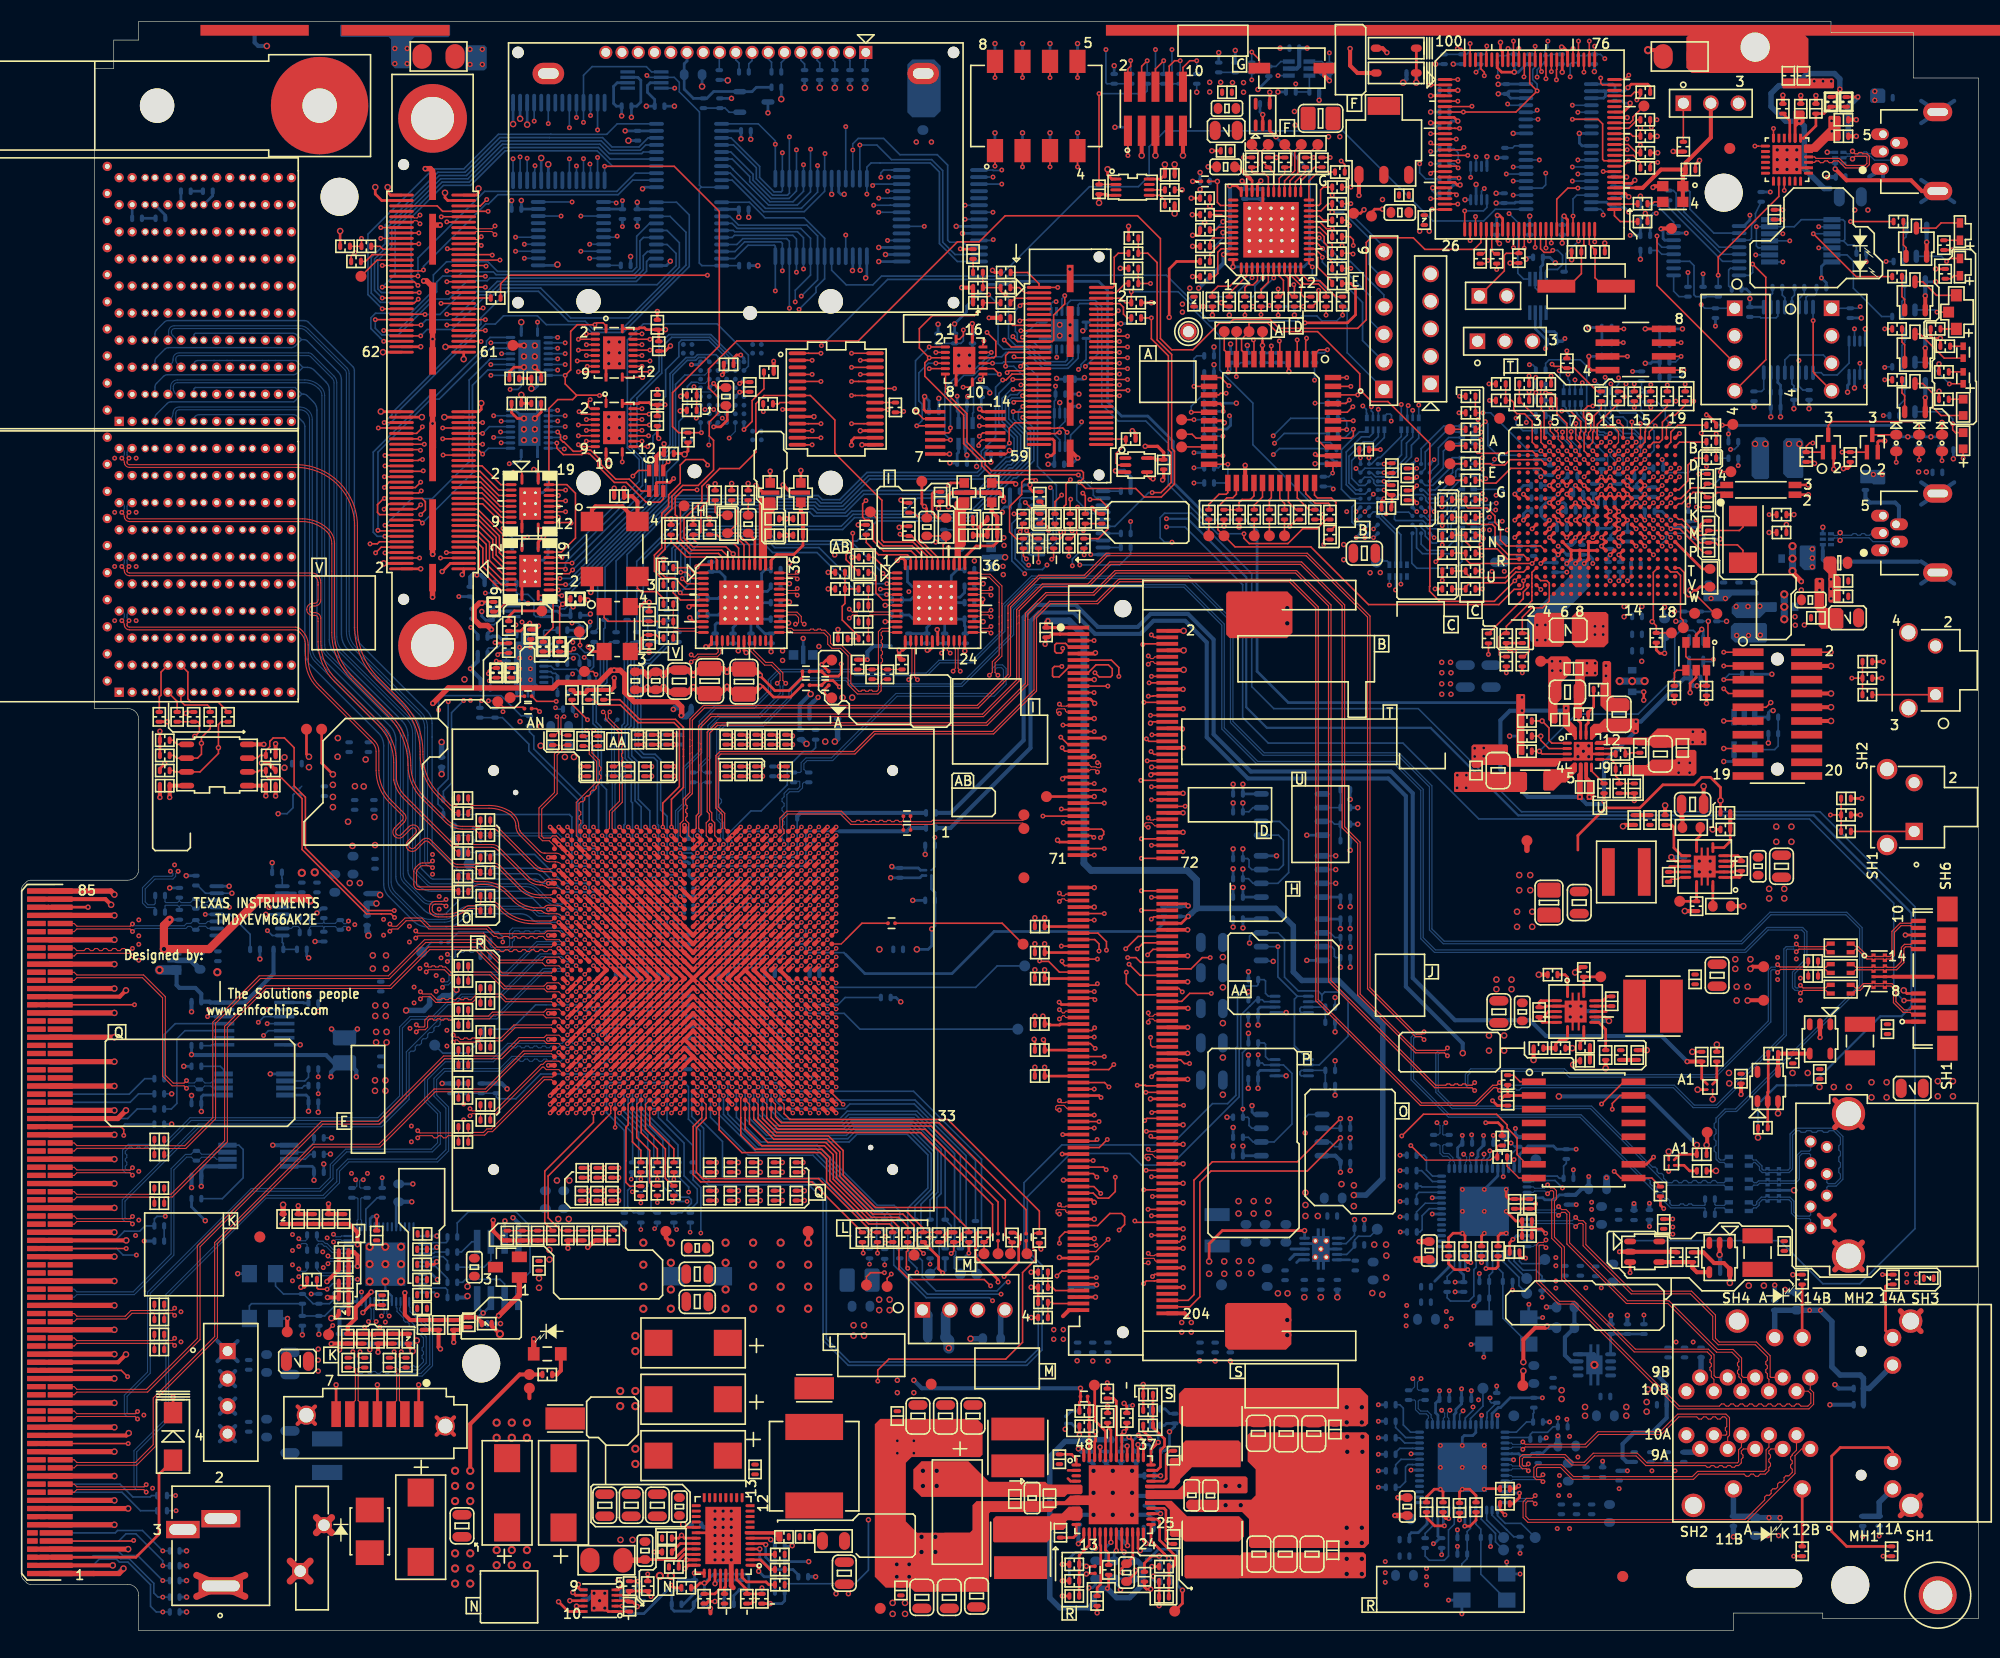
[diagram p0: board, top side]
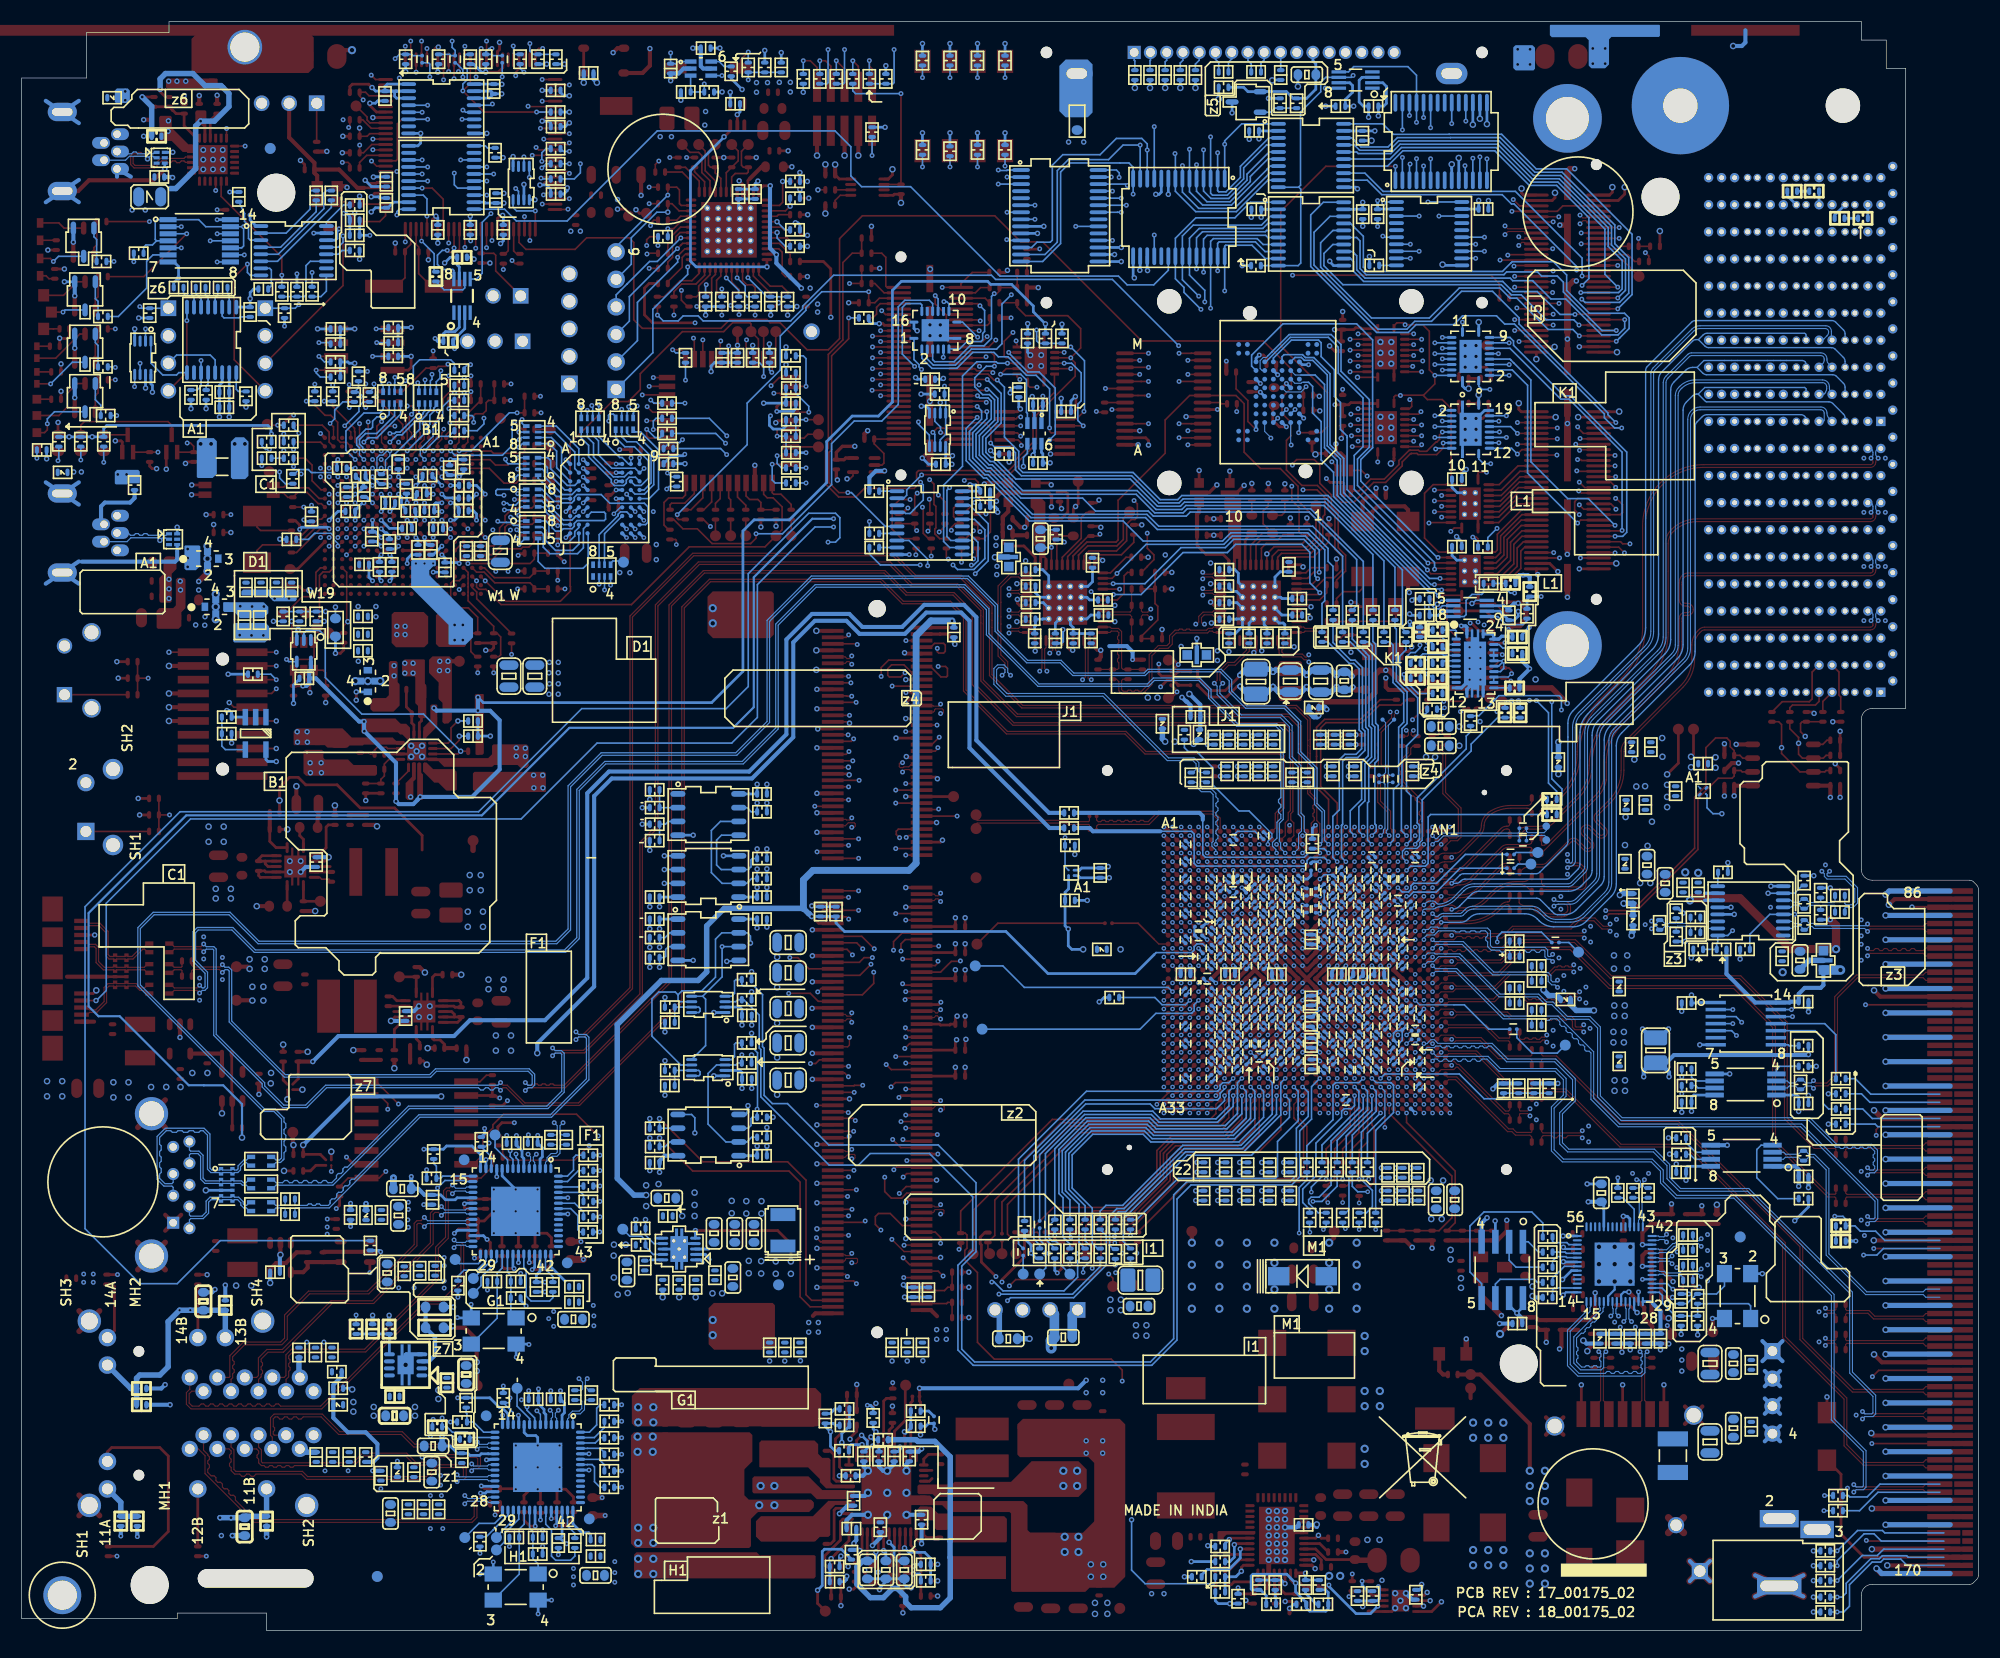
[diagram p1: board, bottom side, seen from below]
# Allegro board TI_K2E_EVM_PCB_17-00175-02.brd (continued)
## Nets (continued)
CVDD: C62.1 C63.1 C64.1 C65.1 C66.1 C74.2 C75.2 C76.2 C77.1 C78.1 C79.1 C80.1 C81.2 C88.2 C89.1 C90.2 C91.2 C92.2 C93.2 C96.2 C166.2 C167.2 C168.1 C169.1 C170.2 C171.2 C172.2 C173.2 C178.2 C179.2 C180.2 C181.2 C182.2 C183.2 C184.2 C185.2 C206.1 C219.1 C225.1 C257.1 C436.1 C437.1 C438.1 C439.1 C445.2 C446.2 C447.2 C448.1 C449.2 C450.2 C451.2 C452.2 C458.2 C459.1 C460.2 C461.2 C464.2 C465.2 C466.2 C508.1 C509.1 C521.1 C522.1 C525.1 C526.1 C535.1 C543.1 C544.1 C547.1 C549.1 C554.1 C556.1 C558.1 C559.1 C563.2 C566.1 C567.1 C568.1 C569.1 C571.1 C575.1 C578.1 C579.1 C580.1 C581.1 C582.1 C587.1 C588.1 C589.1 C590.1 C591.1 C596.1 C597.1 C603.2 C604.2 C605.2 C606.2 C608.1 C614.1 C615.1 C616.1 C617.1 C618.1 C619.1 C623.1 C624.1 C625.1 C626.1 C627.1 C628.1 C629.1 C632.2 C639.1 C640.1 C641.1 C642.1 C643.1 C644.1 C645.1 C652.1 C653.1 C654.1 C655.1 C656.1 C657.1 C658.1 C660.2 C665.1 C666.1 C667.1 C676.1 C677.1 C679.1 C683.2 C686.1 C687.1 C688.1 C689.1 C690.1 C692.1 C693.1 C694.1 C698.1 C699.1 C700.1 C701.1 C702.1 C738.2 C739.1 C740.1 C741.1 C742.1 C743.2 C744.2 C745.2 C750.2 C751.2 C752.2 C753.2 C754.2 C755.1 C756.2 C757.2 CT1.1(POSITIVE) CT2.1(POSITIVE) CT3.1(POSITIVE) CVDD.1 D15.2(CATHODE) L12.2 R63.2 R477.2 R544.2 TP51.1 U23.AA10(CVDD_85) U23.AA16(CVDD_86) U23.AA18(CVDD_87) U23.AA20(CVDD_88) U23.AA22(CVDD_89) U23.AA26(CVDD_90) U23.AB9(CVDD_91) U23.AB11(CVDD_92) U23.AB13(CVDD_93) U23.AB15(CVDD_94) U23.AB17(CVDD_95) U23.AB19(CVDD_96) U23.AB21(CVDD_97) U23.AB25(CVDD_98) U23.AC10(CVDD_99) U23.AC12(CVDD_100) U23.AC14(CVDD_101) U23.AC16(CVDD_102) U23.AC18(CVDD_103) U23.AC20(CVDD_104) U23.AC22(CVDD_105) U23.AC24(CVDD_106) U23.AC26(CVDD_107) U23.AD11(CVDD_108) U23.AD13(CVDD_109) U23.AD15(CVDD_110) U23.AD17(CVDD_111) U23.AD19(CVDD_112) U23.AD21(CVDD_113) U23.AD25(CVDD_114) U23.J12(CVDD_01) U23.J14(CVDD_02) U23.J16(CVDD_03) U23.J18(CVDD_04) U23.J20(CVDD_05) U23.J22(CVDD_06) U23.J26(CVDD_07) U23.K11(CVDD_08) U23.K13(CVDD_09) U23.K15(CVDD_10) U23.K17(CVDD_11) U23.K19(CVDD_12) U23.K21(CVDD_13) U23.K23(CVDD_14) U23.K25(CVDD_15) U23.L10(CVDD_16) U23.L12(CVDD_17) U23.L14(CVDD_18) U23.L16(CVDD_19) U23.L18(CVDD_20) U23.L20(CVDD_21) U23.L22(CVDD_22) U23.M15(CVDD_23) U23.M17(CVDD_24) U23.M19(CVDD_25) U23.M21(CVDD_26) U23.M25(CVDD_27) U23.N10(CVDD_28) U23.N14(CVDD_29) U23.N16(CVDD_30) U23.N18(CVDD_31) U23.N20(CVDD_32) U23.N22(CVDD_33) U23.N26(CVDD_34) U23.P13(CVDD_35) U23.P15(CVDD_36) U23.P17(CVDD_37) U23.P19(CVDD_38) U23.P21(CVDD_39) U23.P23(CVDD_40) U23.P25(CVDD_41) U23.R14(CVDD_42) U23.R16(CVDD_43) U23.R18(CVDD_44) U23.R20(CVDD_45) U23.R22(CVDD_46) U23.R24(CVDD_47) U23.R26(CVDD_48) U23.T13(CVDD_49) U23.T15(CVDD_50) U23.T17(CVDD_51) U23.T19(CVDD_52) U23.T21(CVDD_53) U23.T23(CVDD_54) U23.T25(CVDD_55) U23.U12(CVDD_56) U23.U14(CVDD_57) U23.U16(CVDD_58) U23.U18(CVDD_59) U23.U20(CVDD_60) U23.U22(CVDD_61) U23.U24(CVDD_62) U23.U26(CVDD_63) U23.V13(CVDD_64) U23.V15(CVDD_65) U23.V17(CVDD_66) U23.V19(CVDD_67) U23.V21(CVDD_68) U23.V23(CVDD_69) U23.V25(CVDD_70) U23.W12(CVDD_71) U23.W14(CVDD_72) U23.W16(CVDD_73) U23.W18(CVDD_74) U23.W20(CVDD_75) U23.W22(CVDD_76) U23.W24(CVDD_77) U23.W26(CVDD_78) U23.Y9(CVDD_79) U23.Y15(CVDD_80) U23.Y17(CVDD_81) U23.Y19(CVDD_82) U23.Y21(CVDD_83) U23.Y25(CVDD_84)
CVDD1: C243.1 C244.1 C246.2 C247.1 C252.1 C534.1 C548.1 C555.1 C570.1 C668.1 C672.1 C675.1 C678.1 C781.1 C793.1 CVDD1.1 L11.2 R25.2 R257.1 U23.AA12(CVDD1_9) U23.AA14(CVDD1_10) U23.AA24(CVDD1_11) U23.AB23(CVDD1_12) U23.AD9(VNWA4) U23.AD23(VNWA3) U23.J24(VNWA2) U23.L24(CVDD1_1) U23.M11(CVDD1_2) U23.M13(CVDD1_3) U23.M23(CVDD1_4) U23.N12(CVDD1_5) U23.N24(CVDD1_6) U23.P9(VNWA1) U23.Y13(CVDD1_7) U23.Y23(CVDD1_8)
CVDD1_EN: R43.2 R604.2 U33.48(ENSW1)
CVDD1_MON: R25.1 U4.40(MON5)
CVDD_EN: R61.2 R277.2 R589.1 R608.2
CVDD_MON: R63.1 U4.1(MON1)
DBG_RTCK: J5.9 R140.2
DBG_SRST: J5.15 R395.1
DBG_TCK: J5.11 R379.2 U15.J15(TCK)
DBG_TDI: J5.3 U15.M16(TDI)
DBG_TDO: J5.7 U15.J18(TDO)
DBG_TMS: J5.1 U15.L16(TMS)
DBG_TRSTN: J5.2 U15.L17(TRSTN)
DDR3_CLKN: C457.1 U17.36(Y7_N)
DDR3_CLKP: C456.1 U17.35(Y7_P)
DDR_DVDD18: FB5.1 U15.N6(DDR_DVDD18.1) U15.N9(DDR_DVDD18.2) U15.N10(DDR_DVDD18.3) U15.P7(DDR_DVDD18.4) U15.P8(DDR_DVDD18.5) U15.P9(DDR_DVDD18.6) U15.P10(DDR_DVDD18.7) U15.R7(DDR_DVDD18.8) U15.R8(DDR_DVDD18.9) U15.R9(DDR_DVDD18.10)
DEBUG_LED_BUFF_OE: R327.2 U39.23(GPA2) U48.1(OE1#) U48.4(OE2#) U48.10(OE3#) U48.13(OE4#)
DIMM_SA0: DIMM1.197(SA0) R247.1 R251.1
DIMM_SA1: DIMM1.201(SA1) R252.1 R253.1
DIMM_SCL: DIMM1.202(SCL) R497.1 U71.7(SCLB)
DIMM_SDA: DIMM1.200(SDA) R493.1 U71.6(SDAB)
DIP_SW_B0: R315.2 SW1.1 U1.86(PH0)
DIP_SW_B1: R314.2 SW1.2 U1.85(PH1)
DIP_SW_B2: R316.2 SW1.3 U1.84(PH2)
DIP_SW_B3: R313.2 SW1.4 U1.83(PH3)
DSP_PMBUS_EN: R471.2 R628.1 U1.47(PF0)
DSP_SCL_AMC: AMC1.160(RX20+) R574.1
DSP_SDA_AMC: AMC1.159(RX20-) R573.1
DSP_VCL_R: R470.2 U23.V29(VCL) U67.3(SCL1)
DSP_VD_R: R468.2 U23.U30(VD) U67.4(SDA1)
EEPROM_WPZ: EEPROM1.7(W\C\) R423.2 U39.2(GPB1)
EMA_A0: RN1.3(R3A) U15.C14(EMA_A[0]/GP5[0])
EMA_A1: RN1.1(R1A) U15.D15(EMA_A[1]/GP5[1])
EMA_A2: RN1.4(R4A) U15.B14(EMA_A[2]/GP5[2])
EMA_A3: RN1.2(R2A) U15.D14(EMA_A[3]/GP5[3])
EMA_A4: RN3.4(R4A) U15.A14(EMA_A[4]/GP5[4])
EMA_A5: RN3.2(R2A) U15.C13(EMA_A[5]/GP5[5])
EMA_A6: RN3.3(R3A) U15.E13(EMA_A[6]/GP5[6])
EMA_A7: RN3.1(R1A) U15.B13(EMA_A[7]/GP5[7])
EMA_A8: RN4.3(R3A) U15.A13(EMA_A[8]/GP5[8])
EMA_A9: RN4.4(R4A) U15.D12(EMA_A[9]/GP5[9])
EMA_A10: RN4.1(R1A) U15.C12(EMA_A[10]/GPIO5[10])
EMA_A11: RN4.2(R2A) U15.B12(EMA_A[11]/GP5[11])
EMA_A12: RN9.4(R4A) U15.D13(EMA_A[12]/GP5[12])
EMA_BA0: RN9.3(R3A) U15.C15(EMA_BA[0]/GP2[8])
EMA_BA1: RN9.2(R2A) U15.A15(EMA_BA[1]/GP2[9])
EMA_D0: RN5.5(R4B) U15.C9(EMA_D[0]/GP4[8])
EMA_D1: RN5.6(R3B) U15.A8(EMA_D[1]/GP4[9])
EMA_D2: RN5.7(R2B) U15.B8(EMA_D[2]/GP4[10])
EMA_D3: RN5.8(R1B) U15.E8(EMA_D[3]/GP4[11])
EMA_D4: RN6.8(R1B) U15.B5(EMA_D[4]/GP4[12])
EMA_D5: RN6.7(R2B) U15.E7(EMA_D[5]/GP4[13])
EMA_D6: RN6.6(R3B) U15.C6(EMA_D[6]/GP4[14])
EMA_D7: RN6.5(R4B) U15.D7(EMA_D[7]/GP4[15])
EMA_D8: RN7.8(R1B) U15.E10(EMA_D[8]/GP3[0])
EMA_D9: RN7.7(R2B) U15.D9(EMA_D[9]/GP3[1])
EMA_D10: RN7.6(R3B) U15.A7(EMA_D[10]/GP3[2])
EMA_D11: RN7.5(R4B) U15.D6(EMA_D[11]/GP3[3])
EMA_D12: RN8.8(R1B) U15.A6(EMA_D[12]/GP3[4])
EMA_D13: RN8.6(R3B) U15.B6(EMA_D[13]/GP3[5])
EMA_D14: RN8.7(R2B) U15.C7(EMA_D[14]/GP3[6])
EMA_D15: RN8.5(R4B) U15.E6(EMA_D[15]/GP3[7])
EMIF_BUFF_OE: U6.1(1OE#) U6.19(2OE#) U10.1(1OE#) U10.19(2OE#) U13.4(Y) U14.19(O\E\) U16.19(O\E\) U51.1(1OE#) U51.19(2OE#)
EMU_DET: EMU1.58 R100.1 U12.2(A)
EMU_ENABLE: U7.15(E#) U12.4(Y) U49.15(E#)
EMU_RTCK: EMU1.7(PTH_11) R387.1 U49.7(YB)
EMU_TCK: R46.1 R52.1 R53.1 U49.4(YA) U57.11(2A1) U57.13(2A2)
EMU_TCK_R: EMU1.3(PTH_7) R52.2
EMU_TDI: R65.1 R66.1 U7.4(YA) U57.2(1A1)
EMU_TDI_R: EMU1.5(PTH_9) R65.2
EMU_TDO: R44.1 R51.1 U7.12(YD) U57.12(1Y4)
EMU_TDO_R: EMU1.4 R51.2
EMU_TMS: R31.1 R37.1 U7.7(YB) U57.4(1A2)
EMU_TMS_R: EMU1.2 R37.2
EMU_TRST#: R67.2 R341.1 U7.9(YC) U57.6(1A3)
EMU_TRST#_R: EMU1.8 R67.1
EMU_TVD: J5.5 R409.1
EMULED1: Q8.1(G) R85.2 R104.1
EMULED2: Q7.1(G) R84.2 R103.1
EXP_GPIO_00: CN7.54 U46.20(B1)
EXP_GPIO_01: CN7.56 U46.18(B2)
EXP_GPIO_02: CN7.66 U46.17(B3)
EXP_GPIO_03: CN7.68 U46.16(B4)
EXP_GPIO_04: CN7.70 U46.15(B5)
EXP_GPIO_05: CN7.72 U46.14(B6)
EXP_GPIO_06: CN7.74 U46.13(B7)
EXP_GPIO_07: CN7.76 U46.12(B8)
EXP_GPIO_08: CN7.78 U40.20(B1)
EXP_GPIO_09: CN7.80 U40.18(B2)
EXP_GPIO_10: CN7.82 U40.17(B3)
EXP_GPIO_11: CN7.84 U40.16(B4)
EXP_GPIO_12: CN7.86 U40.15(B5)
EXP_GPIO_13: CN7.88 U40.14(B6)
EXP_GPIO_14: CN7.90 U40.13(B7)
EXP_GPIO_15: CN7.92 U40.12(B8)
EXP_GPIO_16: CN7.94 U37.8(B1)
EXP_GPIO_EN: R330.2 U1.97(PD4) U37.6(OE) U40.10(OE) U46.10(OE)
EXP_SCL2_3V3: CN7.7 R186.2 R201.1 R574.2 U21.7(SCLB)
EXP_SDA2_3V3: CN7.5 R187.2 R198.1 R573.2 U21.6(SDAB)
EXP_TP0: CN7.96 TP9.1
EXP_TP1: CN7.98 R42.1
EXP_TP2: CN7.100 R34.1
EXP_XFI_MDC_2V5: J2.D9(XFIMDCLK) R639.2 R653.1
EXP_XFI_MDIO_2V5: J2.C9(XFIMDIO) R412.2 R624.1
EXT_PS#: R34.2 R35.1 U8.23(GPA2)
FAN_PWM: C798.1 FAN1.4 R50.2
GP4-0: R83.2 U15.E12(EMA_A[16]/MMCSD0_DAT[5]/GP4[0])
GP4-1: RN2.2(R2A) U15.B11(EMA_A[17]/MMCSD0_DAT[4]/GP4[1])
GP4-2: RN2.3(R3A) U15.E11(EMA_A[18]/MMCSD0_DAT[3]/GP4[2])
GP4-3: RN2.4(R4A) U15.C10(EMA_A[19]/MMCSD0_DAT[2]/GP4[3])
GP4-4: RN2.1(R1A) U15.A11(EMA_A[20]/MMCSD0_DAT[1]/GP4[4])
HYPER0_LINK_CLKN: U17.15(Y0_N) U23.AJ8(HYPLNK0CLKN)
HYPER0_LINK_CLKP: U17.14(Y0_P) U23.AJ7(HYPLNK0CLKP)
HYPERLINK0_RXFLCLK: J4.C3(RXFLCLK1) R416.2
HYPERLINK0_RXFLCLK_R: R416.1 U23.AJ3(HYPLNK0RXFLCLK)
HYPERLINK0_RXFLDAT: J4.D3(RXFLDAT1) U23.AE3(HYPLNK0RXFLDAT)
HYPERLINK0_RXN0: C111.2 J4.B4(RX0_1-)
HYPERLINK0_RXN0_C: C111.1 U23.AN8(HYPLNK0RXN0)
HYPERLINK0_RXN1: C109.2 J4.B6(RX1_1-)
HYPERLINK0_RXN1_C: C109.1 U23.AM7(HYPLNK0RXN1)
HYPERLINK0_RXN2: C107.2 J4.B8(RX2_1-)
HYPERLINK0_RXN2_C: C107.1 U23.AN5(HYPLNK0RXN2)
HYPERLINK0_RXN3: C101.2 J4.B10(RX3_1-)
HYPERLINK0_RXN3_C: C101.1 U23.AM4(HYPLNK0RXN3)
HYPERLINK0_RXP0: C115.2 J4.A4(RX0_1+)
HYPERLINK0_RXP0_C: C115.1 U23.AN9(HYPLNK0RXP0)
HYPERLINK0_RXP1: C110.2 J4.A6(RX1_1+)
HYPERLINK0_RXP1_C: C110.1 U23.AM8(HYPLNK0RXP1)
HYPERLINK0_RXP2: C108.2 J4.A8(RX2_1+)
HYPERLINK0_RXP2_C: C108.1 U23.AN6(HYPLNK0RXP2)
HYPERLINK0_RXP3: C104.2 J4.A10(RX3_1+)
HYPERLINK0_RXP3_C: C104.1 U23.AM5(HYPLNK0RXP3)
HYPERLINK0_RXPMCLK: J4.C5(RXPMCLK1) U23.AE1(HYPLNK0RXPMCLK)
HYPERLINK0_RXPMDAT: J4.D5(RXPMDAT1) U23.AD1(HYPLNK0RXPMDAT)
HYPERLINK0_TXFLCLK: J4.C4(TXFLCLK1) U23.AC6(HYPLNK0TXFLCLK)
HYPERLINK0_TXFLDAT: J4.D4(TXFLDAT1) U23.AH4(HYPLNK0TXFLDAT)
HYPERLINK0_TXN0: J4.B3(TX0_1-) U23.AL9(HYPLNK0TXN0)
HYPERLINK0_TXN1: J4.B5(TX1_1-) U23.AK8(HYPLNK0TXN1)
HYPERLINK0_TXN2: J4.B7(TX2_1-) U23.AL6(HYPLNK0TXN2)
HYPERLINK0_TXN3: J4.B9(TX3_1-) U23.AK5(HYPLNK0TXN3)
HYPERLINK0_TXP0: J4.A3(TX0_1+) U23.AL8(HYPLNK0TXP0)
HYPERLINK0_TXP1: J4.A5(TX1_1+) U23.AK7(HYPLNK0TXP1)
HYPERLINK0_TXP2: J4.A7(TX2_1+) U23.AL5(HYPLNK0TXP2)
HYPERLINK0_TXP3: J4.A9(TX3_1+) U23.AK4(HYPLNK0TXP3)
HYPERLINK0_TXPMCLK: J4.C6(TXPMCLK1) R414.2
HYPERLINK0_TXPMCLK_R: R414.1 U23.AB6(HYPLNK0TXPMCLK)
HYPERLINK0_TXPMDAT: J4.D6(TXPMDAT1) U23.AF5(HYPLNK0TXPMDAT)
IDAC_OUT: R603.1 U35.2(IDAC_OUT)
JTAG_SELECT: R343.1 R344.2 U7.1(S) U49.1(S)
JTAG_TCK: TP5.1 U4.27(TCK/GPIO18)
JTAG_TDI: R13.2 TP2.1 U4.29(TDI/GPIO20)
JTAG_TDO: TP6.1 U4.28(TDO/GPIO19)
JTAG_TMS: R14.2 TP3.1 U4.30(TMS/GPIO21)
LCD_A0: LCD1.15(A0) R16.2
LCD_RSTZ: LCD1.16(RST) U1.100(PD7)
LM10011_EN: R276.1 R588.2 U1.24(PC5) U35.4(EN)
LM10011_MODE: R611.1 R612.2 U35.5(MODE)
LM10011_VID1A: R536.1 U23.H31(VCNTL2) U35.7(VIDA)
LM10011_VID1B: R528.1 U23.H30(VCNTL3) U35.8(VIDB)
LM10011_VID1C: R244.1 U23.G32(VCNTL4) U35.9(VIDC)
LM10011_VID1S: R537.1 U23.J31(VCNTL5) U35.10(VIDS)
MAIN_POWER_GOOD: R17.2 U1.11(PD1)
MAIN_POWER_START: R23.1 U1.10(PD0)
MAIN_POWER_START_R: CN5.5 R23.2 U4.22(PWM1/GPI1)
MCU_BOOTSELECT: CN4.1 R38.1 U1.36(PG7)
MCU_EXP_SCL: R459.2 U1.34(PA6) U64.7(SCLB) U66.2(SCLA)
MCU_EXP_SDA: R466.2 U1.35(PA7) U64.6(SDAB) U66.3(SDAA)
MCU_JTAG_TCK: R20.2 U1.80(PC0/TCK/SWCLK)
MCU_JTAG_TDI: R301.1 U1.78(PC2/TDI)
MCU_JTAG_TDO: R302.1 U1.77(PC3/TDO/SWO)
MCU_JTAG_TMS: R304.1 R305.1 U1.79(PC1/TMS/SWDIO)
MCU_PA0_U0RX: U1.26(PA0/U0RX) U42.5(Y)
MCU_PA1_U0TX: R331.1 U1.27(PA1/U0TX) U2.20(RXD_SCI)
MCU_RESET_SWZ: C299.1 C300.1 R297.2 R298.1 U36.1(A)
MCU_RESETSTATZ: R42.2 U8.22(GPA1)
MCU_RESETZ: U1.64(R\S\T\) U36.4(Y)
MCU_SPI0_CLK: U1.28(PA2/SSI0CLK) U8.12(SCK) U17.5(SCL/PIN4) U18.5(SCL/PIN4) U41.16(B4)
MCU_SPI0_CLK_1V8: U39.12(SCK) U41.5(A4) U43.12(SCK) U44.12(SCK)
MCU_SPI0_CS0Z: U1.29(PA3/SSI0FSS) U18.4(SCS/AD1/PIN3)
MCU_SPI0_CS1Z: U1.25(PC4) U17.4(SCS/AD1/PIN3)
MCU_SPI0_CS3Z: U1.23(PC6) U38.4(1A1)
MCU_SPI0_CS3Z_1V8: U38.13(1B1) U44.11(C\S\)
MCU_SPI0_CS4Z: U1.22(PC7) U38.5(1A2)
MCU_SPI0_CS4Z_1V8: U38.12(1B2) U39.11(C\S\)
MCU_SPI0_CS5Z: U1.60(PF2) U38.6(2A1)
MCU_SPI0_CS5Z_1V8: U38.11(2B1) U43.11(C\S\)
MCU_SPI0_CS6Z: U1.59(PF3) U8.11(C\S\)
MCU_SPI0_MISO: R40.1 U8.14(SO) U17.3(SDO/AD0/PIN2) U18.3(SDO/AD0/PIN2) U41.14(B6)
MCU_SPI0_MISO_1V8: U39.14(SO) U41.7(A6) U43.14(SO) U44.14(SO)
MCU_SPI0_MOSI: R39.1 U8.13(SI) U17.2(SDI/SDA/PIN1) U18.2(SDI/SDA/PIN1) U41.15(B5)
MCU_SPI0_MOSI_1V8: U39.13(SI) U41.6(A5) U43.13(SI) U44.13(SI)
MCU_SPI1_CLK: LCD1.14(SCL) U1.74(PE0)
MCU_SPI1_CS0Z: LCD1.17(CS1B) U1.75(PE1)
MCU_SPI1_MOSI: LCD1.13(SDA) R290.1
MCU_SRSTN_R: C313.2 R300.1 R307.2 U36.3(B)
MCU_U0RX: R333.1 U42.1(A)
MCU_U1RX: R7.1 U1.66(PB0)
MCU_U1TX: TP1.1 U1.67(PB1)
MCU_UART0_DETECT: COM2.1 R360.1 U42.6(A\/B)
MCU_UART_RX: R333.2 U47.9(ROUT)
MCU_UART_TX: R331.2 R332.1 U47.11(DIN)
MCU_WAKEZ: CN6.2 U1.50(W\A\K\E\)
MCUOSC0: C17.1 U1.48(OSC0) Y1.1
MCUOSC1: C16.2 U1.49(OSC1) Y1.2
MCUXOSC0: R22.1 U1.52(XOSC0)
MCUXOSC0_R: OSC1.3(OUT) R22.2
MEM_A4: RN3.5(R4B) U78.J3(A4)
MEM_A5: RN3.7(R2B) U78.J2(A5)
MEM_A6: RN3.6(R3B) U78.H3(A6)
MEM_A7: RN3.8(R1B) U78.H2(A7)
MEM_A8: RN4.6(R3B) U78.H1(A8)
MEM_A9: RN4.5(R4B) U78.G3(A9)
MEM_A10: RN4.8(R1B) U78.H9(A10)
MEM_A11: RN4.7(R2B) U78.G2(A11)
MEM_A12: RN9.5(R4B) TP92.1
MEM_BA0: RN9.6(R3B) U78.G7(BA0)
MEM_BA1: RN9.7(R2B) U78.G8(BA1)
MEM_CASN: R481.1 U78.F7(C\A\S\)
MEM_CKE: R476.1 U78.F3(CKE)
MEM_CLK: R283.1 U78.F2(CLK)
MEM_CS0N: R597.1 R598.1 U78.G9(C\S\)
MEM_D2: RN5.2(R2A) U78.B8(DQ2)
MEM_D3: RN5.1(R1A) U78.C9(DQ3)
MEM_D4: RN6.1(R1A) U78.C8(DQ4)
MEM_D5: RN6.2(R2A) U78.D9(DQ5)
MEM_D6: RN6.3(R3A) U78.D8(DQ6)
MEM_D7: RN6.4(R4A) U78.E9(DQ7)
MEM_D8: RN7.1(R1A) U78.E1(DQ8)
MEM_D9: RN7.2(R2A) U78.D2(DQ9)
MEM_D10: RN7.3(R3A) U78.D1(DQ10)
MEM_D11: RN7.4(R4A) U78.C2(DQ11)
MEM_D12: RN8.1(R1A) U78.C1(DQ12)
MEM_D13: RN8.3(R3A) U78.B2(DQ13)
MEM_D14: RN8.2(R2A) U78.B1(DQ14)
MEM_D15: RN8.4(R4A) U78.A2(DQ15)
MEM_RASN: R596.1 U78.F8(R\A\S\)
MEM_WE_DQM0N: R599.1 U78.E8(DQML)
MEM_WE_DQM1N: R600.1 U78.F1(DQMH)
MMC_BLUE_LED: R328.1 U1.15(PH7)
MMC_ENABLE_N: AMC1.41(E\N\A\B\L\E\) R319.1
MMC_GA0: AMC1.5(GA0) R288.2 R289.1 U1.92(PB4)
MMC_GA1: AMC1.17(GA1) R286.2 R287.1 U1.91(PB5)
MMC_GA2: AMC1.26(GA2) R284.2 R285.1 U1.90(PB6)
MMC_GAPU: R285.2 R287.2 R289.2 U1.89(PB7)
MMC_PS_N0: AMC1.83(P\S\0\) D11.2(CATHODE) R10.2 U1.63(PH5)
MMC_PS_N1: AMC1.3(P\S\1\) D11.1(ANODE)
MMC_RED_LED: R27.1 U1.62(PH6)
NAND_WPZ: R99.2 U39.1(GPB0) U53.C3(W\P\)
NETCPCLKN: C73.1 U18.36(Y7_N)
NETCPCLKN_R: C73.2 U23.AN3(NETCPCLKN)
NETCPCLKP: C72.1 U18.35(Y7_P)
NETCPCLKP_R: C72.2 U23.AM2(NETCPCLKP)
NOR_WPZ: NOR1.9(W\/VPP/DQ2) R453.2 U1.18(PG1)
OSCIN: C50.2 U15.L19(OSCIN) Y3.2
OSCOUT: C43.2 U15.K19(OSCOUT) Y3.1
OSCVSS: C43.1 C50.1 U15.L18(OSCVSS)
PCIE0CLKN: C506.1 U17.21(Y2_N)
PCIE0CLKN_M: R450.2 R452.2 R455.2 U23.AJ18(PCIE0CLKN)
PCIE0CLKP: C532.1 U17.20(Y2_P)
PCIE0CLKP_M: R455.1 R457.2 R458.2 U23.AJ17(PCIE0CLKP)
PCIE1_RX1N: C770.2 U23.AN14(PCIE1RXN0)
PCIE1_RX1P: C769.2 U23.AN15(PCIE1RXP0)
PCIE1_RX2N: C782.2 U23.AM13(PCIE1RXN1)
PCIE1_RX2P: C771.2 U23.AM14(PCIE1RXP1)
PCIE1_TX1N: C607.2 U75.41(PRXN0)
PCIE1_TX1N_R: C607.1 U23.AL15(PCIE1TXN0)
PCIE1_TX1P: C599.2 U75.42(PRXP0)
PCIE1_TX1P_R: C599.1 U23.AL14(PCIE1TXP0)
PCIE1_TX2N: C585.2 U75.36(PRXN1)
PCIE1_TX2N_R: C585.1 U23.AK14(PCIE1TXN1)
PCIE1_TX2P: C573.2 U75.37(PRXP1)
PCIE1_TX2P_R: C573.1 U23.AK13(PCIE1TXP1)
PCIE1CLKN: U17.22(Y3_N) U23.AJ15(PCIE1CLKN)
PCIE1CLKP: U17.23(Y3_P) U23.AJ14(PCIE1CLKP)
PCIE_REF_CLK_N: AMC1.81(FCLKA-) R456.2 U65.3(I\N\1\)
PCIE_REF_CLK_P: AMC1.80(FCLKA+) R456.1 U65.2(IN1)
PCIE_SPI_CLK: R548.2 U76.6(SCL)
PCIE_SPI_CS: R535.2 U76.1(CS#)
PCIE_SPI_DI: R543.2 U76.2(SO)
PCIE_SPI_DO: R531.2 U76.5(SI)
PCIECLK_MCU_PD: R318.1 R464.1 U65.4(P\D\)
PCIECLK_MUX_SEL: R462.1 R463.1 U1.76(PH4) U65.16(SEL)
PCIECLK_OE: R312.1 R442.1 U65.7(OE)
PCIECLKN_MR: R452.1 U65.14(C\L\K\)
PCIECLKN_R: C506.2 R444.1 R448.2 U65.6(I\N\2\)
PCIECLKP_MR: R457.1 U65.15(CLK)
PCIECLKP_R: C532.2 R448.1 R451.2 U65.5(IN2)
PHY1_INT#: R94.1 R557.1 U77.12(LED[2]/INTN)
PHY1_LED_0: R264.1 U77.14(LED[0])
PHY1_LED_1: R248.1 R558.2 U77.13(LED[1])
PHY1_MDC_2V5: R636.2 U77.7(MDC)
PHY1_MDI0_N: J9.1A(P1_TD1-) U77.27(MDI[0]_N)
PHY1_MDI0_P: J9.2A(P1_TDP1+) U77.28(MDI[0]_P)
PHY1_MDI1_N: J9.3A(P1_TD2-) U77.23(MDI[1]_N)
PHY1_MDI1_P: J9.4A(P1_TD2+) U77.24(MDI[1]_P)
PHY1_MDI2_N: J9.5A(P1_TD3-) U77.21(MDI[2]_N)
PHY1_MDI2_P: J9.6A(P1_TD3+) U77.22(MDI[2]_P)
PHY1_MDI3_N: J9.7A(P1_TD4-) U77.17(MDI[3]_N)
PHY1_MDI3_P: J9.8A(P1_TD4+) U77.18(MDI[3]_P)
PHY2_INT#: R93.2 R496.1 U73.12(LED[2]/INTN)
PHY2_LED_0: R265.1 R498.2 U73.14(LED[0])
PHY2_LED_1: R249.1 U73.13(LED[1])
PHY2_MDC_2V5: R637.2 U73.7(MDC)
PHY2_MDI0_N: J9.1B(P2_TD1-) U73.27(MDI[0]_N)
PHY2_MDI0_P: J9.2B(P2_TD1+) U73.28(MDI[0]_P)
PHY2_MDI1_N: J9.3B(P2_TD2-) U73.23(MDI[1]_N)
PHY2_MDI1_P: J9.4B(P2_TD2+) U73.24(MDI[1]_P)
PHY2_MDI2_N: J9.5B(P2_TD3-) U73.21(MDI[2]_N)
PHY2_MDI2_P: J9.6B(P2_TD3+) U73.22(MDI[2]_P)
PHY2_MDI3_N: J9.7B(P2_TD4-) U73.17(MDI[3]_N)
PHY2_MDI3_P: J9.8B(P2_TD4+) U73.18(MDI[3]_P)
PHY_MDIO_2V5: AMC1.130(RX15+) J2.A9(MDIO) R407.2 R625.1 U73.8(MDIO) U77.8(MDIO)
PHY_RSTZ: R651.2 U1.1(PE7)
PHY_RSTZ_2V5: R651.1 R652.1 U73.16(RESETN) U77.16(RESETN)
PLL0_VDDA12: C421.1 C422.1 FB18.3 U15.L15(PLL0_VDDA12) U15.N15(PLL1_VDDA12)
PLL_LOCK1: U8.4(GPB3) U18.46(STATUS0)
PLL_LOCK2: U8.5(GPB4) U17.46(STATUS0)
PLLLOCK_LED: R365.1 U39.26(GPA5)
PMBUS_ALERT: PMBUS1.3 R36.1 R258.1 R577.1 U1.40(PG5) U79.8(B1)
PMBUS_CLK: PMBUS1.1 R59.2 R259.1 R335.2 R580.1 U4.8(PMBUS_CLK)
PMBUS_CTL: PMBUS1.4 R30.1 R584.1 U1.41(PG4)
PMBUS_DAT: PMBUS1.2 R58.2 R255.1 R334.2 R583.1 U4.9(PMBUS_DATA)
POWER_RESETZ: C60.1 CN6.1 R179.1 R181.2 U1.87(PJ1)
PW_SEQ_I2C_EN: U1.5(PE5) U66.5(EN)
PW_SEQ_RSTZ: C345.1 R324.1 R338.2 U1.2(PE6) U4.3(R\E\S\E\T\)
PW_SEQ_SCL: R59.1 U66.7(SCLB) U67.6(SCL2) U69.6(SCL2)
PW_SEQ_SDA: R58.1 U66.6(SDAB) U67.5(SDA2) U69.5(SDA2)
REFCLK1_PD#: R137.1 U8.1(GPB0) U18.43(PDN)
REFCLK2_PD#: R139.1 U8.2(GPB1) U17.43(PDN)
RS232_RX: COM2.4 U47.8(RIN)
RS232_TX: COM2.3 U47.13(DOUT)
RSV_CLKN: CN7.110 U17.28(Y5_N)
RSV_CLKP: CN7.112 U17.29(Y5_P)
RTC_XI: C37.2 U15.J19(RTC_XI) Y2.1
RTC_XO: C32.2 U15.H19(RTC_XO) Y2.4
RTCK/GP8[0]: R140.1 U15.K17(RTCK/GP8[0])
RTM_MDC_2V5: J2.B9(MDCLK) R623.1 R635.2
RXN_1: C241.2 U75.16(RXN_1)
RXP_1: C242.2 U75.15(RXP_1)
SATA_CLKN: R511.1 U17.25(Y4_N)
SATA_CLKP: R512.1 U17.26(Y4_P)
SATA_GND: FB12.2 J10.M1(SH[0]) J10.M2(SH[1])
SGMIICLKN: C681.1 U18.28(Y5_N)
SGMIICLKP: C673.1 U18.29(Y5_P)
SMB_SCL_IPMBL: AMC1.56(SCL_L) R5.1 U1.72(PB2/I2C0SCL)
SMB_SDA_IPMBL: AMC1.71(SDA_L) R8.1 U1.65(PB3/I2C0SDA)
SOC_BOOTCOMPLETE: U23.AF31(BOOTCOMPLETE) U43.27(GPA6)
SOC_DDR3A_EA0: DIMM1.107(A0) U23.D15(DDRA00)
SOC_DDR3A_EA1: DIMM1.105(A1) U23.C15(DDRA01)
SOC_DDR3A_EA2: DIMM1.106(A2) U23.B16(DDRA02)
SOC_DDR3A_EA3: DIMM1.103(A3) U23.C16(DDRA03)
SOC_DDR3A_EA4: DIMM1.104(A4) U23.D16(DDRA04)
SOC_DDR3A_EA5: DIMM1.99(A5) U23.E16(DDRA05)
SOC_DDR3A_EA6: DIMM1.100(A6) U23.A17(DDRA06)
SOC_DDR3A_EA7: DIMM1.98(A7) U23.E17(DDRA07)
SOC_DDR3A_EA8: DIMM1.97(A8) U23.A18(DDRA08)
SOC_DDR3A_EA9: DIMM1.92(A9) U23.B17(DDRA09)
SOC_DDR3A_EA10: DIMM1.117(A10/AP) U23.A13(DDRA10)
SOC_DDR3A_EA11: DIMM1.96(A11) U23.D18(DDRA11)
SOC_DDR3A_EA12: DIMM1.95(A12/B\C\) U23.E18(DDRA12)
SOC_DDR3A_EA13: DIMM1.130(A13) U23.E12(DDRA13)
SOC_DDR3A_EA14: DIMM1.90(A14) U23.C18(DDRA14)
SOC_DDR3A_EA15: DIMM1.88(A15) U23.E19(DDRA15)
SOC_DDR3A_EBA_0: DIMM1.119(BA0) U23.D13(DDRBA0)
SOC_DDR3A_EBA_1: DIMM1.108(BA1) U23.C13(DDRBA1)
SOC_DDR3A_EBA_2: DIMM1.91(BA2) U23.B18(DDRBA2)
SOC_DDR3A_ECAS#: DIMM1.125(C\A\S\) U23.B12(DDRCASZ)
SOC_DDR3A_ECC0: DIMM1.81(CB2) U23.A23(DDRCB00)
SOC_DDR3A_ECC1: DIMM1.72(CB4) U23.D22(DDRCB01)
SOC_DDR3A_ECC2: DIMM1.71(CB1) U23.E22(DDRCB02)
SOC_DDR3A_ECC3: DIMM1.69(CB0) U23.E21(DDRCB03)
SOC_DDR3A_ECC4: DIMM1.74(CB5) U23.C22(DDRCB04)
SOC_DDR3A_ECC5: DIMM1.82(CB7) U23.B21(DDRCB05)
SOC_DDR3A_ECC6: DIMM1.80(CB6) U23.A20(DDRCB06)
SOC_DDR3A_ECC7: DIMM1.83(CB3) U23.A21(DDRCB07)
SOC_DDR3A_ECKE_0: DIMM1.87(CKE0) U23.C20(DDRCKE0)
SOC_DDR3A_ECKE_1: DIMM1.89(CKE1) U23.A19(DDRCKE1)
SOC_DDR3A_ECKN_0: DIMM1.113(C\K\0\) U23.B14(DDRCLKOUTN0)
SOC_DDR3A_ECKN_1: DIMM1.114(C\K\1\) U23.A15(DDRCLKOUTN1)
SOC_DDR3A_ECKP_0: DIMM1.111(CK0) U23.B15(DDRCLKOUTP0)
SOC_DDR3A_ECKP_1: DIMM1.112(CK1) U23.A16(DDRCLKOUTP1)
SOC_DDR3A_ECS_0#: DIMM1.127(C\S\0\) U23.A12(DDRCE0Z)
SOC_DDR3A_ECS_1#: DIMM1.129(C\S\1\) U23.C12(DDRCE1Z)
SOC_DDR3A_EDM_0: DIMM1.11(DM0) U23.A3(DDRDQM0)
SOC_DDR3A_EDM_1: DIMM1.28(DM1) U23.E3(DDRDQM1)
SOC_DDR3A_EDM_2: DIMM1.44(DM2) U23.D8(DDRDQM2)
SOC_DDR3A_EDM_3: DIMM1.59(DM3) U23.E8(DDRDQM3)
SOC_DDR3A_EDM_4: DIMM1.140(DM4) U23.E26(DDRDQM4)
SOC_DDR3A_EDM_5: DIMM1.157(DM5) U23.D26(DDRDQM5)
SOC_DDR3A_EDM_6: DIMM1.172(DM6) U23.E31(DDRDQM6)
SOC_DDR3A_EDM_7: DIMM1.189(DM7) U23.A31(DDRDQM7)
SOC_DDR3A_EDM_8: DIMM1.76(DM8) U23.B20(DDRDQM8)
SOC_DDR3A_EDQ0: DIMM1.7(DQ1) U23.E2(DDRD00)
SOC_DDR3A_EDQ1: DIMM1.15(DQ3) U23.D1(DDRD01)
SOC_DDR3A_EDQ2: DIMM1.6(DQ5) U23.F2(DDRD02)
SOC_DDR3A_EDQ3: DIMM1.16(DQ6) U23.E1(DDRD03)
SOC_DDR3A_EDQ4: DIMM1.5(DQ0) U23.F1(DDRD04)
SOC_DDR3A_EDQ5: DIMM1.13(DQ2) U23.D2(DDRD05)
SOC_DDR3A_EDQ6: DIMM1.4(DQ4) U23.F3(DDRD06)
SOC_DDR3A_EDQ7: DIMM1.18(DQ7) U23.B2(DDRD07)
SOC_DDR3A_EDQ8: DIMM1.31(DQ10) U23.A5(DDRD08)
SOC_DDR3A_EDQ9: DIMM1.34(DQ14) U23.A6(DDRD09)
SOC_DDR3A_EDQ10: DIMM1.33(DQ11) U23.B5(DDRD10)
SOC_DDR3A_EDQ11: DIMM1.36(DQ15) U23.E5(DDRD11)
SOC_DDR3A_EDQ12: DIMM1.22(DQ12) U23.C4(DDRD12)
SOC_DDR3A_EDQ13: DIMM1.21(DQ9) U23.D4(DDRD13)
SOC_DDR3A_EDQ14: DIMM1.19(DQ8) U23.E4(DDRD14)
SOC_DDR3A_EDQ15: DIMM1.24(DQ13) U23.B3(DDRD15)
SOC_DDR3A_EDQ16: DIMM1.39(DQ17) U23.D6(DDRD16)
SOC_DDR3A_EDQ17: DIMM1.37(DQ16) U23.E6(DDRD17)
SOC_DDR3A_EDQ18: DIMM1.50(DQ23) U23.E7(DDRD18)
SOC_DDR3A_EDQ19: DIMM1.40(DQ20) U23.B6(DDRD19)
SOC_DDR3A_EDQ20: DIMM1.42(DQ21) U23.C6(DDRD20)
SOC_DDR3A_EDQ21: DIMM1.48(DQ22) U23.C8(DDRD21)
SOC_DDR3A_EDQ22: DIMM1.49(DQ18) U23.A8(DDRD22)
SOC_DDR3A_EDQ23: DIMM1.51(DQ19) U23.B8(DDRD23)
SOC_DDR3A_EDQ24: DIMM1.68(DQ31) U23.E10(DDRD24)
SOC_DDR3A_EDQ25: DIMM1.65(DQ27) U23.B11(DDRD25)
SOC_DDR3A_EDQ26: DIMM1.63(DQ26) U23.A11(DDRD26)
SOC_DDR3A_EDQ27: DIMM1.66(DQ30) U23.C10(DDRD27)
SOC_DDR3A_EDQ28: DIMM1.57(DQ25) U23.D10(DDRD28)
SOC_DDR3A_EDQ29: DIMM1.56(DQ29) U23.B9(DDRD29)
SOC_DDR3A_EDQ30: DIMM1.55(DQ24) U23.E9(DDRD30)
SOC_DDR3A_EDQ31: DIMM1.54(DQ28) U23.A9(DDRD31)
SOC_DDR3A_EDQ32: DIMM1.142(DQ38) U23.B23(DDRD32)
SOC_DDR3A_EDQ33: DIMM1.133(DQ32) U23.E23(DDRD33)
SOC_DDR3A_EDQ34: DIMM1.135(DQ33) U23.D24(DDRD34)
SOC_DDR3A_EDQ35: DIMM1.136(DQ37) U23.C24(DDRD35)
SOC_DDR3A_EDQ36: DIMM1.134(DQ36) U23.E24(DDRD36)
SOC_DDR3A_EDQ37: DIMM1.147(DQ35) U23.E25(DDRD37)
SOC_DDR3A_EDQ38: DIMM1.144(DQ39) U23.B25(DDRD38)
SOC_DDR3A_EDQ39: DIMM1.145(DQ34) U23.A25(DDRD39)
SOC_DDR3A_EDQ40: DIMM1.160(DQ46) U23.E28(DDRD40)
SOC_DDR3A_EDQ41: DIMM1.161(DQ43) U23.D28(DDRD41)
SOC_DDR3A_EDQ42: DIMM1.159(DQ42) U23.C28(DDRD42)
SOC_DDR3A_EDQ43: DIMM1.148(DQ44) U23.E27(DDRD43)
SOC_DDR3A_EDQ44: DIMM1.162(DQ47) U23.B28(DDRD44)
SOC_DDR3A_EDQ45: DIMM1.153(DQ41) U23.A26(DDRD45)
SOC_DDR3A_EDQ46: DIMM1.151(DQ40) U23.B26(DDRD46)
SOC_DDR3A_EDQ47: DIMM1.150(DQ45) U23.C26(DDRD47)
SOC_DDR3A_EDQ48: DIMM1.165(DQ48) U23.A29(DDRD48)
SOC_DDR3A_EDQ49: DIMM1.167(DQ49) U23.A28(DDRD49)
SOC_DDR3A_EDQ50: DIMM1.177(DQ50) U23.B31(DDRD50)
SOC_DDR3A_EDQ51: DIMM1.179(DQ51) U23.E29(DDRD51)
SOC_DDR3A_EDQ52: DIMM1.166(DQ52) U23.B29(DDRD52)
SOC_DDR3A_EDQ53: DIMM1.168(DQ53) U23.C30(DDRD53)
SOC_DDR3A_EDQ54: DIMM1.174(DQ54) U23.E30(DDRD54)
SOC_DDR3A_EDQ55: DIMM1.176(DQ55) U23.D30(DDRD55)
SOC_DDR3A_EDQ56: DIMM1.180(DQ60) U23.F31(DDRD56)
SOC_DDR3A_EDQ57: DIMM1.194(DQ63) U23.F33(DDRD57)
SOC_DDR3A_EDQ58: DIMM1.192(DQ62) U23.F32(DDRD58)
SOC_DDR3A_EDQ59: DIMM1.193(DQ59) U23.E32(DDRD59)
SOC_DDR3A_EDQ60: DIMM1.191(DQ58) U23.E33(DDRD60)
SOC_DDR3A_EDQ61: DIMM1.185(DQ57) U23.C32(DDRD61)
SOC_DDR3A_EDQ62: DIMM1.182(DQ61) U23.D32(DDRD62)
SOC_DDR3A_EDQ63: DIMM1.183(DQ56) U23.B32(DDRD63)
SOC_DDR3A_EDQSN_0: DIMM1.10(D\Q\S\0\) U23.C2(DDRDQS0N)
SOC_DDR3A_EDQSN_1: DIMM1.25(D\Q\S\1\) U23.B4(DDRDQS1N)
SOC_DDR3A_EDQSN_2: DIMM1.43(D\Q\S\2\) U23.A7(DDRDQS2N)
SOC_DDR3A_EDQSN_3: DIMM1.60(D\Q\S\3\) U23.B10(DDRDQS3N)
SOC_DDR3A_EDQSN_4: DIMM1.139(D\Q\S\4\) U23.B24(DDRDQS4N)
SOC_DDR3A_EDQSN_5: DIMM1.154(D\Q\S\5\) U23.B27(DDRDQS5N)
SOC_DDR3A_EDQSN_6: DIMM1.171(D\Q\S\6\) U23.B30(DDRDQS6N)
SOC_DDR3A_EDQSN_7: DIMM1.186(D\Q\S\7\) U23.D33(DDRDQS7N)
SOC_DDR3A_EDQSN_8: DIMM1.75(D\Q\S\8\) U23.A22(DDRDQS8N)
SOC_DDR3A_EDQSP_0: DIMM1.12(DQS0) U23.C1(DDRDQS0P)
SOC_DDR3A_EDQSP_1: DIMM1.27(DQS1) U23.A4(DDRDQS1P)
SOC_DDR3A_EDQSP_2: DIMM1.45(DQS2) U23.B7(DDRDQS2P)
SOC_DDR3A_EDQSP_3: DIMM1.62(DQS3) U23.A10(DDRDQS3P)
SOC_DDR3A_EDQSP_4: DIMM1.141(DQS4) U23.A24(DDRDQS4P)
SOC_DDR3A_EDQSP_5: DIMM1.156(DQS5) U23.A27(DDRDQS5P)
SOC_DDR3A_EDQSP_6: DIMM1.173(DQS6) U23.A30(DDRDQS6P)
SOC_DDR3A_EDQSP_7: DIMM1.188(DQS7) U23.C33(DDRDQS7P)
SOC_DDR3A_EDQSP_8: DIMM1.77(DQS8) U23.B22(DDRDQS8P)
SOC_DDR3A_EMRESETN: DIMM1.30(R\E\S\E\T\) R469.1 U23.D20(DDRRESETZ)
SOC_DDR3A_EODT_0: DIMM1.126(ODT0) U23.D12(DDRODT0)
SOC_DDR3A_EODT_1: DIMM1.128(ODT1) U23.E11(DDRODT1)
SOC_DDR3A_ERAS#: DIMM1.122(R\A\S\) U23.B13(DDRRASZ)
SOC_DDR3A_EWE#: DIMM1.121(W\E\) U23.E13(DDRWEZ)
SOC_DEBUG_LED1: R48.1 U48.3(1Y)
SOC_DEBUG_LED2: R340.1 U48.6(2Y)
SOC_DEBUG_LED3: R70.1 U48.8(3Y)
SOC_DEBUG_LED4: R353.1 U48.11(4Y)
SOC_EMIFA00: U23.P3(EMIFA00) U51.2(1A1)
SOC_EMIFA01: U23.P5(EMIFA01) U51.4(1A2)
SOC_EMIFA02: U23.U6(EMIFA02) U51.6(1A3)
SOC_EMIFA03: U23.V6(EMIFA03) U51.8(1A4)
SOC_EMIFA04: U23.P6(EMIFA04) U51.11(2A1)
SOC_EMIFA05: U23.N6(EMIFA05) U51.13(2A2)
SOC_EMIFA06: U23.M3(EMIFA06) U51.15(2A3)
SOC_EMIFA07: U23.N4(EMIFA07) U51.17(2A4)
SOC_EMIFA08: U6.2(1A1) U23.N5(EMIFA08)
SOC_EMIFA09: U6.4(1A2) U23.M5(EMIFA09)
SOC_EMIFA10: U6.6(1A3) U23.M4(EMIFA10)
SOC_EMIFA11: U6.8(1A4) U23.L1(EMIFA11) U53.C4(ALE)
SOC_EMIFA12: U6.11(2A1) U23.U5(EMIFA12) U53.D5(CLE)
SOC_EMIFA13: U6.13(2A2) U23.T5(EMIFA13)
SOC_EMIFA14: U6.15(2A3) U23.L3(EMIFA14)
SOC_EMIFA15: U6.17(2A4) U23.T3(EMIFA15)
SOC_EMIFA16: U10.2(1A1) U23.L2(EMIFA16)
SOC_EMIFA17: U10.4(1A2) U23.L5(EMIFA17)
SOC_EMIFA18: U10.6(1A3) U23.M6(EMIFA18)
SOC_EMIFA19: U10.8(1A4) U23.K2(EMIFA19)
SOC_EMIFA20: U10.11(2A1) U23.K1(EMIFA20)
SOC_EMIFA21: U10.13(2A2) U23.L4(EMIFA21)
SOC_EMIFA22: U10.15(2A3) U23.R3(EMIFA22)
SOC_EMIFA23: U10.17(2A4) U23.L6(EMIFA23)
SOC_EMIFBE0Z: U23.AA2(EMIFBE0Z) U54.2(1A1)
SOC_EMIFBE1Z: U23.R6(EMIFBE1Z) U54.4(1A2)
SOC_EMIFCE0Z: U23.AA1(EMIFCE0Z) U53.C6(C\E\)
SOC_EMIFCE1Z: R184.1 U13.1(A) U23.Y4(EMIFCE1Z) U54.6(1A3)
SOC_EMIFCE2Z: R182.1 U13.3(B) U23.W1(EMIFCE2Z) U54.8(1A4)
SOC_EMIFCE3Z: R183.1 U13.6(C) U23.Y1(EMIFCE3Z) U54.11(2A1)
SOC_EMIFD0: U16.11(B8) U23.G5(EMIFD00) U53.H4(I/O0)
SOC_EMIFD1: U16.12(B7) U23.K3(EMIFD01) U53.J4(I/O1)
SOC_EMIFD2: U16.13(B6) U23.K4(EMIFD02) U53.K4(I/O2)
SOC_EMIFD3: U16.14(B5) U23.J1(EMIFD03) U53.K5(I/O3)
SOC_EMIFD4: U16.15(B4) U23.H5(EMIFD04) U53.K6(I/O4)
SOC_EMIFD5: U16.16(B3) U23.J6(EMIFD05) U53.J7(I/O5)
SOC_EMIFD6: U16.17(B2) U23.H6(EMIFD06) U53.K7(I/O6)
SOC_EMIFD7: U16.18(B1) U23.H1(EMIFD07) U53.J8(I/O7)
SOC_EMIFD8: U14.11(B8) U23.H2(EMIFD08)
SOC_EMIFD9: U14.12(B7) U23.G6(EMIFD09)
SOC_EMIFD10: U14.13(B6) U23.K5(EMIFD10)
SOC_EMIFD11: U14.14(B5) U23.H3(EMIFD11)
SOC_EMIFD12: U14.15(B4) U23.J4(EMIFD12)
SOC_EMIFD13: U14.16(B3) U23.H4(EMIFD13)
SOC_EMIFD14: U14.17(B2) U23.K6(EMIFD14)
SOC_EMIFD15: U14.18(B1) U23.J5(EMIFD15)
SOC_EMIFOEZ: U23.Y2(EMIFOEZ) U53.D4(R\E\) U54.15(2A3)
SOC_EMIFRNW: R388.2 U23.Y3(EMIFRNW) U54.13(2A2)
SOC_EMIFRNW_R: R388.1 U14.1(DIR) U16.1(DIR)
SOC_EMIFWAIT0: R74.1 U23.T6(EMIFWAIT0) U53.C8(R\/B\)
SOC_EMIFWAIT1: CN7.69 R418.1 U23.N3(EMIFWAIT1)
SOC_EMIFWEZ: U23.R5(EMIFWEZ) U53.C7(W\E\) U54.17(2A4)
SOC_EMU_00: R109.1 R131.1 U23.AC5(EMU00)
SOC_EMU_00_R: EMU1.19(PTH_23) R131.2 U49.9(YC)
SOC_EMU_01: R127.1 R128.2 U23.AA6(EMU01)
SOC_EMU_01_R: EMU1.21(PTH_25) R128.1 U49.12(YD)
SOC_EMU_02: R145.1 U23.AC4(EMU02)
SOC_EMU_02_R: EMU1.13(PTH_17) R145.2
SOC_EMU_03: R132.2 U23.AE6(EMU03)
SOC_EMU_03_R: EMU1.17(PTH_21) R132.1
SOC_EMU_04: R146.2 U23.AD6(EMU04)
SOC_EMU_04_R: EMU1.23(PTH_27) R146.1
SOC_EMU_05: R401.1 U23.AD3(EMU05)
SOC_EMU_05_R: EMU1.25(PTH_29) R401.2
SOC_EMU_06: R143.1 U23.AB5(EMU06)
SOC_EMU_06_R: EMU1.27(PTH_31) R143.2
SOC_EMU_07: R130.1 U23.AC3(EMU07)
SOC_EMU_07_R: EMU1.29(PTH_33) R130.2
SOC_EMU_08: R129.1 U23.AB4(EMU08)
SOC_EMU_08_R: EMU1.31(PTH_35) R129.2
SOC_EMU_09: R403.1 U23.AH3(EMU09)
SOC_EMU_09_R: EMU1.33(PTH_37) R403.2
SOC_EMU_10: R402.1 U23.AF3(EMU10)
SOC_EMU_10_R: EMU1.35(PTH_39) R402.2
SOC_EMU_11: R147.1 U23.AG4(EMU11)
SOC_EMU_11_R: EMU1.37(PTH_41) R147.2
SOC_EMU_12: R393.1 U23.AD2(EMU12)
SOC_EMU_12_R: EMU1.39(PTH_43) R393.2
SOC_EMU_13: R392.1 U23.AC2(EMU13)
SOC_EMU_13_R: EMU1.41(PTH_45) R392.2
SOC_EMU_14: R144.1 U23.AB3(EMU14)
SOC_EMU_14_R: EMU1.43(PTH_47) R144.2
SOC_EMU_15: R391.1 U23.AA5(EMU15)
SOC_EMU_15_R: EMU1.45(PTH_49) R391.2
SOC_EMU_16: R400.1 U23.AB2(EMU16)
SOC_EMU_16_R: EMU1.47(PTH_51) R400.2
SOC_EMU_17: R399.1 U23.Y5(EMU17)
SOC_EMU_17_R: EMU1.49(PTH_53) R399.2
SOC_EMU_18: R394.1 U23.AH2(EMU18)
SOC_EMU_18_R: EMU1.51(PTH_55) R394.2
SOC_EMU_19: R227.1 U23.AB32(GPIO17/BOOTMODE14/EMU19)
SOC_EMU_19_R: EMU1.53(PTH_57) R227.2 U55.6(1Y)
SOC_EMU_20: R224.1 U23.AB33(GPIO18/BOOTMODE15/EMU20)
SOC_EMU_20_R: EMU1.55(PTH_59) R224.2 U55.3(2Y)
SOC_EMU_21: R516.2 U23.AB31(GPIO19/EMU21)
SOC_EMU_21_R: EMU1.18 R516.1
SOC_EMU_22: R502.1 U23.AC29(GPIO20/EMU22)
SOC_EMU_22_R: EMU1.20 R502.2
SOC_EMU_23: R225.2 U23.AC33(GPIO21/EMU23)
SOC_EMU_23_R: EMU1.22 R225.1
SOC_EMU_24: R520.2 U23.AD29(GPIO22/EMU24)
SOC_EMU_24_R: EMU1.24 R520.1
SOC_EMU_25: R517.1 U23.AC31(GPIO23/EMU25)
SOC_EMU_25_R: EMU1.26 R517.2
SOC_EMU_26: R228.1 U23.AC32(GPIO24/EMU26)
SOC_EMU_26_R: EMU1.28 R228.2
SOC_EMU_27: R503.1 U23.AB30(GPIO25/EMU27)
SOC_EMU_27_R: EMU1.30 R503.2
SOC_EMU_28: R504.1 U23.AC30(GPIO26/EMU28)
SOC_EMU_28_R: EMU1.32 R504.2
SOC_EMU_29: R229.1 U23.AD32(GPIO27/EMU29)
SOC_EMU_29_R: EMU1.34 R229.2
SOC_EMU_30: R226.1 U23.AD33(GPIO28/EMU30)
SOC_EMU_30_R: EMU1.36 R226.2
SOC_EMU_31: R518.1 U23.AD31(GPIO29/EMU31)
SOC_EMU_31_R: EMU1.38 R518.2
SOC_EMU_32: R519.1 U23.AE33(GPIO30/EMU32)
SOC_EMU_32_R: EMU1.40 R519.2
SOC_EMU_33: R505.1 U23.AD30(GPIO31/EMU33)
SOC_EMU_33_R: EMU1.42 R505.2
SOC_GPIO_00: U23.V30(GPIO00/LENDIAN) U44.21(GPA0) U46.1(A1)
SOC_GPIO_01: U23.AA29(GPIO01/BOOTMODE0) U44.22(GPA1) U46.3(A2)
SOC_GPIO_02: U23.Y29(GPIO02/BOOTMODE1) U44.23(GPA2) U46.4(A3)
SOC_GPIO_03: U23.V33(GPIO03/BOOTMODE2) U44.24(GPA3) U46.5(A4)
SOC_GPIO_04: U23.V32(GPIO04/BOOTMODE3) U44.25(GPA4) U46.6(A5)
SOC_GPIO_05: U23.W30(GPIO05/BOOTMODE4) U44.26(GPA5) U46.7(A6)
SOC_GPIO_06: U23.W32(GPIO06/BOOTMODE5) U44.27(GPA6) U46.8(A7)
SOC_GPIO_07: U23.V31(GPIO07/BOOTMODE6) U44.28(GPA7) U46.9(A8)
SOC_GPIO_08: U23.W31(GPIO08/BOOTMODE7) U40.1(A1) U44.1(GPB0)
SOC_GPIO_09: U23.W33(GPIO09/BOOTMODE8) U40.3(A2) U44.2(GPB1)
SOC_GPIO_10: U23.AB29(GPIO10/BOOTMODE9) U40.4(A3) U44.3(GPB2)
SOC_GPIO_11: U23.Y30(GPIO11/BOOTMODE10) U40.5(A4) U44.4(GPB3) U79.5(A1)
SOC_GPIO_12: U23.Y32(GPIO12/BOOTMODE11) U40.6(A5) U44.5(GPB4) U48.2(1A)
SOC_GPIO_13: U23.AA30(GPIO13/BOOTMODE12) U40.7(A6) U44.6(GPB5) U48.5(2A)
SOC_GPIO_14: U23.Y33(GPIO14/MAINPLLODSEL) U40.8(A7) U44.7(GPB6) U48.9(3A)
SOC_GPIO_15: U23.Y31(GPIO15/ARM_BENDIAN) U40.9(A8) U44.8(GPB7) U48.12(4A)
SOC_GPIO_16: U23.AA33(GPIO16/BOOTMODE13) U37.5(A1) U39.25(GPA4)
SOC_HOUT: U23.AF30(HOUT) U43.23(GPA2)
SOC_I2C1_DIMM_EN: U8.25(GPA4) U71.5(EN)
SOC_I2C1_PMBUS_EN: R484.2 U8.24(GPA3)
SOC_I2C_EN: U1.6(PE4) U64.5(EN)
SOC_LRESETNMIENZ: R506.2 U23.AE30(LRESETNMIENZ) U43.26(GPA5)
SOC_LRESETZ: U23.AF33(LRESETZ) U43.25(GPA4)
SOC_NMIZ: U23.AG33(NMIZ) U43.24(GPA3)
SOC_PACLKSEL: U23.AG6(NETCPCLKSEL) U43.22(GPA1)
SOC_PORZ: C200.1 C201.1 C202.2 R231.1 U23.AH33(PORZ) U43.8(GPB7)
SOC_POWER_GOOD: R11.2 U1.13(PD3)
SOC_POWER_START: R19.1 U1.12(PD2)
SOC_POWER_START_R: CN5.6 R19.2 U4.23(PWM2/GPI2)
SOC_RESETFULLZ: C197.1 C198.1 C199.2 R230.1 U23.AF32(RESETFULLZ) U43.6(GPB5)
SOC_RESETSTATZ: R75.1 U23.AH29(RESETSTATZ) U43.28(GPA7)
SOC_RESETZ: C726.1 C727.1 C728.2 R488.1 U23.AE29(RESETZ) U43.7(GPB6)
SOC_RS232_RX: COM1.4 U50.8(RIN)
SOC_RS232_TX: COM1.3 U50.13(DOUT)
SOC_RSV000: R236.1 U23.H32(RSV000)
SOC_RSV001: R237.1 U23.J32(RSV001)
SOC_RSV002: R419.1 U23.AE2(RSV002)
SOC_RSV003: R420.1 U23.AF2(RSV003)
SOC_RSV004: R210.1 U23.G2(RSV004)
SOC_RSV005: R206.1 U23.G1(RSV005)
SOC_RSV006: R430.1 U23.AL3(RSV006)
SOC_RSV007: R427.1 U23.AL2(RSV007)
SOC_RSV008: U23.AG5(RSV008) U39.27(GPA6)
SOC_RSV009: R445.1 U23.K8(RSV009)
SOC_RSV010: TP70.1 U23.J8(RSV010)
SOC_RSV011: R173.1 U23.W8(RSV011)
SOC_RSV012: R174.1 U23.W7(RSV012)
SOC_RSV013: R521.1 U23.J30(RSV013)
SOC_RSV014: R534.1 U23.J29(RSV014)
SOC_RSV015: R433.1 U23.AG8(RSV015)
SOC_RSV016: R473.1 U23.AJ20(RSV016)
SOC_RSV017: R461.1 U23.AG12(RSV017)
SOC_RSV018: TP75.1 U23.AJ28(RSV018)
SOC_RSV019: TP76.1 U23.AJ26(RSV019)
SOC_RSV020: R437.1 U23.AH9(RSV020)
SOC_RSV021: TP72.1 U23.B19(RSV021)
SOC_RSV022: TP73.1 U23.E20(RSV022)
SOC_RSV023: R214.1 U23.A14(RSV023)
SOC_SCL0: EEPROM1.6(SCL) R440.2 U23.AG30(SCL0) U64.2(SCLA)
SOC_SCL1: R480.2 R494.2 U23.AH30(SCL1) U69.3(SCL1) U71.2(SCLA)
SOC_SCL2: R200.2 U21.2(SCLA) U23.AH31(SCL2)
SOC_SCL_RTM: J4.D2(SCL) R186.1
SOC_SDA0: EEPROM1.5(SDA) R435.2 U23.AG28(SDA0) U64.3(SDAA)
SOC_SDA1: R474.2 R491.2 U23.AJ32(SDA1) U69.4(SDA1) U71.3(SDAA)
SOC_SDA2: R197.2 U21.3(SDAA) U23.AG29(SDA2)
SOC_SDA_RTM: J4.D1(SDA) R187.1
SOC_SGMII0_RXN: C161.2 U77.5(SOUT_N)
SOC_SGMII0_RXN_R: C161.1 U23.AN29(SGMII0RXN0)
SOC_SGMII0_RXP: C163.2 U77.4(SOUT_P)
SOC_SGMII0_RXP_R: C163.1 U23.AN30(SGMII0RXP0)
SOC_SGMII0_TXN: C816.1 U23.AL30(SGMII0TXN0)
SOC_SGMII0_TXP: C817.1 U23.AL29(SGMII0TXP0)
SOC_SGMII1_RXN: C159.2 U73.5(SOUT_N)
SOC_SGMII1_RXN_R: C159.1 U23.AM28(SGMII0RXN1)
SOC_SGMII1_RXP: C160.2 U73.4(SOUT_P)
SOC_SGMII1_RXP_R: C160.1 U23.AM29(SGMII0RXP1)
SOC_SGMII1_TXN: C732.1 U23.AK29(SGMII0TXN1)
SOC_SGMII1_TXP: C733.1 U23.AK28(SGMII0TXP1)
SOC_SGMII_MDC: R630.2 R643.2 U80.17(B5) U80.18(B4) U80.19(B3) U80.20(B2) U80.21(B1)
SOC_SGMII_MDIO: R626.1 R631.2 R646.2 U58.5(A1)
SOC_SPI2_CLK: CN7.91 R232.2
SOC_SPI2_CS0: CN7.83 R541.2
SOC_SPI2_CS1: CN7.85 R526.2
SOC_SPI2_CS2: CN7.87 R233.2
SOC_SPI2_CS3: CN7.89 R524.2
SOC_SPI2_DIN: R54.2 U23.P30(SPI2DIN)
SOC_SPI2_DOUT: CN7.79 R542.2
SOC_TCK: R389.1 TP91.1 U23.AJ33(TCK)
SOC_TDI: U23.AG31(TDI) U57.18(1Y1)
SOC_TDO: U23.AF29(TDO) U57.8(1A4)
SOC_TEMP1: Q1.3(VOUT) U4.48(MON10)
SOC_TIMI0: CN7.73 R241.2 R242.1 U23.K33(TIMI0/AVSIFSEL0)
SOC_TIMI1: CN7.77 R239.1 R240.2 U23.K32(TIMI1/AVSIFSEL1)
SOC_TIMO0: CN7.71 R538.1
SOC_TIMO1: CN7.75 R523.1
SOC_TMS: U23.AH32(TMS) U57.16(1Y2)
SOC_TRST#: U23.AG32(TRSTZ) U57.14(1Y3)
SOC_TVD: EMU1.1(PTH_5) EMU1.12 R45.2
SOC_UART0_DETECT: COM1.1 R339.2 U52.6(A\/B)
SOC_UART0_RXD_3V3: U45.20(B1) U52.5(Y)
SOC_UART0_RXD_V1P8: U23.T29(UART0RXD) U45.1(A1)
SOC_UART0_TXD_3V3: R7.2 R358.1 U2.12(RXD_ECI) U45.18(B2) U50.11(DIN)
SOC_UART0_TXD_V1P8: R527.1 U45.3(A2)
SOC_UART1_CTS_3V3: CN7.99 U45.12(B8)
SOC_UART1_CTS_V1P8: U23.T31(UART1CTS) U45.9(A8)
SOC_UART1_RTS_3V3: CN7.97 U45.13(B7)
SOC_UART1_RTS_V1P8: R235.1 U45.8(A7)
SOC_UART1_RX_3V3: CN7.93 U45.15(B5)
SOC_UART1_RXD_V1P8: U23.U29(UART1RXD) U45.6(A5)
SOC_UART1_TX_3V3: CN7.95 U45.14(B6)
SOC_UART1_TXD_V1P8: R234.1 U45.7(A6)
SOC_URX_3V3: U50.9(ROUT) U52.1(A)
SOC_VPPB_EN: R432.2 U39.24(GPA3) U63.B2(ON)
SOC_XFI_MDIO: R627.1 R632.2 R645.2 U58.4(A2)
SOC_XFI_RX_DN0: C119.2 J2.D2(RX0_4-)
SOC_XFI_RX_DN0_R: C119.1 U23.AN11(XFIRXN0)
SOC_XFI_RX_DN1: C116.2 J2.D4(RX1_4-)
SOC_XFI_RX_DN1_R: C116.1 U23.AM10(XFIRXN1)
SOC_XFI_RX_DP0: C123.2 J2.C2(RX0_4+)
SOC_XFI_RX_DP0_R: C123.1 U23.AN12(XFIRXP0)
SOC_XFI_RX_DP1: C118.2 J2.C4(RX1_4+)
SOC_XFI_RX_DP1_R: C118.1 U23.AM11(XFIRXP1)
SOC_XFI_TX_DN0: J2.D1(TX0_4-) U23.AL12(XFITXN0)
SOC_XFI_TX_DN1: J2.D3(TX1_4-) U23.AK11(XFITXN1)
SOC_XFI_TX_DP0: J2.C1(TX0_4+) U23.AL11(XFITXP0)
SOC_XFI_TX_DP1: J2.C3(TX1_4+) U23.AK10(XFITXP1)
SOC_XFIMDC: R629.2 R644.2 U80.15(B7) U80.16(B6)
SPARE0: TP20.1 U9.20(IO21_15)
SPARE1: TP18.1 U9.19(IO21_16)
SPI0_CLK: NOR1.16(SCK) R540.2
SPI0_CS0: NOR1.7(S\) R539.2
SPI0_DIN: R443.2 R447.2 U23.M31(SPI0DIN)
SPI0_DOUT: NOR1.15(DQ0) R525.2
SPI1_CLK: R105.2 R352.1 U5.6(SCLK)
SPI1_SCS[0]: R342.1 U5.1(C\S\) U15.E19(SPI1_SCS[0]/EPWM1B/GP2[14]/TM64)
SPI1_SIMO: R355.1 U5.5(DI) U15.G17(SPI1_SIMO/GP2[10])
SPI1_SOMI: R345.1 U5.2(DO) U15.H17(SPI1_SOMI/GP2[11])
SPI1_WPN: R348.1 U5.3(W\P\) U15.F18(SPI1_SCS[1]/EPWM1A/GP2[15]/TM64)
SPI_GPIO_INT0: U1.58(PF4) U41.20(B1)
SPI_GPIO_INT0_1V8: U41.1(A1) U44.20(INTA)
SPI_GPIO_INT1: U1.46(PF5) U41.18(B2)
SPI_GPIO_INT1_1V8: U39.20(INTA) U41.3(A2)
SPI_GPIO_INT2: U1.43(PF6) U41.17(B3)
SPI_GPIO_INT2_1V8: U41.4(A3) U43.20(INTA)
SPI_GPIO_INT3: U1.42(PF7) U8.20(INTA)
SPI_GPIO_RESET: U1.37(PG6) U8.18(R\E\S\E\T\) U41.13(B7)
SPI_GPIO_RESET_1V8: U39.18(R\E\S\E\T\) U41.8(A7) U43.18(R\E\S\E\T\) U44.18(R\E\S\E\T\)
SPI_HOLDN: R346.1 U5.7(H\O\L\D\)
T_TDIS: R367.2 R370.2 TP15.1
TCLKA_TSIP0CLKA_N: AMC1.75(TCLKA-) R486.2 U70.3(NCLK)
TCLKA_TSIP0CLKA_P: AMC1.74(TCLKA+) R486.1 U70.2(CLK)
TCLKB_25MHZ_N: AMC1.78(TCLKB-) C56.1
TCLKB_25MHZ_P: AMC1.77(TCLKB+) C53.1
TCLKC_FS_N: AMC1.135(TCLKC-) R501.2 U72.3(NCLK)
TCLKC_FS_P: AMC1.136(TCLKC+) R501.1 U72.2(CLK)
TCLKD_N_C: C56.2 R171.1 U17.9(PRI_REFN)
TCLKD_P_C: C53.2 R160.1 U17.8(PRI_REFP)
TDIS: EMU1.15(PTH_19) R68.2
TPS65000_PG#: R195.1 U20.3(PG#) U59.2(A)
TRGRSTZ: EMU1.6 R64.1 R117.2 U1.39(PJ2)
TRIP1: ESD1.1 ESD1.4 R1.1 R3.2 R4.2
TRIP2: ESD1.2 R2.1
TRIP3: ESD1.3 R1.2
TSCOMPOUT_E: CN7.113 CN7.116 U23.AF4(TSCOMPOUT)
TSIP0_CLKA: R487.1 U23.AK31(TSIP0CLKA)
TSIP0_CLKB: R483.1 U23.AK33(TSIP0CLKB)
TSIP0_FSA: R499.1 U23.AJ31(TSIP0FSA)
TSIP0_FSB: R495.1 U23.AK32(TSIP0FSB)
TSIP0_RX0_TX1: R489.2 U68.13(B1)
TSIP0_RX1_TX0: R492.2 U68.12(B2)
TSIP0_TX0_RX1: R485.2 U68.11(B3)
TSIP0_TX1_RX0: R490.2 U68.10(B4)
TSPUSHEVT0_E: CN7.109 U23.AG3(TSPUSHEVT0)
TSPUSHEVT1_E: CN7.111 U23.AL1(TSPUSHEVT1)
TSREFCLKN: C83.1 U17.33(Y6_N)
TSREFCLKN_R: C83.2 U23.AK1(TSREFCLKN)
TSREFCLKP: C84.1 U17.32(Y6_P)
TSREFCLKP_R: C84.2 U23.AK2(TSREFCLKP)
TSRX_CLK0N: CN7.101 U23.AJ2(TSRXCLKOUT0N)
TSRX_CLK0P: CN7.103 U23.AJ1(TSRXCLKOUT0P)
TSRX_CLK1N: CN7.105 U23.AH1(TSRXCLKOUT1N)
TSRX_CLK1P: CN7.107 U23.AG2(TSRXCLKOUT1P)
TSSYNCEVT_E: CN7.115 U23.AE5(TSSYNCEVT)
TXN_1: C240.2 U75.18(TXN_1)
TXP_1: C239.2 U75.19(TXP_1)
UEMU0: R115.1 U9.33(IO21_5)
UEMU1: R116.1 U9.32(IO21_6)
UEXP0: R119.1 U9.29(IO21_9)
UEXP1: R120.1 U9.28(IO21_10)
UEXP2: R121.1 U9.27(IO21_11)
UEXP3: R124.1 U9.23(IO21_12)
URTCK: R383.1 U9.22(IO21_13)
URTM_PS#: R188.1 R189.2 U8.28(GPA7)
URTM_PS#_R: J4.C1(PS#) R189.1
USB0_0V85: C504.1 C505.1 FB23.1 U23.U8(USB0VP) U23.V9(USB0VPTX)
USB0_ID: R431.2 U23.W4(USB0ID0)
USB0_RXN: L7.2 U23.T1(USB0RX0M)
USB0_RXP: L7.1 U23.U1(USB0RX0P)
USB0_TXN: C186.2 U23.U2(USB0TX0M)
USB0_TXP: C189.2 U23.V2(USB0TX0P)
USB0_VDD3V3: C499.1 C524.1 FB25.1 U23.W10(USB0VPH)
USB0_VDDA33: C407.1 C408.1 C409.1 C410.2 FB17.3 U15.N18(USB0_VDDA33)
USB0DN: L8.2 U23.W3(USB0DM)
USB0DP: L8.1 U23.V3(USB0DP)
USB0DRVVBUS: R533.1 U23.AB1(USB0DRVVBUS)
USB0VBUS: C174.1 C205.1 C214.1 J7.1(VBUS) U29.A2(VIN) U32.1(OUT)
USB1_0V85: C498.1 C513.1 FB22.1 U23.R8(USB1VP) U23.T9(USB1VPTX)
USB1_ID: J6.4(ID) R172.2 U23.W6(USB1ID0)
USB1_RXN: L3.2 U23.N1(USB1RX0M)
USB1_RXN_R: J6.9(MICA_SSRX-) L3.3 U24.2(NC2) U24.13(ED2)
USB1_RXP: L3.1 U23.P1(USB1RX0P)
USB1_RXP_R: J6.10(MICA_SSRX+) L3.4 U24.1(NC1) U24.14(ED1)
USB1_TXN: C129.2 U23.R2(USB1TX0M)
USB1_TXN_R: J6.6(MICA_SSTX-) L4.3 U24.4(NC4) U24.11(ED4)
USB1_TXP: C126.2 U23.P2(USB1TX0P)
USB1_TXP_R: J6.7(MICA_SSTX+) L4.4 U24.3(NC3) U24.12(ED3)
USB1_VDD3V3: C512.1 C523.1 FB27.1 U23.R10(USB1VPH)
USB1DN: L5.2 U23.P4(USB1DM)
USB1DN_R: J6.2(D-) L5.3 U24.7(NC6) U24.8(ED6)
USB1DP: L5.1 U23.R4(USB1DP)
USB1DP_R: J6.3(D+) L5.4 U24.6(NC5) U24.9(ED5)
USB1DRVVBUS: R223.1 U23.AC1(USB1DRVVBUS)
USB1VBUS: C142.1 C144.1 C150.1 J6.1(VBUS) U26.1(OUT) U28.A2(VIN)
USB_CLKN: C462.1 U18.21(Y2_N)
USB_CLKN_R: C462.2 U23.T4(USBCLKM)
USB_CLKP: C463.1 U18.20(Y2_P)
USB_CLKP_R: C463.2 U23.U4(USBCLKP)
USB_RXN_R: J7.5(STDA_SSRX-) L7.3 U30.3(NC3) U30.12(ED3)
USB_RXP_R: J7.6(STDA_SSRX+) L7.4 U30.4(NC4) U30.11(ED4)
USB_SHIELD: FB6.1 J6.SH1 J6.SH2 J6.SH3 J6.SH4 J6.SH5 J6.SH6 J7.H1(PTH_1) J7.H2(PTH_2) U24.5(NCG) U24.10(GND) U30.5(NCG) U30.10(GND)
USB_VBUS: C4.1 FB14.2 R613.1 U2.8(VBUS)
USB_VBUS_EN: R57.2 U28.B2(ON) U29.B2(ON)
USB_VBUS_R: C322.1 D13.6(VBUS) FB14.1 J1.1(VBUS)
USB_VIO: C6.1 C7.1 R6.1 R615.1 U2.5(VIO) U2.6(VDD)
USBDN_R: J7.2(D-) L8.3 U30.1(NC1) U30.14(ED1)
USBDP_R: J7.3(D+) L8.4 U30.2(NC2) U30.13(ED2)
USRSTN: R117.1 U9.31(IO21_7)
UTCA_SGMII4_RX_DN: C143.2 J2.B2(RX0_3-)
UTCA_SGMII4_RX_DN_R: C143.1 U23.AN23(SGMII0RXN4)
UTCA_SGMII4_RX_DP: C145.2 J2.A2(RX0_3+)
UTCA_SGMII4_RX_DP_R: C145.1 U23.AN24(SGMII0RXP4)
UTCA_SGMII4_TX_DN: J2.B1(TX0_3-) U23.AL24(SGMII0TXN4)
UTCA_SGMII4_TX_DP: J2.A1(TX0_3+) U23.AL23(SGMII0TXP4)
UTCA_SGMII5_RX_DN: C136.2 J2.B4(RX1_3-)
UTCA_SGMII5_RX_DN_R: C136.1 U23.AM22(SGMII0RXN5)
UTCA_SGMII5_RX_DP: C141.2 J2.A4(RX1_3+)
UTCA_SGMII5_RX_DP_R: C141.1 U23.AM23(SGMII0RXP5)
UTCA_SGMII5_TX_DN: J2.B3(TX1_3-) U23.AK23(SGMII0TXN5)
UTCA_SGMII5_TX_DP: J2.A3(TX1_3+) U23.AK22(SGMII0TXP5)
UTCA_SGMII6_RX_DN: C133.2 J2.B6(RX2_3-)
UTCA_SGMII6_RX_DN_R: C133.1 U23.AN20(SGMII0RXN6)
UTCA_SGMII6_RX_DP: C135.2 J2.A6(RX2_3+)
UTCA_SGMII6_RX_DP_R: C135.1 U23.AN21(SGMII0RXP6)
UTCA_SGMII6_TX_DN: J2.B5(TX2_3-) U23.AL21(SGMII0TXN6)
UTCA_SGMII6_TX_DP: J2.A5(TX2_3+) U23.AL20(SGMII0TXP6)
UTCA_SGMII7_RX_DN: C127.2 J2.B8(RX3_3-)
UTCA_SGMII7_RX_DN_R: C127.1 U23.AM19(SGMII0RXN7)
UTCA_SGMII7_RX_DP: C132.2 J2.A8(RX3_3+)
UTCA_SGMII7_RX_DP_R: C132.1 U23.AM20(SGMII0RXP7)
UTCA_SGMII7_TX_DN: J2.B7(TX3_3-) U23.AK20(SGMII0TXN7)
UTCA_SGMII7_TX_DP: J2.A7(TX3_3+) U23.AK19(SGMII0TXP7)
UTCK: R382.1 U9.34(IO21_4)
UTDI: R366.1 U9.38(IO21_1)
UTDIS: C358.2 R370.1 U9.18(I_2)
UTDO: R380.1 U9.21(IO21_14)
UTMS: R369.1 U9.37(IO21_2)
UTMSK: R118.1 U9.30(IO21_8)
UTRSTN: R376.1 U9.36(IO21_3)
VAA1: C799.1 C800.1 C801.1 C802.2 FB33.2 U75.28(VAA1)
VAA2_0: C234.1 C235.1 C236.1 C237.2 FB11.2 U75.23(VAA2_0)
VAA2_1: C229.1 C230.1 C231.1 C232.2 FB10.2 U75.17(VAA2_1)
VCONT_10: Q9.1(BASE) U75.32(VCONT_10)
VER0: R87.1 R96.2 U15.C4(AXR12/FSR1/GP0[4])
VER1: R78.1 R92.2 U15.B3(AXR13/CLKX1/GP0[5])
VER2: R77.1 R91.2 U15.B4(AXR14/CLKR1/GP0[6])
VER3: R76.1 R90.2 U15.A4(AXR15/EPWM0TZ[0]/ECAP2_APWM2/GP)
VPP1V8: C478.1 C511.1 R49.2 TP45.1 U23.K9(VPP0) U23.M9(VPP1) U63.A1(VOUT)
VPP1V8_MON: R49.1 U4.46(MON9)
XDS200_EMU0: R115.2 U49.10(IC1)
XDS200_EMU1: R116.2 U49.13(ID1)
XDS200_TCK: R382.2 U49.3(IA1)
XDS200_TDI: R366.2 U7.3(IA1)
XDS200_TDO: R380.2 U7.13(ID1)
XDS200_TMS: R118.2 R369.2 U7.6(IB1)
XDS200_TRST#: R376.2 U7.10(IC1)
XDS_1V2: C86.1 C87.1 C100.1 C366.1 C367.1 C369.1 C375.1 C376.1 C378.1 C380.1 C381.1 C382.1 C385.1 C386.1 C390.1 C392.1 C393.1 FB18.1 L1.2 R202.1 U15.E5(RVDD.1) U15.E15(CVDD.1) U15.G7(CVDD.2) U15.G8(CVDD.3) U15.G13(CVDD.4) U15.H6(CVDD.5) U15.H7(CVDD.6) U15.H10(CVDD.7) U15.H11(CVDD.8) U15.H12(CVDD.9) U15.H13(CVDD.10) U15.H14(RVDD.2) U15.J6(CVDD.11) U15.J12(CVDD.12) U15.K6(CVDD.13) U15.K12(CVDD.14) U15.L12(CVDD.15) U15.L14(RTC_CVDD) U15.M8(CVDD.16) U15.M9(CVDD.17) U15.M12(USB_CVDD) U15.N7(RVDD.3) U15.N8(CVDD.18)
XDS_1V8: C82.1 C85.1 C354.1 C364.1 C370.1 C377.1 C379.1 C387.1 C399.1 FB5.2 FB19.1 R122.2 R194.2 R415.1 U9.15(VCC18) U15.F14(DVDD18.1) U15.G6(DVDD18.2) U15.G10(DVDD18.3) U15.G11(DVDD18.4) U15.G12(DVDD18.5) U15.J13(DVDD18.6) U15.K5(DVDD18.7) U15.L6(DVDD18.8) U15.P13(DVDD18.9) U15.R13(DVDD18.10) U20.12(VLDO1) U61.3(C)
XDS_BOOTMODE[0]: R168.1 R175.2 U15.U3(VP_DOUT[8]/LCD_D[8]/UPP_XD[0]/G)
XDS_BOOTMODE[1]: R152.1 R153.2 U15.T1(VP_DOUT[9]/LCD_D[9]/UPP_XD[1]/G)
XDS_BOOTMODE[2]: R158.1 R159.2 U15.T2(VP_DOUT[10]/LCD_D[10]/UPP_XD[2])
XDS_BOOTMODE[3]: R169.1 R176.2 U15.T3(VP_DOUT[11]/LCD_D[11]/UPP_XD[3])
XDS_BOOTMODE[4]: R141.2 R142.2 U15.R1(VP_DOUT[12]/LCD_D[12]/UPP_XD[4])
XDS_BOOTMODE[5]: R125.2 R126.2 U15.R2(VP_DOUT[13]/LCD_D[13]/UPP_XD[5])
XDS_BOOTMODE[6]: R148.2 R149.2 U15.R3(VP_DOUT[14]/LCD_D[14]/UPP_XD[6])
XDS_BOOTMODE[7]: R110.2 R111.2 U15.P4(VP_DOUT[15]/LCD_D[15]/UPP_XD[7])
XDS_RTCK: R383.2 U49.6(IB1)
XDS_SYS_RESETN: R396.1 U19.1(RESET#)
XDS_USB_DM: D14.2(D-) J3.2(D-) U15.M18(USB0_DM)
XDS_USB_DP: D14.1(D+) J3.3(D+) U15.M19(USB0_DP)
XDS_USB_GND: D14.4(GND) FB16.2 J3.6(PTH1) J3.7(PTH2)
XDS_USB_VBUS: C52.1 C55.1 C67.1 C70.1 C71.2 C99.1 C435.1 FB4.2 R156.2 R191.2 R192.2 R195.2 R203.2 R343.2 U19.6(VDD) U20.6(VINDCDC) U20.13(VINLDO1) U20.16(VINLDO2) U59.5(VCC)
XDS_VBUS: C51.1 D14.6(VBUS) FB4.1 J3.1(VBUS) R162.1 RV1.2
XDS_VCC3V3: C61.1 C69.1 C347.1 C349.1 C350.1 C359.1 C362.1 C363.1 C365.1 C372.1 C373.1 C383.1 C384.1 C388.1 C394.1 C395.1 C396.1 C400.1 C402.1 C860.1 C861.1 C862.1 C863.1 C864.1 C865.1 C866.1 FB17.1 R72.1 R90.1 R91.1 R92.1 R96.1 R97.1 R101.1 R110.1 R114.2 R123.2 R125.1 R141.1 R148.1 R152.2 R158.2 R166.2 R168.2 R169.2 R185.2 R342.2 R345.2 R346.2 R350.2 R352.2 R354.2 R355.2 R362.2 R363.1 R367.1 R371.2 R372.2 R373.2 R374.2 R375.2 R397.1 R398.2 R409.2 R598.2 TP10.1 U5.8(VCC) U9.7(VCCIO1) U9.35(VCCAUX) U15.E14(DVDD3318_B.1) U15.F5(DVDD3318_A.1) U15.F6(DVDD3318_B.2) U15.F7(DVDD3318_B.3) U15.F8(DVDD3318_B.4) U15.F10(DVDD3318_B.5) U15.F11(DVDD3318_B.6) U15.F12(DVDD3318_B.7) U15.F13(DVDD3318_B.8) U15.F15(DVDD3318_A.4) U15.G5(DVDD3318_A.2) U15.G9(DVDD3318_B.9) U15.G14(DVDD3318_A.5) U15.G15(DVDD3318_A.6) U15.H5(DVDD3318_A.3) U15.J5(DVDD3318_C.1) U15.J14(DVDD3318_B.10) U15.K13(DVDD3318_C.2) U15.K15(DVDD3318_B.11) U15.L4(DVDD3318_C.3) U15.L13(DVDD3318_C.4) U15.M13(DVDD3318_C.5) U15.N13(DVDD3318_C.6) U15.P5(DVDD3318_C.7) U15.P6(DVDD3318_C.8) U15.P12(DVDD3318_C.9) U15.R4(DVDD3318_C.10) U19.5(SENSE) U20.15(VLDO2) U78.A7(VDDQ1) U78.A9(VDD1) U78.B3(VDDQ2) U78.C7(VDDQ3) U78.D3(VDDQ4) U78.E7(VDD2) U78.J9(VDD3)
XFICLKN: U18.15(Y0_N) U23.AJ12(XFICLKN)
XFICLKP: U18.14(Y0_P) U23.AJ11(XFICLKP)
N854872: R631.1 R632.1 U23.AH5(MDIO0)
N854876: R629.1 R630.1 U23.AH6(MDCLK0)
N859795: R645.1 R646.1 U23.AE7(XFIMDIO)
N859809: R643.1 R644.1 U23.AF6(XFIMDCLK)
N12934666: CN3.1 R311.2
N13012268: R290.2 U1.96(PE3)
N13662493: CN3.2 R304.2
N13662497: CN3.4 R303.2
N13662501: CN3.6 R302.2
N13662505: CN3.8 R301.2
N13662509: CN3.10 R300.2
N14462583: R479.1 U23.AJ27(SGMII00REFRES)
N14463052: R460.1 U23.AG14(PCIE0REFRES)
N14463586: R434.2 U23.AJ5(HYPLNK0REFRES)
N14466276: R441.2 U23.AH7(XFIREFRES1)
N14466300: R446.2 U23.AG10(XFIREFRES0)
N14466840: R438.2 U23.Y6(USB0RESREF)
N14469420: R454.1 U23.G12(DDRRZQ1)
N14469428: R467.1 U23.G18(DDRRZQ2)
N14469440: R465.1 U23.E15(DDRRZQ0)
N14711749: C8.1 C9.1 FB1.1 U4.34(V33A)
N14714084: R60.1 U4.6(GPIO3)
N14714150: R61.1 U4.4(GPIO1)
N14714160: R337.1 U4.5(GPIO2)
N14715464: R36.2 U4.19(PMBUS_ALERT)
N14715500: R30.2 R324.2 U4.20(PMBUS_CNTRL)
N14716011: R15.2 TP4.1 U4.31(T\R\S\T\)
N14719575: R325.2 U4.43(PMBUS_ADDR1)
N14725158: R336.1 U4.7(GPIO4)
N14733790: R26.1 U4.21(GPIO14)
N14872798: C34.2 R133.2
N14873463: C36.2 R134.2
N14877032: R178.2 R602.1 U17.11(SEC_REFP)
N15165762: R12.1 U4.26(GPIO17)
N15571799: CN1.1 R9.1
N15783945: R56.1 U4.11(FPWM2/GPIO6)
N16053779: R319.2 U1.19(PG0)
N16114816: R50.1 U4.14(FPWM5/GPIO9)
N16281952: R297.1 RST_BMC1.2
N16316172: R318.2 U1.17(PG2)
N16319325: R16.1 U1.61(PF1)
N16321972: R317.1 U41.10(OE)
N16474415: D5.1(ANODE) R89.1
N16474431: D5.2(CATHODE) Q6.3(C)
N16572263: R312.2 U1.16(PG3)
N16795853: R11.1 U4.25(GPIO16)
N16795860: R17.1 U4.24(GPIO15)
N16800870: Q6.1(B) R75.2
N16809812: CN7.81 R54.1
N16865403: Q14.1(B) R365.2
N16865412: D6.1(ANODE) R377.1
N16865430: D6.2(CATHODE) Q14.3(C)
N16865801: Q11.1(B) R328.2
N16865808: D3.2(ANODE) R32.1
N16865818: D3.1(CATHODE) Q3.3(C)
N16865822: D4.2(ANODE) R47.1
N16865834: D4.1(CATHODE) Q11.3(C)
N16865898: Q3.1(B) R27.2
N16869469: C42.1 R108.2
N16870184: C45.1 R112.2
N16947500: C18.1 R46.2
N16951277: R472.1 U23.AJ22(SGMII01REFRES)
N16953830: R449.1 U23.AJ10(PCIE1REFRES)
N16953906: C782.1 U75.33(PTXN1)
N16953908: C769.1 U75.39(PTXP0)
N16953910: C770.1 U75.38(PTXN0)
N16953912: C771.1 U75.34(PTXP1)
N16954088: TP58.1 U75.27(TP)
N16997326: C816.2 U77.2(SIN_N)
N16997342: C817.2 U77.1(SIN_P)
N17001107: R576.1 U77.30(RSET)
N17001211: TP88.1 U77.29(TSTPT)
N17001218: TP89.1 U77.31(HSDAC_N)
N17001225: TP90.1 U77.32(HSDAC_P)
N17007218: J4.C2(MP) R190.1
N17199371: J9.12A(P1_GREEN) R264.2
N17199383: J9.14A(P1_ORANGE) R248.2
N17200454: R568.1 U77.53(TX_CLK)
N17200461: R559.1 U77.56(TX_CTRL)
N17200465: R562.1 U77.55(TXD[3])
N17200469: R564.1 U77.54(TXD[2])
N17200473: R571.1 U77.51(TXD[1])
N17200477: R572.1 U77.50(TXD[0])
N17204930: C831.1 C832.1 C833.1 J9.9A(P1_VCC) R570.1
N17205278: TP87.1 U77.9(CLK125)
N17206950: C844.2 U77.33(XTAL_OUT) Y8.3
N17206970: C845.2 R579.1 U77.34(XTAL_IN) Y8.1
N17261802: R33.1 U4.44(PMBUS_ADDR0)
N17416492: R552.1 U75.13(TESTMODE)
N17426925: R250.1 U75.31(ISET)
N17447628: C791.2 R554.1 U75.30(XTLOUT) Y6.3
N17447634: C795.2 R554.2 R555.1 U75.29(XTALIN_OSC) Y6.1
N17448646: R510.2 U75.45(PERST_N)
N17467804: C848.1 U77.41(REGCAP2)
N17467824: C848.2 U77.37(REGCAP1)
N17469110: R548.1 U75.8(SPI_CLK)
N17469117: R543.1 U75.6(SPI_DI)
N17469130: R531.1 U75.3(SPI_DO)
N17469143: R535.1 U75.5(SPI_CS)
N17470441: NOR1.1(H\O\L\D/DQ3) R428.2
N17470469: NOR1.8(DQ1) R447.1
N17470666: R525.1 U23.N29(SPI0DOUT)
N17470672: R540.1 U23.M30(SPI0CLK)
N17494072: R539.1 U23.L31(SPI0SCS0)
N17494427: R235.2 U23.T33(UART1RTS)
N17494476: R234.2 U23.T32(UART1TXD)
N17495593: R538.2 U23.K31(TIMO0)
N17495612: R523.2 U23.K30(TIMO1)
N17501624: R193.1 U21.5(EN)
N17511358: C342.1 U50.6(C2-)
N17511366: C343.1 U50.2(C1+)
N17511368: R361.2 U50.16(FORCEOFF#)
N17511372: C343.2 U50.4(C1-)
N17511396: C346.1 U50.3(V+)
N17511408: C341.2 U50.7(V-)
N17511414: R359.2 U50.12(FORCEON)
N17511418: C342.2 U50.5(C2+)
N17580617: R527.2 U23.T30(UART0TXD)
N17583891: DBG_D1.3(CATHODE2) Q4.3(C)
N17583895: DBG_D2.1(CATHODE) Q5.3(C)
N17583899: DBG_D1.1(ANODE) R69.1
N17583903: DBG_D3.1(CATHODE) Q13.3(C)
N17583929: DBG_D3.2(ANODE) R73.1
N17583981: Q5.1(B) R70.2
N17584002: Q13.1(B) R353.2
N17584047: DBG_D2.2(ANODE) R71.1
N17584060: Q4.1(B) R48.2
N17584073: DBG_D1.2(CATHODE1) Q12.3(C)
N17584084: Q12.1(B) R340.2
N17624377: C673.2 U23.AJ24(SGMII0CLKP)
N17624382: C681.2 U23.AJ25(SGMII0CLKN)
N17624472: C95.2 U23.AG1(CORECLKN)
N17624476: C94.2 U23.AF1(CORECLKP)
N17626857: R177.2 R601.1 U17.12(SEC_REFN)
N17628895: C59.1 R155.1 R160.2 R161.2 R171.2
N17655103: R436.2 U23.V5(USB1RESREF)
N17664197: J7.8(STDA_SSTX-) L9.3 U30.6(NC5) U30.9(ED5)
N17664207: J7.9(STDA_SSTX+) L9.4 U30.7(NC6) U30.8(ED6)
N17665181: C129.1 L4.2
N17667106: R220.2 R222.1 U26.4(EN) U27.4(OUT)
N17684391: AMC1.33(RX2-) C226.1
N17684393: AMC1.32(RX2+) C228.1
N17684395: AMC1.30(TX2-) C233.1
N17684397: AMC1.29(TX2+) C238.1
N17685557: AMC1.112(RX12+) R489.1
N17687628: U23.AM31(TSIP0TR0) U68.2(A1)
N17687639: U23.AL33(TSIP0TR1) U68.3(A2)
N17687855: AMC1.111(RX12-) R485.1
N17705388: C149.1 U25.9(SS/TR)
N17705416: R218.1 R219.1 U25.7(VSENSE)
N17705473: R217.2 U25.8(COMP)
N17705475: C152.1 R217.1
N17705504: C148.1 R221.1
N17705537: R216.2 U25.1(RT/CLK)
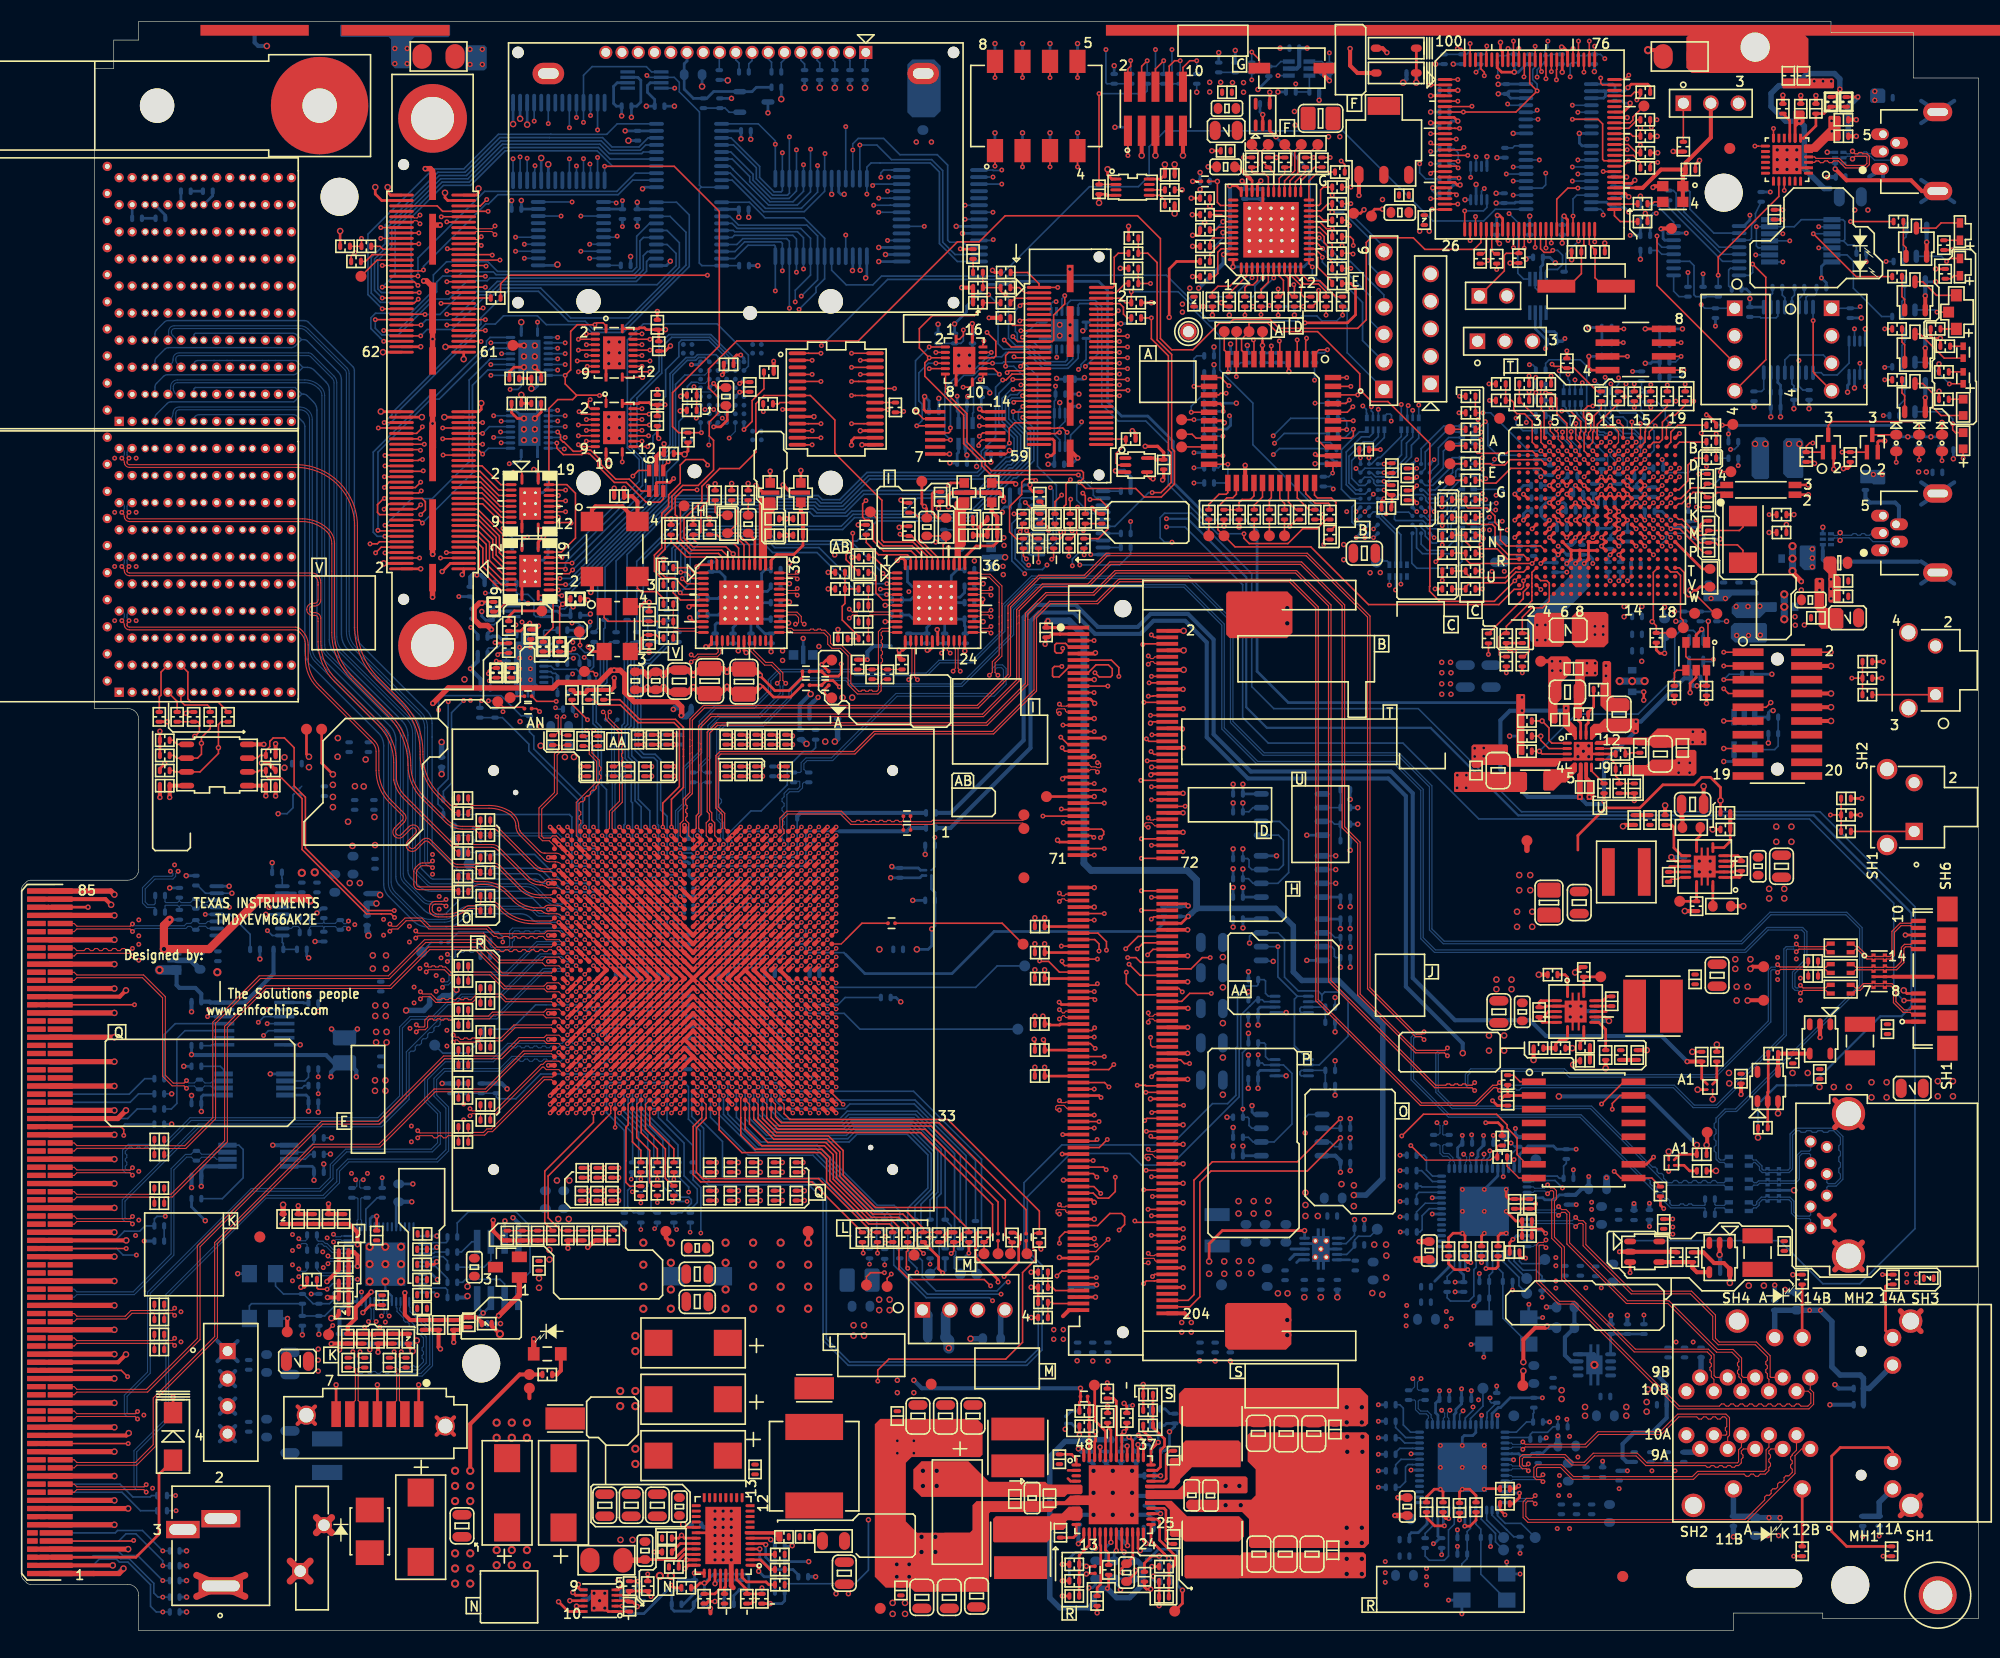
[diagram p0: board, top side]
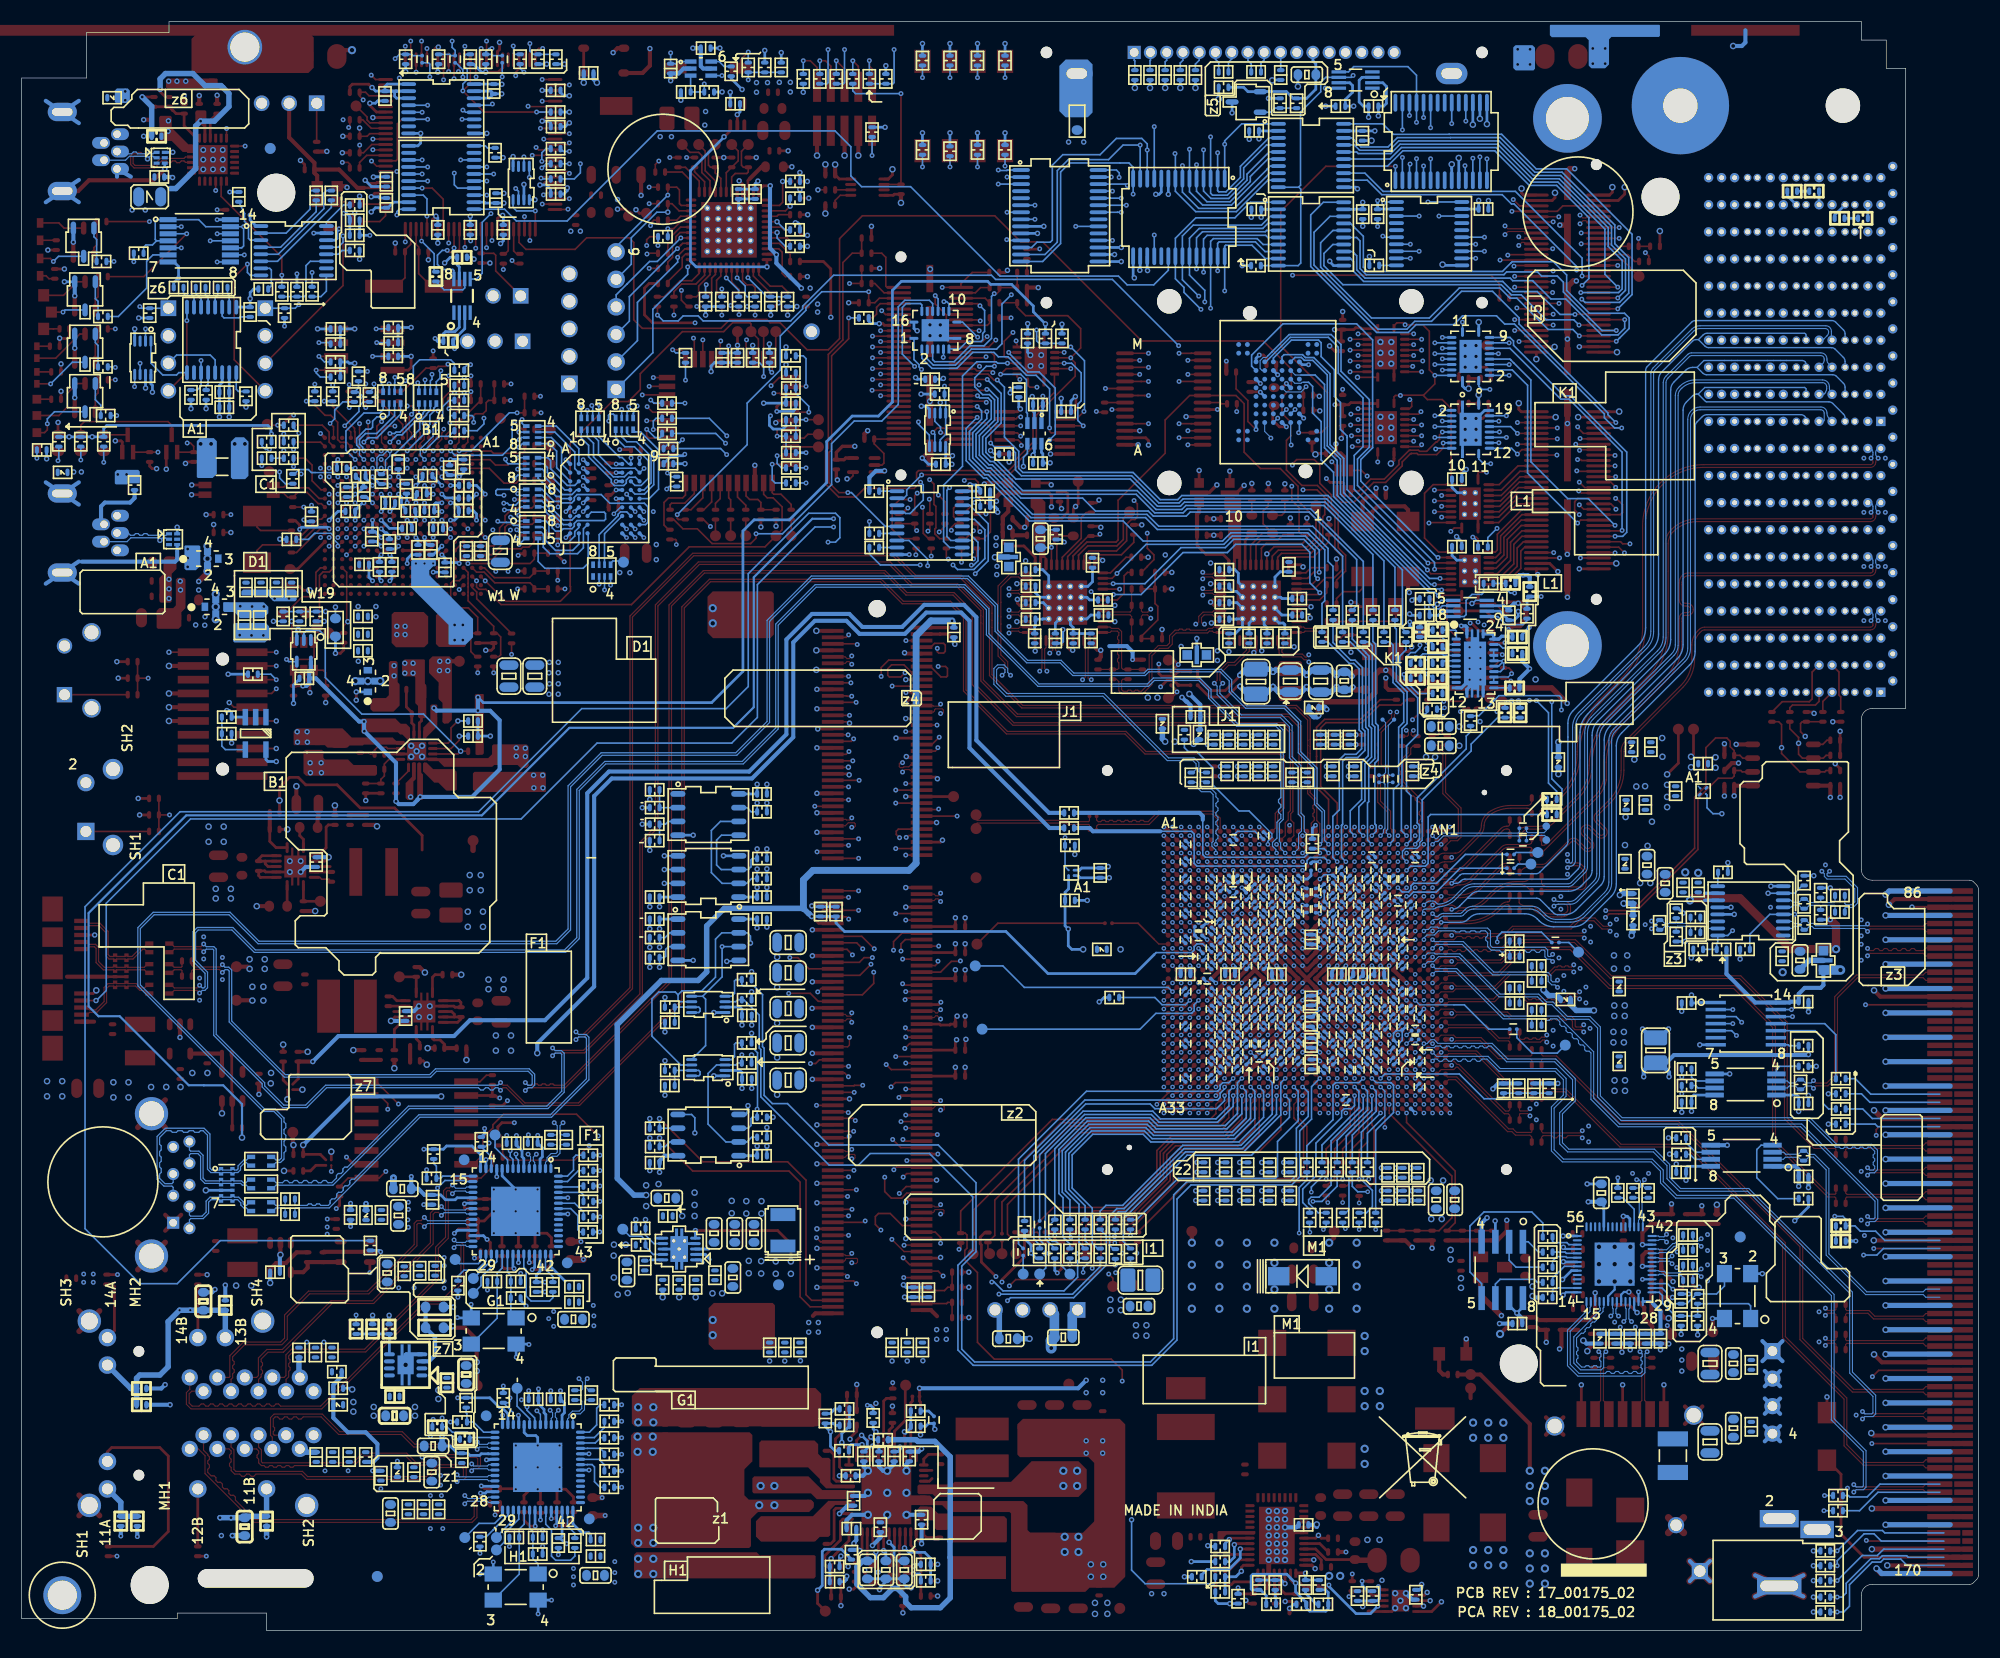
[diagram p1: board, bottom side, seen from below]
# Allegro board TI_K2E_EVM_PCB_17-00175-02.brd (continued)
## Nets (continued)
N17705615: R215.1 TP49.1 U25.14(PWRGD)
N17705627: C134.2 L6.1 R221.2 U25.11(PH1) U25.12(PH2)
N17705639: C134.1 U25.13(BOOT)
N17709052: C105.1 U22.9(SS/TR)
N17709080: R204.2 R209.1 U22.7(VSENSE)
N17709137: R208.1 U22.8(COMP)
N17709139: C103.1 R208.2
N17709168: C106.1 R207.1
N17709201: R212.2 U22.1(RT/CLK)
N17709279: R213.1 TP46.1 U22.14(PWRGD)
N17709291: C117.2 L2.1 R207.2 U22.11(PH1) U22.12(PH2)
N17709303: C117.1 U22.13(BOOT)
N17726206: C13.1 C14.1 FB2.2 Q2.3(VIN)
N17728755: C785.1 R549.2 R550.2 U74.1(REFIN)
N17728967: R532.1 TP78.1 U74.9(PGOOD)
N17793041: D10.1(B-) R254.2
N17836608: R439.1 U65.9(IREF)
N17928857: R98.2 TP17.1
N17928862: R98.1 U15.C5(AXR11/FSX1/GP0[3])
N17928972: R107.2 TP23.1
N17928982: R102.2 TP19.1
N17929018: R106.2 TP21.1
N17929020: R107.1 U15.E4(AXR8/CLKS1/ECAP1/APWM1/GP0[0])
N17929025: R102.1 U15.C3(AXR9/DX1/GP0[1])
N17929027: R106.1 U15.D4(AXR10/DR1/GP0[2])
N17929181: R368.2 TP16.1
N17929183: R381.2 TP22.1
N17929185: R381.1 U15.F17(SPI1_SCS[5]/UART2_RXD/I2C1_SCL/)
N17929187: R368.1 U15.F16(SPI1_SCS[4]/UART2_TXD/I2C1_SDA/)
N17929697: R398.1 U15.P16(USB0_ID)
N17929849: C389.1 U15.N17(USB0_VDDA12)
N17929864: C398.1 C418.1 C424.1 C433.2 FB19.3 U15.N14(USB0_VDDA18)
N17936032: TP34.1 U15.T18(CLKOUT/UHPI_HDS2N/GP6[14])
N17936096: R170.2 U15.V2(VP_DOUT[4]/LCD_D[4]/UPP_XD[12]/)
N17937670: R114.1 U15.K16(EMU1)
N17937746: R395.2 R396.2 R397.2 U15.K14(RESETN)
N17937762: R374.1 U15.J16(EMU0)
N17938891: D9.1(ANODE) R373.1
N17938893: D8.1(ANODE) R372.1
N17939061: D9.2(CATHODE) Q7.3(D)
N17939063: D8.2(CATHODE) Q8.3(D)
N17939289: D7.1(ANODE) R371.1
N17941980: FB15.1 U15.M15(PLL1_VSSA12) U15.M17(PLL0_VSSA12)
N17943569: TP32.1 U15.T19(RSV2(VPP))
N17947121: R122.1 R123.1 U9.26(VCCIO2)
N17948726: J3.4(GND_1) R384.2
N17968117: R82.2 U15.B15(EMA_OEN/GP3[10])
N17968119: R79.2 U15.B9(EMA_WEN/GP3[11])
N17968507: R84.1 U15.E9(EMA_A[23]/MMCSD0_CLK/GP4[7])
N17968518: R85.1 U15.A10(EMA_A[22]/MMCSD0_CMD/GP4[6])
N17968576: R81.2 U15.B16(EMA_CS[5]N/GP3[12])
N17969207: R97.2 U15.B18(EMA_WAIT[0]/GP3[8])
N17969213: R101.2 U15.B19(EMA_WAIT[1]/GP2[1])
N17976218: R166.1 TP35.1 U15.T17(RESETOUTN/UHPI_HASN/GP6[15])
N17976303: R375.1 U15.J17(NMIN)
N17976785: C360.1 R379.1
N18031730: R105.1 U15.G19(SPI1_CLK/GP2[13])
N18106049: C45.2 U17.40(REG_CAP)
N18116016: C329.1 U47.6(C2-)
N18116024: C328.1 U47.2(C1+)
N18116026: R322.2 U47.16(FORCEOFF#)
N18116030: C328.2 U47.4(C1-)
N18116054: C324.1 U47.3(V+)
N18116066: C344.2 U47.7(V-)
N18116072: R326.2 U47.12(FORCEON)
N18116076: C329.2 U47.5(C2+)
N18202591: R55.1 U4.12(FPWM3/GPIO7)
N18238342: AMC1.115(TX12+) R492.1
N18238353: AMC1.114(TX12-) R490.1
N18260681: R329.1 U45.10(OE)
N18287363: D13.2(D-) J1.2(D-) U2.4(D-)
N18287374: D13.1(D+) J1.3(D+) U2.3(D+)
N18287430: R6.2 U2.9(RST)
N18287465: C3.1 R613.2 R614.2 U2.7(REGIN)
N18287912: R558.1 R563.1 U77.15(CONFIG)
N18358937: C732.2 U73.2(SIN_N)
N18358939: C733.2 U73.1(SIN_P)
N18359019: TP77.1 U73.9(CLK125)
N18359046: R551.1 U73.30(RSET)
N18359063: TP79.1 U73.29(TSTPT)
N18359070: C783.2 U73.33(XTAL_OUT) Y7.3
N18359080: C784.2 R553.1 U73.34(XTAL_IN) Y7.1
N18359169: C788.1 U73.41(REGCAP2)
N18359175: C788.2 U73.37(REGCAP1)
N18359199: R498.1 R508.1 U73.15(CONFIG)
N18359263: TP83.1 U73.31(HSDAC_N)
N18359265: TP85.1 U73.32(HSDAC_P)
N18359267: R514.1 U73.53(TX_CLK)
N18359269: R500.1 U73.56(TX_CTRL)
N18359271: R507.1 U73.55(TXD[3])
N18359273: R509.1 U73.54(TXD[2])
N18359285: R515.1 U73.51(TXD[1])
N18359287: R530.1 U73.50(TXD[0])
N18360107: J9.12B(P2_GREEN) R265.2
N18360109: J9.14B(P2_ORANGE) R249.2
N18360137: C809.1 C810.1 C811.1 J9.9B(P2_VCC) R556.1
N18631752: C305.1 LCD1.1(V0)
N18631754: C306.1 LCD1.2(V1)
N18631756: C307.1 LCD1.3(V2)
N18631758: C308.1 LCD1.4(V3)
N18631760: C309.1 LCD1.5(V4)
N18631984: C301.2 LCD1.6(C2-)
N18631986: C301.1 LCD1.7(C2+)
N18631992: C302.2 LCD1.8(C1+)
N18632005: C302.1 LCD1.9(C1-)
N18632025: C310.1 LCD1.10(VOUT)
N18632070: Q10.1(REF) R308.1 R309.1
N18640521: R43.1 U4.18(GPIO13)
N18643296: R419.2 TP65.1
N18643297: R427.2 TP66.1
N18643298: R420.2 TP64.1
N18643299: R430.2 TP67.1
N18643300: R206.2 TP42.1
N18643301: R210.2 TP43.1
N18643419: R173.2 TP36.1
N18643442: R174.2 TP37.1
N18643465: R521.2 TP81.1
N18643488: R534.2 TP80.1
N18643523: R433.2 TP68.1
N18643546: R473.2 TP74.1
N18643624: R461.2 TP71.1
N18643711: R237.2 TP55.1
N18643735: R236.2 TP53.1
N18643759: R437.2 TP69.1
N18643843: R214.2 TP47.1
N18646931: R121.2 TP29.1
N18646952: R124.2 TP31.1
N18646958: R119.2 TP27.1
N18646969: R120.2 TP28.1
N18661122: R156.1 U15.N19(USB0_VBUS)
N18690585: C661.1 R471.1 U67.7(VREF2) U67.8(EN)
N18909283: R88.1 R95.2 U53.G5(LOCK)
N19595154: R238.1 TP56.1 U23.J33(USIMCLK)
N19595193: R243.1 TP54.1 U23.H33(USIMIO)
N19595213: R522.1 TP82.1 U23.K29(USIMRST)
N19617114: L1.1 U20.5(SW)
N19617731: C100.2 R199.2 R202.2 U20.9(FB_DCDC)
N19618957: R194.1 R196.1 U20.11(FB_LDO1)
N19619378: R180.2 R185.1 U20.14(FB_LDO2)
N19620431: R203.1 U20.8(EN_DCDC)
N19620706: C442.2 R191.1 U20.1(EN_LDO1)
N19620742: C444.2 R192.1 U20.2(EN_LDO2)
N19627767: C58.2 R167.1 Y5.3
N19627773: C54.2 R164.1 Y5.1
N19628918: R163.1 Y4.3(OUT)
N19630686: R511.2 U75.44(CLKN)
N19630689: R512.2 U75.43(CLKP)
N19642467: R390.1 U58.6(OE)
N19665402: U19.3(MR#) U59.4(Y)
N19666056: C68.1 U19.4(CT)
N19669080: R378.1 U11.8(OE)
N19695800: R245.1 R246.2 U31.4(OUT) U32.4(EN)
N19714193: C242.1 J10.6(RX_P)
N19714195: C241.1 J10.5(RX_M)
N19714197: C240.1 J10.3(TX_M)
N19714199: C239.1 J10.2(TX_P)
N19809600: R57.1 U4.10(FPWM1/GPIO5)
N19815748: R246.1 R533.2 U31.2(IN)
N19819673: R220.1 R223.2 U27.2(IN)
N19956937: R354.1 R356.2 U9.16(IO12_16)
N20100474: R20.1 U3.6(1Y)
N20107888: R299.2 U36.6(C)
N20108296: R415.2 R417.1 U61.4(REF)
N20214474: R24.1 U3.5(2A)
N20256439: C186.1 L9.2
N20256446: C189.1 L9.1
N20256822: C126.1 L4.1
N20259025: R165.1 TP33.1
N20259028: R165.2 U23.AE4(SYSCLKOUT)
N20260067: U23.AL32(TSIP0TX0) U68.4(A3)
N20260083: U23.AM32(TSIP0TX1) U68.5(A4)
N20260360: R475.1 U68.8(OE)
N20314517: R487.2 U70.7(Q0)
N20314549: R483.2 U70.6(Q1)
N20314831: R499.2 U72.7(Q0)
N20314842: R495.2 U72.6(Q1)
N20315949: R482.2 U70.4(OE)
N20316135: R513.2 U72.4(OE)
N20339426: R541.1 U23.P31(SPI2SCS0)
N20339428: R526.1 U23.R29(SPI2SCS1)
N20339430: R233.1 U23.P33(SPI2SCS2)
N20339432: R524.1 U23.L30(SPI2SCS3)
N20339434: R542.1 U23.R31(SPI2DOUT)
N20339438: R232.1 U23.L33(SPI2CLK)
N20460479: C724.1 R484.1 U69.7(VREF2) U69.8(EN)
N20517788: EEPROM1.3(E2) R425.1 R429.2
N20517790: EEPROM1.2(E1) R421.2 R422.1
N20589689: TP59.1 U23.L29(SPI0SCS2)
N20589690: TP60.1 U23.M29(SPI0SCS1)
N20589691: TP57.1 U23.L32(SPI0SCS3)
N22090501: C277.2 L12.1 R262.2 U34.8(SW1) U34.9(SW2) U34.10(SW3) U34.11(SW4) U34.12(SW5)
N22090505: R263.1 U34.7(BOOT)
N22090506: C277.1 R263.2
N22090512: R275.2 U34.40(RT)
N22090530: C857.2 C858.2 U34.35(COMP)
N22090531: C858.1 R592.1
N22090532: C857.1 R587.1 R592.2 R593.1 R594.2 R603.2 U34.34(FB)
N22090538: C859.2 R587.2 U34.33(DIFFO)
N22090539: C859.1 R594.1
N22090556: R280.2 U34.36(PGOOD)
N22090558: C256.2 L11.1 U33.2(SW1_1) U33.3(SW1_2) U33.4(SW1_3)
N22090580: C246.1 R257.2 R261.2 U33.47(VFB1)
N22090583: C278.2 L14.1 U33.9(SW2_1) U33.10(SW2_2) U33.11(SW2_3)
N22090592: C278.1 U33.12(CB2)
N22090598: C280.2 L13.1 U33.29(SW3)
N22090599: C280.1 U33.28(CB3)
N22090602: C254.2 L10.1 U33.32(SW4_1)
N22090604: C254.1 U33.33(CB4)
N22090609: C290.1 R269.2 R273.2 U33.14(VFB2)
N22090615: C292.1 R270.2 R274.2 U33.26(VF3)
N22090621: C245.1 R256.2 R260.2 U33.35(VFB4)
N22090627: C830.1 U33.45(SS1/PG1)
N22090640: C823.1 R561.1 U33.46(COMP1)
N22090648: C821.2 R561.2
N22090649: C295.1 U33.16(SS2/PG2)
N22090650: C843.1 U33.24(SS3/PG3)
N22090651: C829.1 U33.37(SS4/PG4)
N22090653: R569.1 U33.40(RCLOCK_SYNC)
N22090664: C256.1 U33.1(CB1)
N22090666: R575.2 U33.23(CE)
N22090668: C276.1 R262.1
N22090676: C851.2 R586.1 U33.15(COMP2)
N22090680: C282.2 R586.2
N22090686: C284.2 R582.2
N22090687: C856.2 R582.1 U33.25(COMP3)
N22090695: C820.2 R560.2
N22090696: C822.1 R560.1 U33.36(COMP4)
N22090791: R567.2 U33.39(RESET_N)
N22090797: R590.2 U35.6(SET)
N22090840: R272.2 U33.17(PGOOD)
N22090844: R583.2 U34.4(DATA)
N22090845: R580.2 U34.5(CLK)
N22090846: R584.2 R589.2 U34.1(CNTL)
N22090848: R577.2 U34.6(SMBALRT#)
N22090854: R259.2 U33.43(SCL)
N22090856: R258.2 R282.2 U33.41(I2CALERT)
N22090858: R255.2 U33.42(SDA)
N22090866: R268.2 U34.30(VSET)
N22090868: R279.1 U34.37(TSNS/SS)
N22090880: TP63.1 U33.44(CLK_OUT)
N22090898: R266.2 U34.3(ADDR0)
N22090899: R271.2 U34.2(ADDR1)
N22090903: R277.1 R278.1 U34.39(SYNC/RESET#)
N22090947: C281.1 R267.1 U34.29(VDD)
N22090970: R566.2 U33.38(I2CADDR)
N22169052: R477.1 U23.L26(RSV026)
N22169056: R478.1 U23.K26(RSV027)
N24344484: R389.2 U57.9(2Y1)
N24344504: R387.2 U57.7(2Y2)
N24344573: R385.2 U57.1(1\O\E\)
N24344575: R386.2 U57.19(2\O\E\)
N25551345: R283.2 U15.B7(EMA_CLK/GP2[7])
N25551369: R476.2 U15.D8(EMA_SDCKE/GP2[6])
N25551410: R596.2 U15.A16(EMA_RASN/GP2[5])
N25551640: R597.2 U15.A18(EMA_CS[0]N/GP2[0])
N25565163: R481.2 U15.A9(EMA_CASN/GP2[4])
N25619366: R599.2 U15.C8(EMA_WE_DQM[0]N/GP2[3])
N25619369: R600.2 U15.A5(EMA_WE_DQM[1]N/GP2[2])
N26224346: R575.1 TP94.1
N26374725: C874.2 R623.2
N26377331: C872.2 R621.2
N26444584: R628.2 U79.6(OE)
N26449108: Q15.3(FB) R647.2 R648.1
N26465222: R407.1 U58.8(B1)
N26465374: R412.1 U58.1(B2)
N26504675: R94.2 U8.21(GPA0)
N26504706: R93.1 U8.8(GPB7)
N26537188: C896.2 R653.2
N26540501: R642.2 U80.22(OE#)
N26541964: R655.2 U80.14(B8)
N26588297: R637.1 U80.6(A4)
N26588299: R636.1 U80.5(A3)
N26588301: R635.1 U80.4(A2)
N26588303: R634.1 U80.3(A1)
N26588305: R640.1 U80.9(A7)
N26588307: R638.1 U80.7(A5)
N26588309: R639.1 U80.8(A6)
N26588382: R638.2 TP96.1
N26588389: R640.2 TP97.1
N26588687: R654.1 U80.2(DIR)
N56425294: AMC1.53(RX5+) C165.1
N56425297: AMC1.54(RX5-) C162.1
N56425300: AMC1.47(RX4+) C187.1
N56425303: AMC1.48(RX4-) C176.1
N66223400: C457.2 U23.G3(DDRCLKN)
N66223405: C456.2 U23.G4(DDRCLKP)
N68025719: R39.2 U1.31(PA5/SSI0TX)
N68025736: R40.2 U1.30(PA4/SSI0RX)
N68027970: R296.1 SW1.8
N68027994: R295.1 SW1.7
N68028184: R294.1 SW1.6
N68028192: R293.1 SW1.5
N68029449: R181.1 RST_PWR1.1
N68029469: R211.1 RST_ATTN1.1
N68035165: C298.1 C318.1 C338.1 U1.7(LDO) U1.38(VDDC_1) U1.88(VDDC_2)
N68049827: TP25.1 U17.45(STATUS1/PIN0)
N68049869: R154.2 U17.6(REF_SEL)
N68057675: R151.2 U18.1(SI_MODE0)
N68057679: TP26.1 U18.45(STATUS1/PIN0)
N68057721: R157.2 U18.6(REF_SEL)
N68057761: C42.2 U18.40(REG_CAP)
N68057795: R138.2 U18.47(SI_MODE1)
N68067792: R150.2 U17.1(SI_MODE0)
N68067794: R135.2 U17.47(SI_MODE1)
N68073129: R28.2 U1.51(H\I\B\)

Pads without a net: AMC1 6 8 35 36 38 39 59 60 62 63 65 66 68 69 87 88 90 91 93 94 96 97 99 100 102 103 105 106 108 109 117 118 120 121 123 124 126 127 132 133 138 139 141 142 144 145 147 148 150 151 153 154 156 157 162 163; CN2 1; CN3 7; CN7 41 67 114; D13 3 5; D14 3 5; DIMM1 118 120 198; EEPROM1 1; EMU1 9 10 11 14 44 46 48 50 52 54 56 59 60; FAN1 3; FM1 1; FM2 1; FM3 1; FM4 1; FM5 1; FM6 1; H6 1; J2 A10 B10 C5 C6 C7 C8 C10 D5 D6 D7 D8 D10 E1 E2 E3 E4 E5 E6 E7 E8 E9 E10 F1 F2 F3 F4 F5 F6 F7 F8 F9 F10 G1 G2 G3 G4 G5 G6 G7 G8 G9 G10 H1 H2 H3 H4 H5 H6 H7 H8 H9 H10; J4 C7 C8 C9 C10 D7 D8 D9 D10 E1 E2 E3 E4 E5 E6 E7 E8 E9 E10 F1 F2 F3 F4 F5 F6 F7 F8 F9 F10 G1 G2 G3 G4 G5 G6 G7 G8 G9 G10 H1 H2 H3 H4 H5 H6 H7 H8 H9 H10; J5 6 13 14 16 17 18 19 20; NOR1 3 4 5 6 11 12 13 14; Q1 1 5; Q15 2 6 7; RN9 1 8; RST_ATTN1 SH1 SH2; RST_PWR1 3 4; U1 53 70 71 73 95 98; U2 1 10 11 14 15 16 17 18 19 22 23 24; U3 3 7; U4 37; U8 3 6 19; U11 6 9; U12 1; U15 A1 A2 A3 A12 A17 B1 B2 B17 C1 C2 C11 C16 C17 C18 C19 D1 D2 D3 D5 D10 D11 D16 D17 D18 D19 E1 E2 E3 E16 E17 F1 F2 F3 F4 F9 G1 G2 G3 G4 G16 G18 H3 H4 H16 J1 J2 J3 J4 K3 K4 K18 L1 L2 M2 M3 M14 N1 N2 N3 N4 N16 P1 P2 P3 P14 P15 P17 P18 P19 R5 R6 R10 R11 R12 R14 R15 R16 R17 R18 R19 T4 T5 T6 T7 T8 T9 T10 T11 T12 T13 T14 T15 T16 U4 U5 U6 U7 U8 U9 U10 U11 U12 U13 U14 U15 U16 U17 U18 U19 V1 V4 V5 V6 V7 V8 V9 V10 V11 V12 V13 V14 V15 V16 V17 V18 V19 W1 W2 W3 W4 W5 W6 W7 W8 W9 W10 W11 W12 W13 W14 W15 W16 W17 W18 W19; U17 16 17; U18 8 9 16 17 22 23; U23 G33 H29 M32 M33 N30 N33 P29 P32 R30 R32 R33 U33 W29; U26 3; U27 1; U31 1; U32 3; U37 1 4; U38 7 10; U39 7 8 19 21 22 28; U41 9 12; U42 3; U43 4 5 19 21; U44 19; U45 4 5 16 17; U47 10; U49 5 11 14; U50 10; U52 3; U53 A1 A2 A9 A10 B1 B9 B10 D6 D7 D8 E3 E4 E5 E6 E7 E8 F3 F4 F5 F6 F8 G3 G6 G7 G8 H3 H5 H6 H7 J3 J5 L1 L2 L9 L10 M1 M2 M9 M10; U57 3 5 15 17; U59 1; U61 1 2; U68 6 9; U73 43 44 45 46 47 48; U75 2 10 11 12 47 48 49 50 51 53 54 55 56; U77 43 44 45 46 47 48; U78 E2 G1; U79 1 4; U80 10

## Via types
v1: diameter 0.457, hole 0.203, TOP to BOTTOM, 1530 vias
v2: diameter 0.508, hole 0.254, TOP to BOTTOM, 915 vias
v3: diameter 0.61, hole 0.356, TOP to BOTTOM, 314 vias
v4: diameter 0.432, hole 0.203, TOP to BOTTOM, 1078 vias
v5: diameter 0.406, hole 0.203, TOP to BOTTOM, 1 via
v6: diameter 0.762, hole 0.406, TOP to BOTTOM, 126 vias
v7: diameter 0.6, hole 0.3, TOP to BOTTOM, 55 vias
v8: diameter 0.559, hole 0.305, TOP to BOTTOM, 27 vias
v9: diameter 0.45, hole 0.203, TOP to BOTTOM, 8 vias

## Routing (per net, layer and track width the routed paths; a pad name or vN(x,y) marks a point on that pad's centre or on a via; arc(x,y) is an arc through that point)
AGND: length 3.9
  TOP w0.381: v2(63.58,2.03) 63.58,1.57
  TOP w0.457: 65.5,6.54 U34.38 65.5,4.13 65.68,3.94
  BOTTOM w0.254: v2(63.58,2.03) 63.19,2.41 R593.2
  vias: v3(55.27,8.36) v3(56.39,8.36) v6(58.9,5.03) v6(59.92,5.03)
AGND1: length 19.1
  TOP w0.254: C284.1 103.63,3.99 103.81,3.81 v2(104.22,3.81) ; v2(102.07,7.83) 102.04,7.87 U33.21 ; C282.1 v2(98.28,5.92)
  BOTTOM w0.254: C853.1 100.84,4.5 101.42,3.91 v2(101.42,3.76) ; C853.1 C854.1 99.14,4.24 98.83,3.94 v2(98.5,3.94) ; C853.1 C852.1 ; v2(96.32,18.57) 96.39,18.64 C821.1 96.9,19.1 97.16,18.85 C823.2 ; R566.1 105.54,16.59 105.94,16.99 v2(105.94,18.34) 106.43,18.82 C820.1 105.66,19.11 105.48,18.92 C822.2 ; v2(104.45,5) 104.45,4.69 104.64,4.5 C856.1 ; C851.1 98.1,6.1 v2(98.28,5.92)
  BOTTOM w0.381: v2(102.07,7.83) 101.35,8.56 R281.2
AVCC3V3_1: length 4.6
  TOP w0.254: v1(138.18,13.34) 138.07,13.23 138.02,13.23 137.87,13.08 C259.1 ; C274.1 v1(132.72,10.2)
  BOTTOM w0.254: U77.36 132.72,11.1 v1(132.72,10.2) ; U77.25 138.14,13.3 v1(138.18,13.34) ; U77.20 137.36,15.8 137.41,15.75 137.49,15.75 137.54,15.8 137.54,15.74 v1(137.7,15.74)
  vias: v1(141.94,14.3) v1(141.94,13.41)
AVCC3V3_2: length 9.9
  TOP w0.254: v1(134.75,33.95) 134.75,33.95 C210.1 ; C188.1 C195.1 139.4,37.05 140.27,37.05 v1(140.66,36.65) ; v1(139.73,39.38) 139.73,39.02 139.63,38.92 C175.1 C177.1
  BOTTOM w0.254: v1(134.75,33.95) 134.75,34.11 134.75,34.11 134.75,34.73 U73.36 ; U73.20 139.74,39.43 139.74,39.38 v1(139.73,39.38) ; v1(140.66,36.65) 140.38,36.93 U73.25
  vias: v1(144.91,37.21) v1(144.96,37.9)
AVDD0: length 9.2
  TOP w0.381: FB7.2 C193.1 C192.1 C191.1 C190.2 30.21,37.52 31,36.74 v2(31,35.61)
  BOTTOM w0.203: U75.40 v2(31,35.61)
AVDD1: length 8.4
  TOP w0.381: FB9.2 C223.1 C221.1 C218.1 C213.2 30.68,34.92 31,34.6 v2(31,33.61)
  BOTTOM w0.203: U75.35 v2(31,33.61)
AVDD1V8_1: length 22.9
  TOP w0.254: v1(131.72,10.32) 131.44,10.32 131.19,10.57 C272.1 ; C265.1 137.66,11.68 138.25,12.28 v1(138.25,12.67) ; C273.1 129.67,10.41 130.43,9.65 v1(131.32,9.65) ; v1(133.2,9.62) 133.68,9.62 134.24,10.18 C271.1
  TOP w0.508: C269.1 v1(126.75,10.6)
  BOTTOM w0.254: U77.39 131.22,9.75 v1(131.32,9.65) ; v1(133.2,9.62) 133.22,9.64 U77.35 ; U77.19 137.53,16.3 137.54,16.31 138.17,16.31 138.33,16.15 139.22,16.15 139.42,16.35 C834.1 140.39,16.35 141.05,17.02 C827.1 ; U77.3 130.72,19.87 130.51,20.09 130.51,20.97 C819.1 v1(130.87,22.12) ; U77.26 137.67,12.8 137.8,12.67 v1(138.25,12.67) ; U77.38 v1(131.72,10.32)
  BOTTOM w0.508: C827.1 v1(141.8,17.96)
  vias: v1(141.86,12.45) v1(142.88,12.45)
AVDD1V8_2: length 24.1
  TOP w0.254: C204.1 137.34,35.8 v1(137.64,36.09) ; v1(135.15,33.4) 136.07,33.4 136.27,33.6 C209.1 ; v1(133.48,33.3) 132.25,33.3 131.7,33.86 C212.1 ; C211.1 133.22,34.21 133.48,33.95 v1(133.75,33.95)
  TOP w0.635: C208.1 v1(128.75,34.24)
  BOTTOM w0.254: v1(135.15,33.4) 135.25,33.5 U73.35 ; U73.38 v1(133.75,33.95) ; U73.26 137.98,36.43 v1(137.64,36.09) ; v1(132.97,45.69) 132.98,45.69 C734.1 132.54,44.54 132.54,43.72 132.75,43.51 U73.3 ; C759.1 141.92,40.2 141.47,39.75 140.59,39.75 140.41,39.93 U73.19 ; U73.39 133.25,33.53 v1(133.48,33.3)
  BOTTOM w0.381: v1(144.64,41.9) C748.1 143.98,40.77 143.41,40.2 C759.1
  vias: v1(141.6,34.42) v1(141.6,33.66)
AVDDA1: length 1.6
  TOP w0.254: U23.AF7 v4(54.38,69.36)
  BOTTOM w0.254: C491.1 v4(54.38,69.36) C490.1
  vias: v3(32.61,72.49)
AVDDA2: length 26.4
  TOP w0.254: U23.K7 v4(67.98,69.36)
  L10_SIG4 w0.152: 70.51,73.62 70.77,73.36 70.77,70 70.54,69.77 70.22,69.77 69.98,69.53 69.98,69.2 69.74,68.96 68.37,68.96 v4(67.98,69.36) 68.03,69.36 68.43,69.76 68.94,69.76 69.17,69.99 69.17,70.32 69.41,70.56 69.74,70.56 69.98,70.8 69.98,72.83 70.19,73.04 70.19,73.3 70.51,73.62
  L10_SIG4 w0.508: 70.51,73.62 70.51,75.36 75.06,79.91 v3(75.06,82.04)
  BOTTOM w0.254: C481.1 v4(67.98,69.36) C482.1
  BOTTOM w0.508: v3(75.06,82.04) 75.31,82.3 FB21.1
AVDDA3: length 2.3
  TOP w0.254: U23.AD7 v4(55.98,69.36)
  BOTTOM w0.254: C486.1 v4(55.98,69.36) C477.1
  BOTTOM w0.508: FB24.1 v3(38.76,79.04)
DVDD1V0: length 19.2
  TOP w0.254: C224.1 32.19,30.03 v2(31.5,29.34) ; C203.1 v2(32.77,38.23)
  L3_SIG1 w0.762: v2(38.33,30.94) 37.81,30.43 32.59,30.43 v2(31.5,29.34)
  BOTTOM w0.203: U75.4 38.13,35.21 38.28,35.37 v2(38.3,35.37) ; v2(31.5,29.34) 31.77,29.61 U75.26 ; v2(38.33,30.94) 38.06,31.21 U75.14
  BOTTOM w0.254: U75.1 v2(38.33,36.41) ; U75.46 32.17,38 32.4,38.23 v2(32.77,38.23) ; U75.9 37.56,33.21 v2(38.38,32.38)
DVDD1V0_1: length 11
  BOTTOM w0.254: 130.9,8.51 130.39,8 v1(130.3,8) ; 130.9,8.51 C847.1 ; 130.9,8.51 130.72,8.69 U77.40 ; C846.1 128.09,8.83 128.27,9.02 128.91,9.02 129.72,9.83 U77.42 ; U77.6 132.22,19.92 132.38,20.09 132.38,20.4 132.9,20.91 C818.1 v1(132.9,22.29)
  vias: v1(129.67,5.71) v1(129.67,4.95) v1(129.67,4.19)
DVDD1V0_2: length 9.9
  BOTTOM w0.254: v1(134.93,45.68) C735.1 134.93,44.78 134.42,44.27 134.42,43.72 134.25,43.56 U73.6 ; 130.43,32.23 131.75,33.55 U73.42 ; U73.40 132.75,33.16 133.1,32.82 C787.1 v1(132.31,32.15)
  vias: v1(131.5,29.44) v1(131.5,28.07) v1(131.95,28.78)
GND: length 3567.8
  TOP w0.254: v2(84.62,103.56) 84.62,103.57 84.73,103.68 84.73,104.12 C36.1 ; v4(52.78,63.76) U23.AJ13 ; Y5.4 57.09,94.5 57.49,94.91 v2(57.91,94.91) C54.1 ; U11.7 v2(85.64,108.59) ; DIMM1.143 v1(99,47.57) ; v2(177.24,111.51) 177.25,111.5 D7.2 ; U1.45 142.69,130.22 142.35,130.56 142.36,130.56 v2(142.37,130.55) ; CN7.64 v2(36.83,118.49) ; C259.2 135.04,13.08 v1(134.99,13.03) ; DIMM1.155 v1(96.04,43.97) ; C58.1 v2(57.91,90.3) ; CN7.57 v3(39.01,111.99) ; U5.4 144.91,116.33 144.65,116.59 v2(144.65,117.6) ; v1(137.82,100.88) U15.M1 ; U1.94 136.19,144.25 136.6,143.84 v2(137.77,143.84) ; v2(99,39.51) 98.75,39.77 DIMM1.169 ; C78.2 65.53,82.67 v2(65.63,82.57) ; U15.A19 v1(153.02,110.48) ; DIMM1.35 97.54,82.36 99.89,82.36 v2(99.9,82.37) ; v1(150.62,43.69) 149.96,43.03 NOR1.10 ; U15.J8 v1(143.42,104.08) U15.J7 ; U1.33 136.69,130.33 136.4,130.62 v2(136.21,130.62) ; C173.1 v2(52.35,42.69) ; U7.8 86.24,116.47 v8(86.49,116.72) ; v2(96.08,78.61) 96.23,78.77 DIMM1.47 ; DIMM1.46 104.4,79.07 104.4,79.06 104.31,79.06 v2(104.22,78.98) ; C12.1 100.05,132.57 100.15,132.47 U3.4 ; J6.5 174,58.79 v3(173.71,59.08) ; DIMM1.196 v2(107.2,31.67) ; 125.58,131.17 v2(125.6,131.19) 124.89,131.19 124.59,130.89 TP7.1 ; Y5.2 52.63,90.36 52.37,90.62 52.37,90.72 52.3,90.72 v2(52.3,90.79) ; R153.1 v1(131.12,96.93) ; C27.2 47.95,112.46 v7(47.36,111.87) ; DIMM1.187 95.84,34.37 v2(95.78,34.43) ; DIMM1.178 v2(107.2,37.07) ; C20.1 59.41,118.09 v2(59.88,118.57) ; DIMM1.152 v2(107.2,44.87) ; C130.2 v2(93.52,60.98) ; Y2.2 v2(164.92,104.83) ; v4(128.77,106.47) 128.66,106.36 C861.2 ; C210.2 134.75,36.41 v1(135,36.66) ; C171.1 v2(55.09,42.69) ; v1(137.02,40.71) 137.02,40.07 137.27,39.82 C177.2 C175.2 ; C212.2 131.7,36.25 132.12,36.66 v1(132.98,36.66) 133.22,36.42 C211.2 ; C23.1 47.95,116.02 v7(47.36,116.6) ; R99.1 61.5,108.87 v3(61.19,108.56) 61.11,108.64 C30.2 ; v1(152.39,37.97) 151.96,37.97 151.95,37.97 C194.2 ; U15.J11 146.38,103.53 v1(146.62,103.28) U15.K11 v1(146.62,102.48) U15.L11 ; C272.2 131.19,12.79 v1(130.95,13.03) 130.38,13.03 129.67,12.32 C273.2 ; U14.26 46.18,102.76 U14.10 ; v7(64,8.76) 63.75,9.01 U34.26 ; C474.2 136.21,48.44 v1(135.76,48.9) ; v1(138.62,102.48) U15.K2 ; C44.2 83.53,102.69 83.53,103.54 v2(83.33,103.75) 83.08,103.99 TP24.1 ; C18.2 86.66,127.5 v1(86.63,127.53) ; C181.1 v2(66.14,40.58) ; DIMM1.17 v2(99,87.77) ; R78.2 v1(135.43,115.06) ; U15.J10 v1(145.02,104.08) U15.H9 ; v3(26.52,80.64) 26.29,80.87 TP40.1 ; CN7.3 39.57,98.49 v2(38.81,97.74) ; R77.2 v1(139.13,115.81) ; v7(54.19,116.93) 53.94,116.68 U6.10 ; DIMM1.175 v2(99,37.97) ; v1(139.42,101.68) U15.L3 ; C864.2 128.52,104.32 v4(128.77,104.07) ; U8.10 v2(73.13,112.04) ; R111.1 131.1,104.42 v1(131.1,103.71) ; v3(143.21,52.22) 143.56,52.58 C152.2 ; U29.B1 v3(152.02,44.2) ; v2(25.77,31.68) 26.11,31.68 26.35,31.91 R250.2 ; v1(147.42,100.08) U15.N12 ; R270.1 v2(104.32,5.89) ; DIMM1.146 v2(107.2,46.67) ; U23.Y28 v4(59.18,51.76) ; C195.2 C188.2 137.91,37.8 v1(137.02,38.68) ; v2(148.46,140.97) 148.46,140.77 147.86,140.16 U1.69 ; 158.56,69.51 U22.2 ; 158.56,69.51 158.55,69.49 ; 158.56,69.51 158.72,69.67 C112.2 158.17,70.11 158.07,70.01 U22.3 v8(155.85,70.01) ; U15.K9 v1(144.22,102.48) U15.L9 ; U16.10 46.18,97.04 U16.21 ; C92.1 v2(60.17,78.85) ; C169.2 v2(66.14,43.2) ; v1(99.63,49.19) 99.45,49.37 DIMM1.137 ; U15.M4 v1(141.02,101.68) U15.L5 ; Q8.2 v2(167.25,107.19) ; v2(101.45,120.62) 101.12,120.62 100.97,120.47 EMU1.16 ; R149.1 131.12,99.23 130.52,98.63 v1(130.52,98.65) ; C93.1 v2(58.14,79.75) ; C296.2 U35.1 54.14,1.74 v7(53.82,2.06) ; v2(77.55,109.44) 77.88,109.44 U8.15 ; U10.10 53.94,108.18 53.94,108.18 53.94,107.99 v3(54.22,107.71) ; Y2.3 v2(164.9,105.73) ; C174.2 v3(156.39,42.42) ; v1(60.18,106.32) 59.82,105.97 58.65,105.97 58.57,105.89 U13.2 ; U15.K7 v1(142.62,102.48) U15.L7 ; v4(125.74,105.27) 126.2,104.8 C860.2 126.47,103.68 C863.2 ; U1.9 v2(130.05,139.16) ; U15.K10 v1(145.02,102.48) U15.L10 ; U23.W27 v4(59.98,52.56) ; v2(168.15,107.24) 168.55,107.24 168.78,107.47 R103.2 ; v2(169.84,76.8) 169.84,76.8 C102.2 ; C185.1 v2(52.27,40.58) ; C124.2 v2(93.52,65.78) ; v1(138.62,104.88) U15.H2 ; U9.4 116.92,116.26 v2(116.97,116.2) ; v3(32.64,133.22) 32.64,132.59 33.23,131.99 CN7.118 ; v2(148.34,132.33) 148.01,132.66 U1.54 ; DIMM1.158 v2(107.2,43.07) ; C167.1 v2(70.21,43.2) ; C271.2 134.24,12.45 133.66,13.03 v1(132.97,13.03) 132.72,12.77 C274.2 ; DIMM1.181 v2(99,36.17) ; C29.2 58.67,110.16 v2(58.8,110.03) ; R453.1 151.26,39.24 v1(151.56,38.94) ; v1(130.45,96.14) R159.1 ; C19.2 v2(58.67,121.74) ; R33.2 v2(108.08,127.76) ; DIMM1.163 v2(96.16,41.57) ; v1(136.91,10.67) 136.46,11.12 C265.2 ; R175.1 v1(138.51,88.39) ; C209.2 136.27,36.4 136.54,36.66 v1(137.02,36.66) ; C77.2 v2(67.01,81.77) ; U15.M6 v1(142.62,100.88) U15.M7 ; C179.1 v2(70.21,40.58) ; v4(51.98,64.56) U23.AK12 ; v1(137.82,102.48) U15.K1 ; v1(145.02,100.88) U15.M10 ; Q1.2 v2(114.55,139.92) ; C33.2 v2(65.53,105.87) ; U23.F4 v4(71.18,71.76) ; v7(144.65,80.65) 144.9,80.9 U20.10 146.68,80.9 146.68,80.9 R196.2 ; U1.57 v2(148.13,134.16) ; v2(155.51,85.57) C67.2 ; v8(142.93,57.62) U25.3 140.71,57.62 140.61,57.52 C139.2 140.06,57.97 140.22,58.12 ; DIMM1.184 v2(107.2,35.27) ; C89.2 v2(68.38,79.75) ; v8(163.84,134.86) 163.99,135.01 U2.2 ; C88.1 v2(69.95,78.85) ; v2(76.6,109.42) 76.6,109.83 76.86,110.09 78.76,110.09 U8.16 ; DIMM1.67 95.79,72.77 v2(95.61,72.94) ; C80.2 v2(58.83,82.67) ; R15.1 v2(112.8,135.96) ; J10.1 v2(36.64,22.67) ; U19.2 154.56,91.9 v2(155.07,92.41) ; DIMM1.195 99.15,31.97 v2(99.21,31.9) ; C283.2 102.01,4.51 102.79,5.3 v2(102.79,5.55) ; v2(98.95,80.66) 98.77,80.66 98.68,80.57 97.54,80.57 DIMM1.41 ; R588.1 v1(57.78,5.21) ; v2(77.41,110.74) 77.88,110.74 U8.17 ; R269.1 v2(96.06,6.1) ; v2(94.46,91.03) 94.51,91.08 94.51,91.62 C57.1 ; v3(156.46,54.08) C150.2 ; CN7.63 39.13,118.49 v3(39.12,118.48) ; R95.1 60.83,112.62 v2(60.78,112.57) ; C16.1 v2(146.12,128.07) ; R261.1 v2(97.63,18.06) ; v2(171.96,109.8) 171.42,109.8 171.32,109.69 Q7.2 ; U4.71 114.57,131.54 U4.32 ; v3(100.23,134.87) 100.23,134.36 100.62,133.97 U3.1 ; R176.1 v1(137.03,88.39) ; J6.8 v2(173.86,64.19) ; v1(90.12,32.16) 90.12,32.37 88.04,34.45 88.04,36.55 88.23,36.75 R238.2 ; R241.1 85.1,35.85 85.24,35.99 v4(85.24,36.44) ; R137.2 v2(61.98,102.68) ; v2(68.4,82.57) 68.3,82.67 C76.1 ; R108.1 v2(67.06,105.87) ; R247.2 v2(93.18,33.07) ; U15.J9 v1(144.22,104.08) U15.H8 ; U15.H15 v1(149.82,104.88) ; DIMM1.23 98.64,85.97 v2(99.03,85.57) ; R104.2 165.34,107.86 v2(165.48,107.72) ; U15.P11 v1(145.82,100.08) U15.N11 v1(145.82,100.88) U15.M11 ; CN7.4 v3(33.42,98.49) ; DIMM1.170 v2(107.2,39.47) ; U15.M5 v1(141.02,100.88) U15.N5 ; R260.1 103.52,18.39 104.14,17.77 v2(104.14,17.65) ; CN7.117 39.33,131.99 39.07,132.25 v3(39.07,132.71) ; C865.2 v1(125.4,109) ; C166.1 v2(72.11,42.3) ; C862.2 125.77,106.84 v4(125.74,106.87) ; C60.2 v2(171.82,89.42) ; C26.2 65.13,112.94 65.13,111.71 64.51,111.1 v1(63.87,111.1) ; C182.1 v2(64.11,39.68) ; EMU1.57 95.16,109.97 95.3,109.83 95.3,108.69 95.05,108.43 v2(94.69,108.43) ; R546.1 72.06,87.97 70.85,86.75 69.51,86.75 68.17,88.09 v2(68.17,88.16) ; v1(66.37,117.73) 65.99,117.73 65.7,117.44 C21.1 ; R209.2 v3(156.08,73.94) ; R135.1 v2(77.22,102.05) ; C25.1 v1(58.67,114.56) ; DIMM1.164 v2(107.2,41.27) ; C17.2 v2(143.06,126.52) ; v1(131.12,100.2) R142.1 ; U1.82 v2(142.19,143.84) ; v1(66.27,114.3) 66.3,114.33 C22.1 ; v1(90.68,32.66) 92.02,34.01 92.02,35.59 92.13,35.69 92.13,36.3 91.7,36.72 R243.2 ; v2(99,84.17) 98.88,84.17 98.88,84.17 DIMM1.29 ; C10.2 154.48,135.31 v2(154.86,135.69) ; U1.4 v2(130.05,141.66) ; U31.3 v1(148.46,33.02) ; TP41.1 DIMM1.53 98.88,76.97 98.88,76.97 v2(99,76.97) ; C184.1 v2(53.7,39.68) ; C28.1 45.22,112.41 45.76,111.87 v7(46.36,111.87) ; R155.2 v2(74.44,97.66) ; U9.17 110.82,111.66 v2(111,111.48) ; J10.4 v2(32.83,22.67) ; U27.3 v3(162.11,47.73) ; C178.1 v2(72.24,39.68) ; C151.2 v3(154.2,53.41) ; DIMM1.73 v2(99,68.57) ; 140.22,58.12 140.23,58.14 ; 140.22,58.12 U25.2 ; C164.2 v3(155.52,44.81) ; R151.1 v2(59.24,98.91) ; C8.2 v2(109.86,136.58) ; C170.1 v2(64.11,42.3) ; DIMM1.190 v2(107.2,33.47) ; C75.1 v2(69.77,81.77) ; DIMM1.78 107.48,67.07 v2(107.67,66.88) ; C24.2 45.02,116.18 45.44,116.6 v7(46.36,116.6) ; v3(36.94,111.99) CN7.58 ; R150.1 v2(76.63,99.06) ; C180.1 v2(68.17,39.68) ; C90.1 v2(67.01,78.85) ; v2(71.15,82.57) 71.04,82.67 C74.1 ; C34.1 v2(64.01,105.84) ; C140.2 v2(93.52,56.7) ; DIMM1.61 v2(96.16,74.57) ; U15.L8 v1(143.42,102.48) U15.K8 ; R139.2 81.1,101.92 v2(81,101.82) ; C172.1 v2(53.72,41.79) ; v2(93.45,54.56) 93.52,54.49 C147.2 ; U28.B1 v3(154.69,49.92) ; v1(131.12,101.98) R126.1 ; C125.2 v2(93.52,63.38) ; DIMM1.149 v1(96.09,45.77) ; C59.2 v2(75.34,92.39) ; R87.2 v1(132.72,113.92) ; C96.1 v2(51.61,79.75) ; v1(137.82,104.88) U15.H1 ; U1.21 v2(130.24,133.16) ; C9.2 v2(109.51,135.1) ; R138.1 v2(59.94,102.62) ; C155.2 v2(93.52,51.98) ; J10.7 v2(29.02,22.67) ; C168.2 v2(68.17,42.3) ; C91.1 v2(65.63,79.75) ; C183.1 v2(55.09,40.58) ; C295.2 v2(99.26,1.62) ; C81.1 v2(57.45,81.77) ; R76.2 v1(141.17,115.81) ; C68.2 v2(152.54,85.65) ; C204.2 138.25,34.6 138.5,34.35 138.52,34.37 v1(138.81,34.37) ; v2(93.18,28.88) R253.2 ; C79.2 v2(60.17,81.77) ; DIMM1.79 v2(99,66.77) ; C15.2 v1(162.56,131.13) ; DIMM1.138 v2(104.19,49.07)
  TOP w0.305: v2(105.31,106.2) 105.41,106.3 C31.2 ; B2.2 85.83,105.03 85.55,104.75 v2(85.55,103.71) ; v2(70.28,105.74) 70.99,105.03 B3.2 ; C57.1 94.83,91.67 95.13,91.97 95.83,91.97 95.83,91.97 DIMM1.3 ; v2(100.96,107.04) 101.08,106.92 U12.3 ; B4.2 68.43,105.03 v2(67.77,105.69) ; C894.2 46.99,90.79 v9(46.96,90.76)
  TOP w0.356: DIMM1.26 107.2,85.07 v2(107.2,85.07) ; DIMM1.14 v3(107.25,88.67) ; DIMM1.32 107.07,83.27 v2(107.12,83.21) ; DIMM1.2 v3(107.25,92.27) ; DIMM1.9 99.03,90.17 v2(99.11,90.25) ; v2(107.2,75.47) 107.2,75.47 DIMM1.58 ; DIMM1.38 107.2,81.47 v2(107.2,81.47) ; DIMM1.70 v1(107.19,71.87) ; DIMM1.20 v2(107.2,86.87) ; DIMM1.52 107.2,77.27 v2(107.2,77.27) ; DIMM1.64 107.2,73.67 v2(107.2,73.67) ; DIMM1.8 v3(107.25,90.47)
  TOP w0.381: U23.D7 v4(72.78,69.36) ; v4(60.78,68.56) U23.V8 U23.U9 v4(62.38,67.76) U23.T8 v4(63.18,68.56) U23.R7 v4(63.98,69.36) ; U23.D3 v4(72.78,72.56) ; U23.AN13 v4(48.61,64.16) ; v4(52.78,63.76) U23.AH14 v4(53.58,62.96) U23.AG15 v4(54.38,62.16) U23.AF16 v4(55.18,61.36) U23.AE17 U23.AD18 v4(55.98,59.76) U23.AE19 v4(55.18,58.96) U23.AF20 v4(54.38,58.16) U23.AG21 v4(53.58,57.36) U23.AH22 v4(52.78,56.56) U23.AJ23 v4(51.98,55.76) U23.AK24 v4(51.18,54.96) U23.AL25 v4(50.38,54.16) ; U23.AH24 v4(53.58,55.76) U23.AG23 v4(54.38,56.56) U23.AF22 v4(55.18,57.36) U23.AE21 v4(55.98,58.16) U23.AD20 v4(56.78,58.96) U23.AC19 v4(57.58,59.76) U23.AB18 U23.AC17 v4(56.78,61.36) U23.AD16 v4(55.98,62.16) U23.AE15 v4(55.18,62.96) U23.AF14 v4(54.38,63.76) U23.AG13 v4(53.58,64.56) U23.AH12 v4(52.78,65.36) ; U23.C29 v4(73.58,50.96) ; U23.U32 v4(62.38,48.56) ; GND3.1 151.34,129.41 v1(151.3,129.37) ; U23.J3 v4(68.78,72.56) ; C4.2 v2(164.21,141.68) ; v4(67.18,54.16) U23.L25 v4(66.38,54.96) U23.M24 v4(65.58,55.76) U23.N23 v4(64.78,56.56) U23.P22 v4(63.98,57.36) U23.R21 v4(63.18,58.16) U23.T20 ; Q4.2 v2(175.7,123.19) ; Y4.2 52.64,95.99 52.45,95.81 v2(52.53,95.81) ; TP62.1 46.86,21.44 ; CN3.3 v3(103.38,136.14) ; U23.AL4 v4(50.38,71.76) U23.AM3 v4(49.58,72.56) U23.AN2 ; J5.4 v3(167,89.03) ; C103.2 v3(155.24,77.93) ; v4(52.78,62.16) U23.AH16 v4(53.58,61.36) U23.AG17 U23.AH18 v4(52.78,59.76) U23.AJ19 v4(51.98,58.96) ; v4(49.58,70.16) U23.AM6 v4(50.38,69.36) U23.AL7 ; J5.10 v3(167,85.22) ; Q6.2 v2(175.7,113.79) ; U23.AL10 v4(50.38,66.96) U23.AM9 v4(49.58,67.76) ; U23.V10 v4(60.78,66.96) U23.W9 v4(59.98,67.76) U23.Y8 v4(59.18,68.56) U23.AA7 v4(58.38,69.36) ; v3(147.8,74.23) 147.93,74.35 C106.2 ; U23.J7 v4(68.78,69.36) ; U23.U3 v4(62.38,72.56) U23.T2 v4(62.38,73.36) ; U23.W27 v4(60.78,53.36) U23.V26 U23.U27 ; C229.2 40.77,28 40.51,27.74 C230.2 v2(39.88,26.59) ; U23.AJ16 v4(51.98,62.16) U23.AK15 v4(51.18,62.96) ; U23.N2 v4(65.58,73.37) 65.59,73.37 U23.M1 v4(66.38,74.16) ; U23.AK21 v4(51.18,57.36) U23.AL22 v4(50.38,56.56) ; Q2.1 v2(123.43,132.46) ; v4(52.78,68.56) U23.AH8 v4(53.58,67.76) U23.AG9 v4(54.38,66.96) U23.AF10 v4(55.18,66.16) U23.AE11 v4(55.98,65.36) U23.AD12 v4(56.78,64.56) U23.AC13 v4(57.58,63.76) U23.AB14 v4(58.38,62.96) U23.AA15 v4(59.18,62.16) U23.Y16 v4(59.98,61.36) U23.W17 U23.V18 v4(60.78,59.76) U23.W19 v4(59.98,58.96) U23.Y20 v4(59.18,58.16) U23.AA21 v4(58.38,57.36) U23.AB22 v4(57.58,56.56) U23.AC23 v4(56.78,55.76) U23.AD24 v4(55.98,54.96) U23.AE25 v4(55.18,54.16) U23.AF26 v4(54.38,53.36) U23.AG27 v4(53.58,52.56) U23.AH28 v4(52.78,51.76) U23.AJ29 v4(51.98,50.96) U23.AK30 v4(51.18,50.16) U23.AL31 v4(50.38,49.36) ; U23.C14 v4(73.58,63.76) ; U23.L17 U23.M18 v4(66.38,59.76) U23.L19 v4(67.18,58.96) U23.K20 v4(67.98,58.16) U23.J21 v4(68.78,57.36) U23.H22 v4(69.58,56.56) U23.G23 v4(70.38,55.76) U23.F24 v4(71.18,54.96) ; U23.L17 v4(67.18,61.36) U23.K16 v4(67.98,62.16) U23.J15 v4(68.78,62.96) U23.H14 v4(69.58,63.76) U23.G13 v4(70.38,64.56) U23.F12 v4(71.18,65.36) ; U23.L17 U23.K18 v4(67.98,59.76) U23.J19 v4(68.78,58.96) U23.H20 v4(69.58,58.16) U23.G21 v4(70.38,57.36) U23.F22 v4(71.18,56.56) ; v4(71.18,66.96) U23.F10 v4(70.38,66.16) U23.G11 v4(69.58,65.36) U23.H12 v4(68.78,64.56) U23.J13 v4(67.98,63.76) U23.K14 v4(67.18,62.96) U23.L15 v4(66.38,62.16) U23.M16 v4(65.58,61.36) U23.N17 U23.P18 v4(64.78,59.76) U23.N19 v4(65.58,58.96) U23.M20 v4(66.38,58.16) U23.L21 v4(67.18,57.36) U23.K22 v4(67.98,56.56) U23.J23 v4(68.78,55.76) U23.H24 v4(69.58,54.96) U23.G25 v4(70.38,54.16) U23.F26 v4(71.18,53.36) ; R218.2 v3(143.13,53.75) ; v4(50.38,51.76) U23.AL28 v4(51.18,52.56) U23.AK27 ; v2(28.32,39.37) C191.2 C190.1 ; v2(150.57,133.2) 150.69,133.31 OSC1.2 ; U23.AN22 v4(48.61,56.96) ; U23.D25 v4(72.78,54.16) ; v4(55.98,51.76) U23.AD28 v4(56.78,52.56) U23.AC27 v4(57.58,53.36) U23.AB26 v4(58.38,54.16) U23.AA25 v4(59.18,54.96) U23.Y24 v4(59.98,55.76) U23.W23 v4(60.78,56.56) U23.V22 U23.U21 v4(62.38,57.36) U23.T22 v4(63.18,56.56) U23.R23 v4(63.98,55.76) U23.P24 v4(64.78,54.96) U23.N25 v4(65.58,54.16) U23.M26 v4(66.38,53.36) U23.L27 v4(67.18,52.56) U23.K28 v4(67.98,51.76) ; U23.AH26 v4(52.78,53.36) ; U10.21 v7(55.19,111.02) ; R240.1 85.55,36.75 v4(85.24,36.44) ; C39.2 89.14,102.55 88.42,101.83 v2(88.02,101.83) 87.8,102.05 C40.2 ; v2(28.57,26.45) 28.7,26.45 28.73,26.47 C237.1 C236.2 ; U23.AK9 v4(51.18,67.76) ; B2.2 B1.2 90.25,105.03 90.63,104.64 v2(90.63,104.24) ; v4(67.98,66.96) U23.K10 v4(67.18,66.16) U23.L11 v4(66.38,65.36) U23.M12 v4(65.58,64.56) U23.N13 v4(64.78,63.76) U23.P14 v4(63.98,62.96) U23.R15 v4(63.18,62.16) U23.T16 v4(62.38,61.36) U23.U17 U23.V16 v4(60.78,62.16) U23.W15 v4(59.98,62.96) U23.Y14 v4(59.18,63.76) U23.AA13 v4(58.38,64.56) U23.AB12 v4(57.58,65.36) U23.AC11 v4(56.78,66.16) U23.AD10 v4(55.98,66.96) U23.AE9 v4(55.18,67.76) U23.AF8 v4(54.38,68.56) U23.AG7 v4(53.58,69.36) ; v4(71.18,62.16) U23.F16 v4(70.38,61.36) U23.G17 U23.F18 v4(71.18,59.76) ; R212.1 v3(158.9,66.85) ; C6.2 v2(169.34,139.45) ; U23.N32 v4(65.58,48.56) ; U23.AM1 v4(49.58,74.16) ; U23.C23 v4(73.58,55.76) ; U23.AM21 v4(49.58,58.16) ; U23.D31 v4(72.78,49.36) ; U32.2 v3(156.72,34.67) ; CN3.9 v3(107.19,136.14) ; v4(50.38,59.76) U23.AM18 ; U23.U11 v4(62.38,66.16) U23.T10 v4(63.18,66.96) U23.R9 v4(63.98,67.76) U23.P8 v4(64.78,68.56) U23.N7 v4(65.58,69.36) ; U23.AM30 v4(49.58,50.16) U23.AN31 v4(48.78,49.36) ; C849.2 v1(58.37,7.24) ; Q3.2 v2(175.83,128.14) ; U23.AN19 v4(48.61,59.36) ; C47.2 v2(70.57,101.09) C49.2 ; U21.4 v2(22.35,81.79) ; U23.Y28 v4(59.98,52.56) ; U23.C9 v4(73.58,67.76) ; v4(51.98,67.76) U23.AJ9 v4(52.78,66.96) U23.AH10 v4(53.58,66.16) U23.AG11 v4(54.38,65.36) U23.AF12 v4(55.18,64.56) U23.AE13 v4(55.98,63.76) U23.AD14 v4(56.78,62.96) U23.AC15 v4(57.58,62.16) U23.AB16 v4(58.38,61.36) U23.AA17 U23.Y18 v4(59.18,59.76) U23.AA19 v4(58.38,58.96) U23.AB20 v4(57.58,58.16) U23.AC21 v4(56.78,57.36) U23.AD22 v4(55.98,56.56) U23.AE23 v4(55.18,55.76) U23.AF24 v4(54.38,54.96) U23.AG25 ; v6(59.92,35.79) 59.46,36.25 TP52.1 ; RST_BMC1.1 120.24,143.52 v2(120.7,143.05) ; v4(50.38,58.96) U23.AL19 v4(51.18,59.76) U23.AK18 ; v7(46.36,118.6) 46.35,118.62 GND4.1 ; v4(71.18,51.76) U23.F28 v4(70.38,52.56) U23.G27 v4(69.58,53.36) U23.H26 v4(68.78,54.16) U23.J25 v4(67.98,54.96) U23.K24 v4(67.18,55.76) U23.L23 v4(66.38,56.56) U23.M22 v4(65.58,57.36) U23.N21 v4(64.78,58.16) U23.P20 v4(63.98,58.96) U23.R19 v4(63.18,59.76) U23.T18 U23.R17 v4(63.98,61.36) U23.P16 v4(64.78,62.16) U23.N15 v4(65.58,62.96) U23.M14 v4(66.38,63.76) U23.L13 v4(67.18,64.56) U23.K12 v4(67.98,65.36) U23.J11 v4(68.78,66.16) U23.H10 v4(69.58,66.96) U23.G9 v4(70.38,67.76) U23.F8 v4(71.18,68.56) ; U23.AL16 v4(50.38,62.16) ; v2(43.52,37.86) 43.52,36.87 44.39,36 R231.2 C202.1 C201.2 C200.2 ; v2(24.54,28.79) 24.51,28.77 GND1.1 ; C98.2 v2(12.76,76.89) ; v4(56.78,69.36) U23.AC7 v4(57.58,68.56) U23.AB8 v4(58.38,67.76) U23.AA9 v4(59.18,66.96) U23.Y10 v4(59.98,66.16) U23.W11 v4(60.78,65.36) U23.V12 U23.U13 v4(62.38,64.56) U23.T12 v4(63.18,65.36) U23.R11 v4(63.98,66.16) U23.P10 v4(64.78,66.96) U23.N9 v4(65.58,67.76) U23.M8 v4(66.38,68.56) U23.L7 v4(67.18,69.36) ; R68.1 v1(89.28,121.16) ; v2(89.41,101.82) 89.14,101.55 C48.2 C46.2 ; U23.AK6 v4(51.18,70.16) ; U23.D11 v4(72.78,66.16) ; U23.AN4 v4(48.61,71.36) ; C232.1 C231.2 38.48,26.15 v2(38.65,25.98) ; v4(57.58,51.76) U23.AB28 v4(58.38,52.56) U23.AA27 v4(59.18,53.36) U23.Y26 v4(59.98,54.16) U23.W25 v4(60.78,54.96) U23.V24 U23.U23 v4(62.38,55.76) U23.T24 v4(63.18,54.96) U23.R25 v4(63.98,54.16) U23.P26 v4(64.78,53.36) U23.N27 v4(65.58,52.56) U23.M28 v4(66.38,51.76) ; v2(97.47,108.22) 97.04,108.66 EMU1.H5 ; U23.U27 U23.V28 v4(60.78,51.76) ; U23.U27 v4(62.38,52.56) U23.T28 v4(63.18,51.76) ; U23.AF18 v4(54.38,59.76) U23.AG19 v4(53.58,58.96) U23.AH20 v4(52.78,58.16) U23.AJ21 v4(51.98,57.36) ; C35.2 v2(54.69,105.44) ; U23.AN10 v4(48.61,66.56) ; U23.AA4 v4(58.38,71.76) ; C97.2 v2(23.44,77.02) ; v2(28.23,30.73) C223.2 C221.2 ; v4(71.18,58.16) U23.F20 v4(70.38,58.96) U23.G19 v4(69.58,59.76) U23.H18 U23.J17 v4(68.78,61.36) U23.H16 v4(69.58,62.16) U23.G15 v4(70.38,62.96) U23.F14 v4(71.18,63.76) ; U23.AM24 v4(49.58,55.76) ; U23.A1 v4(75.18,74.16) ; U23.V1 v4(61.18,74.33) ; v4(54.38,51.76) U23.AF28 v4(55.18,52.56) U23.AE27 v4(55.98,53.36) U23.AD26 v4(56.78,54.16) U23.AC25 v4(57.58,54.96) U23.AB24 v4(58.38,55.76) U23.AA23 v4(59.18,56.56) U23.Y22 v4(59.98,57.36) U23.W21 v4(60.78,58.16) U23.V20 U23.U19 v4(62.38,58.96) ; U23.U25 v4(62.38,54.16) U23.T26 v4(63.18,53.36) U23.R27 v4(63.98,52.56) U23.P28 v4(64.78,51.76) ; U23.AN1 v4(48.78,74.16) ; GND2.1 155.57,44.86 v3(155.52,44.81) ; U23.C27 v4(73.58,52.56) ; v3(159.56,61.06) 159.77,61.26 TP48.1 ; U23.AE32 v4(55.18,48.56) ; U23.AN7 v4(48.61,68.96) ; C198.2 C199.1 v2(50.42,35.28) ; C213.1 C218.2 29.27,33.29 v2(28.18,32.2) ; U23.AN25 v4(48.61,54.56) ; U23.AA32 v4(58.38,48.56) ; v4(67.18,67.76) U23.L9 v4(66.38,66.96) U23.M10 v4(65.58,66.16) U23.N11 v4(64.78,65.36) U23.P12 v4(63.98,64.56) U23.R13 v4(63.18,63.76) U23.T14 v4(62.38,62.96) U23.U15 U23.V14 v4(60.78,63.76) U23.W13 v4(59.98,64.56) U23.Y12 v4(59.18,65.36) U23.AA11 v4(58.38,66.16) U23.AB10 v4(57.58,66.96) U23.AC9 v4(56.78,67.76) U23.AD8 v4(55.98,68.56) ; U23.AM27 v4(49.58,53.36) ; v2(25.53,39.19) C193.2 C192.2 ; R230.2 C197.2 52.89,36 v2(52.25,35.36) ; U23.W2 v4(59.98,73.36) ; v2(169.34,137.92) C7.2 ; v4(71.18,50.16) U23.F30 v4(70.38,50.96) U23.G29 v4(69.58,51.76) U23.H28 v4(68.78,52.56) U23.J27 ; U23.AJ13 v4(51.98,64.56) ; R24.2 v3(106.42,130.79) ; CN3.5 v3(104.65,136.14) ; U23.AN28 v4(48.61,52.16) ; C105.2 v3(151.69,76.15) ; U23.R1 v4(63.58,74.33) ; U26.2 v2(165.99,54.74) ; U23.AM15 v4(49.58,62.96) ; U23.H8 v4(69.58,68.56) U23.G7 v4(70.38,69.36) U23.F6 v4(71.18,70.16) ; U23.A33 v4(75.18,47.76) ; U23.C5 v4(73.58,70.96) ; v4(51.18,72.56) U23.AK3 v4(51.98,71.76) U23.AJ4 ; U23.AN16 v4(48.61,61.76) ; U23.D21 v4(72.78,57.36) ; U23.AD5 v4(55.98,70.96) ; U6.21 v7(55.19,117.93) ; U9.25 v2(112.93,107.54) ; C234.2 C235.2 v2(32.89,25.68) ; U23.AL13 v4(50.38,64.56) U23.AM12 v4(49.58,65.36) ; R216.1 v3(140.03,60.53) ; C41.2 v2(70.57,102.62) C38.2 ; U23.G31 v4(70.38,49.36) ; U23.AJ6 v4(51.98,70.16) ; Q5.2 v2(175.7,118.36) ; U23.AN33 v4(48.78,47.76) ; U23.AK12 v4(51.18,65.36) ; U23.U7 v4(62.38,69.36) ; C156.2 v2(158.7,49.48) ; v3(106.42,135.32) C11.2 ; U23.D17 v4(72.78,61.36) ; C12.1 v3(99.44,131.78) ; J5.12 v3(167,83.95) ; TP38.1 v2(141.25,89.46) ; C149.2 v3(146.2,51.89) ; C3.2 v2(165.61,141.68) ; J5.8 v3(167,86.49) ; U23.C19 v4(73.58,58.96) ; C148.2 v3(149.99,53.56)
  TOP w0.483: v3(8.56,54.75) AMC1.67 ; v3(8.56,14.25) AMC1.13 ; v3(8.56,61.5) AMC1.76 ; v3(8.56,32.25) AMC1.37 ; v3(8.56,25.5) AMC1.28 ; v3(8.56,67.92) 8.23,68.25 AMC1.85 ; v3(8.56,63.75) AMC1.79 ; v3(8.56,39) AMC1.46 ; v3(8.56,18.75) AMC1.19 ; v3(8.56,43.5) AMC1.52 ; v3(8.56,9.75) AMC1.7 ; AMC1.49 v3(8.56,41.25) ; v3(8.56,36.75) AMC1.43 ; 6.65,5.25 8.98,5.25 9.4,5.66 v3(9.4,5.71) ; v3(8.56,30) AMC1.34 ; v3(8.56,16.5) AMC1.16 ; v3(8.56,66) AMC1.82 ; v3(8.56,27.75) AMC1.31 ; v3(8.56,57) AMC1.70 ; v3(8.56,23.25) AMC1.25 ; v3(8.56,48) AMC1.58 ; v3(8.56,52.5) AMC1.64 ; v3(8.56,45.75) AMC1.55 ; v3(8.56,12) AMC1.10 ; v3(8.56,21) AMC1.22 ; v3(8.56,59.25) AMC1.73 ; v3(8.56,34.5) AMC1.40 ; v3(8.56,50.25) AMC1.61
  TOP w0.508: v2(37.26,134.93) 37.71,134.93 37.93,134.72 CN7.H9 ; v2(68.17,88.16) 67.61,88.73 C66.2 65.39,88.73 v2(65.1,88.44) 64.76,88.78 C64.2 62.62,88.78 v2(62,88.16) 61.52,88.65 C65.2 59.74,88.65 v2(59.23,88.14) 58.89,88.48 C62.2 58.2,88.48 v2(57.81,88.09) 57.42,88.48 C63.2 ; 6.65,5.25 AMC1.1 ; C208.2 v1(128.98,35.89) ; v2(37.1,124.57) 37.38,124.57 37.93,124.02 CN7.H7 v2(37.93,119.2) CN7.H10 ; v2(38.62,129.73) 38.02,129.73 37.93,129.63 CN7.H8 ; v6(163.45,97.78) 163.45,97.64 v2(164.26,96.82) ; C269.2 v1(127.03,12.26) ; CN7.H5 v2(37.93,111.4) ; D10.2 v2(47.26,26.9) ; CN7.H6 v2(37.93,95.37) ; CN7.H3 37.93,99.34 v2(37.94,99.33)
  TOP w0.635: CN7.H4 37.93,109.16 37.93,109.17 37.93,109.81 37.93,109.82 v2(37.93,111.4)
  TOP w0.889: 97.33,12.01 98.83,12.01
  L2_GND1 w0.381: 19.97,117.03 J2.GF3 19.97,116.17 ; 173.93,77.51 RST_ATTN1.2 ; RST_ATTN1.2 175.42,78.99 ; RST_ATTN1.2 175.42,77.51 ; RST_ATTN1.2 173.93,78.99 ; 24.45,93.65 J4.GH4 ; J4.GH4 24.45,94.55 ; J4.GH4 25.35,94.55 ; J4.GH4 25.35,93.65 ; J3.5 172.55,103.65 ; J3.5 170.5,102.15 ; J3.5 170.5,103.65 ; 8.42,128.16 J2.GA7 8.42,127.12 ; J2.GH5 25.35,121.15 ; J2.GH5 25.35,122.05 ; J2.GH5 24.45,122.05 ; J2.GH5 24.45,121.15 ; 24.45,109.55 J4.GH10 ; J4.GH10 25.35,109.55 ; J4.GH10 25.35,108.65 ; J4.GH10 24.45,108.65 ; 17.23,97.03 J4.GE5 17.23,96.17 ; 21.73,129.53 J2.GG8 21.73,128.67 ; 10.97,109.53 J4.GB10 10.97,108.67 ; 62.31,146.27 LCD1.11 ; LCD1.11 62.31,145.05 ; LCD1.11 63.52,145.05 ; LCD1.11 63.52,146.27 ; 18.3,22.53 J8.2 ; J8.2 18.3,23.95 ; J8.2 19.71,23.95 ; J8.2 19.71,22.53 ; 12.73,94.53 J4.GC4 12.73,93.67 ; 17.23,113.67 J2.GE2 17.23,114.53 ; J2.GH2 25.35,114.55 ; J2.GH2 24.45,114.55 ; J2.GH2 25.35,113.65 ; J2.GH2 24.45,113.65 ; 129.36,124.53 PMBUS1.5 ; PMBUS1.5 130.74,125.91 ; PMBUS1.5 130.74,124.53 ; PMBUS1.5 129.36,125.91 ; J2.GH3 25.35,117.05 ; J2.GH3 24.45,116.15 ; J2.GH3 25.35,116.15 ; J2.GH3 24.45,117.05 ; 19.97,118.67 J2.GF4 19.97,119.53 ; 10.97,111.17 J2.GB1 10.97,112.03 ; 15.47,133.67 J2.GD10 15.47,134.53 ; J2.GH1 25.35,111.15 ; J2.GH1 24.45,111.15 ; J2.GH1 24.45,112.05 ; J2.GH1 25.35,112.05 ; 12.73,128.67 J2.GC8 12.73,129.53 ; RST_PWR1.2 177.35,91.57 ; RST_PWR1.2 177.35,90.18 ; RST_PWR1.2 175.95,91.57 ; RST_PWR1.2 175.95,90.18 ; 21.73,106.17 J4.GG9 21.73,107.03 ; CN7.H12 39.61,137.89 ; CN7.H12 36.24,137.89 ; CN7.H12 39.61,141.26 ; CN7.H12 36.24,141.26 ; J8.3 19.71,19.99 ; J8.3 18.3,21.41 ; J8.3 19.71,21.41 ; J8.3 18.3,19.99 ; 166.08,45.16 J7.4 ; J7.4 166.08,44.09 ; J7.4 167.15,44.09 ; J7.4 167.15,45.16 ; 17.23,93.67 J4.GE4 17.23,94.53 ; 24.45,106.15 J4.GH9 ; J4.GH9 24.45,107.05 ; J4.GH9 25.35,106.15 ; J4.GH9 25.35,107.05 ; 17.23,118.67 J2.GE4 17.23,119.53 ; 10.97,102.03 J4.GB7 10.97,101.17 ; 12.73,132.03 J2.GC9 12.73,131.17 ; 136.38,122.48 CN4.2 ; CN4.2 137.79,122.48 ; CN4.2 137.79,123.9 ; CN4.2 136.38,123.9 ; 21.73,113.67 J2.GG2 21.73,114.53 ; 8.42,123.16 J2.GA5 8.42,122.12 ; 17.23,99.53 J4.GE6 17.23,98.67 ; 138.74,119.71 CN6.3 ; CN6.3 138.74,118.29 ; CN6.3 140.15,119.71 ; TP14.1 108.41,119.17 ; TP14.1 108.41,120.6 ; TP14.1 106.98,119.17 ; TP14.1 106.98,120.6 ; 10.97,103.67 J4.GB8 10.97,104.53 ; 24.45,91.15 J4.GH3 ; J4.GH3 25.35,92.05 ; J4.GH3 24.45,92.05 ; J4.GH3 25.35,91.15 ; 17.23,129.53 J2.GE8 17.23,128.67 ; 170.5,138.86 J1.5 ; J1.5 170.5,137.36 ; J1.5 172.55,138.86 ; 157.75,140.26 CN1.3 ; CN1.3 159.16,141.68 ; CN1.3 157.75,141.68 ; CN1.3 159.16,140.26 ; 19.97,126.17 J2.GF7 19.97,127.03 ; 164.58,41.66 J7.7 ; J7.7 165.65,41.66 ; J7.7 165.65,40.59 ; J7.7 164.58,40.59 ; 16.4,11.29 J11.2 ; J11.2 20.36,9.33 ; J11.2 20.36,11.29 ; 10.97,99.53 J4.GB6 10.97,98.67 ; J4.GH7 25.35,101.15 ; J4.GH7 25.35,102.05 ; J4.GH7 24.45,102.05 ; J4.GH7 24.45,101.15 ; 24.45,134.55 J2.GH10 ; J2.GH10 25.35,134.55 ; J2.GH10 24.45,133.65 ; J2.GH10 25.35,133.65 ; J2.GH6 25.35,124.55 ; J2.GH6 25.35,123.65 ; J2.GH6 24.45,124.55 ; J2.GH6 24.45,123.65 ; 15.47,123.67 J2.GD6 15.47,124.53 ; 8.42,94.62 J4.GA4 8.42,95.66 ; 12.73,127.03 J2.GC7 12.73,126.17 ; 24.45,131.15 J2.GH9 ; J2.GH9 25.35,131.15 ; J2.GH9 24.45,132.05 ; J2.GH9 25.35,132.05 ; 21.73,89.53 J4.GG2 21.73,88.67 ; 12.73,113.67 J2.GC2 12.73,114.53 ; 8.42,88.16 J4.GA1 8.42,87.12 ; J4.GH2 25.35,88.65 ; J4.GH2 24.45,89.55 ; J4.GH2 24.45,88.65 ; J4.GH2 25.35,89.55 ; 24.45,129.55 J2.GH8 ; J2.GH8 25.35,129.55 ; J2.GH8 25.35,128.65 ; J2.GH8 24.45,128.65 ; 10.97,94.53 J4.GB4 10.97,93.67 ; 12.73,101.17 J4.GC7 12.73,102.03 ; 15.47,131.17 J2.GD9 15.47,132.03 ; 158.12,119.51 158.82,120.21 ; 158.12,119.51 157.41,118.8 ; 158.12,119.51 158.82,118.8 ; 158.12,119.51 157.41,120.21 ; 19.97,97.03 J4.GF5 19.97,96.17 ; 21.73,103.67 J4.GG8 21.73,104.53 ; 12.73,104.53 J4.GC8 12.73,103.67 ; 17.23,123.67 J2.GE6 17.23,124.53 ; 17.23,112.03 J2.GE1 17.23,111.17 ; 21.73,121.17 J2.GG5 21.73,122.03 ; 15.47,98.67 J4.GD6 15.47,99.53 ; 15.47,88.67 J4.GD2 15.47,89.53 ; 19.97,99.53 J4.GF6 19.97,98.67 ; 13.15,10.29 J11.3 ; J11.3 16.61,8.33 ; J11.3 13.15,8.33 ; 174.3,136.56 J1.4 174.3,138.06 ; 24.45,87.05 J4.GH1 ; J4.GH1 25.35,86.15 ; J4.GH1 25.35,87.05 ; J4.GH1 24.45,86.15 ; 19.97,131.17 J2.GF9 19.97,132.03 ; 19.97,108.67 J4.GF10 19.97,109.53 ; 21.73,111.17 J2.GG1 21.73,112.03 ; 24.45,98.65 J4.GH6 ; J4.GH6 24.45,99.55 ; J4.GH6 25.35,99.55 ; J4.GH6 25.35,98.65 ; 8.42,135.66 J2.GA10 8.42,134.62 ; 24.45,96.15 J4.GH5 ; J4.GH5 25.35,97.05 ; J4.GH5 25.35,96.15 ; J4.GH5 24.45,97.05 ; 10.97,131.17 J2.GB9 10.97,132.03 ; 8.42,99.62 J4.GA6 8.42,100.66 ; 19.97,111.17 J2.GF1 19.97,112.03 ; 17.23,103.67 J4.GE8 17.23,104.53 ; 10.97,128.67 J2.GB8 10.97,129.53 ; 82.43,28.88 FAN1.1 ; FAN1.1 83.84,28.88 ; FAN1.1 82.43,30.29 ; FAN1.1 83.84,30.29 ; 8.42,124.62 J2.GA6 8.42,125.66 ; 10.97,127.03 J2.GB7 10.97,126.17 ; 12.73,108.67 J4.GC10 12.73,109.53 ; 17.23,116.17 J2.GE3 17.23,117.03 ; J2.GH4 25.35,118.65 ; J2.GH4 25.35,119.55 ; J2.GH4 24.45,118.65 ; J2.GH4 24.45,119.55 ; 8.42,118.16 J2.GA3 8.42,117.12 ; 15.47,96.17 J4.GD5 15.47,97.03 ; 8.42,105.66 J4.GA8 8.42,104.62 ; 21.73,108.67 J4.GG10 21.73,109.53 ; 17.23,89.53 J4.GE2 17.23,88.67 ; 17.23,131.17 J2.GE9 17.23,132.03 ; 17.23,109.53 J4.GE10 17.23,108.67 ; 8.42,108.16 J4.GA9 8.42,107.12 ; 167.06,119.51 167.76,118.8 ; 167.06,119.51 166.35,120.21 ; 167.06,119.51 167.76,120.21 ; 167.06,119.51 166.35,118.8 ; 15.47,127.03 J2.GD7 15.47,126.17 ; 15.47,86.17 J4.GD1 15.47,87.03 ; 24.45,104.55 J4.GH8 ; J4.GH8 25.35,104.55 ; J4.GH8 24.45,103.65 ; J4.GH8 25.35,103.65 ; 21.73,118.67 J2.GG4 21.73,119.53 ; 21.73,101.17 J4.GG7 21.73,102.03 ; 19.97,94.53 J4.GF4 19.97,93.67 ; 15.47,91.17 J4.GD3 15.47,92.03 ; 8.42,129.62 J2.GA8 8.42,130.66 ; 21.73,98.67 J4.GG6 21.73,99.53 ; 19.97,123.67 J2.GF6 19.97,124.53 ; 21.73,132.03 J2.GG9 21.73,131.17 ; 12.73,117.03 J2.GC3 12.73,116.17 ; 8.42,113.16 J2.GA1 8.42,112.12 ; 10.97,86.17 J4.GB1 10.97,87.03 ; 10.97,124.53 J2.GB6 10.97,123.67 ; 15.47,104.53 J4.GD8 15.47,103.67 ; 12.73,98.67 J4.GC6 12.73,99.53 ; 19.97,91.17 J4.GF3 19.97,92.03 ; 8.42,90.66 J4.GA2 8.42,89.62 ; 8.42,114.62 J2.GA2 8.42,115.66 ; 12.73,122.03 J2.GC5 12.73,121.17 ; 15.47,109.53 J4.GD10 15.47,108.67 ; J2.GH7 25.35,127.05 ; J2.GH7 24.45,127.05 ; J2.GH7 24.45,126.15 ; J2.GH7 25.35,126.15 ; 15.47,122.03 J2.GD5 15.47,121.17 ; 10.97,118.67 J2.GB4 10.97,119.53 ; LCD1.K 49.9,142.9 ; LCD1.K 47.33,142.9 ; LCD1.K 47.33,144.53 ; LCD1.K 49.9,144.53 ; 15.47,118.67 J2.GD4 15.47,119.53 ; 10.97,107.03 J4.GB9 10.97,106.17 ; 10.97,113.67 J2.GB2 10.97,114.53 ; 12.73,118.67 J2.GC4 12.73,119.53 ; 8.42,132.12 J2.GA9 8.42,133.16 ; 19.97,101.17 J4.GF7 19.97,102.03 ; 12.73,123.67 J2.GC6 12.73,124.53 ; 12.73,87.03 J4.GC1 12.73,86.17 ; 8.42,119.62 J2.GA4 8.42,120.66 ; 19.97,133.67 J2.GF10 19.97,134.53 ; 10.97,92.03 J4.GB3 10.97,91.17 ; 15.47,102.03 J4.GD7 15.47,101.17 ; 10.97,121.17 J2.GB5 10.97,122.03 ; 15.47,107.03 J4.GD9 15.47,106.17 ; 10.97,89.53 J4.GB2 10.97,88.67 ; 17.23,102.03 J4.GE7 17.23,101.17 ; 12.73,134.53 J2.GC10 12.73,133.67 ; 19.97,121.17 J2.GF5 19.97,122.03 ; 17.23,86.17 J4.GE1 17.23,87.03 ; 8.42,102.12 J4.GA7 8.42,103.16 ; 21.73,134.53 J2.GG10 21.73,133.67 ; 15.47,93.67 J4.GD4 15.47,94.53 ; 19.97,86.17 J4.GF1 19.97,87.03 ; 12.73,96.17 J4.GC5 12.73,97.03 ; 12.73,89.53 J4.GC2 12.73,88.67 ; 19.97,113.67 J2.GF2 19.97,114.53 ; 19.97,106.17 J4.GF9 19.97,107.03 ; 10.97,134.53 J2.GB10 10.97,133.67 ; 21.73,123.67 J2.GG6 21.73,124.53 ; 21.73,91.17 J4.GG3 21.73,92.03 ; 17.23,126.17 J2.GE7 17.23,127.03 ; 21.73,117.03 J2.GG3 21.73,116.17 ; 15.47,129.53 J2.GD8 15.47,128.67 ; 17.23,92.03 J4.GE3 17.23,91.17 ; 17.23,107.03 J4.GE9 17.23,106.17 ; 36.24,89.23 CN7.H11 ; CN7.H11 39.61,92.6 ; CN7.H11 36.24,92.6 ; CN7.H11 39.61,89.23 ; 8.42,92.12 J4.GA3 8.42,93.16 ; 8.42,110.66 J4.GA10 8.42,109.62 ; 21.73,93.67 J4.GG4 21.73,94.53 ; 17.23,122.03 J2.GE5 17.23,121.17 ; 12.73,92.03 J4.GC3 12.73,91.17 ; 15.47,117.03 J2.GD3 15.47,116.17 ; 21.73,127.03 J2.GG7 21.73,126.17 ; 15.47,114.53 J2.GD2 15.47,113.67 ; 10.97,116.17 J2.GB3 10.97,117.03 ; 19.97,103.67 J4.GF8 19.97,104.53 ; 8.42,97.12 J4.GA5 8.42,98.16 ; 19.97,128.67 J2.GF8 19.97,129.53 ; 12.73,106.17 J4.GC9 12.73,107.03 ; 15.47,111.17 J2.GD1 15.47,112.03 ; 19.97,89.53 J4.GF2 19.97,88.67 ; 12.73,111.17 J2.GC1 12.73,112.03 ; 21.73,96.17 J4.GG5 21.73,97.03 ; 17.23,134.53 J2.GE10 17.23,133.67 ; 10.97,97.03 J4.GB5 10.97,96.17 ; 21.73,86.17 J4.GG1 21.73,87.03
  L6_GND2 w0.381: 15.47,117.03 J2.GD3 15.47,116.17 ; 19.97,118.67 J2.GF4 19.97,119.53 ; 10.97,98.67 J4.GB6 10.97,99.53 ; 8.42,100.66 J4.GA6 8.42,99.62 ; 10.97,91.17 J4.GB3 10.97,92.03 ; J4.GH9 25.35,107.05 ; J4.GH9 24.45,107.05 ; J4.GH9 24.45,106.15 ; J4.GH9 25.35,106.15 ; FAN1.1 83.84,28.88 ; FAN1.1 82.43,30.29 ; FAN1.1 83.84,30.29 ; FAN1.1 82.43,28.88 ; CN7.H12 39.61,141.26 ; CN7.H12 39.61,137.89 ; CN7.H12 36.24,141.26 ; CN7.H12 36.24,137.89 ; 21.73,118.67 J2.GG4 21.73,119.53 ; 8.42,117.12 J2.GA3 8.42,118.16 ; J4.GH5 25.35,96.15 ; J4.GH5 24.45,97.05 ; J4.GH5 25.35,97.05 ; J4.GH5 24.45,96.15 ; 166.35,120.21 167.06,119.51 ; 167.06,119.51 166.35,118.8 ; 167.06,119.51 167.76,118.8 ; 167.06,119.51 167.76,120.21 ; 21.73,128.67 J2.GG8 21.73,129.53 ; 15.47,132.03 J2.GD9 15.47,131.17 ; 173.93,78.99 RST_ATTN1.2 ; RST_ATTN1.2 175.42,78.99 ; RST_ATTN1.2 173.93,77.51 ; RST_ATTN1.2 175.42,77.51 ; 8.42,93.16 J4.GA3 8.42,92.12 ; J4.GH10 25.35,108.65 ; J4.GH10 25.35,109.55 ; J4.GH10 24.45,109.55 ; J4.GH10 24.45,108.65 ; 10.97,131.17 J2.GB9 10.97,132.03 ; 19.97,114.53 J2.GF2 19.97,113.67 ; 24.45,119.55 J2.GH4 ; J2.GH4 24.45,118.65 ; J2.GH4 25.35,118.65 ; J2.GH4 25.35,119.55 ; 8.42,114.62 J2.GA2 8.42,115.66 ; 10.97,129.53 J2.GB8 10.97,128.67 ; 10.97,126.17 J2.GB7 10.97,127.03 ; 10.97,108.67 J4.GB10 10.97,109.53 ; 12.73,94.53 J4.GC4 12.73,93.67 ; 15.47,133.67 J2.GD10 15.47,134.53 ; 21.73,131.17 J2.GG9 21.73,132.03 ; 19.97,128.67 J2.GF8 19.97,129.53 ; J4.GH8 25.35,104.55 ; J4.GH8 24.45,103.65 ; J4.GH8 24.45,104.55 ; J4.GH8 25.35,103.65 ; J2.GH7 25.35,126.15 ; J2.GH7 24.45,127.05 ; J2.GH7 24.45,126.15 ; J2.GH7 25.35,127.05 ; 24.45,116.15 J2.GH3 ; J2.GH3 25.35,117.05 ; J2.GH3 24.45,117.05 ; J2.GH3 25.35,116.15 ; 24.45,92.05 J4.GH3 ; J4.GH3 24.45,91.15 ; J4.GH3 25.35,92.05 ; J4.GH3 25.35,91.15 ; 21.73,127.03 J2.GG7 21.73,126.17 ; 62.31,146.27 LCD1.11 ; LCD1.11 62.31,145.05 ; LCD1.11 63.52,146.27 ; LCD1.11 63.52,145.05 ; PMBUS1.5 130.74,124.53 ; PMBUS1.5 129.36,124.53 ; PMBUS1.5 129.36,125.91 ; PMBUS1.5 130.74,125.91 ; 12.73,101.17 J4.GC7 12.73,102.03 ; 12.73,107.03 J4.GC9 12.73,106.17 ; 19.97,93.67 J4.GF4 19.97,94.53 ; 19.97,132.03 J2.GF9 19.97,131.17 ; 15.47,111.17 J2.GD1 15.47,112.03 ; 19.97,127.03 J2.GF7 19.97,126.17 ; 12.73,128.67 J2.GC8 12.73,129.53 ; 12.73,88.67 J4.GC2 12.73,89.53 ; 21.73,106.17 J4.GG9 21.73,107.03 ; 10.97,123.67 J2.GB6 10.97,124.53 ; 21.73,122.03 J2.GG5 21.73,121.17 ; 12.73,111.17 J2.GC1 12.73,112.03 ; J2.GH8 25.35,129.55 ; J2.GH8 24.45,128.65 ; J2.GH8 25.35,128.65 ; J2.GH8 24.45,129.55 ; 17.23,96.17 J4.GE5 17.23,97.03 ; 10.97,94.53 J4.GB4 10.97,93.67 ; 12.73,98.67 J4.GC6 12.73,99.53 ; 15.47,102.03 J4.GD7 15.47,101.17 ; 19.97,117.03 J2.GF3 19.97,116.17 ; 17.23,103.67 J4.GE8 17.23,104.53 ; 19.97,102.03 J4.GF7 19.97,101.17 ; 21.73,109.53 J4.GG10 21.73,108.67 ; LCD1.K 49.9,142.9 ; LCD1.K 47.33,142.9 ; LCD1.K 49.9,144.53 ; LCD1.K 47.33,144.53 ; 17.23,121.17 J2.GE5 17.23,122.03 ; 17.23,111.17 J2.GE1 17.23,112.03 ; 12.73,124.53 J2.GC6 12.73,123.67 ; 17.23,129.53 J2.GE8 17.23,128.67 ; 12.73,122.03 J2.GC5 12.73,121.17 ; 17.23,92.03 J4.GE3 17.23,91.17 ; 12.73,108.67 J4.GC10 12.73,109.53 ; J11.2 20.36,11.29 ; J11.2 20.36,9.33 ; J11.2 16.4,11.29 ; 19.97,123.67 J2.GF6 19.97,124.53 ; 17.23,114.53 J2.GE2 17.23,113.67 ; 170.5,103.65 J3.5 ; J3.5 172.55,103.65 ; J3.5 170.5,102.15 ; 15.47,86.17 J4.GD1 15.47,87.03 ; 36.24,92.6 CN7.H11 ; CN7.H11 36.24,89.23 ; CN7.H11 39.61,92.6 ; CN7.H11 39.61,89.23 ; 17.23,109.53 J4.GE10 17.23,108.67 ; 15.47,89.53 J4.GD2 15.47,88.67 ; 17.23,119.53 J2.GE4 17.23,118.67 ; 10.97,97.03 J4.GB5 10.97,96.17 ; 21.73,111.17 J2.GG1 21.73,112.03 ; 8.42,112.12 J2.GA1 8.42,113.16 ; 17.23,124.53 J2.GE6 17.23,123.67 ; 8.42,132.12 J2.GA9 8.42,133.16 ; 10.97,103.67 J4.GB8 10.97,104.53 ; 10.97,106.17 J4.GB9 10.97,107.03 ; RST_PWR1.2 177.35,90.18 ; RST_PWR1.2 175.95,90.18 ; RST_PWR1.2 177.35,91.57 ; RST_PWR1.2 175.95,91.57 ; 21.73,86.17 J4.GG1 21.73,87.03 ; 10.97,122.03 J2.GB5 10.97,121.17 ; 19.97,108.67 J4.GF10 19.97,109.53 ; 157.41,120.21 158.12,119.51 ; 158.12,119.51 158.82,120.21 ; 158.12,119.51 158.82,118.8 ; 158.12,119.51 157.41,118.8 ; 15.47,107.03 J4.GD9 15.47,106.17 ; 10.97,114.53 J2.GB2 10.97,113.67 ; 24.45,122.05 J2.GH5 ; J2.GH5 25.35,122.05 ; J2.GH5 24.45,121.15 ; J2.GH5 25.35,121.15 ; 8.42,109.62 J4.GA10 8.42,110.66 ; 21.73,96.17 J4.GG5 21.73,97.03 ; 12.73,87.03 J4.GC1 12.73,86.17 ; 15.47,94.53 J4.GD4 15.47,93.67 ; CN4.2 137.79,123.9 ; CN4.2 137.79,122.48 ; CN4.2 136.38,123.9 ; CN4.2 136.38,122.48 ; 17.23,117.03 J2.GE3 17.23,116.17 ; CN6.3 140.15,119.71 ; CN6.3 138.74,118.29 ; CN6.3 138.74,119.71 ; 8.42,130.66 J2.GA8 8.42,129.62 ; J4.GH2 25.35,88.65 ; J4.GH2 24.45,88.65 ; J4.GH2 25.35,89.55 ; J4.GH2 24.45,89.55 ; J4.GH7 25.35,101.15 ; J4.GH7 25.35,102.05 ; J4.GH7 24.45,102.05 ; J4.GH7 24.45,101.15 ; J8.2 19.71,23.95 ; J8.2 18.3,22.53 ; J8.2 19.71,22.53 ; J8.2 18.3,23.95 ; 24.45,99.55 J4.GH6 ; J4.GH6 24.45,98.65 ; J4.GH6 25.35,99.55 ; J4.GH6 25.35,98.65 ; 17.23,88.67 J4.GE2 17.23,89.53 ; 10.97,88.67 J4.GB2 10.97,89.53 ; 12.73,96.17 J4.GC5 12.73,97.03 ; 8.42,119.62 J2.GA4 8.42,120.66 ; 8.42,87.12 J4.GA1 8.42,88.16 ; 19.97,121.17 J2.GF5 19.97,122.03 ; 8.42,89.62 J4.GA2 8.42,90.66 ; J8.3 19.71,19.99 ; J8.3 18.3,21.41 ; J8.3 19.71,21.41 ; J8.3 18.3,19.99 ; J7.4 167.15,44.09 ; J7.4 166.08,45.16 ; J7.4 166.08,44.09 ; J7.4 167.15,45.16 ; 15.47,98.67 J4.GD6 15.47,99.53 ; 15.47,108.67 J4.GD10 15.47,109.53 ; 12.73,104.53 J4.GC8 12.73,103.67 ; 17.23,132.03 J2.GE9 17.23,131.17 ; 21.73,89.53 J4.GG2 21.73,88.67 ; 24.45,114.55 J2.GH2 ; J2.GH2 24.45,113.65 ; J2.GH2 25.35,114.55 ; J2.GH2 25.35,113.65 ; 21.73,103.67 J4.GG8 21.73,104.53 ; 19.97,112.03 J2.GF1 19.97,111.17 ; 17.23,102.03 J4.GE7 17.23,101.17 ; 21.73,117.03 J2.GG3 21.73,116.17 ; 8.42,135.66 J2.GA10 8.42,134.62 ; J4.GH4 25.35,94.55 ; J4.GH4 25.35,93.65 ; J4.GH4 24.45,94.55 ; J4.GH4 24.45,93.65 ; 24.45,132.05 J2.GH9 ; J2.GH9 25.35,131.15 ; J2.GH9 25.35,132.05 ; J2.GH9 24.45,131.15 ; 12.73,91.17 J4.GC3 12.73,92.03 ; 8.42,128.16 J2.GA7 8.42,127.12 ; 8.42,105.66 J4.GA8 8.42,104.62 ; 21.73,99.53 J4.GG6 21.73,98.67 ; 12.73,126.17 J2.GC7 12.73,127.03 ; J2.GH6 25.35,124.55 ; J2.GH6 24.45,123.65 ; J2.GH6 24.45,124.55 ; J2.GH6 25.35,123.65 ; 24.45,134.55 J2.GH10 ; J2.GH10 25.35,134.55 ; J2.GH10 24.45,133.65 ; J2.GH10 25.35,133.65 ; 10.97,111.17 J2.GB1 10.97,112.03 ; 19.97,92.03 J4.GF3 19.97,91.17 ; 15.47,114.53 J2.GD2 15.47,113.67 ; 21.73,101.17 J4.GG7 21.73,102.03 ; 15.47,128.67 J2.GD8 15.47,129.53 ; 15.47,97.03 J4.GD5 15.47,96.17 ; 19.97,106.17 J4.GF9 19.97,107.03 ; 21.73,134.53 J2.GG10 21.73,133.67 ; 10.97,134.53 J2.GB10 10.97,133.67 ; TP14.1 108.41,119.17 ; TP14.1 108.41,120.6 ; TP14.1 106.98,120.6 ; TP14.1 106.98,119.17 ; 10.97,116.17 J2.GB3 10.97,117.03 ; J4.GH1 25.35,87.05 ; J4.GH1 24.45,87.05 ; J4.GH1 24.45,86.15 ; J4.GH1 25.35,86.15 ; 174.3,136.56 J1.4 174.3,138.06 ; 19.97,98.67 J4.GF6 19.97,99.53 ; J1.5 172.55,138.86 ; J1.5 170.5,137.36 ; J1.5 170.5,138.86 ; 8.42,107.12 J4.GA9 8.42,108.16 ; 19.97,86.17 J4.GF1 19.97,87.03 ; 17.23,94.53 J4.GE4 17.23,93.67 ; 12.73,118.67 J2.GC4 12.73,119.53 ; 8.42,97.12 J4.GA5 8.42,98.16 ; 15.47,126.17 J2.GD7 15.47,127.03 ; 157.75,141.68 CN1.3 ; CN1.3 159.16,141.68 ; CN1.3 159.16,140.26 ; CN1.3 157.75,140.26 ; 12.73,116.17 J2.GC3 12.73,117.03 ; 10.97,118.67 J2.GB4 10.97,119.53 ; 17.23,134.53 J2.GE10 17.23,133.67 ; 21.73,94.53 J4.GG4 21.73,93.67 ; 12.73,134.53 J2.GC10 12.73,133.67 ; 10.97,102.03 J4.GB7 10.97,101.17 ; 19.97,88.67 J4.GF2 19.97,89.53 ; 12.73,131.17 J2.GC9 12.73,132.03 ; 15.47,119.53 J2.GD4 15.47,118.67 ; 21.73,113.67 J2.GG2 21.73,114.53 ; 8.42,95.66 J4.GA4 8.42,94.62 ; 21.73,92.03 J4.GG3 21.73,91.17 ; 8.42,122.12 J2.GA5 8.42,123.16 ; 24.45,111.15 J2.GH1 ; J2.GH1 25.35,112.05 ; J2.GH1 25.35,111.15 ; J2.GH1 24.45,112.05 ; 8.42,125.66 J2.GA6 8.42,124.62 ; 17.23,107.03 J4.GE9 17.23,106.17 ; J11.3 16.61,8.33 ; J11.3 13.15,8.33 ; J11.3 13.15,10.29 ; 21.73,124.53 J2.GG6 21.73,123.67 ; 19.97,104.53 J4.GF8 19.97,103.67 ; J7.7 165.65,40.59 ; J7.7 164.58,41.66 ; J7.7 165.65,41.66 ; J7.7 164.58,40.59 ; 12.73,114.53 J2.GC2 12.73,113.67 ; 15.47,124.53 J2.GD6 15.47,123.67 ; 10.97,86.17 J4.GB1 10.97,87.03 ; 15.47,103.67 J4.GD8 15.47,104.53 ; 19.97,96.17 J4.GF5 19.97,97.03 ; 17.23,99.53 J4.GE6 17.23,98.67 ; 19.97,134.53 J2.GF10 19.97,133.67 ; 15.47,92.03 J4.GD3 15.47,91.17 ; 17.23,126.17 J2.GE7 17.23,127.03 ; 15.47,121.17 J2.GD5 15.47,122.03 ; 17.23,87.03 J4.GE1 17.23,86.17 ; 8.42,103.16 J4.GA7 8.42,102.12
  L7_GND3 w0.381: PMBUS1.5 130.74,125.91 ; PMBUS1.5 130.74,124.53 ; PMBUS1.5 129.36,125.91 ; PMBUS1.5 129.36,124.53 ; 12.73,112.03 J2.GC1 12.73,111.17 ; 10.97,116.17 J2.GB3 10.97,117.03 ; J4.GH2 25.35,88.65 ; J4.GH2 24.45,88.65 ; J4.GH2 25.35,89.55 ; J4.GH2 24.45,89.55 ; 17.23,94.53 J4.GE4 17.23,93.67 ; 8.42,102.12 J4.GA7 8.42,103.16 ; 166.08,44.09 J7.4 ; J7.4 167.15,45.16 ; J7.4 166.08,45.16 ; J7.4 167.15,44.09 ; 10.97,112.03 J2.GB1 10.97,111.17 ; 21.73,93.67 J4.GG4 21.73,94.53 ; 17.23,113.67 J2.GE2 17.23,114.53 ; 24.45,109.55 J4.GH10 ; J4.GH10 25.35,109.55 ; J4.GH10 24.45,108.65 ; J4.GH10 25.35,108.65 ; 10.97,87.03 J4.GB1 10.97,86.17 ; 12.73,94.53 J4.GC4 12.73,93.67 ; 15.47,104.53 J4.GD8 15.47,103.67 ; 15.47,107.03 J4.GD9 15.47,106.17 ; 82.43,28.88 FAN1.1 ; FAN1.1 82.43,30.29 ; FAN1.1 83.84,30.29 ; FAN1.1 83.84,28.88 ; 21.73,97.03 J4.GG5 21.73,96.17 ; 15.47,98.67 J4.GD6 15.47,99.53 ; 10.97,124.53 J2.GB6 10.97,123.67 ; LCD1.11 63.52,146.27 ; LCD1.11 62.31,146.27 ; LCD1.11 63.52,145.05 ; LCD1.11 62.31,145.05 ; 17.23,118.67 J2.GE4 17.23,119.53 ; 10.97,97.03 J4.GB5 10.97,96.17 ; 24.45,118.65 J2.GH4 ; J2.GH4 25.35,119.55 ; J2.GH4 24.45,119.55 ; J2.GH4 25.35,118.65 ; J4.GH1 25.35,87.05 ; J4.GH1 25.35,86.15 ; J4.GH1 24.45,86.15 ; J4.GH1 24.45,87.05 ; 21.73,112.03 J2.GG1 21.73,111.17 ; J4.GH8 25.35,103.65 ; J4.GH8 25.35,104.55 ; J4.GH8 24.45,103.65 ; J4.GH8 24.45,104.55 ; J4.GH9 25.35,107.05 ; J4.GH9 24.45,106.15 ; J4.GH9 25.35,106.15 ; J4.GH9 24.45,107.05 ; 15.47,101.17 J4.GD7 15.47,102.03 ; 24.45,131.15 J2.GH9 ; J2.GH9 25.35,131.15 ; J2.GH9 25.35,132.05 ; J2.GH9 24.45,132.05 ; 8.42,98.16 J4.GA5 8.42,97.12 ; RST_ATTN1.2 175.42,77.51 ; RST_ATTN1.2 173.93,77.51 ; RST_ATTN1.2 175.42,78.99 ; RST_ATTN1.2 173.93,78.99 ; 24.45,102.05 J4.GH7 ; J4.GH7 25.35,101.15 ; J4.GH7 24.45,101.15 ; J4.GH7 25.35,102.05 ; 166.35,118.8 167.06,119.51 ; 167.06,119.51 167.76,120.21 ; 167.06,119.51 167.76,118.8 ; 167.06,119.51 166.35,120.21 ; 21.73,108.67 J4.GG10 21.73,109.53 ; 17.23,104.53 J4.GE8 17.23,103.67 ; 15.47,116.17 J2.GD3 15.47,117.03 ; J8.2 19.71,22.53 ; J8.2 18.3,23.95 ; J8.2 18.3,22.53 ; J8.2 19.71,23.95 ; 8.42,135.66 J2.GA10 8.42,134.62 ; 17.23,128.67 J2.GE8 17.23,129.53 ; 24.45,122.05 J2.GH5 ; J2.GH5 25.35,121.15 ; J2.GH5 25.35,122.05 ; J2.GH5 24.45,121.15 ; 17.23,123.67 J2.GE6 17.23,124.53 ; TP14.1 108.41,119.17 ; TP14.1 106.98,120.6 ; TP14.1 108.41,120.6 ; TP14.1 106.98,119.17 ; 19.97,98.67 J4.GF6 19.97,99.53 ; 17.23,107.03 J4.GE9 17.23,106.17 ; 17.23,133.67 J2.GE10 17.23,134.53 ; J4.GH6 25.35,99.55 ; J4.GH6 25.35,98.65 ; J4.GH6 24.45,98.65 ; J4.GH6 24.45,99.55 ; CN7.H12 39.61,141.26 ; CN7.H12 39.61,137.89 ; CN7.H12 36.24,141.26 ; CN7.H12 36.24,137.89 ; LCD1.K 49.9,142.9 ; LCD1.K 49.9,144.53 ; LCD1.K 47.33,144.53 ; LCD1.K 47.33,142.9 ; J2.GH8 25.35,129.55 ; J2.GH8 25.35,128.65 ; J2.GH8 24.45,128.65 ; J2.GH8 24.45,129.55 ; 8.42,132.12 J2.GA9 8.42,133.16 ; 8.42,129.62 J2.GA8 8.42,130.66 ; 10.97,122.03 J2.GB5 10.97,121.17 ; 170.5,138.86 J1.5 ; J1.5 170.5,137.36 ; J1.5 172.55,138.86 ; 19.97,112.03 J2.GF1 19.97,111.17 ; 17.23,87.03 J4.GE1 17.23,86.17 ; 10.97,106.17 J4.GB9 10.97,107.03 ; 17.23,99.53 J4.GE6 17.23,98.67 ; J11.3 16.61,8.33 ; J11.3 13.15,10.29 ; J11.3 13.15,8.33 ; J8.3 19.71,21.41 ; J8.3 18.3,21.41 ; J8.3 18.3,19.99 ; J8.3 19.71,19.99 ; 175.95,91.57 RST_PWR1.2 ; RST_PWR1.2 177.35,90.18 ; RST_PWR1.2 175.95,90.18 ; RST_PWR1.2 177.35,91.57 ; 10.97,94.53 J4.GB4 10.97,93.67 ; J4.GH4 25.35,93.65 ; J4.GH4 24.45,94.55 ; J4.GH4 25.35,94.55 ; J4.GH4 24.45,93.65 ; 17.23,97.03 J4.GE5 17.23,96.17 ; 19.97,123.67 J2.GF6 19.97,124.53 ; J2.GH6 25.35,123.65 ; J2.GH6 25.35,124.55 ; J2.GH6 24.45,123.65 ; J2.GH6 24.45,124.55 ; J4.GH5 25.35,96.15 ; J4.GH5 24.45,96.15 ; J4.GH5 25.35,97.05 ; J4.GH5 24.45,97.05 ; 8.42,93.16 J4.GA3 8.42,92.12 ; 21.73,113.67 J2.GG2 21.73,114.53 ; 17.23,116.17 J2.GE3 17.23,117.03 ; 36.24,89.23 CN7.H11 ; CN7.H11 36.24,92.6 ; CN7.H11 39.61,92.6 ; CN7.H11 39.61,89.23 ; 12.73,122.03 J2.GC5 12.73,121.17 ; 15.47,118.67 J2.GD4 15.47,119.53 ; 12.73,129.53 J2.GC8 12.73,128.67 ; 15.47,91.17 J4.GD3 15.47,92.03 ; 17.23,91.17 J4.GE3 17.23,92.03 ; 8.42,123.16 J2.GA5 8.42,122.12 ; 21.73,134.53 J2.GG10 21.73,133.67 ; 21.73,121.17 J2.GG5 21.73,122.03 ; 136.38,123.9 CN4.2 ; CN4.2 137.79,122.48 ; CN4.2 136.38,122.48 ; CN4.2 137.79,123.9 ; 10.97,131.17 J2.GB9 10.97,132.03 ; 10.97,102.03 J4.GB7 10.97,101.17 ; 15.47,97.03 J4.GD5 15.47,96.17 ; 15.47,93.67 J4.GD4 15.47,94.53 ; 174.3,138.06 J1.4 174.3,136.56 ; 15.47,88.67 J4.GD2 15.47,89.53 ; 10.97,109.53 J4.GB10 10.97,108.67 ; 12.73,126.17 J2.GC7 12.73,127.03 ; 10.97,119.53 J2.GB4 10.97,118.67 ; 21.73,128.67 J2.GG8 21.73,129.53 ; 19.97,92.03 J4.GF3 19.97,91.17 ; J11.2 20.36,11.29 ; J11.2 20.36,9.33 ; J11.2 16.4,11.29 ; 10.97,89.53 J4.GB2 10.97,88.67 ; 10.97,133.67 J2.GB10 10.97,134.53 ; J2.GH10 25.35,133.65 ; J2.GH10 24.45,133.65 ; J2.GH10 24.45,134.55 ; J2.GH10 25.35,134.55 ; 21.73,123.67 J2.GG6 21.73,124.53 ; 17.23,127.03 J2.GE7 17.23,126.17 ; 8.42,118.16 J2.GA3 8.42,117.12 ; 12.73,117.03 J2.GC3 12.73,116.17 ; 12.73,123.67 J2.GC6 12.73,124.53 ; 21.73,92.03 J4.GG3 21.73,91.17 ; J7.7 165.65,40.59 ; J7.7 164.58,40.59 ; J7.7 165.65,41.66 ; J7.7 164.58,41.66 ; 19.97,101.17 J4.GF7 19.97,102.03 ; 8.42,110.66 J4.GA10 8.42,109.62 ; 8.42,112.12 J2.GA1 8.42,113.16 ; 15.47,124.53 J2.GD6 15.47,123.67 ; 19.97,121.17 J2.GF5 19.97,122.03 ; 17.23,89.53 J4.GE2 17.23,88.67 ; 21.73,107.03 J4.GG9 21.73,106.17 ; 15.47,129.53 J2.GD8 15.47,128.67 ; 19.97,126.17 J2.GF7 19.97,127.03 ; 10.97,103.67 J4.GB8 10.97,104.53 ; 8.42,87.12 J4.GA1 8.42,88.16 ; 19.97,116.17 J2.GF3 19.97,117.03 ; 24.45,111.15 J2.GH1 ; J2.GH1 25.35,112.05 ; J2.GH1 24.45,112.05 ; J2.GH1 25.35,111.15 ; 12.73,114.53 J2.GC2 12.73,113.67 ; 10.97,126.17 J2.GB7 10.97,127.03 ; 15.47,114.53 J2.GD2 15.47,113.67 ; 19.97,128.67 J2.GF8 19.97,129.53 ; 19.97,104.53 J4.GF8 19.97,103.67 ; 19.97,96.17 J4.GF5 19.97,97.03 ; J2.GH3 25.35,116.15 ; J2.GH3 24.45,117.05 ; J2.GH3 24.45,116.15 ; J2.GH3 25.35,117.05 ; 12.73,89.53 J4.GC2 12.73,88.67 ; 19.97,134.53 J2.GF10 19.97,133.67 ; 17.23,131.17 J2.GE9 17.23,132.03 ; 21.73,102.03 J4.GG7 21.73,101.17 ; 21.73,87.03 J4.GG1 21.73,86.17 ; 12.73,98.67 J4.GC6 12.73,99.53 ; 19.97,87.03 J4.GF1 19.97,86.17 ; J2.GH7 25.35,126.15 ; J2.GH7 24.45,127.05 ; J2.GH7 24.45,126.15 ; J2.GH7 25.35,127.05 ; 170.5,102.15 J3.5 ; J3.5 170.5,103.65 ; J3.5 172.55,103.65 ; 19.97,118.67 J2.GF4 19.97,119.53 ; 21.73,98.67 J4.GG6 21.73,99.53 ; 158.12,119.51 158.82,118.8 ; 158.12,119.51 157.41,118.8 ; 158.12,119.51 158.82,120.21 ; 158.12,119.51 157.41,120.21 ; 19.97,94.53 J4.GF4 19.97,93.67 ; 10.97,129.53 J2.GB8 10.97,128.67 ; 8.42,128.16 J2.GA7 8.42,127.12 ; 12.73,108.67 J4.GC10 12.73,109.53 ; J4.GH3 25.35,91.15 ; J4.GH3 24.45,91.15 ; J4.GH3 24.45,92.05 ; J4.GH3 25.35,92.05 ; 15.47,111.17 J2.GD1 15.47,112.03 ; 8.42,120.66 J2.GA4 8.42,119.62 ; 8.42,114.62 J2.GA2 8.42,115.66 ; 10.97,113.67 J2.GB2 10.97,114.53 ; 21.73,116.17 J2.GG3 21.73,117.03 ; CN1.3 159.16,140.26 ; CN1.3 159.16,141.68 ; CN1.3 157.75,141.68 ; CN1.3 157.75,140.26 ; 17.23,108.67 J4.GE10 17.23,109.53 ; 19.97,107.03 J4.GF9 19.97,106.17 ; 12.73,118.67 J2.GC4 12.73,119.53 ; 15.47,109.53 J4.GD10 15.47,108.67 ; 12.73,104.53 J4.GC8 12.73,103.67 ; J2.GH2 25.35,113.65 ; J2.GH2 25.35,114.55 ; J2.GH2 24.45,113.65 ; J2.GH2 24.45,114.55 ; 15.47,134.53 J2.GD10 15.47,133.67 ; 19.97,132.03 J2.GF9 19.97,131.17 ; 17.23,122.03 J2.GE5 17.23,121.17 ; 21.73,118.67 J2.GG4 21.73,119.53 ; 12.73,107.03 J4.GC9 12.73,106.17 ; 12.73,87.03 J4.GC1 12.73,86.17 ; 15.47,86.17 J4.GD1 15.47,87.03 ; 12.73,133.67 J2.GC10 12.73,134.53 ; 17.23,102.03 J4.GE7 17.23,101.17 ; 12.73,96.17 J4.GC5 12.73,97.03 ; 8.42,105.66 J4.GA8 8.42,104.62 ; 12.73,92.03 J4.GC3 12.73,91.17 ; 12.73,102.03 J4.GC7 12.73,101.17 ; 19.97,88.67 J4.GF2 19.97,89.53 ; 15.47,122.03 J2.GD5 15.47,121.17 ; 8.42,94.62 J4.GA4 8.42,95.66 ; 10.97,91.17 J4.GB3 10.97,92.03 ; 19.97,108.67 J4.GF10 19.97,109.53 ; 19.97,113.67 J2.GF2 19.97,114.53 ; 8.42,89.62 J4.GA2 8.42,90.66 ; 8.42,108.16 J4.GA9 8.42,107.12 ; 10.97,99.53 J4.GB6 10.97,98.67 ; 21.73,131.17 J2.GG9 21.73,132.03 ; 8.42,125.66 J2.GA6 8.42,124.62 ; 21.73,127.03 J2.GG7 21.73,126.17 ; 21.73,103.67 J4.GG8 21.73,104.53 ; 138.74,118.29 CN6.3 ; CN6.3 138.74,119.71 ; CN6.3 140.15,119.71 ; 17.23,111.17 J2.GE1 17.23,112.03 ; 8.42,99.62 J4.GA6 8.42,100.66 ; 21.73,89.53 J4.GG2 21.73,88.67 ; 15.47,132.03 J2.GD9 15.47,131.17 ; 12.73,132.03 J2.GC9 12.73,131.17 ; 15.47,127.03 J2.GD7 15.47,126.17
  L11_GND4 w0.381: 19.97,99.53 J4.GF6 19.97,98.67 ; 8.42,105.66 J4.GA8 8.42,104.62 ; 15.47,108.67 J4.GD10 15.47,109.53 ; 47.33,144.53 LCD1.K ; LCD1.K 47.33,142.9 ; LCD1.K 49.9,144.53 ; LCD1.K 49.9,142.9 ; 10.97,107.03 J4.GB9 10.97,106.17 ; 18.3,19.99 J8.3 ; J8.3 18.3,21.41 ; J8.3 19.71,19.99 ; J8.3 19.71,21.41 ; 21.73,117.03 J2.GG3 21.73,116.17 ; 18.3,22.53 J8.2 ; J8.2 18.3,23.95 ; J8.2 19.71,22.53 ; J8.2 19.71,23.95 ; 8.42,112.12 J2.GA1 8.42,113.16 ; 157.75,140.26 CN1.3 ; CN1.3 157.75,141.68 ; CN1.3 159.16,141.68 ; CN1.3 159.16,140.26 ; 12.73,129.53 J2.GC8 12.73,128.67 ; 17.23,116.17 J2.GE3 17.23,117.03 ; 15.47,134.53 J2.GD10 15.47,133.67 ; 21.73,122.03 J2.GG5 21.73,121.17 ; 24.45,118.65 J2.GH4 ; J2.GH4 25.35,119.55 ; J2.GH4 24.45,119.55 ; J2.GH4 25.35,118.65 ; 24.45,91.15 J4.GH3 ; J4.GH3 24.45,92.05 ; J4.GH3 25.35,91.15 ; J4.GH3 25.35,92.05 ; 136.38,123.9 CN4.2 ; CN4.2 137.79,123.9 ; CN4.2 137.79,122.48 ; CN4.2 136.38,122.48 ; 19.97,109.53 J4.GF10 19.97,108.67 ; 21.73,89.53 J4.GG2 21.73,88.67 ; 24.45,96.15 J4.GH5 ; J4.GH5 25.35,96.15 ; J4.GH5 24.45,97.05 ; J4.GH5 25.35,97.05 ; 10.97,97.03 J4.GB5 10.97,96.17 ; 8.42,95.66 J4.GA4 8.42,94.62 ; 8.42,98.16 J4.GA5 8.42,97.12 ; 8.42,89.62 J4.GA2 8.42,90.66 ; 19.97,117.03 J2.GF3 19.97,116.17 ; 17.23,127.03 J2.GE7 17.23,126.17 ; 12.73,127.03 J2.GC7 12.73,126.17 ; 19.97,106.17 J4.GF9 19.97,107.03 ; 10.97,122.03 J2.GB5 10.97,121.17 ; 17.23,123.67 J2.GE6 17.23,124.53 ; 10.97,132.03 J2.GB9 10.97,131.17 ; 8.42,130.66 J2.GA8 8.42,129.62 ; J7.4 167.15,45.16 ; J7.4 167.15,44.09 ; J7.4 166.08,45.16 ; J7.4 166.08,44.09 ; 12.73,91.17 J4.GC3 12.73,92.03 ; 21.73,111.17 J2.GG1 21.73,112.03 ; 17.23,87.03 J4.GE1 17.23,86.17 ; 24.45,113.65 J2.GH2 ; J2.GH2 25.35,113.65 ; J2.GH2 25.35,114.55 ; J2.GH2 24.45,114.55 ; 12.73,103.67 J4.GC8 12.73,104.53 ; 170.5,138.86 J1.5 ; J1.5 170.5,137.36 ; J1.5 172.55,138.86 ; 15.47,111.17 J2.GD1 15.47,112.03 ; 24.45,117.05 J2.GH3 ; J2.GH3 25.35,117.05 ; J2.GH3 24.45,116.15 ; J2.GH3 25.35,116.15 ; 15.47,89.53 J4.GD2 15.47,88.67 ; 12.73,109.53 J4.GC10 12.73,108.67 ; J11.2 20.36,9.33 ; J11.2 20.36,11.29 ; J11.2 16.4,11.29 ; 167.06,119.51 167.76,118.8 ; 167.06,119.51 167.76,120.21 ; 167.06,119.51 166.35,118.8 ; 167.06,119.51 166.35,120.21 ; 8.42,123.16 J2.GA5 8.42,122.12 ; 17.23,111.17 J2.GE1 17.23,112.03 ; 19.97,131.17 J2.GF9 19.97,132.03 ; 12.73,131.17 J2.GC9 12.73,132.03 ; RST_ATTN1.2 175.42,78.99 ; RST_ATTN1.2 173.93,78.99 ; RST_ATTN1.2 175.42,77.51 ; RST_ATTN1.2 173.93,77.51 ; 24.45,99.55 J4.GH6 ; J4.GH6 25.35,98.65 ; J4.GH6 24.45,98.65 ; J4.GH6 25.35,99.55 ; 8.42,92.12 J4.GA3 8.42,93.16 ; 19.97,88.67 J4.GF2 19.97,89.53 ; 15.47,124.53 J2.GD6 15.47,123.67 ; J4.GH10 25.35,108.65 ; J4.GH10 24.45,109.55 ; J4.GH10 25.35,109.55 ; J4.GH10 24.45,108.65 ; 8.42,99.62 J4.GA6 8.42,100.66 ; 21.73,128.67 J2.GG8 21.73,129.53 ; J2.GH5 25.35,122.05 ; J2.GH5 24.45,121.15 ; J2.GH5 24.45,122.05 ; J2.GH5 25.35,121.15 ; 24.45,106.15 J4.GH9 ; J4.GH9 25.35,106.15 ; J4.GH9 25.35,107.05 ; J4.GH9 24.45,107.05 ; J2.GH7 25.35,126.15 ; J2.GH7 24.45,126.15 ; J2.GH7 24.45,127.05 ; J2.GH7 25.35,127.05 ; J2.GH6 25.35,123.65 ; J2.GH6 25.35,124.55 ; J2.GH6 24.45,124.55 ; J2.GH6 24.45,123.65 ; 17.23,97.03 J4.GE5 17.23,96.17 ; 36.24,89.23 CN7.H11 ; CN7.H11 39.61,89.23 ; CN7.H11 39.61,92.6 ; CN7.H11 36.24,92.6 ; 15.47,107.03 J4.GD9 15.47,106.17 ; J4.GH2 25.35,89.55 ; J4.GH2 25.35,88.65 ; J4.GH2 24.45,88.65 ; J4.GH2 24.45,89.55 ; 15.47,86.17 J4.GD1 15.47,87.03 ; 21.73,92.03 J4.GG3 21.73,91.17 ; 10.97,126.17 J2.GB7 10.97,127.03 ; 10.97,119.53 J2.GB4 10.97,118.67 ; 10.97,108.67 J4.GB10 10.97,109.53 ; 15.47,96.17 J4.GD5 15.47,97.03 ; 12.73,124.53 J2.GC6 12.73,123.67 ; 19.97,128.67 J2.GF8 19.97,129.53 ; 10.97,99.53 J4.GB6 10.97,98.67 ; 12.73,87.03 J4.GC1 12.73,86.17 ; 8.42,133.16 J2.GA9 8.42,132.12 ; J7.7 165.65,41.66 ; J7.7 165.65,40.59 ; J7.7 164.58,40.59 ; J7.7 164.58,41.66 ; 21.73,87.03 J4.GG1 21.73,86.17 ; 8.42,110.66 J4.GA10 8.42,109.62 ; 12.73,106.17 J4.GC9 12.73,107.03 ; 21.73,108.67 J4.GG10 21.73,109.53 ; 21.73,113.67 J2.GG2 21.73,114.53 ; J2.GH1 25.35,112.05 ; J2.GH1 24.45,111.15 ; J2.GH1 25.35,111.15 ; J2.GH1 24.45,112.05 ; 17.23,102.03 J4.GE7 17.23,101.17 ; 12.73,117.03 J2.GC3 12.73,116.17 ; J2.GH8 25.35,128.65 ; J2.GH8 24.45,128.65 ; J2.GH8 25.35,129.55 ; J2.GH8 24.45,129.55 ; 15.47,94.53 J4.GD4 15.47,93.67 ; TP14.1 108.41,119.17 ; TP14.1 108.41,120.6 ; TP14.1 106.98,120.6 ; TP14.1 106.98,119.17 ; 17.23,89.53 J4.GE2 17.23,88.67 ; 17.23,109.53 J4.GE10 17.23,108.67 ; 175.95,90.18 RST_PWR1.2 ; RST_PWR1.2 177.35,91.57 ; RST_PWR1.2 177.35,90.18 ; RST_PWR1.2 175.95,91.57 ; 15.47,116.17 J2.GD3 15.47,117.03 ; CN7.H12 39.61,141.26 ; CN7.H12 39.61,137.89 ; CN7.H12 36.24,141.26 ; CN7.H12 36.24,137.89 ; 24.45,93.65 J4.GH4 ; J4.GH4 25.35,93.65 ; J4.GH4 24.45,94.55 ; J4.GH4 25.35,94.55 ; 10.97,92.03 J4.GB3 10.97,91.17 ; 12.73,133.67 J2.GC10 12.73,134.53 ; J4.GH1 25.35,87.05 ; J4.GH1 24.45,87.05 ; J4.GH1 25.35,86.15 ; J4.GH1 24.45,86.15 ; 21.73,131.17 J2.GG9 21.73,132.03 ; 15.47,126.17 J2.GD7 15.47,127.03 ; 15.47,128.67 J2.GD8 15.47,129.53 ; 21.73,119.53 J2.GG4 21.73,118.67 ; 8.42,102.12 J4.GA7 8.42,103.16 ; 19.97,123.67 J2.GF6 19.97,124.53 ; 12.73,101.17 J4.GC7 12.73,102.03 ; 24.45,102.05 J4.GH7 ; J4.GH7 25.35,101.15 ; J4.GH7 24.45,101.15 ; J4.GH7 25.35,102.05 ; 19.97,112.03 J2.GF1 19.97,111.17 ; 157.41,120.21 158.12,119.51 ; 158.12,119.51 158.82,118.8 ; 158.12,119.51 158.82,120.21 ; 158.12,119.51 157.41,118.8 ; J3.5 172.55,103.65 ; J3.5 170.5,103.65 ; J3.5 170.5,102.15 ; 62.31,146.27 LCD1.11 ; LCD1.11 63.52,146.27 ; LCD1.11 62.31,145.05 ; LCD1.11 63.52,145.05 ; 19.97,87.03 J4.GF1 19.97,86.17 ; 10.97,134.53 J2.GB10 10.97,133.67 ; 8.42,118.16 J2.GA3 8.42,117.12 ; 17.23,99.53 J4.GE6 17.23,98.67 ; 82.43,30.29 FAN1.1 ; FAN1.1 83.84,28.88 ; FAN1.1 82.43,28.88 ; FAN1.1 83.84,30.29 ; 174.3,136.56 J1.4 174.3,138.06 ; 10.97,124.53 J2.GB6 10.97,123.67 ; 19.97,103.67 J4.GF8 19.97,104.53 ; 19.97,91.17 J4.GF3 19.97,92.03 ; 24.45,104.55 J4.GH8 ; J4.GH8 25.35,103.65 ; J4.GH8 24.45,103.65 ; J4.GH8 25.35,104.55 ; 21.73,123.67 J2.GG6 21.73,124.53 ; 21.73,103.67 J4.GG8 21.73,104.53 ; 12.73,89.53 J4.GC2 12.73,88.67 ; 21.73,98.67 J4.GG6 21.73,99.53 ; 12.73,98.67 J4.GC6 12.73,99.53 ; 10.97,88.67 J4.GB2 10.97,89.53 ; 19.97,127.03 J2.GF7 19.97,126.17 ; 15.47,114.53 J2.GD2 15.47,113.67 ; 12.73,122.03 J2.GC5 12.73,121.17 ; 15.47,92.03 J4.GD3 15.47,91.17 ; 19.97,119.53 J2.GF4 19.97,118.67 ; J2.GH10 25.35,134.55 ; J2.GH10 25.35,133.65 ; J2.GH10 24.45,133.65 ; J2.GH10 24.45,134.55 ; 17.23,107.03 J4.GE9 17.23,106.17 ; 12.73,112.03 J2.GC1 12.73,111.17 ; 13.15,8.33 J11.3 ; J11.3 13.15,10.29 ; J11.3 16.61,8.33 ; 8.42,87.12 J4.GA1 8.42,88.16 ; 10.97,114.53 J2.GB2 10.97,113.67 ; 21.73,107.03 J4.GG9 21.73,106.17 ; 17.23,92.03 J4.GE3 17.23,91.17 ; 17.23,132.03 J2.GE9 17.23,131.17 ; 21.73,134.53 J2.GG10 21.73,133.67 ; 10.97,87.03 J4.GB1 10.97,86.17 ; 21.73,96.17 J4.GG5 21.73,97.03 ; 19.97,101.17 J4.GF7 19.97,102.03 ; 17.23,93.67 J4.GE4 17.23,94.53 ; 19.97,97.03 J4.GF5 19.97,96.17 ; 10.97,112.03 J2.GB1 10.97,111.17 ; 19.97,93.67 J4.GF4 19.97,94.53 ; 15.47,119.53 J2.GD4 15.47,118.67 ; 8.42,114.62 J2.GA2 8.42,115.66 ; 138.74,118.29 CN6.3 ; CN6.3 140.15,119.71 ; CN6.3 138.74,119.71 ; 10.97,93.67 J4.GB4 10.97,94.53 ; 15.47,122.03 J2.GD5 15.47,121.17 ; 15.47,131.17 J2.GD9 15.47,132.03 ; 19.97,134.53 J2.GF10 19.97,133.67 ; 17.23,114.53 J2.GE2 17.23,113.67 ; 24.45,131.15 J2.GH9 ; J2.GH9 25.35,132.05 ; J2.GH9 25.35,131.15 ; J2.GH9 24.45,132.05 ; 15.47,104.53 J4.GD8 15.47,103.67 ; 10.97,104.53 J4.GB8 10.97,103.67 ; 8.42,127.12 J2.GA7 8.42,128.16 ; 19.97,113.67 J2.GF2 19.97,114.53 ; 21.73,127.03 J2.GG7 21.73,126.17 ; 12.73,113.67 J2.GC2 12.73,114.53 ; 10.97,102.03 J4.GB7 10.97,101.17 ; 8.42,119.62 J2.GA4 8.42,120.66 ; 129.36,124.53 PMBUS1.5 ; PMBUS1.5 129.36,125.91 ; PMBUS1.5 130.74,124.53 ; PMBUS1.5 130.74,125.91 ; 17.23,134.53 J2.GE10 17.23,133.67 ; 8.42,135.66 J2.GA10 8.42,134.62 ; 17.23,129.53 J2.GE8 17.23,128.67 ; 17.23,122.03 J2.GE5 17.23,121.17 ; 15.47,101.17 J4.GD7 15.47,102.03 ; 10.97,128.67 J2.GB8 10.97,129.53 ; 17.23,118.67 J2.GE4 17.23,119.53 ; 12.73,94.53 J4.GC4 12.73,93.67 ; 19.97,121.17 J2.GF5 19.97,122.03 ; 8.42,108.16 J4.GA9 8.42,107.12 ; 17.23,104.53 J4.GE8 17.23,103.67 ; 8.42,124.62 J2.GA6 8.42,125.66 ; 12.73,97.03 J4.GC5 12.73,96.17 ; 12.73,119.53 J2.GC4 12.73,118.67 ; 10.97,116.17 J2.GB3 10.97,117.03 ; 21.73,94.53 J4.GG4 21.73,93.67 ; 15.47,99.53 J4.GD6 15.47,98.67 ; 21.73,102.03 J4.GG7 21.73,101.17
  BOTTOM w0.127: 25.83,119.15 25.24,118.56 arc(25.07,118.45) 24.88,118.41 13.57,118.41 arc(13.37,118.37) 13.21,118.26 12.45,117.5 arc(12.34,117.34) 12.3,117.14 J2.GC3 ; 25.83,119.15 26.06,119.15 arc(26.22,119.12) 26.36,119.03 26.77,118.62 29.21,116.18 arc(29.44,115.84) 29.51,115.44 29.51,91.97 arc(29.67,91.19) 30.11,90.54 36.08,84.57 arc(36.59,83.8) 36.77,82.9 36.77,70.72 arc(36.82,70.47) 36.96,70.26 37.8,69.42 arc(37.88,69.37) 37.97,69.35 47.38,69.35 arc(47.58,69.31) 47.74,69.2 47.83,69.11 arc(47.84,69.1) 47.85,69.09 arc(48.01,68.99) 48.19,68.96 v4(48.61,68.96) 47.87,69.7 arc(47.86,69.71) 47.85,69.72 arc(47.69,69.82) 47.51,69.85 40.82,69.85 arc(40.63,69.89) 40.47,70 38.03,72.43 arc(37.92,72.6) 37.88,72.79 37.88,82.46 37.88,83.73 arc(37.76,84.36) 37.4,84.9 31.39,90.91 arc(30.89,91.67) 30.71,92.56 30.71,116.3 arc(30.67,116.5) 30.56,116.66 26.46,120.76 arc(26.3,120.87) 26.1,120.91 13.52,120.91 arc(13.33,120.87) 13.17,120.76 12.45,120.04 arc(12.34,119.88) 12.3,119.68 J2.GC4 ; 25.83,119.15 25.4,119.59 arc(25.23,119.7) 25.04,119.74 16.07,119.74 arc(16.01,119.72) 15.95,119.68 arc(15.91,119.63) 15.9,119.56 J2.GD4 ; 25.86,114.12 26.01,114.12 arc(26.2,114.08) 26.36,113.98 26.95,113.39 arc(27.17,113.05) 27.25,112.65 27.25,90.99 arc(27.39,90.28) 27.79,89.69 33.99,83.49 arc(34.39,82.89) 34.53,82.18 34.53,69.57 arc(34.62,69.14) 34.86,68.77 37.13,66.5 arc(37.61,66.18) 38.18,66.07 38.83,66.07 arc(39.02,66.1) 39.19,66.21 39.36,66.39 39.37,66.39 39.64,66.66 39.64,66.67 40.41,67.44 arc(40.58,67.55) 40.77,67.59 47.15,67.59 ; 25.86,114.12 25.18,113.45 arc(25.14,113.42) 25.09,113.41 13.8,113.41 arc(13.6,113.37) 13.44,113.26 12.45,112.27 arc(12.34,112.11) 12.3,111.91 J2.GC1 ; 25.86,114.12 25.25,114.73 16.03,114.73 15.9,114.6 J2.GD2 ; 47.15,67.59 47.69,67.05 47.87,66.87 arc(48.21,66.64) v4(48.61,66.56) ; 47.15,67.59 46.79,67.95 arc(46.48,68.16) 46.11,68.23 37.85,68.23 arc(37.21,68.36) 36.66,68.72 35.94,69.44 arc(35.72,69.77) 35.65,70.15 35.65,82.63 arc(35.51,83.35) 35.1,83.97 28.96,90.1 arc(28.54,90.73) 28.4,91.46 28.4,114.5 arc(28.32,114.9) 28.09,115.24 27.66,115.67 27.02,116.32 arc(26.72,116.52) 26.37,116.59 25.96,116.59 ; J2.GD1 15.9,111.77 arc(15.93,111.92) 16.02,112.06 16.04,112.08 arc(16.2,112.19) 16.39,112.22 25.04,112.22 arc(25.28,112.18) 25.48,112.04 25.95,111.57 arc(26.09,111.36) 26.14,111.12 26.14,90.38 arc(26.27,89.69) 26.67,89.1 32.93,82.84 arc(33.29,82.3) 33.41,81.67 33.41,68.9 arc(33.54,68.28) 33.89,67.75 36.18,65.46 arc(36.75,65.08) 37.42,64.95 39.19,64.95 arc(39.92,65.09) 40.54,65.51 40.7,65.67 arc(41.24,66.03) 41.87,66.15 46.02,66.15 arc(46.55,66.05) 47,65.75 47.12,65.63 arc(47.42,65.43) 47.78,65.36 v4(49.58,65.36) ; J2.GC2 12.3,114.76 arc(12.34,114.95) 12.45,115.12 13.09,115.76 arc(13.26,115.87) 13.45,115.91 25.07,115.91 arc(25.27,115.95) 25.43,116.06 25.96,116.59 ; 25.96,116.59 25.32,117.22 23.44,117.22 23.44,117.22 22.76,117.22 22.76,117.22 22.24,117.22 22.24,117.22 19.46,117.22 19.46,117.22 18.94,117.22 18.94,117.22 18.26,117.22 18.26,117.22 17.74,117.22 17.74,117.22 16.25,117.22 arc(16.11,117.19) 16,117.12 arc(15.93,117.01) 15.9,116.87 J2.GD3 ; 147.49,106.72 147.81,107.04 147.81,108.25 147.57,108.49 147.25,108.49 146.86,108.88 v1(146.62,108.88) 146.62,108.42 147.02,108.01 147.02,107.92 147.02,107.1 C370.2 147.49,106.72
  BOTTOM w0.203: U75.20 34.17,30.86 33.57,31.46 v6(33.57,32.21)
  BOTTOM w0.254: C505.2 v4(60.78,68.56) C499.2 ; U17.51 82.27,95.37 82.03,95.12 C412.2 ; C702.2 v4(57.58,53.36) ; C491.2 v4(53.58,69.36) R441.1 ; C623.2 v4(67.98,58.16) ; U46.11 59.51,125.98 59.92,126.39 v2(59.87,126.39) ; U18.64 68.42,94.87 C414.2 ; U39.15 45.36,139.15 45.36,139.15 v3(45.36,139.05) ; C684.2 v4(70.38,54.16) ; C93.1 v2(58.14,79.75) ; C367.2 139.83,108.1 141.01,108.1 v1(141.02,108.08) 141.1,108 C366.2 ; v2(138.85,126.58) 139.02,126.75 C876.2 ; U44.17 76.71,125.55 v2(76.68,125.53) ; C297.2 v2(116.16,146.06) ; R458.1 v2(27.08,63.59) ; v2(114.55,139.92) 114.3,140.17 C315.2 ; C339.2 136.14,130.55 v2(136.21,130.62) ; C330.2 v2(136.09,132.66) ; R515.2 v1(127.22,38.18) ; C78.2 65.53,82.67 v2(65.63,82.57) ; R356.1 C354.2 v2(112.12,113.28) ; v2(155.51,85.57) 155.51,87.26 154.96,87.81 C435.2 ; v1(84.36,100.46) 84.6,100.7 R112.1 ; C695.2 v4(54.38,53.36) ; C480.2 v4(72.78,69.36) ; R291.1 v2(132.14,144.58) ; C844.1 v1(135.58,7.75) ; C710.2 v4(56.78,52.56) ; v1(144.22,104.08) 144.22,104.92 C378.2 ; C586.2 v4(69.58,62.16) ; C550.2 v4(55.98,65.36) ; C533.2 v4(72.78,66.16) ; U38.15 137.28,142.09 C311.2 ; R429.1 v2(122.62,72.01) ; U45.11 49.38,126.01 v3(49.45,126.08) ; v2(98.1,115.65) 97.94,115.49 C351.2 ; C507.2 v4(73.58,67.76) ; C639.2 v4(67.18,57.36) ; v2(80.31,70.51) 80.45,70.38 C478.2 82.76,70.38 82.96,70.18 U63.B1 ; C708.2 v4(62.38,52.56) ; C503.2 v4(69.58,68.56) C495.2 ; C344.1 159.18,123.83 159.51,123.49 v2(159.51,122.94) C346.2 U50.1 ; C704.2 v4(52.78,53.36) ; C383.2 138.91,103.35 138.62,103.06 v1(138.62,102.48) ; U56.2 87.12,112.42 87.25,112.55 C355.2 87.25,113.74 87.33,113.82 v2(87.33,113.89) ; C333.2 67.09,130.46 v2(67.11,130.44) ; C500.2 v4(59.18,68.56) C484.2 ; C595.2 v4(70.38,61.36) ; C516.2 v2(111.82,68.58) ; C338.2 v2(139.19,130.55) ; C615.2 v4(65.58,58.96) ; U42.4 v2(135.24,136.05) ; U17.61 85.19,92.98 C426.2 ; v1(148.46,128.78) C340.2 C336.2 ; U52.7 v2(169.17,114.68) ; C337.2 142.19,130.38 142.37,130.56 142.37,130.55 v2(142.37,130.55) ; EEPROM1.4 v2(118.62,73.41) ; v4(62.38,64.56) 62.05,64.23 C563.1 61.25,64.23 v4(60.78,63.76) C569.2 ; C357.2 v2(84.65,113.72) ; C582.2 v4(56.78,62.96) ; C893.2 42.09,91.94 41.45,92.58 v1(41.45,92.58) ; C402.2 141.54,97.68 v1(142.62,97.68) ; C619.2 v4(56.78,58.96) ; C671.2 v4(73.58,55.76) ; v1(148.22,96.88) 148.55,97.21 C398.2 ; R562.2 v1(125.22,19.3) ; v2(113.56,48.44) 113.56,47.85 113.79,47.62 U71.4 ; U58.2 44.17,94.09 C417.2 42.84,93.25 42.47,93.62 v2(42.47,94.06) ; C513.2 v4(62.38,67.76) C504.2 ; C306.2 v3(76.45,142.39) ; v4(56.78,61.36) 56.8,61.33 C605.1 56.8,60.53 v4(57.58,59.76) ; C545.2 v4(64.78,65.36) ; C874.1 13.26,130.64 J2.GC9 ; v1(140.39,28.88) 140.35,28.84 Y7.2 139.1,30.09 v1(139.12,30.1) ; R295.2 v2(92.38,146.48) ; C77.2 v2(67.01,81.77) ; R652.2 140.59,17.65 v1(140.72,17.78) ; C76.1 68.3,82.67 v2(68.4,82.57) ; U17.57 83.8,92.83 83.54,92.57 C427.2 C428.2 ; U53.K3 62.4,116.83 v1(61.82,116.83) ; v2(130.24,133.16) 130.24,132.9 130.56,132.59 C325.2 ; C631.2 v4(54.38,58.16) ; U50.14 162.09,115.19 162.34,114.94 C352.2 C356.2 v2(162.34,112.01) ; C311.2 137.43,141.44 U38.14 ; C311.2 v2(136.29,141.84) ; C430.2 67.31,92.98 U18.61 ; C172.1 v2(53.72,41.79) ; v1(143.42,104.08) 143.42,103.36 C382.2 ; C497.2 v4(64.78,68.56) ; C361.2 v2(87.25,108.49) 87.25,108.61 87.12,108.74 U56.5 ; C687.2 v4(67.18,54.16) C686.2 ; C693.2 v4(59.98,54.16) ; C508.2 v4(59.98,67.76) ; C523.2 v4(63.18,66.96) ; C307.2 v3(75.06,142.39) ; C624.2 v4(66.38,58.16) ; v1(146.62,96.88) 146.43,97.07 C400.2 ; R446.1 v4(53.58,67.76) ; Q12.2 v2(176.66,124.49) ; C413.2 86.31,94.87 U17.64 ; U48.7 166.54,126.32 166.12,125.9 v1(166.12,124.84) 166.57,124.39 C341.1 ; U17.65 86.34,93.37 86.36,93.34 C419.2 87.03,92.74 87.1,92.67 C425.2 ; C705.2 v4(70.38,52.56) ; C680.2 v4(55.98,54.96) ; C393.2 142.61,99.3 v1(141.82,100.08) ; C182.1 v2(64.11,39.68) ; C477.2 v4(55.98,70.96) C473.2 ; C373.2 150.07,104.63 v1(149.82,104.88) 149.67,104.88 C377.2 149.02,105.79 C359.2 ; C677.2 v4(60.78,54.96) 61.55,55.73 C660.1 62.35,55.73 v4(62.38,55.76) C667.2 ; v1(135,40.71) 136.25,41.95 U73.10 ; R432.1 v2(83.4,71.63) ; C572.2 v4(55.98,63.76) ; C529.2 60.83,66.9 v4(60.78,66.96) C524.2 ; R559.2 v1(125.22,20.83) ; C309.2 v3(72.26,142.39) ; R321.1 v2(108.77,133.02) ; C647.2 v4(53.58,57.36) ; C371.1 48.58,105.5 48.09,105.01 U14.23 ; C173.1 v2(52.35,42.69) ; v1(151.42,108.08) 151.5,108 C369.2 ; U40.11 57.45,133.22 v2(57.31,133.07) ; C621.2 v4(51.98,58.96) ; v1(134.95,25.22) 134.96,25.23 Y7.4 133.82,26.43 v1(133.78,26.39) ; C184.1 v2(53.7,39.68) ; v2(137.34,82.55) C444.1 C442.1 ; C875.2 141.67,119.69 141.48,119.89 140.61,119.89 140.2,120.3 U79.2 ; C646.2 v4(55.18,57.36) ; C91.1 v2(65.63,79.75) ; v4(58.38,61.36) 58.76,60.98 C604.1 58.76,60.18 v4(59.18,59.76) ; U55.4 96.81,112.7 97.12,113 v2(97.56,113) ; C551.2 v4(71.18,65.36) ; U65.13 v2(22.53,66.1) ; C526.2 v4(57.58,66.96) ; R421.1 v2(122.62,76.71) ; C335.2 v1(55.45,129.59) ; C749.2 v2(36.11,41.21) ; C658.2 v4(57.58,56.56) ; C327.1 C326.2 114.43,131.4 U4.71 ; C712.2 60.81,51.8 v4(60.78,51.76) C714.2 ; C627.2 v4(60.78,58.16) 61.25,57.69 C632.1 62.05,57.69 v4(62.38,57.36) C642.2 ; C405.2 87.03,95.79 86.6,95.37 U17.63 ; C368.2 96.9,107.65 v2(97.47,108.22) ; v1(132.93,1.52) Y8.4 v1(131.7,2.79) ; C567.2 v4(66.38,63.76) ; C613.2 v4(68.78,58.96) ; v7(47.36,111.87) 47.61,112.12 U54.1 ; v8(95.81,119.52) 95.77,119.52 95.51,119.26 U49.8 ; C305.2 v3(77.85,142.39) ; U38.9 v2(137.67,138.19) ; R330.1 v2(67.94,125.98) ; C819.2 v1(131.77,22.12) ; R479.2 v4(51.18,52.56) ; C583.2 v4(53.58,62.96) ; R507.2 v1(127.22,42.44) ; C509.2 v4(58.38,67.76) ; C298.2 138.89,144.58 138.15,143.84 v2(137.77,143.84) R288.1 ; U77.10 134.22,18.27 133.94,17.99 133.15,17.99 132.97,17.81 v1(132.97,17.07) ; R434.1 v4(51.98,71.76) ; v4(55.18,61.36) 54.85,61.03 C606.1 54.85,60.23 v4(54.38,59.76) C609.2 ; C790.1 C789.2 98.98,31.67 v2(99.21,31.9) ; U78.A1 v4(130.37,108.07) ; C178.1 v2(72.24,39.68) ; C637.2 v4(70.38,57.36) ; C706.2 v4(68.78,52.56) C698.2 ; C635.2 27.37,57.36 27.38,57.35 v2(27.38,57.15) ; R478.2 v4(67.18,52.56) ; C96.1 v2(51.61,79.75) ; C320.2 v2(67.3,137.64) ; C404.2 68.63,97.92 68.3,97.59 68.3,96.75 U18.62 ; C715.2 v4(57.58,51.76) C719.2 ; R472.2 v4(51.18,57.36) ; C321.2 v3(56.01,137.52) ; v1(147.42,100.08) 147.85,100.51 C388.2 ; C664.2 v4(68.78,55.76) ; C353.2 89.05,114.75 89.36,114.45 v2(89.36,114.24) ; C783.1 v1(137.61,31.42) ; v4(61.18,74.33) 61.47,74.03 R431.1 ; v1(152.22,102.48) 151.4,103.3 C384.2 ; C92.1 v2(60.17,78.85) ; C565.2 v4(69.58,63.76) ; C397.2 81.76,96.8 82.19,96.37 U17.50 ; U18.53 64.54,92.99 64.16,92.99 64.01,92.84 C432.2 ; v2(81.14,58.02) 81.09,58.02 80.7,58.42 R469.2 ; C527.2 v4(55.98,66.96) ; v2(90.52,103.22) 90.52,103.5 90.73,103.71 91.16,103.71 R386.1 ; U74.8 U74.11 119.41,35.7 U74.4 ; C415.2 81.91,93.73 82.27,93.37 U17.53 ; v2(71.15,82.57) 71.04,82.67 C74.1 ; C674.2 v4(69.58,54.96) ; C541.2 v2(122.62,64.77) ; v2(107.67,66.88) 107.47,66.88 107.39,66.8 C530.1 C531.2 ; C795.1 v2(27.43,27.33) ; R576.2 v1(138.3,7.11) ; C734.2 133.88,45.7 v1(133.83,45.75) ; C590.2 v4(59.18,62.16) ; C379.2 138.98,104.52 v1(138.62,104.88) ; C347.2 v2(153.29,120.14) ; C651.2 v4(69.58,56.56) ; v1(142.62,102.48) 142.62,101.7 C387.2 ; C591.2 v4(57.58,62.16) ; C597.2 v4(65.58,61.36) 65.19,60.98 C603.1 65.19,60.18 v4(64.78,59.76) ; U78.A3 v4(128.77,108.07) ; C539.2 v4(59.98,66.16) ; v1(138.3,5.21) Y8.2 v1(137.07,6.31) ; C556.2 v4(63.98,64.56) ; v1(98.68,99.31) U57.10 ; C183.1 v2(55.09,40.58) ; C653.2 v4(66.38,56.56) ; U54.10 47.61,109.62 v7(47.36,109.87) ; v2(148.13,134.16) 148.11,134.18 C323.2 ; U54.19 45.56,112.62 46.31,111.87 v7(46.36,111.87) ; R320.1 v2(108.77,134.58) ; R341.2 102.42,120.86 102.18,120.62 v2(101.45,120.62) ; v1(145.02,104.08) 145.04,104.11 C364.2 ; C360.2 v1(158.44,107.52) ; C707.2 v4(63.98,52.56) ; v1(144.22,102.48) 144.22,103.29 C381.2 ; R296.2 v2(89.84,146.48) ; C717.2 v4(67.98,51.76) ; C562.2 v4(71.18,63.76) ; R462.2 26.31,62.26 v2(26.49,62.08) ; C559.2 v4(56.78,64.56) ; U78.B7 v4(125.74,106.87) ; C488.2 v4(68.78,69.36) C481.2 ; C675.2 v4(67.98,54.96) ; R654.2 50.93,92.33 51.1,92.16 51.91,92.16 52.48,92.72 v1(52.48,93.09) ; C544.2 v4(66.38,65.36) ; C650.2 v2(113.21,55.88) ; R464.2 v2(21.99,61.98) ; R293.2 v2(97.46,146.48) ; v4(73.58,63.76) C564.2 ; U37.2 54.97,142.86 54.64,142.53 54.64,140.95 54.89,140.7 C317.2 v2(55.38,139.8) ; C518.2 v2(82.25,67.39) ; R551.2 v1(140.34,30.75) ; C729.2 v4(58.38,48.56) ; C471.2 v4(68.78,72.56) ; C731.2 v2(15.68,49.38) ; R568.2 v1(125.22,16.26) ; U51.10 v3(46.11,120.77) ; v2(148.34,132.33) 147.66,132.33 147.55,132.23 C331.2 ; U38.8 v2(143.77,138.19) 143.77,137.29 144.03,137.04 U41.11 ; C528.2 62.27,66.27 v4(62.38,66.16) C538.2 ; v2(111.47,121.41) 111.46,121.41 C345.2 ; C168.2 v2(68.17,42.3) ; C547.2 v4(60.78,65.36) ; C555.2 v4(65.58,64.56) ; C626.2 v4(63.18,58.16) ; C510.2 v4(70.38,67.76) ; B6.2 v2(72.14,91.57) ; C711.2 v4(53.58,52.56) ; R442.2 v2(15.19,69.67) ; C629.2 v4(57.58,58.16) ; v3(46.01,139.54) U39.16 ; C554.2 v4(67.18,64.56) ; C659.2 v4(54.38,56.56) ; C535.2 v4(56.78,66.16) ; C557.2 v4(59.98,64.56) ; C581.2 v4(58.38,62.96) ; R500.2 v1(127.22,43.87) ; v1(159.51,130.64) 159.51,130.19 158.95,129.63 U47.1 ; J2.GE9 17.63,132.43 C896.1 ; v2(79.73,127.01) U43.16 ; C452.1 v2(57.45,81.77) ; R347.1 v2(110.05,118.47) ; C685.2 v4(68.78,54.16) ; U59.3 155.21,92.26 v2(155.07,92.41) ; v1(141.03,19.24) R563.2 ; C736.2 v2(111.82,44.7) ; C512.2 v4(63.98,67.76) ; 149.53,90.41 C433.1 ; U18.63 68.47,95.91 68.83,95.91 69.15,96.23 C406.2 ; R454.2 v4(69.58,65.36) ; C669.2 v4(55.18,55.76) ; C720.2 v4(70.38,50.96) ; R529.1 v2(123.92,37.92) ; U66.4 v2(118.62,61.85) ; C598.2 v4(53.58,61.36) ; v2(52.49,93.83) 52.37,93.7 C423.2 ; U18.51 64.39,95.37 64.27,95.25 C411.2 ; C451.1 v2(58.83,82.67) ; v1(145.02,108.08) 145.03,108.1 C363.2 ; C648.2 v4(51.98,57.36) ; C670.2 v4(53.58,55.76) ; C458.1 v2(69.95,78.85) ; R564.2 v1(125.22,17.78) ; U18.57 65.92,92.83 65.66,92.57 C431.2 ; v1(66.37,117.73) 66.67,117.43 U53.K8 ; C485.2 v4(58.38,69.36) R438.1 ; C470.2 v4(65.58,73.37) ; v1(154.56,102.51) 154.41,102.37 C385.2 ; v2(27.25,66.22) 27.69,66.65 R450.1 ; C380.2 146.13,103.77 v1(146.62,103.28) ; C515.2 v2(122.62,66.8) ; C314.2 147.74,141.19 147.96,140.97 v2(148.46,140.97) ; C568.2 v4(64.78,63.76) ; C537.2 v4(63.98,66.16) ; R444.2 v2(13.66,68.54) ; U17.62 85.8,97.36 86.36,97.92 C403.2 ; C665.2 v4(67.18,55.76) ; C689.2 v4(62.38,54.16) 61.99,53.78 C683.1 61.19,53.78 v4(60.78,53.36) ; R522.2 v4(85.24,36.44) ; C630.2 v4(55.98,58.16) ; R449.2 v4(52.78,66.96) ; C310.2 65.05,143.12 65.1,143.08 v3(65.18,143.08) ; U47.14 151.65,128.33 151.5,128.48 151.5,129.17 v1(151.3,129.37) ; C596.2 v4(67.18,61.36) ; C784.1 134.55,32.94 v1(134.54,32.94) ; C482.2 v4(67.18,69.36) ; R286.1 142.19,144.5 v2(142.19,143.84) ; C593.2 v4(54.38,62.16) ; C645.2 v4(56.78,57.36) ; C549.2 v4(57.58,65.36) ; C691.2 v4(72.78,54.16) ; R530.2 v1(127.25,36.78) ; C548.2 v4(59.18,65.36) ; C690.2 v4(56.78,54.16) ; C592.2 v4(55.98,62.16) ; C372.2 138.62,105.69 v1(137.82,104.88) ; U78.J1 v4(130.37,100.87) ; C308.2 v3(73.66,142.39) ; C522.2 v4(64.78,66.96) ; U64.4 v2(115.82,71.5) ; C608.2 v4(66.38,59.76) ; C468.2 v2(111.82,78.11) ; C483.2 v4(62.38,69.36) 61.91,69.36 61.59,69.67 R436.1 ; R572.2 v1(125.22,13.21) ; C638.2 v4(68.78,57.36) ; C401.2 64.43,97.72 64.92,97.23 U18.50 ; C616.2 v4(63.98,58.96) ; C501.2 v4(57.58,68.56) ; C575.2 v4(65.58,62.96) ; C721.2 v4(73.58,50.96) ; R571.2 v1(125.22,14.73) ; C90.1 v2(67.01,78.85) ; C620.2 v4(53.58,58.96) ; C521.2 v4(66.38,66.96) ; C519.2 v4(69.58,66.96) ; C652.2 v4(67.98,56.56) ; R608.1 v1(68.33,3.94) ; U44.16 77.36,125.58 v2(77.39,125.55) ; C570.2 v4(59.18,63.76) ; C697.2 v4(69.58,53.36) ; R358.2 v2(164.97,112.78) ; C304.2 v3(62.8,142.52) ; C391.1 48.58,99.22 48.14,98.79 U16.23 ; U53.F7 v1(66.27,114.3) ; C716.2 v4(55.98,51.76) ; R445.2 v4(67.18,67.76) ; C89.2 v2(68.38,79.75) ; C166.1 v2(72.11,42.3) ; C362.2 v2(119.38,107.7) ; C486.2 v4(56.78,69.36) ; C490.2 v4(54.38,68.56) ; C579.2 v4(63.98,62.96) ; C534.2 v4(65.58,66.16) ; C644.2 v4(58.38,57.36) ; U52.4 v2(170.17,120.14) ; C694.2 v4(58.38,54.16) ; v2(156.77,100.74) 156.77,100.71 C389.2 ; C180.1 v2(68.17,39.68) ; v2(79.11,127.66) U43.17 ; U78.C3 v4(128.77,106.47) ; C576.2 v4(70.38,62.96) ; C587.2 v4(67.98,62.16) ; U65.8 v2(19.15,68.7) ; v1(141.82,105.68) 142.69,106.56 C365.2 ; R514.2 v1(127.22,39.6) ; C617.2 v4(59.98,58.96) ; C640.2 v4(65.58,57.36) ; R467.2 v4(71.18,59.76) ; v2(157.1,80.21) 157.87,80.21 158.05,80.39 U61.5 ; C737.2 v2(122.62,42.44) ; C679.2 v4(57.58,54.96) ; C334.2 v2(56.82,129.62) ; U67.1 v2(116.71,57.03) ; C386.2 144.58,102.05 v1(145.02,102.48) ; C479.2 v4(65.58,69.36) ; v2(79.11,126.36) U43.15 ; R460.2 v4(54.38,63.76) ; C709.2 v4(59.98,52.56) ; C678.2 v4(59.18,54.96) ; v3(150.1,22.24) 150.11,22.24 150.22,22.35 C815.2 ; C676.2 v4(63.18,54.96) ; C787.2 v1(132.31,31.25) ; C847.2 v1(131.06,6.99) ; C725.2 v4(51.18,50.16) ; U78.D7 v4(125.74,105.27) ; C316.2 v2(60.25,140.7) ; C520.2 v4(68.78,66.16) ; C622.2 v4(69.58,58.16) ; C589.2 v4(64.78,62.16) ; C614.2 v4(67.18,58.96) ; C611.2 v4(73.58,58.96) ; C171.1 v2(55.09,42.69) ; C416.2 64.28,93.73 U18.52 ; R348.2 v2(144.65,117.6) ; C724.2 v2(121.23,49.4) ; C735.2 v1(135.83,45.69) ; U44.10 75.41,132.77 75.62,132.56 v2(75.92,132.56) ; U65.12 v2(22.83,66.75) ; R351.2 v2(111.58,118.75) ; U44.15 78.01,124.96 v2(77.9,124.85) ; C663.2 v4(70.38,55.76) ; C618.2 v4(58.38,58.96) ; C578.2 v4(67.18,62.96) ; C502.2 v4(55.98,68.56) ; C358.1 v1(108.2,108.71) ; v2(45.22,131.99) C332.2 ; R465.2 v4(71.18,62.16) ; C672.2 v4(65.58,55.76) ; C429.2 68.59,92.02 67.92,92.68 67.92,93.37 U18.65 68.46,93.37 68.48,93.34 C420.2 ; U39.17 v3(46.66,139) ; C701.2 v4(59.18,53.36) ; C514.2 v4(55.18,67.76) ; C656.2 v4(60.78,56.56) ; C643.2 v4(59.98,57.36) ; C566.2 v4(67.98,63.76) ; C543.2 v4(67.98,65.36) ; C542.2 v2(111.82,64.92) ; C169.2 v2(66.14,43.2) ; Q10.3 v2(68.88,140.08) ; C730.2 v2(27.37,47.84) ; C472.2 v4(72.78,72.56) ; R439.2 v2(23.12,70.87) ; C75.1 v2(69.77,81.77) ; v2(130.05,139.16) 130.08,139.16 130.43,138.81 C319.2 ; C612.2 v4(70.38,58.96) ; R344.1 v2(84.58,120.57) ; C628.2 v4(59.18,58.16) ; v2(130.05,141.66) 130.56,141.66 130.87,141.96 C312.2 ; C577.2 v4(68.78,62.96) ; C700.2 v4(63.18,53.36) ; C392.2 144.63,99.3 145.02,98.91 v1(145.02,98.48) ; v8(87.5,117.72) 87.76,117.98 C348.2 ; R327.1 v1(170.25,126.34) ; v2(130.05,140.16) 130.05,140.16 C318.2 ; C496.2 v4(66.38,68.56) ; v2(116.97,116.2) 116.97,116.71 116.66,117.02 C349.2 C350.2 ; C560.2 v4(55.18,64.56) ; C588.2 v4(66.38,62.16) ; C666.2 v4(63.98,55.76) ; R308.2 v2(65.52,141.42) ; C571.2 v4(57.58,63.76) ; C511.2 v4(65.58,67.76) ; v2(27.88,43.05) C746.2 ; v1(147.42,96.88) 147.57,97.04 C399.2 ; C552.2 v4(70.38,64.56) ; C167.1 v2(70.21,43.2) ; C558.2 v4(58.38,64.56) ; C845.1 v1(132.52,9.28) ; C655.2 v4(63.18,56.56) ; R294.2 v2(94.92,146.48) ; C489.2 v4(63.98,69.36) ; U78.E3 v4(128.77,104.07) ; v2(108.08,127.76) R33.2 ; C625.2 v4(64.78,58.16) ; U70.5 v2(22.95,51.37) ; C641.2 v4(63.98,57.36) ; U53.C5 v1(63.87,111.1) ; C179.1 v2(70.21,40.58) ; C546.2 v4(63.18,65.36) ; U43.10 v2(86.84,128.96) ; C699.2 v4(64.78,53.36) ; v1(145.82,100.08) 146.07,99.83 C390.2 ; C718.2 v4(66.38,51.76) ; C450.1 v2(60.17,81.77) ; R509.2 v1(127.22,41.02) ; U69.1 v2(116.71,51.19) ; C791.1 v1(26.72,31.06) ; C657.2 v4(59.18,56.56) ; C580.2 v4(59.98,62.96) ; C561.2 v4(53.58,64.56) ; C185.1 v2(52.27,40.58) ; U62.B1 25.78,77.09 ; C475.2 v4(73.58,70.96) ; R284.1 v2(145.16,143.89) ; C170.1 v2(64.11,42.3) ; v2(24.54,28.79) Y6.4 ; v2(15.22,4.6) R585.2 ; R332.2 v1(155.19,125.22) ; C498.2 v4(63.18,68.56) ; C713.2 v4(69.58,51.76) ; C661.2 v2(121.23,55.25) ; R417.2 v2(161.22,81.92) ; C818.2 v1(133.8,22.12) ; C299.2 v2(110.49,145.64) ; Y6.2 v2(19.94,32.93) ; C703.2 v4(55.98,53.36) ; C668.2 v4(56.78,55.76) ; v3(47.96,135.92) U39.10 ; C688.2 v4(63.98,54.16) ; C540.2 v4(53.58,66.16) ; U42.7 v2(134.24,133.48) ; C654.2 v4(64.78,56.56) ; C553.2 v4(68.78,64.56) ; C722.2 v2(113.21,50.04) ; C536.2 v4(70.38,66.16) ; U68.7 v2(25.71,54.06) ; C324.2 v1(161.4,132.78) ; C487.2 v4(70.38,69.36) ; C692.2 v4(65.58,54.16) ; C525.2 v4(59.18,66.96) ; C181.1 v2(66.14,40.58)
  BOTTOM w0.305: v1(142.44,119.25) 142.19,119 C875.2 ; U80.12 47.21,86.87 46.96,87.12 v9(46.96,87.76) 47.71,87.01 U80.11 ; C872.1 v1(11.31,35.94) ; v9(45.96,87.76) 45.71,87.51 U80.13
  BOTTOM w0.381: U72.5 v2(23.17,44.79) ; R605.1 v6(98.93,10.67) 98.93,10.66 ; C888.2 v1(169.93,8.66) ; v6(163.45,97.78) FB17.2 v6(163.45,98.93) ; v2(38.81,50.49) 38.81,50.49 R488.2 C728.1 ; R609.1 144.4,57.16 v8(143.93,57.62) ; C886.2 v1(171.45,8.71) ; U54.21 v7(47.36,110.87) ; C889.2 167.71,22.33 v2(167.36,22.68) ; R607.1 102.95,14.27 v6(102.49,14.73) 102.87,15.11 C829.2 ; R552.2 41.02,30.73 v3(41.15,30.86) ; v6(102.49,12.7) 102.78,12.41 R606.1 ; C895.2 v2(148.21,29.08) ; C830.2 100.08,15.37 v6(100.71,14.73) 101.09,14.73 101.47,15.11 R569.2 ; 18.3,22.53 J8.2 ; J8.2 18.3,23.95 ; J8.2 19.71,23.95 ; J8.2 19.71,22.53 ; C777.2 156.77,34.62 v3(156.72,34.67) ; v2(100.96,107.04) 101.75,107.04 102.35,106.43 R385.1 ; v2(94.46,91.03) 94.56,91.12 C57.1 ; Q11.2 v2(175.83,128.14) ; C801.2 C802.1 v2(29.34,25.9) ; v6(98.93,14.73) 98.93,15.35 R604.1 ; v2(166.67,134.11) 166.73,134.16 C322.2 ; 18.3,19.99 J8.3 ; J8.3 18.3,21.41 ; J8.3 19.71,21.41 ; J8.3 19.71,19.99 ; v6(145.16,24.51) 145.16,25.43 145.1,25.49 Q15.4 ; C601.2 72.73,61.31 v4(72.78,61.36) ; C313.1 v2(119.76,141.25) ; C890.2 v2(166.9,20.83) ; U51.21 v7(47.36,117.6) ; R655.1 42.35,87.83 v1(41.4,88.77) 42.09,89.47 R642.1 ; v2(44.81,49.99) 44.3,50.49 C726.2 C727.2 ; v6(102.49,10.67) 103.96,10.67 104.46,10.17 C843.2 ; v2(32.13,25.9) C800.2 C799.2 ; v6(162.69,93.34) FB18.2 v6(162.69,94.49) ; v7(64,9.51) 62.96,9.51 C842.2 ; v2(30.99,55.51) 30.17,54.69 C696.2 29.42,54.69 v2(28.6,55.51) ; C374.2 R386.1 ; v6(147.5,87.63) FB19.2 v6(148.65,87.63) ; FB19.4 v6(149.8,87.63) ; v2(162.76,31.47) 163.03,31.21 C891.2 ; v2(175.7,123.19) Q12.2 ; Q14.2 v2(175.7,113.79) ; Q13.2 v2(175.7,118.36) ; C762.2 v1(150.24,37.28) ; U76.4 45.85,37.59 v2(45.35,38.09) ; v2(73.51,86.12) 73.5,86.12 73.11,85.74 73.06,85.74 72.71,85.39 C441.2 ; C835.2 v1(148.21,14.73) ; v2(44.2,28.32) C796.2 ; v4(68.78,61.36) 68.61,61.2 C602.2 ; v2(120.7,143.05) C300.2 119.96,143.72 119.51,144.17 U36.2 ; C759.2 v1(143.48,39.3) ; R590.1 52.25,2.84 v7(52.83,3.43) ; R650.1 v2(146.69,29.08) ; C892.2 v2(161.81,31.87) ; FB18.4 v6(162.69,95.64) ; FB17.4 v6(163.45,100.08) ; v8(154.85,70.01) 154.38,70.47 R610.1 ; C747.2 v2(15.68,40.88) ; v3(127.51,142.88) 127.82,143.19 C303.2 ; C633.2 v2(15.68,57.11) ; R648.2 v2(140.74,29.84)
  BOTTOM w0.406: C594.2 16.36,61.02
  BOTTOM w0.483: AMC1.34 v3(8.56,30) ; AMC1.37 v3(8.56,32.25) ; AMC1.85 8.23,68.25 v3(8.56,67.92) ; AMC1.13 v3(8.56,14.25) ; AMC1.76 v3(8.56,61.5) ; AMC1.52 v3(8.56,43.5) ; AMC1.1 8.91,5.25 9.37,5.71 v3(9.4,5.71) ; AMC1.22 v3(8.56,21) ; AMC1.43 v3(8.56,36.75) ; AMC1.25 v3(8.56,23.25) ; AMC1.10 v3(8.56,12) ; AMC1.28 v3(8.56,25.5) ; AMC1.67 v3(8.56,54.75) ; AMC1.7 v3(8.56,9.75) ; AMC1.64 v3(8.56,52.5) ; AMC1.79 v3(8.56,63.75) ; AMC1.70 v3(8.56,57) ; AMC1.40 v3(8.56,34.5) ; AMC1.16 v3(8.56,16.5) ; AMC1.19 v3(8.56,18.75) ; AMC1.46 v3(8.56,39) ; AMC1.73 v3(8.56,59.25) ; AMC1.31 v3(8.56,27.75) ; AMC1.49 v3(8.56,41.25) ; AMC1.61 v3(8.56,50.25) ; AMC1.55 v3(8.56,45.75) ; AMC1.58 v3(8.56,48) ; AMC1.82 v3(8.56,66)
  BOTTOM w0.508: C517.2 32.95,68.01 v3(33.08,67.88) ; C887.2 v2(161.15,8.75) ; v3(90.77,99.06) 90.74,99.09 B5.2 ; v2(68.17,88.16) 67.61,88.73 C66.2 65.39,88.73 v2(65.1,88.44) 64.9,88.65 C437.2 62.48,88.65 v2(62,88.16) 61.52,88.65 C65.2 59.74,88.65 v2(59.23,88.14) 58.89,88.48 C62.2 58.2,88.48 v2(57.81,88.09) ; C594.2 15.63,61.85 B7.2 ; C798.2 v3(87.58,26.92) ; C885.2 v2(158,8.64)
  BOTTOM w0.635: v1(146.28,41.78) 146.29,41.77 C748.2
  BOTTOM w0.889: FAN1.1 83.63,29.09 C797.2
  vias: v1(8.58,108.21) v1(8.58,103.21) v1(8.58,98.21) v1(8.58,93.21) v1(10.57,108.21) v1(10.57,103.21) v1(10.57,98.21) v1(10.57,93.21) v1(10.81,65.59) v1(10.81,64.11) v1(10.81,63.34) v1(10.81,61.86) v1(10.81,42.37) v1(10.81,37.87) v1(11.28,19.87) v1(12.08,13.12) v1(14.11,70.66) v1(14.7,29.41) v1(14.7,26.63) v1(25,36.54) v1(25,35.06) v1(25,33.74) v1(25,32.27) v1(27.79,34.94) v1(27.84,33.49) v1(28.19,36.23) v1(30.44,42.19) v1(30.75,65.15) v1(31.66,28) v1(31.92,42.19) v1(33.05,27.99) v1(33.4,65.63) v1(33.4,64.18) v1(33.57,28.46) v1(35.79,65) v1(35.79,63.54) v1(35.84,55.57) v1(35.97,46.56) v1(35.97,45.1) v1(36.22,59.38) v1(36.22,57.93) v1(36.76,61.11) v1(37.92,71.63) v1(37.92,69.8) v1(38.26,60.45) v1(38.26,59) v1(38.54,67.75) v1(38.54,66.58) v1(38.71,62.08) v1(39.25,55.4) v1(39.25,53.94) v1(40.8,48.59) v1(40.8,47.13) v1(122.3,103.27) v1(125.86,6.35) v1(125.86,5.33) v1(125.86,4.45) v1(127.84,30) v1(127.79,29.03) v1(127.79,28.12) v1(130.95,17.07) v1(130.95,15.05) v1(132.98,40.71) v1(132.98,38.68) v1(132.97,15.05) v1(135,38.68) v1(134.99,17.07) v1(134.99,15.05) v1(135.48,101.57) v1(137.11,101.58) v1(141.6,32.26) v1(141.6,31.6) v1(141.73,9.4) v1(142.88,17.91) v1(142.88,9.4) v1(143.64,16) v1(144.37,31.62) v1(144.91,39.52) v1(144.91,38.86) v1(145.8,31.62) v1(150.47,14.73) v1(150.93,139.45) v1(152.6,14.73) v1(152.7,26.62) v1(154.28,26.62) v1(162.07,62.11) v1(162.07,60.08) v1(163.8,64.02) v1(163.8,61.98) v1(164.18,60.21) v1(164.18,58.17) v1(173.99,32.89) v1(173.99,32.13) v1(174.88,32.89) v1(174.88,32.13) v2(27.37,25.97) v2(27.37,24.95) v2(27.37,23.94) v2(41.38,145.95) v2(41.38,144.55) v2(42.52,145.95) v2(42.52,144.55) v2(55.04,4.62) v2(75.16,3.39) v2(76.31,3.39) v2(80.82,17.5) v2(80.82,16.36) v2(82.35,17.5) v2(82.35,16.36) v2(97.42,24.89) v2(98.87,24.87) v2(100.26,24.87) v2(107.14,122.43) v2(107.14,121.69) v2(108.72,24.89) v2(110.17,24.87) v2(111.57,24.87) v2(111.76,142.88) v2(112.78,142.88) v2(112.78,141.99) v2(117.47,140.21) v2(117.55,138.95) v2(124.46,97.63) v2(125.4,97.65) v2(125.6,132.08) v2(131.07,89.36) v2(131.08,88.4) v2(131.88,89.36) v2(131.93,88.4) v2(134.11,81.43) v2(134.11,80.67) v2(134.95,81.46) v2(134.95,80.7) v2(141.27,88.6) v2(142.01,89.46) v2(142.04,88.6) v2(144.7,76.94) v2(146.23,89.05) v2(146.23,88.11) v2(149.55,94.51) v2(149.53,89.46) v2(152.93,79.17) v2(152.96,80.09) v2(153.95,79.17) v2(153.97,80.09) v2(155.93,95.26) v2(157.25,95.26) v2(158.29,91.85) v2(159.38,91.85) v2(160.48,91.87) v2(162.17,8.75) v2(164.26,96.04) v2(165.46,143) v2(166.27,143) v2(167.03,143) v2(167,97.03) v2(167,96.14) v2(167,95.25) v2(170.92,106.71) v2(171.04,142.06) v2(171.04,141.25) v2(171.73,106.71) v2(175.09,106.93) v2(175.8,106.93) v3(26.52,79.68) v3(28.73,76.94) v3(28.73,76) v3(29.16,80.64) v3(30.12,74.65) v3(30.53,72.42) v3(41.15,31.75) v3(47.75,32.51) v3(47.75,31.62) v3(47.9,83.44) v3(47.9,81.66) v3(49.53,37.97) v3(50.5,37.97) v3(79.15,30.53) v3(79.15,29.57) v3(80.11,30.53) v3(80.11,29.57) v3(80.77,6.1) v3(80.77,4.95) v3(81.92,6.1) v3(81.92,4.95) v3(110.87,62.15) v3(110.87,59.36) v3(110.87,56.06) v3(110.87,52.88) v3(110.87,49.45) v3(112.32,39.62) v3(112.32,38.48) v3(113.72,39.62) v3(113.72,38.48) v3(115.06,39.65) v3(115.06,38.51) v3(115.95,31.11) v3(116.84,31.11) v3(118.39,30.75) v3(118.49,40.41) v3(118.49,39.27) v3(118.49,38.25) v3(119.63,38.25) v3(119.91,30.75) v3(124.66,31.14) v3(125.58,31) v3(125.94,32.57) v3(136.12,60.08) v3(136.12,59.19) v3(137.52,60.08) v3(137.52,59.19) v3(138.02,66.34) v3(138.02,64.95) v3(139.42,66.34) v3(139.42,64.95) v3(142.14,22.17) v3(142.14,21.36) v3(144.3,20.62) v3(144.3,19.81) v3(158.17,61.95) v3(158.17,61.06) v3(159.41,31.83) v3(159.56,61.95) v3(160.81,31.83) v3(161.29,68.45) v3(161.29,67.56) v3(162.69,68.45) v3(162.69,67.56) v3(163.12,109.52) v3(164.08,109.52) v3(165.94,50.16) v3(167.26,50.16) v3(168.66,50.16) v3(170.74,50.6) v3(170.74,49.2) v3(172.14,50.6) v3(172.14,49.2) v6(18.06,60.76) v6(25.86,69.93) v6(27.05,69.98) v6(32.12,35.41) v6(32.12,33.81) v6(32.12,32.21) v6(33.57,35.41) v6(33.57,33.81) v6(35.02,35.41) v6(35.02,33.81) v6(35.02,32.21) v6(40.01,7.11) v6(40.01,5.71) v6(40.01,4.32) v6(41.4,7.11) v6(41.4,5.71) v6(41.4,4.32) v6(43.84,19.18) v6(43.84,17.78) v6(45.24,19.18) v6(45.24,17.78) v6(46.63,19.18) v6(46.63,17.78) v6(55.24,22.1) v6(55.24,20.7) v6(56.64,27.18) v6(56.64,25.78) v6(56.64,22.1) v6(56.64,20.7) v6(56.64,16.76) v6(56.64,15.37) v6(57.38,35.79) v6(57.38,33.76) v6(57.38,31.72) v6(57.38,29.69) v6(59.92,33.93) v6(59.92,31.47) v6(59.92,29.69) v6(83.06,8.64) v6(83.06,7.24) v6(84.33,8.64) v6(84.33,7.24) v6(98.93,12.7) v6(100.71,12.7) v6(100.71,10.67) v6(111.12,11.56) v6(112.52,11.56) v6(116.81,94.36) v6(116.81,92.96) v6(116.81,28.65) v6(116.81,27.25) v6(122.3,9.47) v6(122.3,8.08) v6(122.35,17.88) v6(122.35,16.48) v6(123.75,17.88) v6(123.75,16.48) v6(123.7,9.47) v6(123.7,8.08) v7(46.36,117.6) v7(46.36,110.87) v7(46.36,109.87) v7(47.36,118.6) v7(52.83,2.06) v7(53.34,2.74) v7(53.82,3.43) v7(54.19,118.93) v7(54.19,117.93) v7(54.19,112.02) v7(54.19,111.02) v7(54.19,110.02) v7(55.19,118.93) v7(55.19,116.93) v7(55.19,112.02) v7(55.19,110.02) v7(64,11.01) v7(64,10.26) v7(64,8.01) v7(64,7.26) v7(64,6.51) v7(64.75,11.01) v7(64.75,10.26) v7(64.75,9.51) v7(64.75,8.76) v7(64.75,8.01) v7(64.75,7.26) v7(64.75,6.51) v7(65.5,11.01) v7(65.5,10.26) v7(65.5,9.51) v7(65.5,8.76) v7(65.5,8.01) v7(65.5,7.26) v7(65.5,6.51) v7(143.64,81.65) v7(143.64,80.65) v7(144.15,81.15) v7(144.65,81.65) v8(86.49,117.72) v8(87.5,116.72) v8(95.81,120.52) v8(96.75,125.65) v8(96.77,120.52) v8(96.77,119.51) v8(96.77,113.46) v8(142.93,56.62) v8(143.93,56.62) v8(154.85,71.01) v8(155.85,71.01) v8(162.04,136.66) v8(162.04,135.76) v8(162.04,134.86) v8(162.94,136.66) v8(162.94,135.76) v8(162.94,134.86) v8(163.84,136.66) v8(163.84,135.76) v9(45.96,90.76) v9(45.96,89.76) v9(45.96,88.76) v9(46.96,89.76) v9(46.96,88.76)
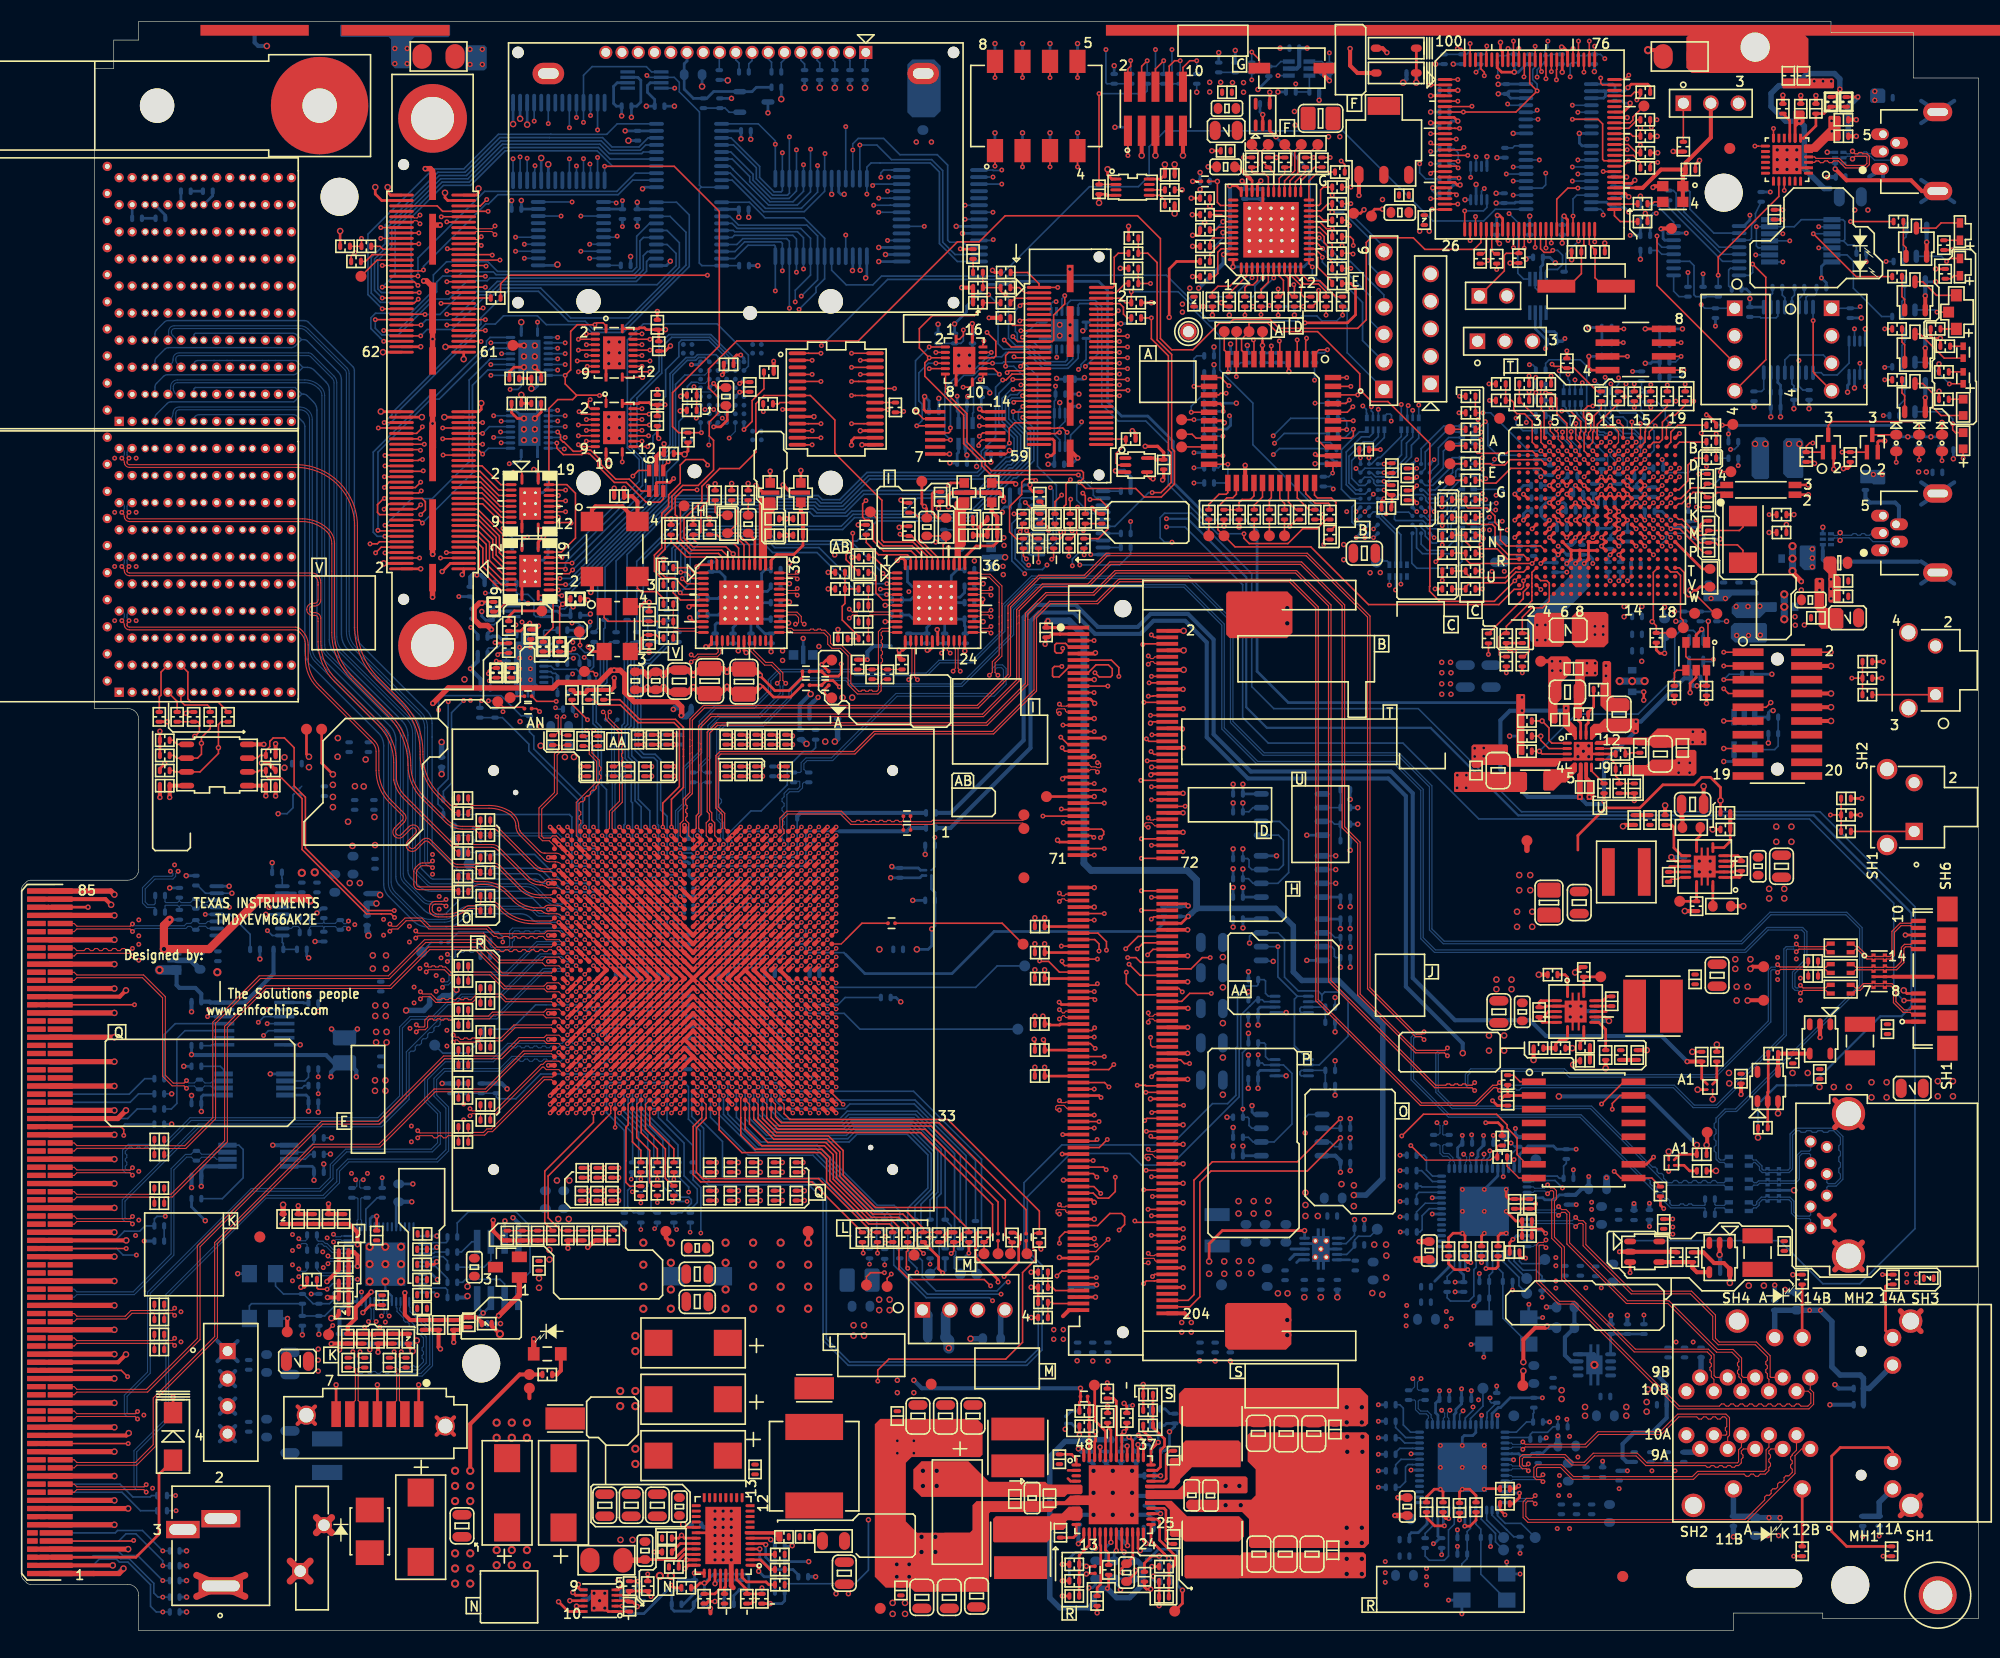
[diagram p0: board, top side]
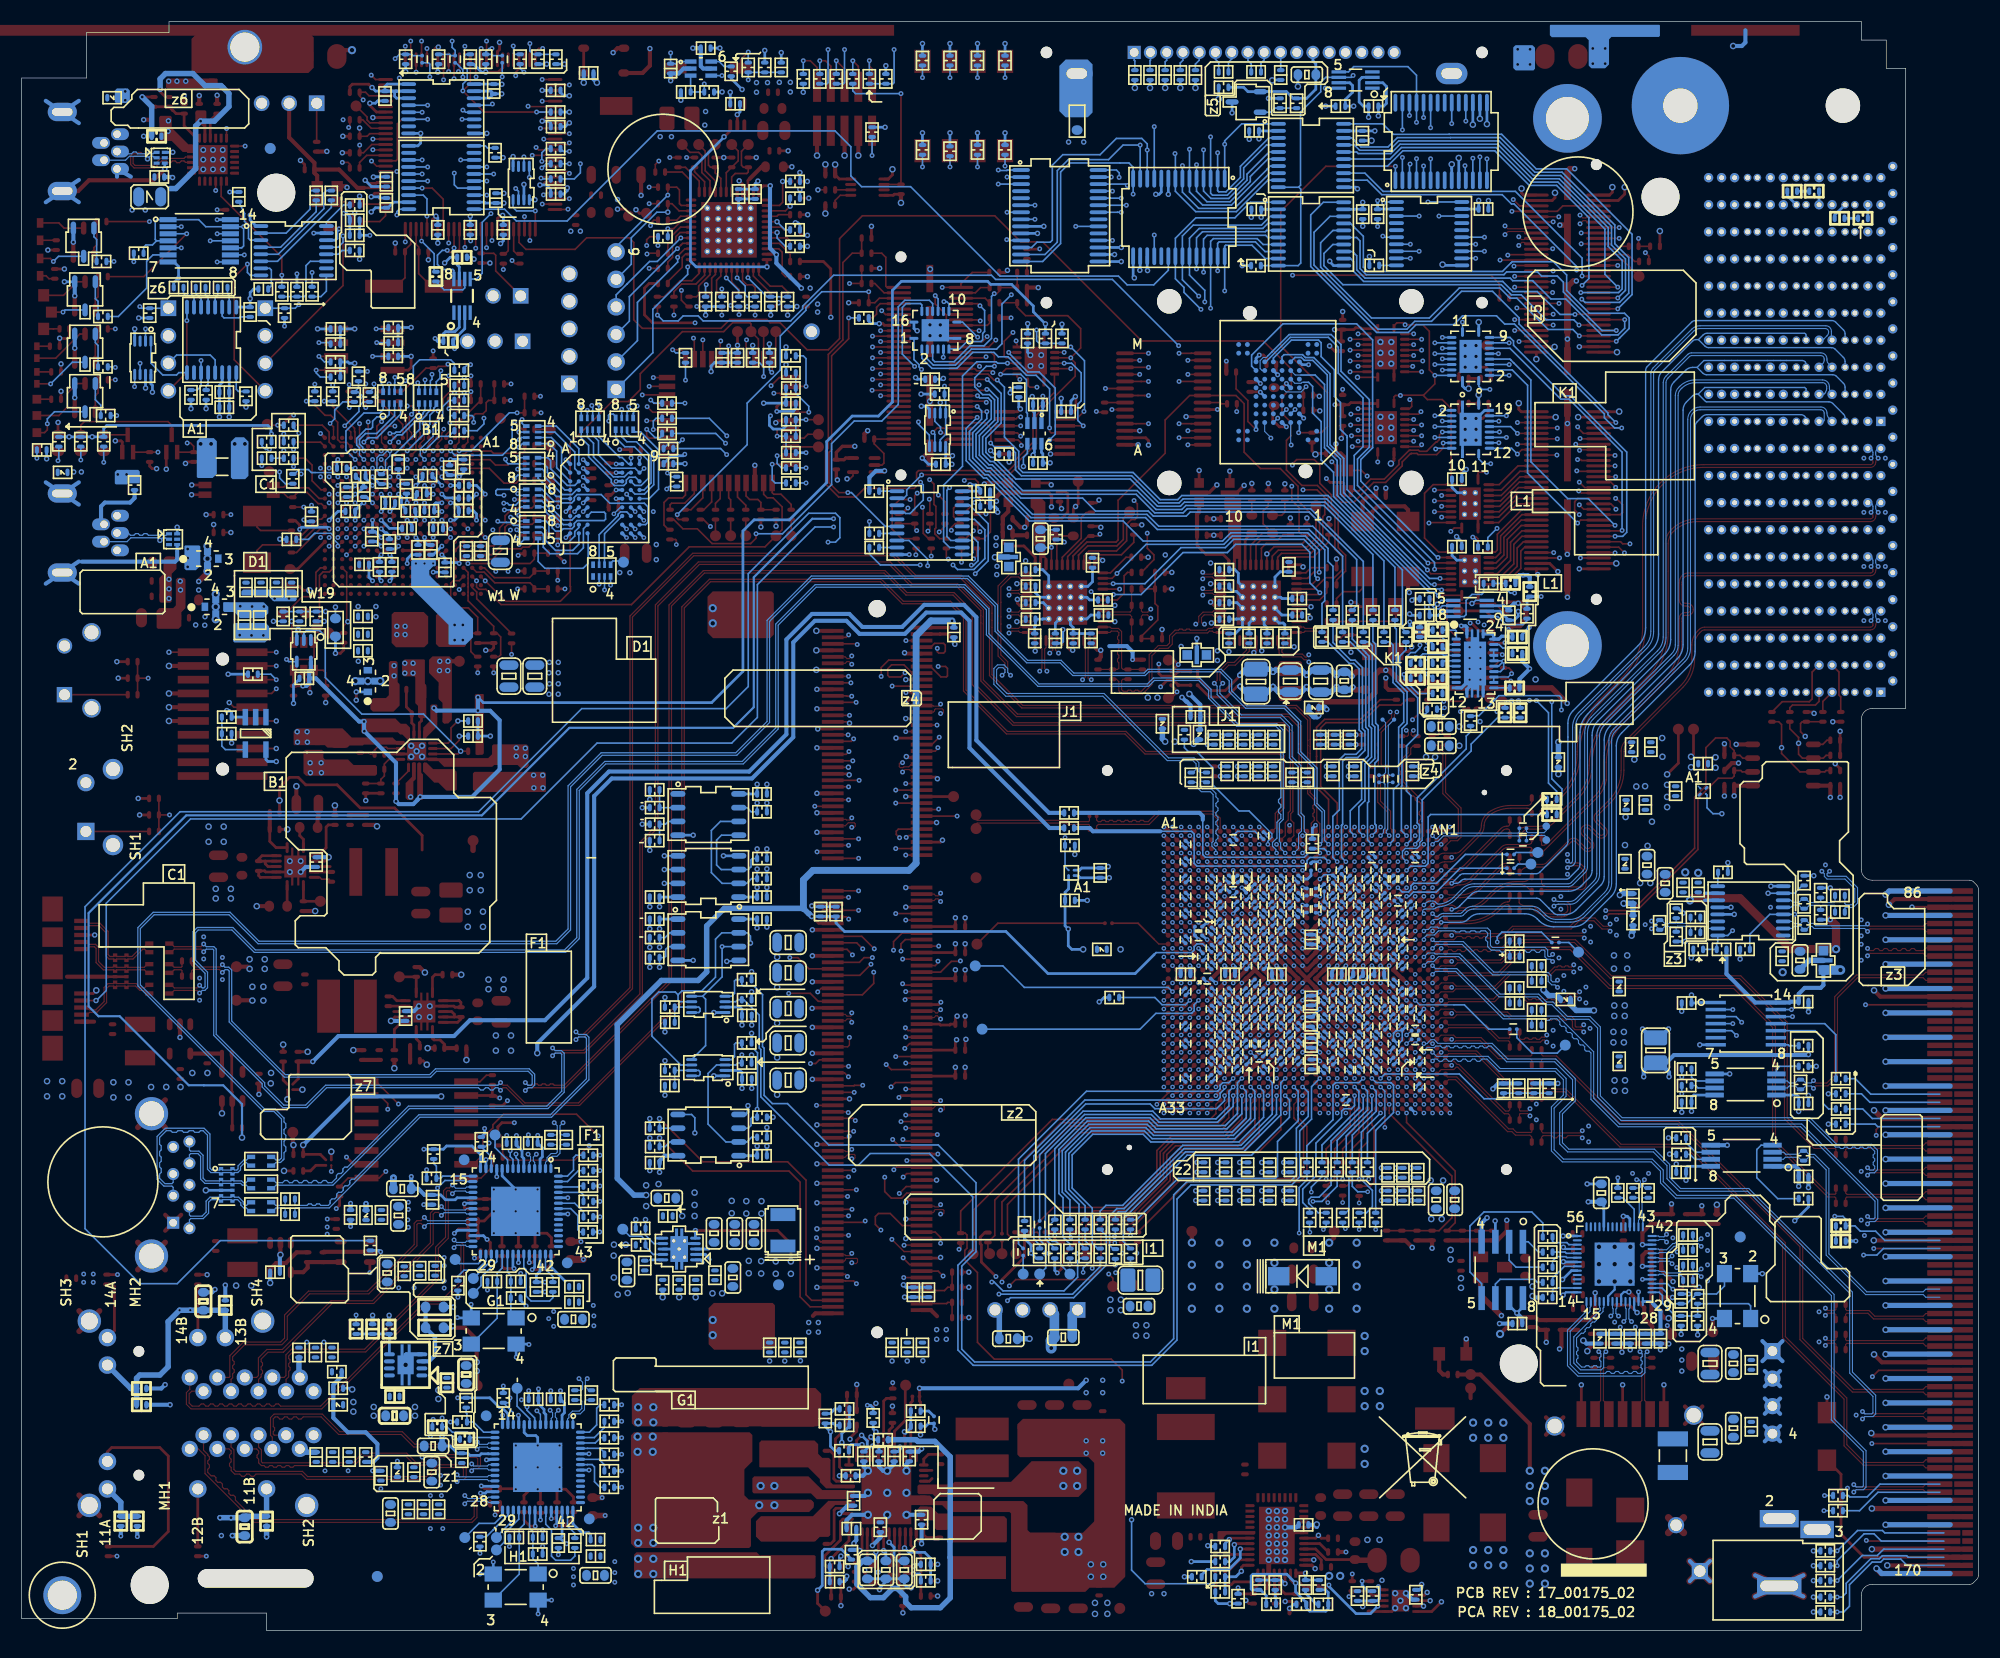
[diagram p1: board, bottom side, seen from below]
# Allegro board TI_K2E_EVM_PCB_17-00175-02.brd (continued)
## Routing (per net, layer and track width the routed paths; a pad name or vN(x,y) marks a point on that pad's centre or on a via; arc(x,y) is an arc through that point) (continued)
GND_3: length 12.9
  TOP w0.254: U4.36 112.57,132.93 112.14,133.35 v2(111.51,133.35) ; v2(110.94,127) 110.98,127.04 U4.47
  BOTTOM w0.381: v2(108.64,123.9) 110.94,126.2 v2(110.94,127) 111.53,127.59 111.53,133.33 v2(111.51,133.35)
  vias: v2(107.82,123.9)
GND_LAN: length 32.7
  TOP w0.508: 173.41,10.6 J9.SH1 ; J9.SH1 175.3,10.6 ; J9.SH1 175.3,12.48 ; 173.41,29.49 J9.SH3 ; J9.SH3 175.3,27.61 ; J9.SH3 175.3,29.49
  L8_SIG3 w0.381: 153.35,12.48 J9.SH2 ; J9.SH2 155.24,10.6 ; J9.SH2 153.35,10.6 ; J9.SH2 155.24,12.48 ; J9.10A 154.36,18.73 ; J9.10A 152.95,18.73 ; J9.10A 152.95,17.31 ; 152.95,21.37 J9.10B ; J9.10B 154.36,21.37 ; J9.10B 152.95,22.79 ; 157.41,29.49 J9.SH4 ; J9.SH4 159.3,27.61 ; J9.SH4 159.3,29.49 ; J9.SH4 157.41,27.61 ; J9.SH3 175.3,29.49 ; J9.SH3 175.3,27.61 ; J9.SH3 173.41,29.49 ; J9.SH1 175.3,12.48 ; J9.SH1 175.3,10.6 ; J9.SH1 173.41,10.6
GND_USB: length 21.9
  TOP w0.381: v2(167.39,134.9) 168.44,133.86 174.4,133.86 175.39,132.86 J1.6
  BOTTOM w0.254: D13.4 v2(167.39,134.9)
  BOTTOM w0.381: 175.33,139.13 J1.7 ; J1.7 178.37,141.19 ; J1.7 175.33,141.19 ; J1.6 178.37,131.83 ; J1.6 175.33,133.89 ; J1.6 175.33,131.83
VBAT: length 17.4
  TOP w0.254: U1.55 149,133.16
  TOP w0.381: OSC1.4 OSC1.1 153.33,134.28 153.58,134.53 C10.1 ; C10.1 153.58,135.47 155.91,137.8 CN1.2 ; C10.1 151.31,134.85 149.62,133.16 149,133.16
VBUS0: length 125.8
  TOP w0.254: U29.A1 153.03,43.94 C164.1 v3(154.62,44.81)
  L3_SIG1 w0.381: v3(133.01,53.29) 134.57,51.73 139.44,51.73 v3(141.88,49.29)
  BOTTOM w0.381: R426.1 85.72,74.07 93.12,81.46 93.12,93.19 93.88,93.95 97.1,93.95 99.07,91.99 103.27,91.99 104.47,93.19 107.39,93.19 109.38,91.2 109.38,82.45 113.19,78.64 126.13,78.64 127.76,77.02 127.76,59.43 133.01,54.18 v3(133.01,53.29) ; v3(154.62,44.81) 150.13,49.29 141.89,49.29 v3(141.88,49.29)
VBUS0_R: length 27.8
  TOP w0.152: U23.W5 v4(59.98,70.96)
  BOTTOM w0.152: 75.5,73.77 72.63,73.77 72.38,73.52 72.38,70.81 72.13,70.55 62.21,70.55 61.96,70.8 61.96,71.07 61.68,71.35 60.37,71.35 v4(59.98,70.96)
  BOTTOM w0.381: 75.5,73.77 81.72,73.77 82.02,74.07 R426.2
VBUS1: length 121.2
  TOP w0.254: U28.A1 155.07,50.93 C151.1
  TOP w0.381: C151.1 v2(153.73,52.51)
  BOTTOM w0.381: v2(153.73,52.51) 151.37,54.86 140.69,54.86 139.23,56.32 132.3,56.32 128.4,60.23 128.4,77.28 126.4,79.28 113.45,79.28 110.02,82.71 110.02,91.47 107.65,93.83 104.21,93.83 103,92.63 99.33,92.63 97.29,94.67 93.62,94.67 92.48,93.52 92.48,82.17 85.78,75.46 R424.1
VBUS1_R: length 27.2
  TOP w0.254: U23.V4 v4(60.78,71.76)
  BOTTOM w0.152: v4(60.78,71.76) 61.82,71.76 62.21,71.37 71.34,71.37 71.58,71.61 71.58,74.83
  BOTTOM w0.381: 71.58,74.83 71.58,75.17 71.88,75.46 R424.2
VCC0V75: length 130.7
  TOP w0.254: v3(109.6,34.06) 109.6,35.69 110.82,36.9 v2(118.41,36.9) ; R41.2 106.6,126.36 105.92,125.68 v2(105.92,121.21)
  TOP w0.381: 96.11,29.01 96.67,29.57 DIMM1.203 ; DIMM1.204 107.33,29.27 107.57,29.03
  L3_SIG1 w0.254: v2(105.92,121.21) 105.92,115.73 110.76,110.9 115.94,110.9 116.61,110.23 116.61,103.82 117.58,102.84 117.58,97.44 123.95,91.07 123.95,47.12 123.11,46.28 120.07,46.28 118.85,45.06 117.31,45.06 113.08,40.83 113.08,36.95 110.19,34.06 v3(109.6,34.06)
  BOTTOM w0.254: U74.5 v2(118.41,36.9)
  BOTTOM w0.279: U74.3 117.17,35.2
  vias: v2(95.26,27.76) v2(95.26,26.87) v2(96.15,27.76) v2(96.15,26.87) v2(107.07,28.42) v2(107.07,27.53) v2(107.96,28.42) v2(107.96,27.53) v3(109.6,32.92) v3(111,34.06) v3(111,32.92) v3(112.34,34.09) v3(112.34,32.94)
VCC0V75_EN: length 111.4
  TOP w0.152: R12.2 v1(119.23,135.96)
  L5_SIG2 w0.254: v1(119.23,135.96) 119.23,126.97 117.92,125.66 115.74,125.66 115.11,125.03 115.11,124.05 115.79,123.37 118.64,123.37 119.94,122.06 119.94,115.23 119.96,115.21 118.32,113.57 118.32,98.59 119.2,97.71 119.2,41.74 v2(123.02,37.92)
  BOTTOM w0.152: U74.7 122.24,35.7 122.71,36.18 122.72,36.18 123.02,36.48 R529.2 v2(123.02,37.92)
VCC0V75_MON: length 3.2
  TOP w0.152: U4.45 110.67,128.04 109.67,127.04 R41.1
VCC0V75REF: length 130.1
  TOP w0.254: v2(107.67,65.9) 107.04,65.27 DIMM1.84 ; U23.F15 v4(71.18,62.96)
  TOP w0.305: v2(94.72,93.19) 94.72,93.23 94.56,93.06 C57.2 DIMM1.1
  BOTTOM w0.152: 75.89,62.57 72.61,62.57 72.38,62.8 72.38,63.11 72.13,63.37 71.58,63.37 v4(71.18,62.96)
  BOTTOM w0.178: 75.89,62.57 76.07,62.38
  BOTTOM w0.254: C576.1 v4(71.18,62.96) ; U74.6 122.03,36.2 ; v2(107.67,65.9) C530.2 C531.1 105.44,65.3 104.65,64.52 89.76,64.52 85.87,60.63 77.83,60.63 76.07,62.38
  BOTTOM w0.381: v2(94.72,93.19) 94.56,93.03 C57.2
  BOTTOM w0.508: v2(107.67,65.9) 107.93,66.17 107.97,66.17 108.45,66.65 115.75,66.65 117.37,65.02 117.37,60.78 118.16,59.99 121.55,59.99 125.63,55.92 125.63,41.73 124.08,40.18 v3(122.96,40.18)
  BOTTOM w0.635: 108.45,66.65 108.45,66.65 108.45,69.28 107.57,70.15 98.7,70.15 98.04,70.82 98.04,91.82 96.67,93.19 v2(94.72,93.19)
  vias: v3(121.82,41.2) v3(122.96,41.08) v3(122.96,39.17)
VCC0V85: length 232.7
  TOP w0.254: R256.1 C245.2 v2(103.52,22.7) ; R62.2 111.09,122.21 v2(110.74,122.56)
  TOP w0.508: v2(60.88,84.45) 60.88,84.48 60.92,84.51 60.92,85.25 60.44,85.72 56.53,85.72 55.67,86.59 55.67,88.21 55.25,88.63 v2(54.69,88.63) 54.38,88.63 53.26,87.51 49.53,87.51 49.02,87 39.37,87 v2(37.95,85.57)
  L3_SIG1 w0.254: v2(110.74,122.56) 111.46,123.27 114.98,123.27 115.47,122.78 118.52,122.78 119.2,122.1 119.2,116.46 118.59,115.86 118.59,105.29 120.65,103.23 120.65,102.4 119.57,101.31 119.57,98.65 123.58,94.64 137.72,94.64 139.67,96.58 140.37,96.58 141.22,95.72 141.22,90.55 139.32,88.64 139.32,84.81 138.82,84.31 138.82,75.34 151.34,62.82 151.34,42.96 149.66,41.27 149.66,33.26 143.36,26.97 127.35,26.97 123.7,23.32 v6(123.7,20.6)
  L3_SIG1 w0.508: v3(72.82,86.44) 72.82,88.8 70.19,91.44 57.15,91.44 54.69,88.98 v2(54.69,88.63)
  L8_SIG3 w0.508: v2(37.95,85.57) 32.38,85.57 v3(29.18,82.37)
  BOTTOM w0.381: FB22.2 71.81,83.2 C441.1 71.81,85.45 72.8,86.44 v3(72.82,86.44)
  BOTTOM w0.508: v3(35.48,57.23) 37.11,57.23 37.65,57.77 FB30.2 ; FB20.2 61.79,84.8 61.34,84.35 61.02,84.35 60.91,84.45 v2(60.88,84.45)
  vias: v3(32.72,55.24) v3(32.72,54.28) v3(33.68,55.24) v3(33.68,54.28) v6(122.3,20.6) v6(122.3,19.2) v6(123.7,19.2)
VCC0V85_EN: length 123.2
  TOP w0.254: U33.34 105.12,14.27 v2(105.12,14.27)
  L8_SIG3 w0.107: v1(113.64,122.21) 114.12,122.68 115.32,122.68 115.54,122.46 115.54,118.9 115.72,118.73 115.72,112.58 114.65,111.51 114.65,59.86 117.7,56.82 117.7,20.71 111.27,14.27 v2(105.12,14.27)
  BOTTOM w0.152: v1(113.64,122.21) R337.2
  BOTTOM w0.381: R607.2 v2(105.12,14.27)
VCC0V85_MON: length 3.3
  TOP w0.152: R62.1 111.46,123.41 113.07,125.02 U4.2
VCC1V5: length 185.3
  TOP w0.254: v2(94.42,51.98) C155.1 DIMM1.131 ; v2(108.08,128.78) 108.58,128.78 108.77,128.96 R29.2 ; DIMM1.85 C124.1 v2(94.42,65.78) ; DIMM1.93 C125.1 v2(94.42,63.38) ; v2(94.42,60.98) C130.1 DIMM1.101 ; v1(95.76,57.99) 95.98,57.77 DIMM1.109 ; R204.1 v3(156.8,76.61) 156.8,77.82 155.88,78.74 155.07,78.74 154.38,78.05 151.49,78.05 149.35,75.92 146.18,75.92 143.64,73.38 143.64,72.03 ; v2(94.26,56.7) 94.42,56.55 C140.1 94.86,55.97 94.95,55.88 95.79,55.88 95.88,55.97 DIMM1.115 ; v2(94.31,54.52) 94.31,54.48 94.42,54.37 C147.1 DIMM1.123
  TOP w0.305: DIMM1.110 107.59,57.47 v2(107.64,57.42)
  TOP w0.356: DIMM1.116 v2(107.62,55.67) ; DIMM1.102 v2(107.62,59.87) ; DIMM1.94 v2(107.62,62.27) ; DIMM1.132 v2(107.62,50.87) ; DIMM1.86 v2(107.62,64.67) ; DIMM1.124 v2(107.62,53.27)
  TOP w0.381: U23.H7 v4(69.58,69.36) ; U23.C11 v4(73.58,66.16) ; U23.F11 v4(71.18,66.16) ; U23.F5 v4(71.18,70.96) ; U23.D5 v4(72.78,70.96) ; U23.H13 v4(69.58,64.56) ; U23.H9 v4(69.58,67.76) ; U23.D23 v4(72.78,55.76) ; U23.H11 v4(69.58,66.16) U23.G10 v4(70.38,66.96) U23.F9 v4(71.18,67.76) ; U23.G30 v4(70.38,50.16) ; U23.C3 v4(73.58,72.56) ; U23.A32 v4(75.18,48.56) ; U23.C31 v4(73.58,49.36) ; U23.D27 v4(72.78,52.56) ; U23.H25 v4(69.58,54.16) U23.G26 v4(70.38,53.36) U23.F27 v4(71.18,52.56) ; U23.D14 v4(72.78,63.76) ; U23.B1 v4(74.38,74.16) ; U23.H19 v4(69.58,58.96) U23.G20 v4(70.38,58.16) U23.F21 v4(71.18,57.36) ; U23.D29 v4(72.78,50.96) ; v4(71.18,64.56) U23.F13 v4(70.38,63.76) U23.G14 v4(69.58,62.96) U23.H15 ; U23.H17 v4(69.58,61.36) ; U23.F17 v4(71.18,61.36) ; v4(71.18,50.96) U23.F29 v4(70.38,51.76) U23.G28 v4(69.58,52.56) U23.H27 ; U23.C21 v4(73.58,57.36) ; U23.C25 v4(73.58,54.16) ; U23.F23 v4(71.18,55.76) ; U23.C7 v4(73.58,69.36) ; U23.H21 v4(69.58,57.36) ; U23.B33 v4(74.38,47.76) ; U23.F25 v4(71.18,54.16) ; U23.C17 v4(73.58,61.36) ; U23.D9 v4(72.78,67.76) ; U23.D19 v4(72.78,58.96) ; U23.A2 v4(75.18,73.36) ; U23.H23 v4(69.58,55.76) ; U23.F7 v4(71.18,69.36) ; U23.F19 v4(71.18,58.96)
  TOP w0.508: TP44.1 138.94,72.01
  L5_SIG2 w0.254: v2(107.62,64.67) 110.9,67.94 110.9,83.64 114.88,87.63 114.88,116.04 112.42,118.5 112.42,119 111.43,119.99 110.39,119.99 108.47,121.91 108.47,122.79 109.22,123.55 109.22,127.64 v2(108.08,128.78)
  BOTTOM w0.254: C637.1 v4(71.18,57.36) ; C622.1 v4(70.38,58.16) ; C638.1 v4(69.58,57.36) ; C510.1 v4(71.18,67.76) ; C475.1 v4(72.78,70.96) ; C577.1 v4(69.58,62.96) ; C663.1 v4(71.18,55.76) ; C595.1 v4(71.18,61.36) ; C713.1 v4(70.38,51.76) ; C664.1 v4(69.58,55.76) ; C706.1 v4(69.58,52.56) ; C553.1 v4(69.58,64.56) ; C721.1 v4(72.78,50.96) ; C671.1 v4(72.78,55.76) ; C564.1 v4(72.78,63.76) ; C720.1 v4(71.18,50.96) ; C691.1 v4(73.58,54.16) ; C697.1 v4(70.38,53.36) ; C684.1 v4(71.18,54.16) ; C480.1 v4(73.58,69.36) ; C611.1 v4(72.78,58.96) ; C507.1 v4(72.78,67.76) ; C472.1 v4(73.58,72.56) ; C613.1 v4(69.58,58.96) ; C705.1 v4(71.18,52.56) ; C612.1 v4(71.18,58.96) ; C487.1 v4(71.18,69.36) ; C519.1 v4(70.38,66.96) ; C533.1 v4(73.58,66.16) ; C536.1 v4(71.18,66.16) ; C685.1 v4(69.58,54.16) ; C488.1 v4(69.58,69.36) ; C552.1 v4(71.18,64.56) ; C565.1 v4(70.38,63.76)
  BOTTOM w0.279: U74.2 117.51,34.7 117.04,34.24
  BOTTOM w0.381: R549.1 v3(121.44,30.75) ; C601.1 73.63,61.31 v4(73.58,61.36) ; C602.1 69.51,61.3 v4(69.58,61.36)
  vias: v3(113.49,34.11) v3(113.49,32.97) v3(138.23,69.72) v3(138.23,68.33) v3(139.24,69.72) v3(139.24,68.33)
VCC1V5_EN: length 107.7
  TOP w0.152: R56.2 v1(120.4,121.41)
  TOP w0.254: U22.10 152.64,71.01 v3(152.27,71.37)
  L10_SIG4 w0.107: v1(120.4,121.41) 120.58,121.6 121.06,121.6 123.16,123.7 126.24,123.7 126.66,124.12 147.19,124.12 154.2,117.1 154.2,114.71 155.65,113.26 156.54,113.26 159.03,110.77 166.55,110.77 168.66,108.67 168.66,88.77 169.31,88.12 169.31,84.16 161.19,76.05 156.95,76.05 v3(152.27,71.37)
  BOTTOM w0.381: R610.2 v3(152.27,71.37)
VCC1V5_MON: length 2.2
  TOP w0.152: U4.42 110.49,129.54 110.24,129.29 R29.1
VCC1V8: length 279.8
  TOP w0.254: C22.2 66.4,115.23 v1(66.27,115.1) ; R45.1 89.81,125.35 v2(89.61,125.55) ; U10.20 56.94,113.25 57.02,113.33 57.92,113.33 58.12,113.14 C25.2 ; v3(46.12,114.05) C28.2 C27.1 ; v1(98.81,103.61) 99.35,103.07 R127.2 ; C26.1 64.25,114.72 v1(63.87,115.1) ; R239.2 v1(87.43,34.82) ; v2(48.16,100.97) 47.68,100.48 U16.20 ; R244.2 93.93,35.33 v1(94.08,35.18) ; R626.2 52.15,95.22 v2(52.27,95.1) ; C474.1 R428.1 ; C474.1 137.19,49.38 NOR1.2 ; C474.1 136.85,49.35 136.65,49.15 v1(136.47,49.15) ; R109.2 93.35,105.1 93.07,105.38 v2(93.07,105.74) ; v1(85.01,32.99) 84.63,33.38 84.63,34.45 R242.2 ; R44.2 v2(101.41,125.73) ; CN7.2 v2(36.83,97.99) ; C29.1 C25.2 ; C25.2 v1(59.39,113.14) ; C20.2 58.8,119.95 C19.1 ; CN7.1 40.8,97.59 v2(40.67,97.46) ; C19.1 v2(59.42,120.07) ; C19.1 57.65,120.07 57.48,120.24 57.02,120.24 56.94,120.16 U6.20 ; R31.2 v2(102.17,129.61) ; v2(83.34,113.9) 83.29,113.85 83.29,112.67 83.47,112.49 U11.1 ; R274.1 C292.2 v2(104.99,2.29) ; C21.2 64.8,116.03 v1(64.67,115.9) ; R443.1 136.65,46.48 136.27,46.86 v1(135.13,46.86) ; R64.2 v2(104.27,122.56) ; C24.1 C23.2 v3(47.05,114.63) ; v2(42.47,94.82) 42.59,94.94 R627.2 ; U14.20 47.68,106.93 47.45,107.16 v2(47.27,107.16) ; C15.1 161.79,130.22 v1(162.56,130.22) ; v2(38.3,34.03) 38.3,34.01 38.08,33.78 C215.1 ; R88.2 60.93,114.02 v2(60.83,113.92)
  TOP w0.381: U23.K27 v4(67.98,52.56) U23.J28 v4(68.78,51.76) ; v2(54.69,87.92) 54.69,87.08 54.43,86.81 R182.2 R183.2 52.05,86.54 51.07,86.54 R184.2 ; U23.AC8 v4(56.78,68.56) ; v4(57.58,69.36) U23.AB7 v4(58.38,68.56) U23.AA8 ; R200.1 22.75,80.06 v2(22.14,80.06) ; v2(86.77,123.95) R53.2 R66.2 ; U23.AA3 v4(58.38,72.56) ; U23.AJ30 v4(51.98,50.16) ; v4(59.98,51.76) U23.W28 v4(60.78,52.56) U23.V27 ; U23.L8 v4(67.18,68.56) ; U23.N31 v4(65.58,49.36) ; U23.AG26 v4(53.58,53.36) U23.AH27 v4(52.78,52.56) ; v4(56.78,51.76) U23.AC28 v4(57.58,52.56) U23.AB27 ; FB9.1 29.27,29.17 28.93,28.83 28.6,28.83 v3(28.59,28.82) ; v4(63.98,51.76) U23.R28 v4(63.18,52.56) U23.T27 ; U23.AD4 v4(55.98,71.76) ; U23.Y7 v4(59.18,69.36) ; U23.T7 v4(63.18,69.36) ; R197.1 v2(23.44,81.85) ; U23.Y27 v4(59.18,52.56) U23.AA28 v4(58.38,51.76) ; U23.AE26 v4(55.18,53.36) U23.AF27 v4(54.38,52.56) ; R74.2 v1(69.41,117.16) ; U21.1 C97.1 v2(22.54,77.03) ; U23.P7 v4(64.78,69.36) ; U23.U28 v4(62.38,51.76) ; v2(59.29,109.52) C30.1 58.85,108.64 58.57,108.36 U13.5 ; FB11.1 35.69,26.26 36.12,25.83 36.12,25.78 v3(36.09,25.78) ; U23.AE31 v4(55.18,49.36) ; U23.P27 v4(64.78,52.56) U23.N28 v4(65.58,51.76) ; v4(67.18,51.76) U23.L28 v4(66.38,52.56) U23.M27 ; U23.AN32 v4(48.78,48.56) ; v4(66.38,69.36) U23.M7 v4(65.58,68.56) U23.N8 ; FB10.1 43.38,28.13 v6(44.15,27.36) ; U23.AD27 v4(55.98,52.56) U23.AE28 v4(55.18,51.76) ; U23.J2 v4(68.78,73.36) ; U23.V7 v4(60.78,69.36) ; U23.AM33 v4(49.58,47.76) ; U23.AE8 v4(55.18,68.56) ; U23.U31 v4(62.38,49.36) ; U23.M2 v4(66.38,73.36) ; U23.AA31 v4(58.38,49.36)
  TOP w0.508: v1(43.37,92.39) 43,92.76 42.32,92.76 41.76,93.32 41.76,94.35 42.23,94.82 v2(42.47,94.82) ; FB7.1 v3(24.13,39.29)
  L5_SIG2 w0.508: v1(94.08,35.18) 92.92,36.34 88.95,36.34 v1(87.43,34.82) 86.41,33.8 85.82,33.8 v1(85.01,32.99)
  L8_SIG3 w0.381: 66.7,69.62 66.44,69.36 v4(66.38,69.36)
  L10_SIG4 w0.254: 56.28,71.46 55.98,71.76 v4(55.98,71.76) ; 58.03,72.21 v4(58.38,72.56)
  BOTTOM w0.152: v4(68.78,73.36) 68.37,73.76 66.78,73.76 v4(66.38,73.36) ; C484.1 59.64,69.75 60.38,69.75 v4(60.78,69.36)
  BOTTOM w0.254: R440.1 v2(111.82,70.3) ; C483.1 v4(63.18,69.36) ; U40.19 C321.1 v2(55.7,138.42) ; U72.8 26.81,42.84 26.98,42.67 C746.1 v2(26.98,41.55) ; U41.2 137.89,131.84 137.81,131.76 C330.1 v2(136.09,131.76) ; R536.2 86.95,34.35 v1(87.43,34.82) 87.43,35.56 88.04,36.17 R528.2 ; U46.2 C333.1 v2(66.19,130.44) ; U51.20 47.61,114.87 47.36,114.62 47.06,114.62 v3(47.05,114.63) ; v2(112.72,68.58) C516.1 U64.1 ; R537.2 85.24,33.22 v1(85.01,32.99) ; U57.20 C374.1 92.12,105.33 92.53,105.74 v2(93.07,105.74) ; v2(97.59,114.12) R357.1 ; C357.1 83.75,113.49 v2(83.34,113.9) ; C719.1 v4(56.78,51.76) ; C473.1 v4(55.98,71.76) ; C729.1 v4(58.38,49.36) ; U71.1 C736.1 v2(112.72,44.7) ; v2(47.27,107.16) 47.68,106.76 U14.20 ; U38.16 C311.1 136.28,142.74 v2(136.28,142.72) ; U55.8 C368.1 v2(94.74,107.65) ; U63.A2 83.97,68.45 84.3,68.12 C518.1 84.3,65.04 v2(84,64.74) 84,63.2 83.67,62.87 v3(82.63,62.87) ; R422.2 v2(123.32,75.95) ; U53.H8 v1(66.27,115.1) ; v4(59.18,69.36) C484.1 ; U69.2 114.3,51.69 114.12,51.5 C722.1 v2(114.12,50.04) ; C710.1 v4(55.98,52.56) ; C470.1 v4(66.38,73.36) ; C725.1 v4(51.98,50.16) ; C718.1 v4(65.58,51.76) ; C715.1 v4(58.38,51.76) ; C500.1 v4(58.38,68.56) ; U39.9 48.61,134.94 v3(48.61,135.33) ; v2(38.3,34.03) 38.28,34.01 U75.7 ; EEPROM1.8 C468.1 v2(112.72,78.11) ; R553.2 134.55,30.46 v1(134.04,29.95) ; v2(52.27,95.1) 52.15,95.22 R626.2 ; v2(26.47,58.65) C635.1 26.03,57.91 25.98,57.96 U68.1 ; C712.1 60.91,52.7 v4(60.78,52.56) ; U16.20 47.68,100.48 48.16,100.96 v2(48.16,100.97) ; U56.1 86.47,112.42 86.35,112.55 C355.1 v1(86.35,113.93) ; v2(89.46,107.85) 89.46,107.95 89.47,107.96 R378.2 ; v2(109.18,129.93) 108.95,129.93 108.77,129.75 R323.2 ; R510.1 v1(33.27,41.78) ; U54.20 46.11,114.04 v3(46.12,114.05) ; C489.1 v4(64.78,69.36) ; R555.2 v2(25.91,27.28) ; C502.1 v4(55.18,68.56) ; R470.1 v2(113.23,58.95) ; R491.1 v2(111.25,47.37) ; U45.2 55.42,131.21 C335.1 v1(55.45,131.98) ; R329.2 v2(56.2,126.82) ; C707.1 v4(64.78,52.56) ; R494.1 v2(111.82,46.42) ; R425.2 v2(123.32,74.42) ; U40.2 C320.1 v2(66.4,137.68) ; U53.G4 v1(63.87,115.1) ; v2(56.28,139.67) C317.1 56.77,140.7 57.15,141.08 57.15,143.09 56.9,143.34 56.88,143.34 56.86,143.36 U37.3 ; C703.1 v4(55.18,53.36) ; C708.1 v4(63.18,52.56) ; C711.1 v4(54.38,52.56) ; C716.1 v4(55.18,51.76) ; C709.1 v4(59.18,52.56) ; R474.1 v2(113.23,55.12) ; C501.1 v4(56.78,68.56) ; U75.52 34.57,39.33 C749.1 ; v2(56.82,131.83) C334.1 U46.19 ; U53.J6 v1(64.67,115.9) ; C417.1 43.77,94.59 U58.3 ; v2(26.47,47.92) C730.1 26.47,49.2 26.26,49.42 U70.8 ; v2(114.12,55.88) C650.1 114.12,57.35 114.3,57.54 U67.2 ; R468.1 v2(113.23,60.81) ; C717.1 v4(68.78,51.76) ; U48.14 v1(162.56,130.22) ; U79.3 139.7,120.16 140.77,119.09 C875.1 ; C496.1 v4(67.18,68.56) ; C485.1 v4(57.58,69.36) ; R579.2 v1(132.52,7.76) ; C479.1 v4(66.38,69.36) ; v4(68.78,73.36) C471.1 ; U43.9 v2(86.26,129.61) ; C714.1 v4(59.98,51.76) ; U53.D3 v1(62.27,111.9) ; C497.1 v4(65.58,68.56) ; R475.2 v2(15.68,53.16) ; v2(57.66,140.7) C316.1 58.43,141.31 57.76,141.98 57.76,142.6 58.02,142.86 U37.7 ; U44.9 v2(74.76,132.56) ; C704.1 v4(53.58,53.36) ; R435.1 v2(111.82,72.14) ; R506.1 56.39,42.09 56.3,42 56.3,41.69 v4(56.26,41.66) ; R480.1 v2(113.23,53.11) ; R423.1 v2(111.82,76.38) ; R317.2 v2(136.17,135.95)
  BOTTOM w0.305: U80.24 44.86,91.98 44.73,91.85 U80.23 44.26,91.51 44,91.77 43.45,91.77 43.37,91.69 C893.1 43,92.02 43.37,92.39 v1(43.37,92.39) ; v2(42.47,94.82) 42.88,94.82 43.33,94.36 C417.1 ; v1(140.64,118.31) 140.64,118.54 140.77,118.68 C875.1
  BOTTOM w0.381: v3(36.46,26.76) 36.45,26.76 36.17,26.47 FB33.1 ; 29.42,52.39 28.81,52.39 28.09,53.11 15.72,53.11 v2(15.68,53.16) ; 29.42,52.39 28.55,51.53 v2(28.55,51.1) ; 29.42,52.39 C696.1 30.17,52.39 30.89,51.67 v2(30.89,51.1) ; C749.1 v2(36,39.56)
  BOTTOM w0.508: FB24.2 v3(38.76,82)
  vias: v1(152.4,37.24) v1(152.4,36.58) v3(30.28,68.99) v3(31.22,68.99) v3(32.64,57.68) v3(32.64,56.72) v3(33.6,57.68) v3(33.6,56.72) v3(48.71,35.12) v3(48.71,34.23) v3(49.4,41.53) v3(50.55,41.53) v3(74.17,82.04) v3(75.77,86.11) v3(76.66,86.11) v3(149.99,21.08) v3(149.99,20.19) v3(157.58,51.46) v3(157.61,50.5) v6(122.3,6.61) v6(122.3,5.21) v6(123.7,6.61) v6(123.7,5.21)
VCC1V8_EN: length 137.7
  TOP w0.152: R26.2 122.25,130.18 122.56,129.87 v1(122.56,129.67)
  TOP w0.254: U33.27 v2(105.12,10.77)
  L8_SIG3 w0.107: v2(105.12,10.77) 112.67,10.77 118.95,17.05 118.95,30.99 118.63,31.31 118.63,36.4 118.92,36.69 118.92,37.12 118.34,37.69 118.26,37.69 117.93,38.02 117.93,56.91 114.88,59.96 114.88,111.09 116.46,112.67 116.46,121.87 122.53,127.94 122.53,128 122.56,128.02 v1(122.56,129.67)
  BOTTOM w0.381: R606.2 104.38,11.51 v2(105.12,10.77)
VCC1V8_MON: length 2.5
  TOP w0.152: U4.41 v2(110.88,130.04)
  BOTTOM w0.152: v2(110.88,130.04) 110.88,130.03 110.13,129.29 R323.1
VCC1V8_TCT: length 12.2
  BOTTOM w0.381: R570.2 148.15,15.55 147.76,15.94 147.76,17.21 148.84,18.29 150.5,18.29 151.83,19.63 FB34.2 C815.1 151.83,22.67 151.07,23.44 151.07,23.87 R556.2
VCC2V5: length 219.7
  TOP w0.381: C894.1 47.4,92.4 v1(47.73,92.72) ; TP95.1 138.56,23.9 v3(138.61,23.95) ; v2(140.79,28.09) 140.64,27.94 139.7,27.94 138.61,26.85 v3(138.61,24.77)
  L3_SIG1 w0.381: J9.11B 158.74,12.31 ; J9.11B 158.74,13.81 ; J9.11B 157.25,12.31 ; J9.11B 157.25,13.81 ; 171.94,25.24 J9.13A ; J9.13A 173.43,23.74 ; J9.13A 171.94,23.74 ; J9.13A 173.43,25.24 ; 161.06,27.78 J9.13B ; J9.13B 162.55,26.28 ; J9.13B 162.55,27.78 ; J9.13B 161.06,26.28 ; J9.11A 173.43,13.81 ; J9.11A 171.94,13.81 ; J9.11A 171.94,12.31
  L8_SIG3 w0.508: v1(42.01,97.41) 43.41,96.01 47.04,96.01 47.73,95.33 v1(47.73,92.72) 49.14,92.72 v2(50.9,94.48) 50.9,97.1 57.2,103.39 70.93,103.39 v2(75.04,99.28)
  L10_SIG4 w0.508: v1(130.19,39.93) 130.19,45.32 128.52,46.99 128.52,77.57 109.93,96.16 95.66,96.16 90.81,91.31 80.49,91.31 75.15,96.65 75.15,99.17 v2(75.04,99.28)
  BOTTOM w0.254: v1(134.75,19.86) 134.72,19.83 U77.11 ; U73.52 v1(130.19,39.93) ; U73.49 v1(130.19,38.43) ; U58.7 49.46,94.09 49.85,93.7 C423.1 50.65,94.24 v2(50.9,94.48) ; U77.49 v1(128.24,14.8) ; U77.52 v1(128.24,16.3) ; U73.11 v1(136.75,41.88)
  BOTTOM w0.305: v1(47.73,92.72) 47.32,92.72 47.21,92.61 U80.1
  BOTTOM w0.381: R624.2 41.4,97.23 41.58,97.41 v1(42.01,97.41) 42.37,97.41 42.73,97.05 R625.2 ; v2(140.79,28.09) 140.94,27.94 R647.1
  BOTTOM w0.508: J9.13B C892.1 C891.1 v1(165.03,29.55) v1(166.03,29.55) 167.08,28.5 167.08,24.33 167.84,23.57 169.7,23.57 170,23.27 C889.1 ; C888.1 C886.1 171.45,11.82 J9.11A ; C889.1 170.53,22.33 J9.13A ; C889.1 C890.1 ; J9.11B C885.1 159.89,10.54 C887.1 v2(161.28,10.4) v2(162.29,10.4)
VCC2V5_EN: length 4.9
  BOTTOM w0.254: R649.2 C895.1 R650.2 146.66,27.34 Q15.5
VCC3_AUX_MON: length 3.8
  TOP w0.152: U4.39 110.1,131.04 v2(109.67,131.47) R21.1
  BOTTOM w0.152: R21.1 v2(109.67,131.47)
VCC3_LCD: length 12.4
  BOTTOM w0.254: LCD1.12 61.41,144.87 61.15,144.61 C304.1 61.15,142.27 62,141.42 R309.2 63.24,141.42 63.87,142.06 65.78,142.06 65.8,142.04 Q10.2 67.41,142.04 67.82,142.44 R306.2
VCC3V3_AUX: length 241.3
  TOP w0.254: C290.2 v2(96.06,3.17) ; R73.2 v2(176.97,116.91) ; v2(85.57,105.75) 85.75,105.92 B2.1 ; R201.2 12.76,79.54 13.21,79.99 v2(13.21,80.01) ; U7.16 v2(87.75,120.62) ; R273.1 v2(96.06,4.57) ; CN7.119 41.97,132.49 42.16,132.69 v3(42.16,133.1) ; CN7.120 34.04,132.49 33.78,132.75 v3(33.78,133.22) ; v2(12.76,83) R193.2 R198.2 ; v2(91.74,105.82) 91.77,105.82 91.62,105.97 89.49,105.97 B1.1 ; R252.2 R251.2 v2(93.18,31.67) ; R35.2 v3(29.39,129.17) ; R89.2 v2(176.97,114.38) ; v3(40.8,117.35) CN7.61 ; R71.2 v2(177.1,119.28) 177.07,119.25 176.4,119.25 176.21,119.45 R69.2 ; R21.2 v2(107.95,132.21) ; DIMM1.199 v2(99.11,30.77) ; CN7.62 v3(33.35,117.99) ; R276.2 v1(56.88,4.54) ; R136.2 v2(63.5,102.68) ; R113.1 81.42,104.08 v2(81.16,104.34) ; R188.2 15.29,84.78 v2(15.16,84.65) ; R614.1 v2(169.48,141.55) ; v2(88.42,112.75) 88.6,112.57 88.62,112.57 88.71,112.49 U11.14 ; R161.1 v2(74.44,96.14) ; U35.3 56.01,2.74 C296.1 56.38,2.64 v2(56.82,2.2) ; B4.1 v2(69.09,107.01) ; B3.1 v2(71.92,107.07)
  TOP w0.305: U12.5 104.55,108.22 104.7,108.07 C31.1 105.41,108.74 104.85,109.3 v2(103.7,109.3)
  TOP w0.381: R100.2 102.81,110.45 v2(102.51,110.74) ; R215.2 143.88,61.23 v3(143.38,60.73) ; Y4.1 52.64,103.44 52.96,103.76 55.44,103.76 Y4.4 56.84,104.21 56.35,104.7 C35.1 v2(55.59,105.44) ; R213.2 v3(153.51,66.4) ; U21.8 C98.1 v2(13.66,76.89)
  L3_SIG1 w0.508: v2(42.6,29.29) 42.6,29.25 42.52,29.33 42.52,33.45 44.6,35.53 v2(44.6,37.8) 43.56,38.84 32.11,38.84 31.75,38.48 17.61,38.48 v2(16.95,37.82)
  L8_SIG3 w0.508: v3(40.87,87.78) 40.34,87.78 39.53,86.97 32.7,86.97 28.1,82.36 28.1,79.79 27,78.69 25.2,78.69 v3(24.26,79.63)
  L8_SIG3 w0.635: v2(141.56,126.23) 142.05,125.75 147.79,125.75 151.38,122.15 151.38,116.52 152.64,115.27 152.64,114.88 153.23,114.29 155.84,114.29 157.21,112.92 v2(159.89,112.92) ; v2(169.8,121.15) 169.07,121.15 168.84,121.38 168.84,128.33 168.06,129.11 168.06,132.41 168.21,132.56 168.21,140.29 v2(169.48,141.55)
  BOTTOM w0.254: v2(168.53,114.3) 168.53,114.92 168.67,115.06 U52.8 ; R482.1 v2(14.96,52.07) ; v2(44.6,37.8) 44.58,37.77 U76.3 ; R557.2 v1(136.14,22.56) ; v2(85.67,107.77) 85.7,107.75 C361.1 86.35,108.61 86.47,108.74 U56.6 ; C353.1 88.57,112.9 v2(88.42,112.75) ; R377.2 v2(178.3,108.15) ; C348.1 87.75,119.72 v2(87.75,120.62) ; U49.16 98.24,120.19 98.02,119.96 v2(97.94,119.96) ; U74.10 122.56,34.2 ; v2(99.11,30.77) C789.1 C790.2 ; v2(15.22,3.07) R591.2 ; v2(16.59,47.9) 16.59,48.63 C731.1 16.58,49.24 16.75,49.42 U70.1 ; R508.2 v1(143.22,42.52) ; R359.1 v2(163.58,112.78) ; U79.7 140.2,125.86 140.4,126.06 C876.1 141.05,126.75 v2(141.56,126.23) ; R496.2 137.87,45.85 v1(137.87,46.33) ; v2(16.95,37.82) 16.95,37.82 15.68,39.09 R513.1 ; R493.2 v2(122.62,47.24) ; v2(15.22,5.97) R581.2 ; v2(15.22,1.7) R595.2 ; v2(95.52,115.57) 95.52,115.62 95.65,115.49 C351.1 ; R339.1 v2(169.8,121.15) ; v2(46.12,132) C332.1 U45.19 ; U62.A2 25.04,77.83 ; U76.7 43.31,30 v2(42.6,29.29) 42.04,29.85 U76.8 ; U50.15 C352.1 C356.1 v2(161.44,112.01) ; R361.1 v2(159.89,112.92) ; v2(15.22,7.34) R578.2 ; R497.2 v2(122.62,45.47) ; v1(56.88,4.54) 56.88,4.18 56.32,3.63 R611.2 ; C737.1 v2(121.72,42.29)
  BOTTOM w0.381: U71.8 121.25,43.81 121.72,43.35 C737.1 ; C796.1 42.09,28.79 v2(42.6,29.29) ; C762.1 v1(150.24,39.43) ; R463.2 23.25,60.61 20.59,57.96 U68.14 17.42,57.96 17.34,58.04 C633.1 16.58,58.76 16.03,59.31 14.55,59.31 14.3,59.56 B7.1 ; v2(16.58,40.99) C747.1 16.58,42.54 16.88,42.84 U72.1 ; v1(145.92,15.62) FB35.1
  BOTTOM w0.508: v2(169.48,141.55) 168.6,140.67 R615.2 ; FB32.1 v1(148.82,39.4)
  BOTTOM w0.889: B7.1 v6(12.73,60.96)
  vias: v1(147.45,13.08) v2(73.58,90.82) v2(82.58,137.39) v2(83.97,137.39) v2(90.65,100.86) v2(90.68,100.15) v3(24.26,80.59) v3(80.39,2.54) v3(80.39,1.52) v3(81.53,2.54) v3(81.53,1.52) v3(124.84,35.61) v3(125.93,35.61) v3(125.96,34.59) v3(148.11,20.62) v3(148.11,19.81)
VCC3V3_AUX_EN: length 207.4
  TOP w0.254: v2(97.54,8) 98.04,8.5 U33.13
  L3_SIG1 w0.381: v1(149.73,29.11) 147.03,26.4 134.67,26.4 132.97,24.7 127.67,24.7 126.03,23.06 126.03,15.67 125.71,15.35 108.96,15.35 106.48,12.87 106.48,9.55 103.12,6.2 99.34,6.2 v2(97.54,8)
  L8_SIG3 w0.107: v1(115.16,122.3) 115.16,119.97 114.02,118.83 114.02,73.15 114.43,72.75 114.43,59.77 115.77,58.43 115.77,48.72 117.47,47.02 117.47,23.42 113.08,19.02 97.88,19.02 96.8,17.94 96.8,8.74 v2(97.54,8)
  BOTTOM w0.152: R336.2 115.07,122.21 v1(115.16,122.3) ; R649.1 v1(149.73,29.11)
  BOTTOM w0.381: v2(97.54,8) R605.2
VCC3V3_AUX_F1: length 19
  TOP w0.127: U17.7 v2(79.7,94.62)
  TOP w0.254: U17.18 84.05,90.73 83.8,90.48 v2(83.59,90.48) ; U17.48 81.55,98.74 81.36,98.93 80.99,98.93 v2(80.83,98.77) ; 88.7,95.15 88.7,94.82 88.5,94.62 U17.30 ; 88.7,95.15 88.67,95.12 U17.31 ; 88.7,95.15 v2(88.7,95.17) ; U17.34 v2(88.75,96.62) ; v2(84.51,92.38) 84.55,92.33 U17.19 ; U17.13 81.55,90.68 81.35,90.47 v2(81,90.47) ; U17.27 v2(88.75,93.12) ; U17.10 v2(79.7,93.12) ; U17.24 v2(87.05,90.4)
  TOP w0.381: R601.2 81,89.86 v2(81,90.47) ; R602.2 v4(78.06,89.6)
  BOTTOM w0.152: 90.55,98.2 v2(90.58,98.22)
  BOTTOM w0.254: v2(84.51,92.38) 84.51,91.29 84.68,91.12 C426.1
  BOTTOM w0.381: v4(78.06,89.6) 78.06,90.33 78.59,90.86 80.21,90.86 ; v2(81,90.47) 81.03,90.45
  vias: v2(87.93,98.73) v2(90.6,97.46)
VCC3V3_AUX_F2: length 12.2
  TOP w0.254: U18.19 66.67,90.46 v2(66.87,90.26) ; v2(61.67,93.47) 62.02,93.12 U18.10 ; v2(62.33,98.17) 62.53,98.37 U18.48 ; U18.34 v2(70.86,96.62) ; U18.27 70.66,93.12 v2(70.78,92.99) ; U18.18 66.17,90.45 v2(66.14,90.42) ; U18.24 v2(69.17,90.35) ; v2(61.59,94.49) 61.73,94.62 U18.7 ; U18.30 70.56,94.62 v2(70.86,94.92) 70.66,95.12 U18.31 ; U18.13 63.67,91.11 63.37,90.81 63.17,90.81 63.16,90.8 v2(63.15,90.8)
  vias: v2(70.23,90.42) v2(70.23,89.53) v2(70.86,98.53)
VCC3V3_EN: length 138.9
  TOP w0.152: R55.2 v1(121.92,121.41)
  L8_SIG3 w0.107: v1(73.81,118.59) 73.81,118.57 73.48,118.24 72.21,118.24 69.27,115.29 69.27,112.67 64.62,108.03 61.17,108.03 61.16,108.03 59.08,105.94 56.85,105.94 52.73,101.83 45.59,101.83 44.89,101.13 41.72,101.13 38.84,98.25 38.51,98.25 37.49,97.23 33.64,97.23 28.85,92.44 28.85,85.65 26.36,83.15 22.57,83.15 21.09,81.66 21.09,76.31 22,75.39 v2(23.67,75.39)
  BOTTOM w0.152: U62.B2 25.04,77.11 25.04,75.94 24.49,75.39 v2(23.67,75.39) ; v1(121.92,121.41) 121.39,120.88 120,120.88 119.55,121.34 118.15,121.34 117.7,120.88 109.62,120.88 108.52,121.99 108.52,122.23 105.66,125.09 91.09,125.09 90.7,124.71 79.93,124.71 v1(73.81,118.59)
VCC3V3_MP: length 166.6
  TOP w0.254: U1.44 v2(142.19,128.06) ; v2(148.89,133.86) 148.61,133.58 147.89,133.58 147.8,133.66 U1.56 ; R28.1 150.06,130.61 v2(149.86,130.81) ; Q1.4 v2(115.2,141.99) ; v2(136.5,146.58) 136.5,145.93 136.69,145.73 U1.93 ; v2(114.38,133.81) 114.07,133.5 U4.33 ; U1.3 v2(132.56,142.16) ; v1(70.23,112.7) 70.25,112.69 U8.9 ; v2(132.77,133.43) 132.51,133.43 132.28,133.66 U1.20 ; D1.1 D2.1 128.72,142.88 v3(128.72,142.88) ; R179.2 v2(171.69,87.9) ; C11.1 105.13,133.97 U3.8 ; R38.2 v2(137.38,126.22) ; R32.2 v2(178.18,127.42) ; v2(148.18,139.65) 147.62,139.65 147.61,139.66 U1.68 ; v2(148.26,142.42) 148.57,142.73 150.08,142.73 150.31,142.5 R5.2 ; v2(136.4,128.02) 136.19,128.22 U1.32 ; R14.1 v2(115.8,135.96) R13.1 ; R205.2 v2(169.72,75.28) ; R47.2 v2(176.66,125.67) ; v2(132.56,139.32) 132.22,139.66 U1.8 ; R10.1 v2(151,136.4) ; U1.81 142.69,145.75 142.34,146.1 142.19,146.1 v2(142.14,146.15) ; R8.2 v2(150.96,137.92)
  TOP w0.381: C11.1 v3(105.52,135.31) ; v2(152.43,136.53) 152.45,136.51 R9.2
  L8_SIG3 w0.508: v1(156.34,120.4) 154.41,120.4 149.41,125.39 v2(149.41,126.57) 150.22,127.38 157.45,127.38 161.7,123.14 161.7,117.42 166.55,112.57 166.55,107.49 166.54,107.48 166.54,104.78 168.45,102.87 169.7,101.62 169.7,100.89 169.72,100.86 169.72,90.41 171.69,88.44 v2(171.69,87.9) 171.69,83.73 170.59,82.63 170.59,76.15 v2(169.72,75.28)
  BOTTOM w0.254: C337.1 v2(142.19,128.06) ; R313.1 v2(97.46,138.24) ; R338.1 v2(109.05,122.21) ; v2(121.72,64.77) C541.1 120.03,65.66 ; C339.1 136.14,128.27 v2(136.4,128.02) ; U38.3 146.01,141.44 146.18,141.6 146.18,141.96 146.05,142.09 ; R466.1 v2(122.62,61.21) ; v2(117.47,121.41) R334.1 R335.1 ; U47.15 v1(153.64,128.98) ; R306.1 v3(70.11,141.35) ; C312.1 v2(132.56,142.16) ; R299.1 115.11,143.24 v2(114.11,142.24) ; R307.1 v2(115.95,142.01) ; v2(148.26,142.42) 147.93,142.09 C314.1 147.07,142.53 146.86,142.74 U38.1 ; v2(132.56,139.32) 131.95,139.32 131.77,139.13 C319.1 ; v2(112.73,64.85) 112.73,65.02 112.72,65.03 C542.1 114.41,65.66 ; C340.1 C336.1 150.31,130.51 150.61,130.81 v1(150.88,130.81) ; R305.2 v2(100.84,144.43) ; C325.1 131.77,133.04 132.16,133.43 v2(132.77,133.43) ; R360.2 v1(156.34,120.4) ; U41.19 146.26,131.84 146.77,131.33 C331.1 147.95,131.33 v2(148.34,130.94) ; U64.8 C515.1 v2(121.72,66.8) ; R298.2 v2(112.01,145.85) ; R314.1 v2(92.38,138.24) ; R322.1 v2(149.41,132.39) ; R311.1 v2(100.91,138.75) ; R326.1 v2(149.41,126.57) ; U42.8 v2(133.22,132.06) ; R459.1 v2(122.62,63.05) ; R315.1 v2(89.84,138.24) ; C323.1 148.32,133.28 v2(148.89,133.86) ; Q1.4 v2(115.2,141.99) ; R316.1 v2(94.92,138.24)
  BOTTOM w0.305: C314.1 U38.2
  BOTTOM w0.381: C303.1 v3(128.72,142.88) ; U36.5 117.69,144.17 117.92,144.39 C297.1 v2(118.65,146.06)
  vias: v2(109.65,142.9) v2(109.65,142.01) v2(110.67,142.9)
VCC3V3_MP_ALT: length 3
  TOP w0.254: TP8.1 123.57,130.81 v2(123.9,131.14)
  TOP w0.381: D1.2 125.6,146.05 v2(126.01,145.64)
  BOTTOM w0.254: R292.1 v2(130.51,144.58)
  vias: v2(120.62,137.88) v2(121.67,137.88)
VCC3V3_MP_ALT_DET: length 4.7
  TOP w0.152: v1(133.69,146.48) U1.99
  BOTTOM w0.152: v1(133.69,146.48) 133.69,145.81 133.37,145.48 R291.2 R292.2
VCC3V3_MP_AMC: length 259.8
  TOP w0.254: R190.2 v2(13.44,83.88)
  TOP w0.381: D2.2 123.29,143.76 122.61,144.44 v2(122.61,146.02)
  TOP w0.483: v3(9.83,7.5) AMC1.4
  L3_SIG1 w0.254: v2(13.44,83.88) 15.95,81.36 15.95,60.66 12.7,57.4 12.7,25.07 14.94,22.83 14.94,14.35 11.38,10.79 11.38,8.43 10.45,7.5 v3(9.83,7.5)
  L8_SIG3 w0.254: v2(122.61,146.02) 122.6,146 121.51,146 120.66,146.85 99.71,146.85 98.53,145.67 89.61,145.67 88.43,146.85 39.69,146.85 35.71,142.88 33.96,142.88 26.45,135.37 26.41,135.13 26.41,86.07 25.57,85.23 14.79,85.23 v2(13.44,83.88)
VCC3V3_PCIE: length 21.7
  TOP w0.762: v2(13.66,65.61) 13.13,65.07 v6(13.13,62.89) 17.3,62.89 22,67.58 26.42,67.58 v6(26.62,67.39)
  BOTTOM w0.254: R451.1 v2(13.66,65.61)
  BOTTOM w0.305: U65.11 25.26,67.4 ; U65.10 25.25,68.05
VCC5_MON: length 5
  TOP w0.152: U4.38 110.65,131.54 110.36,131.83 v2(110.36,133.76) R18.1
  BOTTOM w0.152: R320.2 v2(110.36,133.76)
VCC5V: length 425.8
  TOP w0.254: R18.2 v2(108.08,133.76) ; CN7.59 42.19,112.49 42.42,112.72 v3(42.42,113.28) ; CN7.60 33.17,112.49 v3(33.15,112.51)
  TOP w0.381: TP50.1 159.33,58.17 v3(159.31,58.14) ; R219.2 v3(139.55,52.65) ; R245.2 155.22,34.9 156.21,33.91 157.12,33.91 157.67,33.36 U32.5 v3(157.67,32.07)
  L3_SIG1 w0.508: J8.4 23.5,18.16 40.39,1.27 77.62,1.27 80.19,3.84 82.73,3.84 84.1,2.46 103.4,2.46 103.94,3 105.11,3 107.18,5.07 107.18,12.59 109.04,14.45 123.31,14.45 123.88,13.89 126.34,13.89 126.8,14.35 126.8,22.78 128.02,24 136.31,24 138.01,25.7 148.89,25.7 151.49,28.3 151.49,31.42 159.5,39.44 159.5,57.95 v3(159.31,58.14)
  L5_SIG2 w0.635: 156.57,66.69 160.22,70.34 160.22,85.85 165.32,90.94 165.32,93.7 165.16,93.85 165.16,97.02 164.38,97.81 164.38,100.47 163.83,101.01 162.86,101.01 162.06,101.8 162.06,109.66 158.71,113.01 157.34,113.01 155.56,114.79 155.56,120.4 155,120.96 155,120.96 153.9,122.06 139.12,122.06 138.76,121.7 136.88,121.7 135.74,122.85 135.74,123.96 132.67,127.03 132.67,127.76 130.06,130.37 122.92,130.37 121.6,131.69 120.7,131.69 120.03,132.36 120.03,136.22 119.54,136.71 117.68,136.71 115.56,134.58 110.09,134.58 109.31,133.79 108.12,133.79 v2(108.08,133.76) ; v3(33.15,112.51) 33.92,113.28 v3(42.42,113.28)
  L10_SIG4 w0.635: v3(42.42,113.28) 41.65,114.06 41.65,122.22 42.68,123.24 43.92,123.24 45.53,124.85 61.65,124.85 62.15,124.35 68,124.35 70.07,126.42 77.95,126.42 78.79,125.58 87.39,125.58 88.27,126.46 95.57,126.46 102.87,133.76 v2(108.08,133.76)
  BOTTOM w0.381: U32.5 v3(157.67,32.07) ; J8.4 19.71,18.87 ; J8.4 19.71,17.45 ; J8.4 18.3,17.45 ; J8.4 18.3,18.87
  vias: v3(158.29,59.41) v3(158.29,58.14) v3(159.31,59.41) v3(163.45,51.45) v3(164.85,51.45)
VCC5V_EN: length 134.9
  TOP w0.152: R60.2 114.4,121.52 114.43,121.49 114.43,121.46 v1(114.39,121.46)
  TOP w0.254: U25.10 146.14,56.62 v3(146.51,56.26)
  L10_SIG4 w0.107: v3(146.51,56.26) 146.51,64.39 152.73,70.61 152.73,71.38 157.17,75.82 161.34,75.82 169.53,84.01 169.53,88.22 168.88,88.87 168.88,108.76 166.65,111 159.12,111 156.62,113.5 155.74,113.5 154.43,114.8 154.43,119.72 149.8,124.35 136.12,124.35 134.34,126.12 129.67,126.12 129.25,125.7 124.84,125.7 120.96,121.83 117.78,121.83 117.69,121.92 114.91,121.92 114.45,121.46 v1(114.39,121.46)
  BOTTOM w0.381: R609.2 v3(146.51,56.26)
VCC12: length 190.2
  TOP w0.254: 158.12,71.01 C112.1 158.72,71.2 158.41,71.51 U22.6 ; 158.12,71.01 U22.5 ; 158.12,71.01 158.12,70.76 157.86,70.51 U22.4 ; 140.67,56.62 140.67,56.87 140.92,57.12 U25.4 ; 140.67,56.62 C139.1 140.06,56.44 140.37,56.12 U25.6 ; 140.67,56.62 U25.5 ; U33.22 102.56,9.05 102.56,6.73 C283.1 101.55,5.73 v2(101.55,5.37) ; v3(61.06,9.78) 61.33,9.51 U34.25
  TOP w0.381: v6(41.4,14.73) 41.4,19.06 45.97,23.62 TP61.1 R254.1
  TOP w0.635: 27.2,10.42 F1.2 ; F1.2 28.61,10.42 ; F1.2 27.2,9.01 ; F1.2 28.61,9.01
  L3_SIG1 w1.016: v6(84.45,14.73) 84.45,24.94 v3(85.57,26.06)
  L5_SIG2 w0.762: v2(129.92,129.16) 129.92,128.24 131.86,126.3 131.86,124.09 135.2,120.75 139.6,120.75 139.95,121.11 153.51,121.11 154.61,120.01 154.61,114.4 156.95,112.06 157.53,112.06 159.11,110.49 159.11,108.53 159.27,108.37 159.27,96.88 161.65,94.51 161.65,91.38 159.27,89 159.27,77.82 156.69,75.24 142.18,75.24 133.4,66.46 133.4,56.21 134.69,54.91 v3(135.43,54.91)
  L9_PWR2 w0.381: 8.55,88.65 J4.A2 ; J4.A2 9.45,89.55 ; J4.A2 9.45,88.65 ; J4.A2 8.55,89.55 ; J4.B2 10.65,89.55 ; J4.B2 10.65,88.65 ; J4.B2 9.75,88.65 ; J4.B2 9.75,89.55 ; 27.18,8.99 F1.2 ; F1.2 27.18,10.44 ; F1.2 28.63,10.44 ; F1.2 28.63,8.99 ; 18.3,26.49 J8.1 ; J8.1 19.71,26.49 ; J8.1 19.71,25.07 ; J8.1 18.3,25.07 ; 9.75,87.05 J4.B1 10.65,87.05 ; 9.45,87.05 J4.A1 8.55,87.05
  BOTTOM w0.381: 18.08,26.71 J8.1 ; J8.1 19.93,24.85 ; J8.1 19.93,26.71 ; J8.1 18.08,24.85 ; C842.1 61.25,9.74 61.06,9.55 v3(61.06,9.78)
  BOTTOM w0.889: FAN1.2 85.28,29.19 C797.1
  BOTTOM w1.016: v3(85.57,26.06) 85.57,26.76 C797.1
  vias: v2(129.03,129.16) v3(135.43,53.52) v3(136.83,54.91) v3(136.83,53.52) v3(161.95,74.19) v3(161.95,72.8) v3(163.35,74.19) v3(163.35,72.8) v6(40.01,14.73) v6(40.01,13.34) v6(40.01,11.94) v6(41.4,13.34) v6(41.4,11.94) v6(43.84,7.42) v6(43.84,6.02) v6(45.24,7.42) v6(45.24,6.02) v6(46.63,7.42) v6(46.63,6.02) v6(83.19,14.73) v6(83.19,13.34) v6(84.45,13.34) v6(111.12,13.34) v6(112.39,13.34)
VCC12_AMC: length 140.6
  TOP w0.381: v3(9.88,18.21) 9.66,17.99 2.93,17.99 2.92,18 AMC1.18 ; v3(9.63,25.48) 8.9,24.75 AMC1.27 ; AMC1.72 9.05,58.5 v3(9.63,59.08) ; v3(8.26,66.98) 7.73,67.5 AMC1.84 ; v3(8.41,6) 8.41,6 AMC1.2 ; v3(9.65,36) AMC1.42
  TOP w0.483: v3(9.83,11.25) AMC1.9 ; AMC1.57 8.87,47.25 v3(9.63,48.01)
  TOP w0.635: J11.1 20.61,3.13 ; J11.1 16.15,5.09 ; J11.1 16.15,3.13 ; J11.1 20.61,5.09 ; 24.78,6.4 F1.1 ; F1.1 26.63,4.55 ; F1.1 24.78,4.55 ; F1.1 26.63,6.4
  L4_PWR1 w0.381: 24.98,4.75 F1.1 ; F1.1 24.98,6.2 ; F1.1 26.43,6.2 ; F1.1 26.43,4.75 ; 16.15,5.09 J11.1 ; J11.1 20.61,3.13 ; J11.1 16.15,3.13 ; J11.1 20.61,5.09
  L5_SIG2 w0.381: 24.98,6.2 F1.1 ; F1.1 26.43,6.2 ; F1.1 24.98,4.75 ; F1.1 26.43,4.75 ; 16.15,3.13 J11.1 ; J11.1 20.61,3.13 ; J11.1 16.15,5.09 ; J11.1 20.61,5.09
  L8_SIG3 w0.381: 16.15,3.13 J11.1 ; J11.1 16.15,5.09 ; J11.1 20.61,5.09 ; J11.1 20.61,3.13 ; F1.1 26.43,4.75 ; F1.1 24.98,4.75 ; F1.1 24.98,6.2 ; F1.1 26.43,6.2
  L10_SIG4 w0.381: F1.1 26.43,6.2 ; F1.1 24.98,4.75 ; F1.1 24.98,6.2 ; F1.1 26.43,4.75 ; 16.15,3.13 J11.1 ; J11.1 16.15,5.09 ; J11.1 20.61,3.13 ; J11.1 20.61,5.09
  BOTTOM w0.381: 16.15,3.13 J11.1 ; J11.1 16.15,5.09 ; J11.1 20.61,5.09 ; J11.1 20.61,3.13 ; F1.1 26.63,4.55 ; F1.1 24.78,4.55 ; F1.1 26.63,6.4 ; F1.1 24.78,6.4
VCCPLLA1A: length 8
  TOP w0.254: C49.1 72.11,100.16 71.27,99.31 69.7,99.31 69.17,98.79 U18.37
  TOP w0.381: B3.3 71.92,103.25 72.11,103.05 C41.1 C49.1
VCCPLLA2A: length 8.2
  TOP w0.254: U17.37 87.05,99.06 88.09,100.1 89.69,100.1 90.04,100.45 C48.1
  TOP w0.381: B1.3 89.53,103.28 90.04,102.78 C39.1 90.04,102.11 90.06,102.09 90.06,101.38 90.04,101.37 C48.1
VDD33: length 21.5
  TOP w0.254: U23.Y11 v4(59.18,66.16) ; TP39.1 27.69,80.06 v3(28.73,79.02) ; R172.1 43.75,91.13 v1(43.69,91.19) ; U23.P11 v4(64.78,66.16)
  L5_SIG2 w0.152: 64.78,66.17 65.17,66.57 65.17,67.93 64.94,68.16 62.21,68.16 61.17,67.12 61.17,66.79 60.94,66.56 60.61,66.56 60.38,66.33 60.38,65.99 60.14,65.76 59.57,65.76 v4(59.18,66.16)
  L5_SIG2 w0.188: 64.78,66.17 v4(64.78,66.16)
  BOTTOM w0.127: U62.A1 25.86,77.93
  BOTTOM w0.152: C539.1 C557.1
  BOTTOM w0.254: C537.1 v4(64.78,66.16) C545.1 ; v4(59.18,66.16) C539.1
  BOTTOM w0.508: FB27.2 C517.1 32.65,67.11 32.7,67.06 32.74,67.09 v3(32.74,67.11)
  vias: v2(46,83.9) v3(28.73,78.05) v3(30.76,77.93) v3(31.57,77.9) v3(50.14,80.62) v3(50.98,80.62)
VDD_USB_0: length 2.8
  TOP w0.254: U23.U10 v4(62.38,66.96) ; U23.V11 v4(60.78,66.16)
  BOTTOM w0.254: v4(60.78,66.16) 60.86,66.24 C529.1 ; C528.1 62.35,66.93 v4(62.38,66.96)
  BOTTOM w0.508: v2(60.15,85.01) 60.33,85.19 FB20.1
VDD_USB_1: length 4.1
  TOP w0.254: U23.R12 v4(63.98,65.36) ; U23.T11 v4(63.18,66.16)
  BOTTOM w0.254: C546.1 v4(63.98,65.36) ; C538.1 v4(63.18,66.16)
  BOTTOM w0.508: v3(40.13,59.13) 40.13,59.08 39.65,58.6 38.91,58.6 FB30.1
VDDA: length 2.7
  TOP w0.254: U33.19 v2(101.04,7.37)
  BOTTOM w0.254: C853.2 100.84,7.17 v2(101.04,7.37)
VDDAHV: length 12.8
  TOP w0.254: U23.AH11 v4(52.78,66.16) ; U23.AH21 v4(52.78,57.36) ; v4(53.58,54.16) U23.AH25 ; U23.AH13 v4(52.78,64.56) ; U23.AH17 v4(52.78,61.36) ; U23.AH19 v4(52.78,58.96) ; U23.AH15 v4(52.78,62.96) ; U23.AH23 v4(52.78,55.76)
  BOTTOM w0.152: v4(53.58,54.16) 53.49,54.16 53.18,54.47 C670.1 53.25,55.36 53.72,55.36 53.72,55.35 53.74,55.35 53.97,55.12 53.97,55.11 53.98,55.1 C695.1
  BOTTOM w0.254: C670.1 v4(52.78,55.76) ; C695.1 v4(53.58,54.16) ; C620.1 v4(52.78,58.96) C621.1 ; C647.1 v4(52.78,57.36) C648.1 ; C598.1 v4(52.78,61.36) ; C540.1 v4(52.78,66.16) ; C583.1 v4(52.78,62.96) ; C561.1 v4(52.78,64.56)
  vias: v3(32.41,62.31) v3(32.41,61.09) v3(33.63,62.31) v3(33.63,61.09)
VDDALV: length 27.6
  TOP w0.381: U23.AE24 v4(55.18,54.96) U23.AF25 v4(54.38,54.16) ; U23.AE10 v4(55.18,66.96) U23.AF9 v4(54.38,67.76) ; v4(53.58,56.56) U23.AG22 v4(54.38,57.36) U23.AF21 v4(55.18,58.16) U23.AE20 ; v4(54.38,66.16) U23.AF11 v4(55.18,65.36) U23.AE12 ; v4(53.58,58.16) U23.AG20 v4(54.38,58.96) U23.AF19 v4(55.18,59.76) U23.AE18 U23.AF17 v4(54.38,61.36) U23.AG16 v4(53.58,62.16) ; U23.AE22 v4(55.18,56.56) U23.AF23 v4(54.38,55.76) U23.AG24 v4(53.58,54.96) ; U23.AE14 v4(55.18,63.76) U23.AF13 v4(54.38,64.56) ; U23.AE16 v4(55.18,62.16) U23.AF15 v4(54.38,62.96) ; U23.AG18 v4(53.58,59.76)
  BOTTOM w0.254: C593.1 v4(53.58,62.16) ; C669.1 v4(54.38,55.76) ; C527.1 v4(55.18,66.96) ; C609.1 v4(53.58,59.76) ; C646.1 v4(54.38,57.36) ; C560.1 v4(54.38,64.56) ; C631.1 v4(53.58,58.16) ; C550.1 v4(55.18,65.36) ; C514.1 v4(54.38,67.76) ; C592.1 v4(55.18,62.16) ; C659.1 v4(53.58,56.56) ; C680.1 v4(55.18,54.96) ; C630.1 v4(55.18,58.16) ; C572.1 v4(55.18,63.76)
  vias: v3(32.61,50.77) v3(32.61,49.81) v3(33.58,50.77) v3(33.58,49.81)
VDDCMON: length 30.7
  TOP w0.152: U23.J10 v4(68.78,66.96)
  TOP w0.254: R545.1 73.96,86.72 v1(73.96,86.64) 74.53,86.08 TP86.1
  L5_SIG2 w0.107: v4(68.78,66.96) 69.14,67.33 69.7,67.33 69.94,67.57 69.94,67.84 70.29,68.19 72.13,68.19 72.14,68.2 72.16,68.2 72.41,68.45 72.41,68.71 72.62,68.93 72.89,68.93 73.21,69.25 73.21,69.51 73.49,69.79 73.73,69.79 73.94,70.01 73.94,70.25 74.29,70.59 74.53,70.59 74.74,70.81 74.74,70.83 74.8,70.88 74.8,72.65 74.46,72.99 74.22,72.99 73.94,73.27 73.94,74.43 72.67,75.7 72.67,80.82 71.88,81.61 71.88,86.47 72.56,87.15 73.46,87.15 v1(73.96,86.64)
  BOTTOM w0.254: C520.1 v4(68.78,66.96)
VDDCMON_R: length 157.8
  TOP w0.254: R544.1 R545.2 74.27,87.68 74.89,87.68 v1(75.48,87.1)
  TOP w0.305: U34.31 v2(61.34,6.51)
  L3_SIG1 w0.152: v2(61.34,6.51) 61.82,6.99 61.82,10.12 71.76,20.07 76.72,20.07 79.48,22.82 79.48,27.34 76.61,30.21 76.61,35.95 79.39,38.73 86.94,38.73 91.21,43 96.72,43 97.99,44.27 101.96,44.27 102.9,45.21 106.07,45.21 106.65,45.8 109.39,45.8 109.75,46.16 109.75,47.44 112.17,49.85 112.17,63.3 113.31,64.44 113.31,78.34 107.52,84.12 106.79,84.12 105.99,84.93 99.54,84.93 99.32,84.7 97.32,84.7 95.22,86.8 77.5,86.8 77.21,87.1 v1(75.48,87.1)
VDDD: length 53.9
  TOP w0.254: U33.20 101.54,7.45 v2(101.75,7.24) ; R272.1 100.33,4.01 v1(100.2,3.88)
  L3_SIG1 w0.254: v2(101.75,7.24) 102.16,7.24 103.56,8.63 103.56,19.76 v1(102.54,20.78)
  BOTTOM w0.254: C852.2 101.97,6.41 101.75,6.63 v2(101.75,7.24) ; v1(102.54,20.78) 102.25,20.78 102.01,20.53 R282.1
  BOTTOM w0.508: C852.2 102.96,6.41 103.5,5.87 103.5,4.26 102.26,3.02 101.06,3.02 v1(100.2,3.88) 99.78,3.88 99.01,3.11 99.01,2.6 98.5,2.09 95.81,2.09 94.89,3.01 94.89,6.73 94.91,6.74 94.91,8.24 94.89,8.26 94.89,16.03 96.32,17.45 97.89,17.45 98.04,17.6 R567.1
VDDG: length 3.7
  TOP w0.254: U33.18 v2(100.54,8.13)
  BOTTOM w0.254: C854.2 99.89,6.41 100.08,6.6 100.08,7.67 v2(100.54,8.13)
VDDPLL0: length 6.3
  TOP w0.254: U23.E14 v4(71.98,63.76) ; U23.G24 v4(70.38,54.96) ; U23.G16 v4(70.38,62.16) ; U23.G22 v4(70.38,56.56) ; U23.G8 v4(70.38,68.56)
  BOTTOM w0.152: 72.37,64.9 72.37,64.22
  BOTTOM w0.178: C551.1 72.37,64.9 ; 72.37,64.22 C562.1
  BOTTOM w0.254: C586.1 v4(70.38,62.16) ; v4(71.98,63.76) C562.1 ; C674.1 v4(70.38,54.96) ; C651.1 v4(70.38,56.56) ; C495.1 v4(70.38,68.56)
  vias: v3(79.17,62.87)
VSS_RTC: length 8.9
  TOP w0.152: C32.1 v1(154.81,106.75) ; C37.1 v1(154.57,103.69)
  TOP w0.254: U15.H18 v1(152.22,104.88)
  L3_SIG1 w0.254: v1(154.81,106.75) 154.57,106.51 v1(154.57,103.69) 154.18,103.3 153.39,103.3 152.87,103.82 152.87,104.23 v1(152.22,104.88)
VSSCMON: length 30.4
  TOP w0.152: U23.J9 v4(68.78,67.76)
  TOP w0.254: TP93.1 74.26,89.57 v1(73.84,89.15) 74.48,88.52 R547.1
  L5_SIG2 w0.107: v1(73.84,89.15) 73.84,88.75 71.65,86.56 71.65,81.51 72.34,80.82 72.34,75.29 73.14,74.49 73.14,73.21 73.43,72.93 73.73,72.93 73.99,72.67 73.99,70.71 73.8,70.53 73.42,70.53 73.21,70.31 73.21,70.07 72.93,69.79 72.69,69.79 72.41,69.51 72.41,69.27 72.13,68.99 70.29,68.99 69.94,68.64 69.94,68.41 69.7,68.16 69.7,68.16 69.18,68.16 v4(68.78,67.76)
  BOTTOM w0.254: C503.1 v4(68.78,67.76)
VSSCMON_R: length 161
  TOP w0.254: R546.2 R547.2 74.27,88.09 75.39,88.09 75.64,88.34 v1(75.64,89.2)
  TOP w0.305: U34.32 61.52,6.01 61.21,5.71 v2(61.21,5.7)
  L3_SIG1 w0.152: v1(75.64,89.2) 77.76,87.08 95.34,87.08 97.44,84.98 99.2,84.98 99.42,85.2 106.11,85.2 106.91,84.4 107.64,84.4 112.44,79.6 113.59,78.46 113.59,64.32 112.45,63.18 112.45,49.74 110.03,47.32 110.03,46.05 109.5,45.52 106.77,45.52 106.18,44.93 103.1,44.93 102.17,44 98.13,44 96.85,42.72 91.32,42.72 87.05,38.46 79.51,38.46 76.89,35.83 76.89,30.33 79.76,27.46 79.76,22.71 76.84,19.79 71.88,19.79 65.34,13.25 65.3,13.25 62.07,10.02 62.07,6.56 v2(61.21,5.7)
25M_CLK_REFN: length 3.4
  TOP w0.102: R167.2 60.14,92.18 60.2,92.24 62.14,92.24 62.26,92.12 U18.12
25M_CLK_REFP: length 5
  TOP w0.102: U18.11 62.26,92.62 62.14,92.5 60.25,92.5 60.14,92.6 R164.2 R163.2
25M_SEC_REFN: length 15.5
  TOP w0.102: R177.1 79.55,87.8 79.33,87.59 79.33,86.74 79.03,86.44 77.14,86.44 76.28,87.3 76.28,89.96 75.59,90.65 74.78,90.65 74.4,91.04 74.4,91.72 74.04,92.08 71.13,92.08 70.97,92.24 70.7,92.24 70.58,92.12 U18.25
25M_SEC_REFP: length 15.4
  TOP w0.102: R178.1 78.95,87.8 79.08,87.67 79.08,86.84 78.93,86.69 78.57,86.69 78.46,86.79 78.24,86.79 78.13,86.69 77.91,86.69 77.8,86.79 77.58,86.79 77.47,86.69 77.25,86.69 76.53,87.41 76.53,90.07 76.22,90.38 75.69,90.91 74.89,90.91 74.65,91.14 74.65,91.82 74.14,92.33 73.83,92.33 73.72,92.43 73.5,92.43 73.39,92.33 73.17,92.33 73.06,92.43 72.84,92.43 72.73,92.33 71.24,92.33 71.07,92.5 70.7,92.5 70.58,92.62 U18.26
9090FPWM4: length 14.8
  TOP w0.152: v1(119.13,125.86) 118.82,126.17 U4.13
  BOTTOM w0.152: v1(119.13,125.86) 119.13,125.17 122.34,121.96 122.34,117.94 CN5.1
9090FPWM6: length 13.6
  TOP w0.152: U4.15 119.38,127.54 120.05,126.86 v1(120.05,126.75)
  BOTTOM w0.152: v1(120.05,126.75) 120.05,126.3 123.76,122.59 123.76,119.06 CN5.2
9090FPWM7: length 11.7
  TOP w0.152: U4.16 119.59,128.04 119.76,127.87 119.76,127.87 v1(120.07,127.55)
  BOTTOM w0.152: v1(120.07,127.55) 120.08,127.55 124.51,123.12 124.51,120.85 125.73,119.63 CN5.3
9090FPWM8: length 10.2
  TOP w0.152: U4.17 v1(119.76,128.54)
  BOTTOM w0.152: CN5.4 125.73,123.28 125.31,123.7 122.65,126.36 121.93,126.36 v1(119.76,128.54)
AMC0_SGMII2_RX_DN: length 59.2
  TOP w0.102: C157.2 40.32,50.13 40.16,49.97 38.07,49.97 32.97,44.87 26.89,44.87 17.81,35.8 17.81,27.12 12.14,21.45 12.14,17.14 10.5,15.5 5.09,15.5 4.84,15.75 AMC1.15
AMC0_SGMII2_RX_DN_R: length 10.1
  TOP w0.102: C157.1 41.22,50.06 41.3,49.97 42.79,49.97 46.3,53.49 48.9,53.49 U23.AN26
AMC0_SGMII2_RX_DP: length 59.3
  TOP w0.102: C158.2 40.32,49.61 40.21,49.72 38.18,49.72 33.08,44.62 26.99,44.62 18.07,35.69 18.07,27.02 12.4,21.35 12.4,17.04 10.6,15.25 5.09,15.25 4.84,15 AMC1.14
AMC0_SGMII2_RX_DP_R: length 10
  TOP w0.102: C158.1 41.22,49.6 41.33,49.72 42.89,49.72 46.41,53.23 48.9,53.23 U23.AN27
AMC0_SGMII2_TX_DN: length 81.4
  TOP w0.102: v1(11.5,13.46) 11.29,13.25 5.09,13.25 4.84,13.5 AMC1.12 ; U23.AL27 v4(50.38,52.56)
  BOTTOM w0.102: v4(50.38,52.56) 50.38,52.59 50.22,52.74 49.96,52.74 49.75,52.53 49.53,52.53 49.32,52.74 49.09,52.74 48.88,52.53 48.65,52.53 48.44,52.74 48.21,52.74 48,52.53 47.77,52.53 47.57,52.74 47.34,52.74 47.13,52.53 46.9,52.53 46.69,52.74 46.46,52.74 46.25,52.53 46.02,52.53 45.81,52.74 45.36,52.74 44.23,51.61 39.07,51.61 38.3,50.85 38.3,49.42 39.41,48.32 39.41,44.26 38.39,43.25 30.2,43.25 29.34,42.39 29.34,41.31 27.93,39.9 22.56,39.9 13.56,30.91 13.56,19.43 10.62,16.48 10.62,13.34 10.71,13.24 11.28,13.24 v1(11.5,13.46)
AMC0_SGMII2_TX_DP: length 81.4
  TOP w0.102: AMC1.11 4.84,12.75 5.09,13 11.27,13 v1(11.5,12.77) ; U23.AL26 v4(50.38,53.36)
  BOTTOM w0.102: v1(11.5,12.77) 11.28,12.99 10.61,12.99 10.36,13.23 10.36,16.59 13.31,19.53 13.31,31.01 22.45,40.16 27.82,40.16 29.08,41.42 29.08,42.49 30.09,43.5 38.29,43.5 39.15,44.37 39.15,48.21 38.05,49.32 38.05,50.95 38.96,51.86 44.13,51.86 45.25,52.99 50.01,52.99 v4(50.38,53.36)
AMC1_SGMII3_RX_DN: length 55.1
  TOP w0.102: C146.2 40.32,53.16 40.18,53.02 38.93,53.02 32.9,46.99 27.68,46.99 16.21,35.52 16.21,26.95 11.52,22.25 5.09,22.25 4.84,22.5 AMC1.24
AMC1_SGMII3_RX_DN_R: length 10.2
  TOP w0.102: U23.AM25 49.59,54.95 48.43,54.95 48.21,54.72 45.9,54.72 44.2,53.02 41.3,53.02 41.22,53.11 C146.1
AMC1_SGMII3_RX_DP: length 55.2
  TOP w0.102: AMC1.23 4.84,21.75 5.09,22 11.62,22 16.46,26.84 16.46,35.41 27.79,46.74 33.01,46.74 39.04,52.77 40.23,52.77 40.32,52.69 C153.2
AMC1_SGMII3_RX_DP_R: length 10.2
  TOP w0.102: U23.AM26 49.56,54.17 48.48,54.17 48.22,54.43 45.96,54.43 44.3,52.77 41.33,52.77 41.22,52.65 C153.1
AMC1_SGMII3_TX_DN: length 76.6
  TOP w0.102: v1(10.69,20.2) 10.49,20 5.09,20 4.84,20.25 AMC1.21 ; U23.AK26 v4(51.18,53.36)
  BOTTOM w0.102: v1(10.69,20.2) 10.48,19.99 9.83,19.99 9.73,20.09 9.73,21.6 11.87,23.75 11.87,31.12 21.29,40.54 27.59,40.54 28.74,41.69 28.74,42.91 30,44.17 37.9,44.17 38.64,44.91 38.64,47.79 37.45,48.97 37.45,50.84 39.11,52.49 43.53,52.49 44.98,53.94 45.22,53.94 45.38,53.78 45.61,53.78 45.76,53.94 45.99,53.94 46.15,53.78 46.38,53.78 46.54,53.94 46.77,53.94 46.92,53.78 47.15,53.78 47.31,53.94 47.54,53.94 47.7,53.78 47.93,53.78 48.08,53.94 48.31,53.94 48.47,53.78 48.7,53.78 48.86,53.94 49.09,53.94 49.24,53.78 49.47,53.78 49.63,53.94 50.08,53.94 50.22,53.79 50.88,53.79 51.18,53.5 v4(51.18,53.36)
AMC1_SGMII3_TX_DP: length 76.7
  TOP w0.102: U23.AK25 v4(51.18,54.16) ; v1(10.69,19.52) 10.46,19.75 5.09,19.75 4.84,19.5 AMC1.20
  BOTTOM w0.102: v1(10.69,19.52) 10.48,19.73 9.72,19.73 9.47,19.98 9.47,21.71 11.62,23.85 11.62,31.23 21.18,40.79 27.48,40.79 28.48,41.8 28.48,43.01 29.89,44.42 37.8,44.42 38.39,45.01 38.39,47.68 37.2,48.87 37.2,50.94 39,52.74 43.43,52.74 44.88,54.19 49.89,54.19 50.22,54.53 50.53,54.53 50.9,54.16 v4(51.18,54.16)
AMC2_SATA0_RX_DN: length 27.5
  TOP w0.102: v1(14.12,29.74) 13.91,29.54 13.24,29.54 13.15,29.62 C226.2
  L10_SIG4 w0.102: v1(33.21,29.02) 33.42,29.23 33.42,29.7 33.2,29.92 23.13,29.92 22.97,29.77 22.74,29.77 22.59,29.92 22.36,29.92 22.21,29.77 21.98,29.77 21.83,29.92 21.6,29.92 21.45,29.77 21.22,29.77 21.07,29.92 20.84,29.92 20.69,29.77 20.46,29.77 20.31,29.92 20.08,29.92 19.93,29.77 19.7,29.77 19.54,29.92 19.32,29.92 19.16,29.77 18.93,29.77 18.78,29.92 18.55,29.92 18.4,29.77 18.17,29.77 18.02,29.92 17.79,29.92 17.64,29.77 17.41,29.77 17.26,29.92 17.03,29.92 16.88,29.77 16.65,29.77 16.5,29.92 16.27,29.92 15.79,30.4 15.13,30.4 14.93,30.2 14.7,30.2 14.5,30.4 14.27,30.4 14.07,30.2 13.84,30.2 13.64,30.4 13.42,30.4 13.14,30.12 13.14,29.78 13.36,29.56 13.93,29.56 v1(14.12,29.74)
  BOTTOM w0.102: v1(33.21,29.02) 33.45,29.26 33.45,29.66 33.37,29.74 U75.22
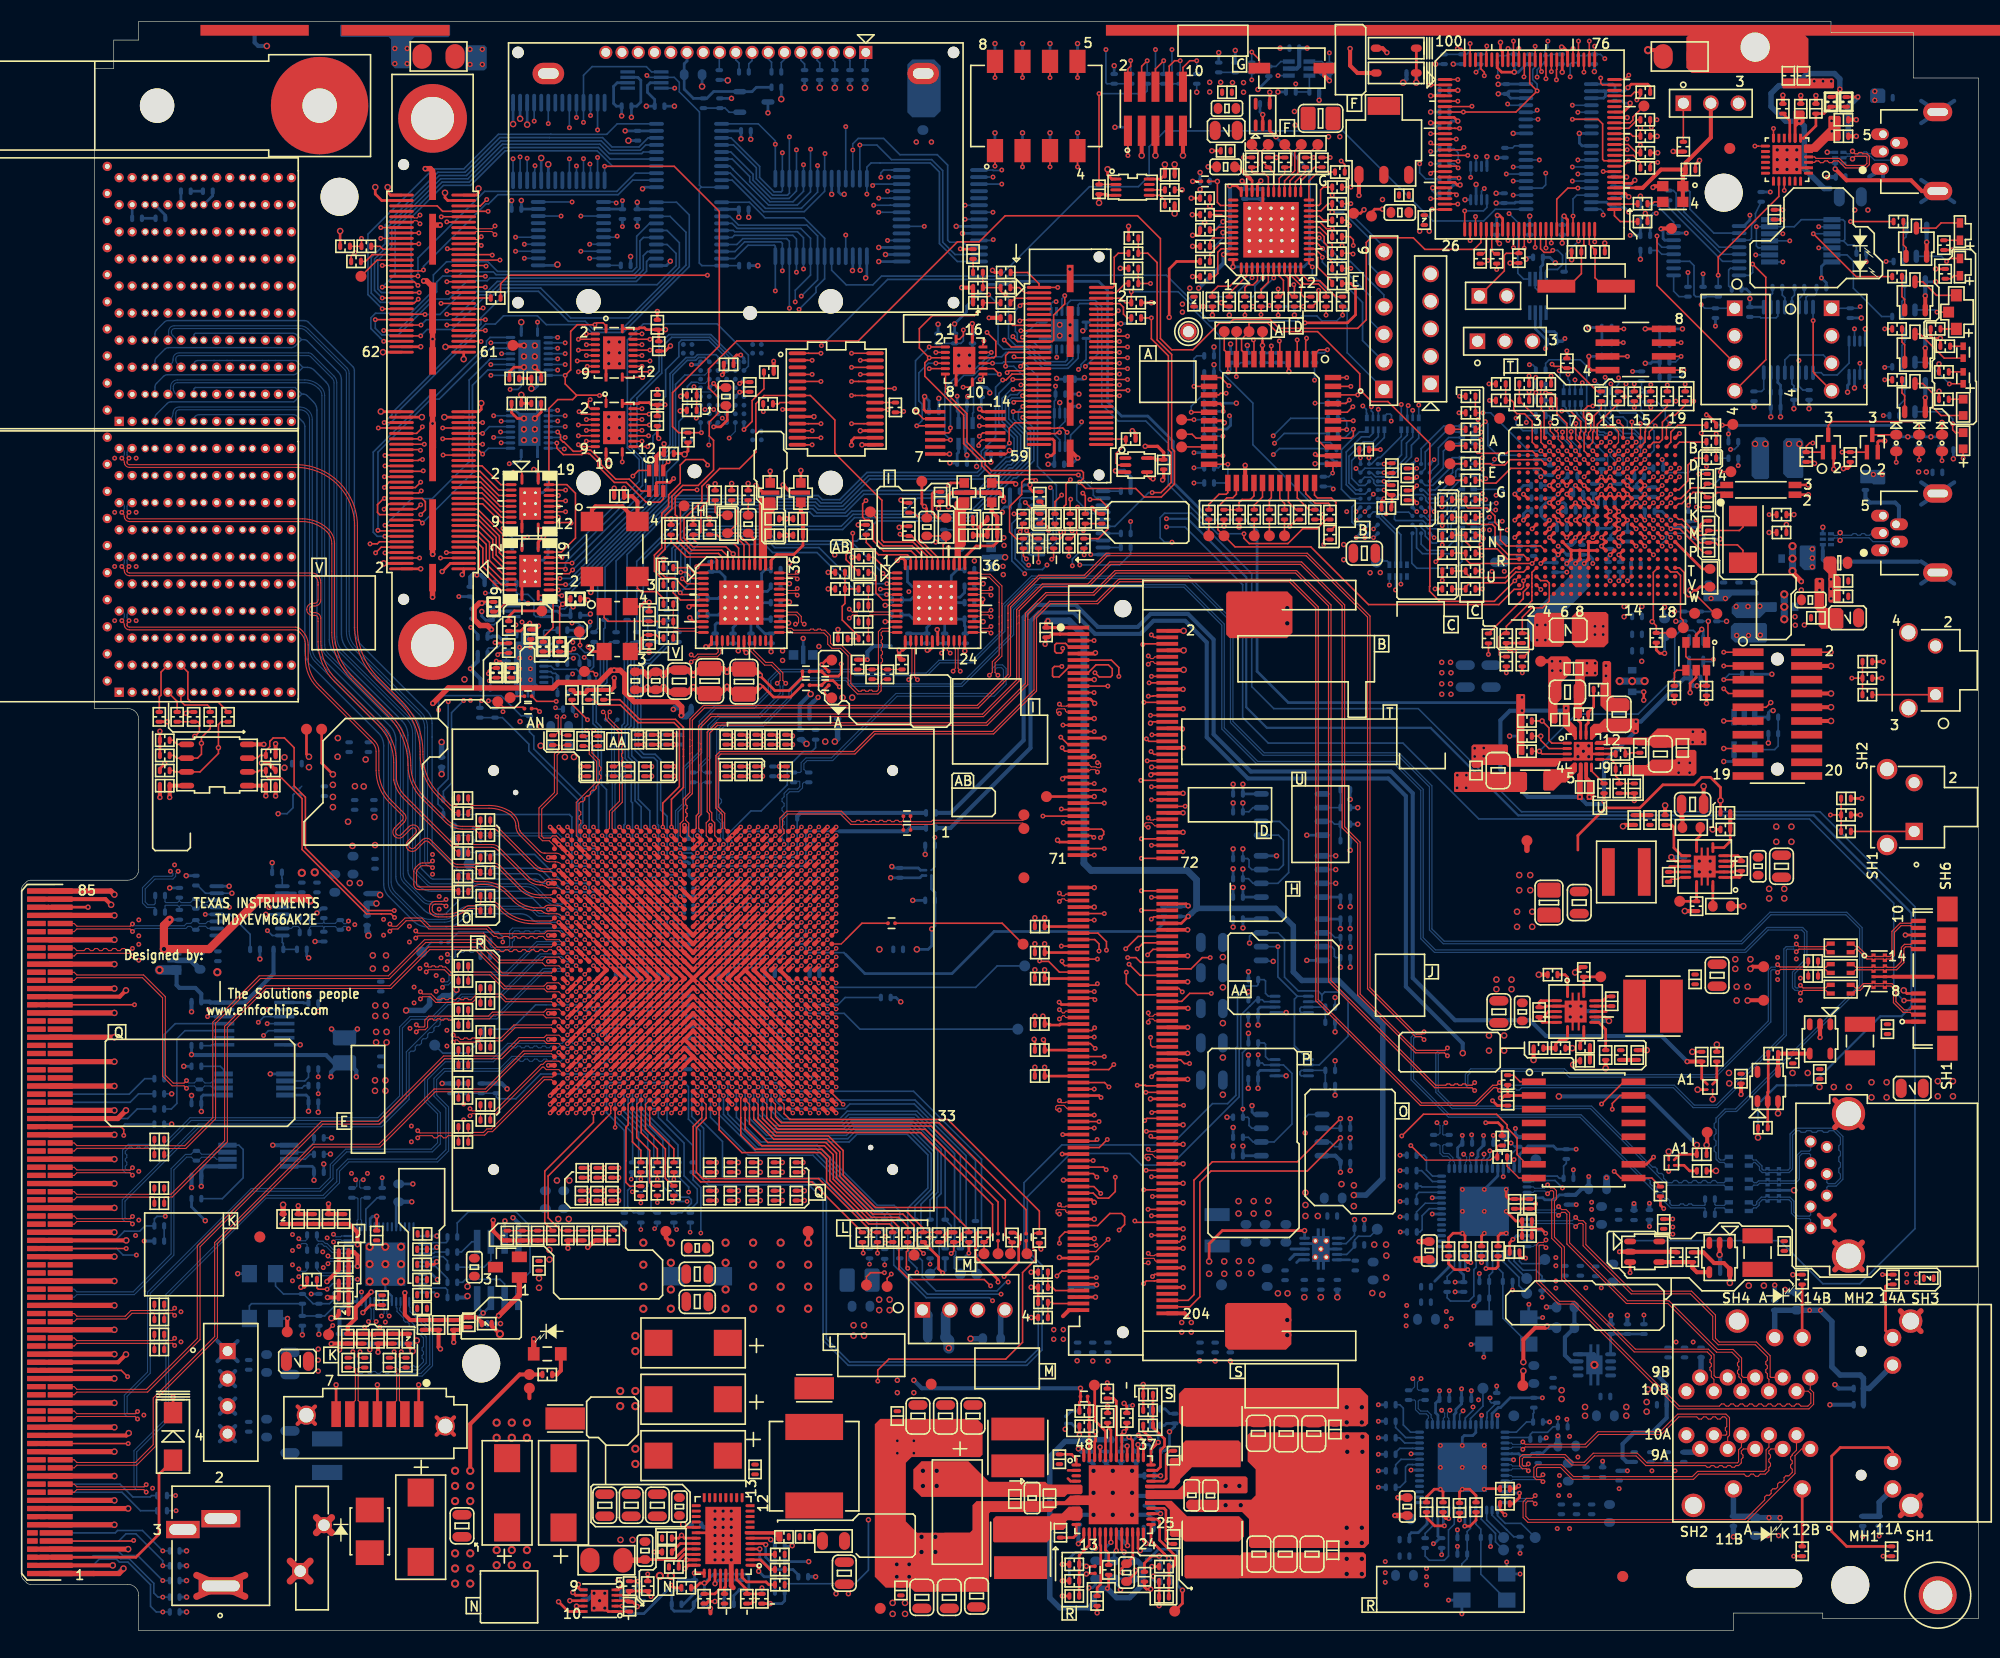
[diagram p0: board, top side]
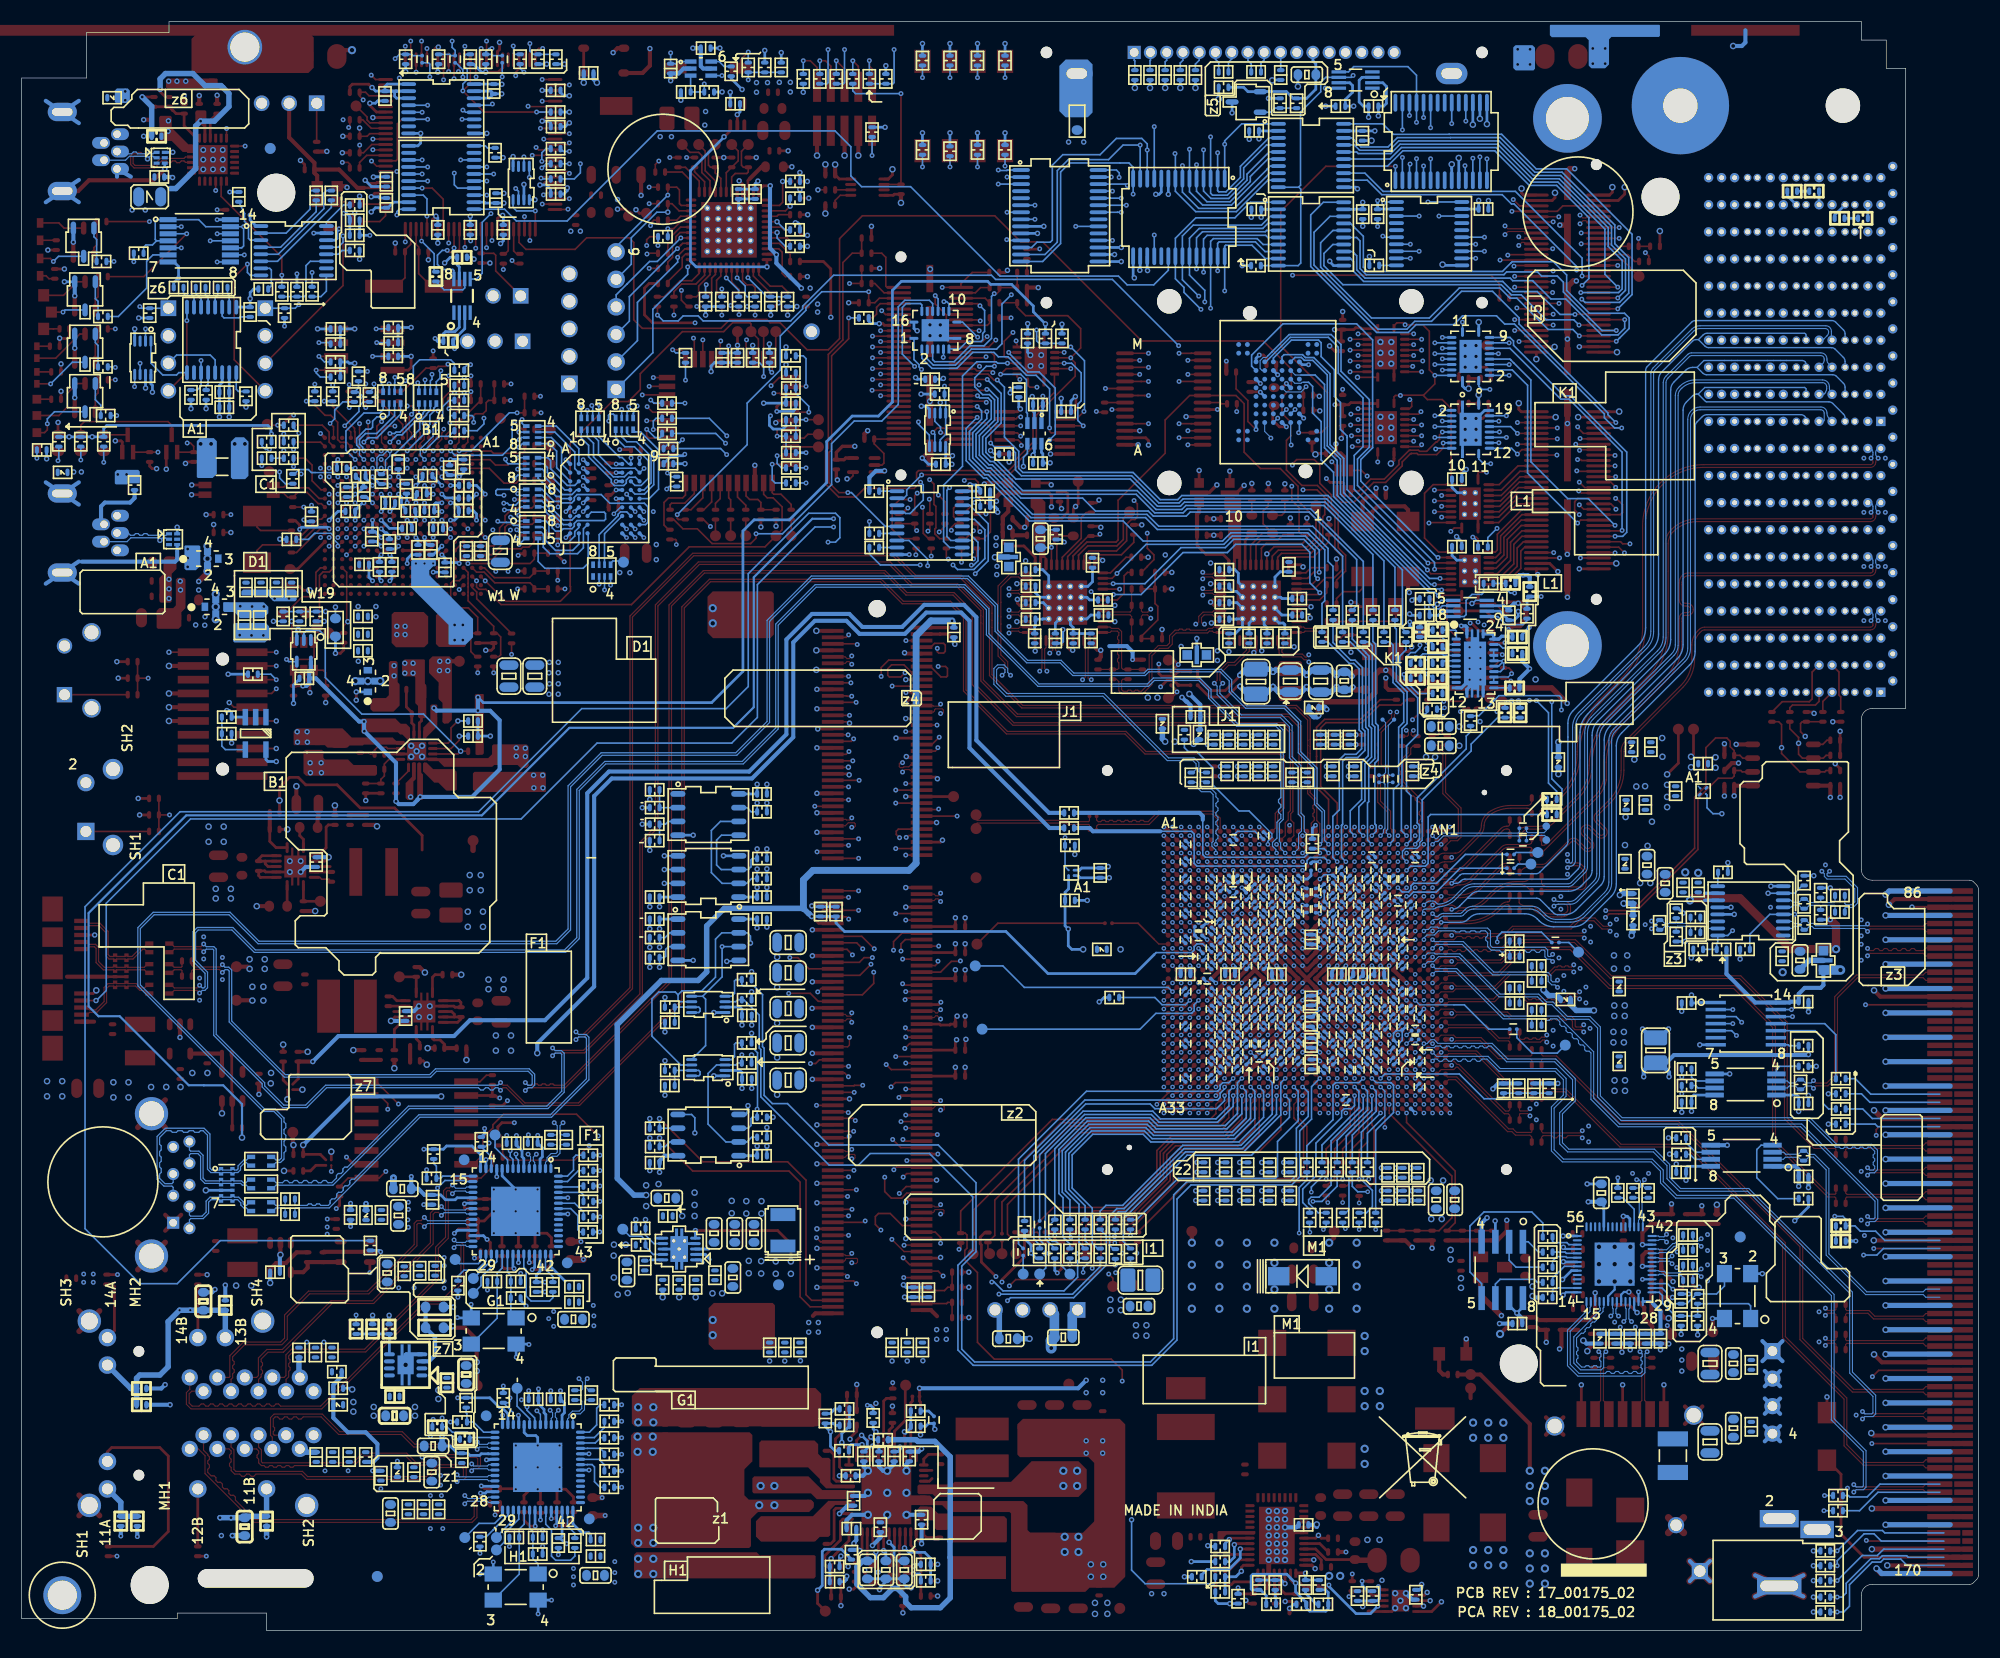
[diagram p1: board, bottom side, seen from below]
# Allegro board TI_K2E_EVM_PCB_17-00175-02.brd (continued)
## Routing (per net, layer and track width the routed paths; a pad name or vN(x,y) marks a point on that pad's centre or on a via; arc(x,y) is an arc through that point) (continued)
AMC2_SATA0_RX_DP: length 27.4
  TOP w0.102: C228.2 13.15,29.15 13.28,29.28 13.91,29.28 v1(14.12,29.08)
  L10_SIG4 w0.102: v1(33.92,29.02) 33.71,29.23 33.71,29.82 33.32,30.21 16.39,30.21 15.91,30.69 13.24,30.69 12.85,30.3 12.85,29.66 13.24,29.27 13.93,29.27 v1(14.12,29.08)
  BOTTOM w0.102: U75.21 33.77,29.74 33.71,29.68 33.71,29.23 v1(33.92,29.02)
AMC2_SATA0_TX_DN: length 27.1
  TOP w0.102: v1(14.12,26.96) 13.91,26.76 13.23,26.76 13.15,26.84 C233.2
  L10_SIG4 w0.102: v1(14.12,26.96) 13.93,26.78 13.38,26.78 13.28,26.88 13.28,27.53 13.58,27.84 13.9,27.84 14.03,27.71 14.26,27.71 14.38,27.84 14.61,27.84 14.74,27.71 14.97,27.71 15.1,27.84 15.32,27.84 15.45,27.71 15.68,27.71 15.81,27.84 16.04,27.84 16.16,27.71 16.39,27.71 16.52,27.84 16.75,27.84 16.87,27.71 17.1,27.71 17.23,27.84 27.91,27.84 29,26.75 32.17,26.75 32.5,27.08 32.5,28.29 v1(32.72,28.51)
  BOTTOM w0.102: v1(32.72,28.51) 32.51,28.73 32.51,29.68 32.57,29.74 U75.24
AMC2_SATA0_TX_DP: length 27.1
  TOP w0.102: C238.2 13.15,26.42 13.23,26.51 13.91,26.51 v1(14.12,26.3)
  L10_SIG4 w0.102: v1(14.12,26.3) 13.93,26.49 13.26,26.49 12.98,26.76 12.98,27.65 13.46,28.13 28.03,28.13 29.12,27.04 32.05,27.04 32.21,27.2 32.21,28.32 v1(32.01,28.51)
  BOTTOM w0.102: U75.25 32.17,29.74 32.25,29.66 32.25,28.75 v1(32.01,28.51)
AMC4_PCIE0_RX0N: length 53.3
  TOP w0.102: U23.AN17 48.9,60.69 44.35,60.69 41.94,63.09 37.56,63.09 33.98,59.51 22.48,59.51 18.73,55.76 18.73,45.2 13.79,40.26 13.22,40.26 13.15,40.33 C176.2
AMC4_PCIE0_RX0P: length 53.3
  TOP w0.102: C187.2 13.15,39.91 13.24,40.01 13.9,40.01 18.98,45.09 18.98,55.66 22.58,59.26 34.08,59.26 37.67,62.84 41.83,62.84 44.24,60.43 48.9,60.43 U23.AN18
AMC4_PCIE0_TX0N: length 50.8
  TOP w0.102: v1(10.23,38.2) 10.02,38 5.09,38 4.84,38.25 AMC1.45
  BOTTOM w0.102: v1(10.23,38.2) 10.01,37.99 9.65,37.99 9.54,38.11 9.54,39.62 16.41,46.49 33.22,46.49 35.76,49.02 35.76,53.3 35.92,53.47 36.2,53.47 36.33,53.6 36.33,53.88 36.49,54.04 36.74,54.04 36.91,54.2 36.91,54.45 37.07,54.61 37.32,54.61 37.48,54.78 37.48,55.03 37.64,55.19 37.89,55.19 38.05,55.35 38.05,55.6 38.21,55.76 38.46,55.76 38.63,55.92 38.63,56.17 38.9,56.45 39.47,56.45 39.61,56.31 39.84,56.31 39.98,56.45 40.21,56.45 40.32,56.34 C662.2
AMC4_PCIE0_TX0N_R: length 12.1
  TOP w0.102: v4(50.38,60.56) U23.AL18
  BOTTOM w0.102: v4(50.38,60.56) 50.1,60.83 48.24,60.83 43.86,56.45 41.38,56.45 41.22,56.29 C662.1
AMC4_PCIE0_TX0P: length 50.8
  TOP w0.102: AMC1.44 4.84,37.5 5.09,37.75 10,37.75 v1(10.23,37.52)
  BOTTOM w0.102: v1(10.23,37.52) 10.01,37.74 9.55,37.74 9.28,38 9.28,39.73 16.3,46.74 33.12,46.74 35.5,49.13 35.5,53.41 38.8,56.71 40.22,56.71 40.32,56.8 C649.2
AMC4_PCIE0_TX0P_R: length 12.2
  TOP w0.102: U23.AL17 v4(50.38,61.36)
  BOTTOM w0.102: C649.1 41.22,56.79 41.3,56.71 43.75,56.71 48.13,61.09 50.1,61.09 v4(50.38,61.36)
AMC5_PCIE0_RX1N: length 51.4
  TOP w0.102: U23.AM16 49.59,62.15 48.33,62.15 48.06,61.87 44.1,61.87 42.22,63.75 37.18,63.75 33.85,60.43 21.93,60.43 17.64,56.14 17.64,47.33 15.05,44.74 13.25,44.74 13.15,44.84 C162.2
AMC5_PCIE0_RX1P: length 51.4
  TOP w0.102: U23.AM17 49.59,61.35 48.33,61.35 48.06,61.62 43.99,61.62 42.11,63.5 37.29,63.5 33.96,60.17 22.03,60.17 17.89,56.03 17.89,47.22 15.16,44.49 13.22,44.49 13.15,44.41 C165.2
AMC5_PCIE0_TX1N: length 52.8
  TOP w0.102: v1(10.23,42.7) 10.02,42.5 5.09,42.5 4.84,42.75 AMC1.51
  BOTTOM w0.102: v1(10.23,42.7) 10.01,42.49 9.7,42.49 9.56,42.63 9.56,42.84 9.7,42.98 9.7,43.21 9.56,43.35 9.56,43.52 9.7,43.66 9.7,43.89 9.56,44.03 9.56,44.23 9.95,44.61 10.17,44.61 10.31,44.48 10.54,44.48 10.67,44.61 10.9,44.61 11.03,44.48 11.26,44.48 11.39,44.61 11.62,44.61 11.75,44.48 11.98,44.48 12.11,44.61 12.34,44.61 12.47,44.48 12.7,44.48 12.84,44.61 13.18,44.61 15.64,47.07 32.98,47.07 35.14,49.23 35.14,55.6 35.95,56.41 38.02,56.41 39.37,57.76 39.96,57.76 40.68,58.48 42.21,58.48 42.35,58.35 C634.2
AMC5_PCIE0_TX1N_R: length 10.9
  TOP w0.102: U23.AK17 v4(51.18,61.36)
  BOTTOM w0.102: v4(51.18,61.36) 50.81,61.73 50.29,61.73 49.82,62.2 47.96,62.2 47.78,62.02 47.77,62.02 44.24,58.48 43.38,58.48 43.25,58.35 C634.1
AMC5_PCIE0_TX1P: length 53
  TOP w0.102: AMC1.50 4.84,42 5.09,42.25 10,42.25 v1(10.23,42.02)
  BOTTOM w0.102: C610.2 42.35,58.89 42.19,58.73 40.58,58.73 39.86,58.01 39.27,58.01 37.92,56.66 35.84,56.66 34.89,55.71 34.89,49.34 32.87,47.33 15.54,47.33 13.08,44.87 9.84,44.87 9.31,44.34 9.31,42.52 9.6,42.24 10.01,42.24 v1(10.23,42.02)
AMC5_PCIE0_TX1P_R: length 10.7
  TOP w0.102: U23.AK16 v4(51.18,62.16)
  BOTTOM w0.102: C610.1 43.25,58.85 43.36,58.74 44.13,58.74 47.67,62.27 47.68,62.27 47.86,62.45 50.15,62.45 50.22,62.53 50.81,62.53 51.1,62.24 51.1,62.23 v4(51.18,62.16)
AMC_JTAG_TCK: length 249.2
  TOP w0.152: U11.11 88.7,110.54 v1(88.39,110.24)
  L8_SIG3 w0.107: v1(13.02,7.34) 12.57,7.79 12.57,11.53 14.66,13.61 28.93,13.61 33.3,9.25 53.04,9.25 59.08,3.2 68.03,3.2 68.26,2.98 74.02,2.98 74.48,2.51 78.61,2.51 79.76,3.66 94.03,3.66 95.55,5.18 95.55,6.31 96.57,7.33 96.57,18.1 97.85,19.38 111.33,19.38 115.39,23.44 115.39,31.35 116.33,32.29 116.33,47.84 115.54,48.63 115.54,58.33 114.2,59.68 114.2,72.65 109.42,77.42 109.42,103.25 107.26,105.41 102.71,105.41 101.92,106.2 101.92,107.83 100.08,109.68 94.85,109.68 94.3,110.24 v1(88.39,110.24)
  BOTTOM w0.152: R578.1 v1(13.02,7.34) 11.15,9.22 8.85,9.22 8.63,9 AMC1.165
AMC_JTAG_TCK_1V8: length 20.4
  TOP w0.152: U11.4 85.57,110.54 85.72,110.69 v1(85.72,111)
  BOTTOM w0.152: U49.2 97.52,117.43 96.58,116.5 94.29,116.5 92.81,117.97 90.86,117.97 90.45,117.56 89.56,117.56 87.85,115.86 86.97,115.86 85.72,114.61 v1(85.72,111)
AMC_JTAG_TDI: length 251.8
  TOP w0.152: U11.13 88.82,111.84 88.65,112.01 v1(88.39,112.01)
  L8_SIG3 w0.107: v1(88.39,112.01) 86.74,110.36 86.74,107.11 87.71,106.15 89.94,106.15 92.96,103.12 106.29,103.12 107.93,101.48 108.51,100.91 108.51,76.92 113.23,72.2 113.23,68.37 111.31,66.45 111.31,62.51 111.43,62.39 111.43,59.97 114.62,56.78 114.62,49.76 114.27,49.41 114.27,31.84 105.96,23.52 102.29,23.52 99.29,20.52 96.04,20.52 95.07,19.55 95.07,14.09 91.73,10.75 79.36,10.75 76.53,7.92 75.68,7.92 72.69,4.94 67.92,4.94 67.33,5.52 63.48,5.52 61.68,7.33 60.16,7.33 57.33,10.16 36.02,10.16 31.53,14.66 14.31,14.66 11.56,11.91 11.56,4.78 12.55,3.78 12.55,2.95 13.02,2.47 v1(13.02,1.7)
  BOTTOM w0.152: AMC1.169 3.19,6 6.58,6 7.16,6.58 8.74,6.58 9.01,6.31 9.8,6.31 11.89,4.22 11.89,2.23 12.42,1.7 v1(13.02,1.7) R595.1
AMC_JTAG_TDI_1V8: length 10
  TOP w0.152: U11.2 83.23,111.84 v1(82.55,112.52) ; U7.2 v1(83.77,118.47)
  BOTTOM w0.152: v1(83.77,118.47) 82.51,117.21 82.51,112.57 v1(82.55,112.52)
AMC_JTAG_TDO: length 244.9
  TOP w0.152: U11.10 88.63,109.89 88.33,109.59 v1(88.33,109.37)
  L8_SIG3 w0.107: v1(88.33,109.37) 88.33,108.5 87.73,107.9 87.73,106.81 87.86,106.68 94.92,106.68 96.14,105.46 98.58,105.46 99.85,104.19 105.55,104.19 108.1,101.64 108.74,101 108.74,77.11 113.45,72.39 113.45,64.53 112.67,63.75 112.67,60.23 114.85,58.05 114.85,49.66 114.5,49.32 114.5,31.74 106.05,23.29 103.39,23.29 100.63,20.53 100.63,20.53 100.4,20.29 96.14,20.29 95.3,19.46 95.3,14 91.83,10.53 80.3,10.53 74.32,4.55 67.99,4.55 67.27,5.26 63.46,5.26 61.59,7.12 60.04,7.12 57.23,9.93 33.63,9.93 29.13,14.43 14.4,14.43 11.79,11.81 11.79,4.98 13.02,3.74 v1(13.02,3.07)
  BOTTOM w0.152: R591.1 v1(13.02,3.07) 12.58,3.07 12.2,3.45 12.2,4.34 9.93,6.61 9.14,6.61 8.86,6.89 6.61,6.89 6.48,6.75 AMC1.168
AMC_JTAG_TDO_1V8: length 12.9
  TOP w0.152: U7.14 v1(89.49,117.97) ; U11.5 v1(85.72,109.89)
  BOTTOM w0.152: v1(89.49,117.97) 89.49,117.93 87.73,116.16 86.69,116.16 85.2,114.68 85.2,110.41 v1(85.72,109.89)
AMC_JTAG_TMS: length 249.9
  TOP w0.152: U11.12 v1(88.39,111.19)
  L8_SIG3 w0.107: v1(13.02,5.97) 12.24,6.75 12.24,11.62 14.59,13.97 28.9,13.97 33.39,9.47 53.26,9.47 56.9,5.84 60.25,5.84 62.46,3.63 67.92,3.63 68.35,3.21 74.12,3.21 74.58,2.74 78.41,2.74 79.65,3.99 94.04,3.99 95.32,5.27 95.32,6.4 95.78,6.86 95.78,18.97 96.42,19.61 106.32,19.61 110.73,24.02 110.73,27.33 115.85,32.44 115.85,42.35 115.31,42.89 115.31,58.24 113.97,59.58 113.97,72.56 109.19,77.33 109.19,101.19 105.74,104.65 102.65,104.65 101.7,105.61 101.7,107.74 99.99,109.45 94.76,109.45 94.23,109.98 90.2,109.98 90.07,109.86 88.23,109.86 88.01,110.08 88.01,110.81 v1(88.39,111.19)
  BOTTOM w0.152: AMC1.166 8.96,8.25 9.63,8.92 10.54,8.92 13.02,6.43 v1(13.02,5.97) R581.1
AMC_JTAG_TMS_1V8: length 9.8
  TOP w0.152: U7.5 v1(84.38,116.97) ; U11.3 v1(82.62,111.19)
  BOTTOM w0.152: v1(82.62,111.19) 83.11,111.69 83.11,113.19 82.81,113.5 82.81,116.09 83.69,116.97 v1(84.38,116.97)
AMC_JTAG_TRST#: length 243.9
  L8_SIG3 w0.107: v1(13.02,4.6) 12.01,5.61 12.01,11.72 14.5,14.2 28.99,14.2 33.49,9.7 57.14,9.7 59.92,6.92 61.51,6.92 63.43,4.99 67.21,4.99 67.89,4.32 74.41,4.32 80.39,10.3 91.92,10.3 95.55,13.93 95.55,19.07 96.35,19.86 105.46,19.86 109.57,23.97 109.57,26.48 115.62,32.54 115.62,42.25 115.08,42.79 115.08,58.15 113.74,59.49 113.74,72.46 108.97,77.23 108.97,101.1 105.65,104.42 102.56,104.42 101.47,105.51 101.47,107.65 99.89,109.22 94.28,109.22 93.42,108.36 89.05,108.36 v2(88.14,107.44)
  BOTTOM w0.152: R585.1 v1(13.02,4.6) 10.71,6.92 9.32,6.92 8.74,7.5 AMC1.167 ; U56.4 87.77,108.65 88.14,108.28 v2(88.14,107.44)
AMC_JTAG_TRST#_1V8: length 8.4
  TOP w0.152: U7.11 89.73,116.47 v1(90.25,115.95)
  BOTTOM w0.152: v1(90.25,115.95) 88.38,115.95 87.86,115.43 87.86,112.43 87.77,112.34 U56.3
AMC_MDC_2V5: length 91.3
  L3_SIG1 w0.152: v1(19.18,66.75) 19.18,66.65 17.42,64.9 17.42,61.09 17.38,61.04 17.38,59.79 17.65,59.51 17.65,44.8 13.26,40.41 v1(13.26,38.23)
  L8_SIG3 w0.107: v1(19.18,66.75) 19.25,66.67 19.74,66.67 24.89,71.83 27.08,71.83 29.57,74.32 29.57,80.09 33.58,84.1 38.46,84.1 38.99,84.63 38.99,85.93 39.47,86.41 39.76,86.41 40.58,87.22 47.1,87.22 47.44,87.56 47.44,89.98 50.44,92.99 v1(50.8,92.99)
  BOTTOM w0.152: R634.2 51.56,92.79 51.36,92.99 v1(50.8,92.99) ; AMC1.129 8.63,36 9.48,36.85 10.9,36.85 11.38,37.34 R621.1 12.25,37.98 12.5,38.23 v1(13.26,38.23)
ATTENTIONZ: length 93.6
  TOP w0.152: U1.14 132.89,136.66 v1(133.12,136.89) ; R211.2 R205.1 ; R205.1 C102.1 ; R205.1 v1(166.95,75.28)
  L5_SIG2 w0.107: v1(133.12,136.89) 132.05,135.83 132.05,129.25 133.93,127.37 133.93,126.65 136.46,124.12 152.73,124.12 155.96,120.88 158.05,120.88 162.85,116.08 162.85,112.04 164.64,110.25 164.64,107.07 167.06,104.65 167.06,100.66 167.56,100.15 167.56,75.89 v1(166.95,75.28)
BD_ID0: length 25.7
  TOP w0.152: CN7.104 v1(33.15,128.49)
  L3_SIG1 w0.102: v1(33.15,128.49) 38.99,134.34 49.78,134.34 51.29,135.85 v1(51.86,135.85)
  BOTTOM w0.152: U39.4 v1(51.86,135.85)
BD_ID1: length 20.2
  TOP w0.152: CN7.106 v1(36.66,128.99)
  L3_SIG1 w0.102: v1(51.21,135.18) 50.14,134.11 41.49,134.11 37.77,130.39 37.77,130.11 v1(36.66,128.99)
  BOTTOM w0.152: U39.5 v1(51.21,135.18)
BD_ID2: length 23.9
  TOP w0.152: CN7.108 v1(33.15,129.49)
  L3_SIG1 w0.102: v1(33.15,129.49) 38.22,134.57 49.29,134.57 v1(50.56,135.84)
  BOTTOM w0.152: U39.6 v1(50.56,135.84)
BD_PRESENT: length 22.5
  TOP w0.152: CN7.102 v1(36.66,127.99)
  L3_SIG1 w0.102: v1(36.66,127.99) 38,129.34 38,130.3 41.46,133.76 50.85,133.76 v1(52.45,135.36)
  BOTTOM w0.152: v1(52.45,135.36) 52.51,135.3 U39.3
BOOTMODE14: length 29.7
  L8_SIG3 w0.107: v1(90.46,134.81) 90.44,134.79 89.7,134.79 89.27,134.35 89.27,134 89.49,133.78 90.19,133.78 90.3,133.89 90.62,133.89 94.08,130.43 94.08,120.19 96.62,117.65 96.62,114.14 v2(95.81,113.33)
  BOTTOM w0.152: v1(90.46,134.81) 90.42,134.76 89.67,134.76 89.62,134.81 U43.1 ; U55.2 v2(95.81,113.33)
BOOTMODE15: length 31
  L8_SIG3 w0.107: v1(97.83,111.56) 98.17,111.9 98.17,114.85 97.16,115.86 97.16,116.56 97.32,116.72 97.32,127.51 90.67,134.16 v1(89.65,134.16)
  BOTTOM w0.152: v1(97.83,111.56) 97.83,111.34 96.81,110.33 U55.5 ; v1(89.65,134.16) U43.2
BOOTMODE_ON: length 29.3
  L8_SIG3 w0.107: v1(90.46,133.51) 93.57,130.4 93.57,120.27 96.09,117.75 96.09,115.27 95.68,114.86 v1(95.42,114.86)
  BOTTOM w0.152: v1(90.46,133.51) U43.3 ; U55.7 95.81,109.9 95.31,110.4 U55.1 95.31,113.47 95.42,113.58 R357.2 v1(95.42,114.86)
BP3: length 16.4
  TOP w0.254: R280.1 63.19,2.47 63.33,2.61 63.34,2.61 63.4,2.67 v2(63.98,2.67) ; C279.1 60.64,8.51 v2(60.91,8.77) 61.17,8.51 U34.27 ; v2(67.61,2.77) 67.32,2.47 R278.2
  L3_SIG1 w0.203: v2(67.61,2.77) 67.52,2.67 v2(63.98,2.67) 62.61,2.67 60.63,4.65 60.63,8.49 v2(60.91,8.77)
BP6: length 2.6
  TOP w0.254: C849.1 60.79,8.01 U34.28
BPCAP: length 3.5
  TOP w0.254: U4.35 113.07,133.36 v2(112.65,133.78)
  BOTTOM w0.254: v2(112.65,133.78) 112.9,133.53 C327.2 C326.1
BSC_JTAG_TCK: length 15.2
  TOP w0.152: U3.2 C12.2 v1(99.44,141.86)
  BOTTOM w0.152: R303.1 103.89,142.11 103.63,141.86 v1(99.44,141.86)
BUFF_EMIFA00: length 34.8
  TOP w0.152: CN7.6 v1(36.73,98.99)
  L8_SIG3 w0.107: v1(49.47,116.34) 48.87,115.74 45.02,115.74 43.8,114.53 37.39,114.53 32.36,109.5 32.36,103.91 36.73,99.54 v1(36.73,98.99)
  BOTTOM w0.152: v1(49.47,116.34) 49.4,116.34 49.39,116.35 U51.18
BUFF_EMIFA01: length 34
  TOP w0.152: CN7.8 33.72,99.49 33.7,99.47 v1(33.53,99.47)
  L8_SIG3 w0.107: v1(33.53,99.47) 33.53,99.47 33.53,100.19 31.8,101.91 31.8,109.26 37.29,114.76 43.71,114.76 44.92,115.97 48.07,115.97 v1(49.47,117.37)
  BOTTOM w0.152: U51.16 49.45,117.35 v1(49.47,117.37)
BUFF_EMIFA02: length 37.5
  TOP w0.152: CN7.10 33.19,99.99 v1(32.66,99.47)
  L8_SIG3 w0.107: v1(49.47,118.35) 48.67,119.16 44.56,119.16 43.31,117.91 37.76,117.91 31.57,111.72 31.57,101.82 32.66,100.73 v1(32.66,99.47)
  BOTTOM w0.152: U51.14 v1(49.47,118.35)
BUFF_EMIFA03: length 37
  TOP w0.152: v1(32.16,100.3) 32.82,100.3 33.02,100.49 CN7.12
  L8_SIG3 w0.107: v1(49.47,119.35) 49.44,119.38 38.91,119.38 31.34,111.82 31.34,102.2 31.34,101.82 31.34,101.82 31.34,101.11 v1(32.16,100.3)
  BOTTOM w0.152: U51.12 v1(49.47,119.35)
BUFF_EMIFA04: length 27.5
  TOP w0.152: v1(33.53,100.99) CN7.14
  BOTTOM w0.152: v1(33.53,100.99) 32.82,100.99 32.45,101.36 32.45,108.77 37.65,113.96 38.24,113.96 42.9,118.63 42.9,119.02 43.23,119.35 U51.9
BUFF_EMIFA05: length 25.6
  TOP w0.152: v1(32.88,101.54) 32.93,101.49 CN7.16
  BOTTOM w0.152: v1(32.88,101.54) 32.88,108.77 37.77,113.66 38.54,113.66 43.23,118.35 U51.7
BUFF_EMIFA06: length 23.9
  TOP w0.152: CN7.18 33.72,101.99 33.71,102.01 v1(33.53,102.01)
  BOTTOM w0.152: v1(33.53,102.01) 36,104.47 37.9,104.47 41.3,107.87 41.3,115.42 42.89,117.01 43.23,117.35 U51.5
BUFF_EMIFA07: length 20.8
  TOP w0.152: v1(36.99,102.21) 36.71,102.49 CN7.20
  BOTTOM w0.152: U51.3 43.02,116.35 41.61,114.94 41.61,106.83 v1(36.99,102.21)
BUFF_EMIFA08: length 46.2
  TOP w0.152: v1(33.48,104.49) 33.42,104.49 32.84,103.92 32.84,103.2 33.05,102.99 CN7.22 ; v1(57.99,119.18) U6.18
  L8_SIG3 w0.107: v1(57.99,119.18) 57.21,119.18 56.44,118.41 56.44,114.32 59.7,111.06 59.7,109.21 59.21,108.73 51.95,108.73 49.52,106.3 39.73,106.3 37.75,104.32 34.49,104.32 34.32,104.49 v1(33.48,104.49)
BUFF_EMIFA09: length 39.8
  TOP w0.152: U6.16 v1(57.99,118.18) ; CN7.24 36.42,103.49 v1(36.83,103.9)
  L8_SIG3 w0.107: v1(57.99,118.18) 57.99,117.88 57.33,117.22 57.2,117.22 56.67,116.69 56.67,114.43 59.9,111.19 59.9,109.09 59.31,108.5 52.04,108.5 49.61,106.07 39.83,106.07 37.66,103.9 v1(36.83,103.9)
BUFF_EMIFA10: length 42.4
  TOP w0.152: v1(33.45,103.49) 33.5,103.54 33.5,103.58 33.92,103.99 CN7.26 ; U6.14 v1(57.99,117.18)
  L8_SIG3 w0.107: v1(33.45,103.49) 37.58,103.49 39.93,105.84 49.71,105.84 52.13,108.27 59.4,108.27 60.1,108.97 60.1,111.32 56.9,114.53 56.9,115.94 57.21,116.26 57.36,116.26 57.99,116.88 v1(57.99,117.18)
BUFF_EMIFA11: length 40.5
  TOP w0.152: U6.12 v1(57.99,116.18) ; CN7.28 36.96,104.49 37.25,104.2 37.25,104.19 37.26,104.17 37.26,103.43 v1(36.83,102.99)
  L8_SIG3 w0.107: v1(57.99,116.18) 57.99,113.82 60.58,111.23 60.58,108.25 59.47,107.14 53.45,107.14 53.11,107.48 51.67,107.48 49.8,105.61 40.03,105.61 37.41,102.99 v1(36.83,102.99)
BUFF_EMIFA12: length 28
  TOP w0.152: U6.9 v1(51.38,116.18) ; v1(36.88,105.18) 36.83,105.18 36.64,104.99 CN7.30
  L8_SIG3 w0.107: v1(36.88,105.18) 36.88,105.23 37.24,105.59 37.24,106.16 36.25,107.15 36.25,112.1 36.81,112.65 48.15,112.65 51.38,115.89 v1(51.38,116.18)
BUFF_EMIFA13: length 28.7
  TOP w0.152: v1(36.83,105.99) 36.33,105.49 CN7.32 ; U6.7 v1(51.28,117.18)
  L8_SIG3 w0.107: v1(36.83,105.99) 36.02,106.8 36.02,112.19 37.67,113.84 44.51,113.84 45.15,113.2 48.38,113.2 51,115.83 51,116.5 51.28,116.78 v1(51.28,117.18)
BUFF_EMIFA14: length 31.4
  TOP w0.152: CN7.34 33.92,105.99 33.48,105.55 v1(33.48,105.51) ; U6.5 v1(51.38,118.18)
  L8_SIG3 w0.107: v1(51.38,118.18) 50.85,117.65 50.85,116.68 50.77,116.6 50.77,115.92 48.28,113.43 45.25,113.43 44.61,114.07 37.58,114.07 33.15,109.64 33.15,107.19 33.38,106.96 33.59,106.96 33.88,106.66 33.88,105.96 33.48,105.55 v1(33.48,105.51)
BUFF_EMIFA15: length 30
  TOP w0.152: U6.3 v1(51.38,119.18) ; CN7.36 v1(33.48,106.49)
  L8_SIG3 w0.107: v1(33.48,106.49) 32.92,107.05 32.92,109.74 37.48,114.3 43.9,114.3 45.01,115.42 49.09,115.42 50.14,116.47 50.32,116.47 50.55,116.69 50.55,118.34 v1(51.38,119.18)
BUFF_EMIFA16: length 31.1
  TOP w0.152: v1(37.07,107.04) 36.98,107.04 36.94,106.99 CN7.38 ; U10.18 v1(57.91,112.27)
  L3_SIG1 w0.102: v1(37.07,107.04) 43.69,107.04 45.07,108.42 59.23,108.42 59.8,108.99 59.8,110.39 v1(57.91,112.27)
BUFF_EMIFA17: length 31.9
  TOP w0.152: U10.16 v1(57.94,111.27) ; v1(33.53,107.49) CN7.40
  L8_SIG3 w0.107: v1(57.94,111.27) 57.15,111.27 56.62,110.74 56.62,110.03 55.54,108.96 51.85,108.96 49.42,106.53 39.64,106.53 37.66,104.55 36.48,104.55 v1(33.53,107.49)
BUFF_EMIFA18: length 25.2
  TOP w0.152: v1(36.99,108.08) 36.71,108.08 36.62,107.99 CN7.42 ; U10.14 v1(57.86,110.27)
  L3_SIG1 w0.102: v1(36.99,108.08) 44.11,108.08 44.68,108.65 55.08,108.65 56.7,110.27 v1(57.86,110.27)
BUFF_EMIFA19: length 36.4
  TOP w0.152: U10.12 v1(57.78,109.27) ; v1(33.53,108.46) 33.76,108.46 33.79,108.49 CN7.44
  L8_SIG3 w0.107: v1(33.53,108.46) 34.67,107.32 34.67,106.73 36.63,104.77 37.39,104.77 39.93,107.31 45.24,107.31 45.64,107.72 50.29,107.72 51.76,109.18 55.45,109.18 56.39,110.13 56.39,111.76 56.87,112.24 57.36,112.24 57.92,111.68 58.14,111.68 58.32,111.51 58.32,109.81 v1(57.78,109.27)
BUFF_EMIFA20: length 19
  TOP w0.152: U10.9 51.53,109.27 51.36,109.45 v1(51.38,109.45) ; v1(36.81,108.93) 36.78,108.97 36.71,108.97 36.68,108.99 CN7.46
  L8_SIG3 w0.107: v1(51.38,109.45) 50.02,108.09 37.66,108.09 v1(36.81,108.93)
BUFF_EMIFA21: length 19.3
  TOP w0.152: v1(37.16,109.49) CN7.48 ; U10.7 v1(51.38,110.27)
  L8_SIG3 w0.107: v1(51.38,110.27) 51,109.89 51,109.39 50.17,108.56 43.15,108.56 42.71,108.99 37.66,108.99 v1(37.16,109.49)
BUFF_EMIFA22: length 19.7
  TOP w0.152: U10.5 v1(51.38,111.27) ; CN7.50 36.74,109.99 v1(36.76,110.02)
  L8_SIG3 w0.107: v1(36.76,110.02) 37.48,110.02 37.91,109.59 39.03,109.59 39.34,109.9 42.88,109.9 43.69,109.09 49.42,109.09 50.07,109.74 50.32,109.74 50.9,110.32 50.9,110.79 51.38,111.27 v1(51.38,111.27)
BUFF_EMIFA23: length 21
  TOP w0.152: U10.3 51.67,112.27 51.45,112.49 v1(51.45,112.5) ; CN7.52 36.45,110.49 36.98,111.02 v1(36.98,111.1)
  L8_SIG3 w0.107: v1(51.45,112.5) 51.44,112.5 50.95,112.01 50.95,111.33 50.13,110.5 50.01,110.5 49.74,110.24 48.75,110.24 47.83,109.32 45.37,109.32 44.58,110.11 44.15,110.11 43.36,110.9 41.89,110.9 41.58,110.59 37.49,110.59 v1(36.98,111.1)
BUFF_EMIFBE0Z: length 9.1
  TOP w0.152: CN7.49 v1(38.86,109.99)
  L3_SIG1 w0.102: v1(38.86,109.99) 40.99,112.12 v1(43.56,112.12)
  BOTTOM w0.152: v1(43.56,112.12) U54.18
BUFF_EMIFBE1Z: length 4.6
  TOP w0.152: v1(42.55,110.49) 42.4,110.49 42.4,110.49 CN7.51
  BOTTOM w0.152: v1(42.55,110.49) 43.18,111.12 U54.16
BUFF_EMIFCE1Z: length 8.8
  TOP w0.152: CN7.43 v1(38.9,108.49)
  L3_SIG1 w0.102: v1(38.9,108.49) 40.52,110.11 43.55,110.11 v1(43.56,110.12)
  BOTTOM w0.152: v1(43.56,110.12) U54.14
BUFF_EMIFCE2Z: length 4.7
  TOP w0.152: v1(42.55,108.58) 42.14,108.99 CN7.45
  BOTTOM w0.152: v1(42.55,108.58) 43.08,109.12 U54.12
BUFF_EMIFCE3Z: length 11.1
  TOP w0.152: CN7.47 v1(42.55,109.49)
  L3_SIG1 w0.107: v1(42.55,109.49) 43.05,108.99 50.03,108.99 v1(50.09,109.05)
  BOTTOM w0.152: v1(50.09,109.05) 50.05,109.05 49.98,109.12 U54.9
BUFF_EMIFD0: length 7
  TOP w0.152: CN7.9 41.87,99.99 42.23,99.63 42.23,98.03 44.22,96.04 U16.9
BUFF_EMIFD1: length 7
  TOP w0.152: U16.8 44.25,96.54 42.57,98.22 42.57,99.91 41.99,100.49 CN7.11
BUFF_EMIFD2: length 7.1
  TOP w0.152: U16.7 44.29,97.04 42.88,98.45 42.88,100.25 42.13,100.99 CN7.13
BUFF_EMIFD3: length 7
  TOP w0.152: U16.6 44.4,97.54 43.18,98.76 43.18,100.44 42.13,101.49 CN7.15
BUFF_EMIFD4: length 7
  TOP w0.152: CN7.17 42.19,101.99 43.48,100.7 43.48,99.06 44.5,98.04 U16.5
BUFF_EMIFD5: length 7
  TOP w0.152: CN7.19 42.19,102.49 43.79,100.89 43.79,99.27 44.52,98.54 U16.4
BUFF_EMIFD6: length 6.9
  TOP w0.152: U16.3 44.55,99.04 44.09,99.49 44.09,101.03 42.13,102.99 CN7.21
BUFF_EMIFD7: length 6.9
  TOP w0.152: CN7.23 42.09,103.49 44.4,101.18 44.4,99.72 44.58,99.54 U16.2
BUFF_EMIFD8: length 5.1
  TOP w0.152: CN7.25 42.54,103.99 44.27,102.26 U14.9
BUFF_EMIFD9: length 5.1
  TOP w0.152: CN7.27 42.55,104.49 44.28,102.76 U14.8
BUFF_EMIFD10: length 5.1
  TOP w0.152: U14.7 44.22,103.26 42.49,104.99 CN7.29
BUFF_EMIFD11: length 5.1
  TOP w0.152: U14.6 44.17,103.76 42.44,105.49 CN7.31
BUFF_EMIFD12: length 5.1
  TOP w0.152: U14.5 44.1,104.26 42.37,105.99 CN7.33
BUFF_EMIFD13: length 5.1
  TOP w0.152: U14.4 44.03,104.76 42.3,106.49 CN7.35
BUFF_EMIFD14: length 5.1
  TOP w0.152: CN7.37 42.31,106.99 44.04,105.26 U14.3
BUFF_EMIFD15: length 5.1
  TOP w0.152: U14.2 44.22,105.76 42.49,107.49 CN7.39
BUFF_EMIFOEZ: length 17.6
  TOP w0.152: CN7.53 v1(38.86,110.99)
  L3_SIG1 w0.102: v1(38.86,110.99) 40.4,112.53 42.57,112.53 43.05,113 49.82,113 50.55,112.28 50.55,111.5 v1(50.16,111.12)
  BOTTOM w0.152: U54.5 v1(50.16,111.12)
BUFF_EMIFRNW: length 16.9
  TOP w0.152: v1(42.4,118.98) 42.38,118.99 CN7.65
  L3_SIG1 w0.107: v1(50.16,110.12) 50.8,110.76 50.8,112.5 48.11,115.19 46.18,115.19 v1(42.4,118.98)
  BOTTOM w0.152: U54.7 v1(50.16,110.12)
BUFF_EMIFWEZ: length 11.5
  TOP w0.152: CN7.55 v1(42.55,111.49)
  L3_SIG1 w0.107: v1(50.16,112.12) 48.22,112.12 47.92,112.42 44.44,112.42 43.51,111.49 v1(42.55,111.49)
  BOTTOM w0.152: U54.3 v1(50.16,112.12)
CLK1_ELF: length 7.9
  TOP w0.152: U18.41 67.17,100.16 66.05,101.28 R133.1 66.01,102.15 66.01,103.33 65.53,103.81 C33.1
CLK1_REF_SEL: length 41.1
  TOP w0.152: R157.1 59.24,96.94 58.4,97.78 58.4,99.26 59.08,99.93 59.08,103.12 59.72,103.76 59.72,104.82 60.78,105.89 60.78,107.57 61.29,108.08 62.92,108.08 63.31,107.68 v1(63.31,107.57) ; U8.27 77.88,117.24 v1(77.41,117.24)
  L8_SIG3 w0.107: v1(63.31,107.57) 63.31,106.42 62.99,106.1 62.99,105.41 63.2,105.21 64.09,105.21 71.09,112.21 71.09,116.03 72.69,117.62 73.5,117.62 73.88,117.24 v1(77.41,117.24)
CLK1_SYNC: length 5.4
  TOP w0.152: R136.1 64.15,101.15 64.67,100.63 66.24,100.63 66.67,100.21 U18.42
CLK2_ELF: length 4.5
  TOP w0.152: C44.1 R134.1 85.32,100.48 85.05,100.22 U17.41
CLK2_REF_SEL: length 30.4
  TOP w0.152: v1(76.6,116.59) U8.26 ; R154.1 76.71,98.2 76.71,98.22 76.09,98.84 76.09,99.28 76.71,99.9 v1(76.71,101.28)
  L8_SIG3 w0.107: v1(76.71,101.28) 77.99,101.28 78.26,101.02 80.47,101.02 80.84,100.64 81.24,100.64 81.59,100.99 81.59,102.21 81.15,102.64 80.58,102.64 77.9,105.32 77.9,108.35 78.21,108.65 78.21,110.66 76.21,112.65 76.21,116.21 v1(76.6,116.59)
CLK2_SYNC: length 6.2
  TOP w0.152: U17.42 84.55,99.05 82.8,100.8 82.8,102.72 82.34,103.18 R113.2
CLK_RSTZ: length 49.3
  TOP w0.152: U17.44 83.55,99.19 83.55,99.19 82.28,100.46 79.59,100.46 79.4,100.65 79.4,104.32 75.06,108.66 75.06,111.73 72.8,113.99 U8.7 68.52,113.99 68.07,113.54 68.07,113.54 67.77,113.23 67.77,108.76 66.25,107.25 64.43,107.25 62.79,105.61 62.79,104.26 61.14,102.61 61.14,100.84 61.95,100.03 65.01,100.03 v2(65.67,99.36) U18.44
CORECLKN: length 38.7
  TOP w0.102: v1(71.59,96.17) 71.41,96 70.7,96 70.58,96.12 U18.33 ; C95.1 54.91,79.75 55.12,79.96 55.12,82.91 53.9,84.13 53.9,84.55 v4(53.67,84.78)
  L8_SIG3 w0.102: v1(71.59,96.17) 71.43,96.01 70.68,96.01 70.42,96.28 70.42,97.4 67.67,100.15 61.88,100.15 56.92,95.19 56.92,93.08 53.8,89.96 53.8,84.91 v4(53.67,84.78)
CORECLKP: length 38.7
  TOP w0.102: U18.32 70.58,95.62 70.7,95.74 71.41,95.74 v1(71.59,95.56) ; v4(54.28,84.78) 54.15,84.65 54.15,84.23 55.37,83.01 55.37,81.99 55.47,81.89 55.47,81.66 55.37,81.56 55.37,81.33 55.47,81.23 55.47,81 55.37,80.9 55.37,80.67 55.47,80.57 55.47,80.34 55.37,80.24 55.37,79.83 55.45,79.75 C94.1
  L8_SIG3 w0.102: v1(71.59,95.56) 71.43,95.72 70.56,95.72 70.21,96.07 70.13,96.16 70.13,97.28 67.54,99.86 62,99.86 57.21,95.07 57.21,92.96 54.09,89.83 54.09,84.97 v4(54.28,84.78)
CP2105_MCU_U0RX: length 35.5
  TOP w0.152: v1(162.69,132.92) U2.21
  L5_SIG2 w0.107: v1(134.24,136.02) 137.09,138.86 144.93,138.86 146.63,137.16 148.72,137.16 149.06,137.49 150.32,137.49 150.39,137.41 160.66,137.41 161.14,136.93 161.14,134.47 v1(162.69,132.92)
  BOTTOM w0.152: U42.2 v1(134.24,136.02)
CP2105_SOC_U0RX: length 25.4
  TOP w0.127: U2.13 160.3,137.01
  TOP w0.152: 160.3,137.01 v1(159.97,137.01)
  L5_SIG2 w0.107: v1(169.17,120.14) 168.79,120.52 164.34,120.52 160.85,124.02 160.85,132.42 159.97,133.29 v1(159.97,137.01)
  BOTTOM w0.152: U52.2 v1(169.17,120.14)
CPLD_A0: length 68.2
  TOP w0.152: U9.2 118.52,119.02 118.62,119.13 118.62,119.26 v1(118.59,119.29)
  L8_SIG3 w0.102: v1(146.15,115.67) 146.15,114.31 145.69,113.84 142.88,113.84 141.65,112.62 141.65,112.58 141.35,112.28 140.19,112.28 136.62,108.7 136.62,108.41 136.63,108.39 136.63,107.83 136.62,107.81 136.62,106.82 135.41,105.62 134.68,105.62 134.13,105.08 134.13,104.31 131.22,101.39 129.96,101.39 129.78,101.22 129.78,100.99 129.6,100.81 129.35,100.81 129.17,100.99 129.17,101.22 128.99,101.39 128.74,101.39 128.56,101.22 128.56,100.99 128.38,100.81 128.13,100.81 127.95,100.99 127.95,101.22 127.77,101.39 127.52,101.39 127.34,101.22 127.34,100.99 127.16,100.81 126.91,100.81 126.73,100.99 126.73,101.22 126.55,101.39 126.3,101.39 126.12,101.22 126.12,100.99 125.94,100.81 125.69,100.81 125.51,100.99 125.51,101.22 125.33,101.39 125.05,101.39 v4(124.77,101.67)
  L10_SIG4 w0.102: v1(146.15,115.67) 146.15,117.25 142.36,121.04 124.33,121.04 122.82,119.53 118.84,119.53 v1(118.59,119.29)
  BOTTOM w0.152: RN1.6 146.18,115.13 146.15,115.16 v1(146.15,115.67)
  BOTTOM w0.254: U78.H7 v4(124.77,101.67)
CPLD_A1: length 70.3
  TOP w0.152: U9.3 v1(117.73,119.13)
  L8_SIG3 w0.102: v4(123.97,101.67) 123.97,101.68 124.69,102.4 130.42,102.4 130.79,102.76 130.81,102.76 130.82,102.77 131.27,102.77 131.88,103.38 131.88,103.71 134.98,106.81 134.98,106.81 135.5,107.33 135.5,108.14 135.56,108.2 135.56,108.27 135.73,108.43 135.73,110.23 137.55,112.05 137.55,112.06 137.78,112.28 137.78,112.28 138.42,112.92 139.91,112.92 141.46,114.47 144.32,114.47 144.73,114.88 144.73,115.45 145.33,116.05 146.96,116.05 v1(147.4,115.62)
  L10_SIG4 w0.102: v1(147.4,115.62) 147.4,116.44 142.36,121.48 127.82,121.48 126.14,123.16 125.32,123.16 122.73,120.57 119.18,120.57 v1(117.73,119.13)
  BOTTOM w0.152: v1(147.4,115.62) 147.4,115.06 147.24,114.9 RN1.8
  BOTTOM w0.254: U78.H8 v4(123.97,101.67)
CPLD_A2: length 70.7
  TOP w0.152: U9.5 116.13,118.97 v1(116.08,119.02)
  L8_SIG3 w0.102: v4(123.97,100.87) 123.97,100.48 124.08,100.37 124.26,100.37 124.4,100.52 124.4,101.82 124.62,102.04 125.28,102.04 125.46,101.86 125.46,101.78 125.64,101.6 125.89,101.6 126.07,101.78 126.07,101.86 126.25,102.04 126.5,102.04 126.68,101.86 126.68,101.78 126.86,101.6 127.11,101.6 127.29,101.78 127.29,101.86 127.47,102.04 127.72,102.04 127.9,101.86 127.9,101.78 128.07,101.6 128.33,101.6 128.51,101.78 128.51,101.86 128.68,102.04 128.94,102.04 129.12,101.86 129.12,101.78 129.29,101.6 129.55,101.6 129.73,101.78 129.73,101.86 129.9,102.04 130.5,102.04 130.92,102.46 131.4,102.46 133.83,104.89 133.83,105.2 134.55,105.93 135.02,105.93 135.29,105.93 136.31,106.95 136.31,107.94 136.32,107.95 136.32,108.27 136.31,108.28 136.31,109.66 139.23,112.58 140.06,112.58 141.63,114.14 142.8,114.14 142.8,114.15 145.48,114.15 145.8,114.47 145.8,115.24 145.68,115.37 v1(145.19,115.37)
  L10_SIG4 w0.102: v1(116.08,119.02) 116.36,118.75 118.98,118.75 119.17,118.94 122.65,118.94 124.34,120.62 127.43,120.62 128.94,119.11 132.73,119.11 133.97,117.87 140.41,117.87 140.44,117.83 140.84,117.83 140.87,117.87 141.63,117.87 142.35,118.59 142.82,118.59 145.11,116.3 145.11,115.44 v1(145.19,115.37)
  BOTTOM w0.152: v1(145.19,115.37) 145.62,114.93 RN1.5
  BOTTOM w0.254: U78.J8 v4(123.97,100.87)
CPLD_A3: length 67.9
  TOP w0.152: U9.6 v1(115.34,118.57)
  L8_SIG3 w0.102: v1(146.68,115.06) 147.48,115.06 147.62,114.92 147.62,114.12 147,113.49 143.42,113.49 142.53,112.61 142.53,112.4 142.01,111.89 140.27,111.89 137.05,108.67 137.05,106.83 135.54,105.32 134.66,105.32 134.44,105.09 134.44,104.44 134.44,104.43 134.44,104.18 130.94,100.69 130.92,100.69 130.74,100.5 125.14,100.5 v4(124.77,100.87)
  L10_SIG4 w0.107: v1(146.68,115.06) 146.6,114.99 144.99,114.99 142.41,117.57 141,117.57 140.96,117.53 140.32,117.53 140.28,117.57 133.84,117.57 132.6,118.81 129.55,118.81 129.37,118.63 119.45,118.63 119.26,118.44 115.47,118.44 v1(115.34,118.57)
  BOTTOM w0.152: v1(146.68,115.06) RN1.7
  BOTTOM w0.254: U78.J7 v4(124.77,100.87)
CPLD_BIO_0: length 31.5
  TOP w0.152: R83.1 v1(150.37,114.99) ; U9.42 v1(123.32,114.05)
  L10_SIG4 w0.107: v1(150.37,114.99) 150.06,114.68 142.43,114.68 141.61,113.86 138.87,113.86 138.48,114.25 133.96,114.25 133.15,113.44 129.49,113.44 129.38,113.55 126.77,113.55 126.33,113.11 125.13,113.11 124.9,113.34 124.03,113.34 v1(123.32,114.05)
CPLD_BIO_1: length 25.3
  TOP w0.152: U9.43 v1(122.68,114.83)
  L10_SIG4 w0.107: v1(122.68,114.83) 124.05,114.83 125.32,113.57 126.14,113.57 126.73,114.16 130.42,114.16 132.03,115.77 135.73,115.77 136.44,115.06 142.17,115.06 142.55,115.44 v1(143.37,115.44)
  BOTTOM w0.152: RN2.7 143.38,115.43 v1(143.37,115.44)
CPLD_BIO_2: length 24.1
  TOP w0.152: U9.44 v1(122.3,115.65)
  L10_SIG4 w0.107: v1(122.3,115.65) 128.98,115.65 129.33,116 137.14,116 137.85,115.29 142.07,115.29 v1(142.73,115.95)
  BOTTOM w0.152: v1(142.73,115.95) 142.73,115.49 142.88,115.34 RN2.6
CPLD_BIO_3: length 28
  TOP w0.152: v1(120.52,118.21) 119.74,118.21 119.33,117.81 U9.1
  L10_SIG4 w0.107: v1(141.91,116.28) 141.91,116.76 141.41,117.26 141.13,117.26 141.09,117.23 140.19,117.23 140.15,117.26 133.72,117.26 132.47,118.5 129.67,118.5 129.5,118.33 120.63,118.33 v1(120.52,118.21)
  BOTTOM w0.152: R349.2 120.23,117.93 v1(120.52,118.21) ; v1(141.91,116.28) 141.99,116.28 141.99,115.6 142.33,115.25 142.33,114.92 142.32,114.9 RN2.5
CPLD_BIO_4: length 27.5
  TOP w0.152: v1(122.54,113.57) 122.22,113.26 121.05,113.26 U9.41
  L10_SIG4 w0.107: v1(144.04,115.16) 143.94,115.06 142.49,115.06 142.26,114.83 136.34,114.83 135.63,115.54 133.33,115.54 131.72,113.93 126.83,113.93 126.23,113.34 125.23,113.34 124.14,114.43 123.16,114.43 122.57,113.83 122.57,113.6 v1(122.54,113.57)
  BOTTOM w0.152: R364.2 122.25,113.28 v1(122.54,113.57) ; v1(144.04,115.16) 143.94,115.06 RN2.8
CPLD_CSN: length 48.6
  TOP w0.152: v1(113.69,119.13) 113.67,119.13 113.67,119.18 113.74,119.1 U9.8 ; R81.1 v1(153.54,115.04)
  L10_SIG4 w0.107: v1(113.69,119.13) 115.47,120.9 117.69,120.9 117.96,121.18 119.47,121.18 119.63,121.03 122.76,121.03 125.19,123.47 129.56,123.47 129.67,123.58 130.42,123.58 132.12,121.89 146.69,121.89 v1(153.54,115.04)
  BOTTOM w0.152: v1(153.54,115.04) R81.1
CPLD_D0: length 11.1
  TOP w0.152: U9.39 v1(122.91,111.66)
  L3_SIG1 w0.107: v1(124.35,108.24) 124.35,110.22 v1(122.91,111.66)
  BOTTOM w0.127: v1(124.35,108.24) 124.37,108.22 U78.A8
  BOTTOM w0.152: U78.A8 124.58,107.67 125.18,108.27 125.4,108.27 127.34,110.21 RN5.4
CPLD_D1: length 16.2
  TOP w0.152: v1(122.87,112.96) 122.36,112.45 U9.40
  L3_SIG1 w0.107: v1(122.87,112.96) 121.92,112.01 121.92,108.49 v1(123.16,107.26)
  BOTTOM w0.127: v1(123.16,107.26) 123.54,106.87 U78.B9
  BOTTOM w0.152: U78.B9 123.98,107.28 126.13,107.28 127.36,108.51 127.36,109.8 127.89,110.33 RN5.3
CPLD_RDN: length 47.1
  TOP w0.152: v1(151.89,114.96) R82.1 ; U9.12 110.68,115.65 v1(111.43,114.89)
  L10_SIG4 w0.107: v1(151.89,114.96) 151.36,114.43 142.5,114.43 141.71,113.63 136.07,113.63 135.68,114.02 134.38,114.02 133.24,112.88 132.1,112.88 131.45,112.24 126.8,112.24 126.7,112.34 122.95,112.34 119.49,115.79 118.04,115.79 117.14,114.89 v1(111.43,114.89)
  BOTTOM w0.152: R82.1 v1(151.89,114.96)
CPLD_RESETN: length 46.3
  TOP w0.127: U15.B10 v1(145.82,109.68)
  TOP w0.152: U9.13 v1(108.2,114.83)
  L10_SIG4 w0.107: v1(108.2,114.83) 109.25,113.79 112.33,113.79 113.47,112.65 118.72,112.65 121.54,109.83 126.38,109.83 127.38,108.83 135.15,108.83 136.38,110.07 141.95,110.07 141.97,110.04 145.46,110.04 v1(145.82,109.68)
  BOTTOM w0.152: R347.2 108.46,117.65 108.2,117.4 v1(108.2,114.83)
CPLD_RXD1: length 37.9
  TOP w0.127: U15.E18 v1(152.22,107.28)
  L10_SIG4 w0.107: v1(119.38,113.28) 121.41,111.25 125.91,111.25 126.05,111.11 140.51,111.11 141.36,110.27 142.03,110.27 142.06,110.24 145.84,110.24 146.46,110.87 147.35,110.87 147.75,110.47 149.57,110.47 152.22,107.82 v1(152.22,107.28)
  BOTTOM w0.152: R364.1 v1(119.38,113.28)
CPLD_TCK: length 47.9
  TOP w0.152: v1(111.37,116.13) 111.33,116.17 U9.11 111.33,117.86 111,118.19 TP13.1 ; R170.1 v1(135.38,90.09)
  L3_SIG1 w0.102: v1(111.37,116.13) 111.37,115.76 112.12,115.01 114.25,115.01 117.93,111.32 117.93,104.36 118.91,103.39 118.91,98.38 119.86,97.42 127.19,90.09 v1(135.38,90.09)
  BOTTOM w0.152: R351.1 111.58,116.34 v1(111.37,116.13)
CPLD_TDI: length 49.1
  TOP w0.127: v1(137.82,96.88) U15.U1
  TOP w0.152: U9.9 112.93,117.83 112.6,118.16 112.6,119.2 TP11.1 113.28,120.6 113.39,120.7 114.99,120.7 115.8,119.89 119.61,119.89 123.5,116 123.5,114.53 124.6,113.43 126.11,113.43 129.98,109.56 129.98,96.38 129.95,96.35 129.95,95.93 130.88,95 135.93,95 v1(137.82,96.88)
CPLD_TDO: length 38.2
  TOP w0.127: v1(138.62,96.88) U15.U2
  TOP w0.152: U9.24 112.12,104.88 111.79,104.55 111.24,104.55 110.41,103.72 110.41,101.6 TP30.1 111.99,100.02 118.99,100.02 124.32,94.69 136.35,94.69 137.76,96.1 138.39,96.1 138.62,96.33 v1(138.62,96.88)
CPLD_TMS: length 51.6
  TOP w0.127: v1(140.22,96.08) U15.V3
  TOP w0.152: v1(112.12,115.74) U9.10 112.12,119.86 TP12.1
  L3_SIG1 w0.102: v1(140.22,96.08) 138.34,94.2 123.4,94.2 120.09,97.51 119.13,98.47 119.13,103.48 118.16,104.46 118.16,111.42 118.03,111.55 118.03,111.55 113.84,115.74 v1(112.12,115.74)
  BOTTOM w0.152: R350.1 112.5,117.02 112.12,116.64 v1(112.12,115.74)
CPLD_TXD1: length 42.6
  TOP w0.127: U15.F19 v1(153.02,106.48)
  L10_SIG4 w0.107: v1(153.02,106.48) 152.6,106.9 152.6,109.9 149.1,113.4 141.8,113.4 141.8,113.4 140.67,113.4 140.32,113.06 134.68,113.06 133.54,111.91 126.8,111.91 126.6,112.11 122.63,112.11 v1(119.33,115.41)
  BOTTOM w0.152: R349.1 v1(119.33,115.41)
CPLD_WEN: length 71.2
  TOP w0.152: v1(141.25,116.88) 141.45,116.69 142.15,116.69 142.32,116.52 R72.2 143.28,116.52 145.43,114.37 R79.1 ; U9.14 110.49,114.05 110.64,114.2 v1(111.18,114.2)
  L8_SIG3 w0.107: v1(141.25,116.88) 140.33,117.81 139.07,117.81 129.79,108.52 127.2,108.52 127.02,108.35 127.02,108.02 126.84,107.84 126.59,107.84 126.41,108.02 126.41,108.35 126.23,108.52 125.61,108.52 125.61,108.52 125.2,108.52 123.17,106.49 123.17,106.26 123.35,106.08 124.1,106.08 124.28,105.9 124.28,105.65 124.1,105.47 123.35,105.47 123.17,105.29 123.17,105.04 123.35,104.86 124.1,104.86 124.28,104.68 124.28,104.43 124.1,104.25 123.35,104.25 123.17,104.07 v4(123.17,103.27)
  L10_SIG4 w0.107: v1(141.25,116.88) 140.77,116.4 126.43,116.4 126.14,116.11 118.35,116.11 117.74,116.71 112.55,116.71 111.05,115.21 111.05,114.32 v1(111.18,114.2)
  BOTTOM w0.254: U78.F9 v4(123.17,103.27)
CVDD: length 394.5
  TOP w0.254: C89.1 v2(68.38,78.85) ; C169.1 v2(66.14,42.3) ; C171.2 v2(55.09,41.79) ; C180.2 v2(68.17,40.58) ; C181.2 v2(66.14,39.68) ; C76.2 v2(68.4,81.77) ; C74.2 v2(71.15,81.77) ; C81.2 v2(57.45,82.67) ; R544.2 70.97,86.16 69.39,86.16 68.4,87.15 v2(68.15,87.15) ; C178.2 v2(72.24,40.58) ; C78.1 v2(65.63,81.77) ; C184.2 v2(53.7,40.58) ; C88.2 v2(69.95,79.75) ; C93.2 v2(58.14,78.85) ; v2(69.77,82.57) 69.67,82.67 C75.2 ; v2(67.01,82.57) 66.9,82.67 C77.1 ; C79.1 v2(60.17,82.67) ; C92.2 v2(60.17,79.75) ; C185.2 v2(52.27,39.68) ; C90.2 v2(67.01,79.75) ; C96.2 v2(51.61,78.85) ; C179.2 v2(70.21,39.68) ; C170.2 v2(64.11,43.2) ; C166.2 v2(72.11,43.2) ; C183.2 v2(55.09,39.68) ; C167.2 v2(70.21,42.3) ; C80.1 v2(58.83,81.77) ; C173.2 v2(52.35,41.79) ; R63.2 v2(109.91,121.41) ; C172.2 v2(53.72,42.69) ; C168.1 v2(68.17,43.2) ; C91.2 v2(65.63,78.85) ; C182.2 v2(64.11,40.58)
  TOP w0.381: v4(55.98,57.36) U23.AD21 v4(56.78,58.16) U23.AC20 v4(57.58,58.96) U23.AB19 v4(58.38,59.76) U23.AA18 U23.AB17 v4(57.58,61.36) U23.AC16 v4(56.78,62.16) U23.AD15 v4(55.98,62.96) ; v4(68.78,59.76) U23.J18 U23.K17 v4(67.98,61.36) U23.J16 v4(68.78,62.16) ; U23.AA10 v4(58.38,66.96) U23.AB9 v4(57.58,67.76) ; U23.U12 v4(62.38,65.36) ; v4(59.98,56.56) U23.W22 v4(60.78,57.36) U23.V21 U23.U20 v4(62.38,58.16) U23.T21 v4(63.18,57.36) U23.R22 v4(63.98,56.56) U23.P23 v4(64.78,55.76) ; v4(67.98,55.76) U23.K23 v4(67.18,56.56) U23.L22 v4(66.38,57.36) U23.M21 v4(65.58,58.16) U23.N20 v4(64.78,58.96) U23.P19 v4(63.98,59.76) U23.R18 U23.P17 v4(64.78,61.36) U23.N16 v4(65.58,62.16) U23.M15 v4(66.38,62.96) U23.L14 v4(67.18,63.76) U23.K13 v4(67.98,64.56) U23.J12 v4(68.78,65.36) ; TP51.1 v6(72.59,35.79) ; v4(63.98,53.36) U23.R26 v4(63.18,54.16) U23.T25 v4(62.38,54.96) U23.U24 U23.V25 ; U23.M25 v4(66.38,54.16) ; v4(68.78,58.16) U23.J20 v4(67.98,58.96) U23.K19 v4(67.18,59.76) U23.L18 ; v4(55.98,64.56) U23.AD13 v4(56.78,63.76) U23.AC14 v4(57.58,62.96) U23.AB15 v4(58.38,62.16) U23.AA16 v4(59.18,61.36) U23.Y17 U23.W18 v4(59.98,59.76) U23.Y19 v4(59.18,58.96) U23.AA20 v4(58.38,58.16) U23.AB21 v4(57.58,57.36) U23.AC22 v4(56.78,56.56) ; v4(58.38,56.56) U23.AA22 v4(59.18,57.36) U23.Y21 v4(59.98,58.16) U23.W20 v4(60.78,58.96) U23.V19 U23.U18 ; U23.U18 v4(62.38,59.76) U23.T19 v4(63.18,58.96) U23.R20 v4(63.98,58.16) U23.P21 v4(64.78,57.36) U23.N22 v4(65.58,56.56) ; U23.U18 U23.V17 v4(60.78,61.36) U23.W16 v4(59.98,62.16) U23.Y15 v4(59.18,62.96) ; U23.U18 U23.T17 v4(63.18,61.36) U23.R16 v4(63.98,62.16) U23.P15 v4(64.78,62.96) U23.N14 v4(65.58,63.76) ; v4(55.98,66.16) U23.AD11 v4(56.78,65.36) U23.AC12 v4(57.58,64.56) U23.AB13 ; v4(56.78,53.36) U23.AC26 v4(57.58,54.16) U23.AB25 ; v4(55.98,61.36) U23.AD17 U23.AC18 v4(56.78,59.76) U23.AD19 v4(55.98,58.96) ; U23.N10 v4(65.58,66.96) ; v4(59.98,63.76) U23.W14 v4(60.78,62.96) U23.V15 U23.U16 v4(62.38,62.16) U23.T15 v4(63.18,62.96) U23.R14 v4(63.98,63.76) U23.P13 v4(64.78,64.56) ; U23.K25 v4(67.98,54.16) U23.J26 v4(68.78,53.36) ; v4(55.98,54.16) U23.AD25 v4(56.78,54.96) U23.AC24 ; U23.V25 v4(60.78,54.16) U23.W26 v4(59.98,53.36) ; U23.V25 U23.U26 v4(62.38,53.36) ; v4(63.18,64.56) U23.T13 v4(62.38,63.76) U23.U14 U23.V13 v4(60.78,64.56) U23.W12 v4(59.98,65.36) ; v4(58.38,53.36) U23.AA26 v4(59.18,54.16) U23.Y25 v4(59.98,54.96) U23.W24 v4(60.78,55.76) U23.V23 U23.U22 v4(62.38,56.56) U23.T23 v4(63.18,55.76) U23.R24 v4(63.98,54.96) U23.P25 v4(64.78,54.16) U23.N26 v4(65.58,53.36) ; v4(68.78,63.76) U23.J14 v4(67.98,62.96) U23.K15 v4(67.18,62.16) U23.L16 v4(66.38,61.36) U23.M17 U23.N18 v4(65.58,59.76) U23.M19 v4(66.38,58.96) U23.L20 v4(67.18,58.16) U23.K21 v4(67.98,57.36) U23.J22 v4(68.78,56.56) ; U23.Y9 v4(59.18,67.76) ; U23.AB11 v4(57.58,66.16) U23.AC10 v4(56.78,66.96) ; U23.L12 v4(67.18,65.36) U23.K11 v4(67.98,66.16) ; U23.L10 v4(67.18,66.96)
  TOP w0.508: v2(68.15,87.15) 67.43,86.43 C66.1 65.81,86.43 v2(65.1,87.13) 64.45,86.48 C64.1 62.63,86.48 v2(62,87.11) 61.5,86.61 C65.1 59.74,86.61 v2(59.23,87.12) 58.94,86.83 C62.1 57.98,86.83 v2(57.73,87.07) 57.49,86.83 C63.1
  L5_SIG2 w0.254: v6(72.59,31.72) 74.84,31.72 77.76,28.8 78.01,28.8 79.1,27.71 94.38,27.71 95.02,28.35 100.85,28.35 106.11,33.61 106.11,59.18 107.45,60.52 107.45,60.52 107.86,60.93 111.65,60.93 113.92,63.21 113.92,85.19 117.55,88.82 117.55,96.71 116.47,97.79 116.47,114.85 117.55,115.93 117.55,117.6 116.71,118.44 116.71,121.51 116.26,121.97 115.69,121.97 114.55,120.83 110.49,120.83 v2(109.91,121.41)
  BOTTOM w0.254: C581.1 v4(57.58,62.96) ; v4(60.78,57.36) 61.5,56.63 C660.2 62.3,56.63 v4(62.38,56.56) ; C658.1 v4(56.78,56.56) ; C597.1 v4(66.38,61.36) ; C693.1 v4(59.18,54.16) ; C643.1 v4(59.18,57.36) ; v4(62.38,54.96) 62.09,54.68 C683.2 61.3,54.68 v4(60.78,54.16) ; v4(60.78,62.96) 61.15,63.33 C563.2 61.95,63.33 v4(62.38,63.76) ; C687.1 v4(66.38,54.16) C692.1 ; C640.1 v4(66.38,57.36) ; C596.1 v4(67.98,61.36) ; C700.1 v4(63.98,53.36) ; C172.2 v2(53.72,42.69) ; C694.1 v4(57.58,54.16) ; C698.1 v4(68.78,53.36) ; C556.1 v4(64.78,64.56) ; v4(63.98,59.76) 64.29,60.08 C603.2 64.29,60.88 v4(64.78,61.36) ; C575.1 v4(66.38,62.96) ; C525.1 v4(58.38,66.96) ; C535.1 v4(55.98,66.16) ; C509.1 v4(57.58,67.76) ; R477.2 v4(65.58,53.36) C699.1 ; C686.1 v4(67.98,54.16) ; C644.1 v4(57.58,57.36) ; C568.1 v4(65.58,63.76) ; C543.1 v4(68.78,65.36) ; C452.2 v2(57.45,82.67) ; C168.1 v2(68.17,43.2) ; C701.1 v4(58.38,53.36) ; v4(62.38,58.16) 61.95,58.59 C632.2 61.15,58.59 v4(60.78,58.96) ; C544.1 v4(67.18,65.36) ; C169.1 v2(66.14,42.3) ; C608.1 v4(67.18,59.76) ; v2(67.01,82.57) 66.9,82.67 C77.1 ; C628.1 v4(58.38,58.16) ; C166.2 v2(72.11,43.2) ; C547.1 v4(59.98,65.36) ; C657.1 v4(58.38,56.56) ; C579.1 v4(64.78,62.96) ; C167.2 v2(70.21,42.3) ; C615.1 v4(66.38,58.96) ; C580.1 v4(59.18,62.96) ; C526.1 v4(56.78,66.96) ; C74.2 v2(71.15,81.77) ; C653.1 v4(67.18,56.56) ; C676.1 v4(63.98,54.96) ; C652.1 v4(68.78,56.56) ; C625.1 v4(65.58,58.16) ; C589.1 v4(65.58,62.16) ; C702.1 v4(56.78,53.36) ; C178.2 v2(72.24,40.58) ; C173.2 v2(52.35,41.79) ; C656.1 v4(59.98,56.56) ; C92.2 v2(60.17,79.75) ; C618.1 v4(57.58,58.96) ; C655.1 v4(63.98,56.56) ; C587.1 v4(68.78,62.16) ; C554.1 v4(67.98,64.56) ; C624.1 v4(67.18,58.16) ; C183.2 v2(55.09,39.68) ; C521.1 v4(67.18,66.96) ; C677.1 v4(59.98,54.96) ; C617.1 v4(59.18,58.96) ; C567.1 v4(67.18,63.76) ; C179.2 v2(70.21,39.68) ; C582.1 v4(55.98,62.96) ; C458.2 v2(69.95,79.75) ; C679.1 v4(56.78,54.96) ; C641.1 v4(64.78,57.36) ; C654.1 v4(65.58,56.56) ; C614.1 v4(67.98,58.96) ; v4(59.18,61.36) 59.66,60.88 C604.2 59.66,60.08 v4(59.98,59.76) ; C578.1 v4(67.98,62.96) ; C665.1 v4(67.98,55.76) ; C185.2 v2(52.27,39.68) ; C667.1 v4(63.18,55.76) ; C181.2 v2(66.14,39.68) ; C590.1 v4(58.38,62.16) ; C689.1 v4(63.18,54.16) ; C569.1 v4(59.98,63.76) ; C171.2 v2(55.09,41.79) ; C571.1 v4(56.78,63.76) ; C645.1 v4(55.98,57.36) ; C184.2 v2(53.7,40.58) ; C626.1 v4(63.98,58.16) ; C90.2 v2(67.01,79.75) ; v4(56.78,59.76) 56.78,59.83 56.04,60.56 C606.2 55.75,61.13 v4(55.98,61.36) ; C623.1 v4(68.78,58.16) ; C627.1 v4(59.98,58.16) ; C642.1 v4(63.18,57.36) ; C666.1 v4(64.78,55.76) ; C75.2 69.67,82.67 v2(69.77,82.57) ; C180.2 v2(68.17,40.58) ; C182.2 v2(64.11,40.58) ; C78.1 v2(65.63,81.77) ; C690.1 v4(55.98,54.16) ; C522.1 v4(65.58,66.96) ; C76.2 v2(68.4,81.77) ; C558.1 v4(57.58,64.56) ; C559.1 v4(55.98,64.56) ; C450.2 v2(60.17,82.67) ; C688.1 v4(64.78,54.16) ; C91.2 v2(65.63,78.85) ; C451.2 v2(58.83,81.77) ; v4(58.38,59.76) 57.7,60.43 C605.2 57.7,61.23 v4(57.58,61.36) ; C89.1 v2(68.38,78.85) ; C616.1 v4(64.78,58.96) ; C588.1 v4(67.18,62.16) ; C566.1 v4(68.78,63.76) ; C93.2 v2(58.14,78.85) ; C549.1 v4(56.78,65.36) ; C170.2 v2(64.11,43.2) ; C508.1 v4(59.18,67.76) ; C591.1 v4(56.78,62.16) ; C629.1 v4(56.78,58.16) ; C96.2 v2(51.61,78.85) ; C619.1 v4(55.98,58.96) ; C639.1 v4(67.98,57.36)
  BOTTOM w0.508: v2(57.73,87.07) 57.98,86.83 C62.1 58.94,86.83 v2(59.23,87.12) 59.74,86.61 C65.1 61.5,86.61 v2(62,87.11) 62.5,86.61 C437.1 64.58,86.61 v2(65.1,87.13) 65.81,86.43 C66.1 67.42,86.43 68.14,87.15 v2(68.15,87.15)
  vias: v6(64.97,35.79) v6(64.97,33.93) v6(64.97,31.47) v6(64.97,29.69) v6(67.51,35.79) v6(67.51,33.76) v6(67.51,31.72) v6(67.51,29.69) v6(70.05,35.79) v6(70.05,33.76) v6(70.05,31.72) v6(70.05,29.69) v6(72.59,33.76) v6(72.59,29.69)
CVDD1: length 182.5
  TOP w0.254: R257.1 97.63,21.06 97.73,21.16 C246.2 v2(97.73,22.35) ; v2(108.05,130.68) R25.2
  TOP w0.381: U23.N12 v4(65.58,65.36) U23.M11 v4(66.38,66.16) ; U23.P9 v4(64.78,67.76) ; U23.Y13 v4(59.18,64.56) U23.AA12 v4(58.38,65.36) ; U23.AB23 v4(57.58,55.76) ; U23.AD23 v4(55.98,55.76) ; v4(58.38,54.96) U23.AA24 v4(59.18,55.76) U23.Y23 ; U23.AD9 v4(55.98,67.76) ; v4(67.18,54.96) U23.L24 v4(66.38,55.76) U23.M23 ; U23.AA14 v4(58.38,63.76) ; U23.N24 v4(65.58,54.96) ; U23.J24 v4(68.78,54.96) ; U23.M13 v4(66.38,64.56)
  L5_SIG2 w0.254: v2(108.05,130.68) 108.05,129.76 110.36,127.46 110.36,126.5 113.99,122.86 118.42,122.86 119.18,122.11 119.18,116.42 117.81,115.04 117.81,98.18 118.52,97.47 118.52,89.07 114.43,84.98 114.43,61.18 113.47,60.22 109.62,60.22 106.62,57.22 106.62,30.67 102.23,26.29 97.59,26.29 96.44,25.15 79.81,25.15 v3(77.75,27.2)
  L8_SIG3 w0.381: 65.13,67.34 64.78,67.69 v4(64.78,67.76)
  BOTTOM w0.254: C534.1 v4(66.38,66.16) ; C678.1 v4(58.38,54.96) ; C555.1 v4(66.38,64.56) ; v4(59.18,64.56) C570.1 v4(58.38,63.76) ; C548.1 v4(58.38,65.36) ; C668.1 v4(55.98,55.76) ; C675.1 v4(68.78,54.96) ; C672.1 v4(66.38,55.76)
  BOTTOM w0.381: v2(97.73,22.35) 83.08,22.35 v2(82.35,23.09)
  vias: v2(80.82,23.09) v2(80.82,21.95) v2(82.35,21.95) v3(76.78,28.17) v3(76.78,27.2) v3(77.75,28.17)
CVDD1_EN: length 150.3
  TOP w0.152: R43.2 v1(122.68,125.73)
  TOP w0.254: U33.48 98.04,16.62 97.89,16.76 v2(97.54,16.76)
  L8_SIG3 w0.107: v1(122.68,125.73) 120.13,123.18 118.09,123.18 116.97,122.06 116.97,117.96 117.7,117.22 117.7,113.59 115.11,111 115.11,60.14 119.08,56.18 119.08,38.02 119.15,37.95 119.15,36.6 118.85,36.3 118.85,31.4 119.18,31.08 119.18,16.95 112.6,10.37 107.41,10.37 107.4,10.37 103.94,10.37 103.02,9.45 98.68,9.45 97.54,10.59 v2(97.54,16.76)
  BOTTOM w0.381: R604.2 97.8,16.5 v2(97.54,16.76)
CVDD1_MON: length 2.2
  TOP w0.152: R25.1 110.74,130.68 110.89,130.54 U4.40
CVDD_EN: length 211.2
  TOP w0.152: R61.2 v1(112.9,121.41)
  TOP w0.254: R277.2 v2(69.09,2.47)
  L3_SIG1 w0.254: v1(112.9,121.41) 112.9,120.89 110.72,118.71 110.72,114.01 110.99,113.74 111.61,113.74 111.73,113.87 114.41,113.87 117.63,110.65 117.63,104.24 118.6,103.26 118.6,97.86 130.32,86.14 130.32,77.83 133.96,74.19 137.34,74.19 149.35,62.18 149.35,43.21 147.01,40.86 147.01,34.76 147.02,34.75 147.02,31.7 142.8,27.48 127.14,27.48 122.99,23.32 91.29,23.32 85.78,17.8 85.78,13.61 83.97,11.81 74.43,11.81 70.1,7.49 70.1,3.49 v2(69.09,2.47)
  BOTTOM w0.254: R589.1 70.43,2.74 70.16,2.47 v2(69.09,2.47) R277.2
CVDD_MON: length 4.4
  TOP w0.152: R63.1 109.91,123.57 110.41,124.08 111.51,124.08 112.57,125.14 U4.1
DBG_RTCK: length 24
  TOP w0.152: J5.9 161.01,85.22 v2(161.44,85.64) ; R140.2 v2(162.88,102.08)
  L5_SIG2 w0.107: v2(162.88,102.08) 164.49,102.08 166.47,100.1 166.47,95.85 165.94,95.32 165.94,90.14 v2(161.44,85.64)
DBG_SRST: length 15.4
  TOP w0.152: J5.15 v2(157.1,81.41)
  L5_SIG2 w0.107: v2(157.1,81.41) 156.69,81.81 156.69,87.99 157.48,88.77 157.48,93.03 v2(157.36,93.15)
  BOTTOM w0.152: R395.1 v2(157.36,93.15)
DBG_TCK: length 37.2
  TOP w0.127: U15.J15 v1(149.82,104.08)
  TOP w0.152: J5.11 v2(157.1,83.95)
  L5_SIG2 w0.107: v2(157.1,83.95) 158.47,85.32 158.47,91.14 158.8,91.47 158.8,92.89 156.67,95.02 156.67,97.29 155.51,98.46 v1(155.51,107.43)
  L10_SIG4 w0.107: v1(155.51,107.43) 155.52,107.41 155.52,105.71 155.08,105.27 151,105.27 v1(149.82,104.08)
  BOTTOM w0.152: R379.2 v1(155.51,107.43)
DBG_TDI: length 17.9
  TOP w0.127: U15.M16 v1(150.62,100.88)
  TOP w0.152: J5.3 v1(157.1,89.03)
  L5_SIG2 w0.107: v1(150.62,100.88) 150.62,99.82 151,99.44 151,98.23 153.19,96.04 153.19,92.06 156.22,89.03 v1(157.1,89.03)
DBG_TDO: length 23.1
  TOP w0.127: U15.J18 v1(152.22,104.08)
  TOP w0.152: J5.7 157.53,86.49 v1(157.1,86.92)
  L5_SIG2 w0.107: v1(152.22,104.08) 152.6,103.7 152.6,99.96 153.12,99.44 153.79,99.44 156.44,96.79 156.44,94.84 157.77,93.52 157.77,87.59 v1(157.1,86.92)
DBG_TMS: length 16.9
  TOP w0.127: U15.L16 v1(150.62,101.68)
  TOP w0.152: J5.1 v1(157.1,90.3)
  L5_SIG2 w0.107: v1(157.1,90.3) 157.1,91.09 153.48,94.71 153.48,97.25 152.05,98.68 151.04,99.69 151.04,101.27 v1(150.62,101.68)
DBG_TRSTN: length 25
  TOP w0.127: U15.L17 v1(151.42,101.68)
  TOP w0.152: J5.2 v2(167,90.3)
  L10_SIG4 w0.107: v2(167,90.3) 165.13,92.18 165.13,94.13 160.89,98.37 153.39,98.37 151.84,99.93 151.84,101.27 v1(151.42,101.68)
DDR3_CLKN: length 37.8
  TOP w0.102: U17.36 88.46,97.62 88.58,97.5 89.39,97.5 90.47,96.41 90.47,94.8 90.47,94.79 90.47,93.66 90.47,93 90.47,93 90.47,92.34 90.47,89.94 89.84,89.31 89.84,88.43 v1(90.11,88.17)
  BOTTOM w0.102: v1(90.11,88.17) 89.84,88.43 89.84,88.69 90.03,88.87 90.43,88.87 90.61,88.68 90.61,87.44 89.66,86.49 80.7,86.49 74.75,80.54 72.39,80.54 71.95,80.1 71.95,79.29 71.85,79.19 C457.1
DDR3_CLKP: length 37.9
  TOP w0.102: U17.35 88.46,97.12 88.58,97.24 89.29,97.24 90.22,96.31 90.22,94.9 90.22,93.56 90.22,92.9 90.22,92.23 90.22,90.04 89.59,89.41 89.59,88.43 v1(89.33,88.17)
  BOTTOM w0.102: C456.1 72.5,79.19 72.2,79.49 72.2,79.99 72.5,80.29 74.86,80.29 80.8,86.23 89.77,86.23 90.87,87.33 90.87,88.79 90.53,89.12 89.92,89.12 89.59,88.79 89.59,88.43 v1(89.33,88.17)
DDR_DVDD18: length 9.3
  TOP w0.254: U15.P8 U15.R8 v1(143.42,98.48) ; U15.P8 U15.P7 ; U15.P8 U15.P9 ; U15.P7 U15.R7 v1(142.62,98.48) ; U15.P7 U15.N6 ; v1(144.22,98.48) U15.R9 U15.P9 ; U15.P9 U15.P10 ; U15.P9 U15.N9 144.77,100.48 144.83,100.43 145.21,100.43 145.26,100.48 U15.N10
  vias: v2(139.88,92.81) v2(139.88,91.41) v2(140.64,92.81) v2(140.64,91.41)
DEBUG_LED_BUFF_OE: length 138.2
  L3_SIG1 w0.102: v1(50.56,138.71) 50.56,139.54 51.23,140.22 53.36,140.22 54.41,139.17 57.05,139.17 60.3,135.92 71.46,135.92 72.65,137.11 74.33,137.11 75.67,135.77 80.84,135.77 84.26,132.36 90.94,132.36 91.36,132.79 105.84,132.79 107.16,131.47 108.77,131.47 109.41,132.11 111.63,132.11 112.06,132.54 114.87,132.54 115.93,133.6 127.22,133.6 130.02,130.81 130.81,130.81 131.51,130.11 140.67,130.11 142.14,131.57 150.8,131.57 152.67,129.7 159.99,129.7 v1(160.12,129.57)
  BOTTOM w0.152: U48.10 160.36,127.62 160.34,127.64 160.27,127.64 160.12,127.79 v1(160.12,129.57) U48.13 163.61,129.57 164.26,130.22 U48.1 168.1,130.22 168.28,130.05 168.28,128.4 168.15,128.27 ; 168.15,128.27 U48.4 ; 168.15,128.27 168.53,127.89 169.13,127.89 169.35,127.67 R327.2 ; v1(50.56,138.71) U39.23
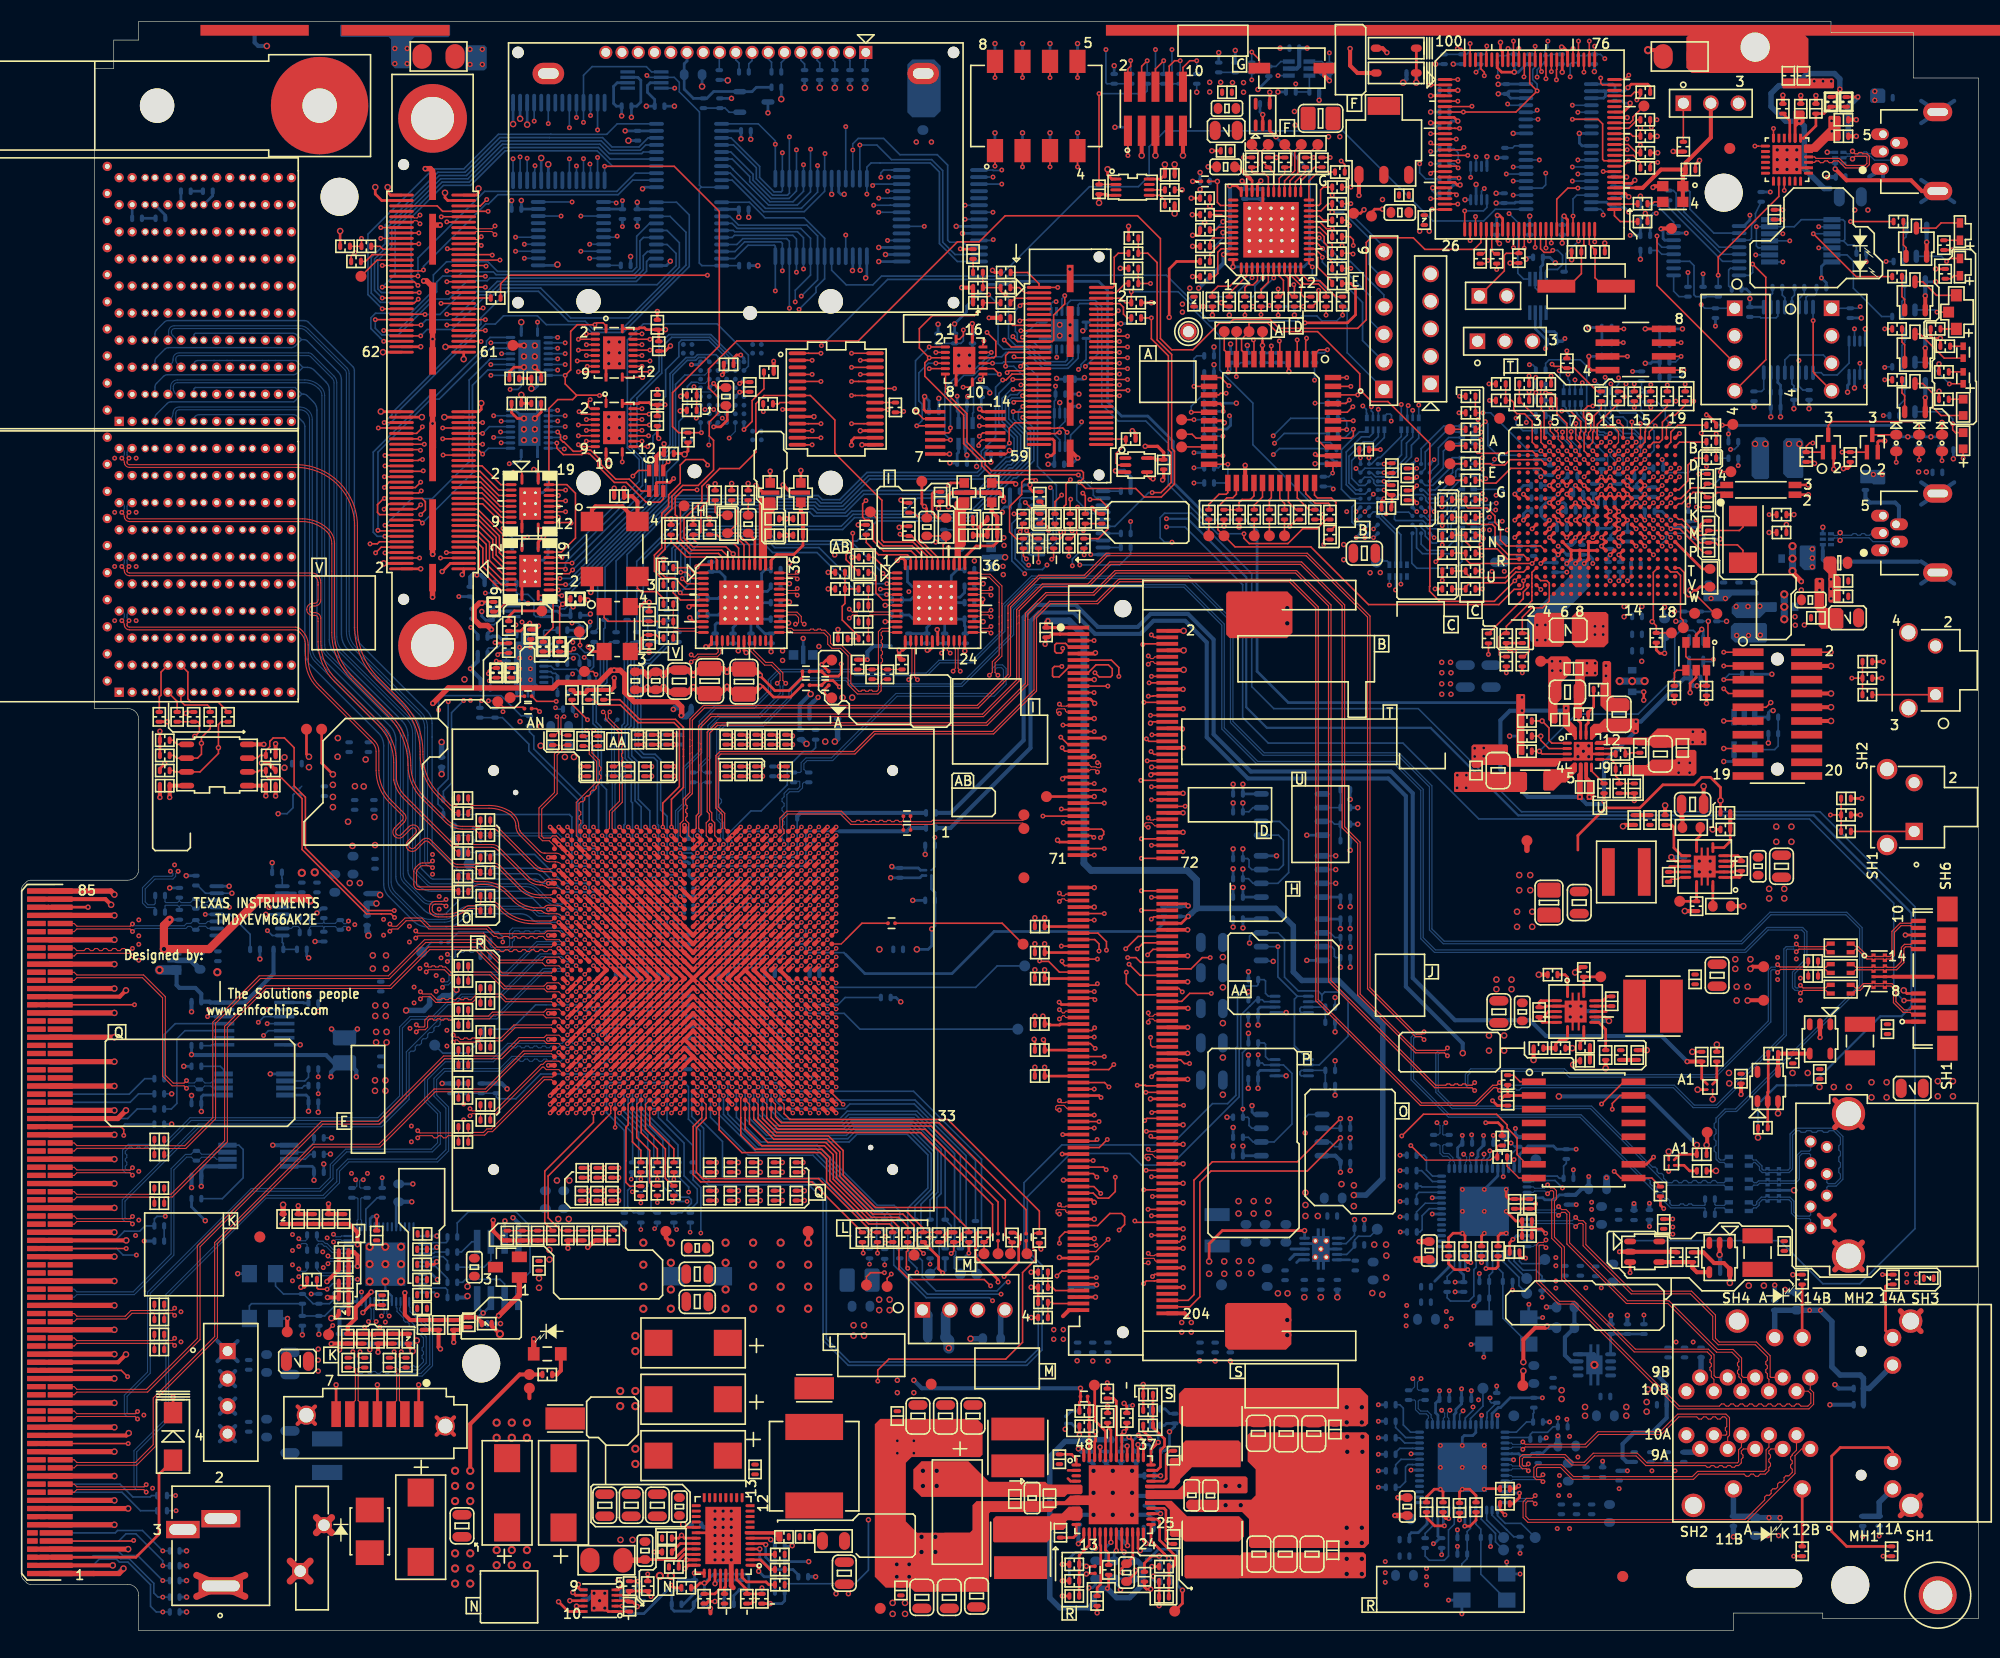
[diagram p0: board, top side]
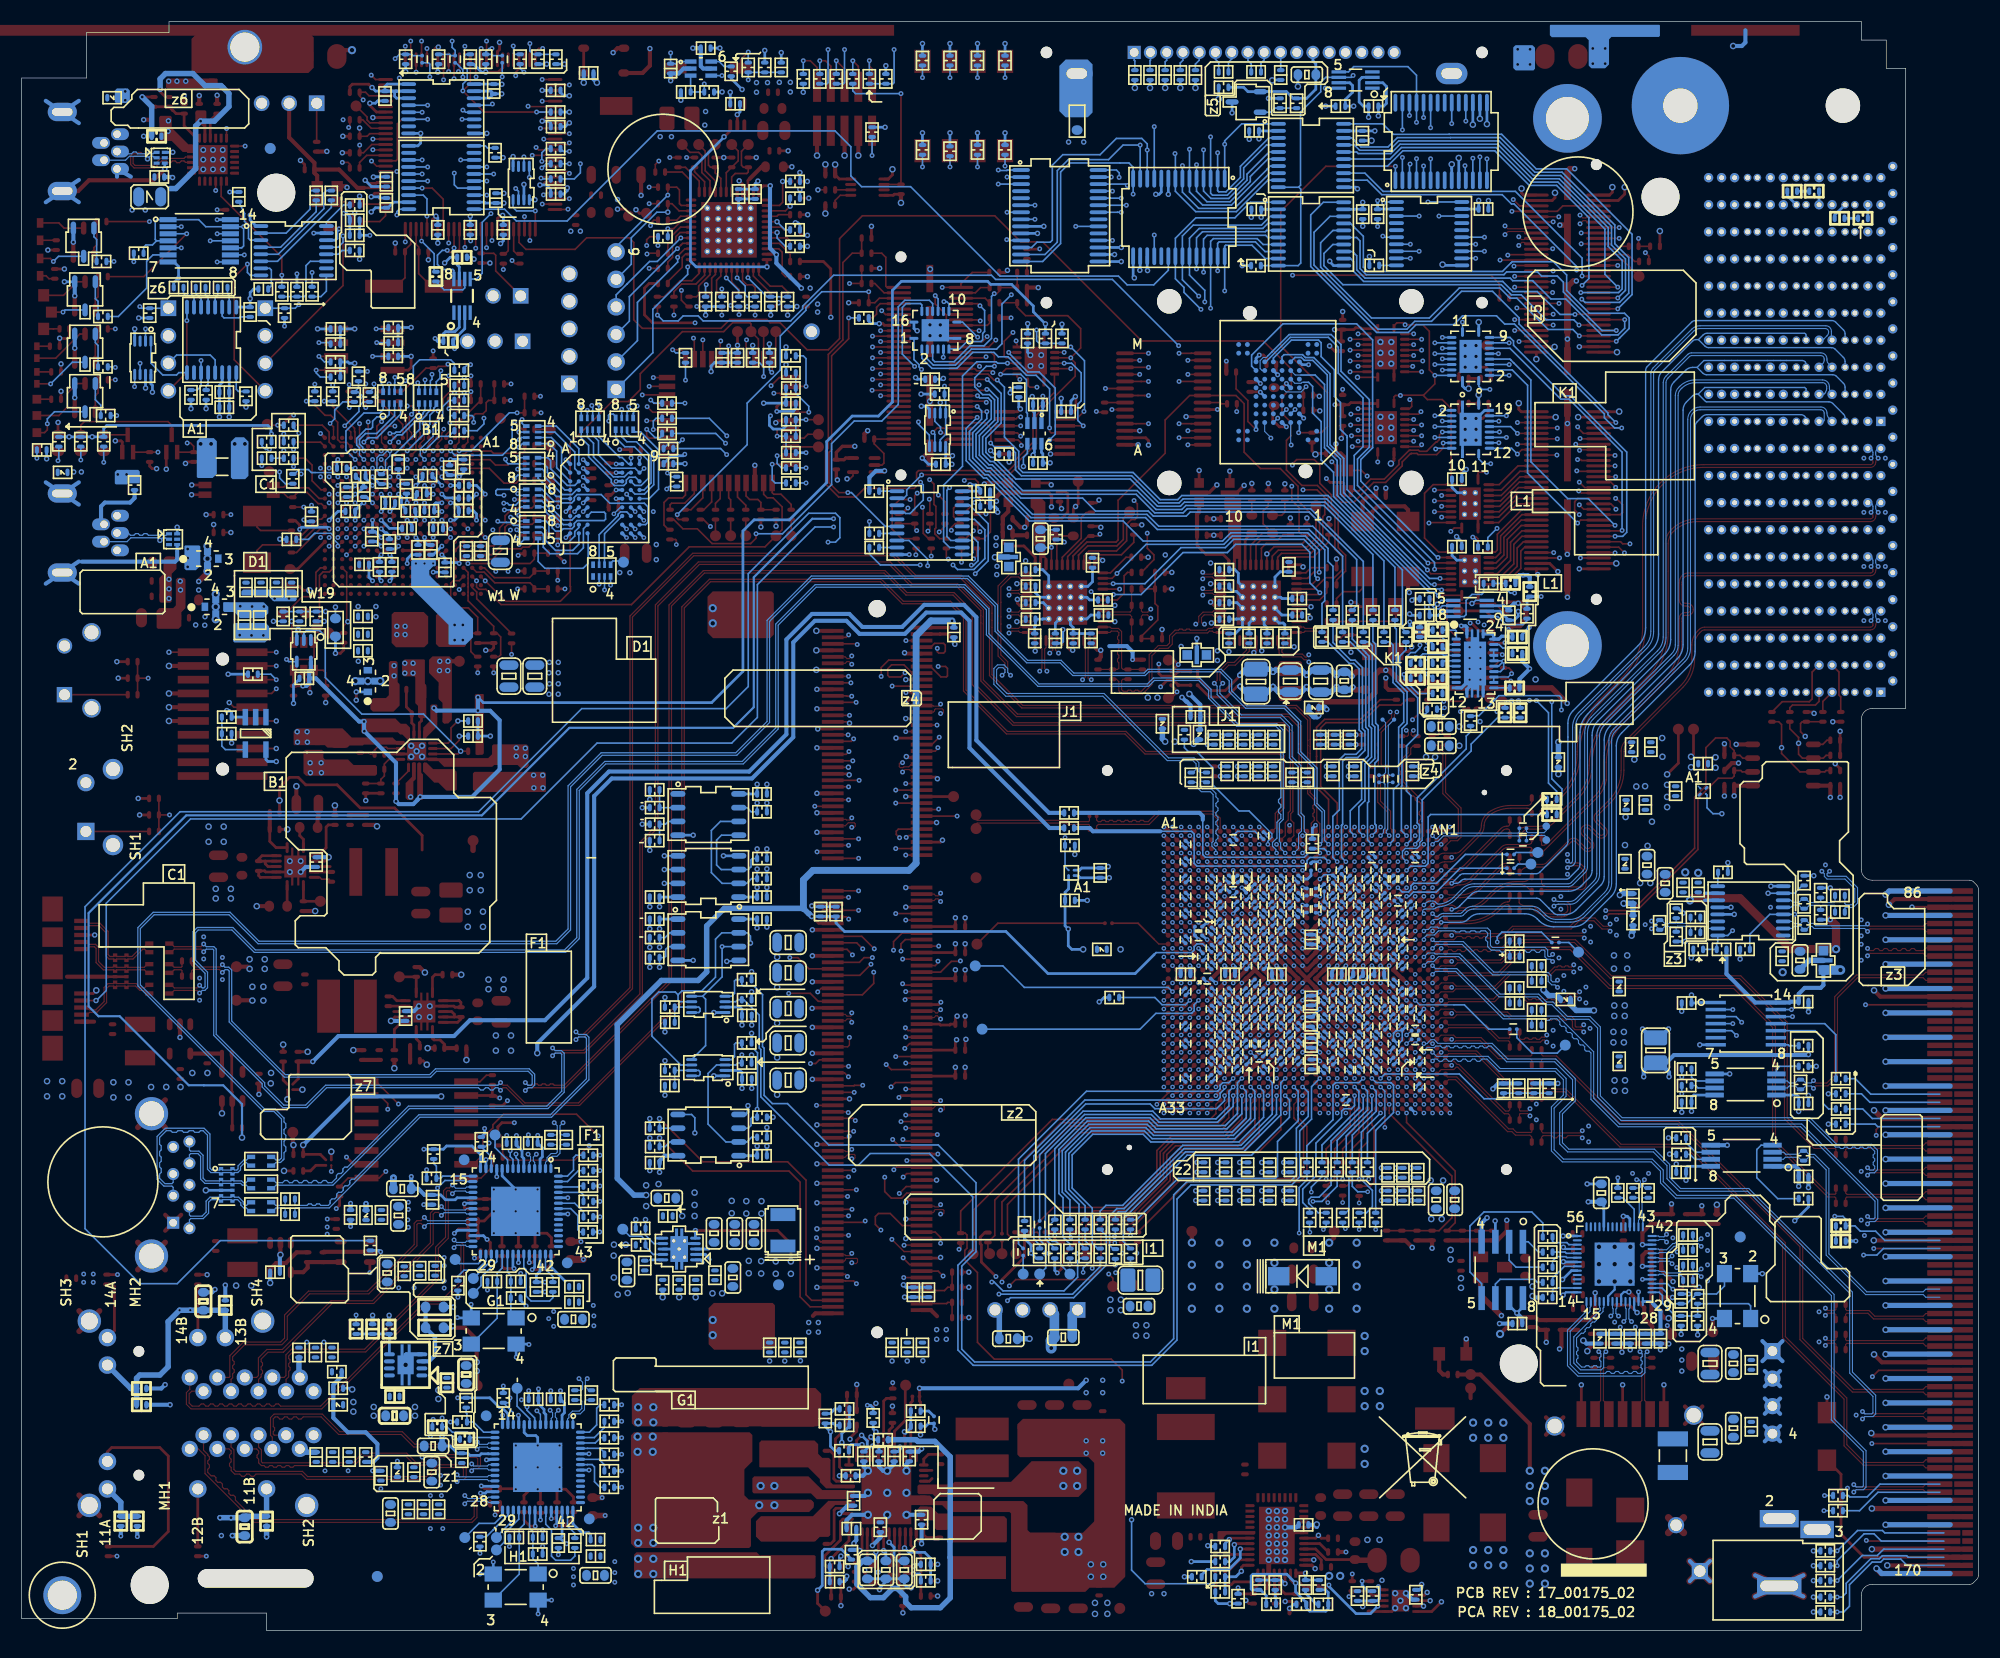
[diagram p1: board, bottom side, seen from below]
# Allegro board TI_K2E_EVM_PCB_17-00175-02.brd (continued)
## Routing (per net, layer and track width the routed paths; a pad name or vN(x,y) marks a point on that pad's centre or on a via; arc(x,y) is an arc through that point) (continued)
DIMM_SA0: length 4.3
  TOP w0.152: DIMM1.197 95.42,31.37 95.12,31.67 R251.1 R247.1
DIMM_SA1: length 4.3
  TOP w0.152: R253.1 R252.1 95.12,30.28 95.23,30.17 DIMM1.201
DIMM_SCL: length 31.3
  TOP w0.152: v2(121.72,45.47) 118.66,42.41 109.78,42.41 108.75,41.37 108.75,30.79 107.82,29.87 DIMM1.202
  BOTTOM w0.152: v2(121.72,45.47) R497.1 121.21,44.65 120.78,45.09 U71.7
DIMM_SDA: length 31.7
  TOP w0.152: v2(121.72,47.24) 117.74,43.26 109.9,43.26 108.2,41.56 108.2,30.99 107.68,30.47 DIMM1.200
  BOTTOM w0.152: v2(121.72,47.24) R493.1 U71.6
DIP_SW_B0: length 62.6
  TOP w0.152: v1(140.28,143.89) 140.19,143.98 U1.86 ; SW1.1 v1(89.84,135.17)
  L3_SIG1 w0.102: v1(140.28,143.89) 140.28,142.77 140.63,142.43 140.63,139.4 140.19,138.96 134.8,138.96 133.45,140.31 133.45,140.32 132.99,140.78 132.4,140.78 132.28,140.89 127.71,140.89 127.32,140.51 117.89,140.51 117.69,140.72 109.35,140.72 106.18,137.54 92.21,137.54 v1(89.84,135.17)
  BOTTOM w0.152: R315.2 v1(89.84,135.17)
DIP_SW_B1: length 60.3
  TOP w0.152: U1.85 140.69,143.23 v1(140.69,143.23) ; SW1.2 v1(92.38,135.09)
  L3_SIG1 w0.102: v1(140.69,143.23) 140.96,142.96 140.96,139.41 140.26,138.71 133.89,138.71 131.94,140.67 127.98,140.67 127.01,139.7 115.04,139.7 114.76,139.41 108.37,139.41 106.27,137.31 94.6,137.31 v1(92.38,135.09)
  BOTTOM w0.152: R314.2 v1(92.38,135.09)
DIP_SW_B2: length 58.1
  TOP w0.152: U1.84 v1(141.19,143.89) ; SW1.3 v1(94.92,135.09)
  L3_SIG1 w0.102: v1(141.19,143.89) 141.19,138.65 140.13,137.59 133.06,137.59 132.48,138.17 130.88,138.17 130.5,138.56 127.97,138.56 127.07,139.46 117.28,139.46 116.48,138.66 109.15,138.66 107.58,137.08 96.91,137.08 v1(94.92,135.09)
  BOTTOM w0.152: R316.2 v1(94.92,135.09)
DIP_SW_B3: length 55.7
  TOP w0.152: v1(141.66,143.13) 141.66,144.06 141.69,144.09 U1.83 ; SW1.4 v1(97.46,135.09)
  L3_SIG1 w0.102: v1(97.46,135.09) 99.07,136.7 107.52,136.7 109.25,138.43 127.39,138.43 128.04,137.78 130.12,137.78 130.62,137.28 140.53,137.28 141.66,138.41 v1(141.66,143.13)
  BOTTOM w0.152: R313.2 v1(97.46,135.09)
DSP_PMBUS_EN: length 91.1
  TOP w0.152: U1.47 v4(143.69,128.25)
  L8_SIG3 w0.107: v2(121.23,58.42) 123.77,60.97 123.77,71.86 124.88,72.97 124.91,72.97 125.5,73.57 125.5,92.78 121.52,96.77 121.52,106.12 122.25,106.86 122.25,107.44 124.3,109.48 128.96,109.48 138.19,118.72 138.19,121.01 140.54,123.36 140.54,126.09 141.45,127.01 142.45,127.01 v4(143.69,128.25)
  BOTTOM w0.152: v4(143.69,128.25) 142.53,127.09 142.53,125.58 R628.1 ; R471.2 v2(121.23,58.42)
DSP_SCL_AMC: length 9.7
  BOTTOM w0.152: R574.1 10.96,11.05 9.26,12.75 AMC1.160
DSP_SDA_AMC: length 9.5
  BOTTOM w0.152: AMC1.159 9.08,13.5 10.26,12.32 11.86,12.32 11.99,12.45 R573.1
DSP_VCL_R: length 107.8
  TOP w0.152: U23.V29 v4(60.78,50.96)
  BOTTOM w0.152: v4(60.78,50.96) 61.54,50.19 61.54,47.19 62.64,46.1 62.64,41.86 63.38,41.12 72.67,41.12 73.96,39.82 73.96,26.8 76.29,24.47 92.77,24.47 94.18,25.88 94.18,33.71 92.82,35.07 92.82,40.03 96.81,44.02 102.29,44.02 103.35,42.95 106.07,42.95 112.38,49.26 112.38,53.61 112.52,53.76 112.52,56.8 113.38,57.66 113.39,57.66 113.95,58.22 R470.2 114.51,58.22 114.69,58.03 U67.3
DSP_VD_R: length 109.5
  TOP w0.152: U23.U30 v4(62.38,50.16)
  BOTTOM w0.152: v4(62.38,50.16) 62.33,50.16 61.85,49.68 61.85,47.45 62.94,46.36 62.94,42 63.53,41.42 73.05,41.42 74.27,40.2 74.27,26.92 76.42,24.78 92.65,24.78 93.83,25.96 93.83,33.63 92.51,34.94 92.51,41.33 96,44.81 106.1,44.81 109.91,48.63 111.31,48.63 112.07,49.39 112.07,53.74 112.22,53.89 112.22,58.69 113.01,59.49 114,59.49 114.13,59.62 R468.2 114.68,60.07 114.81,59.94 114.81,58.8 115.07,58.54 U67.4
EEPROM_WPZ: length 112.1
  L8_SIG3 w0.107: v1(53.16,135.96) 53.44,135.67 73.76,135.67 73.89,135.55 92.93,135.55 103.3,125.17 103.3,120.7 109.65,114.35 109.65,79.55 112.72,76.49 v2(112.72,76.38)
  BOTTOM w0.152: EEPROM1.7 113.65,75.95 113.27,75.56 R423.2 v2(112.72,76.38) ; v1(53.16,135.96) U39.2
EMA_A0: length 7
  TOP w0.127: U15.C14 v1(149.02,108.88)
  BOTTOM w0.152: RN1.3 146.18,112.14 147.84,110.48 148.86,110.48 149.42,109.93 149.42,109.52 149.12,109.22 149.12,108.99 v1(149.02,108.88)
EMA_A1: length 8.4
  TOP w0.127: U15.D15 v1(149.82,108.08)
  BOTTOM w0.152: v1(149.82,108.08) 150.67,108.94 150.67,110.71 149.01,112.37 147.55,112.37 147.24,112.68 RN1.1
EMA_A2: length 6
  TOP w0.127: U15.B14 v1(149.02,109.68)
  BOTTOM w0.152: RN1.4 145.62,112.27 147.8,110.09 148.61,110.09 v1(149.02,109.68)
EMA_A3: length 8
  TOP w0.127: U15.D14 v1(149.02,108.08)
  BOTTOM w0.127: v1(149.02,108.08) 149.42,108.49 149.42,109.16 149.42,109.16
  BOTTOM w0.152: RN1.2 146.68,112.22 146.89,112.01 147.81,112.01 148.21,111.62 148.21,111.07 148.39,110.88 148.82,110.88 149.68,110.03 149.68,109.41 149.42,109.16
EMA_A4: length 31.5
  TOP w0.127: 148.62,110.85 U15.A14
  TOP w0.152: v1(148.62,111.55) 148.62,110.85
  L3_SIG1 w0.102: v1(134.69,100.24) 134.21,100.72 133.2,100.72 133.11,100.63 133.11,99.82 133.21,99.72 135.22,99.72 135.71,99.23 141.18,99.23 141.62,99.67 144.4,99.67 145.43,100.7 145.43,101.54 146.24,102.34 146.24,102.64 146.5,102.9 146.77,102.9 147,103.13 147,103.54 147.84,104.38 147.84,105.84 148.06,106.07 148.34,106.07 149.4,107.13 149.4,108.24 149.17,108.47 148.84,108.47 148.64,108.67 148.64,111.54 v1(148.62,111.55)
  BOTTOM w0.152: RN3.4 134.14,100.79 v1(134.69,100.24)
EMA_A5: length 35
  TOP w0.127: U15.C13 v1(148.22,108.88)
  L3_SIG1 w0.102: v1(136.66,102.39) 136.62,102.35 136.62,101.15 136.44,100.97 135.89,100.97 135.71,100.79 135.71,100.54 135.89,100.36 136.63,100.36 136.74,100.25 136.74,99.7 136.86,99.58 137.21,99.58 137.36,99.72 137.36,101.15 137.77,101.56 138.44,101.56 138.69,101.31 138.69,99.66 138.82,99.54 139.13,99.54 139.3,99.71 139.3,101.03 139.49,101.22 139.74,101.22 139.91,101.05 139.91,99.67 140.05,99.53 140.3,99.53 140.52,99.75 140.52,100.29 140.7,100.46 141.66,100.46 141.66,100.47 141.9,100.47 142.1,100.67 142.1,101.22 142.31,101.43 142.88,101.43 143,101.3 143,100.52 143.15,100.37 143.68,100.37 143.8,100.49 143.8,101.29 143.94,101.43 145.03,101.43 145.79,102.19 145.79,103.52 147,104.73 147,105.04 147.63,105.68 147.63,106.44 148.06,106.87 148.34,106.87 148.6,107.13 148.6,108.26 148.22,108.64 v1(148.22,108.88)
  BOTTOM w0.152: v1(136.66,102.39) 136.55,102.28 135.83,102.28 135.47,102.28 135.2,102.01 134.74,102.01 134.59,101.85 RN3.2
EMA_A6: length 33.4
  TOP w0.127: U15.E13 v1(148.22,107.28)
  L3_SIG1 w0.102: v1(148.22,107.28) 148,107.07 147.97,107.07 147.2,106.3 147.2,105.73 146.77,105.3 146.5,105.3 146.2,105 146.2,104.73 145.4,103.93 145.4,102.2 145.03,101.83 141.88,101.83 141.32,101.27 140.9,101.27 140.1,102.07 139.26,102.07 139.25,102.06 137.61,102.06 136.9,102.77 136.44,102.77 136.16,102.49 136.16,102.47 135.76,102.07 132.48,102.07 132.09,102.46 128.98,102.46 128.64,102.12 128.64,101.6 128.89,101.35 134.66,101.35 v1(134.91,101.6)
  BOTTOM w0.152: v1(134.91,101.6) 134.66,101.35 RN3.3
EMA_A7: length 35.3
  TOP w0.127: U15.B13 147.82,109.29 v1(148.22,109.68)
  L3_SIG1 w0.102: v1(135.47,102.76) 135.47,104.07 135.6,104.19 135.6,106.68 135.8,106.88 136.89,106.88 137.07,106.71 137.07,106.19 137.25,106.01 137.5,106.01 137.68,106.19 137.68,106.83 137.85,107 138.1,107 138.29,106.81 138.29,106.19 138.47,106.01 138.72,106.01 138.9,106.19 138.9,106.71 139.08,106.88 140.82,106.88 141.64,106.07 143.26,106.07 144.87,107.68 145.15,107.68 145.41,107.94 145.41,110.58 145.61,110.78 146.37,110.78 146.58,110.99 146.58,112.93 146.4,113.11 145.84,113.11 145.66,113.29 145.66,113.54 145.84,113.72 146.4,113.72 146.58,113.9 146.58,114.51 146.72,114.66 147.29,114.66 147.44,114.51 147.44,113.53 147.61,113.36 148.01,113.36 148.22,113.15 v1(148.22,109.68)
  BOTTOM w0.127: RN3.1 134.9,102.41 134.95,102.46
  BOTTOM w0.152: 134.95,102.46 134.98,102.46 135.27,102.76 v1(135.47,102.76)
EMA_A8: length 38.4
  TOP w0.127: 147.82,110.85 U15.A13
  TOP w0.152: 147.82,110.85 147.82,111.15 v1(147.38,111.59)
  L8_SIG3 w0.102: v1(147.38,111.59) 147.65,111.32 147.65,111.13 148.01,110.77 151.2,110.77 151.51,111.07 151.51,111.99 151.32,112.18 145.97,112.18 143.97,110.19 139.69,110.19 139,109.49 139,108.69 138.82,108.51 138.12,108.51 137.94,108.34 137.94,108.08 138.12,107.9 138.82,107.9 139,107.73 139,107.47 138.82,107.29 138.12,107.29 137.94,107.12 137.94,106.86 138.12,106.69 138.82,106.69 139,106.51 139,106.25 138.82,106.08 138.12,106.08 137.94,105.9 137.94,105.64 138.12,105.47 138.82,105.47 139,105.29 139,103.68 138.57,103.25 138.1,103.25 137.92,103.43 137.92,103.69 137.74,103.87 137.49,103.87 137.31,103.69 137.31,103.43 137.13,103.25 136.91,103.25 v1(136.1,104.05)
  BOTTOM w0.152: v1(136.1,104.05) 135.76,104.05 135.6,103.89 134.99,103.89 134.61,104.27 RN4.3
EMA_A9: length 30.7
  TOP w0.127: U15.D12 147.02,107.69 v1(147.42,108.08)
  L3_SIG1 w0.102: v1(147.42,108.08) 147.15,108.08 147.01,108.22 147.01,109.13 146.87,109.27 146.46,109.27 146.24,109.04 146.24,106.36 145.97,106.1 145.7,106.1 144.57,104.98 144,104.98 143.8,104.78 143.8,103.93 143.57,103.7 143.26,103.7 142.99,103.97 142.99,104.28 142.85,104.42 142.5,104.42 142.34,104.26 142.34,103.92 142.12,103.7 141.62,103.7 141.44,103.89 141.44,104.95 141.12,105.27 140.47,105.27 140.3,105.09 140.3,103.47 140.12,103.29 139.86,103.29 139.69,103.47 139.69,105.23 139.53,105.39 139.15,105.39 139,105.24 139,103.49 138.84,103.33 138.41,103.33 138.21,103.53 138.21,105.15 137.98,105.39 137.23,105.39 136.93,105.08 136.93,103.63 136.73,103.43 v1(136.04,103.43)
  BOTTOM w0.152: v1(136.04,103.43) 134.82,103.43 134.54,103.71 RN4.4
EMA_A10: length 28
  TOP w0.127: U15.C12 v1(147.42,108.88)
  L3_SIG1 w0.102: v1(136.09,104.78) 136.09,105.44 136.35,105.71 140.05,105.71 140.41,106.07 141.17,106.07 141.44,105.8 141.44,105.53 141.66,105.3 144.37,105.3 144.6,105.53 144.6,105.89 145.83,107.12 145.83,109.12 146.2,109.49 146.2,109.96 146.31,110.08 146.85,110.08 147,110.23 147,112.71 147.21,112.92 147.65,112.92 147.84,112.73 147.84,109.3 v1(147.42,108.88)
  BOTTOM w0.127: 134.99,105.33 134.98,105.33 RN4.1
  BOTTOM w0.152: v1(136.09,104.78) 136.7,104.78 136.83,104.91 136.83,105.19 136.7,105.33 134.99,105.33
EMA_A11: length 36.7
  TOP w0.127: 147.21,110.85 147.38,110.67 147.38,109.65 U15.B12
  TOP w0.152: 147.21,110.85 146.89,111.16 v1(146.15,111.16)
  L3_SIG1 w0.102: v1(146.15,111.16) 146.17,111.18 146.17,111.72 146,111.89 144.98,111.89 144.64,111.55 144.64,107.96 143.54,106.87 141.62,106.87 141,107.49 140.09,107.49 139.91,107.67 139.91,108.23 139.73,108.41 139.48,108.41 139.3,108.23 139.3,107.67 139.12,107.49 138.87,107.49 138.69,107.67 138.69,108.23 138.51,108.41 138.26,108.41 138.08,108.23 138.08,107.67 137.9,107.49 135.77,107.49 134.27,105.98 131.78,105.98 131.46,105.66 131.46,104.03 131.63,103.86 131.99,103.86 132.17,104.03 132.17,104.77 132.35,104.95 132.6,104.95 132.78,104.77 132.78,104.03 132.96,103.86 133.21,103.86 133.39,104.03 133.39,104.77 133.56,104.95 133.82,104.95 134,104.77 134,104.03 134.17,103.86 134.46,103.86 134.66,104.05 134.66,104.77 v1(134.82,104.94)
  BOTTOM w0.152: v1(134.82,104.94) 134.65,104.77 RN4.2
EMA_A12: length 40.1
  TOP w0.127: U15.D13 147.82,107.69 v1(148.22,108.08)
  L3_SIG1 w0.102: v1(148.22,108.08) 147.96,108.08 147.54,107.67 147.26,107.67 147,107.4 147,106.33 146.77,106.1 146.5,106.1 146.2,105.8 146.2,105.53 145.97,105.3 145.7,105.3 144.6,104.21 144.6,102.24 144.42,102.06 143.98,102.06 143.8,102.25 143.8,103.27 143.65,103.42 143.18,103.42 143,103.24 143,102.33 142.74,102.07 142.41,102.07 142.21,102.26 142.21,102.79 142.11,102.9 141.59,102.9 141.44,102.74 141.44,102.25 141.25,102.07 140.89,102.07 140.09,102.87 138.22,102.87 138.02,103.07 136.31,103.07 135.85,102.62 135.85,102.6 135.63,102.38 132.96,102.38 132.55,102.79 126.55,102.79 126.24,102.48 126.24,101.05 126.42,100.87 126.72,100.87 126.9,100.69 126.9,100.44 126.72,100.26 126.42,100.26 126.24,100.08 126.24,99.83 126.42,99.65 126.69,99.65 126.87,99.47 126.87,99.22 126.69,99.04 126.42,99.04 126.24,98.86 v1(126.24,96.49)
  BOTTOM w0.152: RN9.4 v1(126.24,96.49)
EMA_BA0: length 36.3
  TOP w0.127: U15.C15 v1(149.82,108.88)
  L3_SIG1 w0.102: v1(149.82,108.88) 150.03,108.67 150.06,108.67 150.4,108.33 150.4,106.87 149.4,105.87 149.4,103.93 148.6,103.13 148.6,102.33 148.32,102.05 148.32,99.46 146.93,98.07 138.22,98.07 137.42,97.27 134.63,97.27 134.5,97.41 133.14,97.41 132.96,97.23 132.96,96.9 132.79,96.73 132.53,96.73 132.36,96.9 132.36,97.23 132.18,97.41 131.33,97.41 131.32,97.42 130.92,97.42 130.91,97.41 129.23,97.41 127.87,96.04 v1(126.8,96.04)
  BOTTOM w0.152: RN9.3 v1(126.8,96.04)
EMA_BA1: length 35.6
  TOP w0.127: U15.A15 149.42,110.85
  TOP w0.152: 149.42,110.85 v1(149.42,111.39)
  L3_SIG1 w0.102: v1(149.42,111.39) 149.42,108.75 149.7,108.47 149.97,108.47 150.2,108.24 150.2,107.1 148.6,105.5 148.6,103.93 147.57,102.9 147.3,102.9 147.04,102.64 147.04,101.51 145.99,100.47 145.61,100.47 144.05,98.9 135.13,98.9 133.98,97.76 128.48,97.76 v1(127.3,96.58)
  BOTTOM w0.152: RN9.2 v1(127.3,96.58)
EMA_D0: length 31.8
  TOP w0.152: v1(145.01,113.02) 144.56,113.02 144.16,112.62 144.16,111.99 144.36,111.79 144.36,110.66 144.21,110.5 144.21,108.89 U15.C9
  L3_SIG1 w0.102: v1(127.34,113.16) 127.34,115.83 128.13,116.62 138.84,116.62 139.01,116.46 141.55,116.46 141.75,116.66 143.96,116.66 144.69,115.93 144.69,114.78 144.51,114.6 144.06,114.6 143.88,114.43 143.88,114.17 144.06,113.99 144.51,113.99 144.69,113.82 144.69,113.35 v1(145.01,113.02)
  BOTTOM w0.152: RN5.5 v1(127.34,113.16)
EMA_D1: length 29.2
  TOP w0.152: U15.A8 143.82,110.54 143.8,110.55 143.91,110.66 143.91,111.6 142.94,112.56 v1(142.15,112.56)
  L3_SIG1 w0.102: v1(127.98,113.07) 127.98,115.71 128.4,116.13 137.33,116.13 138.24,115.22 141.53,115.22 141.71,115.04 141.71,114.15 141.89,113.97 142.14,113.97 142.32,114.15 142.32,115.04 142.5,115.22 143.02,115.22 143.46,114.78 143.46,112.81 143.21,112.56 v1(142.15,112.56)
  BOTTOM w0.152: v1(127.98,113.07) 127.89,112.98 RN5.6
EMA_D2: length 29
  TOP w0.127: 143.45,110.85 143.45,109.93 143.82,109.56 U15.B8
  TOP w0.152: 143.45,110.85 v1(143.45,111.41)
  L3_SIG1 w0.102: v1(143.45,111.41) 143.01,111.85 140.98,111.85 139.27,113.56 138.35,113.56 137.89,114.02 133.5,114.02 132.17,112.69 132.17,111.65 131.45,110.93 130.97,110.93 130.79,111.11 130.79,112.33 130.61,112.5 130.36,112.5 130.18,112.33 130.18,111.11 130,110.93 129.75,110.93 129.57,111.11 129.57,112.33 129.39,112.5 129.14,112.5 128.96,112.33 128.96,111.11 128.78,110.93 128.12,110.93 127.88,111.16 127.88,112.49 128.01,112.62 v1(128.39,112.62)
  BOTTOM w0.152: RN5.7 v1(128.39,112.62)
EMA_D3: length 26.8
  TOP w0.127: U15.E8 v1(143.42,107.28)
  L3_SIG1 w0.102: v1(143.42,107.28) 143.83,107.7 143.83,111.56 143.21,112.18 141.08,112.18 139.4,113.86 138.48,113.86 136.8,115.54 133.98,115.54 133.8,115.37 133.8,114.5 133.62,114.33 133.37,114.33 133.19,114.5 133.19,115.37 133.01,115.54 132.29,115.54 131.98,115.24 131.98,113.42 131.68,113.11 v1(128.95,113.11)
  BOTTOM w0.152: RN5.8 v1(128.95,113.11)
EMA_D4: length 28
  TOP w0.127: U15.B5 v1(141.02,109.68)
  L3_SIG1 w0.102: v1(141.02,109.68) 139.74,109.68 139.26,110.16 139.26,111.67 138.65,112.28 137.78,112.28 136.55,111.06 134.62,111.06 134.55,110.99 134.3,110.74 134.3,109.77 132.75,108.22 132.75,107.39 132.57,107.22 132.32,107.22 132.14,107.39 132.14,108.36 131.95,108.55 131.7,108.55 131.53,108.38 131.53,107.39 131.35,107.22 131.1,107.22 130.92,107.39 130.92,108.33 130.74,108.51 126.87,108.51 126.39,108.99 126.39,111.64 126.41,111.65 v1(126.41,111.64)
  BOTTOM w0.152: RN6.8 125.78,112.05 126,112.28 126.32,112.28 126.43,112.17 126.43,111.66 v1(126.41,111.64)
EMA_D5: length 29
  TOP w0.127: U15.E7 v1(142.62,107.28)
  L3_SIG1 w0.102: v1(142.62,107.28) 142.2,107.7 142.2,108.24 141.97,108.47 141.56,108.47 141.44,108.59 141.44,109.8 141.17,110.07 140.49,110.07 139.72,110.84 139.72,111.64 138.78,112.58 136.52,112.58 135.95,112.01 134.72,112.01 134.52,112.21 134.15,112.21 133.88,111.94 133.88,110.11 132.77,108.99 128.48,108.99 128.31,109.17 128.31,109.39 128.13,109.57 127.87,109.57 127.7,109.39 127.7,109.17 127.52,108.99 127.1,108.99 126.79,109.3 126.79,111.96 126.04,112.72 v1(125.22,112.72)
  BOTTOM w0.152: v1(125.22,112.72) RN6.7
EMA_D6: length 27.4
  TOP w0.127: U15.C6 v1(141.82,108.88)
  L3_SIG1 w0.102: v1(124.57,112.96) 124.74,113.12 126.27,113.12 127.27,112.13 127.27,110.57 127.71,110.13 129.4,110.13 129.58,109.95 129.58,109.61 129.76,109.44 130.01,109.44 130.19,109.61 130.19,109.95 130.37,110.13 130.67,110.13 130.85,109.95 130.85,109.72 131.03,109.54 131.28,109.54 131.46,109.72 131.46,109.95 131.64,110.13 132.58,110.13 133.47,111.02 133.47,112.09 134.21,112.83 135.08,112.83 135.16,112.75 135.81,112.75 135.95,112.89 138.9,112.89 140.02,111.77 140.02,110.96 140.23,110.76 140.23,110.74 140.43,110.54 140.45,110.54 140.62,110.37 141.25,110.37 141.82,109.8 v1(141.82,108.88)
  BOTTOM w0.152: v1(124.57,112.96) 124.57,112.56 124.72,112.42 RN6.6
EMA_D7: length 27.2
  TOP w0.127: U15.D7 v1(142.62,108.08)
  L3_SIG1 w0.102: v1(123.79,113.03) 124.22,113.46 126.36,113.46 126.74,113.08 126.76,113.08 127.57,112.27 127.57,111.02 128.02,110.58 131.53,110.58 134.08,113.13 135.21,113.13 135.28,113.06 135.68,113.06 135.82,113.19 139.03,113.19 140.53,111.69 140.53,110.87 140.74,110.66 141.3,110.66 142.23,109.72 142.23,108.49 142.4,108.33 142.4,108.3 v1(142.62,108.08)
  BOTTOM w0.152: v1(123.79,113.03) 124.12,112.7 124.12,112.37 124.16,112.33 RN6.5
EMA_D8: length 15.9
  TOP w0.127: U15.E10 v1(145.02,107.28)
  L5_SIG2 w0.102: v1(145.02,107.28) 144.6,106.87 144.06,106.87 143.84,106.64 143.84,105.56 143.57,105.3 141.35,105.3 141.17,105.13 141.17,104.76 141,104.58 140.74,104.58 140.57,104.76 140.57,105.13 140.39,105.3 140.13,105.3 139.96,105.13 139.96,104.76 139.78,104.58 139.52,104.58 139.35,104.76 139.35,105.13 139.17,105.3 135.62,105.3 135.13,105.79 v1(135.13,106.31)
  BOTTOM w0.152: RN7.8 134.81,106.63 v1(135.13,106.31)
EMA_D9: length 15
  TOP w0.127: U15.D9 v1(144.22,108.08)
  L5_SIG2 w0.102: v1(134.82,107.19) 134.98,107.03 136.44,107.03 136.58,107.17 140.75,107.17 141.02,106.9 143.69,106.9 144.14,107.35 144.14,107.35 144.64,107.84 144.64,109.13 144.64,109.14 144.47,109.31 144.17,109.31 144.03,109.17 144.03,108.27 v1(144.22,108.08)
  BOTTOM w0.152: RN7.7 v1(134.82,107.19)
EMA_D10: length 15.8
  TOP w0.127: U15.A7 v1(143.02,110.67)
  L5_SIG2 w0.102: v1(143.02,110.67) 144.37,110.67 144.51,110.53 144.51,110.03 144.33,109.85 142.72,109.85 142.13,109.27 139.97,109.27 139.56,109.67 135.93,109.67 135.56,109.3 135.56,108.49 v1(135.94,108.11)
  BOTTOM w0.152: RN7.6 135.7,107.69 135.88,107.88 135.88,108.05 v1(135.94,108.11)
EMA_D11: length 14.6
  TOP w0.127: U15.D6 v1(141.82,108.08)
  L5_SIG2 w0.102: v1(141.82,108.08) 141.56,108.08 141.17,108.47 139.99,108.47 139.76,108.69 139.76,109.03 139.49,109.3 139.1,109.3 138.92,109.13 138.92,108.31 138.74,108.13 138.49,108.13 138.31,108.31 138.31,109.13 138.13,109.3 137.88,109.3 137.7,109.13 137.7,108.31 137.52,108.13 137.27,108.13 137.09,108.31 137.09,109.13 136.91,109.3 136.55,109.3 136.32,109.08 136.32,107.79 136.17,107.64 135.42,107.64 v1(134.82,108.25)
  BOTTOM w0.152: RN7.5 v1(134.82,108.25)
EMA_D12: length 14.6
  TOP w0.127: U15.A6 v1(142.22,110.62)
  L5_SIG2 w0.102: v1(142.22,110.62) 142.54,110.62 142.64,110.53 142.64,110.26 142.44,110.07 141.29,110.07 141.11,110.24 141.11,110.46 140.93,110.64 140.68,110.64 140.5,110.46 140.5,110.24 140.32,110.07 140.03,110.07 139.85,110.24 139.85,110.5 139.67,110.68 139.42,110.68 139.24,110.5 139.24,110.24 139.06,110.07 138.81,110.07 138.63,110.24 138.63,110.5 138.46,110.68 138.2,110.68 138.02,110.5 138.02,110.24 137.85,110.07 137.59,110.07 137.41,110.24 137.41,110.5 137.24,110.68 136.98,110.68 136.8,110.5 136.8,110.24 136.63,110.07 136.37,110.07 136.2,110.24 136.2,110.5 136.02,110.68 135.76,110.68 135.59,110.5 135.59,110.24 135.41,110.07 135.18,110.07 135.07,109.95 135.07,109.57 134.71,109.21 v1(134.71,109.21)
  BOTTOM w0.152: RN8.8 134.37,109.56 v1(134.71,109.21)
EMA_D13: length 13.7
  TOP w0.127: U15.B6 142.22,109.56 141.82,109.96 141.82,110.52 141.64,110.71 141.64,110.85
  TOP w0.152: v4(141.64,110.89) 141.64,110.85
  L5_SIG2 w0.102: v4(141.64,110.89) 141.91,110.89 142.23,111.2 142.23,111.88 141.83,112.28 140.83,112.28 140.65,112.1 140.65,111.91 140.48,111.74 140.23,111.74 140.04,111.93 140.04,112.1 139.86,112.28 139.63,112.28 139.43,112.09 139.43,111.23 139.28,111.07 134.83,111.07 134.71,110.96 v1(134.71,110.61)
  BOTTOM w0.152: RN8.6 v1(134.71,110.61)
EMA_D14: length 15
  TOP w0.127: U15.C7 v1(142.62,108.88)
  L5_SIG2 w0.102: v1(142.62,108.88) 142.62,109.29 142.74,109.41 142.91,109.41 143.04,109.29 143.04,107.92 142.78,107.67 136.64,107.67 136.31,107.34 135.22,107.34 134.98,107.57 134.58,107.57 134.33,107.83 134.33,109.57 v1(134.68,109.92)
  BOTTOM w0.152: v1(134.68,109.92) 134.48,110.11 RN8.7
EMA_D15: length 14.2
  TOP w0.127: U15.E6 v1(141.82,106.48)
  L5_SIG2 w0.102: v1(141.82,106.48) 140.76,106.48 140.37,106.87 136.7,106.87 136.56,106.73 134.75,106.73 134.03,107.45 134.03,111.38 v1(134.42,111.77)
  BOTTOM w0.152: v1(134.42,111.77) 134.42,111.43 134.16,111.17 RN8.5
EMIF_BUFF_OE: length 61.9
  TOP w0.152: 51.21,114.02 50.16,115.06 v1(50.16,115.85) 50.67,116.36 50.67,119.91 51.28,120.52 v1(52.91,120.52) 53.09,120.7 53.67,120.7 53.94,120.43 U6.1 ; 51.21,114.02 51.23,114 50.85,113.61 49.48,113.61 48.67,112.8 48.67,105.77 U14.19 50.32,105.76 51.11,104.97 51.11,100.83 49.82,99.54 U16.19 ; 51.21,114.02 53.31,114.02 v1(53.34,114) 53.8,114 53.94,113.86 U10.1 ; U13.4 59.22,107.42 v1(59.67,107.87) ; U10.19 v1(57.25,112.77) ; U6.19 v1(57.25,119.68)
  L3_SIG1 w0.102: v1(59.67,107.87) 60.2,108.4 60.2,111.48 58.91,112.77 v1(57.25,112.77)
  L3_SIG1 w0.107: v1(57.25,112.77) 56.03,114 v1(53.34,114) ; v1(57.25,119.68) 53.75,119.68 v1(52.91,120.52)
  L8_SIG3 w0.107: v1(45.09,114.55) 45.72,115.19 49.48,115.19 50.14,115.85 v1(50.16,115.85)
  BOTTOM w0.152: U51.19 v1(50.16,115.85) ; U51.1 46.11,114.86 45.81,114.55 v1(45.09,114.55)
EMU_DET: length 5.8
  TOP w0.152: EMU1.58 R100.1 101.91,109.53 101.02,108.64 101.02,107.75 101.19,107.57 U12.2
EMU_ENABLE: length 36.9
  TOP w0.152: v2(104.42,106.3) 104.15,106.3 103.87,106.58 U12.4 ; U7.15 88.72,118.72 88.81,118.81 v1(88.81,119.04)
  L8_SIG3 w0.107: v2(104.42,106.3) 104.42,109.75 99.42,114.76 99.42,115.44 v1(98.18,116.68)
  L10_SIG4 w0.107: v1(88.81,119.04) 88.81,116.12 90.1,114.82 91.25,114.82 91.51,115.09 91.64,115.09 92.09,115.54 94.37,115.54 95.79,116.97 97.89,116.97 v1(98.18,116.68)
  BOTTOM w0.152: U49.15 97.52,122.36 97.64,122.48 98.96,122.48 99.31,122.12 99.31,117.81 v1(98.18,116.68)
EMU_RTCK: length 33.9
  TOP w0.152: v1(92.15,122.28) 92.35,122.47 EMU1.7
  L5_SIG2 w0.107: v1(92.15,122.28) 97.16,117.27 97.16,115.49 100.03,112.62 100.03,110.2 102.35,107.87 v1(102.35,102.36)
  BOTTOM w0.152: U49.7 94.03,118.29 93.35,118.97 92.05,118.97 91.9,119.13 91.9,119.73 91.72,119.9 91.72,121.84 v1(92.15,122.28) ; R387.1 v1(102.35,102.36)
EMU_TCK: length 44.7
  TOP w0.152: v1(90.83,123.39) 90.6,123.39 90.35,123.64 R52.1 R53.1 R46.1
  L5_SIG2 w0.107: v1(90.83,123.39) 90.83,122.96 94.95,118.84 94.95,112.34 95.25,112.04 95.25,105.79 v1(94.95,105.49)
  BOTTOM w0.152: v1(90.83,123.39) 91.08,123.14 91.08,119.26 91.77,118.58 93.07,118.58 94.54,117.11 96.33,117.11 96.52,117.3 U49.4 ; v1(94.95,105.49) 95.2,105.24 95.2,100.97 94.84,100.61 U57.13 92.93,100.61 92.81,100.49 92.81,99.49 92.98,99.31 U57.11
EMU_TCK_R: length 2.8
  TOP w0.152: R52.2 92.09,123.95 92.57,123.47 EMU1.3
EMU_TDI: length 38.4
  TOP w0.152: v1(83.77,117.47) 83.77,117.42 83.36,117.02 83.36,115.77 86.94,112.18 86.94,109.55 88.62,107.87 88.62,107.5 89.44,106.68 97.54,106.68 v1(97.54,106.65) ; v1(83.77,117.47) 82.85,118.39 82.85,120.17 84.05,121.36 87.93,121.36 88.72,122.14 R66.1 R65.1 ; v1(83.77,117.47) U7.4
  BOTTOM w0.152: v1(97.54,106.65) 98.91,105.28 98.91,104.78 99.19,104.51 U57.2
EMU_TDI_R: length 2.8
  TOP w0.152: EMU1.5 91.67,122.97 R65.2
EMU_TDO: length 45
  TOP w0.152: v1(104.19,124.33) R51.1 R44.1 ; U7.12 v1(89.61,116.97)
  L10_SIG4 w0.107: v1(89.61,116.97) 91.06,118.42 98.23,118.42 99.69,119.89 99.69,122 102.03,124.33 v1(104.19,124.33)
  BOTTOM w0.152: U57.12 94.95,99.96 95.5,100.52 95.5,105.71 93.76,107.46 93.76,109.98 93.76,109.98 93.76,115.79 92.45,117.1 90.65,117.1 90.52,116.97 v1(89.61,116.97)
EMU_TDO_R: length 2.9
  TOP w0.152: R51.2 101.85,124.33 100.99,123.47 EMU1.4
EMU_TMS: length 59.5
  TOP w0.152: 97.64,105.99 v1(97.63,105.99) ; 97.64,105.99 98,106.35 98,106.88 97.82,107.06 89.49,107.06 88.93,107.63 88.93,108 87.25,109.68 87.25,112.31 85.27,114.29 U7.7 ; 97.64,105.99 98.21,105.41 102.82,105.41 103.61,104.62 105.19,104.62 106.4,105.83 106.4,108.86 106.15,109.12 106.15,117.78 104.8,119.13 104.8,126.26 103.94,127.13 R37.1 R31.1
  BOTTOM w0.152: U57.4 99.13,103.21 99.02,103.1 98.6,103.1 98.3,103.4 98.3,103.42 97.38,104.33 97.38,105.74 v1(97.63,105.99)
EMU_TMS_R: length 5.4
  TOP w0.152: EMU1.2 100.73,123.97 100.84,124.08 100.84,126.75 101.22,127.13 R37.2
EMU_TRST#: length 59
  TOP w0.152: v1(104.34,105.03) 105.17,105.03 106.1,105.96 106.1,108.74 105.84,108.99 105.84,117.65 104.27,119.23 v1(104.27,121.16) R67.2 ; U7.9 87.75,114.95 87.55,114.76 v1(86.89,114.76)
  L3_SIG1 w0.107: v1(86.89,114.76) 84.45,114.76 83.24,115.98 83.24,119.95 84.65,121.36 86.86,121.36 88.41,122.91 89.43,122.91 90.3,123.77 90.99,123.77 91.27,123.49 95.69,123.49 95.8,123.6 98.37,123.6 100.53,121.44 103.99,121.44 v1(104.27,121.16)
  BOTTOM w0.152: U57.6 100.89,101.91 104.01,105.03 v1(104.34,105.03) ; R67.2 v1(104.27,121.16)
EMU_TRST#_R: length 3.7
  TOP w0.152: EMU1.8 101.36,122.47 101.69,122.14 101.69,121.5 102.04,121.16 R67.1
EMU_TVD: length 4.2
  TOP w0.152: J5.5 v1(157.1,87.76)
  BOTTOM w0.152: R409.1 157.61,88.27 v1(157.1,87.76)
EMULED1: length 23.7
  TOP w0.152: v1(147.92,113.88) 147.92,114.22 147.76,114.37 R85.2 ; Q8.1 R104.1 164.72,109.3 165.02,109.61 v1(165.32,109.61)
  L3_SIG1 w0.102: v1(147.92,113.88) 147.92,113.96 148.55,114.59 149.57,114.59 154.2,109.96 159.64,109.96 159.84,110.16 164.77,110.16 v1(165.32,109.61)
EMULED2: length 25
  TOP w0.152: v1(168.02,108.76) R103.1 Q7.1 ; R84.2 v1(148.84,115.06)
  L3_SIG1 w0.102: v1(148.84,115.06) 149.42,115.06 153,111.48 156.61,111.48 156.76,111.63 160.24,111.63 160.37,111.51 165.53,111.51 168.02,109.02 v1(168.02,108.76)
EXP_GPIO_00: length 46.8
  TOP w0.152: CN7.54 v1(32.92,110.99)
  BOTTOM w0.152: U46.20 60.45,131.83 61.62,130.66 61.62,125.9 55.54,119.81 52.61,119.81 51.89,120.54 48.42,120.54 47.6,121.35 44.48,121.35 43.71,120.59 42.82,120.59 34.52,112.29 34.52,111.94 33.57,110.99 v1(32.92,110.99)
EXP_GPIO_01: length 45.2
  TOP w0.152: v1(33.46,111.49) CN7.56
  BOTTOM w0.152: v1(33.46,111.49) 34.19,112.23 34.19,112.39 42.39,120.59 42.39,121.16 44.84,123.61 47.7,123.61 50.47,120.84 52.02,120.84 52.74,120.12 55.41,120.12 61.32,126.02 61.32,129.06 59.84,130.53 U46.18
EXP_GPIO_02: length 37.5
  TOP w0.152: CN7.66 v1(33.42,118.99)
  BOTTOM w0.152: v1(33.42,118.99) 33.13,119.28 33.12,119.28 32.23,120.17 32.23,121.16 32.66,121.59 35.91,121.59 38,123.68 38,125.12 39.21,126.34 43.03,126.34 43.15,126.21 43.92,125.45 56.37,125.45 56.76,125.84 56.76,128.69 57.95,129.88 U46.17
EXP_GPIO_03: length 35.4
  TOP w0.152: v1(36.83,119.49) CN7.68
  BOTTOM w0.152: v1(36.83,119.49) 37.42,120.09 39.71,120.09 42.6,122.98 43.22,122.98 43.34,123.09 44.16,123.91 47.9,123.91 50.67,121.15 56.01,121.15 60.71,125.84 60.71,128.09 59.56,129.23 U46.16
EXP_GPIO_04: length 32.6
  TOP w0.152: CN7.70 v1(33.42,119.99)
  BOTTOM w0.152: v1(33.42,119.99) 34.74,119.99 38.3,123.55 38.3,124.46 38.86,125.02 40.31,125.02 40.69,125.4 43.54,125.4 43.79,125.14 56.49,125.14 57.07,125.72 57.07,128.27 57.38,128.58 U46.15
EXP_GPIO_05: length 30.9
  TOP w0.152: v1(36.86,120.49) CN7.72
  BOTTOM w0.152: v1(36.86,120.49) 37.34,120.98 39.89,120.98 42.19,123.28 43.09,123.28 43.51,123.7 43.51,123.7 44.03,124.22 58.65,124.22 60.4,125.97 60.4,127.11 59.58,127.93 U46.14
EXP_GPIO_06: length 33.4
  TOP w0.152: CN7.74 v1(32.64,120.99)
  BOTTOM w0.152: U46.13 57.76,127.28 57.37,126.89 57.37,125.59 56.61,124.83 43.21,124.83 42.97,124.59 41.13,124.59 39.45,122.9 38.08,122.9 34.77,119.59 33.25,119.59 32.64,120.2 v1(32.64,120.99)
EXP_GPIO_07: length 26.2
  TOP w0.152: CN7.76 37.21,121.49 v1(37.23,121.47)
  BOTTOM w0.152: U46.12 57.95,126.63 57.68,126.36 57.68,125.47 56.74,124.52 43.9,124.52 43.21,123.83 42.97,123.59 40.72,123.59 38.6,121.47 v1(37.23,121.47)
EXP_GPIO_08: length 40.1
  TOP w0.152: CN7.78 v1(33.28,121.99)
  BOTTOM w0.152: U40.20 54.97,139.07 54,138.1 48.84,138.1 48.84,138.11 44,138.11 40.81,134.91 37.99,134.91 31.96,128.88 31.96,123.31 33.22,122.05 33.23,122.05 v1(33.28,121.99)
EXP_GPIO_09: length 42.4
  TOP w0.152: CN7.80 36.21,122.49 v1(36.6,122.89)
  BOTTOM w0.152: U40.18 57.82,137.77 56.98,136.93 54.48,136.93 53.62,137.79 48.72,137.79 48.71,137.8 44.13,137.8 40.93,134.61 38.42,134.61 33.55,129.74 33.55,128.01 32.27,126.72 32.27,123.43 33.11,122.59 36.3,122.59 v1(36.6,122.89)
EXP_GPIO_10: length 37.8
  TOP w0.152: CN7.82 v1(33.28,122.99)
  BOTTOM w0.152: v1(33.28,122.99) 33.26,123.01 33.26,123.01 32.57,123.7 32.57,126.59 33.86,127.88 33.86,129.61 38.55,134.3 41.06,134.3 44.25,137.49 53.5,137.49 54.36,136.63 57.11,136.63 57.6,137.12 U40.17
EXP_GPIO_11: length 39.8
  TOP w0.152: v1(36.69,123.49) CN7.84
  BOTTOM w0.152: U40.16 57.38,136.47 57.24,136.33 54.23,136.33 53.37,137.19 44.37,137.19 41.18,134 38.67,134 34.16,129.48 34.16,127.75 32.88,126.47 32.88,123.83 33.21,123.49 v1(36.69,123.49)
EXP_GPIO_12: length 35.3
  TOP w0.152: CN7.86 v1(33.28,123.99)
  BOTTOM w0.152: U40.15 54.31,135.82 53.24,136.88 44.5,136.88 41.31,133.69 38.8,133.69 34.47,129.36 34.47,125.18 v1(33.28,123.99)
EXP_GPIO_13: length 33.9
  TOP w0.152: v1(36.58,124.16) 36.24,124.49 CN7.88
  BOTTOM w0.152: U40.14 54.52,135.17 53.12,136.58 44.63,136.58 41.44,133.39 38.93,133.39 35.94,130.4 35.94,124.79 v1(36.58,124.16)
EXP_GPIO_14: length 28.4
  TOP w0.152: CN7.90 36.55,124.99 v1(36.58,125.02)
  BOTTOM w0.152: v1(36.58,125.02) 36.58,126.68 42.73,132.83 54.93,132.83 56.62,134.52 U40.13
EXP_GPIO_15: length 27.2
  TOP w0.152: CN7.92 37,125.49 v1(37.08,125.58)
  BOTTOM w0.152: v1(37.08,125.58) 37.08,125.91 42.85,131.67 43.09,131.67 43.95,132.53 55.06,132.53 56.4,133.87 U40.12
EXP_GPIO_16: length 39.7
  TOP w0.152: CN7.94 v1(33.28,125.99)
  L3_SIG1 w0.107: v1(33.28,125.99) 32.69,126.59 32.69,129.58 38.78,135.66 39.42,135.66 46.12,142.36 v1(60.27,142.36)
  BOTTOM w0.152: U37.8 v1(60.27,142.36)
EXP_GPIO_EN: length 107.2
  TOP w0.152: U1.97 134.69,144.14 135,143.83 v1(135,143.51)
  L3_SIG1 w0.102: v1(57.71,143.54) 58.32,144.14 80.32,144.14 81.76,142.7 107.69,142.7 108.89,143.9 129.05,143.9 129.41,143.54 133.04,143.54 133.4,143.18 134.67,143.18 v1(135,143.51)
  BOTTOM w0.152: 62.71,133.22 U40.10 ; 62.71,133.22 62.71,133.25 62.56,133.4 62.56,140.16 60.69,142.03 60.69,142.9 60.23,143.36 U37.6 57.89,143.36 57.71,143.54 v1(57.71,143.54) ; 62.71,133.22 62.54,133.05 62.54,126.22 62.78,125.98 U46.10 R330.2
EXP_SCL2_3V3: length 118.5
  TOP w0.152: v1(39.2,99.49) 39.34,99.49 39.35,99.49 CN7.7 ; R201.1 14.05,79.38 14.18,79.25 U21.7 16.46,79.25 18.16,80.95 v2(18.16,81.48) 18.16,83.62 18.42,83.88 R186.2
  L3_SIG1 w0.102: v1(14.25,11.05) 16.39,13.19 16.39,39.22 19.18,42.01 19.18,62.08 19.94,62.84 19.94,66.88 19.23,67.59 18.52,67.59 17.73,68.38 17.73,81.05 v2(18.16,81.48)
  L8_SIG3 w0.107: v1(39.2,99.49) 39.2,98.96 38.77,98.53 38.46,98.53 37.39,97.46 33.55,97.46 28.63,92.54 28.63,85.74 26.26,83.38 20.06,83.38 v2(18.16,81.48)
  BOTTOM w0.152: R574.2 v1(14.25,11.05)
EXP_SDA2_3V3: length 116.1
  TOP w0.152: R198.1 14.05,80.77 14.31,80.52 U21.6 16.23,80.52 16.59,80.88 v2(16.59,81.89) 16.59,82.43 17.4,83.24 R187.2 ; CN7.5 v1(38.66,98.99)
  L3_SIG1 w0.102: v2(16.59,81.89) 17.04,81.44 17.04,68.63 18.05,67.63 18.16,67.63 18.42,67.37 19.14,67.37 19.72,66.79 19.72,62.93 18.95,62.17 18.95,42.11 16.15,39.31 16.15,14.4 v1(14.2,12.45)
  L8_SIG3 w0.107: v1(38.66,98.99) 38.35,98.99 37.91,98.55 34.32,98.55 28.4,92.63 28.4,85.83 26.17,83.61 18.31,83.61 v2(16.59,81.89)
  BOTTOM w0.152: R573.2 v1(14.2,12.45)
EXP_TP0: length 4.4
  TOP w0.152: TP9.1 32.82,126.49 CN7.96
EXP_TP1: length 4
  TOP w0.152: R42.1 31.72,126.36 32.35,126.99 CN7.98
EXP_TP2: length 2.9
  TOP w0.152: R34.1 33.07,127.76 33.34,127.49 CN7.100
EXP_XFI_MDC_2V5: length 74.9
  L3_SIG1 w0.102: J2.D9 15.55,132.45 25.04,132.45 25.51,131.97 25.51,130.74 27.81,128.44 31.62,124.63 33.2,124.63 33.94,123.89 33.94,98.7 36.65,95.99 38.72,95.99 41.59,93.12 44.09,93.12 44.88,92.33 45.9,92.33 46.18,92.61 v1(46.18,93.08)
  L10_SIG4 w0.107: v1(46.18,93.08) 46.62,93.52 48.11,93.52 49.23,92.41 49.23,89.92 v1(50.85,88.29)
  BOTTOM w0.152: R639.2 50.77,88.29 v1(50.85,88.29)
  BOTTOM w0.254: R653.1 J2.D9
EXP_XFI_MDIO_2V5: length 60.5
  L3_SIG1 w0.102: v1(40.35,95.43) 39.58,96.21 36.78,96.21 34.17,98.83 34.17,124.01 33.28,124.89 31.68,124.89 28.04,128.53 27.13,129.45 27.13,129.45 25.78,130.79 25.78,132.03 25.12,132.69 14.59,132.69 J2.C9
  BOTTOM w0.254: v1(40.35,95.43) R624.1 41.66,95.18 R412.2
EXT_PS#: length 68
  TOP w0.152: R35.1 R34.2 v1(31.36,128.49) ; U8.23 v1(80.57,114.64)
  L8_SIG3 w0.107: v1(80.57,114.64) 80.57,123.44 73.56,130.45 67.81,130.45 67.22,131.05 45.3,131.05 42.61,133.73 38.58,133.73 37.57,132.72 35.59,132.72 v1(31.36,128.49)
FAN_PWM: length 150.6
  TOP w0.254: v1(118.45,120.7) 122.38,120.7 123.11,121.44 123.11,123.9 122.68,124.33 R50.2
  L3_SIG1 w0.254: v1(118.45,120.7) 115.77,120.7 115.27,121.21 115.27,121.37 113.87,122.77 112,122.77 110.88,121.65 110.88,120.13 109.47,118.71 109.47,114.54 110.93,113.08 111.31,113.08 112.98,111.4 116.15,111.4 117.12,110.44 117.12,104.03 118.09,103.05 118.09,97.65 124.46,91.29 124.46,45.84 123.14,44.53 117.83,44.53 114.35,41.04 114.35,32.82 111.72,30.19 91.36,30.19 FAN1.4
  BOTTOM w0.508: C798.1 90.36,29.19 FAN1.4
GP4-0: length 8.3
  TOP w0.127: U15.E12 v1(147.42,107.28)
  TOP w0.152: R83.2 v1(150.37,112.88)
  L5_SIG2 w0.107: v1(147.42,107.28) 147.8,107.67 147.8,109.8 148.52,110.53 149.09,110.53 150.37,111.8 v1(150.37,112.88)
GP4-1: length 5.7
  TOP w0.127: U15.B11 v1(146.62,109.68)
  BOTTOM w0.152: v1(146.62,109.68) 145.94,110.36 145.5,110.36 143.54,112.32 143.54,112.42 143.38,112.58 RN2.2
GP4-2: length 8.1
  TOP w0.127: U15.E11 v1(146.62,107.28)
  BOTTOM w0.152: RN2.3 142.88,112.65 143.23,112.3 143.23,112.2 143.85,111.57 143.85,110.88 146.38,108.36 146.38,107.52 v1(146.62,107.28)
GP4-3: length 6
  TOP w0.127: v1(145.02,108.88) U15.C10
  BOTTOM w0.152: RN2.4 142.32,113.05 142.56,112.82 142.56,112.54 142.93,112.17 142.93,111.33 143.42,110.84 143.42,110.48 v1(145.02,108.88)
GP4-4: length 4.9
  TOP w0.127: U15.A11 v1(146.62,110.48)
  BOTTOM w0.152: RN2.1 143.94,112.36 145.68,110.62 146.04,110.62 146.18,110.48 v1(146.62,110.48)
HYPER0_LINK_CLKN: length 57.2
  TOP w0.102: v1(82.68,87.76) 82.42,88.01 82.42,90.58 82.55,90.71 U17.15 ; U23.AJ8 v4(51.98,68.56)
  L8_SIG3 w0.102: v1(82.68,87.76) 82.42,88.01 82.42,88.26 82.14,88.54 77.83,88.54 77.65,88.72 72.42,88.72 70.33,86.63 65.08,86.63 63.79,86.63 61.06,83.9 60.76,83.59 59.95,83.59 59.33,82.98 59.33,81.12 58.69,80.48 58.69,78.08 58.36,77.75 55.84,77.75 53.15,75.06 48.41,75.06 47.83,74.47 47.83,70.28 48.88,69.23 49.99,69.23 50.22,68.99 51.54,68.99 v4(51.98,68.56)
HYPER0_LINK_CLKP: length 57.2
  TOP w0.102: U17.14 82.05,90.71 82.17,90.6 82.17,87.91 82.02,87.76 v1(81.88,87.76) ; U23.AJ7 v4(51.98,69.36)
  L8_SIG3 w0.102: v1(81.88,87.76) 82.13,88.01 82.13,88.14 82.02,88.25 81.01,88.25 80.87,88.11 80.64,88.11 80.5,88.25 80.27,88.25 80.13,88.11 79.9,88.11 79.76,88.25 79.53,88.25 79.39,88.11 79.17,88.11 79.03,88.25 78.8,88.25 78.66,88.11 78.43,88.11 78.29,88.25 77.7,88.25 77.53,88.43 77.07,88.43 76.93,88.29 76.7,88.29 76.56,88.43 76.34,88.43 76.2,88.29 75.97,88.29 75.83,88.43 75.6,88.43 75.46,88.29 75.23,88.29 75.09,88.43 74.86,88.43 74.72,88.29 74.49,88.29 74.35,88.43 74.13,88.43 73.99,88.29 73.76,88.29 73.62,88.43 72.54,88.43 70.45,86.33 68.78,86.33 63.91,86.33 61.18,83.6 60.88,83.3 60.07,83.3 59.63,82.85 59.63,81 58.98,80.35 58.98,77.96 58.48,77.46 55.96,77.46 53.27,74.76 48.53,74.76 48.12,74.35 48.12,74.1 48.23,73.98 48.23,73.76 48.12,73.64 48.12,73.41 48.23,73.3 48.23,73.07 48.12,72.96 48.12,72.73 48.23,72.61 48.23,72.38 48.12,72.27 48.12,72.04 48.23,71.93 48.23,71.7 48.12,71.58 48.12,70.4 49,69.52 50.02,69.52 50.22,69.73 51.61,69.73 v4(51.98,69.36)
HYPERLINK0_RXFLCLK: length 39.7
  L5_SIG2 w0.107: J4.C3 14.36,92.46 26.64,92.46 35.15,83.95 37.47,83.95 v1(38.48,84.96)
  BOTTOM w0.152: R416.2 46.83,84.43 46.1,84.43 44.24,86.28 38.66,86.28 38.48,86.11 v1(38.48,84.96)
HYPERLINK0_RXFLCLK_R: length 13.8
  TOP w0.152: U23.AJ3 v4(51.98,72.56)
  BOTTOM w0.152: R416.1 46.86,82.96 47.27,82.55 47.27,81.37 51.79,76.85 51.79,74.53 51.59,74.32 51.59,73.02 51.69,72.92 51.98,72.63 v4(51.98,72.56)
HYPERLINK0_RXFLDAT: length 50.1
  TOP w0.152: U23.AE3 v4(55.18,72.56)
  L5_SIG2 w0.107: v4(55.18,72.56) 54.78,72.96 54.78,74.12 53.72,75.18 52.43,75.18 44.22,83.39 34.55,83.39 25.78,92.16 15.26,92.16 J4.D3
HYPERLINK0_RXN0: length 53.9
  TOP w0.102: v1(9.9,93.21) 9.82,93.12 arc(9.75,93.02) 9.73,92.91 9.73,92.8 arc(9.73,92.78) 9.74,92.77 9.74,92.75 arc(9.83,92.65) 9.95,92.61 25.27,92.61 arc(25.53,92.56) 25.76,92.41 25.91,92.25 arc(26.3,91.66) 26.44,90.97 26.44,89.66 arc(26.7,88.35) 27.45,87.24 27.6,87.08 27.84,86.84 32.59,82.09 arc(32.87,81.67) 32.97,81.18 32.97,79.39 arc(33.27,77.87) 34.13,76.59 35.31,75.41 arc(35.48,75.01) 35.31,74.61 34.61,73.91 arc(34.52,73.69) 34.61,73.48 arc(34.82,73.39) 35.04,73.48 35.75,74.18 arc(36.54,74.18) 36.54,73.39 35.83,72.68 arc(35.74,72.47) 35.83,72.25 35.83,72.25 arc(36.04,72.16) 36.26,72.25 36.97,72.96 arc(37.36,73.12) 37.76,72.96 39.86,70.86 arc(40.02,70.75) 40.22,70.71 42.07,70.71 arc(42.12,70.72) 42.16,70.73 42.23,70.76 arc(42.28,70.8) 42.32,70.85 42.36,70.96 arc(42.38,71.01) 42.39,71.07 42.39,71.29 arc(42.38,71.33) C111.2
  BOTTOM w0.102: J4.B4 10.07,94.1 arc(9.95,94.08) 9.84,94.01 9.83,93.99 arc(9.75,93.88) 9.73,93.74 9.73,93.51 arc(9.75,93.4) 9.82,93.3 v1(9.9,93.21)
HYPERLINK0_RXN0_C: length 7.6
  TOP w0.102: U23.AN8 48.96,67.95 arc(48.9,67.9) 48.82,67.89 47.83,67.89 arc(46.92,68.07) 46.15,68.58 44.14,70.6 arc(43.91,70.75) 43.64,70.8 43.45,70.8 arc(43.31,70.86) 43.25,71.01 C111.1
HYPERLINK0_RXN1: length 51.4
  TOP w0.102: C109.2 40.32,72.56 arc(40.31,72.52) 40.29,72.49 arc(40.26,72.47) 40.22,72.46 40.04,72.49 arc(39.9,72.55) 39.77,72.65 35.39,77.03 arc(34.88,77.72) 34.59,78.53 34.59,80.18 arc(34.22,82.06) 33.15,83.67 arc(33.13,83.68) 33.11,83.7 29.06,87.75 arc(27.99,89.36) 27.61,91.26 27.61,93.42 arc(27.45,93.79) 27.08,93.95 26.84,93.95 arc(26.65,94.03) 26.57,94.22 26.57,94.25 arc(26.66,94.47) 26.87,94.56 27.05,94.56 arc(27.45,94.72) 27.61,95.12 27.61,96.71 arc(27.54,97.07) 27.33,97.38 arc(27.08,97.55) 26.79,97.61 9.95,97.61 arc(9.83,97.65) 9.74,97.75 9.74,97.77 arc(9.73,97.78) 9.73,97.8 9.73,97.91 arc(9.75,98.02) 9.82,98.12 v1(9.9,98.21)
  BOTTOM w0.102: v1(9.9,98.21) 9.82,98.3 arc(9.75,98.4) 9.73,98.51 9.73,98.74 arc(9.75,98.88) 9.83,98.99 9.84,99.01 arc(9.95,99.08) 10.07,99.1 J4.B6
HYPERLINK0_RXN1_C: length 10.8
  TOP w0.102: C109.1 41.22,72.78 arc(41.23,72.72) 41.25,72.67 arc(41.39,72.57) 41.55,72.54 43.43,72.54 arc(43.76,72.48) 44.04,72.29 44.22,72.11 46.79,69.55 arc(47.28,69.21) 47.85,69.07 arc(47.9,69.06) 47.95,69.06 48.11,69.06 arc(48.18,69.08) 48.24,69.12 48.33,69.21 arc(48.48,69.31) 48.67,69.35 49.37,69.35 arc(49.56,69.31) 49.73,69.2 49.97,68.96 U23.AM7
HYPERLINK0_RXN2: length 55.1
  TOP w0.102: v1(9.9,103.21) 9.82,103.12 arc(9.75,103.02) 9.73,102.91 9.73,102.8 arc(9.73,102.78) 9.74,102.77 9.74,102.75 arc(9.83,102.65) 9.95,102.61 25.91,102.61 arc(27.23,102.35) 28.35,101.6 arc(28.74,101.01) 28.88,100.31 28.88,92.12 arc(29.32,89.9) 30.58,88.01 33.92,84.67 arc(35.4,82.46) 35.92,79.86 arc(36.22,78.31) 37.1,77 39.32,74.78 arc(39.94,74.36) 40.66,74.22 41.72,74.22 arc(41.77,74.21) 41.82,74.2 41.96,74.12 arc(42.02,74.1) 42.09,74.09 42.18,74.09 arc(42.3,74.14) 42.35,74.26 C107.2
  BOTTOM w0.102: v1(9.9,103.21) 9.82,103.3 arc(9.75,103.4) 9.73,103.51 9.73,103.74 arc(9.75,103.88) 9.83,103.99 9.84,104.01 arc(9.95,104.08) 10.07,104.1 J4.B8
HYPERLINK0_RXN2_C: length 8.1
  TOP w0.102: U23.AN5 48.98,70.37 arc(48.89,70.31) 48.79,70.29 48.29,70.29 arc(48.07,70.31) 47.85,70.37 arc(47.64,70.48) 47.45,70.63 46.86,71.22 44.06,74.02 arc(43.83,74.18) 43.55,74.23 43.45,74.23 arc(43.31,74.29) 43.25,74.43 C107.1
HYPERLINK0_RXN3: length 56.2
  TOP w0.102: C101.2 40.32,76.45 arc(40.31,76.37) 40.29,76.3 arc(40.26,76.25) 40.22,76.21 40.04,76.1 arc(40,76.08) 39.96,76.07 39.89,76.07 arc(39.69,76.11) 39.53,76.22 38.53,77.22 arc(37.42,78.88) 37.03,80.83 37.03,81.1 arc(36.53,83.61) 35.11,85.74 32.92,87.93 arc(31.49,90.07) 30.99,92.6 30.99,101.96 arc(29.33,105.95) 25.34,107.61 9.95,107.61 arc(9.83,107.65) 9.74,107.75 9.74,107.77 arc(9.73,107.78) 9.73,107.8 9.73,107.91 arc(9.75,108.02) 9.82,108.12 v1(9.9,108.21)
  BOTTOM w0.102: v1(9.9,108.21) 9.82,108.3 arc(9.75,108.4) 9.73,108.51 9.73,108.74 arc(9.75,108.88) 9.83,108.99 9.84,109.01 arc(9.95,109.08) 10.07,109.1 J4.B10
HYPERLINK0_RXN3_C: length 11.5
  TOP w0.102: U23.AM4 49.78,71.55 arc(49.57,71.7) 49.31,71.75 48.33,71.75 arc(48.3,71.75) 48.26,71.75 48.22,71.75 arc(48.02,71.79) 47.85,71.9 arc(47.8,71.94) 47.75,71.99 46.16,73.58 arc(46.06,73.69) 45.99,73.82 45.98,73.82 arc(45.9,74.04) 45.87,74.27 arc(45.76,74.81) 45.46,75.27 45.21,75.52 arc(44.22,75.99) 43.13,76.15 41.62,76.15 arc(41.47,76.18) 41.33,76.27 arc(41.25,76.4) 41.22,76.55 C101.1
HYPERLINK0_RXP0: length 54
  TOP w0.102: v1(9.24,93.21) 9.37,93.08 arc(9.45,92.97) 9.47,92.84 9.47,92.8 arc(9.48,92.73) 9.5,92.67 9.51,92.65 arc(9.68,92.44) 9.95,92.35 25.26,92.35 arc(25.43,92.32) 25.58,92.23 25.73,92.07 arc(26.07,91.56) 26.19,90.97 26.19,89.66 arc(26.47,88.25) 27.27,87.06 32.37,81.95 arc(32.63,81.57) 32.72,81.13 32.72,79.39 arc(33.03,77.78) 33.95,76.41 35.13,75.23 arc(35.22,75.01) 35.13,74.79 34.43,74.09 arc(34.26,73.69) 34.43,73.3 arc(34.82,73.13) 35.22,73.3 35.93,74 arc(36.36,74) 36.36,73.57 35.65,72.86 arc(35.48,72.47) 35.65,72.07 35.65,72.07 arc(36.04,71.91) 36.44,72.07 37.15,72.78 arc(37.36,72.87) 37.58,72.78 39.68,70.68 arc(39.92,70.52) 40.22,70.46 41.56,70.46 arc(41.62,70.46) 41.69,70.45 arc(41.77,70.43) 41.85,70.4 arc(41.97,70.33) 42.08,70.24 C115.2
  BOTTOM w0.102: J4.A4 9.13,94.1 arc(9.25,94.08) 9.36,94.01 9.37,93.99 arc(9.45,93.88) 9.47,93.74 9.47,93.6 arc(9.44,93.45) 9.36,93.32 v1(9.24,93.21)
HYPERLINK0_RXP0_C: length 7.6
  TOP w0.102: U23.AN9 48.96,67.57 arc(48.9,67.62) 48.82,67.63 47.82,67.63 arc(46.82,67.83) 45.97,68.4 43.96,70.42 arc(43.81,70.51) 43.64,70.55 43.43,70.55 arc(43.36,70.53) 43.3,70.49 arc(43.26,70.43) 43.25,70.36 C115.1
HYPERLINK0_RXP1: length 51.4
  TOP w0.102: C110.2 40.31,71.75 ; 40.31,71.75 40.31,71.75 ; 40.31,71.75 39.59,72.47 35.21,76.85 arc(34.65,77.6) 34.35,78.49 arc(34.34,78.5) 34.34,78.51 34.34,78.51 34.34,80.12 arc(33.98,81.96) 32.93,83.52 28.88,87.57 arc(27.75,89.26) 27.36,91.26 27.36,93.42 arc(27.27,93.61) 27.08,93.69 26.84,93.69 arc(26.47,93.85) 26.31,94.22 26.31,94.25 arc(26.48,94.65) 26.87,94.81 27.05,94.81 arc(27.27,94.9) 27.36,95.12 27.36,96.71 27.36,96.71 arc(27.3,96.98) 27.15,97.2 arc(26.98,97.32) 26.79,97.35 9.95,97.35 arc(9.68,97.44) 9.51,97.65 9.5,97.67 arc(9.48,97.73) 9.47,97.8 9.47,97.84 arc(9.45,97.97) 9.37,98.08 v1(9.24,98.21)
  BOTTOM w0.102: J4.A6 9.13,99.1 arc(9.25,99.08) 9.36,99.01 9.37,98.99 arc(9.45,98.88) 9.47,98.74 9.47,98.6 arc(9.44,98.45) 9.36,98.32 v1(9.24,98.21)
HYPERLINK0_RXP1_C: length 10.8
  TOP w0.102: U23.AM8 49.97,68.16 49.73,68.4 arc(49.56,68.51) 49.37,68.55 48.6,68.55 arc(48.53,68.56) 48.46,68.6 arc(48.4,68.66) 48.33,68.7 48.08,68.8 arc(48.05,68.81) 48.03,68.81 47.87,68.81 arc(47.86,68.81) 47.85,68.81 arc(47.21,68.94) 46.66,69.31 43.91,72.07 arc(43.66,72.23) 43.37,72.29 41.4,72.29 arc(41.36,72.28) 41.33,72.27 41.3,72.26 arc(41.28,72.25) 41.27,72.23 41.23,72.19 arc(41.22,72.17) 41.22,72.15 arc(41.22,72.14) 41.22,72.14 C110.1
HYPERLINK0_RXP2: length 55.1
  TOP w0.102: C108.2 41.96,73.8 arc(41.93,73.83) 41.9,73.85 arc(41.77,73.93) 41.62,73.96 40.66,73.96 arc(39.84,74.13) 39.14,74.6 36.92,76.82 arc(35.99,78.21) 35.66,79.86 arc(35.16,82.37) 33.74,84.49 30.4,87.83 arc(29.09,89.8) 28.63,92.12 28.63,97.79 28.63,100.31 arc(28.51,100.91) 28.17,101.42 arc(27.13,102.11) 25.91,102.35 9.95,102.35 arc(9.68,102.44) 9.51,102.65 9.5,102.67 arc(9.48,102.73) 9.47,102.8 9.47,102.84 arc(9.45,102.97) 9.37,103.08 v1(9.24,103.21)
  BOTTOM w0.102: J4.A8 9.13,104.1 arc(9.25,104.08) 9.36,104.01 9.37,103.99 arc(9.45,103.88) 9.47,103.74 9.47,103.6 arc(9.44,103.45) 9.36,103.32 v1(9.24,103.21)
HYPERLINK0_RXP2_C: length 8.1
  TOP w0.102: C108.1 43.25,73.77 arc(43.26,73.85) 43.31,73.92 arc(43.38,73.96) 43.46,73.98 43.55,73.98 arc(43.73,73.94) 43.88,73.84 46.68,71.04 47.27,70.45 arc(47.5,70.27) 47.76,70.13 arc(47.81,70.12) 47.85,70.1 arc(48.07,70.05) 48.29,70.03 48.79,70.03 arc(48.89,70.01) 48.98,69.95 U23.AN6
HYPERLINK0_RXP3: length 56.2
  TOP w0.102: v1(9.24,108.21) 9.37,108.08 arc(9.45,107.97) 9.47,107.84 9.47,107.8 arc(9.48,107.73) 9.5,107.67 9.51,107.65 arc(9.68,107.44) 9.95,107.35 25.34,107.35 arc(29.15,105.77) 30.73,101.96 30.73,92.59 arc(31.26,89.98) 32.74,87.75 34.93,85.56 arc(36.3,83.52) 36.78,81.1 36.78,80.83 arc(37.19,78.78) 38.35,77.04 39.69,75.7 arc(39.98,75.51) C104.2
  BOTTOM w0.102: J4.A10 9.13,109.1 arc(9.25,109.08) 9.36,109.01 9.37,108.99 arc(9.45,108.88) 9.47,108.74 9.47,108.6 arc(9.44,108.45) 9.36,108.32 v1(9.24,108.21)
HYPERLINK0_RXP3_C: length 11.5
  TOP w0.102: U23.AM5 49.83,70.71 arc(49.58,70.88) 49.28,70.95 arc(49.27,70.95) 49.25,70.95 48.71,70.95 arc(48.45,71) 48.24,71.14 47.85,71.53 45.98,73.4 arc(45.86,73.54) 45.76,73.7 arc(45.65,73.97) 45.62,74.27 arc(45.53,74.71) 45.28,75.09 45.05,75.32 arc(44.14,75.75) 43.13,75.9 41.67,75.9 arc(41.35,75.76) C104.1
HYPERLINK0_RXPMCLK: length 52.4
  TOP w0.152: U23.AE1 v4(55.18,74.16)
  L5_SIG2 w0.107: v4(55.18,74.16) 55.18,74.94 54.4,75.72 52.32,75.72 44.32,83.72 41.38,83.72 39.95,85.14 39.95,85.8 39.45,86.31 35.48,86.31 26.77,95.02 15.06,95.02 13.84,96.24 13.84,96.26 J4.C5
HYPERLINK0_RXPMDAT: length 53.3
  TOP w0.152: U23.AD1 v4(55.98,74.16)
  L5_SIG2 w0.107: J4.D5 15.26,97.16 25.5,97.16 35.74,86.92 41.07,86.92 41.81,86.18 41.81,85.92 43.4,84.33 44.57,84.33 46.3,82.6 48.13,82.6 48.46,82.27 48.46,80.44 52.58,76.33 54.69,76.33 55.98,75.04 v4(55.98,74.16)
HYPERLINK0_TXFLCLK: length 58
  TOP w0.152: U23.AC6 v4(56.78,70.16)
  L5_SIG2 w0.107: v4(56.78,70.16) 56.34,70.59 54.22,70.59 53.98,70.84 53.98,74.02 53.11,74.88 52.3,74.88 44.22,82.96 34.24,82.96 26.82,90.37 13.94,90.37 12.94,91.37 12.94,92.23 13.5,92.79 J4.C4
HYPERLINK0_TXFLDAT: length 58.4
  TOP w0.152: U23.AH4 v4(52.78,71.76)
  L5_SIG2 w0.107: v4(52.78,71.76) 52.38,72.16 52.38,74.35 44.07,82.65 34.11,82.65 26.75,90.02 11.3,90.02 10.87,90.45 10.87,91.82 11.18,92.13 11.2,92.13 12.94,93.88 12.94,94.33 13.27,94.66 14.14,94.66 J4.D4
HYPERLINK0_TXN0: length 62.7
  TOP w0.102: U23.AL9 v4(50.38,67.76)
  L10_SIG4 w0.102: 46.87,67.81 46.87,67.8 ; 46.87,67.8 46.87,66.69 arc(46.27,66.09) 45.67,66.69 45.67,67.81 arc(45.37,68.12) 45.06,67.81 45.06,66.69 arc(44.46,66.09) 43.87,66.69 43.87,67.81 arc(43.78,68.03) 43.56,68.12 43.08,68.12 arc(42.56,68.22) 42.13,68.51 33.76,76.88 arc(33.2,77.71) 33.01,78.69 33.01,78.81 arc(32.63,80.72) 31.54,82.34 27.6,86.28 arc(26.71,87.61) 26.4,89.18 26.4,90.1 arc(26.21,91.09) 25.65,91.92 25.36,92.21 arc(25.19,92.32) 25,92.36 9.86,92.36 arc(9.64,92.27) 9.54,92.04 9.54,91.81 arc(9.56,91.73) 9.6,91.66 9.63,91.63 arc(9.67,91.61) 9.71,91.6 J4.B3 ; 46.87,67.8 arc(46.88,67.88) 46.9,67.95 arc(46.93,68) 46.97,68.04 arc(47.07,68.11) 47.19,68.14 49.78,68.14 arc(49.98,68.1) 50.15,67.98 v4(50.38,67.76)
HYPERLINK0_TXN1: length 63.1
  TOP w0.102: U23.AK8 v4(51.18,68.56)
  L10_SIG4 w0.102: J4.B5 10.06,96.6 arc(9.93,96.63) 9.82,96.7 9.8,96.73 arc(9.7,96.86) 9.67,97.03 9.67,97.1 arc(9.74,97.28) 9.92,97.36 25.4,97.36 arc(26.4,97.16) 27.25,96.59 27.35,96.49 arc(27.61,96.11) 27.7,95.66 27.7,94.95 arc(27.61,94.73) 27.39,94.64 26.86,94.64 arc(26.26,94.05) 26.86,93.45 27.39,93.45 arc(27.61,93.36) 27.7,93.14 27.7,90.17 arc(28.11,88.09) 29.29,86.32 30.73,84.88 33.28,82.33 arc(33.92,81.37) 34.15,80.24 arc(34.52,78.37) 35.58,76.78 42.64,69.72 arc(43.01,69.48) 43.43,69.39 49.27,69.39 arc(49.56,69.36) 49.82,69.25 arc(49.88,69.21) 49.94,69.17 arc(50.1,69.05) 50.28,68.98 51.02,68.98 arc(51.07,68.97) 51.11,68.95 arc(51.16,68.87) 51.18,68.78 v4(51.18,68.56)
HYPERLINK0_TXN2: length 63.7
  TOP w0.102: U23.AL6 v4(50.38,70.16)
  L10_SIG4 w0.102: J4.B7 10.15,101.55 9.86,101.55 arc(9.78,101.57) 9.71,101.61 arc(9.66,101.68) 9.64,101.77 9.64,102.06 arc(9.73,102.27) 9.94,102.36 25.72,102.36 arc(26.78,102.15) 27.68,101.55 27.83,101.39 arc(28.62,100.22) 28.89,98.84 28.89,91.11 arc(29.36,88.77) 30.68,86.78 32.61,84.86 34.49,82.98 arc(35.33,81.72) 35.62,80.24 arc(35.95,78.58) 36.89,77.17 42.87,71.19 arc(43.59,70.72) 44.43,70.55 49.89,70.55 arc(50.09,70.51) 50.25,70.4 50.3,70.35 arc(50.36,70.27) v4(50.38,70.16)
HYPERLINK0_TXN3: length 68.1
  TOP w0.102: U23.AK5 v4(51.18,70.96)
  L10_SIG4 w0.102: J4.B9 9.93,106.6 arc(9.86,106.61) 9.8,106.65 arc(9.76,106.71) 9.75,106.78 9.75,107.16 arc(9.81,107.3) 9.95,107.36 25.24,107.36 arc(27.03,107) 28.55,105.99 28.65,105.89 arc(29.77,104.21) 30.16,102.23 30.16,90.3 arc(30.32,89.53) 30.76,88.87 35.59,84.04 arc(36.5,82.68) 36.82,81.08 arc(37.2,79.16) 38.29,77.53 42.87,72.95 arc(44.04,72.17) 45.41,71.89 49.56,71.89 arc(49.68,71.87) 49.78,71.8 50.05,71.53 arc(50.22,71.42) 50.42,71.38 arc(50.49,71.37) 50.57,71.37 50.92,71.37 arc(51.02,71.33) 51.11,71.27 arc(51.16,71.2) 51.18,71.11 v4(51.18,70.96)
HYPERLINK0_TXP0: length 62.7
  TOP w0.102: U23.AL8 v4(50.38,68.56)
  L10_SIG4 w0.102: J4.A3 9.04,91.6 arc(9.12,91.62) 9.19,91.66 arc(9.23,91.73) 9.25,91.81 9.25,92.14 arc(9.4,92.5) 9.76,92.65 25,92.65 arc(25.31,92.59) 25.57,92.42 25.86,92.13 arc(26.48,91.2) 26.7,90.1 26.7,89.18 arc(26.98,87.72) 27.81,86.49 31.75,82.55 arc(32.9,80.83) 33.3,78.81 33.3,78.69 arc(33.47,77.82) 33.96,77.08 42.33,68.72 arc(42.67,68.49) 43.08,68.41 43.56,68.41 arc(43.99,68.23) 44.16,67.81 44.16,66.69 arc(44.46,66.38) 44.77,66.69 44.77,67.81 arc(45.37,68.41) 45.96,67.81 45.96,66.69 arc(46.27,66.38) 46.57,66.69 46.57,67.8 arc(46.59,67.94) 46.64,68.08 arc(46.7,68.17) 46.76,68.25 arc(46.96,68.38) 47.19,68.43 50.06,68.43 arc(50.23,68.46) v4(50.38,68.56)
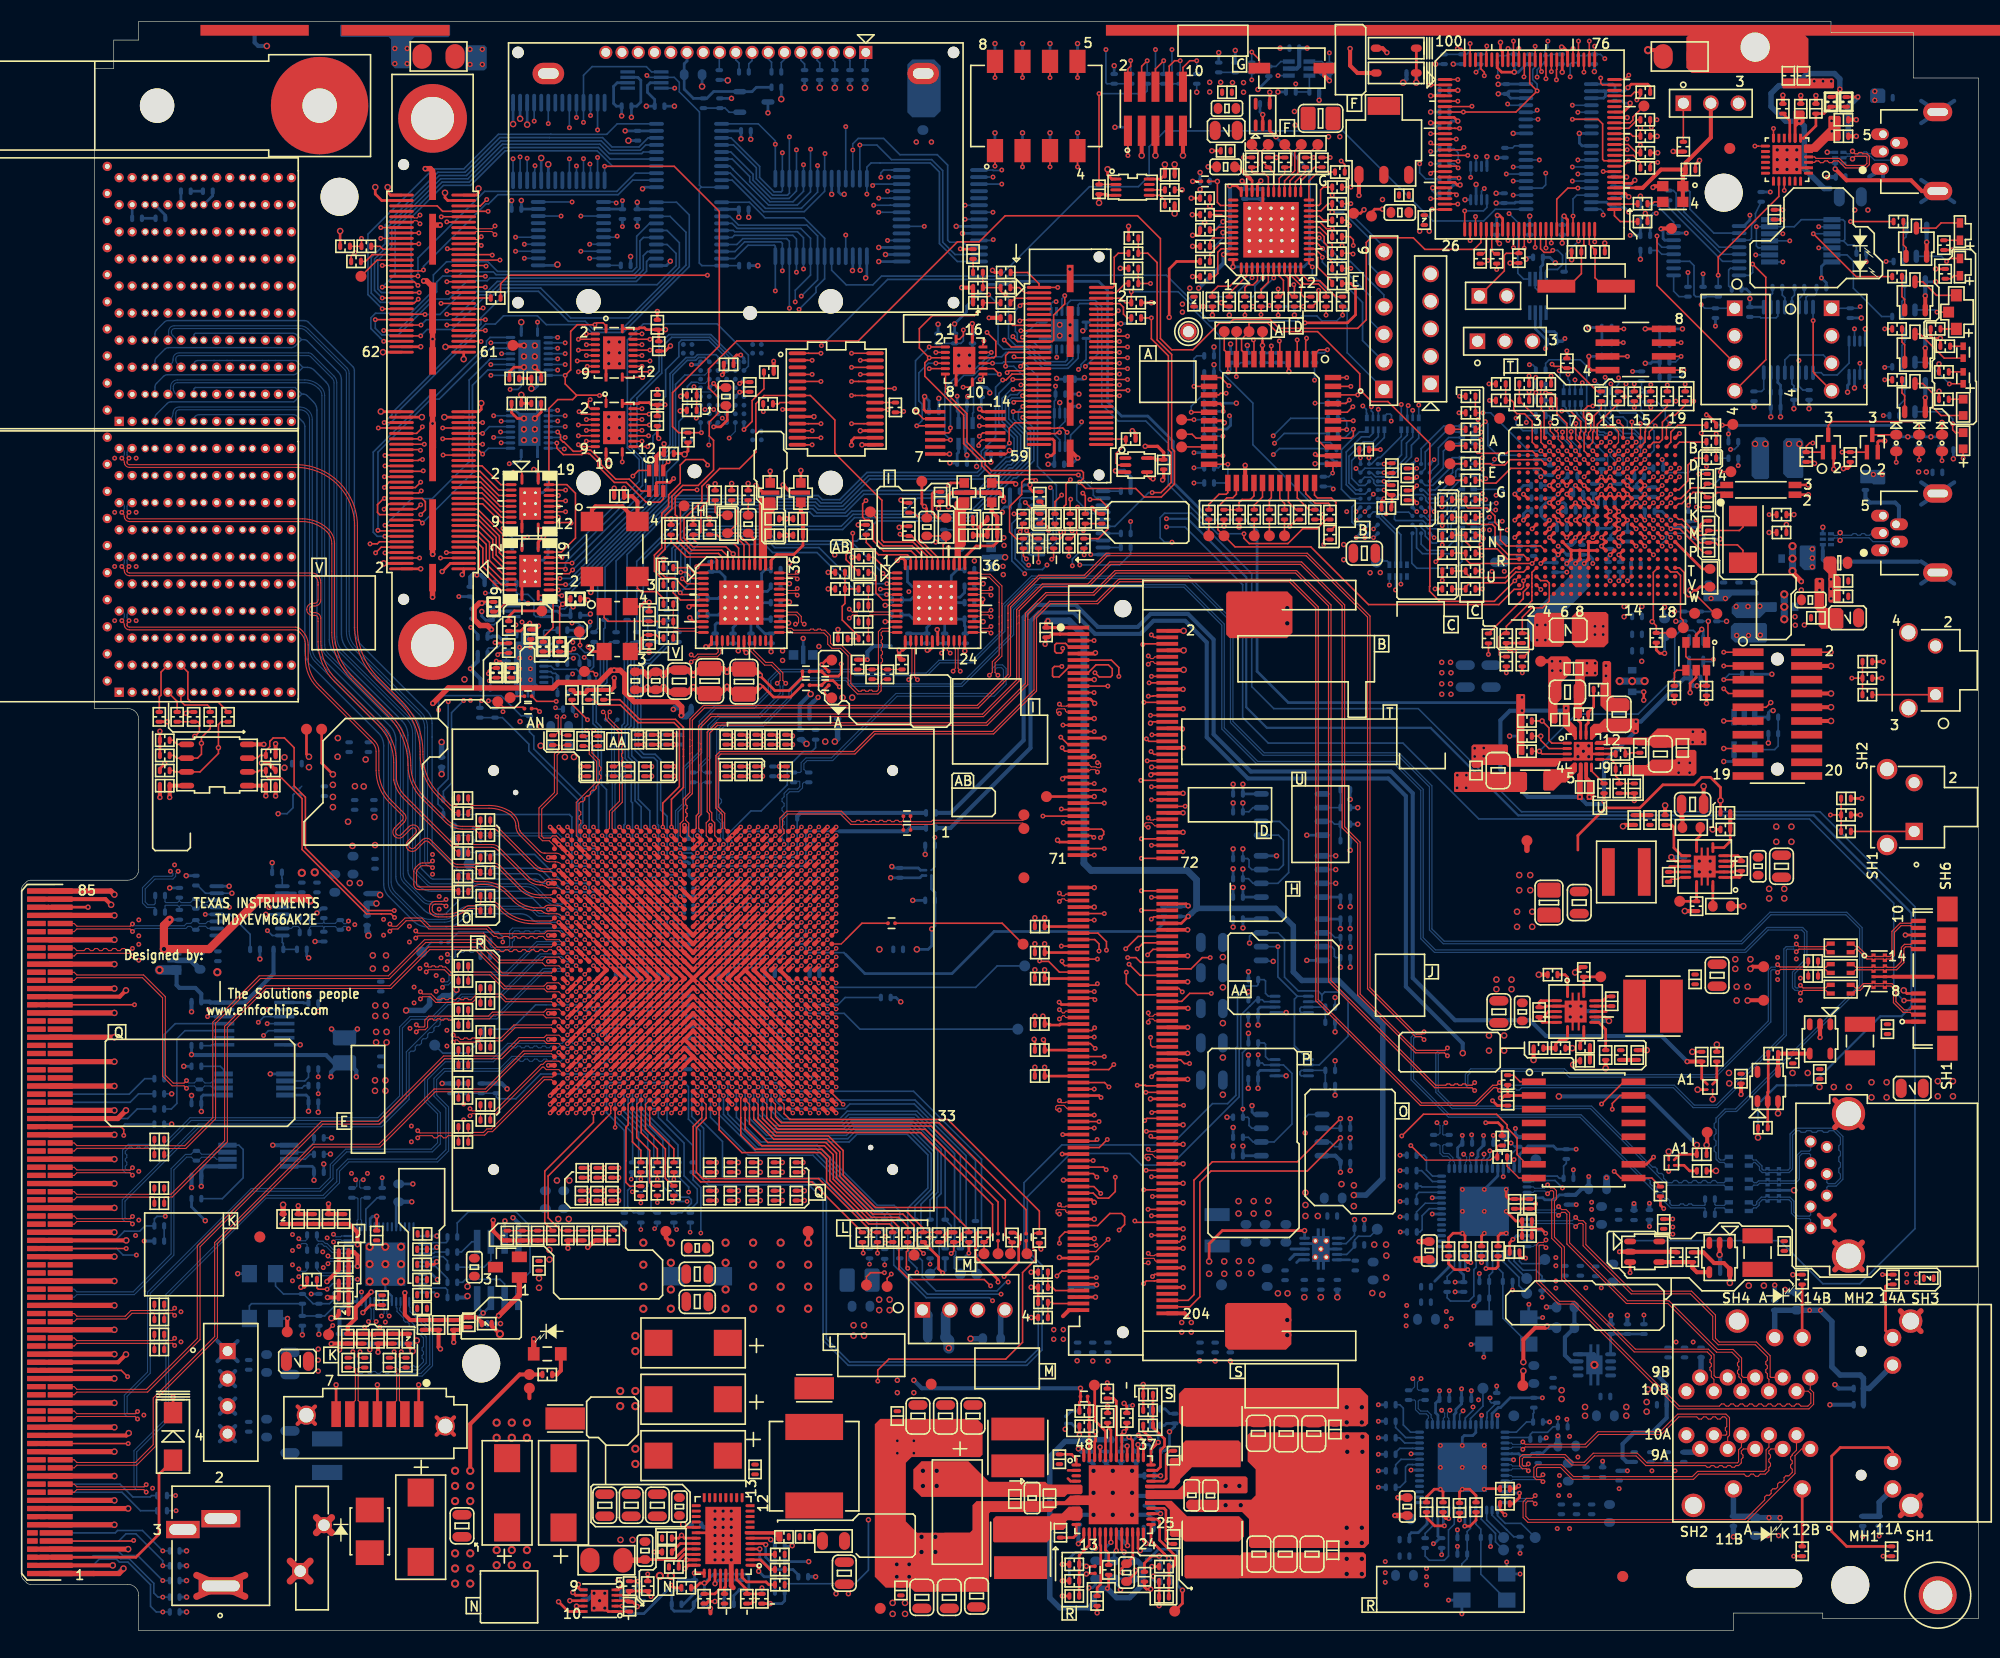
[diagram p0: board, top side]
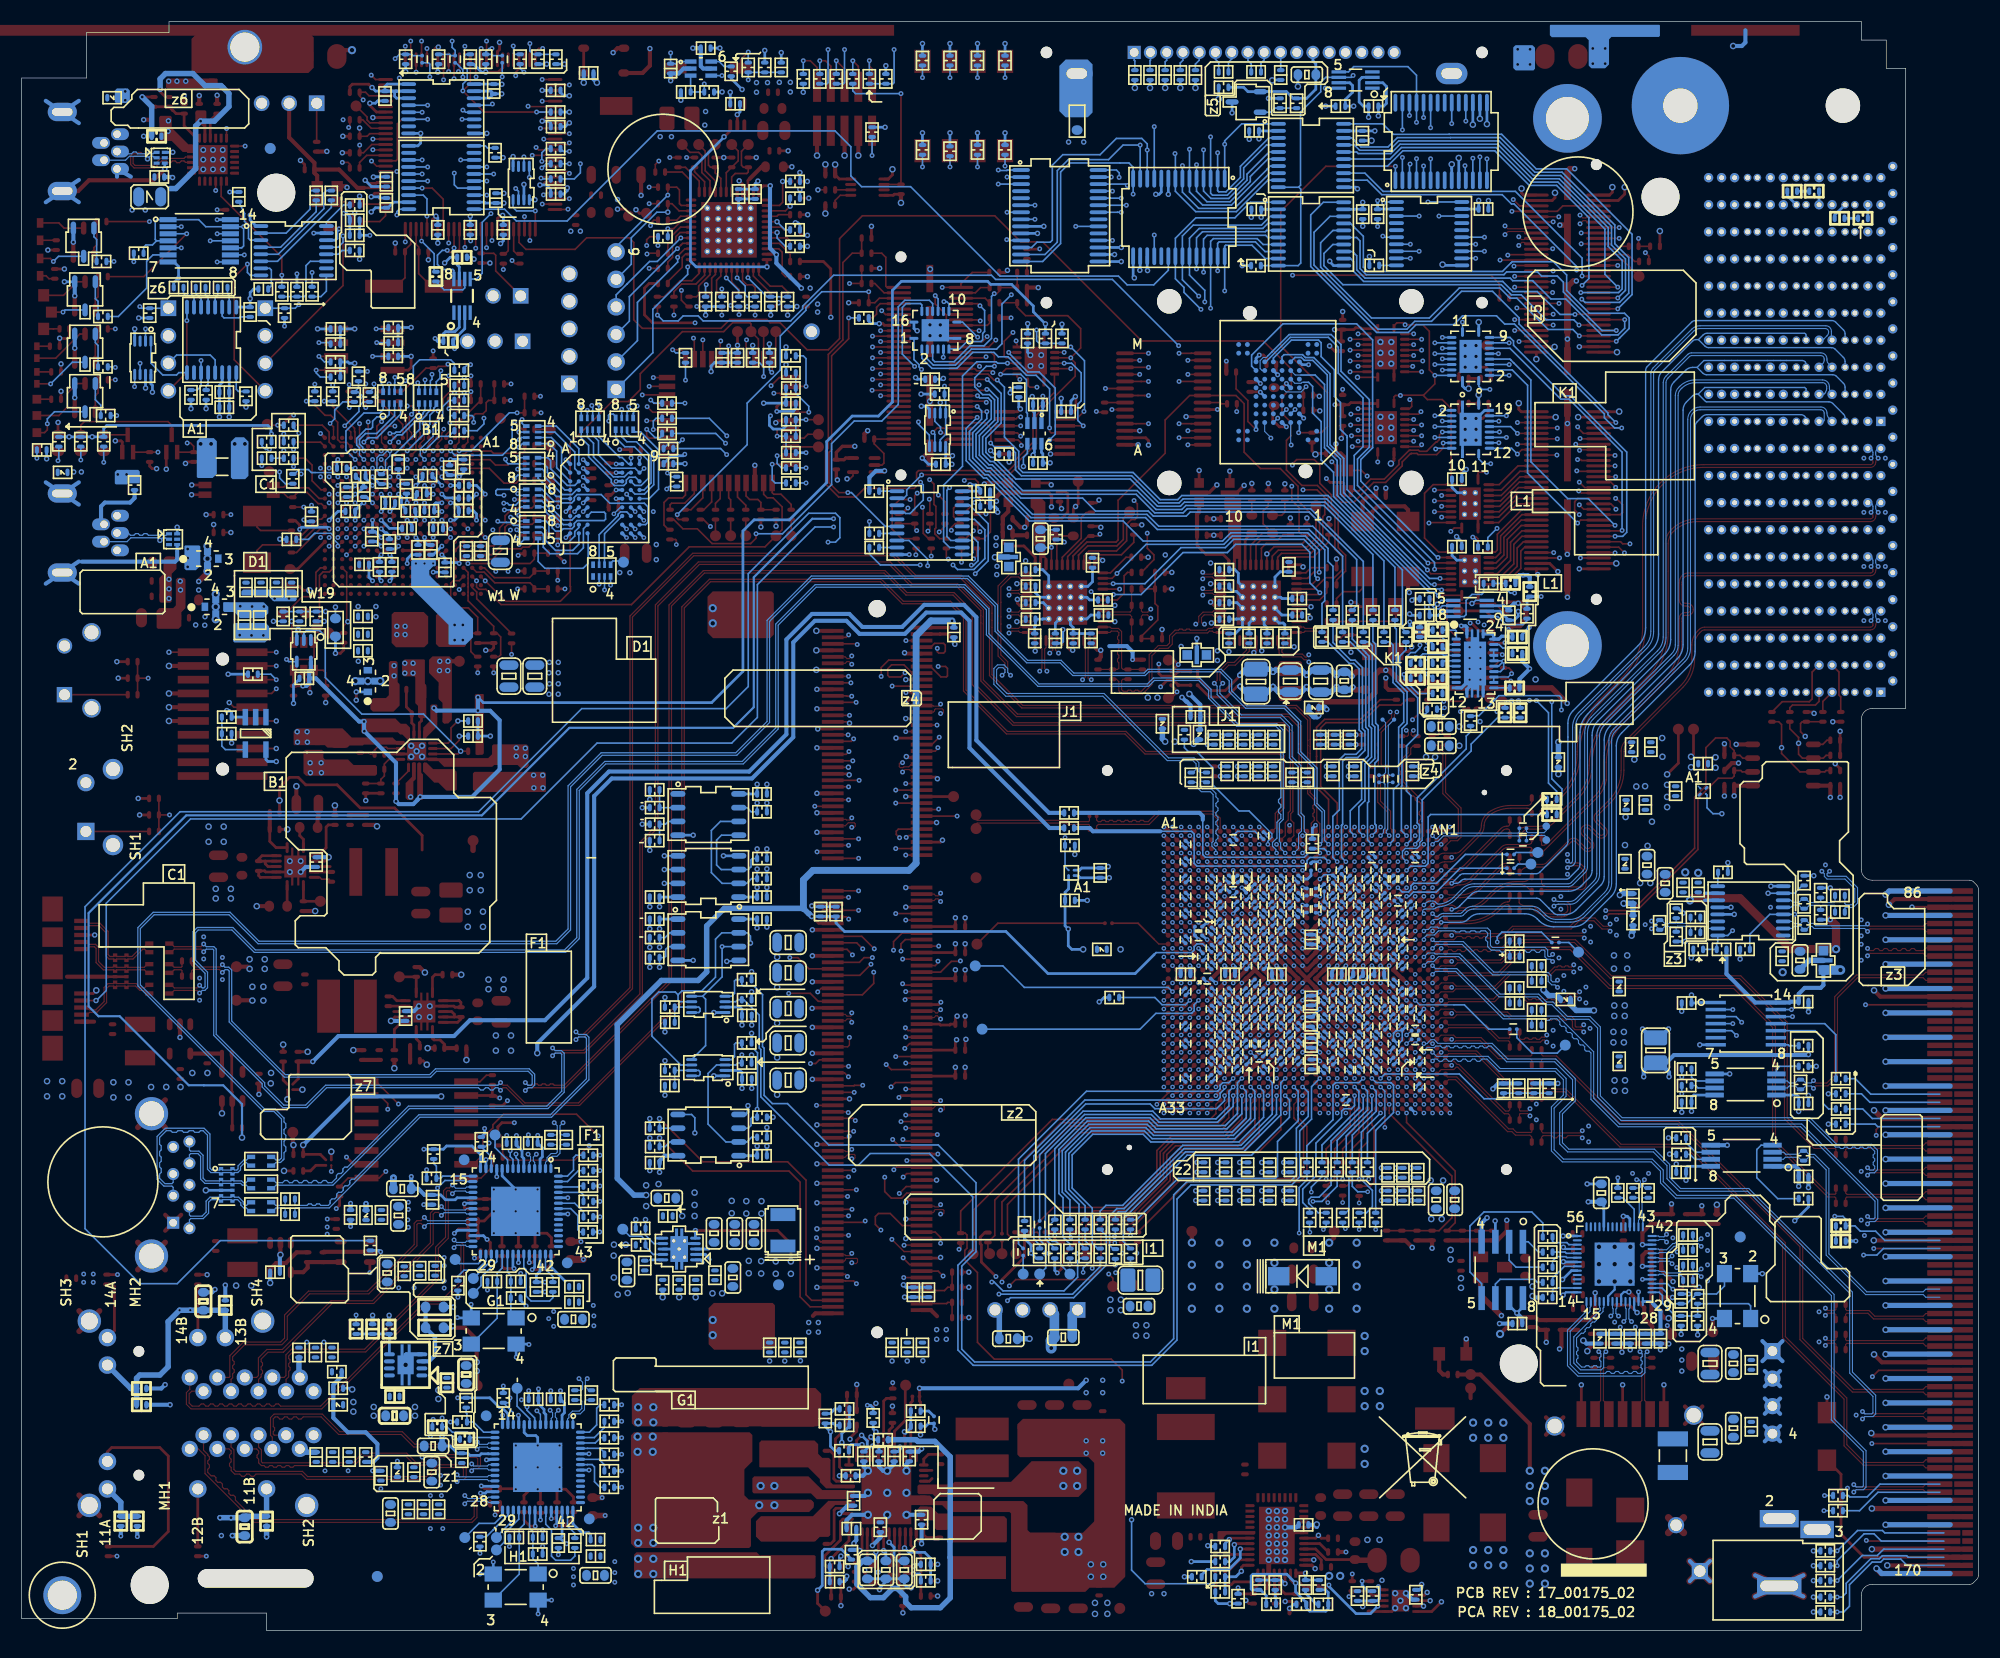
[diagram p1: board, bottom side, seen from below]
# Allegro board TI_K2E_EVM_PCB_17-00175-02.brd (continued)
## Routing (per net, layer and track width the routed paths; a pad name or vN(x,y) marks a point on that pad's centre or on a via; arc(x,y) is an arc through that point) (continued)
HYPERLINK0_TXP1: length 63.1
  TOP w0.102: U23.AK7 v4(51.18,69.36)
  L10_SIG4 w0.102: v4(51.18,69.36) 51.03,69.51 arc(50.78,69.67) 50.5,69.73 50.29,69.73 arc(50.23,69.72) 50.18,69.68 43.43,69.68 arc(43.12,69.75) 42.85,69.93 35.79,76.99 arc(34.79,78.48) 34.44,80.24 arc(34.19,81.48) 33.49,82.54 29.5,86.53 arc(28.38,88.2) 27.99,90.17 27.99,93.14 arc(27.82,93.57) 27.39,93.74 26.86,93.74 arc(26.56,94.05) 26.86,94.35 27.39,94.35 arc(27.82,94.52) 27.99,94.95 27.99,95.66 arc(27.88,96.22) 27.56,96.7 27.46,96.8 arc(26.51,97.43) 25.4,97.65 9.89,97.65 arc(9.53,97.5) 9.38,97.14 9.38,97.06 arc(9.34,96.87) 9.23,96.7 9.22,96.69 arc(9.12,96.62) J4.A5
HYPERLINK0_TXP2: length 63.7
  TOP w0.102: U23.AL5 v4(50.38,70.96)
  L10_SIG4 w0.102: J4.A7 9,101.63 arc(9,101.65) 9.02,101.67 9.2,101.85 arc(9.31,102.02) 9.35,102.21 9.35,102.33 arc(9.45,102.56) 9.68,102.65 25.72,102.65 arc(26.89,102.42) 27.89,101.75 28.04,101.6 arc(28.89,100.33) 29.18,98.84 29.18,91.11 arc(29.63,88.88) 30.89,86.99 34.69,83.19 arc(35.6,81.83) 35.92,80.24 arc(36.22,78.69) 37.1,77.38 43.08,71.4 arc(43.7,70.99) 44.43,70.84 50.19,70.84 arc(50.26,70.85) 50.32,70.89 50.38,70.95 v4(50.38,70.96)
HYPERLINK0_TXP3: length 68.1
  TOP w0.102: U23.AK4 v4(51.18,71.76)
  L10_SIG4 w0.102: v4(51.18,71.76) 51.04,71.76 arc(50.92,71.78) 50.82,71.85 arc(50.81,71.86) 50.8,71.87 50.58,72.09 arc(50.43,72.16) 50.26,72.19 45.41,72.19 arc(44.15,72.44) 43.08,73.15 38.49,77.74 arc(37.47,79.27) 37.11,81.08 arc(36.77,82.79) 35.8,84.24 30.96,89.08 arc(30.59,89.64) 30.45,90.3 30.45,102.23 arc(30.04,104.32) 28.85,106.1 28.75,106.2 arc(27.14,107.27) 25.24,107.65 9.95,107.65 arc(9.6,107.51) 9.45,107.16 9.45,107.05 arc(9.32,106.73) J4.A9
HYPERLINK0_TXPMCLK: length 43
  L5_SIG2 w0.107: J4.C6 14.06,99.66 23.93,99.66 24.26,99.33 24.26,98.95 35.99,87.22 41.2,87.22 42.21,86.21 43.23,86.21 44.25,85.19 49.25,85.19 v4(49.28,85.17)
  BOTTOM w0.152: R414.2 49.4,85.04 v4(49.28,85.17)
HYPERLINK0_TXPMCLK_R: length 18.2
  TOP w0.152: U23.AB6 v4(57.58,70.16)
  L5_SIG2 w0.107: v4(57.58,70.16) 57.18,70.56 57.18,76.23 51.18,82.22 v4(51.18,84.45)
  BOTTOM w0.152: R414.1 50.87,84.77 v4(51.18,84.45)
HYPERLINK0_TXPMDAT: length 58.9
  TOP w0.152: U23.AF5 v4(54.38,70.96)
  L5_SIG2 w0.107: v4(54.38,70.96) 54.79,71.37 54.79,71.96 54.99,72.16 55.4,72.16 55.54,72.31 55.54,75 54.52,76.02 52.45,76.02 44.45,84.02 41.5,84.02 40.26,85.27 40.26,85.93 39.57,86.61 35.61,86.61 26.9,95.33 15.18,95.33 14.14,96.37 14.14,98.54 J4.D6
IDAC_OUT: length 7.7
  TOP w0.254: v1(59.94,4.19) 60.2,3.94 R603.1 ; v1(55.42,2.24) 55.41,2.24 U35.2
  BOTTOM w0.254: v1(59.94,4.19) 59.94,4.06 57.43,1.55 56.11,1.55 v1(55.42,2.24)
JTAG_SELECT: length 24
  TOP w0.152: U7.1 86.58,119.2 86.92,119.54 v1(86.92,120.04)
  L3_SIG1 w0.107: v1(86.92,120.04) 86.92,120.85 88.75,122.68 89.53,122.68 89.73,122.89 93.03,122.89 95.12,120.8 95.12,118.82 v1(97.54,116.4)
  BOTTOM w0.152: R344.2 R343.1 86.69,118.8 86.92,119.03 v1(86.92,120.04) ; v1(97.54,116.4) 97.78,116.63 97.78,116.85 98.24,117.31 U49.1
JTAG_TCK: length 5.9
  TOP w0.152: TP5.1 118.91,136.44 118.11,136.44 117.82,136.14 117.82,134.57 117.07,133.82 U4.27
JTAG_TDI: length 5.4
  TOP w0.152: U4.29 116.07,134.02 116.59,134.54 R13.2 117.01,135.06 117.21,135.25 117.21,136.54 TP2.1
JTAG_TDO: length 5
  TOP w0.152: TP6.1 117.51,136.56 117.51,134.75 116.57,133.8 U4.28
JTAG_TMS: length 5.1
  TOP w0.152: U4.30 115.57,134.55 R14.2 114.47,135.66 114.47,136.56 TP3.1
LCD_A0: length 104.1
  TOP w0.152: v1(151,135.51) 150.47,135.51 150.31,135.35 R16.2
  L3_SIG1 w0.102: LCD1.15 56.91,146.58 57.22,146.88 88.71,146.88 90.18,145.41 109.22,145.41 109.68,144.96 129.24,144.96 129.46,145.19 145.02,145.19 146.99,143.21 146.99,138.14 147.92,137.21 148.51,137.21 150.22,135.51 v1(151,135.51)
LCD_RSTZ: length 80.3
  TOP w0.152: v1(132.51,146.02) 132.89,146.02 133.19,145.72 U1.100
  L3_SIG1 w0.102: v1(132.51,146.02) 131.43,147.11 55.82,147.11 55.41,146.7 LCD1.16
LM10011_EN: length 199.7
  TOP w0.152: U1.24 v1(132.55,131.66)
  TOP w0.254: v1(58.09,3.12) 58.12,3.12 58.12,3.15 57.78,3.48 R588.2 R276.1 56.11,3.43 55.92,3.24 U35.4
  L8_SIG3 w0.107: v1(132.55,131.66) 132.55,124.62 130.95,123.02 130.95,114.57 127,110.62 123.3,110.62 119.25,106.57 119.25,97.14 120.42,95.97 120.42,38.1 120.87,37.65 120.87,15.03 112.06,6.22 105.72,6.22 105.49,6.45 104.82,6.45 104.48,6.79 97.56,6.79 93.87,3.1 79.83,3.1 78.25,1.52 59.69,1.52 v1(58.09,3.12)
LM10011_MODE: length 4
  TOP w0.254: v1(55.37,4.04) 55.08,3.74 U35.5
  BOTTOM w0.254: v1(55.37,4.04) 55.27,3.94 55.27,2.95 55.49,2.72 R611.1 R612.2
LM10011_VID1A: length 95.5
  TOP w0.152: U23.H31 v4(69.58,49.36)
  TOP w0.254: U35.7 51.13,3.24 50.88,3.5 v2(50.88,3.51)
  L3_SIG1 w0.102: v4(69.58,49.36) 69.58,48.67 76,42.24 76,22.79 74.49,21.29 65.05,21.29 50.88,7.11 v2(50.88,3.51)
  BOTTOM w0.152: v4(69.58,49.36) 69.58,48.9 70.31,48.16 76,48.16 76.43,48.59 82.39,48.59 87.17,43.81 87.17,36.12 86.64,35.59 R536.1
LM10011_VID1B: length 95.9
  TOP w0.152: U23.H30 v4(69.58,50.16)
  TOP w0.254: v2(50.6,2.74) U35.8
  L3_SIG1 w0.102: v4(69.58,50.16) 69.85,50.16 70.29,49.73 70.53,49.73 70.74,49.51 70.74,48.47 71.09,48.13 71.33,48.13 71.61,47.85 71.61,47.15 76.23,42.53 76.23,22.7 74.59,21.06 65.46,21.06 51.79,7.39 51.79,3.53 51,2.74 v2(50.6,2.74)
  BOTTOM w0.152: v4(69.58,50.16) 69.58,49.99 69.98,49.58 69.98,49.2 70.21,48.97 70.23,48.97 70.24,48.96 82.46,48.96 88.04,43.38 R528.1
LM10011_VID1C: length 96.9
  TOP w0.127: 70.38,47.73 70.38,48.56 U23.G32
  TOP w0.152: v1(79.02,23.01) 79.02,24.03 80.04,25.04 90.83,25.04 92.38,26.59 92.38,33.03 93.55,34.2 93.55,35.08 93.34,35.28 93.34,36.5 93.52,36.67 R244.1 93.93,38.71 85.73,46.91 85.47,47.17 70.91,47.17 70.38,47.7 70.38,47.73
  TOP w0.254: U35.9 51.22,2.24 v2(51.21,2.24)
  L3_SIG1 w0.107: v1(79.02,23.01) 76.83,20.83 65.68,20.83 52.22,7.37 52.22,3.25 51.21,2.24 v2(51.21,2.24)
LM10011_VID1S: length 99.2
  TOP w0.152: U23.J31 v4(68.78,49.36)
  TOP w0.254: v2(49.56,2.64) 50.45,1.74 U35.10
  L3_SIG1 w0.102: v2(49.56,2.64) 49.56,6.17 64.9,21.51 74.4,21.51 75.77,22.89 75.77,42.16 69.14,48.78 69.14,48.99 v4(68.78,49.36)
  BOTTOM w0.152: R537.1 86.11,36.11 86.11,44.02 82.5,47.63 76.33,47.63 75.62,46.91 70.23,46.91 68.78,48.37 v4(68.78,49.36)
MAIN_POWER_GOOD: length 11.8
  TOP w0.152: v1(130.05,138.16) U1.11 ; v1(121.79,135.64) 122.12,135.31 R17.2
  L5_SIG2 w0.107: v1(121.79,135.64) 124.32,138.16 v1(130.05,138.16)
MAIN_POWER_START: length 15.9
  TOP w0.152: U1.10 132.29,138.66 132.3,138.65 v1(132.72,138.65) ; R23.1 v1(122.68,131.7)
  L5_SIG2 w0.107: v1(122.68,131.7) 124.5,131.7 128.95,136.14 131.43,136.14 132.79,137.5 132.79,138.17 132.72,138.25 v1(132.72,138.65)
MAIN_POWER_START_R: length 12
  TOP w0.152: U4.22 119.92,131.04 120.58,131.7 R23.2 120.96,130.91 v2(120.96,130.91)
  BOTTOM w0.152: CN5.5 124.33,126.11 124.33,128.55 121.97,130.91 121.01,130.91 120.96,130.96 120.96,130.91 v2(120.96,130.91)
MCU_BOOTSELECT: length 8.3
  TOP w0.152: U1.36 R38.1 137.03,127.12 136.85,126.94 136.85,125.49 CN4.1
MCU_EXP_SCL: length 83.3
  TOP w0.152: v1(137.19,128.3) U1.34
  L8_SIG3 w0.107: v2(121.72,63.07) 121.22,63.58 121.22,68.89 v2(121.28,68.96) 120.88,69.37 120.88,70.4 121.5,71.02 122.35,71.02 123.31,71.98 123.31,73.05 124.28,74.02 124.28,93.08 120.71,96.65 120.71,102.92 120.45,103.18 120.45,106.8 123.59,109.94 127.29,109.94 132.98,115.63 132.98,119.57 133.32,119.92 133.32,123.67 137.19,127.53 v1(137.19,128.3)
  BOTTOM w0.152: U66.2 120.78,64.39 121.21,63.96 R459.2 v2(121.72,63.07) ; U64.7 v2(121.28,68.96)
MCU_EXP_SDA: length 86.3
  TOP w0.152: v1(137.69,127.63) U1.35
  L8_SIG3 w0.107: v2(121.72,61.21) 121.72,61.43 123.13,62.84 123.13,67.88 121.28,69.72 v2(121.28,70.23) 121.89,70.23 123.54,71.88 123.54,72.96 124.51,73.93 124.51,93.17 120.93,96.75 120.93,104.94 120.68,105.2 120.68,105.99 121.37,106.68 121.37,106.88 124.2,109.71 127.38,109.71 133.21,115.54 133.21,119.48 133.55,119.82 133.55,123.57 137.62,127.63 v1(137.69,127.63)
  BOTTOM w0.152: U66.3 120.9,63.12 121.16,62.87 121.16,62.23 121.28,62.1 R466.2 v2(121.72,61.21) ; U64.6 v2(121.28,70.23)
MCU_JTAG_TCK: length 50.5
  TOP w0.152: R20.2 v2(107.11,132.97) ; U1.80 v1(143.19,146.02)
  L8_SIG3 w0.107: v2(107.11,132.97) 107.11,135.24 107.8,135.93 107.8,142.72 109.42,144.35 122.1,144.35 124.1,146.35 129.72,146.35 131.09,146.35 132.43,145.01 137.93,145.01 139.53,146.61 140,146.61 140.99,145.62 142.79,145.62 v1(143.19,146.02)
MCU_JTAG_TDI: length 44.4
  TOP w0.152: v1(144.2,143.84) 144.19,143.9 U1.78
  L5_SIG2 w0.107: v1(144.2,143.84) 142.94,145.09 122.38,145.09 120.9,146.57 106.81,146.57 v1(106.17,145.92)
  BOTTOM w0.152: v1(106.17,145.92) 106.17,142.88 106.28,142.77 R301.1
MCU_JTAG_TDO: length 47.3
  TOP w0.152: U1.77 v1(144.69,146.71)
  L3_SIG1 w0.102: v1(144.69,146.71) 144.69,145.98 144.13,145.41 128.56,145.41 127.41,146.57 105.29,146.57 v1(104.65,145.92)
  BOTTOM w0.152: R302.1 104.75,142.77 104.65,142.88 v1(104.65,145.92)
MCU_JTAG_TMS: length 52.4
  TOP w0.152: U1.79 v1(143.69,146.71)
  L3_SIG1 w0.102: v1(143.69,146.71) 143.69,145.98 143.35,145.64 128.66,145.64 127.51,146.79 100.95,146.79 v1(100.08,145.92)
  BOTTOM w0.152: v1(100.08,145.92) 100.08,142.88 100.18,142.77 R305.1 R304.1
MCU_PA0_U0RX: length 4.6
  TOP w0.152: U1.26 v1(133.19,131.03)
  BOTTOM w0.152: U42.5 135.24,131.35 134.92,131.03 v1(133.19,131.03)
MCU_PA1_U0TX: length 38.3
  TOP w0.152: v1(156.59,125.09) 156.59,126.77 162.19,132.37 U2.20 ; U1.27 v1(133.69,128.3)
  L5_SIG2 w0.107: v1(133.69,128.3) 133.69,127.94 134.16,127.47 134.16,126.74 136.17,124.74 156.24,124.74 v1(156.59,125.09)
  BOTTOM w0.152: R331.1 v1(156.59,125.09)
MCU_RESET_SWZ: length 14.9
  L5_SIG2 w0.107: v1(113.54,143.13) 115.37,144.96 120.04,144.96 v1(120.7,145.62)
  BOTTOM w0.152: U36.1 120,144.82 120.2,144.62 C300.1 v1(120.7,145.62) ; v1(113.54,143.13) R297.2 R298.1 C299.1
MCU_RESETSTATZ: length 59.1
  TOP w0.152: v1(76.6,113.99) 76.94,113.99 77.57,113.99 U8.22 ; v1(30.73,127.18) 30.41,126.85 R42.2
  L8_SIG3 w0.107: v1(30.73,127.18) 33.73,127.18 34.95,125.96 39.65,125.96 44.02,121.59 47.6,121.59 48.1,121.09 55.94,121.09 57.1,122.25 63.35,122.25 66.26,119.34 75.85,119.34 77.79,117.4 77.79,115.18 v1(76.6,113.99)
MCU_RESETZ: length 37.4
  TOP w0.152: v1(148.18,137.66) U1.64
  L5_SIG2 w0.107: v1(115.96,143.52) 116.27,143.83 132.6,143.83 132.99,144.22 136.17,144.22 137.74,142.65 143.2,142.65 144.51,141.33 v1(148.18,137.66)
  BOTTOM w0.152: U36.4 v1(115.96,143.52)
MCU_SPI0_CLK: length 142.3
  TOP w0.152: U8.12 71.61,110.74 v1(72.96,110.74) ; U1.28 v1(134.19,130.51) ; U18.5 60.95,95.62 v1(60.78,95.78) ; U17.5 v1(79.83,95.62)
  L10_SIG4 w0.102: v1(143.13,133.79) 140.59,131.25 134.93,131.25 v1(134.19,130.51)
  L10_SIG4 w0.107: v1(134.19,130.51) 133.16,130.51 131.8,131.87 131.8,133.28 130.21,134.87 114.87,134.87 112.55,132.55 112.55,126.03 109.91,123.39 107.24,123.39 105.61,125.02 101.96,125.02 98.36,121.41 90.68,121.41 89.76,120.5 88.48,120.5 85.56,117.58 85.56,113.6 82.2,110.23 77.2,110.23 76.69,110.74 v1(72.96,110.74) 72.58,110.36 72.58,107.56 72.73,107.41 72.73,103.9 77.42,99.21 77.42,98.63 79.29,96.76 79.29,96.63 79.83,96.09 v1(79.83,95.62)
  BOTTOM w0.152: v1(60.78,95.78) 61.7,96.7 61.7,99.52 62.43,100.25 68.55,100.25 69.31,99.49 73.41,99.49 77.28,95.62 v1(79.83,95.62) ; U41.16 v1(143.13,133.79)
MCU_SPI0_CLK_1V8: length 125
  L3_SIG1 w0.102: v1(137.67,133.79) 134.83,133.79 134.11,134.5 132.3,134.5 131.91,134.11 127.99,134.11 127.74,134.37 109.73,134.37 109.43,134.07 108.56,134.07 108.36,134.26 107.29,134.26 107.04,134.01 91.51,134.01 90.62,133.13 84.57,133.13 81.05,136.65 v1(76.71,136.65) 75.87,136.65 72.95,139.57 58.07,139.57 56.89,140.75 49.73,140.75 48.22,139.25 48.22,137.73 46.66,136.16 v1(46.66,135.89)
  BOTTOM w0.152: U43.12 87.38,127.66 86.89,128.14 85.66,128.14 85.47,128.33 85.47,135.25 84.51,136.22 81.06,136.22 79.56,137.72 77.21,137.72 76.71,137.22 v1(76.71,136.65) U44.12 ; v1(137.67,133.79) 138.05,133.79 138.05,133.79 U41.5 ; U39.12 v1(46.66,135.89)
MCU_SPI0_CS0Z: length 126
  TOP w0.152: U1.29 134.69,128.11 134.06,127.48 129.51,127.48 128.45,128.55 124.54,128.55 124.1,128.12 124.1,120.98 123.32,120.19 116.05,120.19 115.24,121.01 111.82,121.01 111.51,120.7 110.59,120.7 108.1,118.21 106.15,118.21 105.11,119.25 105.11,128.47 103,130.58 90.78,130.58 88.37,128.17 86.36,128.17 77.22,119.02 66,119.02 63.41,116.43 63.41,114.69 64.27,113.83 64.27,112.34 63.46,111.53 63.46,110.25 63.86,109.86 63.86,107.11 62.44,105.69 61.01,105.69 60.02,104.7 60.02,103.56 59.39,102.92 59.39,99.81 58.71,99.13 58.71,97.91 59.43,97.18 60.24,97.18 61.3,96.12 U18.4
MCU_SPI0_CS1Z: length 82.6
  TOP w0.152: v1(130.18,131.19) 130.21,131.16 U1.25 ; U17.4 v1(79.26,96.12)
  L10_SIG4 w0.107: v1(130.18,131.19) 129.16,131.19 126.97,129.01 120.77,129.01 117.77,126.01 114.17,126.01 111.25,123.09 107.11,123.09 105.49,124.71 102.09,124.71 99.47,122.09 99.47,120.77 97.65,118.96 92.25,118.96 91.93,119.27 91.93,119.53 91.27,120.19 88.95,120.19 88.09,119.34 88.09,113.9 80.65,106.46 80.65,103.07 81.5,102.22 81.5,96.75 79.99,95.24 79.67,95.24 79.26,95.65 v1(79.26,96.12)
MCU_SPI0_CS3Z: length 21
  TOP w0.152: U1.23 v1(130.05,132.16)
  L5_SIG2 w0.107: v1(143.13,140.79) 138.93,140.79 138.66,140.52 136.2,140.52 130.75,135.06 130.75,132.86 v1(130.05,132.16)
  BOTTOM w0.152: U38.4 v1(143.13,140.79)
MCU_SPI0_CS3Z_1V8: length 69.3
  L3_SIG1 w0.102: v1(76.06,138.81) 76.52,139.26 107.58,139.26 109.26,140.94 119.34,140.94 119.55,140.74 127.23,140.74 127.64,141.15 131.49,141.15 131.99,141.65 134.09,141.65 134.84,140.9 v1(137.15,140.9)
  BOTTOM w0.152: U38.13 137.26,140.79 v1(137.15,140.9) ; v1(76.06,138.81) U44.11
MCU_SPI0_CS4Z: length 18.5
  TOP w0.152: v1(132.44,132.51) 132.29,132.66 U1.22
  L5_SIG2 w0.102: v1(143.64,140.14) 143.45,139.95 137.34,139.95 133.86,136.47 133.86,135.86 133.27,135.28 133.27,132.83 132.95,132.51 v1(132.44,132.51)
  BOTTOM w0.152: U38.5 v1(143.64,140.14)
MCU_SPI0_CS4Z_1V8: length 109.5
  L3_SIG1 w0.102: v1(47.38,135.2) 47.1,134.92 45.21,134.92 44.6,135.53 44.6,139.14 47.44,141.98 60.9,141.98 62.56,143.64 78.84,143.64 80.16,142.32 106.84,142.32 107.68,141.48 117.5,141.48 119.58,143.56 128.96,143.56 129.31,143.21 131.57,143.21 132,142.78 134,142.78 135.45,141.33 138.88,141.33 v1(139.88,140.34)
  BOTTOM w0.152: v1(139.88,140.34) 139.83,140.34 139.63,140.14 U38.12 ; v1(47.38,135.2) U39.11
MCU_SPI0_CS5Z: length 9.1
  TOP w0.152: U1.60 146.05,135.66 145.92,135.79 145.92,139.06 145.5,139.49 v1(143.13,139.49)
  BOTTOM w0.152: U38.6 v1(143.13,139.49)
MCU_SPI0_CS5Z_1V8: length 58.3
  L10_SIG4 w0.107: v1(89.68,128.38) 100.71,139.41 116.58,139.41 116.87,139.7 119.71,139.7 120.68,140.67 131.47,140.67 132.31,139.83 132.77,139.83 133.11,139.49 v1(139.95,139.49)
  BOTTOM w0.152: U38.11 v1(139.95,139.49) ; U43.11 89.6,128.31 v1(89.68,128.38)
MCU_SPI0_CS6Z: length 99.5
  TOP w0.152: U8.11 72.62,111.39 72.62,111.39 v1(73.77,111.39) ; v1(148.31,135.64) 147.83,135.16 U1.59
  L10_SIG4 w0.107: v1(148.31,135.64) 147.55,136.4 143.18,136.4 140.92,134.14 139.32,134.14 136.92,136.54 133.32,136.54 133.25,136.47 131.59,136.47 131.27,136.14 125.93,136.14 125.6,136.47 112.59,136.47 111,134.87 111,132.18 110.15,131.33 110.15,126.32 108.29,124.46 106.6,124.46 105.74,125.32 101.84,125.32 98.23,121.72 86.51,121.72 85.25,120.47 85.25,115.05 83.47,113.26 82.75,113.26 81.47,111.98 76.33,111.98 75.74,111.39 v1(73.77,111.39)
MCU_SPI0_MISO: length 134.5
  TOP w0.152: v1(135.34,126.45) 135.05,126.17 R40.1 ; U17.3 v1(79.86,96.62) ; v1(72.96,109.44) 72.49,109.44 U8.14 ; U18.3 61.44,96.62 v1(60.98,97.08)
  L3_SIG1 w0.102: v1(135.34,126.45) 131.8,126.45 130.66,127.59 128.63,127.59 127.52,128.7 121.24,128.7 120.47,127.93 118.62,127.93 117.51,126.83 111.49,126.83 110.95,126.29 106.15,126.29 104.9,125.04 86.81,125.04 78.69,116.92 78.69,112.94 76.73,110.98 74.13,110.98 72.96,109.82 v1(72.96,109.44)
  L5_SIG2 w0.107: v1(135.34,126.45) 134.62,127.17 134.62,127.56 138.1,131.04 138.1,132.56 140.62,135.09 v1(143.13,135.09)
  L10_SIG4 w0.107: v1(72.96,109.44) 73.95,109.44 78.81,104.57 78.81,97.66 v1(79.86,96.62)
  BOTTOM w0.152: v1(60.98,97.08) 61.24,97.34 61.24,99.71 62.24,100.71 68.74,100.71 69.5,99.95 73.6,99.95 76.93,96.62 v1(79.86,96.62) ; U41.14 v1(143.13,135.09)
MCU_SPI0_MISO_1V8: length 160.2
  L3_SIG1 w0.102: v1(78.01,132.58) 76.33,134.26 59.62,134.26 56.92,136.96 47.89,136.96 47.17,136.24 47.17,135.86 46.81,135.51 45.69,135.51 v1(45.36,135.84) 45.36,136.47 47.69,138.8 47.69,139.47 49.97,141.75 65,141.75 65.18,141.93 71.6,141.93 75.92,137.61 80.85,137.61 83.78,134.67 89.72,134.67 89.96,134.43 90.62,134.43 90.91,134.71 97.86,134.71 98.58,135.43 104.61,135.43 105.29,134.75 106.89,134.75 107.98,135.84 109.88,135.84 110.47,135.25 122.56,135.25 123.29,135.99 130.46,135.99 130.69,136.22 132.87,136.22 133.4,135.69 133.83,135.69 134.43,135.09 v1(137.67,135.09)
  BOTTOM w0.152: U41.7 v1(137.67,135.09) ; v1(78.01,132.58) U44.14 78.01,135.07 78.4,135.46 79.23,135.46 83.87,135.46 84.71,134.62 84.71,128.02 86.36,126.36 88.35,126.36 U43.14 ; v1(45.36,135.84) U39.14
MCU_SPI0_MOSI: length 135
  TOP w0.152: R39.1 v1(136.14,125.62) ; v1(73.77,110.09) 72.62,110.09 72.62,110.09 U8.13 ; U18.2 61.9,97.12 61.35,97.67 v1(60.84,97.67) ; v1(79.5,97.56) 79.94,97.12 U17.2
  L3_SIG1 w0.102: v1(136.14,125.62) 132,125.62 130.49,127.13 128.52,127.13 128.51,127.14 128.45,127.14 127.35,128.24 125.06,128.24 123.18,126.36 113.43,126.36 112.43,125.36 109.41,125.36 109.3,125.48 106.48,125.48 104.19,123.19 102.11,123.19 100.49,124.81 86.91,124.81 78.94,116.85 78.94,111.2 77.88,110.14 73.82,110.14 v1(73.77,110.09)
  L5_SIG2 w0.107: v1(143.64,134.44) 143.64,133.68 139.57,129.61 139.57,128.14 139.31,127.88 139.31,127.43 139.36,127.39 139.36,125.92 139.06,125.62 v1(136.14,125.62)
  L10_SIG4 w0.107: v1(79.5,97.56) 79.88,97.94 79.88,103.98 v1(73.77,110.09)
  BOTTOM w0.152: v1(60.84,97.67) 60.84,99.73 62.12,101.01 68.87,101.01 69.63,100.25 76.81,100.25 v1(79.5,97.56) ; U41.15 v1(143.64,134.44)
MCU_SPI0_MOSI_1V8: length 125.5
  L3_SIG1 w0.102: v1(137.03,134.44) 134.65,134.44 133.7,135.38 133.36,135.38 132.75,135.99 130.78,135.99 130.56,135.76 123.39,135.76 122.66,135.03 110.37,135.03 109.79,135.61 108.2,135.61 106.91,134.32 91.28,134.32 91.16,134.2 90.61,134.2 90.19,133.78 84.35,133.78 81.02,137.11 v1(77.36,137.11) 75.97,137.11 72.49,140.59 62.03,140.59 61.1,141.51 50.06,141.51 47.92,139.37 47.92,138.39 46.01,136.48 v1(46.01,136.02)
  BOTTOM w0.152: U41.6 v1(137.03,134.44) ; U44.13 v1(77.36,137.11) 78.94,137.11 80.28,135.76 84,135.76 85.01,134.75 85.01,128.14 86.15,127.01 U43.13 ; v1(46.01,136.02) U39.13
MCU_SPI1_CLK: length 92.6
  TOP w0.152: U1.74 145.91,142.66 145.75,142.82 v1(145.75,143.3)
  L3_SIG1 w0.102: LCD1.14 58.41,146.3 58.69,146.58 88.58,146.58 90.25,144.91 98.7,144.91 99.68,143.93 107.49,143.93 108,144.43 129.3,144.43 129.66,144.08 133.53,144.08 134.16,144.7 145.07,144.7 145.75,144.03 v1(145.75,143.3)
MCU_SPI1_CS0Z: length 99.8
  TOP w0.152: v1(148.34,143.56) 147.94,143.16 U1.75
  L3_SIG1 w0.102: LCD1.17 53.91,146.72 54.53,147.34 146.29,147.34 148.34,145.29 v1(148.34,143.56)
MCU_SPI1_MOSI: length 76.9
  L3_SIG1 w0.102: LCD1.13 59.91,144.86 60.2,144.58 98.42,144.58 99.38,143.62 107.87,143.62 108.38,144.13 129.17,144.13 129.53,143.77 134.17,143.77 v1(134.24,143.84)
  BOTTOM w0.152: v1(134.24,143.84) 134.59,144.19 R290.1
MCU_SRSTN_R: length 14.4
  L5_SIG2 w0.107: v2(108.46,141.99) 109,141.45 116.66,141.45 117.59,142.39 v1(117.59,142.76)
  BOTTOM w0.152: U36.3 C313.2 R307.2 v1(117.59,142.76) ; R300.1 v2(108.46,141.99)
MCU_U0RX: length 30
  L5_SIG2 w0.107: v1(153.8,125.35) 142.8,125.35 142.69,125.24 135.99,125.24 134.39,126.84 134.39,129.77 133.74,130.42 v1(133.74,134.12)
  BOTTOM w0.152: U42.1 v1(133.74,134.12) ; R333.1 v1(153.8,125.35)
MCU_U1RX: length 2.7
  TOP w0.152: U1.66 148.34,138.66 149.12,139.45 R7.1
MCU_U1TX: length 3.5
  TOP w0.152: U1.67 148.46,139.16 148.72,139.42 148.72,139.7 TP1.1
MCU_UART0_DETECT: length 33.3
  L10_SIG4 w0.107: v1(155.02,122.38) 152.78,124.61 152.78,129.74 149.22,133.3 146.32,133.3 144.81,134.82 143.4,134.82 141.68,133.1 v1(135,133.1)
  BOTTOM w0.152: U42.6 134.74,132.84 v1(135,133.1) ; COM2.1 R360.1 155.35,122.05 v1(155.02,122.38)
MCU_UART_RX: length 3
  BOTTOM w0.152: R333.2 152.98,123.12 152.48,123.62 U47.9
MCU_UART_TX: length 7
  BOTTOM w0.152: U47.11 153.96,126.38 154.36,125.98 154.36,123.28 154.52,123.12 R332.1 R331.2
MCU_WAKEZ: length 13.8
  TOP w0.152: U1.50 v1(145.19,128.17)
  L3_SIG1 w0.102: CN6.2 145.19,127.28 v1(145.19,128.17)
MCUOSC0: length 7
  TOP w0.152: Y1.1 142.8,124.08 143.96,125.24 C17.1 143.96,127.7 144.19,127.94 U1.48
MCUOSC1: length 7
  TOP w0.152: U1.49 144.69,127.95 145.22,127.42 C16.2 145.22,124.86 146,124.08 Y1.2
MCUXOSC0: length 2.2
  TOP w0.152: R22.1 149.12,131.66 U1.52
MCUXOSC0_R: length 1.5
  TOP w0.152: OSC1.3 150.68,131.86 150.52,131.7 R22.2
MEM_A4: length 10
  BOTTOM w0.152: RN3.5 132.93,98.68 132.3,98.04 128.77,98.04 128.31,98.5 128.31,101.21 U78.J3
MEM_A5: length 6.5
  BOTTOM w0.127: 132.23,101.56 132.23,100.59 132.13,100.5
  BOTTOM w0.152: U78.J2 129.17,100.26 129.74,99.69 131.33,99.69 132.13,100.5 ; RN3.7 132.52,101.85 132.23,101.56
MEM_A6: length 8.2
  BOTTOM w0.127: 132.46,100.5 132.46,101.19 132.62,101.35 RN3.6
  BOTTOM w0.152: 132.46,100.5 132.46,99.99 131.85,99.39 129.29,99.39 128.75,99.93 128.75,101.69 U78.H3
MEM_A7: length 6.3
  BOTTOM w0.152: RN3.8 132.21,102.41 131.93,102.13 131.93,101.13 131.59,100.78 130.99,100.78 130.57,100.37 130.2,100.37 129.55,101.02 129.55,101.43 129.17,101.8 U78.H2
MEM_A8: length 4
  BOTTOM w0.152: RN4.6 132.59,104.27 131.91,103.59 131.91,103.37 130.61,102.07 U78.H1
MEM_A9: length 10.8
  BOTTOM w0.152: RN4.5 132.48,103.71 132.21,103.45 132.21,103.24 131.63,102.66 131.63,101.77 131.33,101.47 130.84,101.47 130.62,101.69 129.81,101.69 129.59,101.91 129.59,102.18 129.33,102.45 126.83,102.45 126.71,102.57 126.71,103.1 126.84,103.22 128.02,103.22 U78.G3
MEM_A10: length 13.9
  BOTTOM w0.152: U78.H9 123.02,102.07 122.78,102.31 122.78,103.7 123.13,104.05 126.31,104.05 127.11,104.85 129.33,104.85 129.59,104.58 129.59,104.31 129.67,104.24 129.83,104.08 130.75,104.08 130.89,104.21 131.06,104.21 131.06,104.22 131.45,104.22 132.56,105.33 RN4.8
MEM_A11: length 5
  BOTTOM w0.152: RN4.7 132.56,104.77 131.6,103.81 131.6,103.5 130.6,102.49 129.81,102.49 129.44,102.87 U78.G2
MEM_A12: length 1.4
  BOTTOM w0.152: TP92.1 125.17,98.71 126.03,98.71 126.24,98.5 RN9.5
MEM_BA0: length 5.2
  BOTTOM w0.152: RN9.6 126.8,101.24 U78.G7
MEM_BA1: length 6.8
  BOTTOM w0.152: RN9.7 127.3,101.14 125.55,102.9 125.55,103.03 125.33,103.25 124.75,103.25 U78.G8
MEM_CASN: length 29.9
  L8_SIG3 w0.102: v1(139.17,116.84) 137.39,115.06 137.39,114.38 135.03,112.01 134.72,112.01 134.58,112.15 134.26,112.15 132.95,110.84 132.95,110.13 130.46,107.64 128.62,107.64 128.28,107.3 127.07,107.3 126.89,107.12 126.89,104.86 126.71,104.68 126.46,104.68 126.28,104.86 126.28,107.12 126.11,107.3 125.54,107.3 125.29,107.05 125.29,103.77 125.94,103.12 v4(125.94,103.07)
  BOTTOM w0.127: U78.F7 125.34,103.67 v4(125.94,103.07)
  BOTTOM w0.152: v1(139.17,116.84) 139.45,116.84 139.76,116.53 R481.1
MEM_CKE: length 33.8
  L8_SIG3 w0.102: v4(128.77,103.27) 127.43,103.27 127.27,103.43 127.27,104.12 127.45,104.3 128.08,104.3 128.25,104.48 128.25,104.73 128.08,104.91 127.45,104.91 127.27,105.09 127.27,105.34 127.45,105.52 128.08,105.52 128.25,105.7 128.25,105.95 128.08,106.13 127.45,106.13 127.27,106.31 127.27,106.69 127.49,106.9 128.86,106.9 129.2,106.56 129.2,103.12 129.42,102.9 129.72,102.9 129.94,103.12 129.94,105.56 130.16,105.78 130.39,105.78 130.56,105.6 130.56,105.09 130.74,104.91 131,104.91 131.17,105.09 131.17,105.6 131.35,105.78 131.73,105.78 132.16,106.2 132.31,106.35 134.5,108.54 134.79,108.83 134.87,108.83 135.09,109.05 135.09,110.45 136.94,112.31 136.94,112.31 137.52,112.89 137.53,112.89 138.43,113.79 139.33,113.79 139.62,114.07 139.62,114.13 v1(139.76,114.27)
  BOTTOM w0.152: R476.1 v1(139.76,114.27)
  BOTTOM w0.254: U78.F3 v4(128.77,103.27)
MEM_CLK: length 35.6
  L8_SIG3 w0.102: v1(139.75,115.67) 140.58,116.5 141.41,116.5 141.77,116.85 141.77,118.25 142.11,118.59 142.89,118.59 143.11,118.37 143.11,115.79 142.41,115.08 139.17,115.08 135.08,110.99 134.55,110.99 133.54,109.98 133.54,109.73 133.95,109.32 133.95,109.07 133.77,108.89 133.52,108.89 133.11,109.3 132.86,109.3 132.68,109.12 132.68,108.87 133.09,108.46 133.09,108.2 132.91,108.03 132.66,108.03 132.25,108.44 132,108.44 131.82,108.26 131.82,108.01 132.23,107.59 132.23,107.34 132.05,107.16 131.8,107.16 131.39,107.57 131.13,107.57 130.95,107.4 130.95,107.14 131.37,106.73 131.37,106.48 131.19,106.3 130.93,106.3 130.52,106.71 130.27,106.71 129.57,106.01 v4(129.57,103.27)
  BOTTOM w0.152: v1(139.75,115.67) 139.75,115.67 139.79,115.67 139.76,115.65 R283.1
  BOTTOM w0.254: U78.F2 v4(129.57,103.27)
MEM_CS0N: length 38.6
  L8_SIG3 w0.102: v1(149.33,113.9) 148.69,113.26 148.69,113.26 148.06,112.63 143.62,112.63 142.29,111.3 141.53,111.3 140.7,110.47 139.29,110.47 137.43,108.61 137.43,106.67 135.6,104.83 135.6,104.19 135.32,103.91 135.03,103.91 131.6,100.49 131.6,100 131.32,99.72 124.09,99.72 123.55,100.26 123.55,102.09 v4(123.17,102.47)
  BOTTOM w0.152: v1(149.33,113.9) 149.33,114.1 149.53,114.3 R597.1 149.51,114.69 R598.1
  BOTTOM w0.254: U78.G9 v4(123.17,102.47)
MEM_D2: length 7.1
  BOTTOM w0.152: U78.B8 124.59,106.87 124.97,106.49 125.57,106.49 125.58,106.48 125.98,106.48 127.82,108.32 127.82,109.59 128.39,110.16 RN5.2
MEM_D3: length 9.4
  BOTTOM w0.152: U78.C9 123.95,106.45 124.53,106.45 124.79,106.18 124.79,105.91 125.03,105.68 125.9,105.68 126.17,105.96 126.17,106.23 128.27,108.34 128.27,109.4 128.95,110.07 RN5.1
MEM_D4: length 8.3
  BOTTOM w0.152: U78.C8 123.99,105.69 123.42,105.69 122.76,106.35 122.76,107.98 124.04,109.26 124.93,109.26 125.78,110.11 RN6.1
MEM_D5: length 7.9
  BOTTOM w0.152: U78.D9 123.15,105.27 122.51,105.91 122.51,108.37 123.85,109.72 124.74,109.72 125.22,110.2 RN6.2
MEM_D6: length 9.2
  BOTTOM w0.152: U78.D8 123.99,104.89 123.12,104.89 122.26,105.76 122.26,108.77 123.66,110.18 124.39,110.18 124.72,110.5 RN6.3
MEM_D7: length 8.9
  BOTTOM w0.152: U78.E9 122.68,104.47 121.82,105.33 121.82,108.98 123.47,110.63 123.96,110.63 RN6.4
MEM_D8: length 4
  BOTTOM w0.152: U78.E1 130.76,104.47 130.96,104.67 131.26,104.67 132.93,106.35 RN7.1
MEM_D9: length 5.2
  BOTTOM w0.152: RN7.2 132.55,107.19 132.36,107.01 132.36,106.52 130.69,104.85 129.81,104.85 129.39,105.27 U78.D2
MEM_D10: length 4.2
  BOTTOM w0.152: RN7.3 132.42,107.69 132.08,107.34 132.08,106.88 130.47,105.27 U78.D1
MEM_D11: length 5.4
  BOTTOM w0.152: RN7.4 132.05,108.25 131.78,107.98 131.78,107.23 130.24,105.69 129.55,105.69 U78.C2
MEM_D12: length 5.3
  BOTTOM w0.152: RN8.1 131.92,109.56 131.22,108.85 131.22,107.32 129.97,106.07 U78.C1
MEM_D13: length 6.2
  BOTTOM w0.152: RN8.3 131.38,110.61 129.55,108.78 129.55,107.25 U78.B2
MEM_D14: length 5.2
  BOTTOM w0.152: U78.B1 130.76,107.66 130.76,109.17 131.71,110.11 RN8.2
MEM_D15: length 6
  BOTTOM w0.152: RN8.4 131.26,111.17 129.17,109.09 U78.A2
MEM_RASN: length 36.7
  L8_SIG3 w0.102: v4(123.97,103.27) 124.6,103.27 125.17,102.7 130.32,102.7 130.69,103.07 131.14,103.07 131.58,103.51 131.58,104.69 134.59,107.7 134.8,107.7 135.2,108.09 135.2,108.26 135.26,108.32 135.26,108.39 135.42,108.56 135.42,110.1 135.42,110.1 135.42,110.35 137.25,112.18 137.25,112.18 137.65,112.58 137.65,112.58 138.47,113.4 139.43,113.4 140.14,114.11 140.14,114.26 140.66,114.78 144.2,114.78 144.42,115.01 144.42,116.88 144.64,117.09 147.73,117.09 148.08,116.74 v1(148.08,115.06)
  BOTTOM w0.152: R596.1 148.08,114.72 v1(148.08,115.06)
  BOTTOM w0.254: U78.F8 v4(123.97,103.27)
MEM_WE_DQM0N: length 32.3
  L3_SIG1 w0.102: v1(137.93,111.9) 137.93,111.85 137.89,111.81 137.89,108.97 137.59,108.67 136.73,108.67 136.55,108.85 136.55,109.89 136.37,110.07 136.12,110.07 135.94,109.89 135.94,108.85 135.76,108.67 134.16,108.67 133.51,108.02 133.51,107.58 133.69,107.4 134.27,107.4 134.44,107.22 134.44,106.97 134.31,106.84 131.52,106.84 131.34,106.66 131.34,106.44 131.16,106.26 130.91,106.26 130.73,106.44 130.73,106.66 130.55,106.84 130.3,106.84 130.12,106.66 130.12,106.44 129.94,106.26 129.69,106.26 129.51,106.44 129.51,106.66 129.33,106.84 128.58,106.84 128.18,107.24 127.42,107.24 127.24,107.06 127.24,105.36 127.06,105.18 126.81,105.18 126.63,105.36 126.63,107.06 126.45,107.24 125.08,107.24 124.72,106.88 124.72,104.92 v1(124.76,104.88)
  BOTTOM w0.127: v1(124.76,104.88) 124.76,104.86 U78.E8
  BOTTOM w0.152: R599.1 138.56,110.74 137.93,111.37 v1(137.93,111.9)
MEM_WE_DQM1N: length 17.7
  L5_SIG2 w0.102: v4(130.37,103.27) 130.37,104.09 130.84,104.56 130.84,109.34 133.65,112.15 134.57,112.15 134.72,112.01 135.36,112.01 135.86,111.51 v1(138.88,111.51)
  BOTTOM w0.152: R600.1 139.02,112.14 138.88,112 v1(138.88,111.51)
  BOTTOM w0.254: U78.F1 v4(130.37,103.27)
MMC_BLUE_LED: length 47.1
  TOP w0.152: U1.15 v1(133.48,136.16)
  L3_SIG1 w0.102: v1(133.48,136.16) 134.1,136.78 144.84,136.78 146.72,134.9 152.54,134.9 153.87,136.23 158.52,136.23 161.21,133.53 163.37,133.53 168.12,128.78 169.67,128.78 v1(172.09,126.36)
  BOTTOM w0.152: R328.1 v1(172.09,126.36)
MMC_ENABLE_N: length 316.1
  TOP w0.152: AMC1.41 v1(9.65,35.25)
  L10_SIG4 w0.107: v1(129.03,135.38) 129.44,135.79 131.34,135.79 131.55,135.99 132.9,135.99 135.49,133.41 140.77,133.41 143.48,136.12 146.91,136.12 147.9,135.13 149.69,135.13 151.29,133.52 151.29,133.08 164.64,119.74 164.64,114.38 169.11,109.91 169.11,88.96 169.76,88.31 169.76,83.92 167.92,82.07 167.92,60.89 159.71,52.68 159.71,43.2 147.53,31.02 146.95,31.02 136.55,20.62 134.84,20.62 132.42,18.21 129.2,18.21 126.28,15.29 96.33,15.29 93.06,12.01 70,12.01 68.2,13.82 45.83,13.82 43.78,15.86 18.52,15.86 10.19,24.2 10.19,25.71 9.65,26.24 v1(9.65,35.25)
  BOTTOM w0.152: R319.1 129.59,133.99 129.03,134.54 v1(129.03,135.38)
MMC_GA0: length 317
  TOP w0.152: AMC1.5 10.28,8.25 v1(10.34,8.31) ; U1.92 v1(137.19,146.02)
  L10_SIG4 w0.107: v1(137.19,146.02) 137.19,146.75 137.84,147.4 154.4,147.4 165.74,136.06 165.74,133.86 173.41,126.19 173.41,112.63 170.41,109.63 170.41,89.28 170.91,88.79 170.91,83.44 169.06,81.6 169.06,60.42 162.67,54.03 162.67,44.55 148.86,30.74 148.86,29.02 147.96,28.12 146.15,28.12 139.41,21.38 139.41,16.91 133.7,11.2 122.02,11.2 120.93,10.11 96.82,10.11 96.06,10.87 69.34,10.87 68.43,11.79 47.52,11.79 47.02,11.28 38.96,11.28 38.81,11.43 13.46,11.43 v1(10.34,8.31)
  BOTTOM w0.152: R289.1 137.1,145.36 137.22,145.48 R288.2 137.77,145.7 137.44,146.02 v1(137.19,146.02)
MMC_GA1: length 317.7
  TOP w0.152: U1.91 137.69,145.91 137.69,145.91 v1(137.69,146.71) ; AMC1.17 9.83,17.25 v1(9.83,17.25)
  L3_SIG1 w0.107: v1(137.69,146.71) v1(140.87,146.71)
  L10_SIG4 w0.107: v1(9.83,17.25) 14.02,13.06 39.01,13.06 39.4,12.67 67.84,12.67 69.42,11.1 93.44,11.1 93.84,11.51 107.47,11.51 108.08,10.9 120.78,10.9 121.39,11.51 131.99,11.51 138.85,18.37 138.85,21.15 146.05,28.35 146.99,28.35 147.55,28.91 147.55,29.75 161.42,43.62 161.42,53.09 168.83,60.51 168.83,81.7 170.68,83.54 170.68,88.69 170.15,89.21 170.15,109.7 172.47,112.01 172.47,122.36 165.17,129.66 165.17,136.31 154.31,147.17 139.61,147.17 139.15,146.71 v1(137.69,146.71)
  BOTTOM w0.152: v1(140.87,146.71) 140.87,146.12 140.59,145.85 R287.1 140.97,145.36 141.09,145.48 R286.2
MMC_GA2: length 311.6
  TOP w0.152: U1.90 v1(138.19,146.02) ; v1(9.78,23.42) 9.2,24 AMC1.26
  L10_SIG4 w0.107: v1(138.19,146.02) 138.19,145.62 138.73,145.08 v1(146.13,145.08) 156.07,145.08 164.72,136.43 164.72,128.19 171.13,121.77 171.13,111.35 169.88,110.1 169.88,89.17 170.45,88.6 170.45,83.63 168.61,81.79 168.61,60.61 161.19,53.19 161.19,43.71 147.32,29.85 147.32,29 146.9,28.57 145.96,28.57 130.67,13.28 126.64,13.28 125.57,12.22 110.03,12.22 109.6,11.79 93.8,11.79 93.34,11.33 69.65,11.33 67.84,13.13 42.54,13.13 41.65,14.02 19.18,14.02 v1(9.78,23.42)
  BOTTOM w0.152: R285.1 144.5,145.36 144.61,145.48 R284.2 145.73,145.48 v1(146.13,145.08)
MMC_GAPU: length 14.7
  TOP w0.152: U1.89 138.69,143.44 v1(138.66,143.41)
  L3_SIG1 w0.102: v1(136.25,143.41) 136.4,143.26 138.51,143.26 v1(138.66,143.41) 139,143.41 139.85,143.41 v1(139.88,143.38) 139.88,144.09 140.13,144.35 142.42,144.35 142.88,143.89 142.88,143.46 v1(142.93,143.41)
  BOTTOM w0.152: v1(142.93,143.41) 142.93,144.58 143.05,144.7 R285.2 ; v1(139.88,143.38) 139.88,144.06 140.52,144.7 R287.2 ; R289.2 v1(136.25,143.41)
MMC_PS_N0: length 280.2
  TOP w0.152: U1.63 148.29,137.16 149.05,136.4 R10.2 149.41,137.1 v1(149.4,137.11)
  TOP w0.254: D11.2 v2(13.97,21.55) ; AMC1.83 3.72,66.76 v2(6.12,66.76)
  L3_SIG1 w0.254: v2(6.12,66.76) 6.12,65.13 11.86,59.39 11.86,23.66 v2(13.97,21.55)
  L8_SIG3 w0.254: v1(149.4,137.11) 149.91,137.62 149.91,143.43 145.99,147.36 39.55,147.36 39.55,147.35 39.48,147.35 35.5,143.38 33.75,143.38 33.39,143.02 33.38,143.02 25.9,135.54 25.9,86.31 25.33,85.74 13.96,85.74 11.99,83.77 11.99,68.25 9.09,65.35 7.53,65.35 v2(6.12,66.76)
MMC_PS_N1: length 17.2
  TOP w0.254: AMC1.3 10.54,6.75 12.67,8.88 12.67,14.42 D11.1
MMC_RED_LED: length 29.6
  TOP w0.152: v1(148.18,136.68) 147.96,136.66 U1.62 ; R27.1 v1(168.81,130.05)
  L3_SIG1 w0.102: v1(148.18,136.68) 149.73,135.13 152.44,135.13 153.77,136.45 158.67,136.45 161.19,133.93 163.29,133.93 167.18,130.05 v1(168.81,130.05)
NAND_WPZ: length 39.1
  TOP w0.152: v1(53.81,135.15) 60.23,135.15 64.39,130.99 64.39,118.57 60.07,114.25 60.07,111.12 60.64,110.56 R99.2 v1(62.74,110.56)
  BOTTOM w0.152: v1(53.81,135.15) U39.1 ; U53.C3 62.67,110.63 v1(62.74,110.56)
Net_2019: length 0.6
  TOP w0.152: 63.58,48.96 v4(63.98,48.56)
Net_2020: length 0.6
  TOP w0.254: v4(62.39,47.77) 62.36,47.77 61.98,48.16
Net_2021: length 0.6
  TOP w0.152: 60.38,51.36 v4(59.98,50.96)
Net_2022: length 0.6
  TOP w0.152: 63.58,48.16 v4(63.98,47.76)
Net_2024: length 0.6
  TOP w0.152: 65.18,50.56 v4(65.58,50.16)
Net_2026: length 0.6
  TOP w0.152: 64.38,51.36 v4(64.78,50.96)
Net_2028: length 0.6
  TOP w0.152: 63.58,50.56 v4(63.98,50.16)
Net_2031: length 0.6
  TOP w0.152: 69.18,51.36 v4(69.58,50.96)
NETCPCLKN: length 38
  TOP w0.102: C73.1 49.23,82.62 49.52,82.91 49.52,84.23 v4(49.4,84.35) ; v1(71.59,97.67) 71.41,97.5 70.7,97.5 70.58,97.62 U18.36
  L8_SIG3 w0.102: v1(71.59,97.67) 71.43,97.51 71.23,97.51 67.94,100.8 59.56,100.8 55.36,96.6 55.36,92.53 53,90.17 53,89.77 49.87,86.64 49.87,85.24 49.59,84.96 49.59,84.53 v4(49.4,84.35)
NETCPCLKN_R: length 11.9
  TOP w0.102: U23.AN3 49.18,72.41 48.69,72.89 48.07,72.89 47.74,73.22 47.74,75.92 49.17,77.34 49.17,80.91 49.66,81.4 49.66,81.65 49.6,81.72 C73.2
NETCPCLKP: length 38
  TOP w0.102: U18.35 70.58,97.12 70.7,97.24 71.41,97.24 v1(71.59,97.06) ; v4(50.06,84.35) 49.88,84.35 49.77,84.25 49.77,82.7 49.86,82.62 C72.1
  L8_SIG3 w0.102: v4(50.06,84.35) 49.88,84.53 49.88,84.84 50.16,85.12 50.16,86.52 53.29,89.65 53.29,90.05 55.65,92.41 55.65,96.48 59.68,100.51 67.82,100.51 71.11,97.22 71.43,97.22 v1(71.59,97.06)
NETCPCLKP_R: length 11.9
  TOP w0.102: C72.2 50,81.72 49.92,81.63 49.92,81.3 49.43,80.8 49.43,77.24 48,75.81 48,73.32 48.17,73.15 48.81,73.15 49.02,73.35 49.35,73.35 49.74,72.96 U23.AM2
NOR_WPZ: length 132.2
  TOP w0.152: R453.2 150.46,41.76 NOR1.9 147.6,41.76 v1(146.99,42.37) ; U1.18 130.21,134.66 v1(130.05,134.49)
  L10_SIG4 w0.107: v1(146.99,42.37) 148.39,43.76 148.39,52.78 145.07,56.1 145.07,57.98 141.53,61.52 139.9,61.52 135.2,66.22 135.2,73.46 107.57,101.09 107.57,115.27 110.56,118.26 110.56,118.44 114.8,122.68 120.24,122.68 123.82,126.27 127.75,126.27 130.75,129.27 130.75,133.79 v1(130.05,134.49)
OSCIN: length 8.4
  TOP w0.152: Y3.2 158.88,99.69 158.37,100.2 156.55,100.2 156.35,100.4 C50.2 154.89,100.4 153.2,102.08 U15.L19
OSCOUT: length 8.3
  TOP w0.152: Y3.1 158.88,101.85 158.55,101.53 C43.2 155.26,101.09 154.74,101.09 153.27,102.57 152.93,102.57 U15.K19
OSCVSS: length 9.2
  TOP w0.127: U15.L18 v1(152.22,101.68)
  TOP w0.152: v1(152.22,101.68) 152.22,101.69 153.04,101.69 155.23,99.5 C50.1
  TOP w0.254: C43.1 155.32,102.43 154.94,102.05 v1(154.94,101.63)
  BOTTOM w0.254: v1(154.94,101.63) 154.94,101.66 154.77,101.83 152.36,101.83 v1(152.22,101.68)
PCIE0CLKN: length 121.9
  TOP w0.102: U17.21 85.55,90.78 85.43,90.66 85.43,90.49 v1(85.71,90.21)
  L8_SIG3 w0.102: v1(14.44,70.08) 14.23,69.86 14.23,69.57 14.64,69.16 17.08,69.16 17.78,69.86 20.55,69.86 24.7,74 24.7,76.8 24.61,76.89 23.01,78.49 23.01,80.67 24.98,82.64 26.7,82.64 32.45,88.39 32.45,94.48 34.49,96.52 38.35,96.52 42.02,100.19 51.94,100.19 56.14,104.39 72.53,104.39 76.5,100.42 80.33,100.42 81.66,99.09 86.11,99.09 87.09,98.11 89.38,98.11 90.28,97.2 90.28,95.23 89.7,94.64 89.18,94.64 85.45,90.91 85.45,90.47 v1(85.71,90.21)
  BOTTOM w0.102: C506.1 12.33,67.1 12.21,66.98 11.66,66.98 11.4,67.24 11.4,68.45 12.31,69.35 13.96,69.35 14.21,69.6 14.21,69.85 v1(14.44,70.08)
PCIE0CLKN_M: length 34.5
  TOP w0.102: U23.AJ18 v4(51.98,59.76)
  L10_SIG4 w0.102: v4(51.98,59.76) 51.98,59.81 51.66,60.13 50.92,60.13 50.86,60.19 50.13,60.19 49.91,60.41 49.79,60.41 49.63,60.25 49.4,60.25 49.23,60.41 49,60.41 48.84,60.25 48.61,60.25 48.44,60.41 48.22,60.41 48.05,60.25 47.82,60.25 47.66,60.41 47.43,60.41 47.26,60.25 47.03,60.25 46.87,60.41 46.64,60.41 46.48,60.25 46.25,60.25 46.08,60.41 45.85,60.41 45.69,60.25 45.46,60.25 45.3,60.41 45.07,60.41 44.9,60.25 44.67,60.25 44.51,60.41 43.34,60.41 36.77,66.98 34.2,66.98 33.33,66.12 29.37,66.12 29.1,65.85 29.1,65.46 29.3,65.27 29.95,65.27 v1(30.16,65.48)
  BOTTOM w0.102: 27.89,65.36 R450.2 ; 27.89,65.36 27.79,65.26 26.61,65.26 26.56,65.31 R452.2 ; 27.89,65.36 27.99,65.26 28.94,65.26 29.25,65.57 R455.2 29.75,65.24 29.92,65.24 v1(30.16,65.48)
PCIE0CLKP: length 121.9
  TOP w0.102: U17.20 85.05,90.78 85.18,90.66 85.18,90.49 v1(84.9,90.21)
  L8_SIG3 w0.102: v1(13.73,70.08) 13.94,69.87 13.94,69.45 14.52,68.87 17.2,68.87 17.9,69.56 20.67,69.56 24.99,73.88 24.99,76.92 23.3,78.61 23.3,80.55 25.11,82.35 26.82,82.35 32.74,88.27 32.74,94.36 34.61,96.23 38.48,96.23 42.15,99.9 52.06,99.9 56.26,104.1 72.41,104.1 76.38,100.13 80.21,100.13 81.54,98.8 85.99,98.8 86.97,97.82 89.26,97.82 89.99,97.08 89.99,95.35 89.58,94.93 89.06,94.93 85.16,91.03 85.16,90.47 v1(84.9,90.21)
  BOTTOM w0.102: C532.1 12.33,66.67 12.27,66.73 11.56,66.73 11.15,67.14 11.15,68.56 12.2,69.61 13.86,69.61 13.96,69.71 13.96,69.85 v1(13.73,70.08)
PCIE0CLKP_M: length 34.5
  TOP w0.102: U23.AJ17 v4(51.98,60.56)
  L10_SIG4 w0.102: v1(30.16,64.77) 29.95,64.97 29.18,64.97 28.81,65.34 28.81,65.97 29.25,66.41 33.21,66.41 34.08,67.27 36.89,67.27 43.46,60.71 50,60.71 50.22,60.93 50.53,60.93 51.04,60.42 51.84,60.42 v4(51.98,60.56)
  BOTTOM w0.102: 27.89,64.88 R458.2 ; 27.89,64.88 27.77,65 26.69,65 26.56,64.87 R457.2 ; 27.89,64.88 27.98,64.97 28.95,64.97 29.25,64.67 R455.1 29.72,64.98 29.95,64.98 v1(30.16,64.77)
PCIE1_RX1N: length 60.9
  TOP w0.102: U23.AN14 48.9,63.09 43.9,63.09 42.63,64.36 36.58,64.36 v1(36.37,64.57)
  L10_SIG4 w0.102: v1(25.58,35.45) 25.28,35.75 22.21,35.75 19.46,38.5 19.46,57.1 23.7,61.34 29.18,61.34 31.33,63.49 33.99,63.49 34.85,64.35 36.16,64.35 v1(36.37,64.57)
  BOTTOM w0.102: C770.2 26.35,35.6 26.24,35.71 25.85,35.71 v1(25.58,35.45)
PCIE1_RX1P: length 60.9
  TOP w0.102: U23.AN15 48.9,62.83 48.64,62.83 48.47,62.66 48.24,62.66 48.07,62.83 47.84,62.83 47.67,62.66 47.44,62.66 47.27,62.83 47.04,62.83 46.87,62.66 46.65,62.66 46.47,62.83 46.25,62.83 46.07,62.66 45.85,62.66 45.67,62.83 45.45,62.83 45.27,62.66 45.05,62.66 44.87,62.83 44.65,62.83 44.47,62.66 44.25,62.66 44.08,62.83 43.8,62.83 42.52,64.11 36.58,64.11 v1(36.37,63.91)
  L10_SIG4 w0.102: v1(36.37,63.91) 36.22,64.06 34.97,64.06 34.11,63.2 31.46,63.2 31.16,62.9 31.16,62.63 31,62.47 30.72,62.47 30.56,62.31 30.56,62.03 30.4,61.87 30.13,61.87 29.3,61.05 23.82,61.05 19.75,56.97 19.75,38.63 22.33,36.04 25.47,36.04 v1(25.58,36.16)
  BOTTOM w0.102: C769.2 26.35,36.11 26.2,35.97 25.77,35.97 v1(25.58,36.16)
PCIE1_RX2N: length 66.9
  TOP w0.102: v1(33.99,65.2) 34.19,65 34.62,65 35.38,65.76 36.93,65.76 37.69,65 43.01,65 43.69,64.31 48.24,64.31 48.5,64.57 49.57,64.57 U23.AM13
  L10_SIG4 w0.102: v1(33.99,65.2) 33.77,64.99 31.53,64.99 29.62,63.08 23.86,63.08 18.35,57.57 18.35,37.51 23,32.86 23.92,32.86 24.02,32.75 24.25,32.75 24.36,32.86 24.59,32.86 24.7,32.75 24.93,32.75 25.03,32.86 25.37,32.86 v1(25.58,32.65)
  BOTTOM w0.102: C782.2 26.35,32.78 26.24,32.89 25.82,32.89 v1(25.58,32.65)
PCIE1_RX2P: length 66.7
  TOP w0.102: v1(33.99,64.54) 34.19,64.74 34.73,64.74 35.49,65.51 36.83,65.51 37.59,64.74 42.9,64.74 43.59,64.06 43.83,64.06 43.98,63.91 44.33,63.91 44.48,64.06 44.89,64.06 45.04,63.91 45.27,63.91 45.42,64.06 45.65,64.06 45.81,63.91 46.03,63.91 46.19,64.06 46.42,64.06 46.57,63.91 46.8,63.91 46.95,64.06 47.18,64.06 47.33,63.91 47.56,63.91 47.71,64.06 48.11,64.06 48.41,63.75 49.61,63.75 49.98,63.38 U23.AM14
  L10_SIG4 w0.102: v1(25.58,33.36) 25.37,33.15 23.12,33.15 18.64,37.63 18.64,57.45 23.99,62.79 29.75,62.79 30.08,63.13 30.25,63.13 30.42,63.29 30.42,63.46 30.58,63.62 30.75,63.62 30.91,63.78 30.91,63.96 31.07,64.12 31.24,64.12 31.4,64.28 31.4,64.45 31.65,64.69 32.49,64.69 32.59,64.59 32.82,64.59 32.92,64.69 33.83,64.69 v1(33.99,64.54)
  BOTTOM w0.102: v1(25.58,33.36) 25.8,33.15 26.21,33.15 26.35,33.28 C771.2
PCIE1_TX1N: length 54.9
  L10_SIG4 w0.102: v1(38.84,59.36) 38.66,59.54 37.26,59.54 36.86,59.94 35.32,59.94 34.59,59.22 28.41,59.22 24.47,55.28 24.47,49.85 24.12,49.5 22.98,49.5 22.8,49.32 22.8,49.07 22.98,48.89 24.12,48.89 24.47,48.54 24.47,48.05 24.12,47.7 22.98,47.7 22.8,47.52 22.8,47.27 22.98,47.09 24.12,47.09 24.47,46.74 24.47,45.68 24.65,45.5 25.76,45.5 26.11,45.15 26.11,44.66 25.76,44.31 24.65,44.31 24.47,44.13 24.47,41.75 27.55,38.67 30.65,38.67 31.27,38.05 31.27,36.64 30.69,36.06 28.99,36.06 v1(28.78,35.85)
  BOTTOM w0.102: C607.2 40.32,60.36 40.21,60.46 39.8,60.46 39.7,60.36 39.7,59.91 39.37,59.59 39.07,59.59 v1(38.84,59.36) ; v1(28.78,35.85) 29.01,36.08 29.44,36.08 29.52,36.01 U75.41
PCIE1_TX1N_R: length 11.6
  TOP w0.102: U23.AL15 v4(50.38,62.96)
  BOTTOM w0.102: C607.1 41.22,60.41 41.33,60.52 44.83,60.52 47.64,63.33 50.01,63.33 v4(50.38,62.96)
PCIE1_TX1P: length 54.9
  L10_SIG4 w0.102: v1(38.84,60.02) 38.66,59.84 37.38,59.84 36.98,60.24 35.2,60.24 34.47,59.51 28.29,59.51 24.18,55.4 24.18,49.97 24,49.79 22.85,49.79 22.5,49.45 22.5,48.95 22.85,48.6 24,48.6 24.18,48.42 24.18,48.17 24,47.99 22.85,47.99 22.5,47.64 22.5,47.15 22.85,46.8 24,46.8 24.18,46.62 24.18,45.56 24.53,45.21 25.64,45.21 25.82,45.03 25.82,44.78 25.64,44.6 24.53,44.6 24.18,44.25 24.18,41.63 27.43,38.38 30.53,38.38 30.98,37.93 30.98,36.76 30.57,36.35 28.99,36.35 v1(28.78,36.56)
  BOTTOM w0.102: v1(28.78,36.56) 29.01,36.33 29.44,36.33 29.52,36.41 U75.42 ; C599.2 40.32,60.85 40.18,60.72 39.7,60.72 39.45,60.47 39.45,60.02 39.29,59.87 38.99,59.87 v1(38.84,60.02)
PCIE1_TX1P_R: length 11.5
  TOP w0.102: U23.AL14 v4(50.38,63.76)
  BOTTOM w0.102: v4(50.38,63.76) 50.2,63.58 47.53,63.58 44.72,60.77 41.3,60.77 41.22,60.85 C599.1
PCIE1_TX2N: length 60.7
  L10_SIG4 w0.102: v1(28.27,33.85) 28.06,34.06 26.42,34.06 26.14,34.34 26.14,37.34 25.76,37.72 23.01,37.72 22.1,38.63 20.63,40.1 20.63,56.87 24.29,60.53 34.01,60.53 34.19,60.7 34.19,61.77 34.61,62.2 37.89,62.2 39,61.09 40.56,61.09 40.63,61.16 40.63,61.65 40.35,61.93 39.48,61.93 v1(39.29,61.75)
  BOTTOM w0.102: v1(28.27,33.85) 28.5,34.08 29.44,34.08 29.52,34.01 U75.36 ; v1(39.29,61.75) 39.5,61.95 39.78,61.95 40.01,62.18 40.01,62.71 40.1,62.8 40.33,62.8 40.54,62.59 40.77,62.59 40.99,62.8 41.22,62.8 41.43,62.59 41.66,62.59 41.88,62.8 42.23,62.8 42.35,62.68 C585.2
PCIE1_TX2N_R: length 11.4
  TOP w0.102: U23.AK14 v4(51.18,63.76)
  BOTTOM w0.102: C585.1 43.25,62.65 43.39,62.79 43.62,62.79 43.8,62.61 44.03,62.61 44.21,62.79 44.96,62.79 45.29,63.12 45.29,63.55 45.47,63.72 45.47,63.95 45.29,64.13 45.29,64.36 45.5,64.58 45.9,64.58 46.01,64.47 46.36,64.47 46.47,64.58 46.83,64.58 46.93,64.47 47.29,64.47 47.4,64.58 47.75,64.58 47.86,64.47 48.22,64.47 48.32,64.58 49.83,64.58 49.9,64.5 50.21,64.19 50.9,64.19 51.18,63.91 v4(51.18,63.76)
PCIE1_TX2P: length 61.4
  L10_SIG4 w0.102: v1(39.29,62.41) 39.48,62.22 40.47,62.22 40.92,61.77 40.92,61.04 40.68,60.79 38.88,60.79 37.77,61.9 34.73,61.9 34.48,61.65 34.48,61.42 34.65,61.26 34.65,61.03 34.48,60.86 34.48,60.58 34.13,60.24 33.55,60.24 33.45,60.13 33.1,60.13 32.99,60.24 32.64,60.24 32.53,60.13 32.18,60.13 32.07,60.24 24.41,60.24 20.92,56.75 20.92,40.22 23.13,38.01 23.53,38.01 23.65,38.13 23.88,38.13 23.99,38.01 24.22,38.01 24.33,38.13 24.56,38.13 24.68,38.01 24.91,38.01 25.02,38.13 25.25,38.13 25.36,38.01 25.88,38.01 26.43,37.46 26.43,37.23 26.54,37.11 26.54,36.88 26.43,36.77 26.43,36.54 26.54,36.43 26.54,36.2 26.43,36.08 26.43,35.85 26.54,35.74 26.54,35.51 26.43,35.4 26.43,35.17 26.54,35.05 26.54,34.83 26.43,34.71 26.43,34.46 26.54,34.35 27.32,34.35 27.42,34.46 27.65,34.46 27.76,34.35 28.06,34.35 v1(28.27,34.56)
  BOTTOM w0.102: v1(28.27,34.56) 28.5,34.33 29.44,34.33 29.52,34.41 U75.37 ; v1(39.29,62.41) 39.5,62.2 39.67,62.2 39.75,62.28 39.75,62.81 39.99,63.06 42.23,63.06 42.35,63.18 C573.2
PCIE1_TX2P_R: length 10.7
  TOP w0.102: U23.AK13 v4(51.18,64.56)
  BOTTOM w0.102: v4(51.18,64.56) 51.04,64.7 50.76,64.7 50.53,64.93 49.93,64.93 49.83,64.83 45.3,64.83 45.03,64.57 45.03,63.22 44.86,63.05 43.35,63.05 43.25,63.15 C573.1
PCIE1CLKN: length 73.2
  TOP w0.102: U17.22 86.05,90.71 86.18,90.59 86.18,88.82 v1(85.97,88.54) ; U23.AJ15 v4(51.98,62.96)
  L8_SIG3 w0.102: v4(51.98,62.96) 51.54,63.39 50.22,63.39 49.96,63.65 49.77,63.65 46.13,67.3 46.13,75.04 47.75,76.66 52.49,76.66 56.65,80.82 56.65,83.13 58.26,84.74 58.26,85.43 60.1,87.27 60.1,90.14 60.81,90.86 62.4,90.86 63.61,89.64 63.61,88.7 64.38,87.93 65.46,87.93 66.48,88.96 70.59,88.96 71.65,90.03 76.7,90.03 76.99,90.33 78.93,90.33 79.23,90.03 81.91,90.03 82.94,89 83.22,88.72 83.95,87.99 86.02,87.99 86.16,88.14 86.16,88.35 v1(85.97,88.54)
PCIE1CLKP: length 73.2
  TOP w0.102: v1(86.63,88.54) 86.43,88.82 86.43,90.59 86.55,90.71 U17.23 ; U23.AJ14 v4(51.98,63.76)
  L8_SIG3 w0.102: v4(51.98,63.76) 51.61,64.13 50.22,64.13 50.04,63.95 49.89,63.95 49.6,64.24 49.6,64.42 49.4,64.62 49.22,64.62 49.02,64.82 49.02,65 48.83,65.19 48.65,65.19 48.45,65.39 48.45,65.57 48.25,65.77 48.07,65.77 47.87,65.97 47.87,66.15 47.68,66.34 47.5,66.34 47.3,66.54 47.3,66.72 47.1,66.92 46.92,66.92 46.42,67.42 46.42,74.92 47.87,76.37 52.61,76.37 56.95,80.7 56.95,83.01 58.55,84.62 58.55,85.31 60.39,87.15 60.39,90.02 60.93,90.56 62.28,90.56 63.32,89.52 63.32,88.58 64.26,87.64 65.58,87.64 66.61,88.67 70.71,88.67 71.77,89.74 76.82,89.74 77.11,90.04 78.81,90.04 79.11,89.74 81.79,89.74 82.45,89.08 82.93,88.6 83.83,87.7 86.14,87.7 86.46,88.02 86.46,88.37 v1(86.63,88.54)
PCIE_REF_CLK_N: length 15.1
  TOP w0.102: AMC1.81 4.84,65.25 5.09,65 10.02,65 v1(10.23,65.21)
  BOTTOM w0.102: U65.3 17.18,65.45 16.98,65.25 16.4,65.25 R456.2 15.91,65.57 15.6,65.26 15.22,65.26 15.01,65.05 10.38,65.05 v1(10.23,65.21)
PCIE_REF_CLK_P: length 15.2
  TOP w0.102: AMC1.80 4.84,64.5 5.09,64.75 10,64.75 v1(10.23,64.52)
  BOTTOM w0.102: U65.2 17.17,64.8 16.98,64.99 16.4,64.99 R456.1 15.91,64.67 15.6,64.98 15.34,64.98 15.15,64.8 10.5,64.8 v1(10.23,64.52)
PCIE_SPI_CLK: length 6
  BOTTOM w0.152: R548.2 40.7,32.13 40.98,32.41 44.14,32.41 44.58,31.97 U76.6
PCIE_SPI_CS: length 2.2
  BOTTOM w0.152: R535.2 40.59,34.92 41.54,35.87 U76.1
PCIE_SPI_DI: length 5.1
  BOTTOM w0.152: R543.2 42.67,33.53 43.31,34.16 U76.2
PCIE_SPI_DO: length 16.1
  BOTTOM w0.152: U76.5 45.85,32 46.93,33.08 46.93,37.33 45.63,38.63 41.22,38.63 40.2,37.61 R531.2
PCIECLK_MCU_PD: length 195.2
  L8_SIG3 w0.107: v1(16.95,66.1) 14.29,66.1 12.85,67.54 12.85,70.51 14.47,72.13 14.47,82.39 16.53,84.45 25.82,84.45 27.14,85.77 27.14,125.24 35.28,133.38 37.34,133.38 40.74,136.78 55.53,136.78 55.78,136.53 67.97,136.53 68.25,136.8 70.61,136.8 71.3,137.49 78.89,137.49 79.5,136.88 99.92,136.88 105.11,131.7 108.61,131.7 109.27,132.36 118.69,132.36 120.6,130.45 121.94,130.45 122.14,130.66 122.97,130.66 123.32,130.3 125.43,130.3 128.98,133.85 128.98,134.32 v1(130.05,135.38)
  BOTTOM w0.152: R464.1 21.09,64.25 19.25,66.1 U65.4 v1(16.95,66.1) ; v1(130.05,135.38) 130.05,135.34 130.09,135.38 R318.1
PCIECLK_MUX_SEL: length 225.7
  TOP w0.152: U1.76 v1(145.19,146.23)
  L8_SIG3 w0.107: v1(22.68,64.59) 22.28,64.59 19.52,61.84 11.82,61.84 11.33,61.34 10.05,61.34 9.32,62.07 9.32,65.04 12.55,68.27 12.55,70.64 14.17,72.26 14.17,82.52 16.4,84.75 25.7,84.75 26.84,85.89 26.84,125.49 35.13,133.78 37.31,133.78 40.62,137.08 53.57,137.08 55.5,139.01 71.02,139.01 72.57,140.56 96.52,140.56 99.89,143.93 108.57,143.93 109.3,144.65 121.97,144.65 123.98,146.66 131.21,146.66 132.54,145.34 137.32,145.34 137.57,145.59 137.57,146.01 138.54,146.98 140.06,146.98 140.71,146.33 141.32,146.33 141.65,146.66 143.1,146.66 143.52,146.23 v1(145.19,146.23)
  BOTTOM w0.152: v1(22.68,64.59) 23.13,64.15 U65.16 24.05,63.51 24.15,63.41 R463.1 R462.1
PCIECLK_OE: length 194.5
  L8_SIG3 w0.107: v1(130.05,136.53) 130.43,136.14 130.43,134.34 130.21,134.11 129.72,134.11 125.6,130 123.2,130 122.84,130.35 122.27,130.35 121.87,129.95 120.47,129.95 118.37,132.05 109.4,132.05 108.74,131.39 104.98,131.39 100.52,135.85 74.02,135.85 73.89,135.98 55.36,135.98 54.86,136.47 40.9,136.47 37.44,133.02 35.35,133.02 27.45,125.12 27.45,85.64 25.95,84.14 16.65,84.14 14.78,82.26 14.78,72.01 13.16,70.39 13.16,68.33 13.45,68.03 19.39,68.03 v2(19.41,68.05)
  BOTTOM w0.152: v2(19.41,68.05) U65.7 16.96,68.05 16.24,68.77 R442.1 ; R312.1 130.61,136.53 v1(130.05,136.53)
PCIECLKN_MR: length 2.2
  BOTTOM w0.102: R452.1 25.66,65.35 25.57,65.26 25.07,65.26 24.89,65.45 U65.14
PCIECLKN_R: length 6.1
  BOTTOM w0.102: 14.55,67.35 14.72,67.19 15.58,67.19 15.91,67.52 R448.2 16.24,67.52 16.55,67.21 17.12,67.21 17.31,67.4 U65.6 ; 14.55,67.35 14.39,67.19 13.31,67.19 13.23,67.27 C506.2 ; 14.55,67.35 R444.1
PCIECLKP_MR: length 2.1
  BOTTOM w0.102: R457.1 25.66,64.82 25.51,64.97 25.06,64.97 24.89,64.8 U65.15
PCIECLKP_R: length 6.1
  BOTTOM w0.102: 14.55,66.77 14.39,66.93 13.28,66.93 13.23,66.87 C532.2 ; 14.55,66.77 14.55,66.8 14.68,66.93 15.6,66.93 15.91,66.62 R448.1 16.24,66.62 16.58,66.96 17.09,66.96 17.3,66.75 U65.5 ; 14.55,66.77 R451.2
PHY1_INT#: length 156.6
  TOP w0.152: R94.1 81.32,112.44 v1(81.41,112.52)
  L10_SIG4 w0.107: v1(135.53,21.46) 136.09,21.46 137.58,22.95 137.58,30.24 138.13,30.78 138.13,34.72 138.35,34.95 138.35,61.34 133.73,65.96 133.73,73.79 110.46,97.05 94.19,97.05 93.4,96.27 90.35,96.27 89.56,97.05 88.59,97.05 86.33,94.8 82.63,94.8 82.04,94.21 78.81,94.21 75.84,97.17 75.84,99.53 72.43,102.95 72.43,107.28 72.27,107.44 72.27,111.91 73.44,113.07 80.86,113.07 v1(81.41,112.52)
  BOTTOM w0.152: v1(135.53,21.46) 135.53,21.14 135.65,21.01 R557.1 135.26,20.13 135.26,19.65 135.22,19.61 U77.12
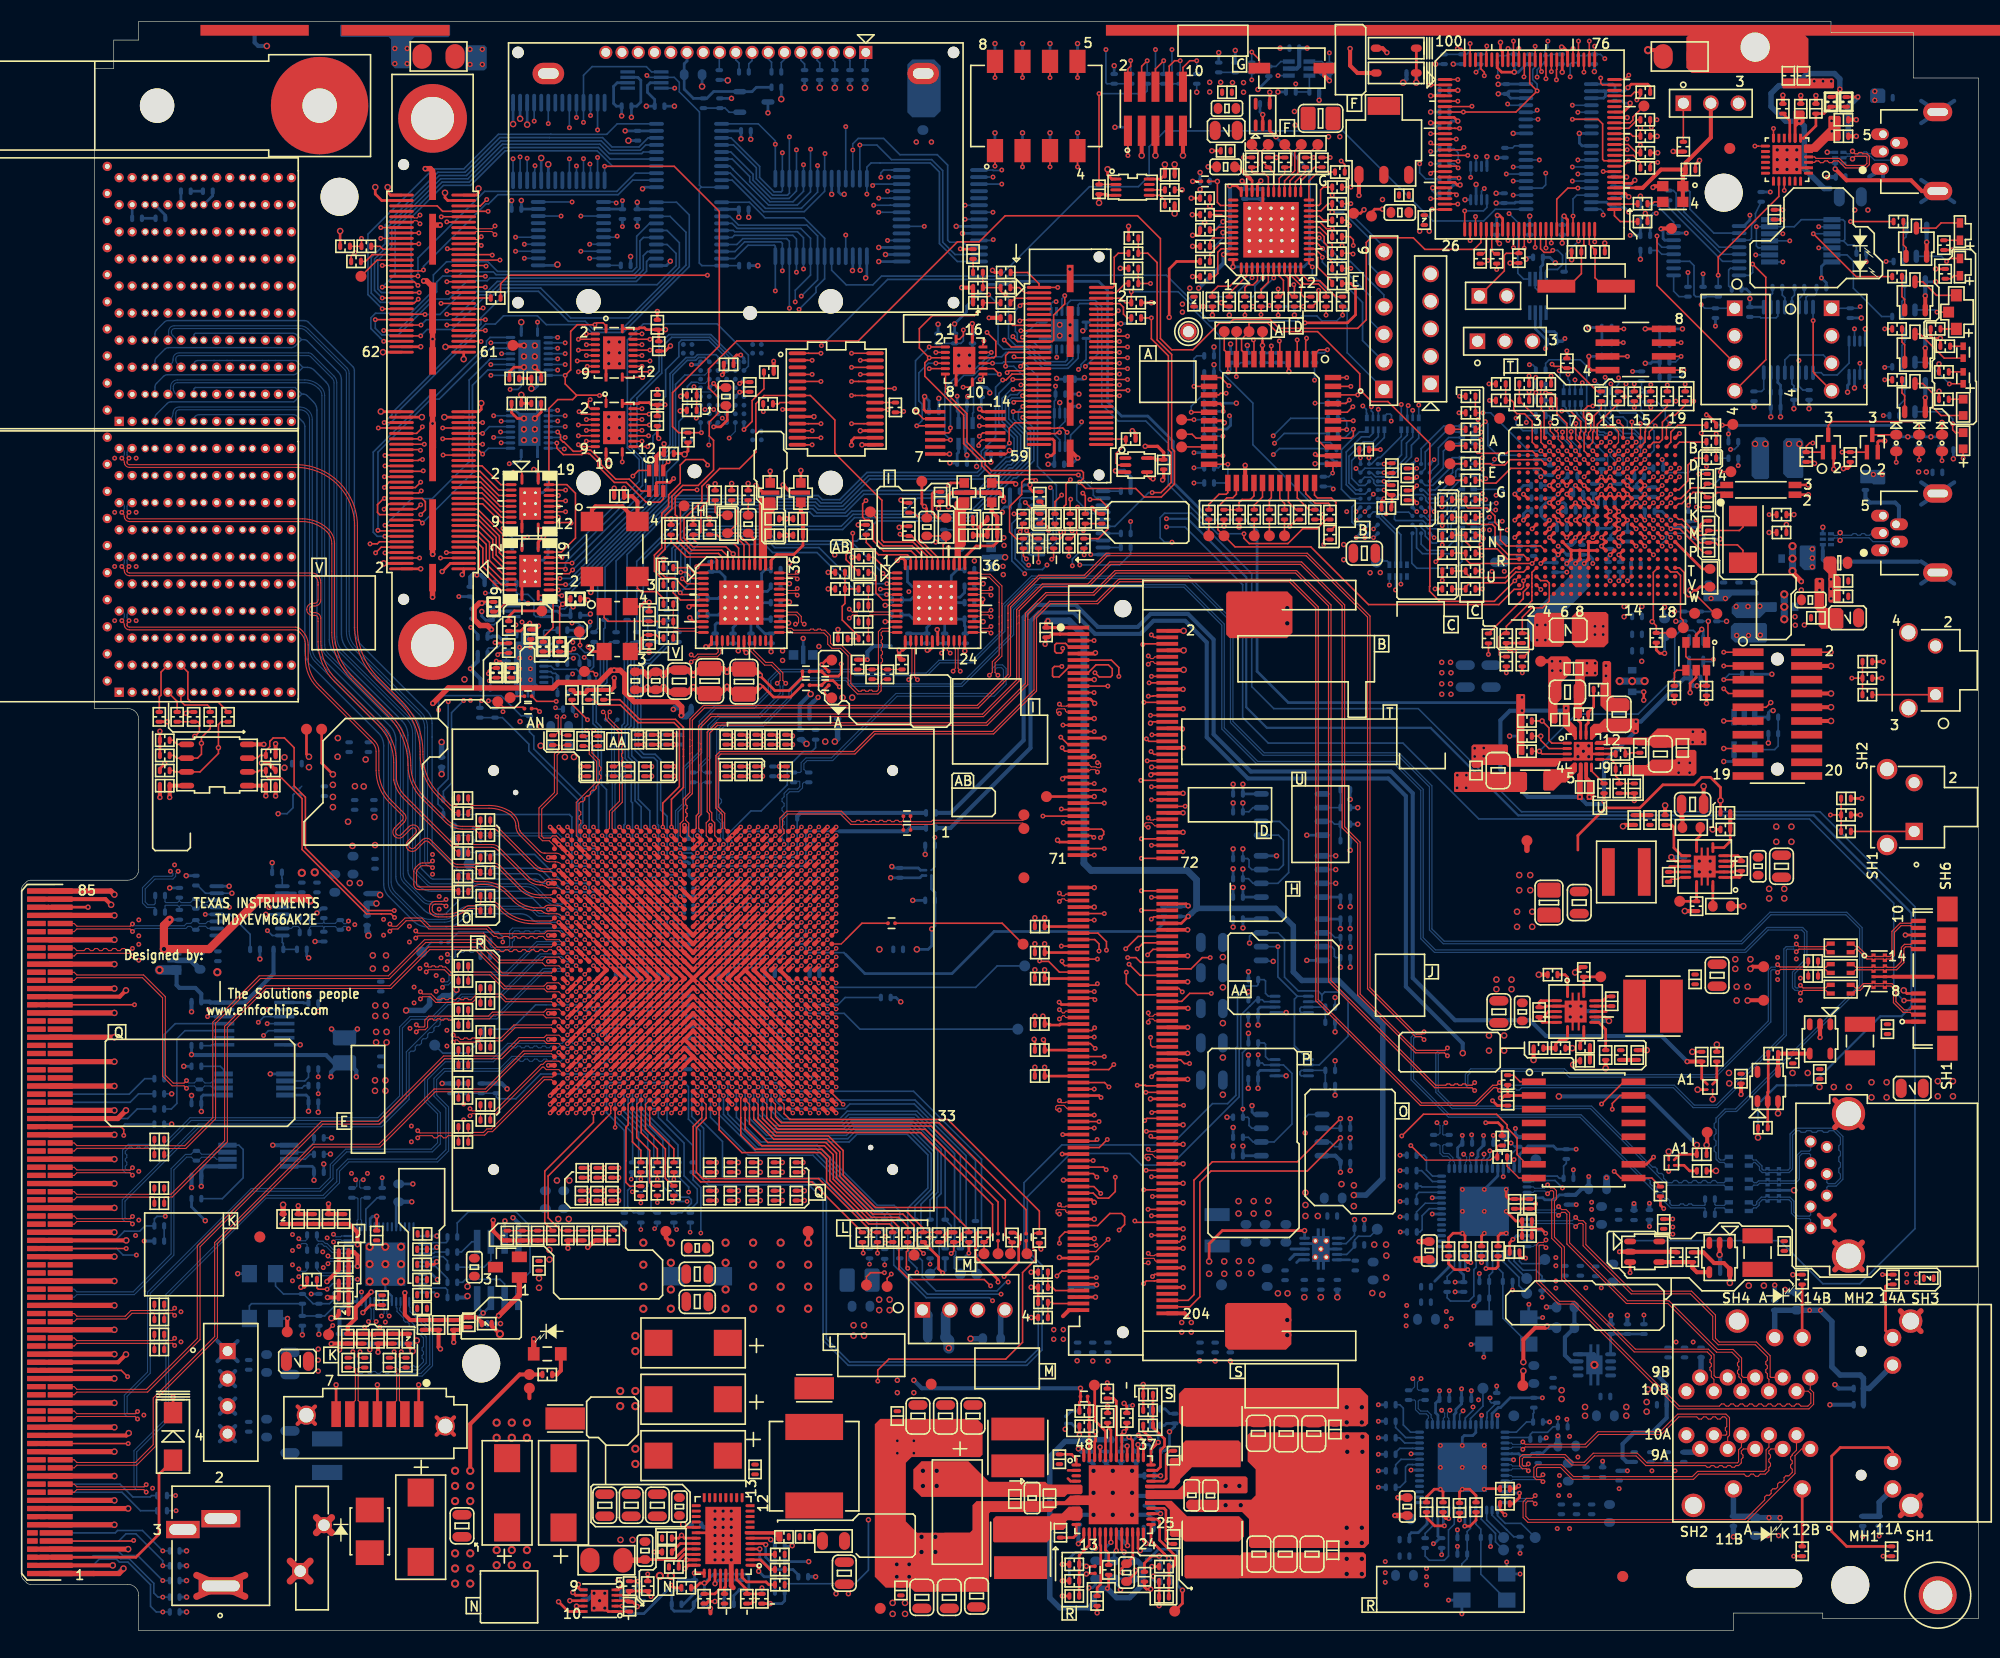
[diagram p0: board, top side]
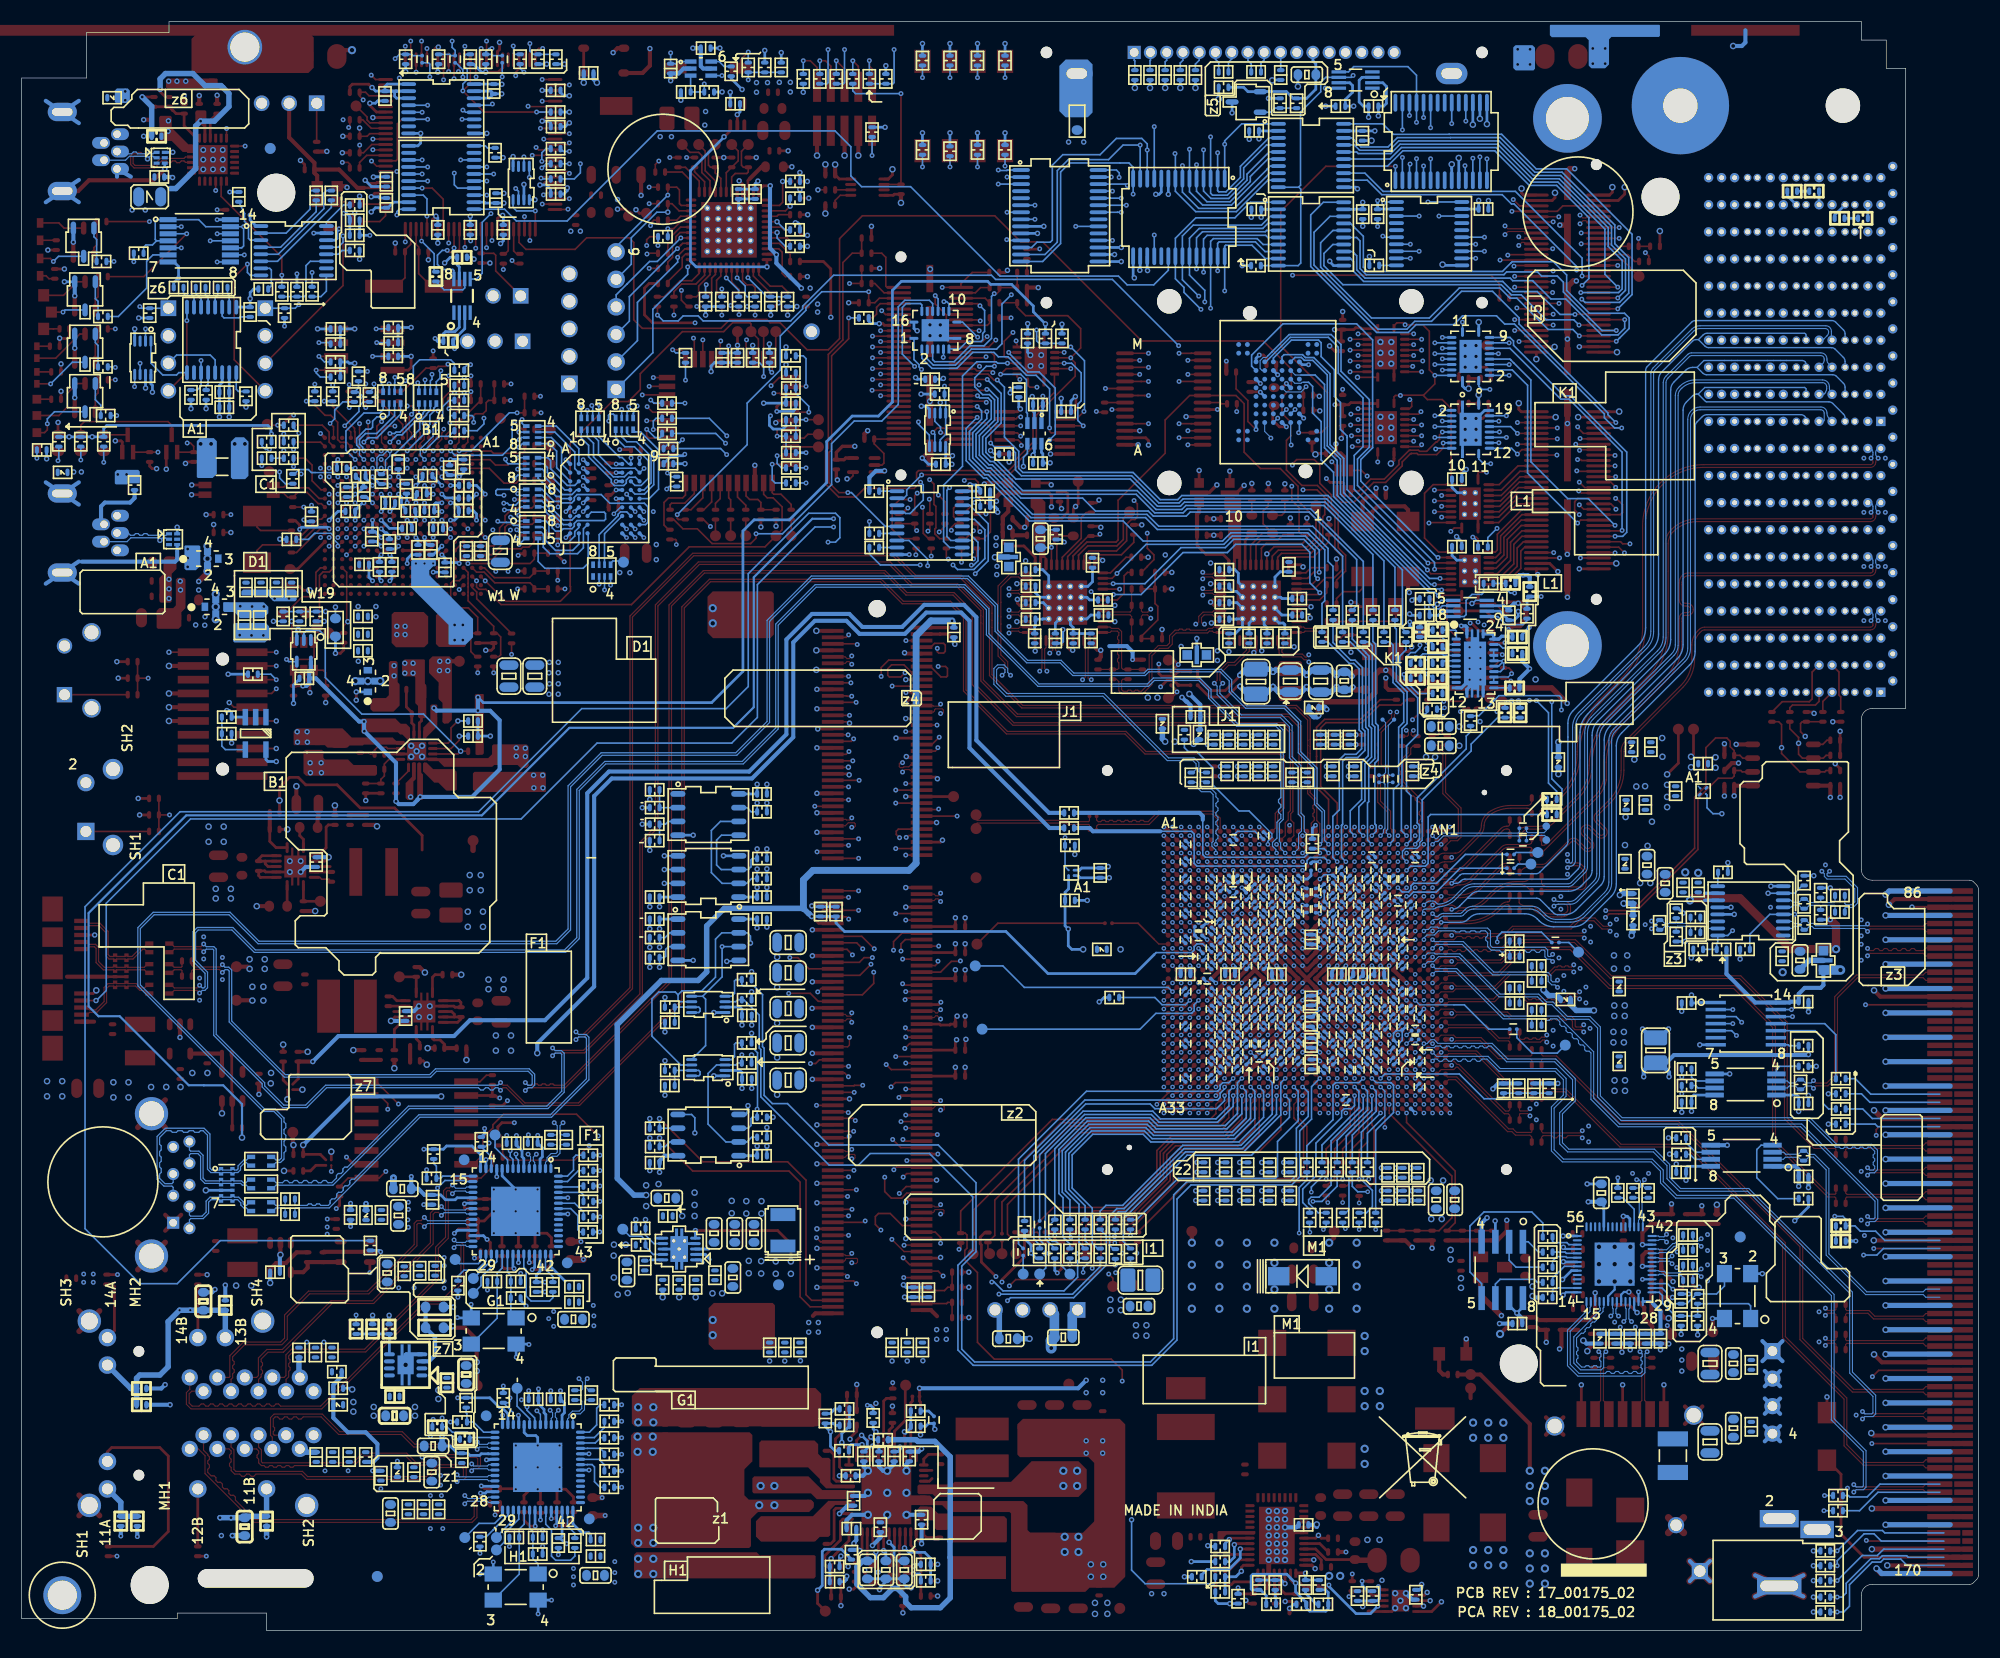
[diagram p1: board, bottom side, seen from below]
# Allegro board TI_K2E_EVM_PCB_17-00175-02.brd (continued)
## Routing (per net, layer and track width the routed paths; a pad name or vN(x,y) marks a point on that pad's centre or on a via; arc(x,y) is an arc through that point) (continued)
PHY1_LED_0: length 43.5
  TOP w0.254: R264.1 v1(171.81,6.85)
  L8_SIG3 w0.254: v1(171.81,6.85) 171.19,7.47 166.57,7.47 165.48,6.38 150.97,6.38 137.5,19.86 v1(136.22,19.86)
  BOTTOM w0.254: U77.14 v1(136.22,19.86)
PHY1_LED_1: length 43.3
  TOP w0.254: R248.1 v1(171.76,32.84)
  L8_SIG3 w0.254: v1(140.36,21.47) 142.38,23.49 146.01,23.49 153.21,30.68 169.6,30.68 v1(171.76,32.84)
  BOTTOM w0.254: v1(140.36,21.47) R558.2 137.39,21.47 136.49,20.57 136.28,20.57 135.72,20 U77.13
PHY1_MDC_2V5: length 166.9
  L8_SIG3 w0.152: v1(51.92,89.81) 52.07,89.81 53.64,91.39 53.64,97.33 57.51,101.19 68.28,101.19 69.72,99.75 71.61,99.75 76.21,95.15 81.15,95.15 v1(81.89,95.89)
  L10_SIG4 w0.152: v1(81.89,95.89) 81.89,96.54 82.93,97.59 89.64,97.59 90.63,96.6 92.79,96.6 93.57,97.38 110.52,97.38 134.14,73.76 134.14,65.91 138.61,61.45 138.61,34.87 138.38,34.65 138.38,30.68 137.87,30.17 137.87,22.68 136.25,21.06 135.36,21.06 134.73,21.69 134.06,21.69 133.05,20.68 v1(133.05,20.27)
  BOTTOM w0.127: U77.7 132.72,19.94 v1(133.05,20.27)
  BOTTOM w0.152: v1(51.92,89.81) 52.04,89.81 52.39,89.47 R636.2
PHY1_MDI0_N: length 36.2
  TOP w0.102: J9.1A 164.29,16.75 163.68,16.13 163.68,14.48 159.17,9.97 139.02,9.97 138.58,10.41 138.58,11.87 138.91,12.19 139.45,12.19 v1(139.7,12.45)
  BOTTOM w0.102: U77.27 137.49,12.3 137.61,12.18 139.43,12.18 v1(139.7,12.45)
PHY1_MDI0_P: length 36.2
  TOP w0.102: v1(139.7,11.68) 139.45,11.94 139.01,11.94 138.84,11.76 138.84,10.52 139.13,10.23 159.07,10.23 160.88,12.04 160.88,12.31 161.04,12.47 161.17,12.47 161.31,12.47 161.47,12.63 161.47,12.91 161.64,13.07 161.77,13.07 161.91,13.07 162.07,13.23 162.07,13.51 162.24,13.67 162.37,13.67 162.51,13.67 162.67,13.83 162.67,14.11 162.83,14.27 162.97,14.27 163.11,14.27 163.42,14.58 163.42,14.88 163.27,15.03 163.27,15.26 163.42,15.41 163.42,15.64 163.27,15.79 163.27,16.02 163.42,16.17 163.42,16.24 163.82,16.63 J9.2A
  BOTTOM w0.102: v1(139.7,11.68) 139.46,11.92 137.61,11.92 137.49,11.8 U77.28
PHY1_MDI1_N: length 31
  TOP w0.102: v1(140.41,14.37) 140.22,14.18 139.9,14.18 139.83,14.25 139.83,14.94 139.93,15.04 142.03,15.04 143.13,13.94 154.31,13.94 154.79,14.43 158.97,14.43 159.18,14.22 159.41,14.22 159.61,14.43 159.84,14.43 160.04,14.22 160.27,14.22 160.47,14.43 160.94,14.43 161.26,14.75 161.26,15.04 161.42,15.19 161.42,15.42 161.26,15.57 161.26,15.8 161.42,15.95 161.42,16.18 161.26,16.33 161.26,16.56 161.46,16.75 J9.3A
  BOTTOM w0.102: U77.23 137.49,14.3 137.61,14.18 140.22,14.18 v1(140.41,14.37)
PHY1_MDI1_P: length 31.1
  TOP w0.102: J9.4A 161.28,16.93 161.01,16.66 161.01,14.86 160.83,14.68 154.69,14.68 154.2,14.2 143.23,14.2 142.14,15.29 139.82,15.29 139.57,15.04 139.57,14.14 139.79,13.92 140.22,13.92 v1(140.41,13.73)
  BOTTOM w0.102: v1(140.41,13.73) 140.22,13.92 137.61,13.92 137.49,13.8 U77.24
PHY1_MDI2_N: length 28
  TOP w0.102: v1(139.06,15.37) 138.87,15.18 138.62,15.18 138.51,15.29 138.51,15.85 138.63,15.98 142.36,15.98 143.07,15.27 144.33,15.27 145.16,16.1 149.02,16.1 149.91,15.21 155.42,15.21 155.57,15.06 155.8,15.06 155.95,15.21 156.18,15.21 156.33,15.06 156.56,15.06 156.71,15.21 156.94,15.21 157.09,15.06 157.32,15.06 157.47,15.21 157.7,15.21 157.86,15.06 158.08,15.06 158.24,15.21 158.47,15.21 158.72,15.46 158.72,15.8 158.88,15.95 158.88,16.18 158.72,16.33 158.72,16.56 158.92,16.75 J9.5A
  BOTTOM w0.102: v1(139.06,15.37) 138.87,15.18 137.61,15.18 137.49,15.3 U77.21
PHY1_MDI2_P: length 28
  TOP w0.102: v1(139.06,14.73) 138.87,14.92 138.52,14.92 138.25,15.19 138.25,15.96 138.53,16.23 142.47,16.23 143.18,15.52 144.22,15.52 145.06,16.36 149.12,16.36 150.01,15.47 158.37,15.47 158.47,15.57 158.47,16.66 158.74,16.93 J9.6A
  BOTTOM w0.102: v1(139.06,14.73) 138.87,14.92 137.61,14.92 137.49,14.8 U77.22
PHY1_MDI3_N: length 25.2
  TOP w0.102: v1(138.56,17.4) 138.77,17.18 144.31,17.18 145.46,18.34 151.23,18.34 152.85,19.96 157.31,19.96 157.63,19.64 157.63,18.01 157.47,17.84 J9.7A
  BOTTOM w0.102: v1(138.56,17.4) 138.33,17.18 137.61,17.18 137.49,17.3 U77.17
PHY1_MDI3_P: length 25.2
  TOP w0.102: v1(138.56,16.71) 138.77,16.93 144.41,16.93 145.57,18.08 151.33,18.08 152.96,19.71 154.61,19.71 154.81,19.51 155.04,19.51 155.24,19.71 155.47,19.71 155.68,19.51 155.91,19.51 156.11,19.71 156.34,19.71 156.54,19.51 156.77,19.51 156.97,19.71 157.2,19.71 157.38,19.53 157.38,18.82 157.25,18.7 157.25,18.47 157.38,18.34 157.38,18.11 157.29,18.02 J9.8A
  BOTTOM w0.102: U77.18 137.49,16.8 137.61,16.92 138.35,16.92 v1(138.56,16.71)
PHY2_INT#: length 122.8
  TOP w0.127: R93.2 68.44,112.61 68.45,112.6 v1(68.45,112.5)
  L10_SIG4 w0.107: v1(137.46,44.99) 137.39,45.06 137.39,58.52 136.8,59.11 136.8,62.57 133.5,65.87 133.5,73.69 110.36,96.82 94.28,96.82 93.49,96.03 90.65,96.03 88.42,93.8 78.89,93.8 75.62,97.08 75.62,99.44 71.85,103.2 71.85,106.36 71.41,106.81 71.41,109.55 v1(68.45,112.5)
  BOTTOM w0.152: U73.12 137.25,43.72 R496.1 137.8,44.65 v1(137.46,44.99)
PHY2_LED_0: length 70.2
  TOP w0.254: R265.1 v1(163.56,6.85)
  L8_SIG3 w0.254: v1(163.56,6.85) 151.28,6.85 144.2,13.93 144.2,18.69 142.49,20.4 140.16,20.4 137.66,22.9 137.66,26.76 138.28,27.38 142.81,27.38 143.26,27.83 143.26,33.63 144.07,34.44 144.07,43.83 v1(143.48,44.42)
  BOTTOM w0.254: U73.14 138.25,43.93 139.04,44.71 141.38,44.71 141.68,44.42 R498.2 v1(143.48,44.42)
PHY2_LED_1: length 34.1
  TOP w0.254: R249.1 v2(163.48,32.84)
  L8_SIG3 w0.254: v1(137.74,43.46) 139.08,44.8 143.21,44.8 143.29,44.87 143.67,44.87 143.74,44.8 147.05,44.8 155.07,36.78 155.07,34.92 157.15,32.84 v2(163.48,32.84)
  BOTTOM w0.254: U73.13 137.75,43.45 v1(137.74,43.46)
PHY2_MDC_2V5: length 256.1
  L8_SIG3 w0.107: v1(134.47,21.29) 135.64,22.45 135.64,43.31 v1(134.98,43.97) ; v1(10.52,36.45) 11.38,37.31 11.38,40.51 25.97,55.1 25.97,59.21 37.19,70.43 37.19,79.12 41.89,83.82 43.43,83.82 v1(44.42,84.81)
  L10_SIG4 w0.107: v1(50.93,89.74) 51.41,90.22 52.7,90.22 52.96,90.48 52.96,91.51 50.39,94.08 45.77,94.08 44.42,92.74 v1(44.42,84.81) ; v1(10.52,36.45) 10.21,36.14 10.21,26.01 14.42,21.79 14.42,20.29 17.9,16.81 35.1,16.81 35.82,16.09 43.88,16.09 45.92,14.05 68.35,14.05 70.15,12.24 92.96,12.24 96.24,15.52 126.19,15.52 129.16,18.49 132.36,18.49 134.47,20.6 v1(134.47,21.29)
  BOTTOM w0.152: R637.2 50.36,89.58 50.52,89.74 v1(50.93,89.74) ; U73.7 134.75,43.41 134.98,43.64 v1(134.98,43.97)
PHY2_MDI0_N: length 39.6
  TOP w0.102: v1(140.69,36.04) 140.46,35.81 140.03,35.81 139.8,35.59 139.8,32.16 141.83,30.12 143.22,30.12 152.9,20.45 164.97,20.45 165.4,20.87 165.4,21.95 165.09,22.26 J9.1B
  BOTTOM w0.102: v1(140.69,36.04) 140.46,35.81 139.65,35.81 139.52,35.93 U73.27
PHY2_MDI0_P: length 39.7
  TOP w0.102: v1(140.69,35.33) 140.46,35.56 140.14,35.56 140.06,35.48 140.06,32.26 141.94,30.38 143.33,30.38 153,20.7 156.69,20.7 156.89,20.9 157.12,20.9 157.32,20.7 157.55,20.7 157.76,20.9 157.98,20.9 158.19,20.7 158.42,20.7 158.62,20.9 158.85,20.9 159.05,20.7 159.28,20.7 159.48,20.9 159.71,20.9 159.92,20.7 160.14,20.7 160.35,20.9 160.58,20.9 160.78,20.7 161.01,20.7 161.21,20.9 161.44,20.9 161.64,20.7 161.87,20.7 162.07,20.9 162.3,20.9 162.51,20.7 162.73,20.7 162.94,20.9 163.17,20.9 163.37,20.7 163.6,20.7 163.8,20.9 164.03,20.9 164.23,20.7 164.86,20.7 165.14,20.98 165.14,21.84 164.91,22.08 J9.2B
  BOTTOM w0.102: U73.28 139.52,35.43 139.65,35.56 140.46,35.56 v1(140.69,35.33)
PHY2_MDI1_N: length 33.4
  TOP w0.102: J9.3B 161.45,23.35 161.38,23.42 161.38,25.36 160.12,26.62 156.69,26.62 156.34,26.97 156.34,29.11 154.13,31.32 148.67,31.32 144.37,35.61 144.37,37.57 144.12,37.82 143.74,37.82 v1(143.43,38.13)
  BOTTOM w0.102: U73.23 139.52,37.93 139.65,37.81 143.12,37.81 v1(143.43,38.13)
PHY2_MDI1_P: length 33.4
  TOP w0.102: J9.4B 161.28,23.17 161.13,23.32 161.13,23.69 160.99,23.83 160.99,24.06 161.13,24.2 161.13,24.43 160.99,24.57 160.99,24.8 161.13,24.94 161.13,25.25 160.02,26.37 156.59,26.37 156.08,26.87 156.08,29 154.02,31.06 148.56,31.06 144.12,35.51 144.12,37.47 144.02,37.57 143.74,37.57 v1(143.43,37.26)
  BOTTOM w0.102: v1(143.43,37.26) 143.14,37.56 139.65,37.56 139.52,37.43 U73.24
PHY2_MDI2_N: length 30.3
  TOP w0.102: v1(141.86,39.12) 142.14,38.84 142.55,38.84 142.88,38.52 142.88,35.77 145.34,33.31 148.22,30.43 152.04,30.43 156.54,25.93 157.96,25.93 158.75,25.15 158.75,23.51 158.91,23.35 J9.5B
  BOTTOM w0.102: v1(141.86,39.12) 141.55,38.81 139.65,38.81 139.52,38.93 U73.21
PHY2_MDI2_P: length 30.3
  TOP w0.102: J9.6B 158.74,23.17 158.5,23.41 158.5,23.62 158.37,23.75 158.37,23.97 158.5,24.1 158.5,24.33 158.37,24.46 158.37,24.68 158.5,24.81 158.5,25.04 157.86,25.68 156.44,25.68 156.44,25.68 151.94,30.18 148.12,30.18 145.16,33.13 142.62,35.67 142.62,38.42 142.45,38.59 142.14,38.59 v1(141.86,38.31)
  BOTTOM w0.102: U73.22 139.52,38.43 139.65,38.56 141.61,38.56 v1(141.86,38.31)
PHY2_MDI3_N: length 31.6
  TOP w0.102: J9.7B 156.37,23.35 156.21,23.51 156.21,25.44 155.69,25.96 148.95,25.96 142.39,32.51 142.39,35.38 141.48,36.3 141.48,39.62 141.66,39.8 141.66,40.59 141.41,40.84 141.12,40.84 v1(140.84,41.12)
  BOTTOM w0.102: v1(140.84,41.12) 140.53,40.81 139.65,40.81 139.52,40.93 U73.17
PHY2_MDI3_P: length 31.6
  TOP w0.102: v1(140.84,40.31) 141.12,40.59 141.3,40.59 141.4,40.49 141.4,39.93 141.22,39.76 141.22,36.19 142.14,35.28 142.14,32.41 148.84,25.7 155.58,25.7 155.96,25.33 155.96,25.1 155.83,24.98 155.83,24.75 155.96,24.62 155.96,24.39 155.83,24.26 155.83,24.04 155.96,23.91 155.96,23.41 156.2,23.17 J9.8B
  BOTTOM w0.102: U73.18 139.52,40.43 139.65,40.56 140.6,40.56 v1(140.84,40.31)
PHY_MDIO_2V5: length 324.5
  L3_SIG1 w0.102: J2.A9 9,132.67 9.65,133.32 25.17,133.32 26.42,132.08 26.42,131.2 29.78,127.84 30.68,127.84 32.91,125.61 33.21,125.61 34.62,124.2 34.62,99.02 36.99,96.66 41.9,96.66 v1(42.8,95.76)
  L8_SIG3 w0.107: v1(41.43,85.85) 41.43,83.68 36.96,79.21 36.96,70.53 25.74,59.31 25.74,55.2 9.42,38.88 9.42,36.83 9.04,36.44 9.04,35.28 9.68,34.65 v1(10.59,34.65) ; v1(135.51,44.27) 136.25,43.54 136.25,33.43 136.84,32.83 136.84,21.68 135.79,20.62 v1(133.96,20.62)
  L10_SIG4 w0.107: v1(41.43,85.85) 41.96,86.39 41.96,95.43 42.29,95.76 v1(42.8,95.76) ; v1(133.96,20.62) 132.05,18.72 128.98,18.72 126.01,15.75 96.14,15.75 92.87,12.47 70.26,12.47 68.33,14.4 45.89,14.4 43.97,16.32 35.92,16.32 35.15,17.09 17.95,17.09 14.65,20.38 14.65,21.89 10.59,25.95 v1(10.59,34.65)
  BOTTOM w0.152: v1(133.96,20.62) 133.96,20.32 133.25,19.61 133.25,19.41 133.22,19.38 U77.8 ; v1(10.59,34.65) 9.37,34.65 8.76,35.25 AMC1.130 ; R407.2 R625.1 43.63,96.19 43.2,95.76 v1(42.8,95.76) ; U73.8 135.25,43.48 135.51,43.74 v1(135.51,44.27)
PHY_RSTZ: length 153.6
  TOP w0.152: U1.1 v1(132.56,143.16)
  L8_SIG3 w0.107: v1(142.62,19.48) 142.62,19.28 142.1,18.76 139.89,18.76 137.13,21.52 137.13,33.47 138.33,34.67 138.33,40.84 137.08,42.09 137.08,46.45 135.12,48.41 130.66,48.41 120.65,58.43 120.65,71.44 123.12,73.91 123.53,73.91 123.83,74.21 123.83,92.89 119.48,97.23 119.48,106.48 123.4,110.4 127.1,110.4 132.52,115.82 132.52,119.76 132.81,120.05 132.81,129.08 133.63,129.9 133.63,133.35 133.27,133.71 133.27,135.64 132.03,136.88 132.03,139.71 132.96,140.64 132.96,142.75 v1(132.56,143.16)
  BOTTOM w0.152: v1(142.62,19.48) 142.69,19.41 R651.2
PHY_RSTZ_2V5: length 38.5
  L8_SIG3 w0.107: v1(142.21,40.84) 141.39,41.67 140.85,41.67 140.46,41.28 140.46,40.41 140.26,40.21 139.24,40.21 139.19,40.15 139.19,31.6 137.36,29.76 137.36,22.69 140.32,19.72 141.68,19.72 v1(141.79,19.61)
  BOTTOM w0.152: v1(142.21,40.84) 141.53,41.53 139.67,41.53 139.57,41.43 U73.16 ; v1(141.79,19.61) R651.1 141.35,18.8 140.84,18.29 139.45,18.29 139.25,18.09 R652.1 139.1,17.8 136.92,17.8 U77.16
PLL0_VDDA12: length 15.6
  TOP w0.254: U15.N15 v1(149.82,100.08) ; U15.L15 v1(149.82,101.68)
  L3_SIG1 w0.381: v1(149.82,101.68) 149.75,101.68 149.3,101.23 149.3,100.61 v1(149.82,100.08) 149.82,99.15 151.04,97.93 156.78,97.93 158.24,96.47 v2(158.24,94.51)
  vias: v2(159.33,94.51) v2(160.43,94.54)
PLL_LOCK1: length 30.6
  TOP w0.152: U18.46 64.67,99.06 64.32,99.42 61.62,99.42 60.5,100.53 60.5,102.82 60.33,102.99 60.33,104.57 61.04,105.28 v1(62.33,105.28) ; U8.4 71.61,115.94 v1(72.96,115.94)
  L8_SIG3 w0.107: v1(62.33,105.28) 62.71,104.9 65.28,104.9 71.81,111.43 71.81,114.79 v1(72.96,115.94)
PLL_LOCK2: length 24.7
  TOP w0.152: U8.5 71.61,115.29 v1(73.77,115.29) ; v1(77.93,104.29) 77.62,103.99 77.62,102.77 77.85,102.54 78.19,102.54 78.61,102.11 78.61,100.57 79.55,99.64 82.1,99.64 82.55,99.18 U17.46
  L8_SIG3 w0.107: v1(77.93,104.29) 77.47,104.75 77.47,106.25 74.85,108.87 74.85,114.21 v1(73.77,115.29)
PLLLOCK_LED: length 140.6
  L3_SIG1 w0.102: v1(52.51,139.84) 53.4,138.94 56.64,138.94 61.02,134.56 80.3,134.56 86.41,128.45 88.56,128.45 88.93,128.82 101.12,128.82 101.67,128.27 110.54,128.27 110.82,128.55 111.93,128.55 113.13,129.74 117.75,129.74 118.29,130.28 123.25,130.28 123.86,129.67 130.13,129.67 130.89,128.91 146,128.91 149.17,125.73 168.02,125.73 172.34,121.41 172.34,112.9 v1(171.83,112.14)
  BOTTOM w0.152: v1(52.51,139.84) U39.26 ; v1(171.83,112.14) R365.1
PMBUS_ALERT: length 206.2
  TOP w0.152: v1(141.32,127.39) 141.14,127.21 140.52,127.21 140.19,127.54 U1.40 ; v1(122.89,127.05) 122.81,127.13 R36.1
  TOP w0.254: v2(101.75,20.95) 102.01,20.7 R258.1
  L3_SIG1 w0.102: PMBUS1.3 135.74,120.14 140.19,124.6 140.19,126.26 v1(141.32,127.39) ; v2(71.12,7.82) 71.12,5.16 72.24,4.04 76.96,4.04 83.79,10.87 85.72,10.87 87.43,12.57 87.43,18.06 89.43,20.06 100.86,20.06 v2(101.75,20.95)
  L5_SIG2 w0.107: v1(122.89,127.05) 123.66,126.28 123.66,125.31 125.53,123.44 126.75,123.44 PMBUS1.3 131.32,118.87 131.32,113.35 127.67,109.71 122.02,109.71 121.52,109.2 121.52,95.62 125.83,91.3 125.83,62.94 124.98,62.09 124.98,36.86 123.51,35.39 123.51,31.28 116.08,23.85 103.95,23.85 101.75,21.65 v2(101.75,20.95)
  BOTTOM w0.152: U79.8 140.7,125.53 140.81,125.63 141.76,125.63 142.22,126.1 142.22,126.94 141.77,127.39 v1(141.32,127.39)
  BOTTOM w0.254: R577.1 70.92,7.75 70.99,7.82 v2(71.12,7.82)
PMBUS_CLK: length 187.8
  TOP w0.152: v1(115.98,123.83) R59.2 116.14,123.11 116.46,123.42 116.46,124.63 116.07,125.02 U4.8
  TOP w0.254: R259.1 v2(100.23,20.7)
  L3_SIG1 w0.102: v2(100.23,20.7) 89.53,20.7 87.12,18.29 87.12,12.7 85.6,11.18 83.91,11.18 83.66,11.18 77.17,4.69 77.17,4.68 77.03,4.54 73.03,4.54 72.64,4.92 v2(72.64,6.35)
  L5_SIG2 w0.107: v2(100.23,20.7) 99.82,21.11 99.82,23.02 106.95,30.15 121.62,30.15 122.63,31.16 122.63,35.27 124.43,37.07 124.43,87.66 119.71,92.38 119.71,104.8 120.02,105.11 120.02,109.53 122.72,112.24 125.45,112.24 127.64,114.43 129.41,114.43 PMBUS1.1 126.62,118.49 125.4,118.49 124.16,119.74 124.16,121.64 121.69,124.1 117.88,124.1 117.6,123.83 v1(115.98,123.83)
  BOTTOM w0.152: R59.2 v1(115.98,123.83)
  BOTTOM w0.254: v2(72.64,6.35) R580.1
PMBUS_CTL: length 198.3
  TOP w0.152: R30.1 122.63,128.65 122.91,128.37 v1(122.91,127.84) ; v1(140.69,127.61) U1.41
  L3_SIG1 w0.102: v1(140.69,127.61) 140.69,127.39 137.76,124.46 131.83,124.46 PMBUS1.4
  L5_SIG2 w0.107: v1(122.91,127.84) 123.49,127.84 125.48,125.86 126.87,125.86 PMBUS1.4 131.55,121.18 131.55,113.26 127.77,109.48 122.49,109.48 121.92,108.92 121.92,101.06 122.8,100.18 122.8,95.08 126.06,91.82 126.06,62.18 125.21,61.33 125.21,36.77 123.85,35.41 123.85,31.3 115.26,22.71 108.23,22.71 105.22,19.7 82.3,19.7 78.16,15.55 v2(78.16,10.21)
  BOTTOM w0.152: R584.1 70.43,4.43 70.55,4.31 76.9,4.31 78.16,5.56 v2(78.16,10.21)
PMBUS_DAT: length 183.8
  TOP w0.152: v1(100.2,22.87) R255.1 ; U4.9 116.57,125.17 116.92,124.82 116.92,123.5 117.31,123.11 R58.2 117.47,124.13 117.45,124.16 117.45,124.21 117.47,124.22 v1(117.42,124.22)
  L3_SIG1 w0.102: v2(73.28,4.95) 77.01,4.95 83.54,11.48 84.04,11.48 84.04,11.48 85.47,11.48 86.77,12.78 86.77,18.36 89.64,21.23 98.57,21.23 v1(100.2,22.87)
  L5_SIG2 w0.107: v1(100.2,22.87) 107.18,29.84 121.75,29.84 123.28,31.37 123.28,35.49 124.75,36.96 124.75,62.65 125.6,63.5 125.6,87.09 120.63,92.06 120.63,108.64 121.93,109.94 127.58,109.94 131.06,113.42 131.06,116.59 PMBUS1.2 126.64,121.01 125.3,121.01 121.95,124.36 121.87,124.36 121.82,124.41 117.6,124.41 v1(117.42,124.22)
  BOTTOM w0.152: v1(117.42,124.22) 117.47,124.22 117.45,124.21 117.45,124.16 117.47,124.13 R58.2
  BOTTOM w0.305: R583.1 v2(73.28,4.95)
POWER_RESETZ: length 97.7
  TOP w0.152: R181.2 R179.1 ; R179.1 v1(168.92,87.9) ; R179.1 C60.1 ; U1.87 v1(139.69,146.23)
  L8_SIG3 w0.107: CN6.1 136.04,120.68 137.39,120.68 139.69,122.98 139.69,127.12 140.07,127.5 140.07,134.65 139.5,135.23 139.5,140.84 141.17,142.52 141.17,143.37 140.81,143.73 140.81,145.11 v1(139.69,146.23)
  L10_SIG4 w0.107: CN6.1 135.59,119 136.52,119.93 143.05,119.93 145.41,117.56 145.41,115.87 145.99,115.29 146.31,115.29 146.46,115.44 146.84,115.44 147.04,115.24 147.72,115.24 148.15,115.67 151.87,115.67 152.4,115.14 152.4,114.58 155.57,111.4 155.57,110.07 155.89,109.75 155.89,108.9 158.24,106.55 165.96,106.55 168.4,104.11 168.4,88.44 168.92,87.92 v1(168.92,87.9)
PW_SEQ_I2C_EN: length 92
  TOP w0.152: U1.5 v1(132.56,141.16)
  L8_SIG3 w0.107: v1(132.56,141.16) 131.62,140.23 131.62,133.38 130.9,132.65 129.07,132.65 123.39,126.97 123.39,124.76 121.54,122.91 118.16,122.91 117.91,122.66 117.91,122.05 117.98,121.97 117.98,120.92 117.97,120.9 117.97,120.13 118.11,119.99 118.11,113.61 117.51,113.02 117.51,65.83 115.52,63.84 v2(115.52,61.76)
  BOTTOM w0.152: U66.5 114.48,61.78 115.49,61.78 v2(115.52,61.76)
PW_SEQ_RSTZ: length 38.5
  TOP w0.152: v1(113.57,124.87) U4.3 ; U1.2 v1(130.05,142.66)
  L8_SIG3 w0.107: v1(130.05,142.66) 130.73,141.97 130.73,134.21 130.33,133.81 129.9,133.81 125.78,129.69 123.07,129.69 122.71,130.05 122.4,130.05 121.87,129.53 v1(121.87,127.84) 119.44,125.4 114.1,125.4 v1(113.57,124.87)
  BOTTOM w0.152: v1(121.87,127.84) 121.86,127.85 R324.1 ; R338.2 C345.1 111.8,123.11 v1(113.57,124.87)
PW_SEQ_SCL: length 84.8
  TOP w0.152: R59.1 v1(115.98,121.41)
  L5_SIG2 w0.107: v2(113.33,63.45) 113.33,85.39 116.02,88.08 116.02,118.41 115.7,118.73 115.7,121.13 v1(115.98,121.41)
  BOTTOM w0.152: 120.02,58.67 120.02,58.67 119.66,59.03 117.83,59.03 116.56,60.3 116.56,63.8 115.98,64.39 U66.7 113.64,64.39 113.33,64.08 v2(113.33,63.45) ; 120.02,58.67 120.27,58.93 121.79,58.93 122.43,58.29 122.43,54.86 119.76,52.19 U69.6 ; 120.02,58.67 120.02,58.17 119.88,58.03 U67.6
PW_SEQ_SDA: length 75.8
  TOP w0.152: R58.1 v1(118.29,122.21)
  L8_SIG3 w0.107: v1(115.95,63.12) 117.74,64.91 117.74,98.79 118.34,99.39 118.34,117.07 119,117.73 119,121.5 v1(118.29,122.21)
  BOTTOM w0.152: 117.74,58.54 115.95,60.33 v1(115.95,63.12) U66.6 ; 117.74,58.54 U67.5 ; 117.74,58.54 117.47,58.27 117.47,53.98 118.76,52.69 U69.5
REFCLK1_PD#: length 31.3
  TOP w0.152: U8.1 72.62,117.89 72.62,117.89 v1(73.77,117.89) ; U18.43 66.17,99.89 65.74,100.33 62.38,100.33 61.98,100.74 R137.1 62.45,101.15 62.7,101.4 62.7,103.64 63.37,104.31 v1(63.37,105.62)
  L8_SIG3 w0.107: v1(63.37,105.62) 63.37,106.05 69.7,112.37 69.7,115.14 72.45,117.89 v1(73.77,117.89)
REFCLK2_PD#: length 26.3
  TOP w0.152: v1(72.96,117.24) 72.49,117.24 U8.2 ; v1(81.08,101.19) 81.25,101.02 R139.1 82.15,101.02 82.82,100.36 82.82,100.36 84.05,99.12 U17.43
  L8_SIG3 w0.107: v1(72.96,117.24) 73.39,116.81 73.39,114.91 74.35,113.96 74.35,108.74 77.19,105.89 77.19,103.4 78.21,102.39 79.6,102.39 80.8,101.19 v1(81.08,101.19)
RS232_RX: length 15.5
  TOP w0.152: v1(159.77,126.12) 160.99,124.9 160.99,117.3 158.12,114.43
  BOTTOM w0.152: U47.8 159.5,125.08 159.77,125.35 v1(159.77,126.12)
RS232_TX: length 17
  TOP w0.152: COM2.3 150.94,124.14 v1(150.94,128.72)
  BOTTOM w0.152: v1(150.94,128.72) 150.94,128.13 151.39,127.68 U47.13
RSV_CLKN: length 93.2
  TOP w0.102: v1(36.76,129.84) 36.47,130.13 36.23,130.13 36.1,129.99 CN7.110 ; v1(89.47,93.56) 89.19,93.74 88.58,93.74 88.46,93.62 U17.28
  L8_SIG3 w0.102: v1(36.76,129.84) 36.51,130.1 35.23,130.1 34.9,130.43 34.9,131.45 35.36,131.91 41.51,131.91 42.87,130.55 47.58,130.55 54.6,123.53 68.16,123.53 71.66,120.04 77.18,120.04 79.14,118.07 79.14,108.6 78.6,108.06 78.6,105.61 80.87,103.34 82.23,103.34 82.78,102.79 89.85,102.79 91.76,100.89 91.76,95.47 90.01,93.72 89.63,93.72 v1(89.47,93.56)
RSV_CLKP: length 93.2
  TOP w0.102: v1(36.76,130.65) 36.5,130.38 36.23,130.38 36.12,130.49 CN7.112 ; U17.29 88.46,94.12 88.58,94 89.19,94 v1(89.47,94.17)
  L8_SIG3 w0.102: v1(36.76,130.65) 36.51,130.39 36.09,130.39 35.95,130.53 35.72,130.53 35.58,130.39 35.35,130.39 35.19,130.55 35.19,131.33 35.48,131.62 35.9,131.62 36.13,131.39 36.36,131.39 36.59,131.62 36.82,131.62 37.04,131.39 37.27,131.39 37.5,131.62 37.73,131.62 37.96,131.39 38.19,131.39 38.42,131.62 38.64,131.62 38.87,131.39 39.1,131.39 39.33,131.62 39.56,131.62 39.79,131.39 40.02,131.39 40.24,131.62 40.47,131.62 40.7,131.39 40.93,131.39 41.16,131.62 41.39,131.62 42.75,130.26 43.05,130.26 43.19,130.12 43.41,130.12 43.55,130.26 43.78,130.26 43.91,130.12 44.14,130.12 44.28,130.26 44.51,130.26 44.64,130.12 44.87,130.12 45.01,130.26 45.24,130.26 45.37,130.12 45.6,130.12 45.74,130.26 45.96,130.26 46.1,130.12 46.33,130.12 46.46,130.26 46.69,130.26 46.83,130.12 47.06,130.12 47.19,130.26 47.46,130.26 54.48,123.24 68.04,123.24 71.54,119.74 77.05,119.74 78.85,117.95 78.85,108.72 78.31,108.18 78.31,105.49 80.75,103.05 82.11,103.05 82.66,102.5 89.73,102.5 91.47,100.77 91.47,95.59 89.89,94.01 89.63,94.01 v1(89.47,94.17)
RTC_XI: length 5.8
  TOP w0.152: U15.J19 152.94,104.01 153.23,104.01 154.27,105.05 155.12,105.05 C37.2 156.04,104.59 156.48,105.03 157.18,105.03 Y2.1
RTC_XO: length 5.5
  TOP w0.152: U15.H19 153.14,104.48 154.13,105.47 155.2,105.47 C32.2 156.09,105.85 156.41,105.53 157.17,105.53 Y2.4
RTCK/GP8[0]: length 11.6
  TOP w0.127: U15.K17 v1(151.42,102.48)
  TOP w0.152: R140.1 v2(161.29,101.35)
  L10_SIG4 w0.107: v2(161.29,101.35) 160.6,102.03 154.36,102.03 154.29,102.1 151.8,102.1 v1(151.42,102.48)
RTM_MDC_2V5: length 77.9
  L3_SIG1 w0.102: v1(45.62,92.81) 43.11,95.32 42.06,95.32 40.95,96.43 36.89,96.43 34.4,98.93 34.4,124.1 33.32,125.17 32.12,125.17 26.19,131.1 26.19,131.99 25.08,133.1 10.54,133.1 10.2,132.75 J2.B9
  L10_SIG4 w0.107: v1(50.88,91.21) 48.34,93.75 45.95,93.75 45.59,93.4 45.59,92.94 45.62,92.91 v1(45.62,92.81)
  BOTTOM w0.152: R635.2 50.36,91.1 50.44,91.19 50.8,91.19 50.88,91.26 v1(50.88,91.21)
  BOTTOM w0.254: R623.1 J2.B9
RXN_1: length 17.6
  TOP w0.102: v1(31.23,25.73) 30.99,25.49 30.99,25.28 31.11,25.16 C241.2
  BOTTOM w0.102: v1(31.23,25.73) 31.02,25.53 31.02,25.3 31.14,25.18 31.14,24.95 31.02,24.84 31.02,24.61 31.14,24.49 31.14,24.27 31.02,24.15 31.02,23.89 31.2,23.72 31.42,23.72 31.6,23.9 31.83,23.9 32.01,23.72 32.24,23.72 32.41,23.9 32.64,23.9 32.82,23.72 33.05,23.72 33.23,23.9 33.46,23.9 33.63,23.72 33.86,23.72 34.04,23.9 34.27,23.9 34.45,23.72 36.85,23.72 37.67,24.54 37.67,27.61 35.84,29.43 35.84,29.82 35.77,29.9 U75.16
RXP_1: length 17.6
  TOP w0.102: v1(30.57,25.73) 30.73,25.56 30.73,25.22 30.68,25.16 C242.2
  BOTTOM w0.102: v1(30.57,25.73) 30.77,25.53 30.77,23.79 31.09,23.47 36.96,23.47 37.92,24.43 37.92,27.71 36.09,29.54 36.09,29.8 36.17,29.87 U75.15
SATA_CLKN: length 121.3
  TOP w0.102: U17.25 88.46,92.12 88.58,92.24 89.19,92.24 v1(89.47,92.06)
  L8_SIG3 w0.102: v1(89.47,92.06) 89.31,92.22 87.76,92.22 86.65,91.11 86.65,90.15 85.91,89.41 83.26,89.41 81.63,91.04 74.86,91.04 72.5,93.4 71.16,93.4 71.03,93.53 69.78,93.53 68.86,94.45 68.86,96.54 67.86,97.54 63.76,97.54 63.64,97.41 63.64,93.86 62.03,92.25 59.03,92.25 56.95,90.18 56.95,85.28 55.34,83.67 55.34,81.36 51.96,77.98 50,77.98 45.25,82.73 42.08,82.73 40.28,80.92 40.28,77.27 42.79,74.76 42.79,55.45 31.33,44 31.33,41.81 v1(31.53,41.6)
  BOTTOM w0.102: R511.1 31.29,40.84 31.2,40.93 31.2,41.48 31.32,41.6 v1(31.53,41.6)
SATA_CLKP: length 121.3
  TOP w0.102: v1(89.47,92.67) 89.19,92.5 88.58,92.5 88.46,92.62 U17.26
  L8_SIG3 w0.102: v1(89.47,92.67) 89.31,92.51 87.64,92.51 86.35,91.23 86.35,90.27 85.79,89.7 83.38,89.7 81.75,91.33 74.98,91.33 72.62,93.69 71.28,93.69 71.15,93.82 69.91,93.82 69.15,94.57 69.15,96.66 67.98,97.83 63.64,97.83 63.35,97.54 63.35,93.98 61.91,92.54 58.91,92.54 56.66,90.3 56.66,85.4 55.05,83.79 55.05,81.48 51.84,78.28 50.12,78.28 45.37,83.02 41.96,83.02 39.99,81.05 39.99,77.15 42.49,74.64 42.49,55.58 31.04,44.12 31.04,41.82 v1(30.82,41.6)
  BOTTOM w0.102: R512.1 30.76,40.84 30.94,41.02 30.94,41.48 v1(30.82,41.6)
SATA_GND: length 9.1
  TOP w0.381: J10.M1 39.91,19.67 ; J10.M1 38.3,19.67 ; J10.M1 38.3,18.06 ; J10.M1 39.91,18.06 ; 25.47,20.67 J10.M2 ; J10.M2 27.08,20.67 ; J10.M2 27.08,19.06 ; J10.M2 25.47,19.06
SGMIICLKN: length 69.1
  TOP w0.102: v1(71.42,92.89) 71.58,92.89 71.7,93.01 71.7,93.49 71.46,93.74 70.7,93.74 70.58,93.62 U18.28
  L8_SIG3 w0.102: v1(71.42,92.89) 71.65,92.66 71.65,92.33 71.03,91.71 60.16,91.71 58.32,89.87 58.32,86.68 57.46,85.82 57.46,85.06 55.85,83.46 55.85,81.16 52.16,77.46 47.41,77.46 45.19,75.23 45.19,55.55 45.66,55.08 49.07,55.08 49.24,54.92 49.9,54.92 50.22,54.59 52.34,54.59 v4(52.78,54.16)
  BOTTOM w0.102: C681.1 v4(52.78,54.16)
SGMIICLKP: length 69.1
  TOP w0.102: U18.29 70.58,94.12 70.7,94 71.56,94 71.96,93.6 71.96,93.09 72.16,92.89 v1(72.23,92.89)
  L8_SIG3 w0.102: v1(72.23,92.89) 71.95,92.6 71.95,92.21 71.15,91.41 60.28,91.41 58.61,89.74 58.61,86.56 57.75,85.7 57.75,84.94 56.15,83.34 56.15,81.03 52.28,77.17 47.53,77.17 45.48,75.11 45.48,55.67 45.78,55.37 48.33,55.37 48.53,55.58 48.76,55.58 48.96,55.37 49.19,55.37 49.36,55.21 49.91,55.21 50.06,55.36 52.38,55.36 v4(52.78,54.96)
  BOTTOM w0.102: C673.1 v4(52.78,54.96)
SMB_SCL_IPMBL: length 320.1
  TOP w0.152: U1.72 148.54,141.66 148.86,141.99 R5.1 149.41,141.64 149.05,141.27 149.08,141.27 149.08,141.28 v1(149.08,141.28) ; v1(9.42,45.69) 9.42,46.23 9.15,46.5 AMC1.56
  L10_SIG4 w0.107: v1(9.42,45.69) 7.77,44.04 7.77,25.17 9.14,23.8 9.94,23.8 18.33,15.41 42.86,15.41 44.9,13.36 68,13.36 69.8,11.56 93.25,11.56 95.2,13.51 107.65,13.51 108.48,12.67 125.5,12.67 126.34,13.51 130.57,13.51 145.77,28.71 145.77,29.2 147.14,30.56 147.72,30.56 160.96,43.81 160.96,53.28 168.38,60.7 168.38,81.88 170.22,83.73 170.22,88.5 169.57,89.15 169.57,110.25 170.9,111.59 170.9,121.68 165.23,127.35 158.09,127.35 151.98,133.47 151.98,133.81 150.01,135.78 150.01,140.35 v1(149.08,141.28)
SMB_SDA_IPMBL: length 328
  TOP w0.152: v2(149.41,138.68) R8.1 148.72,137.92 148.48,138.16 U1.65 ; AMC1.71 v1(10.41,57.75)
  L10_SIG4 w0.107: v1(10.41,57.75) 10.21,57.55 10.21,44.16 8,41.95 8,25.27 9.24,24.03 10.03,24.03 11.82,22.24 18.43,15.63 43.69,15.63 45.73,13.59 68.1,13.59 69.9,11.79 93.15,11.79 95.11,13.74 109.11,13.74 109.46,14.09 129.01,14.09 133.66,18.75 134.17,18.75 135.83,20.4 136.65,20.4 147.04,30.79 147.62,30.79 160.73,43.9 160.73,53.38 168.15,60.8 168.15,81.98 169.99,83.82 169.99,88.41 169.34,89.06 169.34,110.35 170.68,111.68 170.68,121.39 170.41,121.65 169.48,121.65 168.21,122.93 168.21,122.93 167.61,123.52 161.52,123.52 151.75,133.29 151.75,133.71 149.78,135.68 149.78,138.31 v2(149.41,138.68)
SOC_BOOTCOMPLETE: length 196.7
  TOP w0.152: U23.AF31 v4(54.38,49.36)
  L5_SIG2 w0.107: v1(80.03,134.16) 83.62,134.16 86.6,131.18 87.13,131.18 88.78,129.52 99.54,129.52 104.87,124.2 104.87,120.06 109.59,115.34 109.59,97.83 102.59,90.83 102.59,62.46 102.82,62.23 102.82,51.03 101.9,50.11 101.9,36.52 99.08,33.69 95.48,33.69 95.34,33.83 87.87,33.83 85.82,31.78 77.47,31.78 74.35,34.9 63.21,34.9 62.64,34.33 61.43,34.33 60.19,33.1 57.05,33.1 49.99,40.15 49.99,49.58 50.15,49.75 53.71,49.75 54.1,49.36 v4(54.38,49.36)
  BOTTOM w0.152: v1(80.03,134.16) U43.27
SOC_DDR3A_EA0: length 68.4
  TOP w0.152: v1(99.06,58.22) 98.91,58.37 DIMM1.107 ; U23.D15 v4(72.78,62.96)
  L3_SIG1 w0.102: v1(99.06,58.22) 99.06,57.66 99.21,57.51 99.59,57.51 99.75,57.35 99.75,56.77 99.93,56.59 100.18,56.59 100.36,56.77 100.36,57.4 100.53,57.58 101.61,57.58 102.49,58.46 105.09,58.46 106.05,59.41 106.05,62.92 107.06,63.94 107.06,69.63 106.83,69.86 106.36,69.86 105.94,70.28 105.79,70.28 105.79,70.28 105.51,70.28 98.41,70.28 98.18,70.51 98.18,70.73 98,70.91 97.75,70.91 97.57,70.73 97.57,70.51 97.39,70.33 97.14,70.33 96.96,70.51 96.96,70.73 96.78,70.91 96.53,70.91 96.35,70.73 96.35,70.51 96.17,70.33 95.92,70.33 95.74,70.51 95.74,70.73 95.56,70.91 95.31,70.91 95.13,70.73 95.13,70.51 94.95,70.33 94.46,70.33 94.16,70.64 94.16,71.07 93.42,71.81 86.73,71.81 86.55,71.63 86.55,71.22 86.37,71.04 86.12,71.04 85.94,71.22 85.94,71.63 85.76,71.81 85.49,71.81 85.31,71.63 85.31,70.64 85.13,70.46 84.88,70.46 84.7,70.64 84.7,71.63 84.52,71.81 84.29,71.81 82.95,70.46 81.18,70.46 80.82,70.1 80.82,68.55 76.72,64.45 75.86,64.45 75.54,64.13 74.22,64.13 73.94,63.85 73.94,63.61 73.73,63.39 73.21,63.39 v4(72.78,62.96)
SOC_DDR3A_EA1: length 68.6
  TOP w0.152: U23.C15 v4(73.58,62.96) ; v1(99,58.97) DIMM1.105
  L3_SIG1 w0.102: v4(73.58,62.96) 73.8,63.19 73.81,63.19 73.96,63.34 74.74,63.34 74.92,63.52 74.93,63.52 74.94,63.53 75.46,63.53 75.86,63.94 76.93,63.94 81.33,68.34 81.33,69.67 81.61,69.95 86.74,69.95 87.24,70.45 87.24,71.13 87.4,71.3 88.05,71.3 88.23,71.12 88.23,70.26 88.41,70.08 88.66,70.08 88.84,70.26 88.84,71.17 88.97,71.3 89.32,71.3 89.45,71.17 89.45,70.26 89.63,70.08 89.88,70.08 90.06,70.26 90.06,71.14 90.21,71.3 90.51,71.3 90.67,71.14 90.67,70.26 90.85,70.08 91.1,70.08 91.28,70.26 91.28,71.17 91.41,71.3 91.76,71.3 91.89,71.17 91.89,70.26 92.07,70.08 92.32,70.08 92.5,70.26 92.5,71.12 92.68,71.3 93.21,71.3 93.65,70.86 93.65,70.05 94.03,69.67 95.98,69.67 96.09,69.77 105.73,69.77 106.55,68.95 106.55,64.15 105.54,63.13 105.54,59.62 104.88,58.97 101.75,58.97 101.58,58.79 101.58,58.27 101.4,58.09 101.14,58.09 100.97,58.27 100.97,58.79 100.79,58.97 100.53,58.97 100.36,58.79 100.36,58.27 100.18,58.09 99.93,58.09 99.75,58.27 99.75,58.79 99.57,58.97 v1(99,58.97)
SOC_DDR3A_EA2: length 68.9
  TOP w0.152: DIMM1.106 103,58.67 101.96,59.72 v1(101.96,60.76) ; U23.B16 v4(74.38,62.16)
  L3_SIG1 w0.102: v4(74.38,62.16) 74.6,62.39 74.61,62.39 74.78,62.56 75.5,62.56 75.86,62.92 77.35,62.92 81.18,66.75 82.33,66.75 83.24,67.66 83.59,67.66 83.77,67.48 83.77,66.93 83.95,66.75 84.2,66.75 84.38,66.93 84.38,67.48 84.56,67.66 84.81,67.66 84.99,67.48 84.99,66.93 85.17,66.75 85.42,66.75 85.6,66.93 85.6,67.48 85.78,67.66 86.03,67.66 86.21,67.48 86.21,66.93 86.39,66.75 86.64,66.75 86.82,66.93 86.82,67.48 86.99,67.66 87.25,67.66 87.43,67.48 87.43,66.93 87.6,66.75 87.86,66.75 88.04,66.93 88.04,67.48 88.21,67.66 88.47,67.66 88.64,67.48 88.64,66.93 88.82,66.75 89.08,66.75 89.25,66.93 89.25,67.48 89.43,67.66 89.69,67.66 89.86,67.48 89.86,66.93 90.04,66.75 90.3,66.75 90.47,66.93 90.47,67.48 90.65,67.66 90.9,67.66 91.08,67.48 91.08,66.93 91.26,66.75 91.51,66.75 91.69,66.93 91.69,67.48 91.87,67.66 92.12,67.66 92.3,67.48 92.3,66.93 92.48,66.75 92.73,66.75 92.91,66.93 92.91,67.9 93.64,68.63 93.92,68.63 94.03,68.51 94.03,68.29 94.15,68.17 94.32,68.17 94.44,68.29 94.44,68.51 94.56,68.63 96.38,68.63 96.51,68.76 96.81,68.76 96.99,68.58 96.99,67.84 97.17,67.66 97.42,67.66 97.6,67.84 97.6,68.58 97.78,68.76 98.03,68.76 98.21,68.58 98.21,67.84 98.39,67.66 99.51,67.66 99.69,67.84 99.69,68.22 99.87,68.4 100.12,68.4 100.3,68.22 100.3,67.84 100.47,67.66 100.73,67.66 100.91,67.84 100.91,68.58 101.08,68.76 101.34,68.76 101.52,68.58 101.52,67.84 101.69,67.66 101.95,67.66 102.13,67.84 102.13,68.58 102.3,68.76 102.56,68.76 102.73,68.58 102.73,67.84 102.91,67.66 103.58,67.66 104.57,66.67 105.08,66.67 105.31,66.45 105.31,64.39 104.5,63.58 104.5,61.09 104.17,60.76 103.9,60.76 103.72,60.94 103.72,61.39 103.54,61.57 103.29,61.57 103.11,61.39 103.11,60.94 102.93,60.76 v1(101.96,60.76)
SOC_DDR3A_EA3: length 68.4
  TOP w0.152: DIMM1.103 99.17,59.57 v1(99.29,59.69) ; U23.C16 v4(73.58,62.16)
  L3_SIG1 w0.102: v1(99.29,59.69) 100.23,59.69 100.41,59.87 100.41,60.15 100.59,60.33 100.84,60.33 101.02,60.15 101.02,59.87 101.2,59.69 103.86,59.69 105.03,60.86 105.03,63.34 106.05,64.36 106.05,68.74 105.51,69.27 96.3,69.27 96.17,69.14 93.43,69.14 92.54,68.25 92.29,68.25 92.11,68.43 92.11,69.14 91.93,69.32 91.61,69.32 91.43,69.14 91.43,68.35 91.25,68.17 91,68.17 90.82,68.35 90.82,69.14 90.65,69.32 90.39,69.32 90.21,69.14 90.21,68.35 90.04,68.17 89.78,68.17 89.6,68.35 89.6,69.14 89.43,69.32 89.17,69.32 88.99,69.14 88.99,68.35 88.82,68.17 88.56,68.17 88.39,68.35 88.39,69.14 88.21,69.32 87.95,69.32 87.78,69.14 87.78,68.35 87.6,68.17 87.34,68.17 87.17,68.35 87.17,69.14 86.99,69.32 86.74,69.32 86.56,69.14 86.56,68.35 86.38,68.17 86.13,68.17 85.95,68.35 85.95,69.14 85.77,69.32 85.52,69.32 85.34,69.14 85.34,68.35 85.16,68.17 84.91,68.17 84.73,68.35 84.73,69.14 84.55,69.32 84.3,69.32 84.12,69.14 84.12,68.35 83.94,68.17 83.69,68.17 83.51,68.35 83.51,69.14 83.33,69.32 82.25,69.32 82,69.07 82,68.29 77.14,63.43 75.86,63.43 75.76,63.33 75.02,63.33 74.81,63.11 74.81,62.87 74.53,62.59 74.01,62.59 v4(73.58,62.16)
SOC_DDR3A_EA4: length 68.9
  TOP w0.152: DIMM1.104 106.8,59.27 v1(107.12,58.94) ; U23.D16 v4(72.78,62.16)
  L3_SIG1 w0.102: v1(107.12,58.94) 107.12,59.68 107.06,59.74 107.06,60.39 107.24,60.57 107.49,60.57 107.67,60.75 107.67,61 107.49,61.18 107.24,61.18 107.06,61.36 107.06,62.5 108.69,64.13 108.69,69.72 107.53,70.88 106.78,70.88 106.2,71.46 106.2,71.8 105.91,72.09 104.71,72.09 104.54,71.91 104.54,71.7 104.36,71.53 104.1,71.53 103.93,71.7 103.93,71.91 103.75,72.09 102.89,72.09 102.71,71.91 102.71,71.87 102.53,71.7 102.28,71.7 102.1,71.87 102.1,71.98 101.92,72.16 101.67,72.16 101.49,71.98 101.49,71.87 101.29,71.68 99.65,71.68 99.27,72.06 98.65,72.06 98.52,71.93 94.74,71.93 93.85,72.82 92.14,72.82 91.96,73 91.96,73.31 91.78,73.49 91.53,73.49 91.35,73.31 91.35,73 91.18,72.82 90.92,72.82 90.74,73 90.74,73.31 90.57,73.49 90.31,73.49 90.13,73.31 90.13,73 89.96,72.82 89.7,72.82 89.53,73 89.53,73.31 89.35,73.49 89.09,73.49 88.92,73.31 88.92,73 88.74,72.82 88.48,72.82 88.31,73 88.31,73.31 88.13,73.49 87.87,73.49 87.7,73.31 87.7,73 87.52,72.82 87.27,72.82 87.09,73 87.09,73.31 86.91,73.49 86.66,73.49 86.48,73.31 86.48,73 86.3,72.82 86.05,72.82 85.87,73 85.87,73.31 85.69,73.49 85.44,73.49 85.26,73.31 85.26,73 85.08,72.82 83.88,72.82 83.22,73.49 82.76,73.49 82.58,73.31 82.58,72.8 82.4,72.62 82.15,72.62 81.97,72.8 81.97,73.31 81.79,73.49 81.49,73.49 78.66,70.66 78.66,70.14 78.78,70.02 78.98,70.02 79.1,69.9 79.1,69.73 78.98,69.61 78.78,69.61 78.66,69.49 78.66,68.28 75.35,64.97 74.26,64.97 74.01,64.71 74.01,64.47 73.69,64.16 72.65,64.16 72.41,63.91 72.41,62.53 v4(72.78,62.16)
SOC_DDR3A_EA5: length 68.5
  TOP w0.152: U23.E16 v4(71.98,62.16) ; v1(93.95,61.8) 94,61.76 94.79,61.76 95.78,60.77 DIMM1.99
  L3_SIG1 w0.102: v1(93.95,61.8) 94.42,62.26 94.42,62.66 94.93,63.17 94.93,63.75 94.72,63.96 93.27,63.96 92.96,63.65 92.96,62.66 92.71,62.41 91.58,62.41 91.4,62.23 91.4,60.4 91.2,60.2 90.95,60.2 90.79,60.35 90.79,62.23 90.61,62.41 90.3,62.41 90.12,62.23 90.12,60.4 89.92,60.2 89.67,60.2 89.51,60.35 89.51,62.28 89.33,62.46 89.08,62.46 88.9,62.28 88.9,60.4 88.7,60.2 88.45,60.2 88.29,60.35 88.29,62.28 88.12,62.46 87.86,62.46 87.68,62.28 87.68,60.4 87.48,60.2 87.23,60.2 87.08,60.35 87.08,62.28 86.9,62.46 86.64,62.46 86.47,62.28 86.47,60.4 86.26,60.2 86.01,60.2 85.86,60.35 85.86,62.28 85.68,62.46 85.42,62.46 85.25,62.28 85.25,60.4 85.04,60.2 84.79,60.2 84.64,60.35 84.64,62.28 84.46,62.46 84.21,62.46 84.03,62.28 84.03,60.4 83.82,60.2 83.57,60.2 83.42,60.35 83.42,62.08 83.19,62.31 82.81,62.31 82.63,62.13 82.63,60.4 82.45,60.22 82.2,60.22 82.02,60.4 82.02,62.13 81.84,62.31 81.59,62.31 81.41,62.13 81.41,60.4 81.23,60.22 80.98,60.22 80.8,60.4 80.8,62.13 80.62,62.31 80.19,62.31 79.28,61.4 75.86,61.4 75.44,60.98 74.51,60.98 74.49,60.96 72.54,60.96 72.41,61.09 72.41,61.73 v4(71.98,62.16)
SOC_DDR3A_EA6: length 68.7
  TOP w0.152: DIMM1.100 103.23,60.47 v1(102.21,61.49) ; U23.A17 v4(75.18,61.36)
  L3_SIG1 w0.102: v4(75.18,61.36) 75.32,61.36 75.86,61.91 79,61.91 79.73,62.63 79.73,63.86 80.1,64.24 80.45,64.24 80.63,64.06 80.63,62.99 80.81,62.81 81.06,62.81 81.24,62.99 81.24,64.06 81.42,64.24 81.88,64.24 82.06,64.06 82.06,63.6 82.24,63.42 82.49,63.42 82.67,63.6 82.67,64.06 82.85,64.24 83.24,64.24 83.42,64.06 83.42,63.15 83.6,62.97 83.85,62.97 84.03,63.15 84.03,64.06 84.2,64.24 84.46,64.24 84.64,64.06 84.64,63.15 84.81,62.97 85.07,62.97 85.25,63.15 85.25,64.06 85.42,64.24 85.68,64.24 85.86,64.06 85.86,63.15 86.03,62.97 86.29,62.97 86.46,63.15 86.46,64.06 86.64,64.24 86.9,64.24 87.07,64.06 87.07,63.15 87.25,62.97 87.51,62.97 87.68,63.15 87.68,64.06 87.86,64.24 88.11,64.24 88.29,64.06 88.29,63.15 88.47,62.97 88.72,62.97 88.9,63.15 88.9,64.06 89.08,64.24 89.33,64.24 89.51,64.06 89.51,63.15 89.69,62.97 89.94,62.97 90.12,63.15 90.12,64.06 90.3,64.24 90.55,64.24 90.73,64.06 90.73,63.15 90.91,62.97 91.16,62.97 91.34,63.15 91.34,64.16 91.7,64.52 91.92,64.52 92.1,64.69 92.1,65.56 92.28,65.74 92.53,65.74 92.71,65.56 92.71,64.69 92.89,64.52 93.21,64.52 93.38,64.69 93.38,65.09 93.56,65.27 93.82,65.27 93.99,65.09 93.99,64.69 94.17,64.52 94.86,64.52 95.19,64.85 95.19,65.33 95.36,65.51 95.62,65.51 95.8,65.33 95.8,64.62 95.97,64.44 96.23,64.44 96.4,64.62 96.4,65.33 96.58,65.51 96.84,65.51 97.01,65.33 97.01,64.62 97.19,64.44 97.45,64.44 97.62,64.62 97.62,65.33 97.8,65.51 98.06,65.51 98.23,65.33 98.23,64.62 98.41,64.44 98.93,64.44 99.11,64.62 99.11,65.01 99.29,65.19 99.54,65.19 99.72,65.01 99.72,64.62 99.9,64.44 100.15,64.44 100.33,64.62 100.33,65.14 100.51,65.31 100.76,65.31 100.94,65.14 100.94,64.62 101.12,64.44 101.37,64.44 101.55,64.62 101.55,65.16 101.72,65.34 101.98,65.34 102.16,65.16 102.16,64.62 102.33,64.44 103.35,64.44 103.48,64.31 103.48,62.7 102.27,61.49 v1(102.21,61.49)
SOC_DDR3A_EA7: length 69.1
  TOP w0.152: DIMM1.98 107.93,61.07 108.97,62.1 v1(109.7,62.1) ; U23.E17 v4(71.98,61.36)
  L3_SIG1 w0.102: v4(71.98,61.36) 71.62,61.72 71.56,61.77 71.56,64.67 71.82,64.93 72.98,64.93 73.21,65.15 73.21,66.31 73.49,66.59 73.73,66.59 74.01,66.87 74.01,67.11 74.29,67.39 74.53,67.39 74.81,67.67 74.81,67.91 75.09,68.19 75.33,68.19 75.54,68.41 75.54,68.43 76.63,69.51 76.63,73.89 78.38,75.64 95.37,75.64 95.68,75.34 101.78,75.34 102.44,76 105.24,76 106.78,74.46 109.31,74.46 111.23,72.54 111.23,63.63 v1(109.7,62.1)
SOC_DDR3A_EA8: length 68.4
  TOP w0.152: DIMM1.97 96.27,61.37 96.03,61.62 v1(96.03,61.77) ; U23.A18 v4(75.18,59.76)
  L3_SIG1 w0.102: v1(96.03,61.77) 96.03,60.86 95.94,60.78 95.94,60.35 94.77,59.17 94.77,56.08 93.86,55.17 92.25,55.17 92.07,54.99 91.71,54.99 91.53,54.81 91.53,53.21 91.36,53.04 91.1,53.04 90.93,53.21 90.93,54.81 90.75,54.99 90.49,54.99 90.32,54.81 90.32,53.21 90.14,53.04 89.88,53.04 89.71,53.21 89.71,54.81 89.53,54.99 89.28,54.99 89.1,54.81 89.1,53.21 88.92,53.04 88.67,53.04 88.49,53.21 88.49,54.81 88.31,54.99 88.06,54.99 87.88,54.81 87.88,53.21 87.7,53.04 87.45,53.04 87.27,53.21 87.27,54.81 87.09,54.99 86.84,54.99 86.66,54.81 86.66,53.21 86.48,53.04 86.23,53.04 86.05,53.21 86.05,54.81 85.87,54.99 85.62,54.99 85.44,54.81 85.44,53.21 85.26,53.04 85.01,53.04 84.83,53.21 84.83,54.81 84.65,54.99 84.4,54.99 84.22,54.81 84.22,53.21 84.04,53.04 83.79,53.04 83.61,53.21 83.61,54.81 83.43,54.99 83.2,54.99 83.02,54.81 83.02,53.57 82.85,53.39 81.61,53.39 81.16,53.84 81.16,54.07 80.99,54.25 79.05,54.25 78.87,54.43 78.87,54.68 79.04,54.86 81.14,54.86 81.34,55.06 81.34,55.29 81.17,55.47 79.07,55.47 78.89,55.64 78.89,55.9 79.07,56.08 80.99,56.08 81.16,56.25 81.16,56.56 79.61,58.11 78.97,58.11 78.62,57.76 77.95,57.76 77.47,58.24 77.47,59.44 77.04,59.87 75.86,59.87 75.75,59.76 v4(75.18,59.76)
SOC_DDR3A_EA9: length 68.7
  TOP w0.152: DIMM1.92 104.42,62.87 103.92,62.37 v1(103.92,62.36) ; U23.B17 v4(74.38,61.36)
  L3_SIG1 w0.102: v1(103.92,62.36) 103.92,62.43 103.99,62.49 103.99,63.79 104.78,64.57 104.78,65.94 104.55,66.17 104.36,66.17 103.5,67.03 102.76,67.03 102.58,66.85 102.58,66.29 102.4,66.12 102.15,66.12 101.97,66.29 101.97,66.85 101.79,67.03 101.54,67.03 101.36,66.85 101.36,66.12 101.18,65.94 100.93,65.94 100.75,66.12 100.75,66.85 100.57,67.03 100.05,67.03 99.21,66.19 98.57,66.19 98.17,66.6 98.17,66.98 97.99,67.16 97.74,67.16 97.56,66.98 97.56,66.19 97.38,66.01 97.13,66.01 96.95,66.19 96.95,66.98 96.77,67.16 96.52,67.16 96.34,66.98 96.34,66.19 96.16,66.01 95.61,66.01 95.43,66.19 95.43,66.96 95.23,67.15 94.97,67.15 94.82,67 94.82,66.6 94.64,66.42 94.39,66.42 94.21,66.6 94.21,66.95 94.03,67.13 93.78,67.13 93.6,66.95 93.6,66.6 93.42,66.42 93.12,66.42 92.94,66.24 91.54,66.24 91.36,66.06 91.36,64.9 91.21,64.74 90.9,64.74 90.75,64.9 90.75,66.06 90.57,66.24 90.32,66.24 90.14,66.06 90.14,64.9 89.99,64.74 89.68,64.74 89.53,64.9 89.53,66.06 89.35,66.24 89.1,66.24 88.92,66.06 88.92,64.9 88.77,64.74 88.46,64.74 88.31,64.9 88.31,66.06 88.13,66.24 87.88,66.24 87.7,66.06 87.7,64.9 87.55,64.74 87.24,64.74 87.09,64.9 87.09,66.06 86.91,66.24 86.66,66.24 86.48,66.06 86.48,64.9 86.33,64.74 86.03,64.74 85.87,64.9 85.87,66.06 85.69,66.24 85.44,66.24 85.26,66.06 85.26,64.9 85.11,64.74 84.81,64.74 84.65,64.9 84.65,66.06 84.47,66.24 84.12,66.24 83.95,66.06 83.95,65.43 83.77,65.25 83.51,65.25 83.34,65.43 83.34,66.06 83.16,66.24 82.59,66.24 82.41,66.06 82.41,64.92 82.23,64.74 81.98,64.74 81.8,64.92 81.8,66.06 81.62,66.24 81.39,66.24 77.56,62.41 75.93,62.41 75.54,62.03 75.54,62.01 75.33,61.79 75.31,61.79 75.31,61.79 74.8,61.79 v4(74.38,61.36)
SOC_DDR3A_EA10: length 68.4
  TOP w0.152: v1(99.03,55.63) 98.78,55.37 DIMM1.117 ; U23.A13 v4(75.18,64.56)
  L3_SIG1 w0.102: v4(75.18,64.56) 75.47,64.56 75.86,64.95 76.51,64.95 79.71,68.15 79.71,70.93 80.88,72.11 81.3,72.11 81.48,71.93 81.48,71.15 81.66,70.97 81.91,70.97 82.09,71.15 82.09,71.93 82.27,72.11 82.68,72.11 82.89,72.31 93.64,72.31 94.53,71.42 98.38,71.42 98.76,71.04 102.69,71.04 102.95,70.79 104.57,70.79 105.16,71.37 105.56,71.37 106.57,70.37 107.25,70.37 108.13,69.49 108.13,69.3 107.95,69.12 107.75,69.12 107.57,68.94 107.57,68.69 107.75,68.51 107.95,68.51 108.18,68.28 108.18,64.34 106.55,62.71 106.55,59.2 105.3,57.95 104.15,57.95 103.97,57.77 103.97,57.56 103.79,57.38 103.54,57.38 103.36,57.56 103.36,57.77 103.18,57.95 102.7,57.95 102.17,57.42 102.17,56.65 101.77,56.25 100.55,56.25 100.4,56.1 100.4,54.88 100.15,54.63 100,54.63 99.79,54.84 99.79,55.98 99.49,56.29 99.19,56.29 99.03,56.13 v1(99.03,55.63)
SOC_DDR3A_EA11: length 68.6
  TOP w0.152: U23.D18 v4(72.78,59.76) ; DIMM1.96 103.28,61.67 102.84,62.1 v1(102.08,62.1)
  L3_SIG1 w0.102: v4(72.78,59.76) 73,59.53 73.01,59.53 73.19,59.36 76.53,59.36 76.96,58.93 76.96,57.25 77.14,57.07 78.66,57.07 78.84,56.89 78.84,56.64 78.66,56.46 77.14,56.46 76.96,56.28 76.96,55.12 79.56,52.53 80.23,52.53 80.41,52.35 80.41,51.69 80.59,51.51 80.84,51.51 81.02,51.69 81.02,52.35 81.2,52.53 81.45,52.53 81.63,52.35 81.63,51.69 81.81,51.51 82.06,51.51 82.24,51.69 82.24,52.35 82.42,52.53 82.67,52.53 82.85,52.35 82.85,51.69 83.03,51.51 83.28,51.51 83.46,51.69 83.46,52.35 83.64,52.53 83.89,52.53 84.07,52.35 84.07,51.69 84.25,51.51 84.5,51.51 84.68,51.69 84.68,52.35 84.86,52.53 85.11,52.53 85.29,52.35 85.29,51.69 85.46,51.51 85.72,51.51 85.9,51.69 85.9,52.35 86.07,52.53 86.33,52.53 86.51,52.35 86.51,51.69 86.68,51.51 86.94,51.51 87.12,51.69 87.12,52.35 87.29,52.53 87.55,52.53 87.72,52.35 87.72,51.69 87.9,51.51 88.16,51.51 88.33,51.69 88.33,52.35 88.51,52.53 88.77,52.53 88.94,52.35 88.94,51.69 89.12,51.51 89.37,51.51 89.55,51.69 89.55,52.35 89.73,52.53 89.98,52.53 90.16,52.35 90.16,51.69 90.34,51.51 90.59,51.51 90.77,51.69 90.77,52.35 90.95,52.53 91.57,52.53 92.04,53 92.04,53.64 92.41,54.01 92.94,54.01 93.12,53.83 93.12,53.52 93.29,53.34 93.55,53.34 93.73,53.52 93.73,53.83 93.9,54.01 94.16,54.01 94.34,53.83 94.34,53.52 94.51,53.34 94.77,53.34 94.94,53.52 94.94,53.83 95.12,54.01 95.8,54.01 96.45,54.67 96.45,60.57 99.31,63.42 102.12,63.42 102.41,63.13 102.41,62.43 v1(102.08,62.1)
SOC_DDR3A_EA12: length 68.5
  TOP w0.152: U23.E18 v4(71.98,59.76) ; DIMM1.95 v1(99.29,61.97)
  L3_SIG1 w0.102: v1(99.29,61.97) 97.48,60.16 97.48,57.69 97.48,51.28 97.27,51.08 91.65,51.08 91.07,50.5 90.08,50.5 89.08,49.5 89.08,48.97 88.9,48.79 88.67,48.79 88.49,48.61 88.49,48.06 88.29,47.85 88.04,47.85 87.88,48.01 87.88,48.61 87.7,48.79 87.45,48.79 87.27,48.61 87.27,48.06 87.07,47.85 86.82,47.85 86.66,48.01 86.66,48.61 86.49,48.79 86.24,48.79 86.06,48.61 86.06,47.93 85.88,47.75 85.63,47.75 85.45,47.93 85.45,48.61 85.27,48.79 85.02,48.79 84.84,48.61 84.84,47.93 84.66,47.75 84.41,47.75 84.23,47.93 84.23,48.61 84.05,48.79 83.8,48.79 83.62,48.61 83.62,47.93 83.44,47.75 83.19,47.75 83.01,47.93 83.01,48.61 82.83,48.79 82.58,48.79 82.4,48.61 82.4,47.93 82.22,47.75 81.97,47.75 81.79,47.93 81.79,48.61 81.61,48.79 81.36,48.79 81.18,48.61 81.18,47.93 81,47.75 80.75,47.75 80.57,47.93 80.57,48.61 80.39,48.79 80.14,48.79 79.96,48.61 79.96,47.93 79.78,47.75 79.53,47.75 79.35,47.93 79.35,48.61 79.17,48.79 78.92,48.79 78.74,48.61 78.74,47.93 78.56,47.75 78.31,47.75 78.13,47.93 78.13,48.36 77.72,48.78 77.72,49.34 77.27,49.79 77.27,50.1 77.45,50.28 78.41,50.28 78.59,50.46 78.59,50.71 78.41,50.89 77.45,50.89 77.27,51.07 77.27,51.32 77.45,51.5 78.41,51.5 78.59,51.68 78.59,51.93 78.41,52.11 77.45,52.11 77.27,52.29 77.27,53.36 76.96,53.67 76.96,53.69 75.54,55.1 75.54,56.41 75.54,58.31 75.33,58.53 73.42,58.53 73.21,58.74 73.21,59.05 72.93,59.33 72.41,59.33 v4(71.98,59.76)
SOC_DDR3A_EA13: length 68.6
  TOP w0.152: DIMM1.130 104.66,51.47 v1(104.29,51.1) ; U23.E12 v4(71.98,65.36)
  L10_SIG4 w0.107: v4(71.98,65.36) 72.2,65.59 72.2,65.6 72.34,65.74 72.34,66.31 72.13,66.53 71.89,66.53 71.61,66.81 71.61,67.05 71.33,67.33 70.16,67.33 70.01,67.18 70.01,59.61 70.29,59.33 70.53,59.33 70.81,59.05 70.81,58.81 71.02,58.59 71.33,58.59 71.54,58.81 71.54,59.11 71.78,59.34 73.67,59.34 73.72,59.39 73.73,59.39 73.94,59.61 73.94,59.62 74.01,59.68 74.01,59.91 74.02,59.92 74.02,60.05 74.15,60.18 75.42,60.18 77.43,58.18 79.43,58.18 80.6,57.01 80.77,57.01 81.69,56.09 83.43,54.34 86.18,54.34 88.55,51.98 91.95,51.98 92.46,52.49 94.63,52.49 95.13,51.99 99.14,51.99 99.86,51.26 101.4,51.26 101.84,50.83 103.94,50.83 105.11,49.66 109.58,49.66 110.06,50.14 110.06,51.26 109.73,51.59 107.34,51.59 107.06,51.31 107.06,50.75 106.67,50.36 105.55,50.36 104.83,51.08 104.32,51.08 v1(104.29,51.1)
SOC_DDR3A_EA14: length 68.7
  TOP w0.152: U23.C18 v4(73.58,59.76) ; v1(102.97,62.91) 103.53,63.47 DIMM1.90
  L3_SIG1 w0.102: v1(102.97,62.91) 102.97,63.75 102.79,63.93 96.01,63.93 95.43,63.36 95.43,62.96 94.93,62.45 94.93,60.77 93.85,59.69 93.59,59.69 93.41,59.51 93.41,58.12 93.23,57.94 92.98,57.94 92.8,58.12 92.8,59.51 92.62,59.69 92.37,59.69 92.19,59.51 92.19,58.12 92.01,57.94 91.76,57.94 91.58,58.12 91.58,59.51 91.4,59.69 91.15,59.69 90.97,59.51 90.97,58.12 90.79,57.94 90.54,57.94 90.36,58.12 90.36,59.51 90.18,59.69 89.93,59.69 89.75,59.51 89.75,58.12 89.57,57.94 89.32,57.94 89.14,58.12 89.14,59.51 88.96,59.69 88.71,59.69 88.53,59.51 88.53,58.12 88.35,57.94 88.1,57.94 87.92,58.12 87.92,59.51 87.74,59.69 87.49,59.69 87.31,59.51 87.31,58.12 87.13,57.94 86.88,57.94 86.7,58.12 86.7,59.51 86.52,59.69 86.27,59.69 86.09,59.51 86.09,58.12 85.91,57.94 85.66,57.94 85.48,58.12 85.48,59.51 85.3,59.69 85.05,59.69 84.87,59.51 84.87,58.12 84.7,57.94 84.44,57.94 84.26,58.12 84.26,59.51 84.09,59.69 83.83,59.69 83.65,59.51 83.65,58.12 83.48,57.94 83.22,57.94 83.04,58.12 83.04,59.51 82.87,59.69 82.61,59.69 82.44,59.51 82.44,58.12 82.26,57.94 82,57.94 81.83,58.12 81.83,59.51 81.65,59.69 80.79,59.69 79.6,60.88 75.86,60.88 75.75,60.78 74.59,60.78 v4(73.58,59.76)
SOC_DDR3A_EA15: length 68.9
  TOP w0.152: v1(101.9,62.92) 103.06,64.07 DIMM1.88 ; U23.E19 v4(71.98,58.96)
  L3_SIG1 w0.102: v1(101.9,62.92) 99.19,60.2 99.08,60.2 98.49,59.61 98.49,57.27 98.49,51.69 98.9,51.28 99.85,51.28 100.25,51.69 100.25,52.43 100.56,52.73 101.32,52.73 101.52,52.53 101.52,50.04 101.34,49.86 100.98,49.86 100.86,49.97 100.86,50.34 100.56,50.65 98.96,50.65 98.53,50.22 98.53,49.54 98.44,49.45 92.25,49.45 91.5,48.7 91.5,46.68 90.29,45.47 83.12,45.47 82.72,45.86 82.72,45.9 82.2,46.42 77.39,46.42 76.69,47.12 76.69,48.18 76.7,48.2 76.7,48.92 76.29,49.33 76.1,49.52 76.1,53.09 75.46,53.73 75.09,53.73 74.74,54.07 74.74,54.31 74.53,54.53 74.22,54.53 73.96,54.78 73.96,56.69 73.73,56.93 73.48,56.93 73.35,57.05 73.35,57.06 73.14,57.27 73.14,58.31 72.93,58.53 72.42,58.53 72.21,58.73 72.2,58.73 v4(71.98,58.96)
SOC_DDR3A_EBA_0: length 68.4
  TOP w0.152: U23.D13 v4(72.78,64.56) ; DIMM1.119 v1(99,54.77)
  L10_SIG4 w0.107: v1(99,54.77) 99.76,55.53 100.98,55.53 101.16,55.71 101.16,56.9 101.34,57.07 101.59,57.07 101.77,56.9 101.77,55.71 101.95,55.53 102.27,55.53 103.04,54.76 103.04,54.52 102.86,54.34 101.4,54.34 101.22,54.16 101.22,53.91 101.41,53.72 103.3,53.72 103.48,53.54 103.48,53.01 103.66,52.83 103.91,52.83 104.09,53.01 104.09,53.54 104.27,53.72 106.35,53.72 106.53,53.54 106.53,51.26 106.3,51.03 105.86,51.03 105.71,51.18 105.71,52.73 105.53,52.91 105.28,52.91 105.1,52.73 105.1,51.87 104.92,51.69 104.12,51.69 102.76,53.05 101.31,53.05 100.61,53.75 100.61,53.98 100.36,54.23 97.82,54.23 97.6,54.01 97.04,54.01 96.86,53.83 96.86,53.69 96.68,53.51 96.43,53.51 96.25,53.69 96.25,53.83 96.07,54.01 93.24,54.01 91.94,55.32 91.94,58.65 91.54,59.06 80.7,59.06 80.06,59.7 78.06,59.7 76.65,61.11 75.73,61.11 75.41,60.79 73.84,60.79 72.83,60.79 72.41,61.21 72.41,64.19 v4(72.78,64.56)
SOC_DDR3A_EBA_1: length 68.9
  TOP w0.152: DIMM1.108 107.07,58.07 107.81,58.8 v1(109.8,58.8) ; U23.C13 v4(73.58,64.56)
  L3_SIG1 w0.102: v1(109.8,58.8) 109.19,59.41 109.19,62.31 110.21,63.33 110.21,64.39 110.39,64.57 110.54,64.57 110.72,64.74 110.72,65 110.54,65.18 110.39,65.18 110.21,65.35 110.21,65.61 110.39,65.78 110.54,65.78 110.72,65.96 110.72,66.22 110.54,66.39 110.39,66.39 110.21,66.57 110.21,66.83 110.39,67 110.54,67 110.72,67.18 110.72,67.44 110.54,67.61 110.39,67.61 110.21,67.79 110.21,69.04 110.63,69.46 110.63,69.83 110.45,70 110.34,70 110.21,70.13 110.21,70.45 110.19,70.47 110.34,70.61 110.45,70.61 110.63,70.79 110.63,71.04 110.45,71.22 110.34,71.22 110.16,71.4 110.16,71.65 110.34,71.83 110.45,71.83 110.63,72.01 110.63,72.42 109.17,73.88 108.13,73.88 107.41,73.16 106.99,73.16 106.69,73.46 106.69,73.82 105.03,75.49 103.5,75.49 102.53,74.51 97.36,74.51 96.9,74.06 94.76,74.06 94.48,74.35 93.5,74.35 92.78,75.07 80.76,75.07 77.14,71.45 77.14,69.3 75.54,67.71 75.54,67.61 75.33,67.39 75.09,67.39 74.81,67.11 74.81,66.87 74.53,66.59 74.29,66.59 74.01,66.31 74.01,65.27 73.58,64.84 v4(73.58,64.56)
SOC_DDR3A_EBA_2: length 68.4
  TOP w0.152: DIMM1.91 v1(95.96,63.17) ; U23.B18 v4(74.38,59.76)
  L3_SIG1 w0.102: v1(95.96,63.17) 97.54,63.17 97.68,63.02 97.68,62.52 97.57,62.41 95.66,62.41 95.43,62.19 95.43,60.56 93.92,59.04 93.92,57.85 93.45,57.38 92.21,57.38 92.04,57.2 92.04,55.68 91.86,55.5 91.61,55.5 91.43,55.68 91.43,57.28 91.25,57.45 91,57.45 90.82,57.28 90.82,55.68 90.64,55.5 90.39,55.5 90.21,55.68 90.21,57.28 90.03,57.45 89.78,57.45 89.6,57.28 89.6,55.68 89.42,55.5 89.17,55.5 88.99,55.68 88.99,57.28 88.81,57.45 88.56,57.45 88.38,57.28 88.38,55.68 88.2,55.5 87.95,55.5 87.77,55.68 87.77,57.25 87.59,57.43 87.34,57.43 87.16,57.25 87.16,55.68 86.98,55.5 86.73,55.5 86.55,55.68 86.55,57.28 86.37,57.45 86.12,57.45 85.94,57.28 85.94,55.68 85.76,55.5 85.51,55.5 85.33,55.68 85.33,57.28 85.15,57.45 84.9,57.45 84.72,57.28 84.72,55.68 84.54,55.5 84.29,55.5 84.11,55.68 84.11,57.28 83.93,57.45 83.68,57.45 83.5,57.28 83.5,55.68 83.32,55.5 83.07,55.5 82.89,55.68 82.89,57.28 82.71,57.45 82.46,57.45 82.28,57.28 82.28,55.68 82.1,55.5 81.85,55.5 81.67,55.68 81.67,57.2 81.49,57.38 81.06,57.38 80.26,58.18 80.26,59.23 79.23,60.27 78.77,60.27 78.59,60.09 78.59,58.45 78.41,58.27 78.16,58.27 77.98,58.45 77.98,60.09 77.69,60.38 74.99,60.38 v4(74.38,59.76)
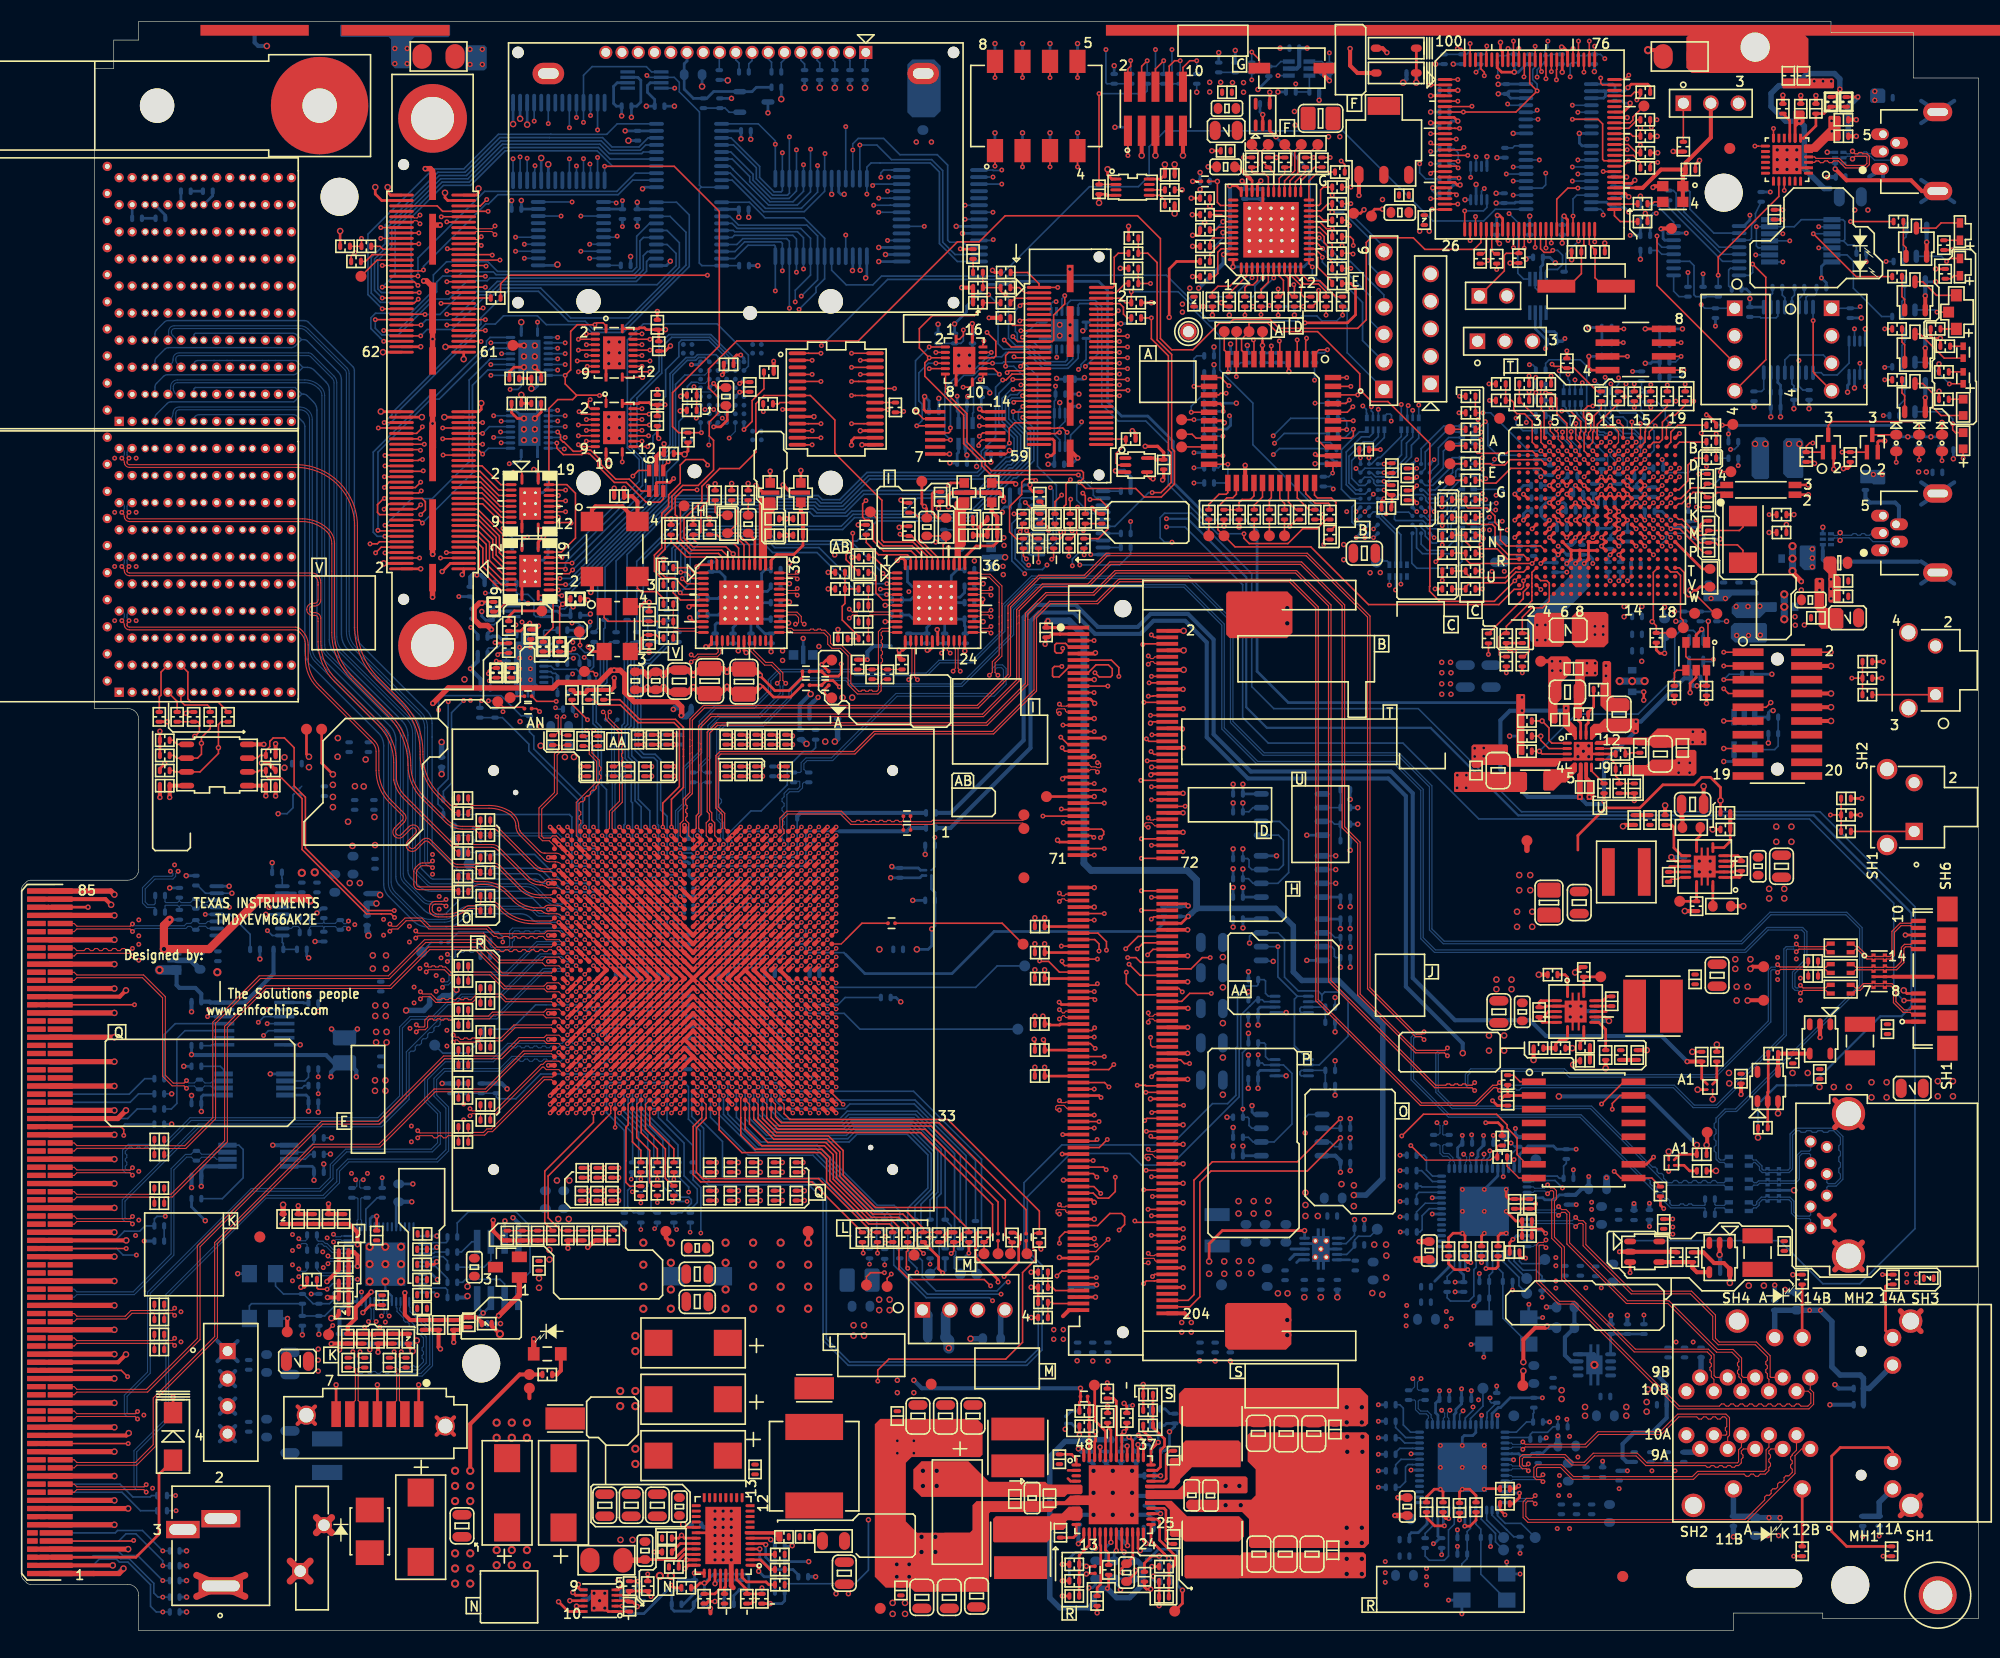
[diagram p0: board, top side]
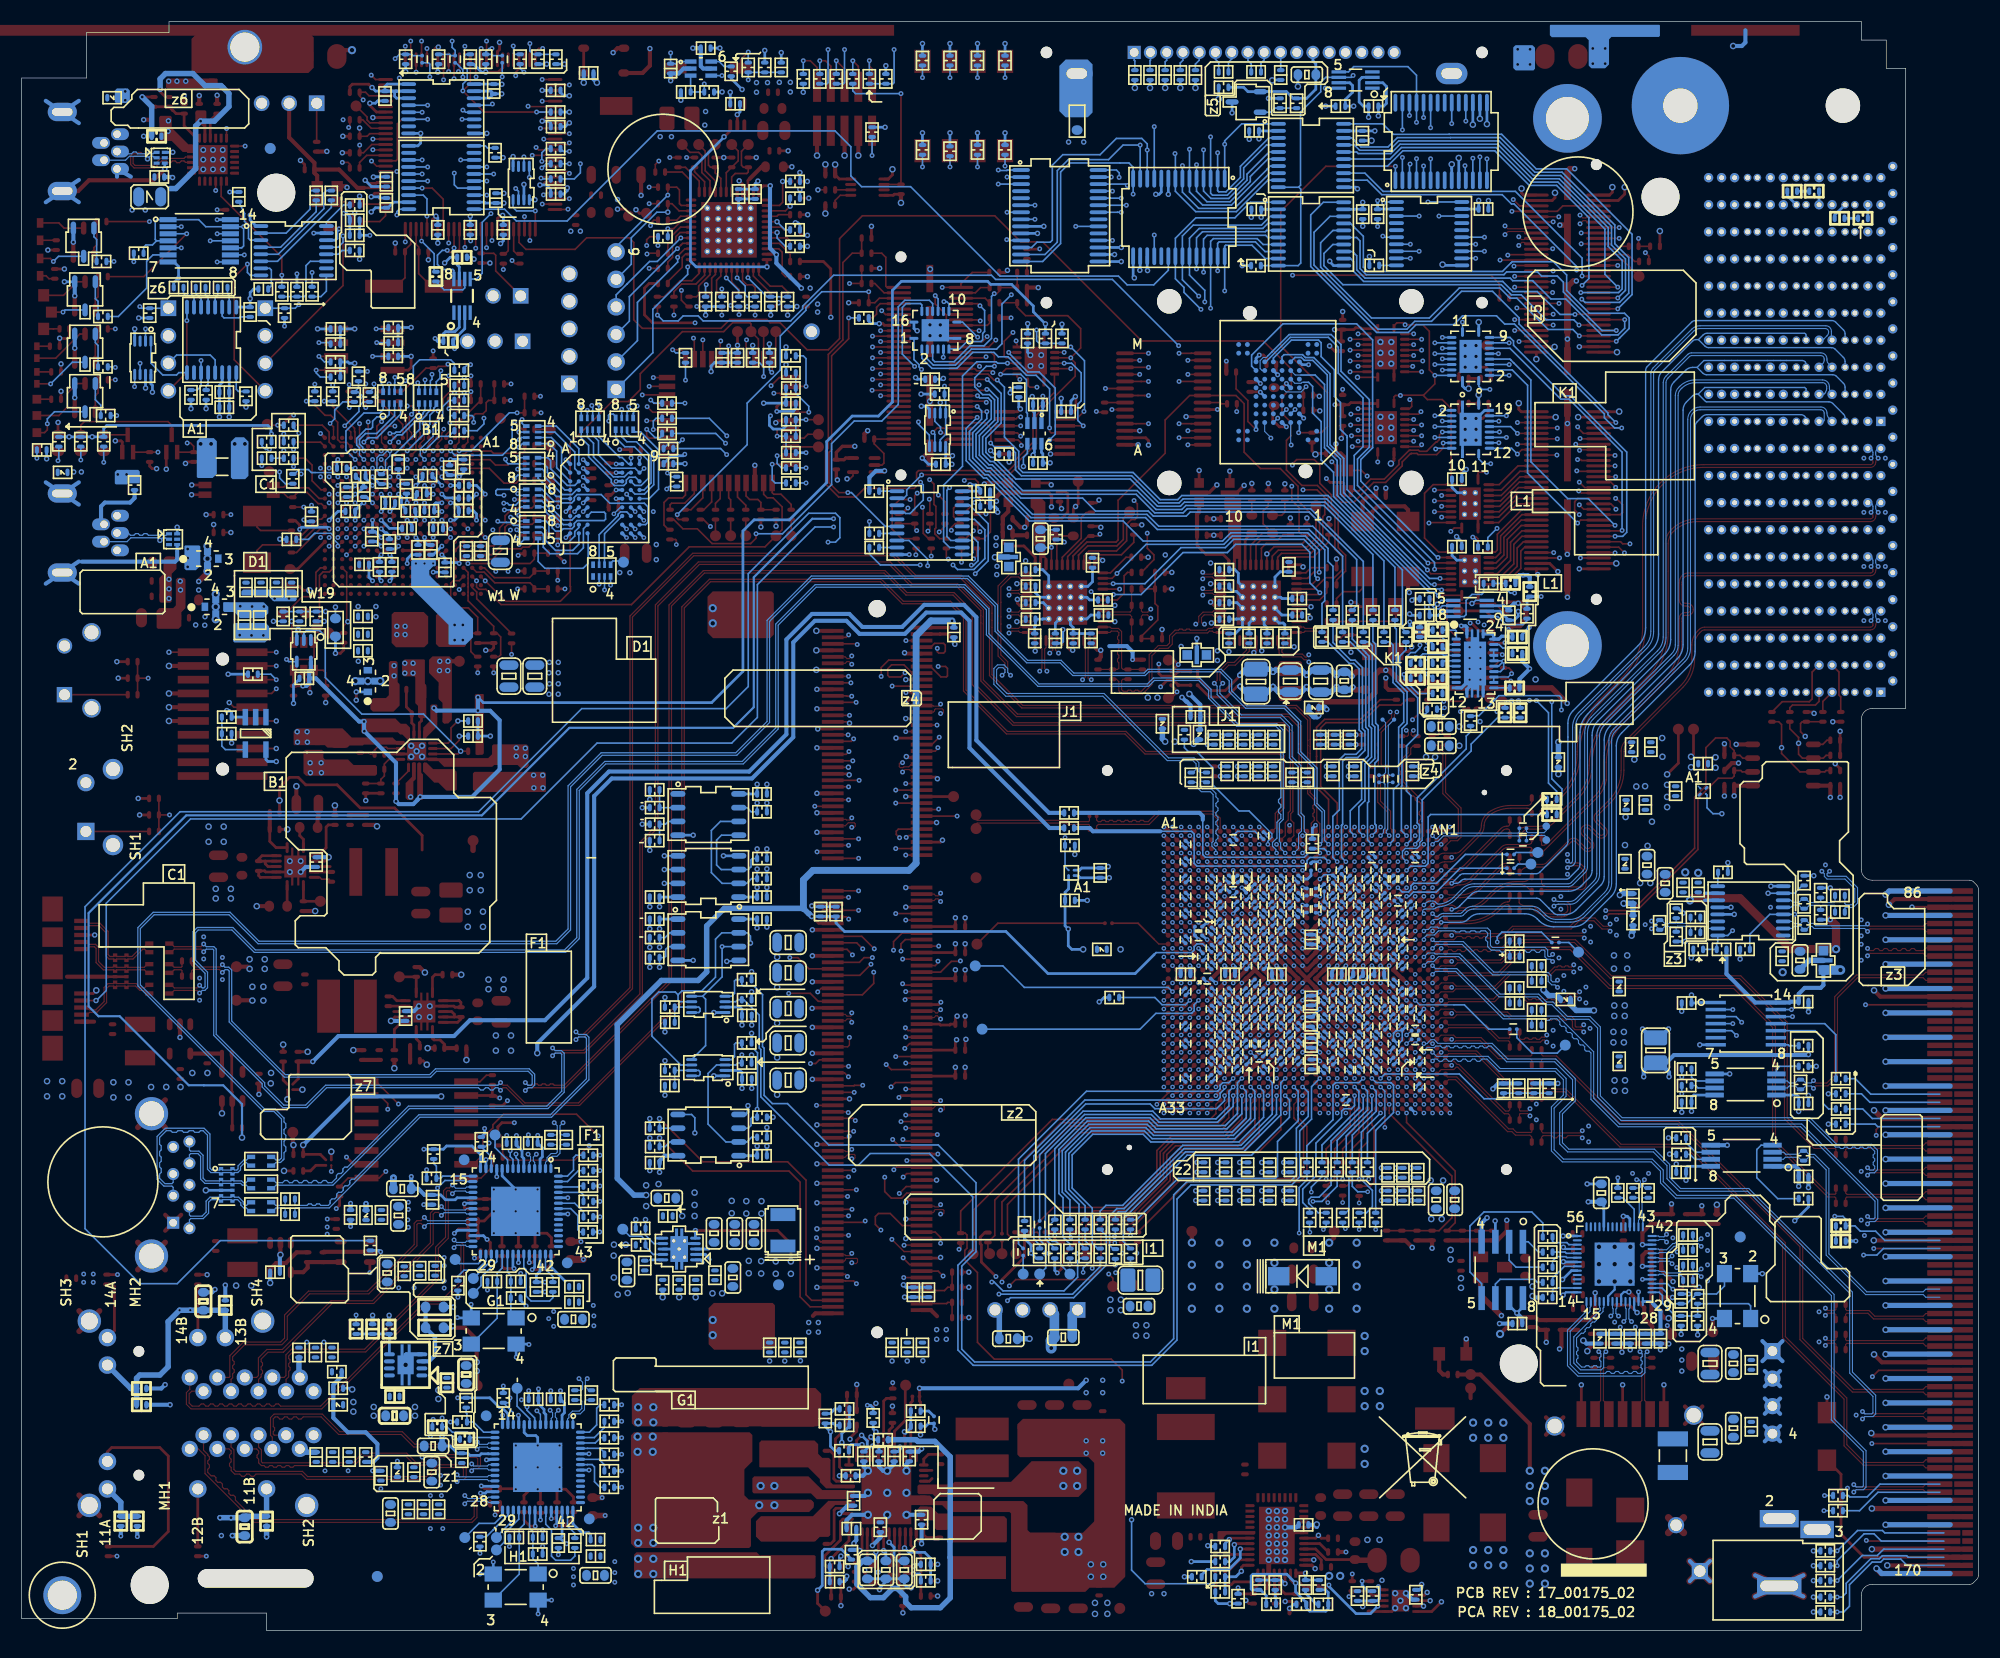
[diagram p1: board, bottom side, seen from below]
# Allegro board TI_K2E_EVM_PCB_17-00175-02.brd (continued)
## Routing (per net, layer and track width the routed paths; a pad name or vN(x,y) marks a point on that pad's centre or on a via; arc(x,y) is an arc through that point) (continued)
SOC_DDR3A_ECAS#: length 69.1
  TOP w0.152: U23.B12 v4(74.38,65.36) ; DIMM1.125 v1(99.93,52.97)
  L3_SIG1 w0.102: v1(99.93,52.97) 101.2,54.24 104.41,54.24 105.05,54.89 105.05,56.05 106.93,57.92 107.54,57.92 108.69,59.07 108.69,62.52 109.7,63.54 109.7,70.18 107.23,72.66 106.78,72.66 105.88,73.56 103.78,73.56 103.63,73.71 97.27,73.71 97.11,73.55 94.55,73.55 94.27,73.84 93.07,73.84 92.41,74.5 81.07,74.5 77.65,71.08 77.65,68.91 75.33,66.59 74.96,66.59 74.75,66.38 74.75,65.74 v4(74.38,65.36)
SOC_DDR3A_ECC0: length 41.2
  TOP w0.152: DIMM1.81 v1(99.93,66.17) ; U23.A23 v4(75.18,55.76)
  L8_SIG3 w0.107: v4(75.18,55.76) 75.51,55.76 75.58,55.7 84.68,55.7 93.09,64.11 96.4,64.11 96.58,63.93 96.58,62.03 96.76,61.85 97.01,61.85 97.19,62.03 97.19,63.93 97.37,64.11 97.62,64.11 97.8,63.93 97.8,62.03 97.98,61.85 98.23,61.85 98.41,62.03 98.41,63.93 98.59,64.11 99.47,64.11 99.93,64.57 v1(99.93,66.17)
SOC_DDR3A_ECC1: length 41
  TOP w0.152: U23.D22 v4(72.78,56.56) ; DIMM1.72 v1(103.35,71.27)
  L8_SIG3 w0.107: v4(72.78,56.56) 73.21,56.99 73.21,58.31 73.49,58.59 73.73,58.59 74.01,58.87 74.01,59.11 74.22,59.33 74.47,59.33 74.74,59.61 74.74,59.85 75.02,60.13 79.65,60.13 80.09,60.56 82.55,60.56 88.07,66.08 88.07,66.62 92.55,71.1 97.05,71.1 97.09,71.06 103.15,71.06 v1(103.35,71.27)
SOC_DDR3A_ECC2: length 41.1
  TOP w0.152: U23.E22 v4(71.98,56.56) ; DIMM1.71 v1(99,71.57)
  L8_SIG3 w0.107: v4(71.98,56.56) 72.41,56.99 72.41,59.91 72.42,59.92 72.42,60.22 72.72,60.53 75.69,60.53 75.86,60.7 79.5,60.7 79.88,61.07 82.34,61.07 87.56,66.29 87.56,66.83 92.34,71.61 94.41,71.61 94.58,71.79 94.58,72.24 94.76,72.42 95.02,72.42 95.19,72.24 95.19,71.79 95.37,71.61 95.63,71.61 95.8,71.79 95.8,72.24 95.98,72.42 96.24,72.42 96.41,72.24 96.41,71.79 96.59,71.61 96.84,71.61 97.02,71.79 97.02,72.24 97.2,72.42 97.45,72.42 97.63,72.24 97.63,71.79 97.81,71.61 98.96,71.61 v1(99,71.57)
SOC_DDR3A_ECC3: length 41.3
  TOP w0.152: DIMM1.69 v1(99.93,72.17) ; U23.E21 v4(71.98,57.36)
  L8_SIG3 w0.107: v4(71.98,57.36) 71.61,57.73 71.61,60.05 72.31,60.76 75.56,60.76 76.01,61.2 79.29,61.2 79.67,61.58 82.13,61.58 87.05,66.5 87.05,67.04 93.47,73.45 96.39,73.45 96.51,73.33 96.51,73.05 96.64,72.92 97,72.92 97.12,73.05 97.12,73.33 97.25,73.45 98.06,73.45 99.34,72.17 v1(99.93,72.17)
SOC_DDR3A_ECC4: length 41.1
  TOP w0.152: DIMM1.74 v1(103.35,68.27) ; U23.C22 v4(73.58,56.56)
  L8_SIG3 w0.107: v4(73.58,56.56) 74.01,56.99 74.01,58.31 74.29,58.59 74.53,58.59 74.74,58.81 74.74,58.83 74.81,58.89 74.81,59.11 75.02,59.33 79.57,59.33 80.3,60.05 82.76,60.05 88.58,65.87 88.58,66.41 92.76,70.59 96.84,70.59 96.89,70.54 101.78,70.54 103.35,68.96 v1(103.35,68.27)
SOC_DDR3A_ECC5: length 41
  TOP w0.152: U23.B21 v4(74.38,57.36) ; v1(104.27,65.66) 104.48,65.87 DIMM1.82
  L8_SIG3 w0.107: v4(74.38,57.36) 74.8,57.78 75.84,57.78 75.86,57.8 80.2,57.8 80.93,58.53 83.39,58.53 90.1,65.24 90.1,65.78 93.39,69.07 96.2,69.07 96.8,68.47 96.8,66.73 97.43,66.09 99.04,66.09 99.63,66.68 100.17,66.68 100.56,66.29 100.56,66.07 100.97,65.66 101.93,65.66 102.11,65.84 102.11,66.06 102.29,66.24 102.54,66.24 102.72,66.06 102.72,65.84 102.9,65.66 v1(104.27,65.66)
SOC_DDR3A_ECC6: length 41.2
  TOP w0.152: DIMM1.80 v1(103.35,66.47) ; U23.A20 v4(75.18,58.16)
  L8_SIG3 w0.107: v4(75.18,58.16) 75.71,58.16 75.86,58.31 79.99,58.31 80.72,59.04 83.18,59.04 89.59,65.45 89.59,65.99 93.18,69.58 96.42,69.58 97.31,68.68 97.31,67.41 97.44,67.28 102.73,67.28 102.92,67.08 104.62,67.08 104.75,66.95 104.75,66.59 104.62,66.47 v1(103.35,66.47)
SOC_DDR3A_ECC7: length 41
  TOP w0.152: U23.A21 v4(75.18,57.36) ; DIMM1.83 v1(99,65.57)
  L8_SIG3 w0.107: v1(99,65.57) 99,64.96 98.65,64.62 98.28,64.62 98.1,64.8 98.1,65.38 97.92,65.56 97.67,65.56 97.49,65.38 97.49,64.8 97.31,64.62 97.06,64.62 96.88,64.8 96.88,65.43 96.7,65.61 96.45,65.61 96.27,65.43 96.27,64.8 96.09,64.62 95.4,64.62 95.28,64.74 95.28,66.03 95.43,66.19 96.17,66.19 96.29,66.3 96.29,68.26 95.99,68.56 93.6,68.56 91.85,66.8 91.85,64.95 90.73,63.83 89.68,63.83 89.65,63.8 89.38,63.8 82.88,57.3 75.24,57.3 v4(75.18,57.36)
SOC_DDR3A_ECKE_0: length 68.5
  TOP w0.152: DIMM1.87 99.34,64.37 100.13,63.58 v1(100.13,62.79) ; U23.C20 v4(73.58,58.16)
  L3_SIG1 w0.102: v4(73.58,58.16) 73.58,57.88 73.83,57.63 73.94,57.51 73.94,57.27 74.22,56.99 74.46,56.99 74.74,56.71 74.74,54.87 75.02,54.59 75.34,54.59 76.33,53.6 76.33,53.58 76.76,53.15 76.76,49.58 77.21,49.13 77.21,47.99 77.2,47.97 77.2,47.54 77.5,47.24 83.18,47.24 83.36,47.07 83.36,46.3 83.53,46.13 83.79,46.13 83.97,46.3 83.97,47.07 84.14,47.24 84.4,47.24 84.58,47.07 84.58,46.3 84.75,46.13 85.01,46.13 85.18,46.3 85.18,47.07 85.36,47.24 85.62,47.24 85.79,47.07 85.79,46.3 85.97,46.13 86.23,46.13 86.4,46.3 86.4,47.07 86.58,47.24 86.83,47.24 87.01,47.07 87.01,46.3 87.19,46.13 87.44,46.13 87.62,46.3 87.62,47.07 87.8,47.24 88.05,47.24 88.23,47.07 88.23,46.3 88.41,46.13 88.64,46.13 88.82,46.3 88.82,47.04 88.97,47.19 89.22,47.19 89.43,46.99 89.43,46.3 89.61,46.13 90.04,46.13 90.25,46.33 90.25,48.13 90.42,48.31 90.82,48.31 91,48.49 91,48.74 90.82,48.92 90.42,48.92 90.25,49.1 90.25,49.48 90.75,49.99 91.89,49.99 92.06,50.17 92.06,50.39 92.24,50.57 92.5,50.57 92.67,50.39 92.67,50.17 92.85,49.99 93.5,49.99 93.68,50.17 93.68,50.39 93.86,50.57 94.11,50.57 94.29,50.39 94.29,50.17 94.47,49.99 94.72,49.99 94.9,50.17 94.9,50.39 95.08,50.57 95.33,50.57 95.51,50.39 95.51,50.17 95.69,49.99 95.92,49.99 96.1,50.17 96.1,50.39 96.27,50.57 96.53,50.57 96.71,50.39 96.71,50.17 96.88,49.99 97.44,49.99 98.09,50.65 98.09,51.37 97.98,51.48 97.98,57.48 97.98,59.82 100.13,61.97 v1(100.13,62.79)
SOC_DDR3A_ECKE_1: length 68.7
  TOP w0.152: v1(99.44,62.71) 99.44,63.37 99.05,63.77 DIMM1.89 ; U23.A19 v4(75.18,58.96)
  L3_SIG1 w0.102: v4(75.18,58.96) 75.46,58.96 75.56,58.86 75.56,58.69 76.28,57.98 76.28,55.09 77.46,53.91 77.72,53.64 79.1,52.27 79.1,49.48 79.28,49.3 79.53,49.3 79.71,49.48 79.71,50.83 79.89,51 80.14,51 80.32,50.83 80.32,49.48 80.49,49.3 80.75,49.3 80.93,49.48 80.93,50.83 81.1,51 81.36,51 81.54,50.83 81.54,49.48 81.71,49.3 81.97,49.3 82.14,49.48 82.14,50.83 82.32,51 82.58,51 82.75,50.83 82.75,49.48 82.93,49.3 83.19,49.3 83.36,49.48 83.36,50.83 83.54,51 83.8,51 83.97,50.83 83.97,49.48 84.15,49.3 84.4,49.3 84.58,49.48 84.58,50.83 84.76,51 85.01,51 85.19,50.83 85.19,49.48 85.37,49.3 85.62,49.3 85.8,49.48 85.8,50.83 85.98,51 86.23,51 86.41,50.83 86.41,49.48 86.59,49.3 86.84,49.3 87.02,49.48 87.02,50.83 87.2,51 87.45,51 87.63,50.83 87.63,49.48 87.81,49.3 88.06,49.3 88.24,49.48 88.24,50.83 88.42,51 88.72,51 88.9,50.83 88.9,50.65 89.08,50.47 89.33,50.47 89.51,50.65 89.51,50.83 89.69,51 90.86,51 92.64,52.79 94.93,52.79 95.11,52.61 95.11,51.89 95.28,51.71 95.54,51.71 95.72,51.89 95.72,52.61 95.89,52.79 96.35,52.79 96.97,53.41 96.97,60.37 99.31,62.71 v1(99.44,62.71)
SOC_DDR3A_ECKN_0: length 68.8
  TOP w0.102: U23.B14 v4(74.38,63.76) ; v1(95.78,56.44) 96.09,56.74 96.22,56.74 96.39,56.57 DIMM1.113
  L10_SIG4 w0.102: v1(95.78,56.44) 95.98,56.63 96.41,56.63 98.17,58.39 98.17,59.84 98.41,60.08 102.36,60.08 103.65,61.37 104.04,61.37 106.12,63.46 106.12,68.71 105.54,69.29 102.84,69.29 102.59,69.04 102.59,67.61 101.67,66.69 101.67,63.77 101.49,63.59 101.24,63.59 101.06,63.77 101.06,65.08 100.71,65.43 99.82,65.43 98.85,64.46 98.05,64.46 97.7,64.11 97.7,61.34 97.52,61.15 97.27,61.15 97.09,61.33 97.09,64.11 96.74,64.46 92.97,64.46 90.38,61.88 82.03,61.88 79.95,63.96 75.52,63.96 75.25,63.68 74.45,63.68 v4(74.38,63.76)
SOC_DDR3A_ECKN_1: length 68.8
  TOP w0.102: DIMM1.114 104.59,56.27 104.42,56.44 104.09,56.44 103.98,56.34 v1(103.98,56.13) ; U23.A15 v4(75.18,62.96)
  L10_SIG4 w0.102: v4(75.18,62.96) 75.25,62.89 75.51,62.89 75.65,63.02 77.45,63.02 78.85,61.62 80.86,61.62 81.5,60.98 90.76,60.98 92.49,62.71 95,62.71 95.3,62.41 95.3,60.02 95.45,59.87 96.99,59.87 97.27,59.58 97.27,58.93 97.01,58.67 95.35,58.67 95.17,58.49 95.17,56.37 95.61,55.93 96.75,55.93 98.62,57.8 99.32,57.8 99.68,58.16 99.68,59.15 100.01,59.47 102.72,59.47 103.99,60.74 106.31,60.74 106.73,61.16 106.73,63.08 107.04,63.39 108.48,63.39 108.79,63.08 108.79,61.07 109.12,60.74 110.69,60.74 111.72,59.71 111.72,59.71 111.76,59.67 111.76,57.76 110.42,56.42 104.27,56.42 v1(103.98,56.13)
SOC_DDR3A_ECKP_0: length 68.8
  TOP w0.102: v1(95.78,57.3) 96.09,57 96.22,57 96.39,57.17 DIMM1.111 ; U23.B15 v4(74.38,62.96)
  L10_SIG4 w0.102: v4(74.38,62.96) 74.37,62.96 74.15,63.18 74.15,63.33 74.21,63.39 75.37,63.39 75.64,63.67 79.83,63.67 81.91,61.59 90.5,61.59 93.09,64.17 96.62,64.17 96.8,63.99 96.8,61.21 97.15,60.86 97.64,60.86 98,61.22 98,63.99 98.17,64.17 98.97,64.17 99.94,65.14 100.59,65.14 100.77,64.96 100.77,63.65 101.12,63.3 101.62,63.3 101.97,63.65 101.97,66.57 102.88,67.49 102.88,68.92 102.97,69 105.42,69 105.83,68.59 105.83,63.58 103.92,61.66 103.52,61.66 102.23,60.38 98.29,60.38 97.88,59.96 97.88,58.51 96.29,56.92 95.84,56.92 95.78,56.97 v1(95.78,57.3)
SOC_DDR3A_ECKP_1: length 68.8
  TOP w0.102: U23.A16 v4(75.18,62.16) ; DIMM1.112 104.59,56.87 104.42,56.7 104.09,56.7 103.98,56.8 v1(103.98,57)
  L10_SIG4 w0.102: v4(75.18,62.16) 74.9,62.16 74.83,62.23 74.83,62.46 74.96,62.59 75.63,62.59 75.77,62.73 77.33,62.73 78.73,61.33 80.73,61.33 81.38,60.68 90.88,60.68 92.61,62.41 94.88,62.41 95,62.29 95,59.9 95.33,59.57 96.87,59.57 96.98,59.46 96.98,59.05 96.89,58.96 95.23,58.96 94.88,58.61 94.88,56.25 95.49,55.64 96.87,55.64 98.74,57.51 99.44,57.51 99.97,58.04 99.97,59.03 100.13,59.18 102.84,59.18 104.11,60.45 106.43,60.45 107.02,61.04 107.02,62.95 107.16,63.09 108.36,63.09 108.5,62.95 108.5,60.95 109,60.45 110.57,60.45 111.43,59.59 111.43,59.59 111.47,59.55 111.47,57.88 110.3,56.71 104.27,56.71 v1(103.98,57)
SOC_DDR3A_ECS_0#: length 69
  TOP w0.152: U23.A12 v4(75.18,65.36) ; DIMM1.127 v1(99,52.37)
  L3_SIG1 w0.102: v4(75.18,65.36) 75.18,65.64 78.16,68.62 78.16,70.87 81.28,74 92.2,74 92.86,73.33 94.06,73.33 94.95,72.44 96.39,72.44 96.64,72.69 102.95,72.69 103.05,72.59 103.54,72.59 103.99,73.04 105.67,73.04 106.71,72.01 106.71,71.67 106.99,71.39 107.74,71.39 109.19,69.93 109.19,63.75 108.18,62.73 108.18,59.28 107.33,58.43 106.72,58.43 104.55,56.26 104.55,55.6 104.29,55.35 101.59,55.35 99.42,53.18 99.42,52.76 99.75,52.43 99.75,51.92 99.64,51.82 99.13,51.82 99,51.94 v1(99,52.37)
SOC_DDR3A_ECS_1#: length 68.4
  TOP w0.152: v1(100.8,52.23) 100.34,51.77 DIMM1.129 ; U23.C12 v4(73.58,65.36)
  L10_SIG4 w0.107: v4(73.58,65.36) 73.41,65.52 73.4,65.53 73.2,65.73 72.62,65.73 72.41,65.51 72.41,65.27 72.06,64.93 71.82,64.93 71.58,65.17 71.58,66.3 71.35,66.53 71,66.53 70.81,66.33 70.81,59.61 71.02,59.39 71.33,59.39 71.61,59.67 71.61,59.91 72.08,60.38 74.01,60.38 75.57,60.38 75.86,60.09 76.23,60.09 77.64,58.68 79.64,58.68 80.81,57.51 80.98,57.51 82.05,56.45 83.2,55.3 83.77,55.3 83.95,55.12 83.95,55.03 84.13,54.85 84.38,54.85 84.56,55.03 84.56,55.12 84.74,55.3 84.99,55.3 85.17,55.12 85.17,55.03 85.35,54.85 85.6,54.85 85.78,55.03 85.78,55.12 85.96,55.3 86.21,55.3 86.39,55.12 86.39,55.03 86.57,54.85 86.82,54.85 87,55.03 87,55.12 87.18,55.3 87.49,55.3 87.66,55.12 87.66,53.6 87.84,53.42 88.09,53.42 88.27,53.6 88.27,55.12 88.45,55.3 88.7,55.3 88.88,55.12 88.88,52.82 89.06,52.64 89.31,52.64 89.49,52.82 89.49,55.12 89.67,55.3 90.67,55.3 90.93,55.04 90.93,54.8 90.75,54.62 90.17,54.62 89.99,54.44 89.99,54.18 90.16,54.01 90.75,54.01 90.93,53.83 90.93,52.67 91.11,52.48 91.74,52.48 92.25,53 94.84,53 95.34,52.49 98.11,52.49 98.4,52.78 99.13,52.78 100.14,51.77 101.61,51.77 102.05,51.33 102.84,51.33 103.1,51.59 103.1,51.99 102.71,52.37 101.47,52.37 101.33,52.23 v1(100.8,52.23)
SOC_DDR3A_EDM_0: length 48.4
  TOP w0.152: DIMM1.11 100.58,89.57 101.27,88.87 v1(101.27,88.06) ; U23.A3 v4(75.18,72.56)
  L8_SIG3 w0.107: v1(101.27,88.06) 101.37,88.16 102.51,88.16 102.69,87.99 102.69,87.64 102.51,87.47 101.96,87.47 101.78,87.29 101.78,87.04 101.96,86.86 102.51,86.86 102.69,86.68 102.69,84.4 102.59,84.3 102.11,84.3 101.93,84.48 101.93,86.26 101.75,86.44 101.5,86.44 101.32,86.26 101.32,84.48 101.14,84.3 99.85,84.3 99.2,83.65 96.73,83.65 96.2,83.11 94.42,83.11 84.66,73.36 84.66,73.05 84.26,72.64 75.26,72.64 v4(75.18,72.56)
SOC_DDR3A_EDM_1: length 45.3
  TOP w0.152: U23.E3 v4(71.98,72.56) ; DIMM1.28 v1(104.19,84.47)
  L10_SIG4 w0.107: v4(71.98,72.56) 71.98,72.84 72.34,73.21 72.34,74.25 74.15,76.05 81.94,76.05 94.25,88.37 98.46,88.37 98.88,88.78 101.19,88.78 102.99,86.97 104.01,86.97 104.6,86.39 104.6,84.88 v1(104.19,84.47)
SOC_DDR3A_EDM_2: length 41.8
  TOP w0.152: DIMM1.44 104.3,79.67 v2(104.29,79.68) ; U23.D8 v4(72.78,68.56)
  L8_SIG3 w0.107: v2(104.29,79.68) 104.1,79.48 104.01,79.48 103.71,79.19 103.71,78.77 103.81,78.67 103.81,78.26 103.51,77.96 103.16,77.96 100.3,75.11 97.62,75.11 97.44,74.93 97.44,74.83 97.27,74.65 97.01,74.65 96.84,74.83 96.84,74.93 96.66,75.11 95.67,75.11 95.35,74.79 93.36,74.79 84.44,65.86 80.53,65.86 80.4,65.99 75.87,65.99 75.27,66.59 75.02,66.59 74.81,66.81 74.81,67.05 74.53,67.33 74.29,67.33 74.01,67.61 74.01,67.85 73.73,68.13 73.41,68.13 72.97,68.56 v4(72.78,68.56)
SOC_DDR3A_EDM_3: length 41.7
  TOP w0.152: U23.E8 v4(71.98,68.56) ; DIMM1.59 v1(94.26,75.17)
  L10_SIG4 w0.107: v1(94.26,75.17) 94.28,75.19 94.28,76.02 95.28,77.01 97.59,77.01 97.77,77.2 97.77,77.85 97.46,78.16 97.46,78.99 97.31,79.15 97.06,79.15 96.85,78.94 96.85,78.03 96.68,77.85 95.23,77.85 86.97,69.6 81.29,69.6 80.88,70 76.99,70 76.56,69.58 75.86,69.58 75.71,69.73 74.22,69.73 74.01,69.51 74.01,69.21 73.73,68.93 72.34,68.93 v4(71.98,68.56)
SOC_DDR3A_EDM_4: length 45.5
  TOP w0.152: U23.E26 v4(71.98,53.36) ; DIMM1.140 v1(107.24,48.47)
  L10_SIG4 w0.107: v1(107.24,48.47) 107.24,48.29 105.64,46.69 104.17,46.69 104.01,46.52 103.59,46.52 103.05,45.97 103.05,45.34 101.27,43.56 99.81,43.56 99.24,42.99 98.89,42.99 98.49,42.58 87.54,42.58 83.72,46.4 83.72,46.4 82.9,47.22 82.8,47.32 81.27,47.32 79.3,49.28 79.3,50.7 77.2,52.8 75.86,52.8 75.67,52.99 72.34,52.99 v4(71.98,53.36)
SOC_DDR3A_EDM_5: length 41.3
  TOP w0.152: DIMM1.157 v1(98.9,43.37) ; U23.D26 v4(72.78,53.36)
  L8_SIG3 w0.107: v4(72.78,53.36) 73.18,52.96 73.18,52.3 73.35,52.13 75.85,52.13 75.86,52.12 76.42,52.12 76.75,51.79 77.03,51.79 77.36,52.12 77.64,52.12 77.97,51.79 78.25,51.79 78.58,52.12 78.86,52.12 79.19,51.79 79.46,51.79 79.8,52.12 80.07,52.12 80.4,51.79 80.68,51.79 81.01,52.12 81.29,52.12 81.62,51.79 81.9,51.79 82.23,52.12 82.51,52.12 82.84,51.79 83.12,51.79 83.45,52.12 83.73,52.12 84.06,51.79 84.34,51.79 84.67,52.12 84.95,52.12 85.28,51.79 85.56,51.79 85.89,52.12 86.17,52.12 86.5,51.79 86.78,51.79 87.11,52.12 87.39,52.12 87.72,51.79 88,51.79 88.33,52.12 88.61,52.12 88.94,51.79 89.22,51.79 89.55,52.12 91.5,52.12 91.76,51.87 91.76,51.61 91.28,51.14 91.28,50.88 91.46,50.71 91.71,50.71 92.19,51.18 92.44,51.18 92.62,51 92.62,50.75 92.14,50.27 92.14,50.02 92.32,49.84 92.57,49.84 93.05,50.32 93.3,50.32 93.52,50.1 93.52,49.85 93.26,49.59 93.26,49.34 93.44,49.16 93.7,49.16 93.95,49.42 94.21,49.42 94.6,49.02 94.6,46.57 95.89,45.29 96.31,45.29 98.23,43.37 v1(98.9,43.37)
SOC_DDR3A_EDM_6: length 46.1
  TOP w0.152: U23.E31 v4(71.98,49.36) ; DIMM1.172 v1(103.96,38.87)
  L10_SIG4 w0.107: v1(103.96,38.87) 103.77,38.68 103.77,38.1 102.74,37.08 102.57,37.08 102.27,37.38 102.1,37.38 101.98,37.26 101.98,37.09 102.29,36.79 102.29,36.62 102.12,36.45 101.08,36.45 100.75,36.78 94.19,36.78 92.76,38.21 87.39,38.21 78.57,38.21 73.89,42.9 73.89,47.55 74.01,47.67 74.01,47.86 73.68,48.19 73.42,48.19 73.21,48.41 73.21,49.45 72.93,49.73 72.34,49.73 v4(71.98,49.36)
SOC_DDR3A_EDM_7: length 47.1
  TOP w0.152: DIMM1.189 98.64,33.77 99.24,34.37 v1(99.24,34.39) ; U23.A31 74.78,49.61 v4(75.82,48.56)
  L8_SIG3 w0.107: v4(75.82,48.56) 76.41,48.56 76.45,48.6 84.95,48.6 93.87,39.68 97.81,39.68 98.53,38.96 99.19,38.96 99.57,39.34 99.88,39.34 100.03,39.2 100.03,38.91 100.18,38.76 100.39,38.76 100.53,38.91 100.53,39.2 100.68,39.34 100.89,39.34 101.04,39.2 101.04,38.91 101.19,38.76 101.4,38.76 101.55,38.91 101.55,39.2 101.7,39.34 101.91,39.34 102.06,39.2 102.06,38.91 102.21,38.76 102.42,38.76 102.57,38.91 102.57,39.2 102.72,39.34 103.17,39.34 103.44,39.08 103.44,37.79 103.56,37.67 104.07,37.67 104.19,37.56 104.19,37.39 104.07,37.27 103.56,37.27 103.44,37.15 103.44,35.98 102.23,34.77 99.62,34.77 v1(99.24,34.39)
SOC_DDR3A_EDM_8: length 41.2
  TOP w0.152: U23.B20 v4(74.38,58.16) ; DIMM1.76 v1(104.28,67.67)
  L8_SIG3 w0.107: v4(74.38,58.16) 74.6,58.39 74.61,58.39 74.75,58.53 75.4,58.53 75.69,58.82 79.78,58.82 80.51,59.55 82.97,59.55 89.08,65.66 89.08,66.2 92.97,70.08 96.63,70.08 97.82,68.89 97.82,68.12 98.15,67.78 100.06,67.78 100.24,67.96 100.24,68.45 100.42,68.63 100.67,68.63 100.85,68.45 100.85,67.96 101.03,67.78 101.28,67.78 101.46,67.96 101.46,68.45 101.64,68.63 101.89,68.63 102.07,68.45 102.07,67.96 102.25,67.78 102.97,67.78 103.01,67.74 103.08,67.67 v1(104.28,67.67)
SOC_DDR3A_EDQ0: length 48.2
  TOP w0.152: U23.E2 v4(71.98,73.36) ; v1(96.09,90.65) 96.09,90.35 95.96,90.22 95.5,90.22 95.35,90.37 95.35,90.96 95.5,91.11 96.34,91.11 96.68,90.77 DIMM1.7
  L8_SIG3 w0.107: v1(96.09,90.65) 96.3,90.86 98.13,90.86 98.3,90.69 98.3,90.18 98.12,90 95.59,90 94.99,89.4 94.99,88.67 88.42,82.09 87.71,82.09 87.45,81.84 87.1,81.84 86.84,82.09 86.49,82.09 86.23,81.84 85.88,81.84 85.62,82.09 85.27,82.09 85.02,81.84 84.66,81.84 84.41,82.09 83.86,82.09 83.69,81.92 83.69,80.79 83.96,80.51 83.96,80.18 83.69,79.9 83.69,79.57 83.96,79.29 83.96,78.96 83.69,78.69 83.69,78.06 81.77,76.15 78.94,76.15 78.1,76.99 77.63,76.99 77.46,77.17 77.46,77.52 77.28,77.7 77.03,77.7 76.85,77.52 76.85,77.17 76.67,76.99 73.03,76.99 71.53,75.49 71.53,74.47 71.58,74.42 71.58,73.76 v4(71.98,73.36)
SOC_DDR3A_EDQ1: length 48.3
  TOP w0.152: v1(99.06,88.4) 99.45,88.01 100.51,88.01 100.66,88.16 100.66,88.77 100.3,89.13 99.16,89.13 98.4,88.37 DIMM1.15 ; U23.D1 v4(72.78,74.16)
  L8_SIG3 w0.107: v1(99.06,88.4) 99.09,88.42 99.09,88.82 98.93,88.98 97.99,88.98 97.82,88.8 97.82,87.72 97.64,87.55 97.38,87.55 97.21,87.72 97.21,88.8 97.03,88.98 96.77,88.98 96.52,88.72 96.52,88.04 96.18,87.7 96.18,87.69 89.03,80.55 88.79,80.31 88.21,80.31 88.14,80.24 88.14,79.83 88.04,79.73 87.68,79.73 87.58,79.83 87.58,80.19 87.45,80.31 87.08,80.31 86.9,80.14 86.9,79.81 86.72,79.63 86.47,79.63 86.29,79.81 86.29,80.14 86.11,80.31 85.75,80.31 85.48,80.05 85.48,77.7 85.04,77.26 85.04,77.01 85.14,76.9 85.14,76.65 84.96,76.47 84.71,76.47 84.61,76.57 84.36,76.57 84.18,76.4 84.18,76.14 84.28,76.04 84.28,75.79 84.1,75.61 83.85,75.61 83.75,75.71 83.49,75.71 83.31,75.53 83.31,75.28 83.42,75.18 83.42,74.92 83.24,74.75 82.99,74.75 82.88,74.85 82.63,74.85 82.41,74.63 78.31,74.63 77.47,75.46 73.66,75.46 73.05,74.86 73.05,74.47 72.78,74.19 v4(72.78,74.16)
SOC_DDR3A_EDQ2: length 48.3
  TOP w0.152: U23.F2 v4(71.18,73.36) ; DIMM1.6 103.54,91.07 v1(103.48,91.01)
  L8_SIG3 w0.107: v4(71.18,73.36) 70.51,74.02 70.51,75.91 72.61,78 74.73,78 76.63,79.91 76.63,80.43 77.34,81.14 77.34,81.62 78.89,83.16 88.05,83.16 93.98,89.09 93.98,89.82 94.97,90.82 94.97,91.48 95.37,91.88 99.19,91.88 103.56,91.88 104.04,91.4 104.04,91.11 103.94,91.01 v1(103.48,91.01)
SOC_DDR3A_EDQ3: length 48.5
  TOP w0.152: U23.E1 v4(71.98,74.16) ; DIMM1.16 v1(104.28,88.07)
  L8_SIG3 w0.107: v4(71.98,74.16) 71.98,74.31 72.04,74.38 72.04,75.28 73.24,76.48 77.89,76.48 78.73,75.64 81.99,75.64 84.47,78.12 84.47,80.96 84.84,81.33 88.37,81.33 95.5,88.46 95.5,89.19 95.8,89.49 99.27,89.49 100.03,90.25 103.42,90.25 103.63,90.46 105.07,90.46 105.33,90.2 105.33,88.7 104.71,88.07 v1(104.28,88.07)
SOC_DDR3A_EDQ4: length 48.4
  TOP w0.152: U23.F1 v4(71.18,74.16) ; DIMM1.5 v1(98.98,91.37)
  L8_SIG3 w0.107: v1(98.98,91.37) 102.79,91.37 102.95,91.22 102.95,90.93 102.77,90.75 98.96,90.75 98.34,91.37 95.58,91.37 95.48,91.27 95.48,90.61 94.48,89.61 94.48,89.19 94.48,89.19 94.48,88.88 88.21,82.6 79.04,82.6 77.85,81.41 77.85,80.93 77.14,80.22 77.14,79.1 75.54,77.5 72.82,77.5 71.02,75.7 71.02,74.47 71.15,74.34 71.15,74.19 v4(71.18,74.16)
SOC_DDR3A_EDQ5: length 48.5
  TOP w0.152: v1(96.01,88.98) 95.33,88.98 95.15,88.8 95.15,88.11 95.25,88.01 95.75,88.01 96.71,88.97 DIMM1.13 ; U23.D2 v4(72.78,73.36)
  L8_SIG3 w0.107: v1(96.01,88.98) 96.01,88.25 88.58,80.82 85.27,80.82 84.97,80.53 84.97,77.91 82.2,75.13 78.52,75.13 77.68,75.97 73.45,75.97 72.55,75.07 72.55,74.45 72.34,74.25 72.34,73.16 72.14,72.95 71.86,72.95 71.84,72.93 71.82,72.93 71.58,72.68 71.58,72.46 71.54,72.43 71.54,72.41 71.33,72.19 71.31,72.19 71.28,72.16 70.27,72.16 70.24,72.13 70.22,72.13 69.98,71.88 69.98,71.64 70.25,71.36 71.28,71.36 71.31,71.39 71.33,71.39 71.54,71.61 71.54,71.63 71.61,71.69 71.61,71.91 71.85,72.16 72.1,72.16 72.34,71.91 72.34,71.61 72.34,71.6 72.34,71.55 72.52,71.37 72.89,71.37 72.91,71.39 72.93,71.39 73.14,71.61 73.14,71.63 73.18,71.66 73.18,72.96 v4(72.78,73.36)
SOC_DDR3A_EDQ6: length 48.5
  TOP w0.152: DIMM1.4 104.5,91.67 v1(104.27,91.9) ; U23.F3 v4(71.18,72.56)
  L8_SIG3 w0.107: v1(104.27,91.9) 104.26,91.9 103.77,92.38 100.13,92.38 95.08,92.38 93.76,91.07 93.76,90.33 93.47,90.03 93.47,89.3 87.83,83.67 78.67,83.67 76.83,81.83 76.83,81.35 74.12,78.64 72.52,78.64 70.01,76.12 70.01,75.85 70.01,73.73 v4(71.18,72.56)
SOC_DDR3A_EDQ7: length 48.4
  TOP w0.152: DIMM1.18 v1(104.06,87.47) ; U23.B2 v4(74.38,73.36)
  L8_SIG3 w0.107: v4(74.38,73.36) 74.57,73.36 74.93,73 75.01,73 75.02,72.99 75.33,72.99 75.34,73 75.71,73 75.86,73.15 83.72,73.15 84.14,73.57 84.16,73.57 94.75,84.16 98.27,84.16 98.79,84.68 98.9,84.68 100.63,86.41 100.63,88.42 100.89,88.67 102.92,88.67 103.2,88.39 103.2,87.02 103.61,86.61 104.53,86.61 104.71,86.44 104.71,85.85 104.89,85.67 105.14,85.67 105.32,85.85 105.32,86.44 105.5,86.61 106.35,86.61 106.5,86.77 106.5,87.33 106.36,87.47 v1(104.06,87.47)
SOC_DDR3A_EDQ8: length 45.2
  TOP w0.152: DIMM1.31 v1(96.11,83.57) ; U23.A5 v4(75.18,70.96)
  L10_SIG4 w0.107: v4(75.18,70.96) 75.79,70.96 76.86,72.03 81,72.03 81.92,71.12 86.34,71.12 86.77,71.55 86.77,71.8 86.26,72.31 86.26,72.57 86.44,72.75 86.69,72.75 87.2,72.23 87.45,72.23 87.63,72.41 87.63,72.66 86.97,73.33 86.97,73.56 87.15,73.73 87.42,73.73 88.06,73.1 88.32,73.1 88.49,73.27 88.49,73.53 87.88,74.14 87.88,74.39 88.06,74.57 88.31,74.57 88.93,73.96 89.18,73.96 89.36,74.14 89.36,74.39 88.74,75 88.74,75.23 88.92,75.41 89.2,75.41 89.79,74.82 90.04,74.82 90.22,75 90.22,75.25 89.58,75.89 89.58,76.14 89.76,76.32 90.01,76.32 90.65,75.68 90.9,75.68 91.08,75.86 91.08,76.11 90.44,76.75 90.44,76.98 90.62,77.16 90.9,77.16 91.51,76.55 91.77,76.55 91.94,76.73 91.94,76.98 91.26,77.67 91.26,77.89 91.43,78.07 91.71,78.07 92.38,77.41 92.63,77.41 96.64,81.42 96.64,83.04 v1(96.11,83.57)
SOC_DDR3A_EDQ9: length 45.4
  TOP w0.152: v1(104.32,82.67) DIMM1.34 ; U23.A6 v4(75.18,70.16)
  L10_SIG4 w0.107: v4(75.18,70.16) 75.79,70.16 75.86,70.08 76.35,70.08 77.28,71.02 80.58,71.02 81.5,70.1 86.76,70.1 96.38,79.72 100.29,79.72 100.47,79.54 100.47,78.94 100.65,78.77 100.9,78.77 101.08,78.94 101.08,79.54 101.26,79.72 101.51,79.72 101.69,79.54 101.69,78.94 101.87,78.77 102.12,78.77 102.3,78.94 102.3,79.54 102.48,79.72 102.8,79.72 103.73,80.65 105.23,80.65 105.48,80.9 105.48,81.24 105.66,81.41 106.53,81.41 106.71,81.59 106.71,81.85 106.53,82.02 105.66,82.02 105.48,82.2 105.48,82.42 105.24,82.67 v1(104.32,82.67)
SOC_DDR3A_EDQ10: length 45.3
  TOP w0.152: DIMM1.33 v1(99,82.97) ; U23.B5 v4(74.38,70.96)
  L10_SIG4 w0.107: v1(99,82.97) 97.31,82.97 97.14,83.13 97.14,83.78 96.85,84.08 95.9,84.08 95.61,83.78 95.61,82.98 94.85,82.23 94.85,81.97 95.53,81.3 95.53,81.05 95.35,80.87 95.09,80.87 94.34,81.62 94.07,81.62 93.89,81.44 93.89,81.21 94.66,80.44 94.66,80.18 94.48,80.01 94.23,80.01 93.46,80.78 93.18,80.78 93,80.6 93,80.38 93.8,79.57 93.8,79.32 93.62,79.14 93.37,79.14 92.57,79.94 92.29,79.94 92.11,79.77 92.11,79.54 92.94,78.71 92.94,78.46 92.76,78.28 92.51,78.28 91.83,78.96 91.58,78.96 85.33,72.71 84.8,72.71 84.63,72.53 84.63,72.42 84.45,72.24 84.2,72.24 84.02,72.42 84.02,72.53 83.84,72.71 82.86,72.71 82.68,72.53 82.68,71.86 82.5,71.68 82.25,71.68 82.07,71.86 82.07,72.53 81.89,72.71 76.82,72.71 75.44,71.33 74.74,71.33 v4(74.38,70.96)
SOC_DDR3A_EDQ11: length 45.3
  TOP w0.152: DIMM1.36 104.04,82.07 v1(103.81,82.3) ; U23.E5 v4(71.98,70.96)
  L10_SIG4 w0.107: v4(71.98,70.96) 72.34,71.33 73.73,71.33 74.01,71.05 74.01,70.81 74.22,70.59 75.33,70.59 76.14,70.59 77.07,71.53 80.79,71.53 81.71,70.61 86.55,70.61 97.11,81.17 97.75,81.17 97.93,81.35 97.93,81.94 98.11,82.12 98.36,82.12 98.54,81.94 98.54,81.35 98.72,81.17 99.16,81.17 100.1,80.23 100.44,80.23 100.62,80.41 100.62,81.23 100.8,81.41 101.05,81.41 101.23,81.23 101.23,80.41 101.41,80.23 102.56,80.23 103.81,81.48 v1(103.81,82.3)
SOC_DDR3A_EDQ12: length 45.2
  TOP w0.152: v1(103.99,86.23) 104.42,86.23 104.45,86.27 DIMM1.22 ; U23.C4 v4(73.58,71.76)
  L10_SIG4 w0.107: v1(103.99,86.23) 103.99,85.98 104.09,85.88 104.09,85.09 103.68,84.68 103.68,84.26 103.75,84.19 103.75,83.15 102.51,81.92 100.16,81.92 100.11,81.86 99.64,81.86 99.39,82.12 99.39,82.58 99.51,82.7 99.51,83.24 99.09,83.66 98.79,83.66 98.49,83.96 98.49,83.96 97.76,84.68 97.35,84.68 95.84,86.2 94.96,86.2 82.78,74.02 76.11,74.02 75.54,73.45 75.54,73.21 75.33,72.99 75.09,72.99 74.81,72.71 74.81,72.47 74.53,72.19 74.29,72.19 73.85,71.76 v4(73.58,71.76)
SOC_DDR3A_EDQ13: length 45.2
  TOP w0.152: U23.D4 v4(72.78,71.76) ; DIMM1.21 v1(98.98,86.57)
  L10_SIG4 w0.107: v4(72.78,71.76) 72.78,71.81 73.16,72.19 73.73,72.19 73.94,72.41 73.94,74.25 74.73,75.04 82.36,75.04 94.57,87.25 96.67,87.25 97.92,86 98.72,86 98.82,86.11 99.48,86.11 100.86,84.72 100.86,84.35 100.94,84.28 102.01,84.28 102.26,84.53 102.26,85.32 101.01,86.57 v1(98.98,86.57)
SOC_DDR3A_EDQ14: length 45.3
  TOP w0.152: DIMM1.19 v1(100.25,87.17) ; U23.E4 v4(71.98,71.76)
  L10_SIG4 w0.107: v1(100.25,87.17) 101.15,87.17 101.95,86.37 102.17,86.37 102.45,86.65 102.45,86.8 102.1,87.15 101.57,87.68 101.11,87.68 100.81,87.98 99.71,87.98 99.51,87.78 99.51,87.56 99.12,87.17 97.56,87.17 96.97,87.76 94.36,87.76 82.15,75.54 74.46,75.54 73.44,74.53 73.42,74.53 73.21,74.31 73.21,73.27 72.93,72.99 72.69,72.99 72.36,72.67 72.36,72.15 v4(71.98,71.76)
SOC_DDR3A_EDQ15: length 45.3
  TOP w0.152: U23.B3 v4(74.38,72.56) ; DIMM1.24 v1(103.58,85.67)
  L10_SIG4 w0.107: v4(74.38,72.56) 74.38,72.84 74.81,73.27 74.81,74.31 75.02,74.53 82.45,74.53 82.45,74.52 82.57,74.52 94.78,86.74 96.01,86.74 97.56,85.19 98.7,85.19 98.82,85.06 99.8,85.06 100.36,84.51 100.36,82.68 100.61,82.42 100.81,82.42 100.98,82.6 100.98,83.11 101.16,83.29 101.42,83.29 101.59,83.11 101.59,82.6 101.77,82.42 102.3,82.42 102.87,82.99 102.87,84.59 103.58,85.3 v1(103.58,85.67)
SOC_DDR3A_EDQ16: length 42
  TOP w0.152: DIMM1.39 96.28,81.17 96.04,81.41 v1(96.04,81.48) ; U23.D6 v4(72.78,70.16)
  L8_SIG3 w0.107: v4(72.78,70.16) 72.41,69.79 72.41,69.21 72.62,68.99 73.92,68.99 74.01,69.08 74.01,69.51 73.73,69.79 73.39,69.79 73.21,69.98 73.21,70.31 73.42,70.53 74.47,70.53 74.74,70.81 74.74,71.05 75.02,71.33 75.33,71.33 75.54,71.11 75.54,71.04 75.76,70.82 76.36,70.82 77.17,71.63 82.68,71.63 83.18,71.12 84.17,71.12 85.68,72.63 85.68,72.65 94.11,81.08 95.2,81.08 95.48,81.36 95.48,81.58 95.83,81.94 96.8,81.94 96.88,82.02 96.88,82.96 97.05,83.14 97.79,83.14 97.97,82.96 97.97,81.84 97.5,81.37 96.15,81.37 v1(96.04,81.48)
SOC_DDR3A_EDQ17: length 42
  TOP w0.152: v1(95.91,82.45) 96.59,81.77 DIMM1.37 ; U23.E6 v4(71.98,70.16)
  L8_SIG3 w0.107: v4(71.98,70.16) 71.54,69.73 70.07,69.73 69.95,69.85 69.95,70.4 70.14,70.59 72.93,70.59 73.14,70.81 73.14,70.83 73.21,70.9 73.21,71.11 73.42,71.33 74.46,71.33 74.74,71.61 74.74,71.91 74.5,72.16 74.07,72.16 73.94,72.29 73.94,72.85 74.04,72.95 74.51,72.95 74.81,72.65 74.81,72.41 75.02,72.19 75.03,72.19 75.08,72.14 75.66,72.14 75.78,72.02 75.78,71.62 75.9,71.5 76.07,71.5 76.19,71.62 76.19,72.02 76.31,72.14 84.47,72.14 85.17,72.84 85.17,73.14 93.61,81.58 93.9,81.58 94.06,81.74 94.06,82.03 94.21,82.19 94.49,82.19 94.59,82.09 94.59,81.64 94.64,81.58 94.87,81.58 94.97,81.69 94.97,82.4 95.17,82.6 95.76,82.6 v1(95.91,82.45)
SOC_DDR3A_EDQ18: length 41.9
  TOP w0.152: U23.E7 v4(71.98,69.36) ; DIMM1.50 v1(104.28,77.87)
  L8_SIG3 w0.107: v4(71.98,69.36) 71.98,69.09 72.41,68.66 72.41,68.41 72.62,68.19 72.87,68.19 73.14,67.91 73.14,67.67 73.42,67.39 73.66,67.39 73.94,67.11 73.94,66.87 74.22,66.59 74.47,66.59 74.74,66.31 74.74,66.07 75.02,65.79 75.27,65.79 75.58,65.48 80.19,65.48 80.32,65.35 84.65,65.35 93.34,74.04 100.1,74.04 103.51,77.45 103.72,77.45 104.14,77.87 v1(104.28,77.87)
SOC_DDR3A_EDQ19: length 41.7
  TOP w0.152: DIMM1.40 104.5,80.87 v1(104.24,81.13) ; U23.B6 v4(74.38,70.16)
  L8_SIG3 w0.107: v1(104.24,81.13) 104.7,80.67 105.56,80.67 105.69,80.8 105.69,81.51 105.54,81.66 103.84,81.66 103.4,82.09 100.38,82.09 99.96,81.68 98.53,81.68 97.7,80.85 95.69,80.85 95.41,80.57 94.42,80.57 84.46,70.61 82.97,70.61 82.47,71.12 77.38,71.12 76.57,70.31 75.54,70.31 75.33,70.53 75.02,70.53 74.65,70.16 v4(74.38,70.16)
SOC_DDR3A_EDQ20: length 41.7
  TOP w0.152: DIMM1.42 v1(103.89,80.27) ; U23.C6 v4(73.58,70.16)
  L8_SIG3 w0.107: v4(73.58,70.16) 73.85,70.16 74.22,69.79 75.33,69.79 75.34,69.8 76.78,69.8 77.59,70.61 78.61,70.61 79.2,70.02 79.2,69.36 79.68,68.88 80.49,68.88 80.79,69.18 80.79,69.6 81.7,70.51 82.36,70.51 82.76,70.1 84.68,70.1 94.63,80.06 95.2,80.06 95.62,80.06 95.9,80.34 97.91,80.34 98.74,81.17 100.17,81.17 100.59,81.58 101.13,81.58 101.31,81.41 101.31,81.23 101.48,81.05 101.74,81.05 101.91,81.23 101.91,81.41 102.09,81.58 103.19,81.58 103.73,81.04 103.73,80.92 103.89,80.76 v1(103.89,80.27)
SOC_DDR3A_EDQ21: length 41.7
  TOP w0.152: U23.C8 v4(73.58,68.56) ; DIMM1.48 v1(103.3,78.47)
  L8_SIG3 w0.107: v1(103.3,78.47) 103.21,78.56 103.21,79.75 103.05,79.91 102.75,79.91 102.6,79.76 102.6,78.28 100.27,75.96 96.51,75.96 96.27,76.2 94.06,76.2 84.23,66.37 80.74,66.37 80.61,66.5 76.25,66.5 75.35,67.39 75.02,67.39 74.81,67.61 74.81,67.85 74.53,68.13 74.29,68.13 73.85,68.56 v4(73.58,68.56)
SOC_DDR3A_EDQ22: length 41.7
  TOP w0.152: U23.A8 v4(75.18,68.56) ; DIMM1.49 v1(99,78.17)
  L8_SIG3 w0.107: v4(75.18,68.56) 75.62,68.56 76.67,67.51 81.65,67.51 82.03,67.89 82.46,67.89 82.84,67.51 83.93,67.51 93.64,77.22 95.68,77.22 95.96,77.5 95.96,77.8 96.24,78.08 96.52,78.08 96.74,77.86 96.74,77.17 96.93,76.97 97.24,76.97 97.51,77.24 97.7,77.24 97.97,76.97 98.28,76.97 98.79,77.48 99.12,77.48 99.72,78.08 100.15,78.08 100.85,78.78 100.85,79.33 100.67,79.5 100.38,79.5 100.2,79.68 100.2,79.93 100.38,80.11 100.9,80.11 101.05,80.27 101.05,80.5 100.89,80.66 99.95,80.66 99.8,80.52 99.8,78.97 v1(99,78.17)
SOC_DDR3A_EDQ23: length 41.7
  TOP w0.152: DIMM1.51 v1(99.93,77.57) ; U23.B8 v4(74.38,68.56)
  L8_SIG3 w0.107: v1(99.93,77.57) 100.36,77.57 101.36,78.57 101.36,79.82 101.52,79.98 101.99,79.98 102.09,79.88 102.09,78.49 100.63,77.03 99.78,77.03 99.21,76.46 96.72,76.46 96.48,76.71 93.85,76.71 84.02,66.88 80.95,66.88 80.82,67 76.46,67 75.27,68.19 75.02,68.19 74.65,68.56 v4(74.38,68.56)
SOC_DDR3A_EDQ24: length 41.6
  TOP w0.152: U23.E10 v4(71.98,66.96) ; DIMM1.68 v1(104.28,72.47)
  L10_SIG4 w0.107: v4(71.98,66.96) 72.18,66.96 72.62,66.53 72.93,66.53 73.14,66.31 73.14,66.07 73.42,65.79 73.75,65.79 73.94,65.6 73.94,65.15 74.12,64.97 74.48,64.97 74.74,64.71 74.74,64.47 75.02,64.19 75.33,64.19 75.54,64.41 75.54,64.43 75.58,64.47 80.16,64.47 81.21,63.42 82.86,63.42 83.34,62.94 90.73,62.94 92.94,65.15 96.4,65.15 101.6,70.36 103.73,70.36 104.28,70.91 v1(104.28,72.47)
SOC_DDR3A_EDQ25: length 41.6
  TOP w0.152: DIMM1.65 98.72,73.37 98.88,73.2 v1(98.96,73.2) ; U23.B11 v4(74.38,66.16)
  L10_SIG4 w0.107: v1(98.96,73.2) 98.96,73.06 99.36,72.66 102.13,72.66 102.3,72.49 102.3,71.59 102.18,71.48 99.5,71.48 99.16,71.14 99.16,70.89 99.39,70.66 99.39,70.41 99.21,70.23 98.96,70.23 98.73,70.46 98.48,70.46 98.3,70.28 98.3,70.03 98.53,69.8 98.53,69.55 98.35,69.37 98.1,69.37 97.87,69.59 97.62,69.59 97.44,69.42 97.44,69.16 97.67,68.94 97.67,68.68 97.49,68.51 97.23,68.51 97.01,68.73 96.76,68.73 96.19,68.17 96.19,67.89 95.96,67.66 93.68,67.66 89.97,63.96 84.04,63.96 83.56,64.44 81.74,64.44 80.56,65.63 75.93,65.63 75.83,65.73 75.01,65.73 74.89,65.85 74.58,66.16 v4(74.38,66.16)
SOC_DDR3A_EDQ26: length 41.7
  TOP w0.152: DIMM1.63 99.68,73.97 99.87,73.77 99.87,73.47 v1(99.57,73.17) ; U23.A11 v4(75.18,66.16)
  L10_SIG4 w0.107: v1(99.57,73.17) 99.47,73.27 99.47,73.41 99.17,73.71 98.75,73.71 98.45,73.41 98.45,71.15 97.9,70.59 97.64,70.59 96.93,71.3 96.68,71.3 96.5,71.12 96.5,70.87 97.21,70.16 97.21,69.91 97.03,69.73 96.78,69.73 96.07,70.44 95.82,70.44 95.64,70.26 95.64,70.01 96.35,69.3 96.35,69.04 95.74,68.43 93.73,68.43 90.86,65.57 88.69,65.57 88.51,65.39 88.51,64.92 88.33,64.74 88.08,64.74 87.9,64.92 87.9,65.39 87.72,65.57 87.47,65.57 87.29,65.39 87.29,64.92 87.11,64.74 86.86,64.74 86.68,64.92 86.68,65.39 86.5,65.57 86.25,65.57 86.07,65.39 86.07,64.92 85.89,64.74 85.64,64.74 85.46,64.92 85.46,65.39 85.28,65.57 81.49,65.57 80.93,66.14 75.2,66.14 v4(75.18,66.16)
SOC_DDR3A_EDQ27: length 41.7
  TOP w0.152: DIMM1.66 v1(103.35,73.07) ; U23.C10 v4(73.58,66.96)
  L10_SIG4 w0.107: v1(103.35,73.07) 102.81,72.53 102.81,71.3 102.45,70.94 100.64,70.94 99.82,70.12 99.82,69.86 99.94,69.74 99.94,69.49 99.76,69.31 99.51,69.31 99.39,69.43 99.13,69.43 96.6,66.9 96.17,66.9 95.99,66.72 95.99,66.47 95.81,66.29 95.56,66.29 95.38,66.47 95.38,66.72 95.2,66.9 94.95,66.9 94.77,66.72 94.77,66.47 94.59,66.29 94.34,66.29 94.16,66.47 94.16,66.72 93.98,66.9 93.63,66.9 90.18,63.45 83.55,63.45 83.07,63.93 81.53,63.93 80.39,65.07 75.79,65.07 75.7,64.99 75.02,64.99 74.81,65.21 74.81,65.45 74.53,65.73 74.22,65.73 74.01,65.94 74.01,66.28 73.58,66.72 v4(73.58,66.96)
SOC_DDR3A_EDQ28: length 41.7
  TOP w0.152: DIMM1.57 96.01,75.77 v1(95.96,75.82) ; U23.D10 v4(72.78,66.96)
  L10_SIG4 w0.107: v4(72.78,66.96) 73.21,67.39 73.73,67.39 73.94,67.61 73.94,67.85 74.23,68.14 75.34,68.14 75.66,68.46 83.63,68.46 83.81,68.28 83.81,68.07 83.99,67.89 84.24,67.89 84.42,68.07 84.42,68.28 84.6,68.46 84.85,68.46 85.03,68.28 85.03,68.02 85.16,67.89 85.51,67.89 85.64,68.02 85.64,68.28 85.82,68.46 86.07,68.46 86.25,68.28 86.25,68.07 86.43,67.89 86.68,67.89 86.86,68.07 86.86,68.28 87.04,68.46 87.33,68.46 87.69,68.1 87.94,68.1 88.3,68.46 88.99,68.46 89.64,69.11 89.64,69.37 89.05,69.95 89.05,70.21 89.23,70.39 89.49,70.39 90.07,69.8 90.33,69.8 90.5,69.98 90.5,70.23 89.92,70.82 89.92,71.07 90.1,71.25 90.35,71.25 90.94,70.66 91.19,70.66 91.37,70.84 91.37,71.09 90.78,71.68 90.78,71.93 90.96,72.11 91.21,72.11 91.8,71.52 92.05,71.52 92.23,71.7 92.23,71.95 91.64,72.54 91.64,72.79 91.82,72.97 92.07,72.97 92.66,72.39 92.91,72.39 93.09,72.56 93.09,72.82 92.5,73.4 92.5,73.66 92.68,73.84 92.94,73.84 93.52,73.25 93.78,73.25 95.3,74.77 95.3,75.16 v1(95.96,75.82)
SOC_DDR3A_EDQ29: length 41.8
  TOP w0.152: DIMM1.56 107.39,76.07 v1(107.39,76.08) ; U23.B9 v4(74.38,67.76)
  L10_SIG4 w0.107: v1(107.39,76.08) 106.74,76.08 104.34,73.68 99.92,73.68 99.38,74.22 98.54,74.22 97.94,73.62 97.94,73.37 90.65,66.08 81.7,66.08 81.14,66.64 75.38,66.64 75.33,66.59 74.22,66.59 74.01,66.81 74.01,67.38 74.15,67.52 74.15,67.53 v4(74.38,67.76)
SOC_DDR3A_EDQ30: length 41.7
  TOP w0.152: DIMM1.55 v1(99.93,76.37) ; U23.E9 v4(71.98,67.76)
  L10_SIG4 w0.107: v1(99.93,76.37) 100.29,76.73 100.29,77.33 100.31,77.34 100.31,78.39 100.11,78.59 98.68,78.59 98.42,78.33 98.42,77.13 97.66,76.37 97.33,76.37 97.16,76.19 97.16,75.72 96.98,75.54 96.72,75.54 96.55,75.72 96.55,76.19 96.37,76.37 95.79,76.37 94.79,75.37 94.79,74.98 94.47,74.66 92.75,74.66 87.06,68.97 79.33,68.97 79.15,69.15 79.15,69.34 79,69.49 78.7,69.49 78.54,69.34 78.54,69.15 78.37,68.97 77.96,68.97 77.83,69.1 77.83,69.31 77.65,69.49 77.4,69.49 77.22,69.31 77.22,69.1 77.09,68.97 74.26,68.97 74.01,68.71 74.01,68.47 73.73,68.19 72.4,68.19 71.98,67.77 v4(71.98,67.76)
SOC_DDR3A_EDQ31: length 41.7
  TOP w0.152: U23.A9 v4(75.18,67.76) ; DIMM1.54 v1(104.28,76.67)
  L10_SIG4 w0.107: v4(75.18,67.76) 75.44,67.76 75.64,67.95 82.72,67.95 83.29,67.39 88.63,67.39 95.31,74.06 96.53,74.06 98.33,75.86 100.24,75.86 100.8,76.42 100.8,76.67 102.01,77.88 103.38,77.88 103.75,78.25 104.62,78.25 104.84,78.03 104.84,76.04 104.54,75.74 103.79,75.74 103.61,75.92 103.61,76.66 103.76,76.81 104.14,76.81 v1(104.28,76.67)
SOC_DDR3A_EDQ32: length 45.5
  TOP w0.127: U23.B23 v4(74.38,55.76)
  TOP w0.152: DIMM1.142 104.38,47.87 v1(104.31,47.8)
  L10_SIG4 w0.107: v1(104.31,47.8) 104.87,47.8 105.26,48.18 105.69,48.18 105.79,48.29 105.79,49.05 105.89,49.15 106.42,49.15 106.55,49.01 106.55,48.34 105.49,47.27 104.24,47.27 103.64,47.87 103.57,47.87 102.72,48.71 100.94,48.71 100.82,48.83 100.82,48.93 100.7,49.05 100.53,49.05 100.41,48.93 100.41,48.83 100.29,48.71 97.16,48.71 96.45,49.41 95.06,49.41 94.87,49.22 94.76,49.22 94.03,48.49 93.5,48.49 92.94,49.05 89.4,49.05 89.07,48.72 88.62,48.72 87.48,47.57 86.55,47.57 85.17,48.96 85.17,48.96 84.91,49.22 83.98,50.15 82.73,50.15 82.23,50.65 82.23,51.78 78.38,55.64 75.8,55.64 75.54,55.89 75.54,55.91 75.33,56.13 74.74,56.13 v4(74.38,55.76)
SOC_DDR3A_EDQ33: length 45.5
  TOP w0.127: U23.E23 v4(71.98,55.76)
  TOP w0.152: DIMM1.133 99.95,50.57 v1(100.36,50.16)
  L10_SIG4 w0.107: v1(100.36,50.16) 100.05,50.16 100.04,50.18 99.5,50.18 98.72,50.96 98.42,50.96 98.24,50.79 98.24,50.74 98.07,50.57 97.81,50.57 97.63,50.74 97.63,50.79 97.46,50.96 94.3,50.96 94.08,50.75 88.95,50.75 88.52,50.32 87.83,50.32 87.73,50.42 87.73,51.35 85.76,53.33 84.72,53.33 84.54,53.15 84.54,51.94 84.37,51.76 84.11,51.76 83.94,51.94 83.94,53.15 83.76,53.33 83.01,53.33 81.89,54.45 80.35,55.99 80.18,55.99 79.01,57.16 77.01,57.16 75.64,58.53 74.22,58.53 74.01,58.31 74.01,58.07 73.73,57.79 73.41,57.79 73.14,57.53 73.14,57.21 72.93,56.99 72.62,56.99 72.41,57.21 72.41,57.51 72.19,57.73 71.75,57.73 71.54,57.52 71.54,57.21 71.33,56.99 70.95,56.99 70.76,56.8 70.76,55.53 70.9,55.39 71.61,55.39 v4(71.98,55.76)
SOC_DDR3A_EDQ34: length 45.5
  TOP w0.152: U23.D24 v4(72.78,54.96) ; v1(99,49.97) DIMM1.135
  L10_SIG4 w0.107: v4(72.78,54.96) 72.49,54.96 72.4,55.05 72.4,55.92 72.19,56.13 71.79,56.13 71.61,56.31 71.61,56.89 71.71,56.99 72.32,56.99 72.41,56.9 72.41,56.31 72.58,56.13 72.95,56.13 73.21,56.39 73.21,56.86 73.34,56.99 73.73,56.99 74.01,57.27 74.01,57.51 74.22,57.73 75.33,57.73 75.54,57.51 75.54,57.49 76.39,56.65 78.8,56.65 83.25,52.2 83.25,51.33 83.41,51.17 84.4,51.17 84.61,50.95 84.86,50.95 85.93,52.02 86.18,52.02 86.36,51.84 86.36,51.59 85.29,50.52 85.29,50.27 85.47,50.09 85.73,50.09 86.79,51.16 87.04,51.16 87.22,50.98 87.22,50.73 86.16,49.66 86.16,49.41 86.42,49.15 87.62,49.15 88.2,49.73 88.65,49.73 89.16,50.24 94.45,50.24 94.67,50.46 96.85,50.46 97.33,49.97 v1(99,49.97)
SOC_DDR3A_EDQ35: length 45.6
  TOP w0.152: U23.C24 v4(73.58,54.96) ; DIMM1.136 v1(103.76,49.67)
  L10_SIG4 w0.107: v4(73.58,54.96) 73.58,55.27 73.45,55.39 73.24,55.39 73.14,55.3 73.14,54.66 73.28,54.53 73.82,54.53 74.01,54.71 74.01,56.81 74.15,56.96 75.35,56.96 76.16,56.14 78.59,56.14 82.74,51.99 82.74,50.86 82.94,50.66 84.19,50.66 86.21,48.64 87.83,48.64 88.41,49.23 88.86,49.23 89.37,49.73 92.97,49.73 93.15,49.55 93.6,49.1 93.92,49.1 94.55,49.73 94.66,49.73 94.85,49.92 96.66,49.92 97.12,49.46 99.21,49.46 99.43,49.68 99.83,49.68 99.84,49.66 102.62,49.66 103.82,48.46 104.36,48.46 104.77,48.87 104.77,49.21 104.31,49.67 v1(103.76,49.67)
SOC_DDR3A_EDQ36: length 45.6
  TOP w0.152: v1(102.97,50.32) 103.73,50.32 103.78,50.27 DIMM1.134 ; U23.E24 v4(71.98,54.96)
  L10_SIG4 w0.107: v4(71.98,54.96) 71.8,54.79 71.52,54.79 71.33,54.59 71.02,54.59 70.74,54.87 70.74,55.11 70.53,55.33 70.27,55.33 70.07,55.54 70.07,55.55 70.01,55.61 70.01,56.71 70.22,56.93 70.53,56.93 70.74,57.14 70.74,57.45 71.02,57.73 71.27,57.73 71.54,58.01 71.54,58.25 71.82,58.53 73.66,58.53 73.94,58.81 73.94,59.05 74.22,59.33 75.47,59.33 75.48,59.32 75.57,59.32 77.22,57.67 79.22,57.67 80.39,56.5 80.56,56.5 82.25,54.81 83.22,53.84 85.97,53.84 88.55,51.26 93.87,51.26 94.09,51.47 98.93,51.47 99.65,50.75 101.19,50.75 101.68,50.27 102.92,50.27 v1(102.97,50.32)
SOC_DDR3A_EDQ37: length 45.5
  TOP w0.152: DIMM1.147 v1(99,46.37) ; U23.E25 v4(71.98,54.16)
  L10_SIG4 w0.107: v4(71.98,54.16) 71.7,54.16 71.33,53.79 71.09,53.79 70.81,53.51 70.81,53.21 71.09,52.93 71.34,52.93 71.61,53.2 71.61,53.51 71.82,53.73 75.34,53.73 75.75,53.31 77.41,53.31 79.44,51.29 79.81,50.91 79.81,49.49 81.48,47.83 83.01,47.83 83.26,47.58 83.98,46.85 83.99,46.85 87.75,43.09 98.08,43.09 98.74,43.75 98.93,43.75 99.25,44.07 101.06,44.07 101.83,44.84 101.83,45.97 101.43,46.37 v1(99,46.37)
SOC_DDR3A_EDQ38: length 45.5
  TOP w0.152: v1(103.66,47.06) 103.87,47.27 DIMM1.144 ; U23.B25 v4(74.38,54.16)
  L10_SIG4 w0.107: v1(103.66,47.06) 103.36,47.36 102.79,47.36 102.61,47.54 102.61,48.02 102.43,48.2 102.18,48.2 102,48.02 102,47.54 101.82,47.36 101.57,47.36 101.39,47.54 101.39,48.02 101.21,48.2 100.96,48.2 100.78,48.02 100.78,47.54 100.6,47.36 99.93,47.36 99.24,48.06 97.84,48.06 97.5,47.71 97.5,47.19 97.32,47.01 96.14,47.01 95.96,46.83 95.96,46.58 96.14,46.4 97.32,46.4 97.5,46.22 97.5,45.15 97.31,44.96 95.63,44.96 95.47,44.81 87.47,44.81 87.41,44.87 86.6,45.67 85.84,46.44 84.51,47.77 84.51,47.77 83.98,48.29 83.43,48.84 81.93,48.84 80.92,49.85 80.92,51.24 77.83,54.33 75.86,54.33 75.6,54.59 74.81,54.59 v4(74.38,54.16)
SOC_DDR3A_EDQ39: length 45.5
  TOP w0.152: DIMM1.145 v1(99.44,46.97) ; U23.A25 v4(75.18,54.16)
  L10_SIG4 w0.107: v1(99.44,46.97) 98.3,46.97 98.03,46.71 98.03,46.13 98.3,45.86 101.2,45.86 101.32,45.74 101.32,45.05 101.16,44.89 99.21,44.89 99.03,44.71 99.03,44.58 98.85,44.4 98.6,44.4 98.42,44.58 98.42,44.71 98.24,44.89 97.96,44.89 97.47,44.4 97.47,43.78 97.29,43.6 97.04,43.6 96.86,43.78 96.86,44.27 96.68,44.45 95.84,44.45 95.46,44.07 93.53,44.07 93.06,43.6 91.67,43.6 91.49,43.78 91.49,44.12 91.31,44.3 91.06,44.3 90.88,44.12 90.88,43.78 90.7,43.6 90.45,43.6 90.27,43.78 90.27,44.12 90.09,44.3 89.84,44.3 89.66,44.12 89.66,43.78 89.48,43.6 89.23,43.6 89.05,43.78 89.05,44.12 88.87,44.3 88.62,44.3 88.44,44.12 88.44,43.78 88.26,43.6 87.96,43.6 84.24,47.32 84.24,47.32 83.7,47.86 83.22,48.34 81.69,48.34 80.32,49.7 80.32,51.12 77.62,53.82 75.91,53.82 75.56,54.16 v4(75.18,54.16)
SOC_DDR3A_EDQ40: length 41.3
  TOP w0.152: U23.E28 v4(71.98,51.76) ; DIMM1.160 v1(103.78,42.47)
  L8_SIG3 w0.107: v4(71.98,51.76) 72.41,51.33 72.62,51.33 72.62,51.33 72.93,51.33 73.21,51.05 73.21,50.81 73.42,50.59 73.66,50.59 73.94,50.31 73.94,50.07 74.29,49.73 74.53,49.73 74.75,49.5 75.66,49.5 75.86,49.71 88.21,49.71 91.82,46.1 91.82,44.3 95.33,40.79 102.51,40.79 103.77,42.05 103.77,42.08 103.78,42.09 v1(103.78,42.47)
SOC_DDR3A_EDQ41: length 41.2
  TOP w0.152: DIMM1.161 98.91,42.17 v1(99.24,41.84) ; U23.D28 v4(72.78,51.76)
  L8_SIG3 w0.107: v4(72.78,51.76) 73,51.53 73.01,51.53 73.16,51.38 73.67,51.38 74.01,51.05 74.01,50.63 74.11,50.53 74.53,50.53 74.81,50.25 74.81,50.01 75.02,49.79 75.44,49.79 75.86,50.22 89.26,50.22 89.54,49.93 89.54,49.68 89.38,49.52 89.38,49.26 89.56,49.08 89.81,49.08 89.97,49.25 90.22,49.25 90.4,49.07 90.4,48.82 90.24,48.65 90.24,48.4 90.48,48.16 90.9,48.16 91.08,47.98 91.08,47.75 91.26,47.57 91.51,47.57 91.69,47.75 91.69,47.98 91.87,48.16 92.28,48.16 93.08,47.36 93.08,47.05 92.9,46.87 92.53,46.87 92.35,46.69 92.35,46.44 92.53,46.26 92.9,46.26 93.08,46.08 93.08,45.83 92.9,45.65 92.53,45.65 92.35,45.47 92.35,45.22 92.53,45.04 92.9,45.04 93.08,44.86 93.08,44.21 95.21,42.08 96.47,42.08 96.72,41.83 96.72,41.48 96.9,41.3 97.45,41.3 97.63,41.48 97.63,41.67 97.81,41.84 98.06,41.84 98.24,41.67 98.24,41.48 98.42,41.3 98.86,41.3 99.24,41.68 v1(99.24,41.84)
SOC_DDR3A_EDQ42: length 41.2
  TOP w0.152: v1(100.1,42.52) 99.85,42.77 DIMM1.159 ; U23.C28 v4(73.58,51.76)
  L8_SIG3 w0.107: v1(100.1,42.52) 100.1,42.52 102.42,42.52 102.58,42.35 102.58,41.73 102.3,41.45 100.36,41.45 99.46,42.35 96.92,42.35 93.59,45.68 93.59,47.58 92.5,48.67 91.52,48.67 89.47,50.72 75.46,50.72 75.33,50.59 75.02,50.59 74.74,50.87 74.74,51.11 74.47,51.39 74.13,51.39 73.77,51.76 v4(73.58,51.76)
SOC_DDR3A_EDQ43: length 41.3
  TOP w0.152: DIMM1.148 v1(103.81,46.07) ; U23.E27 v4(71.98,52.56)
  L8_SIG3 w0.107: v1(103.81,46.07) 103.12,46.75 103.12,49 100.66,51.46 98.93,51.46 95.33,55.07 93.24,55.07 93.19,55.02 75.74,55.02 75.43,55.33 75.02,55.33 74.81,55.11 74.81,54.87 74.46,54.53 74.22,54.53 74.01,54.31 74.01,54.07 73.71,53.77 72.57,53.77 72.34,53.55 72.34,52.93 v4(71.98,52.56)
SOC_DDR3A_EDQ44: length 41.3
  TOP w0.152: U23.B28 v4(74.38,51.76) ; DIMM1.162 v1(104.28,41.87)
  L8_SIG3 w0.107: v1(104.28,41.87) 105.98,41.87 106.17,42.06 106.17,42.88 106.02,43.02 100.31,43.02 100.31,43.03 99.45,43.03 99.28,42.86 98.02,42.86 96.43,44.45 96.01,44.45 94.09,46.36 94.09,47.79 92.71,49.17 91.73,49.17 89.68,51.23 75.87,51.23 75.72,51.38 74.99,51.38 74.62,51.76 v4(74.38,51.76)
SOC_DDR3A_EDQ45: length 41.2
  TOP w0.152: v1(100.2,45.31) 99.46,44.57 DIMM1.153 ; U23.A26 v4(75.18,53.36)
  L8_SIG3 w0.107: v4(75.18,53.36) 75.79,53.36 75.86,53.43 92.39,53.43 92.82,53 94.92,53 97.98,49.94 98.25,49.94 98.52,49.67 98.52,49.13 98.34,48.95 96.95,48.95 96.77,48.77 96.77,48.52 96.95,48.34 98.34,48.34 98.52,48.16 98.52,47.91 98.34,47.73 96.95,47.73 96.77,47.55 96.77,47.3 96.95,47.12 98.34,47.12 98.52,46.94 98.52,45.34 99.1,44.75 99.87,44.75 100.15,45.03 100.15,45.26 v1(100.2,45.31)
SOC_DDR3A_EDQ46: length 41.2
  TOP w0.152: v1(99.26,45.31) 99.12,45.17 DIMM1.151 ; U23.B26 v4(74.38,53.36)
  L8_SIG3 w0.107: v4(74.38,53.36) 74.65,53.36 75.04,53.75 75.41,53.75 75.6,53.94 92.6,53.94 93.03,53.5 95.13,53.5 98.19,50.44 99.39,50.44 100.11,49.73 100.11,49.35 100.29,49.17 101.09,49.17 101.27,48.99 101.27,48.74 101.09,48.56 99.58,48.56 99.4,48.38 99.4,48.13 99.58,47.95 101.65,47.95 101.83,47.77 101.83,47.52 101.65,47.34 100.29,47.34 100.11,47.16 100.11,46.16 v1(99.26,45.31)
SOC_DDR3A_EDQ47: length 41.2
  TOP w0.152: U23.C26 v4(73.58,53.36) ; v1(104.22,45.61) 104.36,45.47 DIMM1.150
  L8_SIG3 w0.107: v4(73.58,53.36) 73.8,53.59 73.81,53.59 73.95,53.73 74.48,53.73 74.75,54 74.75,54.28 75,54.53 75.33,54.53 75.34,54.52 92.74,54.52 93.24,54.01 95.34,54.01 98.4,50.95 100.25,50.95 102.62,48.59 102.62,45.26 102.97,44.91 104.78,44.91 104.93,45.06 104.93,45.31 104.77,45.47 104.36,45.47 v1(104.22,45.61)
SOC_DDR3A_EDQ48: length 46.1
  TOP w0.152: U23.A29 v4(75.18,50.96) ; v1(99.59,40.34) 98.96,40.97 DIMM1.165
  L10_SIG4 w0.107: v1(99.59,40.34) 100.33,40.34 100.43,40.23 100.43,39.24 100.17,38.98 98.49,38.98 98.37,39.1 98.37,39.92 98.25,40.04 98.09,40.04 97.97,39.92 97.97,39.1 97.85,38.98 97.68,38.98 97.56,39.1 97.56,39.92 97.44,40.04 97.27,40.04 97.15,39.92 97.15,38.78 96.95,38.58 96.39,38.58 96.29,38.68 96.29,39.93 96.18,40.04 94.91,40.04 94.41,40.54 86.42,40.54 83.44,43.52 83.27,43.52 83.1,43.36 82.93,43.36 82.81,43.47 82.81,43.64 82.98,43.81 82.98,43.98 82.86,44.1 82.7,44.1 82.53,43.93 82.36,43.93 82.24,44.05 82.24,44.22 82.41,44.39 82.41,44.55 81.67,45.29 80.42,45.29 79.88,45.83 79.72,45.83 79.13,45.24 78.96,45.24 78.84,45.36 78.84,45.53 79.43,46.11 79.43,46.28 79.31,46.4 79.14,46.4 78.46,45.72 78.29,45.72 78.17,45.84 78.17,46 78.85,46.69 78.85,46.86 77.38,48.33 77.38,48.33 77.27,48.44 77.27,49.74 76.27,50.74 75.86,50.74 75.65,50.96 v4(75.18,50.96)
SOC_DDR3A_EDQ49: length 46.1
  TOP w0.152: U23.A28 v4(75.18,51.76) ; v1(100.94,41.83) 100.94,40.51 100.33,39.9 99.36,39.9 98.9,40.37 DIMM1.167
  L10_SIG4 w0.107: v1(100.94,41.83) 100.94,42.19 101.24,42.49 103.17,42.49 103.5,42.16 103.5,41.33 103.33,41.15 103.02,41.15 102.9,41.27 102.9,41.79 102.78,41.91 102.62,41.91 102.5,41.79 102.5,41.27 102.38,41.15 102.21,41.15 102.09,41.27 102.09,41.79 101.97,41.91 101.8,41.91 101.68,41.79 101.68,41.27 101.57,41.15 100.95,41.15 100.75,41.35 98.65,41.35 98.36,41.06 95.58,41.06 95.09,41.55 87.06,41.55 82.31,46.3 80.84,46.3 80.03,47.11 79.6,47.54 78.29,48.86 78.29,50.19 77.32,51.16 77.23,51.25 77.04,51.44 77.04,51.44 76.71,51.76 v4(75.18,51.76)
SOC_DDR3A_EDQ50: length 46
  TOP w0.152: v1(101.3,36.96) 101.8,37.47 101.8,38.2 101.52,38.48 100.43,38.48 99.32,37.37 DIMM1.177 ; U23.B31 v4(74.38,49.36)
  L10_SIG4 w0.107: v4(74.38,49.36) 74.01,48.99 74.01,48.41 74.29,48.13 74.53,48.13 74.74,47.91 74.74,47.61 74.4,47.26 74.4,46.96 74.52,46.84 74.76,46.84 74.88,46.72 74.88,46.55 74.76,46.43 74.52,46.43 74.4,46.31 74.4,46.15 74.52,46.03 74.76,46.03 74.88,45.91 74.88,45.74 74.76,45.62 74.52,45.62 74.4,45.5 74.4,45.33 74.52,45.21 74.76,45.21 74.88,45.09 74.88,44.93 74.76,44.81 74.52,44.81 74.4,44.69 74.4,44.52 74.52,44.4 74.76,44.4 74.88,44.28 74.88,44.11 74.76,43.99 74.52,43.99 74.4,43.88 74.4,43.11 78.78,38.72 85.67,38.72 92.97,38.72 94.4,37.29 100.97,37.29 v1(101.3,36.96)
SOC_DDR3A_EDQ51: length 46.1
  TOP w0.152: U23.E29 v4(71.98,50.96) ; v1(95.78,35.74) 95.78,36.27 96.28,36.77 DIMM1.179
  L10_SIG4 w0.107: v1(95.78,35.74) 93.8,35.74 92.34,37.2 91.93,37.2 91.92,37.2 91.31,37.2 91.13,37.02 91.13,36.02 90.95,35.84 90.7,35.84 90.52,36.02 90.52,37.02 90.34,37.2 90.09,37.2 89.91,37.02 89.91,36.02 89.73,35.84 89.48,35.84 89.3,36.02 89.3,37.02 89.12,37.2 88.87,37.2 88.69,37.02 88.69,36.02 88.51,35.84 88.26,35.84 88.08,36.02 88.08,37.02 87.9,37.2 85.04,37.2 85.04,37.2 78.15,37.2 74.74,40.6 74.33,41.02 72.87,42.48 72.87,47.14 72.34,47.67 72.34,47.91 72.06,48.19 71.82,48.19 71.54,48.47 71.54,48.71 71.3,48.96 71.05,48.96 70.78,49.24 70.78,50.28 71.07,50.57 71.59,50.57 v4(71.98,50.96)
SOC_DDR3A_EDQ52: length 46.1
  TOP w0.152: v1(103.56,40.67) DIMM1.166 ; U23.B29 v4(74.38,50.96)
  L10_SIG4 w0.107: v4(74.38,50.96) 74.38,50.96 74.81,51.39 75.72,51.39 75.86,51.25 76.48,51.25 77.78,49.95 77.78,48.65 77.81,48.62 78.1,48.33 80.63,45.8 81.92,45.8 86.66,41.05 94.88,41.05 95.37,40.55 98.6,40.55 98.89,40.84 100.54,40.84 100.94,40.44 100.94,39.24 101.12,39.07 101.62,39.07 101.81,39.26 101.81,40.52 101.93,40.64 102.1,40.64 102.22,40.52 102.22,39.26 102.34,39.14 102.51,39.14 102.62,39.26 102.62,40.52 102.74,40.64 102.91,40.64 103.03,40.52 103.03,39.26 103.15,39.14 103.48,39.14 103.84,39.5 103.84,40.39 v1(103.56,40.67)
SOC_DDR3A_EDQ53: length 46.1
  TOP w0.152: v1(104.37,40.06) 104.38,40.07 DIMM1.168 ; U23.C30 v4(73.58,50.16)
  L10_SIG4 w0.107: v1(104.37,40.06) 105.94,40.06 106.27,40.39 106.27,42.67 105.94,43 99.97,43 99.45,42.48 99.1,42.48 98.7,42.08 87.26,42.08 82.52,46.81 81.05,46.81 80.39,47.47 79.96,47.9 78.79,49.07 78.79,50.4 78.31,50.89 77.73,51.46 77.73,51.47 76.93,52.27 75.86,52.27 75.72,52.13 74.22,52.13 74.01,51.91 74.01,50.59 v4(73.58,50.16)
SOC_DDR3A_EDQ54: length 46.2
  TOP w0.152: DIMM1.174 v1(104.28,38.27) ; U23.E30 v4(71.98,50.16)
  L10_SIG4 w0.107: v1(104.28,38.27) 104.28,37.89 102.33,35.94 100.67,35.94 99.9,35.17 99,35.17 97.92,36.25 94.01,36.25 92.55,37.71 87.6,37.71 78.36,37.71 74.96,41.11 74.31,41.75 73.79,42.28 73.38,42.69 73.38,47.43 73.21,47.61 73.21,47.85 72.93,48.13 72.69,48.13 72.41,48.41 72.41,48.65 72.1,48.96 71.85,48.96 71.61,49.21 71.61,49.23 71.6,49.23 71.6,49.79 v4(71.98,50.16)
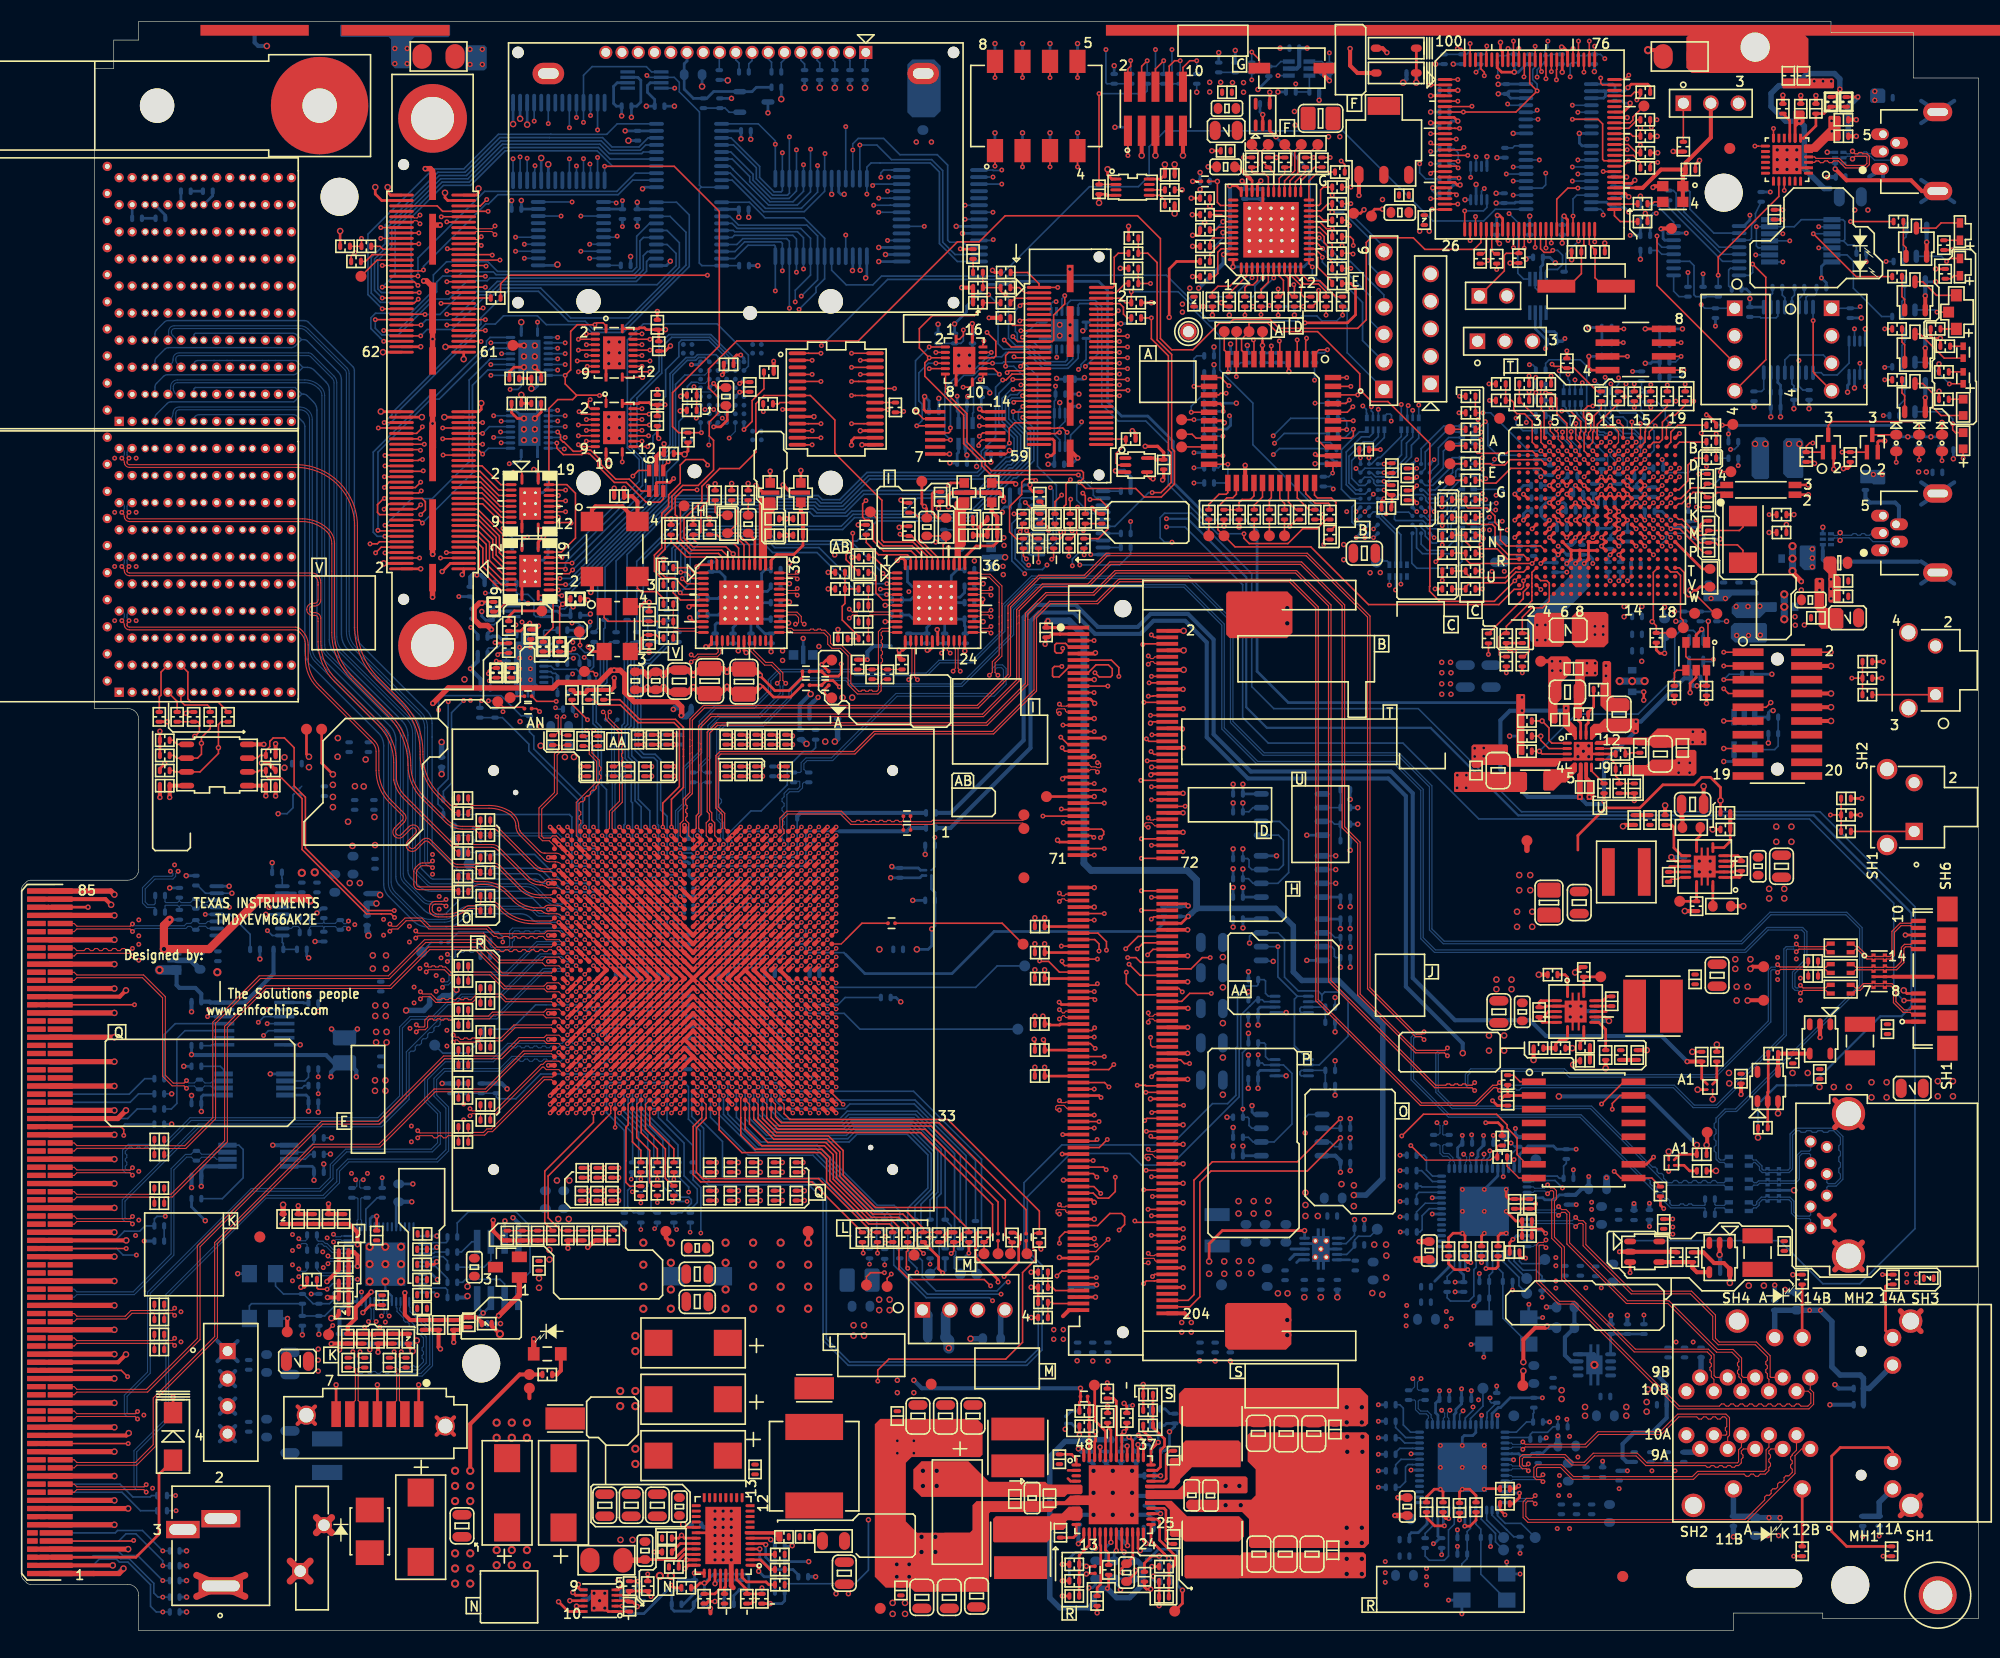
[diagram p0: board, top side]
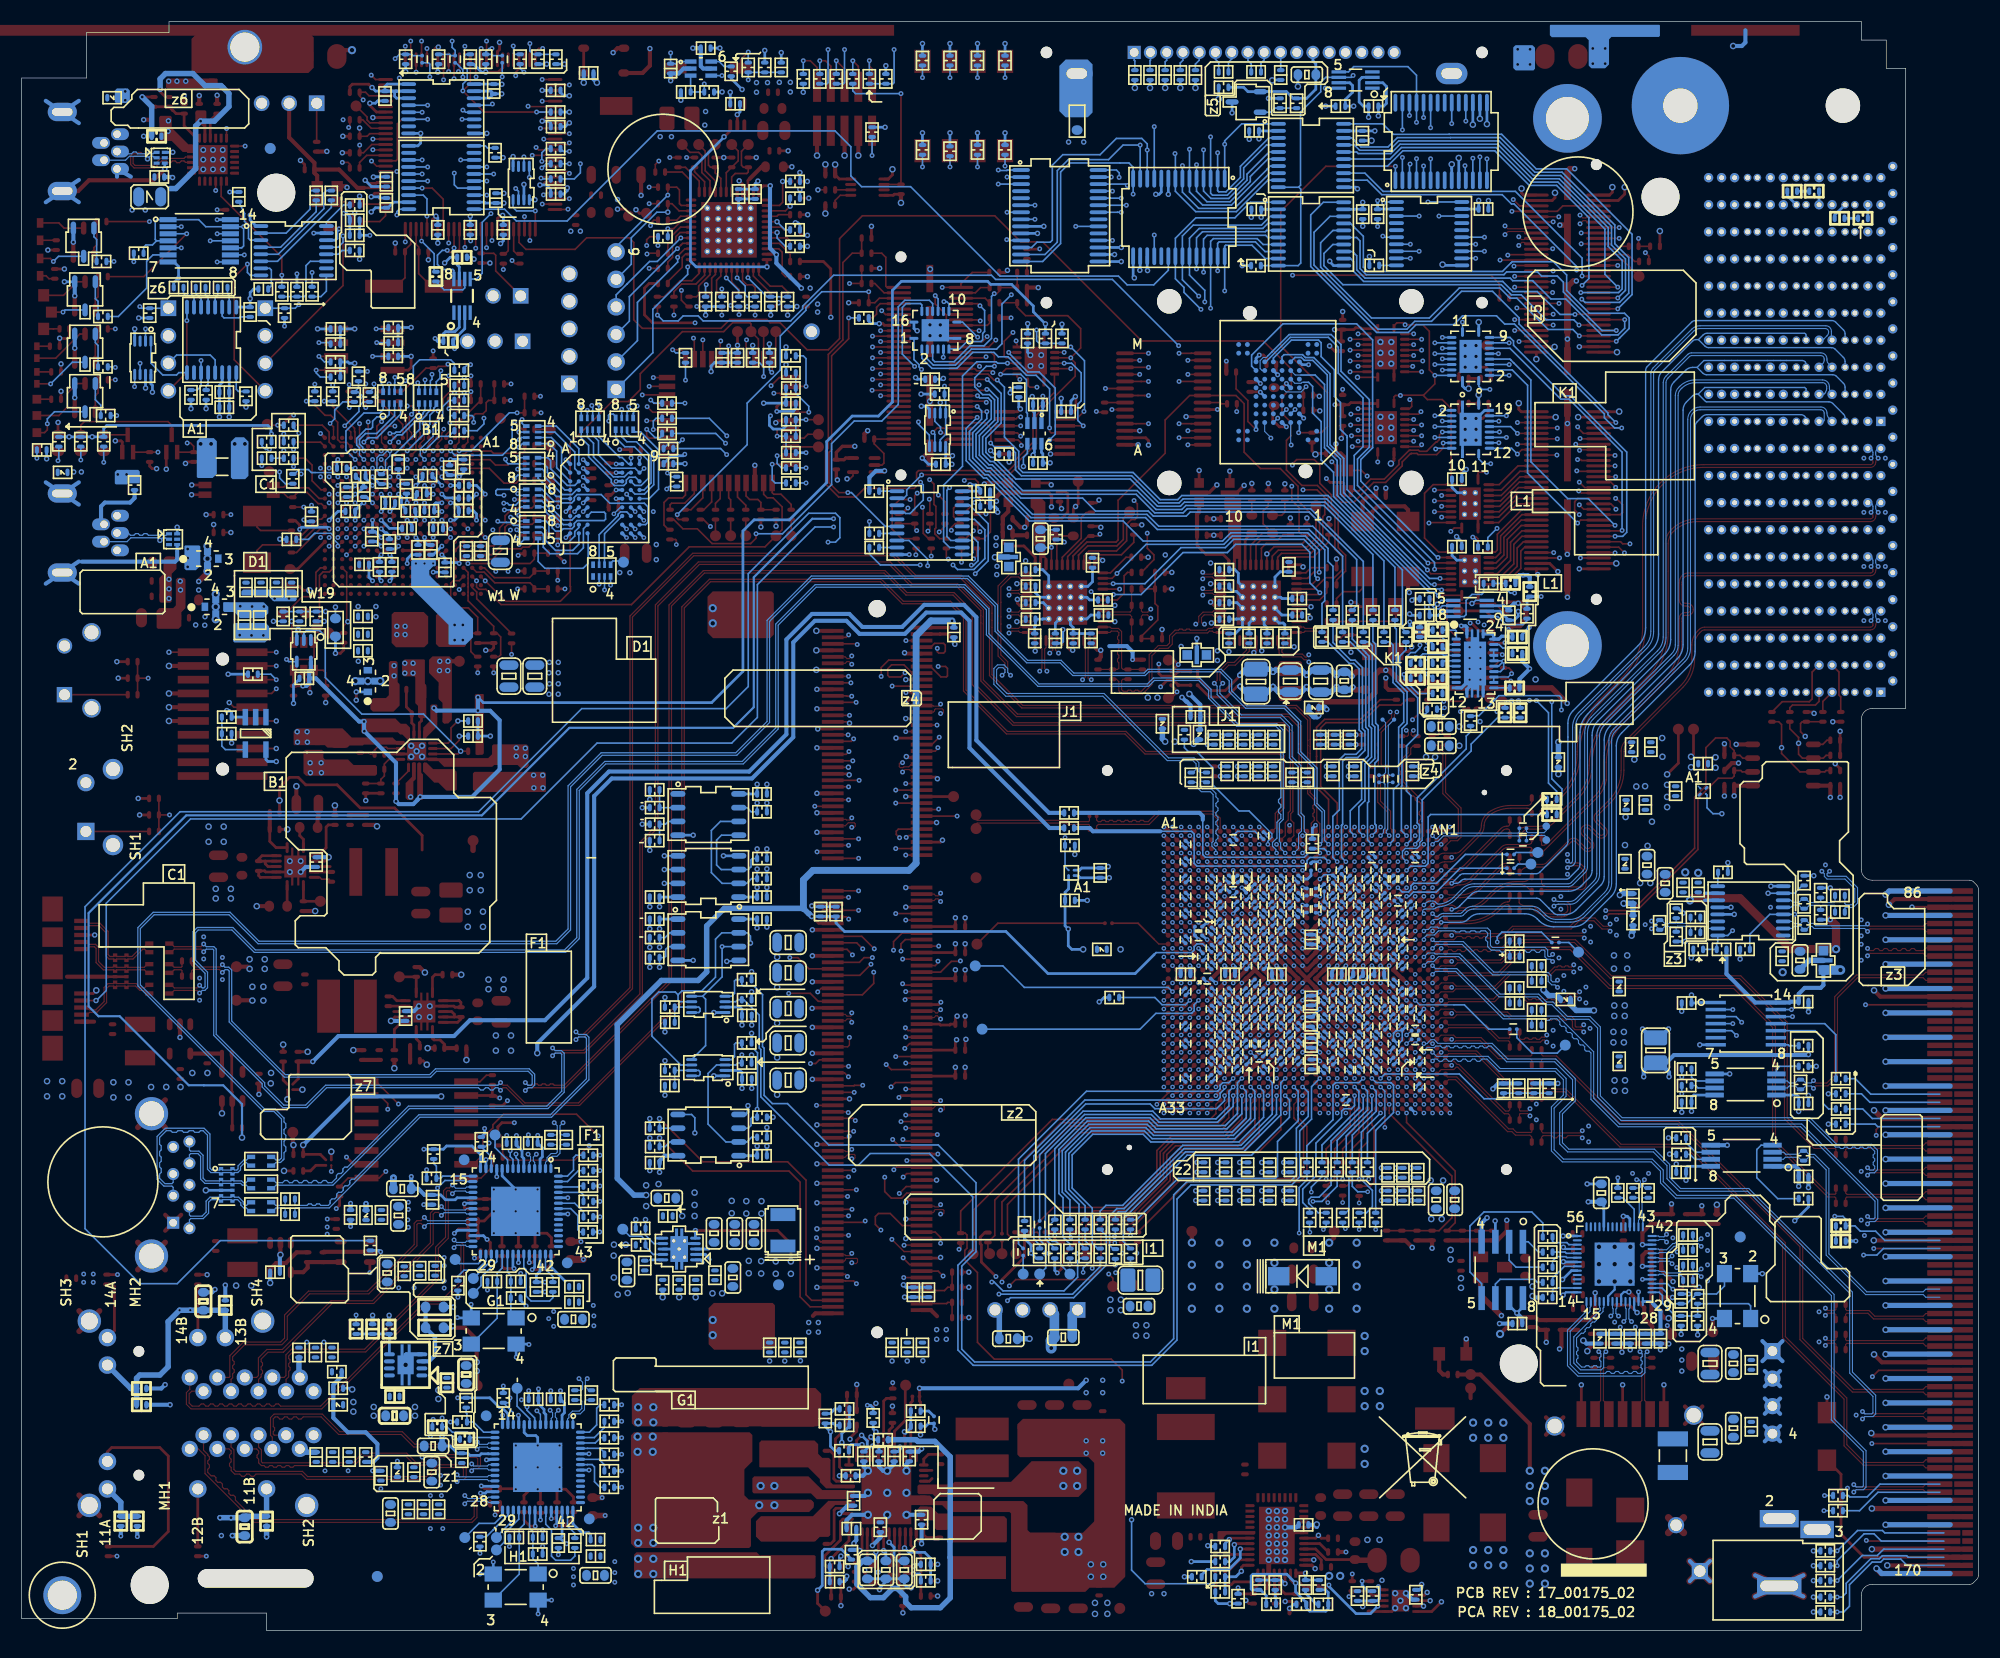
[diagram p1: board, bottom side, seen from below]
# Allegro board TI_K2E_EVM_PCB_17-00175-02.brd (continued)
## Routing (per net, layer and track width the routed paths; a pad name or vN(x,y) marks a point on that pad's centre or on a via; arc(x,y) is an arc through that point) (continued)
SOC_DDR3A_EDQ55: length 46
  TOP w0.152: U23.D30 v4(72.78,50.16) ; v1(102.74,37.8) 102.87,37.67 DIMM1.176
  L10_SIG4 w0.107: v4(72.78,50.16) 73,49.93 73.01,49.93 73.22,49.73 74.53,49.73 74.81,49.45 74.81,48.41 75.09,48.13 75.33,48.13 75.67,47.79 75.67,46.91 75.39,46.63 75.39,42.84 78.99,39.23 85.88,39.23 93.18,39.23 94.49,37.92 97.13,37.92 97.68,38.48 99.51,38.48 99.63,38.36 99.63,38.01 99.75,37.89 99.91,37.89 100.03,38.01 100.03,38.36 100.15,38.48 100.32,38.48 100.44,38.36 100.44,38.01 100.56,37.89 100.73,37.89 100.85,38.01 100.85,38.36 100.97,38.48 101.13,38.48 101.25,38.36 101.25,38.01 101.37,37.89 101.54,37.89 101.66,38.01 101.66,38.36 101.78,38.48 102.52,38.48 102.74,38.25 v1(102.74,37.8)
SOC_DDR3A_EDQ56: length 47.3
  TOP w0.152: U23.F31 v4(71.18,49.36) ; DIMM1.180 v1(104.28,36.47)
  L8_SIG3 w0.107: v4(71.18,49.36) 71.58,48.96 72.1,48.96 72.38,48.68 72.38,48.44 72.69,48.13 73.73,48.13 73.94,47.91 73.94,47.46 74.09,47.32 74.51,46.9 77.29,46.9 77.47,47.08 84.32,47.08 92.46,38.94 92.46,37.76 95.28,34.93 97.9,34.93 98.85,33.99 98.96,33.88 102.18,33.88 103.76,35.46 105.61,35.46 105.87,35.71 105.87,36.19 105.59,36.47 v1(104.28,36.47)
SOC_DDR3A_EDQ57: length 47.3
  TOP w0.152: U23.F33 v4(71.18,47.76) ; DIMM1.194 104.56,32.27 104.55,32.26 103.81,32.26 v1(103.56,32)
  L8_SIG3 w0.107: v4(71.18,47.76) 71.18,47.59 71.11,47.53 71.11,47.01 79.33,38.79 86.39,38.79 92.16,33.01 92.16,31.8 93.94,30.02 99.62,30.02 99.8,30.2 99.8,30.99 99.98,31.17 100.23,31.17 100.41,30.99 100.41,30.2 100.59,30.02 101.57,30.02 102.08,30.53 102.08,30.78 101.91,30.95 101.91,31.2 102.09,31.38 102.34,31.38 102.51,31.21 102.76,31.21 v1(103.56,32)
SOC_DDR3A_EDQ58: length 47.3
  TOP w0.152: DIMM1.192 104.58,32.87 v1(104.38,32.66) ; U23.F32 v4(71.18,48.56)
  L8_SIG3 w0.107: v1(104.38,32.66) 104.38,32.11 101.79,29.51 93.73,29.51 91.65,31.59 91.65,32.8 86.18,38.28 79.12,38.28 76.51,40.89 70.6,46.8 70.6,47.99 v4(71.18,48.56)
SOC_DDR3A_EDQ59: length 47.2
  TOP w0.152: U23.E32 v4(71.98,48.56) ; DIMM1.193 v1(99.19,32.57)
  L8_SIG3 w0.107: v4(71.98,48.56) 71.6,48.19 71.6,47.55 71.62,47.53 71.62,47.22 79.52,39.32 83.37,39.32 83.55,39.5 83.55,41.05 83.73,41.22 83.98,41.22 84.16,41.05 84.16,39.5 84.34,39.32 84.59,39.32 84.77,39.5 84.77,41.05 84.95,41.22 85.2,41.22 85.38,41.05 85.38,39.5 85.56,39.32 86.58,39.32 92.67,33.23 92.67,32.66 93.09,32.23 93.34,32.23 93.83,31.75 93.83,31.12 94.25,30.7 98.44,30.7 98.6,30.86 98.6,32.26 98.91,32.57 v1(99.19,32.57)
SOC_DDR3A_EDQ60: length 47.1
  TOP w0.152: v1(95.55,32.72) 96.01,33.17 DIMM1.191 ; U23.E33 v4(71.98,47.76)
  L8_SIG3 w0.107: v1(95.55,32.72) 97.82,32.72 98.09,32.44 98.09,31.52 97.78,31.21 97.53,31.21 97.35,31.39 97.35,32.13 97.17,32.31 96.92,32.31 96.74,32.13 96.74,31.39 96.56,31.21 96.31,31.21 96.13,31.39 96.13,32.13 95.95,32.31 95.7,32.31 95.52,32.13 95.52,31.39 95.34,31.21 94.59,31.21 94.34,31.46 94.34,33.15 93.9,33.58 93.03,33.58 87.97,38.64 87.97,39.53 85.11,42.38 84.86,42.38 84.55,42.07 84.29,42.07 84.12,42.25 84.12,42.5 84.43,42.82 84.43,43.07 84.25,43.25 84,43.25 83.68,42.93 83.43,42.93 83.25,43.11 83.25,43.36 83.57,43.68 83.57,43.93 81.73,45.77 78.01,45.77 77.83,45.58 73.97,45.58 72.13,47.43 72.13,47.53 71.98,47.68 v4(71.98,47.76)
SOC_DDR3A_EDQ61: length 47.1
  TOP w0.127: DIMM1.185 99.15,34.97 v1(100.28,36.09)
  TOP w0.152: U23.C32 v4(73.58,48.56)
  L8_SIG3 w0.107: v1(100.28,36.09) 100.28,36.5 99.83,36.95 98.42,36.95 98.3,36.83 98.3,35.63 98.18,35.51 98.01,35.51 97.89,35.63 97.89,36.83 97.78,36.95 97.61,36.95 97.49,36.83 97.49,35.63 97.37,35.51 97.2,35.51 97.08,35.63 97.08,36.83 96.96,36.95 96.79,36.95 96.68,36.83 96.68,36.11 96.56,35.99 96.39,35.99 96.27,36.11 96.27,36.83 96.15,36.95 95.72,36.95 95.6,37.07 95.6,37.83 95.48,37.95 95.31,37.95 95.19,37.83 95.19,37.07 95.08,36.95 94.91,36.95 94.79,37.07 94.79,37.83 94.67,37.95 94.5,37.95 94.38,37.83 94.38,37.07 94.26,36.95 93.99,36.95 92.96,37.97 92.96,39.15 84.53,47.59 77.26,47.59 77.08,47.4 75.34,47.4 75.33,47.39 75.02,47.39 74.74,47.67 74.74,47.91 74.47,48.19 73.95,48.19 73.81,48.33 73.8,48.33 v4(73.58,48.56)
SOC_DDR3A_EDQ62: length 47.1
  TOP w0.152: U23.D32 v4(72.78,48.56) ; DIMM1.182 106.86,35.87 v1(107.24,36.25)
  L8_SIG3 w0.107: v1(107.24,36.25) 106.69,36.79 106.69,37.78 106.51,37.96 105.36,37.96 105.18,38.14 105.18,38.39 105.36,38.57 106.51,38.57 106.69,38.74 106.69,39.46 106.17,39.98 104.99,39.98 104.64,39.62 104.01,39.62 103.35,40.28 100.71,40.28 100.28,39.85 99.39,39.85 99.03,40.21 94.06,40.21 92.57,41.7 85.07,49.2 75.98,49.2 75.74,48.96 73.18,48.96 v4(72.78,48.56)
SOC_DDR3A_EDQ63: length 47.3
  TOP w0.127: v1(99.15,35.55) 99.14,35.57 DIMM1.183
  TOP w0.152: U23.B32 v4(74.38,48.56)
  L8_SIG3 w0.107: v4(74.38,48.56) 74.61,48.56 74.98,48.19 75.72,48.19 75.86,48.05 76.57,48.05 76.62,48.1 84.74,48.1 93.96,38.87 96.16,38.87 96.28,38.75 96.28,37.74 96.4,37.62 96.57,37.62 96.69,37.74 96.69,38.75 96.81,38.87 97.38,38.87 98.79,37.46 99.85,37.46 99.97,37.58 99.97,38.13 100.09,38.25 100.26,38.25 100.38,38.13 100.38,37.58 100.5,37.46 100.67,37.46 100.79,37.58 100.79,38.13 100.9,38.25 101.07,38.25 101.19,38.13 101.19,37.58 101.31,37.46 101.48,37.46 101.6,37.58 101.6,38.13 101.72,38.25 101.89,38.25 102,38.13 102,37.58 102.12,37.46 102.54,37.46 102.61,37.39 102.61,36.83 102.49,36.71 102.13,36.71 102.01,36.59 102.01,36.42 102.13,36.3 102.49,36.3 102.61,36.19 102.61,35.87 102.23,35.48 99.22,35.48 v1(99.15,35.55)
SOC_DDR3A_EDQSN_0: length 48.4
  TOP w0.102: v1(103.98,89.95) 104.23,89.71 104.43,89.71 104.59,89.87 DIMM1.10 ; U23.C2 v4(73.58,73.36)
  L8_SIG3 w0.102: v4(73.58,73.36) 73.37,73.57 73.37,73.57 73.21,73.73 73.21,74.31 73.42,74.53 73.53,74.53 73.93,74.93 75.44,74.93 75.47,74.96 77.18,74.96 78.02,74.12 83.33,74.12 86.62,77.41 86.62,77.66 86.03,78.25 86.03,78.77 86.39,79.12 86.85,79.12 87.47,78.51 87.72,78.51 96.45,87.24 96.96,87.24 97.31,86.89 97.31,85.05 97.41,84.96 97.78,84.96 97.92,85.1 97.92,86.89 98.27,87.24 99.19,87.24 99.69,87.74 99.69,88.87 100.53,89.71 103.75,89.71 v1(103.98,89.95)
SOC_DDR3A_EDQSN_1: length 45.4
  TOP w0.102: U23.B4 v4(74.38,71.76) ; v1(95.78,85.5) 95.96,85.32 95.97,85.32 96.44,85.32 96.49,85.37 DIMM1.25
  L10_SIG4 w0.102: v1(95.78,85.5) 95.49,85.21 94.69,85.21 94.23,84.75 94.23,84.25 94.76,83.72 94.76,83.47 94.58,83.29 94.33,83.29 93.8,83.82 93.3,83.82 92.95,83.47 92.95,82.98 93.49,82.44 93.49,82.19 93.31,82.01 93.06,82.01 92.52,82.55 92.03,82.55 91.68,82.2 91.68,81.7 92.21,81.17 92.21,80.91 92.03,80.73 91.78,80.73 91.24,81.27 90.75,81.27 90.4,80.92 90.4,80.42 90.93,79.89 90.93,79.64 90.75,79.46 90.5,79.46 89.97,79.99 89.47,79.99 89.12,79.64 89.12,79.15 89.66,78.61 89.66,78.36 89.48,78.18 89.23,78.18 88.69,78.72 88.2,78.72 87.85,78.37 87.85,77.87 88.38,77.34 88.38,77.09 88.2,76.91 87.95,76.91 87.42,77.44 86.92,77.44 86.57,77.09 86.57,76.6 87.13,76.04 87.13,75.78 86.95,75.61 86.7,75.61 86.14,76.16 85.65,76.16 85.3,75.82 85.3,75.32 85.86,74.76 85.86,74.48 85.68,74.3 85.45,74.3 84.86,74.89 84.37,74.89 82.99,73.51 76.49,73.51 75.54,72.57 75.54,72.41 75.33,72.19 75.09,72.19 74.65,71.76 v4(74.38,71.76)
SOC_DDR3A_EDQSN_2: length 41.8
  TOP w0.102: DIMM1.43 98.47,79.97 98.72,79.71 99.17,79.71 99.25,79.64 99.5,79.64 99.59,79.73 99.59,80.01 99.5,80.1 v1(99.3,80.1) ; U23.A7 v4(75.18,69.36)
  L8_SIG3 w0.102: v1(99.3,80.1) 99.01,79.81 98.27,79.81 97.98,79.52 97.98,78.18 97.86,78.06 97.69,78.06 97.57,78.18 97.57,79.51 97.26,79.82 96.1,79.82 95.83,79.55 95.76,79.55 95.24,79.03 95.24,78.21 95.05,78.02 93.31,78.02 84.89,69.6 84.06,69.6 83.8,69.33 83.8,68.51 83.62,68.33 83.21,68.33 82.92,68.62 82.92,69.23 82.38,69.77 81.68,69.77 81.3,69.39 81.3,68.63 80.98,68.31 78.87,68.31 78.7,68.49 78.7,69.81 78.4,70.1 77.8,70.1 77.5,69.81 77.5,68.49 77.32,68.31 77.01,68.31 76.15,69.17 76.04,69.28 75.25,69.28 v4(75.18,69.36)
SOC_DDR3A_EDQSN_3: length 41.8
  TOP w0.102: v1(103.98,75) 104.18,74.81 104.47,74.81 104.53,74.87 DIMM1.60 ; U23.B10 v4(74.38,66.96)
  L10_SIG4 w0.102: v4(74.38,66.96) 74.81,67.39 75.33,67.39 75.38,67.44 81.47,67.44 82.03,66.88 90.32,66.88 91.36,67.92 91.36,68.17 91.11,68.42 91.11,68.91 91.46,69.27 91.96,69.27 92.21,69.02 92.46,69.02 92.64,69.19 92.64,69.45 92.41,69.67 92.41,70.07 92.76,70.42 93.21,70.42 93.33,70.29 93.74,70.29 97.14,73.7 97.14,73.96 98.21,75.02 99.71,75.02 100.02,74.71 101.13,74.71 101.31,74.89 101.31,76.41 101.66,76.76 102.15,76.76 102.5,76.41 102.5,74.89 102.68,74.71 103.69,74.71 v1(103.98,75)
SOC_DDR3A_EDQSN_4: length 45.7
  TOP w0.102: DIMM1.139 96.39,48.77 96.34,48.72 95.97,48.72 v1(95.78,48.9) ; U23.B24 v4(74.38,54.96)
  L10_SIG4 w0.102: v4(74.38,54.96) 74.81,55.39 75.39,55.39 75.65,55.13 78.16,55.13 81.72,51.57 81.72,50.18 82.26,49.64 83.76,49.64 83.93,49.48 84.55,48.86 84.89,48.51 84.9,48.51 87.8,45.61 88.34,45.61 88.52,45.78 88.52,47.86 88.87,48.21 89.36,48.21 89.71,47.86 89.71,45.78 89.89,45.61 90.14,45.61 90.32,45.78 90.32,47.97 90.68,48.33 91.18,48.33 91.52,47.99 91.52,45.78 91.7,45.61 91.95,45.61 92.13,45.78 92.13,47.86 92.48,48.21 92.97,48.21 93.32,47.86 93.32,45.78 93.5,45.61 94.34,45.61 94.58,45.85 94.58,48.32 94.87,48.62 95.5,48.62 v1(95.78,48.9)
SOC_DDR3A_EDQSN_5: length 41.3
  TOP w0.102: U23.B27 v4(74.38,52.56) ; v1(103.98,44.4) 104.19,44.2 104.55,44.2 104.62,44.27 DIMM1.154
  L8_SIG3 w0.102: v1(103.98,44.4) 103.69,44.11 102.26,44.11 102.08,44.29 102.08,46.28 101.73,46.63 101.24,46.63 100.89,46.28 100.89,44.34 100.76,44.21 98.77,44.21 95.47,47.51 95.4,47.57 95.4,49.35 91.83,52.92 75.9,52.92 75.89,52.93 75.02,52.93 74.66,52.56 v4(74.38,52.56)
SOC_DDR3A_EDQSN_6: length 46.2
  TOP w0.102: U23.B30 v4(74.38,50.16) ; DIMM1.171 96.39,39.17 96.31,39.09 95.99,39.09 v1(95.78,39.3)
  L10_SIG4 w0.102: v4(74.38,50.16) 74.39,50.16 74.75,50.53 75.36,50.53 76.07,49.81 76.57,49.32 76.57,47.63 76.85,47.35 77.64,47.35 77.93,47.06 77.93,46.65 77.64,46.36 76.34,46.36 76.23,46.24 76.23,46.07 76.34,45.96 77.38,45.96 77.67,45.67 77.67,45.25 77.38,44.96 76.3,44.96 76.19,44.85 76.19,44.67 76.3,44.56 77.23,44.56 77.52,44.27 77.52,43.86 77.23,43.57 76.59,43.57 76.47,43.45 76.47,42.88 79.32,40.03 82.8,40.03 82.92,40.15 82.92,42.33 83.21,42.62 83.62,42.62 83.91,42.33 83.91,40.15 84.03,40.03 84.2,40.03 84.32,40.15 84.32,40.92 84.63,41.23 85.01,41.23 85.31,40.94 85.31,40.15 85.43,40.03 86.21,40.03 86.21,40.03 86.63,40.03 93.6,40.03 94.61,39.01 95.49,39.01 v1(95.78,39.3)
SOC_DDR3A_EDQSN_7: length 47.3
  TOP w0.102: v1(103.98,34.8) 104.19,34.6 104.55,34.6 104.62,34.67 DIMM1.186 ; U23.D33 v4(72.78,47.76)
  L8_SIG3 w0.102: v4(72.78,47.76) 72.93,47.61 73.08,47.46 73.08,47.2 74.18,46.09 77.62,46.09 77.8,46.28 81.94,46.28 88.48,39.74 88.48,38.85 93.04,34.29 93.93,34.29 95,33.22 98.48,33.22 98.63,33.08 99.99,33.08 100.17,32.9 100.17,31.95 100.51,31.61 101.01,31.61 101.36,31.97 101.36,32.9 101.54,33.08 104.07,33.08 104.17,33.17 105.28,33.17 105.69,33.58 105.69,34.1 105.27,34.51 104.27,34.51 v1(103.98,34.8)
SOC_DDR3A_EDQSN_8: length 41.1
  TOP w0.102: v1(95.78,68.05) 96.03,67.81 96.23,67.81 96.39,67.97 DIMM1.75 ; U23.A22 v4(75.18,56.56)
  L8_SIG3 w0.102: v1(95.78,68.05) 95.55,67.82 95.1,67.82 94.81,67.53 94.81,66.7 94.69,66.58 94.52,66.58 94.4,66.7 94.4,67.53 94.11,67.82 93.58,67.82 92.68,66.92 92.68,64.83 90.84,62.99 90.67,62.99 90.33,63.33 89.89,63.33 89.6,63.03 89.6,62.65 89.97,62.29 89.97,62.12 89.66,61.81 89.49,61.81 89.06,62.24 88.65,62.24 88.36,61.95 88.36,61.54 88.79,61.11 88.79,60.94 88.67,60.82 88.5,60.82 88.07,61.25 87.66,61.25 87.37,60.96 87.37,60.55 87.8,60.12 87.8,59.95 87.68,59.83 87.51,59.83 87.09,60.26 86.67,60.26 86.38,59.97 86.38,59.56 86.81,59.13 86.81,58.96 86.69,58.84 86.52,58.84 86.1,59.27 85.69,59.27 85.4,58.98 85.4,58.57 85.82,58.14 85.82,57.97 85.7,57.85 85.54,57.85 85.11,58.28 84.7,58.28 84.41,57.99 84.41,57.58 84.83,57.15 84.83,56.98 84.35,56.5 80.22,56.5 80,56.72 79.77,56.72 79.55,56.5 79.14,56.5 78.92,56.72 78.69,56.72 78.47,56.5 78.24,56.5 78.02,56.72 77.79,56.72 77.57,56.5 77.34,56.5 77.12,56.72 76.89,56.72 76.67,56.5 76.44,56.5 76.22,56.72 75.99,56.72 75.77,56.5 75.24,56.5 v4(75.18,56.56)
SOC_DDR3A_EDQSP_0: length 48.4
  TOP w0.102: DIMM1.12 104.59,89.27 104.43,89.43 104.23,89.43 v1(103.98,89.18) ; U23.C1 v4(73.58,74.16)
  L8_SIG3 w0.102: v4(73.58,74.16) 74.05,74.64 75.36,74.64 75.5,74.5 75.73,74.5 75.89,74.66 76.12,74.66 76.29,74.5 76.52,74.5 76.68,74.66 77.06,74.66 77.22,74.5 77.22,74.4 77.22,74.29 77.38,74.13 77.49,74.13 77.59,74.13 77.89,73.83 78.16,73.83 78.3,73.69 78.53,73.69 78.67,73.83 78.9,73.83 79.04,73.69 79.27,73.69 79.41,73.83 79.64,73.83 79.78,73.69 80,73.69 80.14,73.83 80.37,73.83 80.51,73.69 80.74,73.69 80.88,73.83 81.11,73.83 81.25,73.69 81.48,73.69 81.62,73.83 81.85,73.83 81.99,73.69 82.25,73.69 82.39,73.83 83.45,73.83 86.92,77.29 86.92,77.78 86.33,78.37 86.33,78.65 86.51,78.83 86.73,78.83 87.35,78.21 87.84,78.21 96.58,86.95 96.84,86.95 97.02,86.77 97.02,84.93 97.29,84.66 97.9,84.66 98.22,84.98 98.22,86.77 98.39,86.95 99.31,86.95 99.99,87.62 99.99,88.75 100.66,89.42 101.21,89.42 101.4,89.23 101.62,89.23 101.81,89.42 102.02,89.42 102.22,89.23 102.43,89.23 102.62,89.42 102.84,89.42 103.03,89.23 103.24,89.23 103.44,89.42 103.75,89.42 v1(103.98,89.18)
SOC_DDR3A_EDQSP_1: length 45.4
  TOP w0.102: U23.A4 v4(75.18,71.76) ; v1(95.78,84.63) 95.61,84.63 95.53,84.71 95.53,84.96 95.63,85.06 96.27,85.06 96.34,84.99 96.34,84.88 96.45,84.77 DIMM1.27
  L10_SIG4 w0.102: v1(95.78,84.63) 95.49,84.92 94.82,84.92 94.52,84.63 94.52,84.37 95.05,83.84 95.05,83.35 94.7,83 94.21,83 93.68,83.53 93.42,83.53 93.24,83.35 93.24,83.1 93.78,82.56 93.78,82.07 93.43,81.72 92.93,81.72 92.4,82.25 92.15,82.25 91.97,82.07 91.97,81.82 92.5,81.29 92.5,80.79 92.15,80.44 91.66,80.44 91.12,80.98 90.87,80.98 90.69,80.8 90.69,80.55 91.23,80.01 91.23,79.52 90.88,79.17 90.38,79.17 89.85,79.7 89.59,79.7 89.42,79.52 89.42,79.27 89.95,78.74 89.95,78.24 89.6,77.89 89.11,77.89 88.57,78.43 88.32,78.43 88.14,78.25 88.14,77.99 88.67,77.46 88.67,76.97 88.32,76.61 87.83,76.61 87.3,77.15 87.04,77.15 86.86,76.97 86.86,76.72 87.42,76.16 87.42,75.66 87.07,75.31 86.58,75.31 86.02,75.87 85.77,75.87 85.59,75.69 85.59,75.44 86.15,74.88 86.15,74.36 85.8,74.01 85.33,74.01 84.74,74.6 84.49,74.6 83.11,73.22 76.61,73.22 75.84,72.44 75.84,72.29 75.45,71.9 75.32,71.9 v4(75.18,71.76)
SOC_DDR3A_EDQSP_2: length 41.8
  TOP w0.102: DIMM1.45 98.58,79.37 98.67,79.46 99.07,79.46 v1(99.3,79.23) ; U23.B7 v4(74.38,69.36)
  L8_SIG3 w0.102: v1(99.3,79.23) 99.01,79.52 98.39,79.52 98.27,79.4 98.27,78.06 97.98,77.77 97.57,77.77 97.28,78.06 97.28,79.39 97.14,79.52 96.22,79.52 95.95,79.26 95.89,79.26 95.53,78.91 95.53,78.09 95.17,77.72 93.43,77.72 85.01,69.3 84.18,69.3 84.09,69.21 84.09,68.39 83.74,68.04 83.09,68.04 82.63,68.5 82.63,69.11 82.25,69.48 81.8,69.48 81.59,69.27 81.59,68.51 81.1,68.02 78.75,68.02 78.4,68.37 78.4,69.68 78.28,69.81 77.92,69.81 77.79,69.68 77.79,68.37 77.45,68.02 76.89,68.02 76.43,68.48 76.07,68.84 75.92,68.99 75.02,68.99 74.81,69.21 74.81,69.24 74.68,69.36 v4(74.38,69.36)
SOC_DDR3A_EDQSP_3: length 41.8
  TOP w0.102: v1(103.98,74.13) 103.78,74.13 103.66,74.25 103.66,74.45 103.76,74.55 104.3,74.55 104.59,74.27 DIMM1.62 ; U23.A10 v4(75.18,66.96)
  L10_SIG4 w0.102: v1(103.98,74.13) 103.69,74.42 102.56,74.42 102.21,74.77 102.21,76.29 102.03,76.47 101.78,76.47 101.6,76.29 101.6,74.77 101.25,74.42 99.89,74.42 99.59,74.73 98.33,74.73 97.43,73.83 97.43,73.58 93.86,70 93.21,70 93.08,70.13 92.88,70.13 92.7,69.95 92.7,69.8 92.93,69.57 92.93,69.07 92.58,68.72 92.09,68.72 91.84,68.97 91.59,68.97 91.41,68.79 91.41,68.54 91.66,68.29 91.66,67.8 90.44,66.59 81.91,66.59 81.35,67.15 75.5,67.15 75.45,67.1 75.32,67.1 v4(75.18,66.96)
SOC_DDR3A_EDQSP_4: length 45.7
  TOP w0.102: DIMM1.141 96.49,48.17 96.2,48.46 95.57,48.46 95.45,48.34 95.45,48.09 95.51,48.03 95.78,48.03 v1(95.78,48.03) ; U23.A24 v4(75.18,54.96)
  L10_SIG4 w0.102: v4(75.18,54.96) 75.41,54.96 75.53,54.84 78.04,54.84 81.43,51.45 81.43,50.06 82.14,49.35 83.64,49.35 83.72,49.27 84.34,48.65 84.75,48.24 84.75,48.24 87.68,45.31 88.46,45.31 88.81,45.66 88.81,47.74 88.99,47.92 89.24,47.92 89.42,47.74 89.42,45.66 89.77,45.31 90.27,45.31 90.62,45.66 90.62,47.85 90.8,48.04 91.06,48.04 91.22,47.87 91.22,45.66 91.57,45.31 92.07,45.31 92.42,45.66 92.42,47.74 92.6,47.92 92.85,47.92 93.03,47.74 93.03,45.66 93.38,45.31 94.46,45.31 94.87,45.73 94.87,48.2 95,48.32 95.49,48.32 v1(95.78,48.03)
SOC_DDR3A_EDQSP_5: length 41.3
  TOP w0.102: v1(103.98,43.53) 103.76,43.53 103.68,43.61 103.68,43.87 103.76,43.94 104.34,43.94 104.62,43.67 DIMM1.156 ; U23.A27 v4(75.18,52.56)
  L8_SIG3 w0.102: v1(103.98,43.53) 103.69,43.82 102.14,43.82 101.79,44.17 101.79,46.16 101.61,46.34 101.36,46.34 101.18,46.16 101.18,44.17 100.93,43.92 98.65,43.92 95.26,47.3 95.11,47.45 95.11,49.23 91.71,52.63 75.62,52.63 75.55,52.56 v4(75.18,52.56)
SOC_DDR3A_EDQSP_6: length 46.2
  TOP w0.102: DIMM1.173 96.47,38.57 96.37,38.67 96.37,38.76 96.29,38.84 95.55,38.84 95.48,38.77 95.48,38.52 95.57,38.43 v1(95.78,38.43) ; U23.A30 v4(75.18,50.16)
  L10_SIG4 w0.102: v4(75.18,50.16) 75.31,50.16 76.07,49.4 76.28,49.2 76.28,47.51 76.73,47.06 77.52,47.06 77.64,46.94 77.64,46.77 77.52,46.65 76.22,46.65 75.93,46.36 75.93,45.95 76.22,45.66 77.26,45.66 77.38,45.54 77.38,45.38 77.26,45.26 76.18,45.26 75.9,44.97 75.9,44.55 76.18,44.27 77.11,44.27 77.23,44.15 77.23,43.98 77.11,43.86 76.47,43.86 76.18,43.57 76.18,42.76 79.2,39.74 82.92,39.74 83.21,40.03 83.21,42.21 83.33,42.33 83.5,42.33 83.62,42.21 83.62,40.03 83.91,39.74 84.32,39.74 84.61,40.03 84.61,40.8 84.75,40.94 84.89,40.94 85.01,40.82 85.01,40.03 85.3,39.74 86.09,39.74 86.75,39.74 86.76,39.74 93.48,39.74 94.49,38.72 95.49,38.72 v1(95.78,38.43)
SOC_DDR3A_EDQSP_7: length 47.3
  TOP w0.102: DIMM1.188 104.7,34.07 104.57,34.2 104.57,34.26 104.5,34.34 103.53,34.34 103.45,34.27 103.45,33.99 103.58,33.86 103.91,33.86 v1(103.98,33.93) ; U23.C33 v4(73.58,47.76)
  L8_SIG3 w0.102: v1(103.98,33.93) 104.27,34.22 105.15,34.22 105.4,33.97 105.4,33.7 105.16,33.47 104.05,33.47 103.95,33.37 101.42,33.37 101.07,33.02 101.07,32.09 100.89,31.9 100.63,31.9 100.46,32.08 100.46,33.02 100.11,33.37 98.75,33.37 98.6,33.52 95.12,33.52 94.05,34.58 93.16,34.58 88.77,38.97 88.77,39.86 82.06,46.57 77.68,46.57 77.49,46.38 74.31,46.38 73.37,47.32 73.37,47.55 v4(73.58,47.76)
SOC_DDR3A_EDQSP_8: length 41.1
  TOP w0.102: DIMM1.77 96.39,67.37 96.23,67.53 96.03,67.53 v1(95.78,67.28) ; U23.B22 v4(74.38,56.56)
  L8_SIG3 w0.102: v1(95.78,67.28) 95.54,67.53 95.22,67.53 95.1,67.41 95.1,66.58 94.81,66.29 94.4,66.29 94.11,66.58 94.11,67.41 93.99,67.53 93.7,67.53 92.97,66.79 92.97,64.71 90.96,62.69 90.55,62.69 90.21,63.03 90.01,63.03 89.9,62.91 89.9,62.77 90.26,62.41 90.26,62 89.78,61.52 89.37,61.52 88.94,61.94 88.77,61.94 88.65,61.82 88.65,61.66 89.08,61.23 89.08,60.82 88.79,60.53 88.38,60.53 87.95,60.96 87.78,60.96 87.67,60.84 87.67,60.67 88.09,60.24 88.09,59.83 87.8,59.54 87.39,59.54 86.96,59.97 86.8,59.97 86.68,59.85 86.68,59.68 87.1,59.25 87.1,58.84 86.81,58.55 86.4,58.55 85.98,58.98 85.81,58.98 85.69,58.86 85.69,58.69 86.12,58.26 86.12,57.85 85.83,57.56 85.41,57.56 84.99,57.99 84.82,57.99 84.7,57.87 84.7,57.7 85.13,57.27 85.13,56.86 84.47,56.2 75.86,56.2 75.84,56.18 74.97,56.18 74.6,56.56 v4(74.38,56.56)
SOC_DDR3A_EMRESETN: length 64.9
  TOP w0.152: U23.D20 v4(72.78,58.16) ; DIMM1.30 104.36,83.87 104.24,83.74 v2(104.19,83.74)
  L3_SIG1 w0.102: v4(72.78,58.16) 72.5,58.16 72.13,58.53 71.79,58.53 71.6,58.72 71.6,60.31 70.74,61.17 70.74,64.71 70.96,64.93 71.41,64.93 71.61,65.13 71.61,65.51 71.89,65.79 72.13,65.79 72.41,66.07 72.41,67.11 72.69,67.39 72.93,67.39 73.21,67.67 73.21,67.91 73.49,68.19 73.73,68.19 73.94,68.41 73.94,68.65 74.29,68.99 74.53,68.99 74.81,69.27 74.81,69.51 75.09,69.79 75.33,69.79 75.72,70.18 75.72,77.85 80.09,82.22 94.16,82.22 95.28,81.1 97.08,81.1 97.46,81.48 101.93,81.48 v2(104.19,83.74)
  BOTTOM w0.152: v4(72.78,58.16) 73.18,57.75 75.34,57.75 76.01,58.42 R469.1
SOC_DDR3A_EODT_0: length 68.4
  TOP w0.152: DIMM1.126 106.97,52.67 107.31,52.32 v1(107.8,52.32) ; U23.D12 v4(72.78,65.36)
  L10_SIG4 w0.107: v1(107.8,52.32) 107.52,52.32 107.04,52.81 107.04,53.57 107.24,53.78 108.65,53.78 108.83,53.6 108.83,52.35 109.01,52.17 109.26,52.17 109.44,52.35 109.44,53.6 109.62,53.78 111.89,53.78 112.22,54.1 112.22,54.66 111.72,55.16 108.9,55.16 108.72,54.98 108.72,54.46 108.54,54.28 108.29,54.28 108.11,54.46 108.11,54.98 107.93,55.16 107.32,55.16 106.67,55.81 105.28,55.81 105.08,55.61 105.08,54.53 104.78,54.23 103.94,54.23 103.68,54.48 103.68,54.84 102.98,55.54 102.98,55.55 102.77,55.77 102.77,56.62 101.75,57.64 101.16,57.64 99.79,56.28 99.15,56.28 97.39,54.52 95.03,54.52 94.32,55.23 93.41,55.23 92.5,56.14 92.5,57.36 92.82,57.68 92.82,58.77 92.03,59.57 80.91,59.57 80.27,60.21 78.27,60.21 76.86,61.61 75.95,61.61 75.33,60.99 73.73,60.99 73.42,60.99 73.14,61.27 73.14,64.71 73.08,64.77 73.08,65.07 72.8,65.36 v4(72.78,65.36)
SOC_DDR3A_EODT_1: length 69
  TOP w0.152: DIMM1.128 v1(104.28,52.07) ; U23.E11 v4(71.98,66.16)
  L3_SIG1 w0.102: v4(71.98,66.16) 71.7,66.16 71.33,65.79 70.29,65.79 70.01,65.51 70.01,61.21 70.22,60.99 70.24,60.99 70.74,60.49 70.74,57.27 71.09,56.93 71.33,56.93 71.54,56.71 71.54,56.47 71.89,56.13 72.13,56.13 72.34,55.91 72.34,55.67 72.69,55.33 72.93,55.33 73.14,55.11 73.14,54.87 73.49,54.53 73.73,54.53 73.94,54.31 73.94,54.07 74.29,53.73 74.53,53.73 74.74,53.51 74.74,53.27 75.02,52.99 75.27,52.99 75.54,52.71 75.54,50.01 75.53,50 75.53,49.37 76.08,48.83 76.19,48.71 76.19,48.41 76.18,48.39 76.18,46.91 77.18,45.91 81.99,45.91 82.21,45.69 82.21,45.65 83.39,44.48 90.02,44.48 92.01,46.47 92.01,47.79 93.17,48.95 94.06,48.95 95.53,47.47 97.18,47.47 99.38,49.68 100.44,49.68 100.77,49.35 101.55,49.35 102.03,49.83 102.03,53.24 102.46,53.67 105.94,53.67 106.43,53.19 106.43,52.3 106.2,52.07 v1(104.28,52.07)
SOC_DDR3A_ERAS#: length 68.4
  TOP w0.127: DIMM1.122 104.36,53.87 104.2,54.03 v1(104.2,54.74)
  TOP w0.152: U23.B13 v4(74.38,64.56)
  L10_SIG4 w0.107: v4(74.38,64.56) 73.94,64.13 73.94,62 74.19,61.75 75.49,61.75 75.86,62.12 77.07,62.12 78.48,60.72 80.48,60.72 81.12,60.07 91.13,60.07 91.47,60.42 93.81,60.42 94.27,59.96 94.27,57.82 93.95,57.51 93.37,57.51 93.01,57.15 93.01,56.35 93.5,55.85 94.41,55.85 95.24,55.03 97.18,55.03 99.05,56.9 99.69,56.9 99.83,57.04 99.84,57.04 100.58,57.78 100.58,58.12 100.91,58.45 102.97,58.45 104.37,59.84 104.88,59.84 105.06,59.66 105.06,58.95 105.24,58.78 105.49,58.78 105.67,58.95 105.67,59.66 105.85,59.84 106.88,59.84 107.41,60.38 108.21,60.38 108.85,59.74 109.7,59.74 110.34,59.11 110.34,58.47 109.91,58.04 108.87,58.04 108.69,58.22 108.69,59 108.51,59.18 108.26,59.18 108.08,59 108.08,58.22 107.91,58.04 105.96,58.04 105.78,57.86 105.78,57.5 105.6,57.32 105.35,57.32 105.17,57.5 105.17,57.86 104.99,58.04 103.96,58.04 103.28,57.35 103.28,55.98 103.49,55.76 103.49,55.75 104.19,55.05 104.19,54.99 104.2,54.98 v1(104.2,54.74)
SOC_DDR3A_EWE#: length 68.8
  TOP w0.152: U23.E13 v4(71.98,64.56) ; DIMM1.121 98.64,54.17 v1(99.09,53.72)
  L10_SIG4 w0.107: v1(99.09,53.72) 98.81,53.72 98.37,53.29 98.19,53.29 97.9,53 95.55,53 95.05,53.5 93.03,53.5 91.43,55.1 91.43,58.32 91.21,58.55 90.76,58.55 90.59,58.37 90.59,55.98 90.41,55.8 90.16,55.8 89.98,55.98 89.98,58.37 89.8,58.55 89.55,58.55 89.37,58.37 89.37,55.98 89.19,55.8 88.94,55.8 88.76,55.98 88.76,58.37 88.58,58.55 88.21,58.55 87.98,58.32 87.98,56.42 87.8,56.24 87.54,56.24 87.37,56.42 87.37,58.33 87.19,58.5 86.94,58.5 86.76,58.33 86.76,56.42 86.58,56.24 86.33,56.24 86.15,56.42 86.15,58.3 85.97,58.48 85.72,58.48 85.54,58.3 85.54,56.27 85.36,56.09 85.11,56.09 84.93,56.27 84.93,58.35 84.75,58.53 84.5,58.53 84.32,58.35 84.32,56.24 84.14,56.06 83.89,56.06 83.71,56.24 83.71,58.25 83.5,58.45 83.25,58.45 83.1,58.3 83.1,57.08 82.92,56.9 82.67,56.9 82.49,57.08 82.49,58.15 82.09,58.55 80.49,58.55 79.85,59.19 77.85,59.19 76.44,60.6 75.51,60.6 75.5,60.59 73.92,60.59 72.12,60.59 71.61,61.1 71.61,64.19 v4(71.98,64.56)
SOC_DEBUG_LED1: length 10.6
  TOP w0.152: v1(165.37,128.92) 169.32,124.97 R48.1
  BOTTOM w0.152: U48.3 v1(165.37,128.92)
SOC_DEBUG_LED2: length 9.4
  BOTTOM w0.152: R340.1 171.68,121.28 169.06,123.9 169.06,126.39 168.48,126.97 U48.6
SOC_DEBUG_LED3: length 14.7
  TOP w0.152: R70.1 v1(171.96,120.14)
  L5_SIG2 w0.107: v1(162.56,126.32) 165.94,126.32 169.42,122.84 170.74,122.84 171.96,121.62 v1(171.96,120.14)
  BOTTOM w0.152: U48.8 v1(162.56,126.32)
SOC_DEBUG_LED4: length 19.6
  L5_SIG2 w0.107: v1(171.96,116.59) 172.34,116.97 172.34,121.56 170.64,123.27 169.54,123.27 164.54,128.27 v1(163.19,128.27)
  BOTTOM w0.152: v1(171.96,116.59) 172.01,116.64 R353.1 ; U48.11 v1(163.19,128.27)
SOC_EMIFA00: length 66.7
  TOP w0.152: U23.P3 v4(64.78,72.56)
  L10_SIG4 w0.107: v4(64.78,72.56) 64.55,72.79 64.55,72.8 64.19,73.16 64.19,79.89 63.33,80.75 63.33,89.64 58.73,94.24 58.73,99.12 59.13,99.52 59.13,104.37 57.33,106.17 56.26,106.17 55.27,107.15 53.73,107.15 52.72,108.17 52.72,111.72 52.28,112.15 51.96,112.15 51.92,112.12 51.31,112.12 51.31,112.12 51.29,112.12 49.09,114.32 49.09,117.66 47.52,119.23 43.15,119.23 42.92,119 42.92,116.24 v1(43.31,115.85)
  BOTTOM w0.152: v1(43.31,115.85) U51.2
SOC_EMIFA01: length 94
  TOP w0.152: U23.P5 v4(64.78,70.96)
  L5_SIG2 w0.107: v1(43.3,116.85) 43.3,118.31 45.14,120.14 48.62,120.14 49.4,120.93 59.99,120.93 60.98,119.95 63.31,119.95 67.66,115.59 67.66,109.4 66.07,107.81 66.07,104.54 69.14,101.47 69.14,92.53 71.22,90.45 71.22,86.69 69.27,84.73 69.27,76.9 71.51,74.66 72.06,74.66 72.41,74.31 72.41,73.21 72.69,72.93 72.93,72.93 73.21,72.65 73.21,70.87 72.93,70.59 72.69,70.59 72.34,70.25 72.34,70.01 72.13,69.79 70.29,69.79 70.01,69.51 70.01,69.27 69.73,68.99 67.89,68.99 67.61,68.71 67.61,68.47 67.33,68.19 67.02,68.19 66.81,68.41 66.81,68.65 66.53,68.93 65.49,68.93 65.21,69.21 65.21,70.31 65.22,70.33 65.22,70.51 65,70.72 65,70.73 v4(64.78,70.96)
  BOTTOM w0.152: v1(43.3,116.85) 43.31,116.85 U51.4
SOC_EMIFA02: length 62
  TOP w0.152: U23.U6 v4(62.38,70.16)
  L5_SIG2 w0.107: v4(62.38,70.16) 61.66,70.16 61.31,70.51 61.31,73.86 61.54,74.09 61.55,74.09 61.62,74.17 61.62,75.08 61.39,75.31 58.65,78.05 58.65,80.09 58.04,80.7 58.04,83.13 55.56,85.61 52.54,85.61 50.49,87.65 48.74,87.65 47.11,89.28 46.76,89.28 46.44,89.6 46.44,89.95 46.11,90.28 45.76,90.28 43.89,92.14 43.89,100.64 45.08,101.83 45.08,105.57 45.77,106.26 45.77,109.03 44.7,110.1 44.7,117.45 v1(44.3,117.85)
  BOTTOM w0.152: v1(44.3,117.85) U51.6
SOC_EMIFA03: length 60.1
  TOP w0.152: U23.V6 v4(60.78,70.16)
  L10_SIG4 w0.107: v4(60.78,70.16) 60.78,70.44 60.49,70.73 60.41,70.81 60.41,74.63 56.06,78.97 56.06,99.26 50.77,104.55 50.77,112.31 47.26,115.82 46.04,115.82 45.81,116.05 45.81,118.2 45.16,118.85 v1(43.31,118.85)
  BOTTOM w0.152: v1(43.31,118.85) U51.8
SOC_EMIFA04: length 75
  TOP w0.152: U23.P6 v4(64.78,70.16)
  L5_SIG2 w0.107: v1(47.61,120.77) 47.05,121.32 44.67,121.32 42.8,119.45 42.8,114.21 43.04,113.97 43.04,112.84 41.17,110.97 41.17,93.66 41.93,92.9 41.93,88 43.65,86.28 49.89,86.28 51.56,84.61 51.56,82.57 58.01,76.12 58.01,71.61 58.29,71.33 59.33,71.33 59.61,71.05 59.61,70.01 59.86,69.76 U23.P6 v4(64.78,70.16)
  BOTTOM w0.152: U51.11 v1(47.61,120.77)
SOC_EMIFA05: length 80.9
  TOP w0.152: U23.N6 v4(65.58,70.16)
  L5_SIG2 w0.107: v4(65.58,70.16) 66.01,69.73 66.53,69.73 66.81,69.45 66.81,69.21 67.02,68.99 67.33,68.99 67.54,69.21 67.54,69.45 67.85,69.76 69.7,69.76 70.01,70.07 70.01,70.31 70.29,70.59 72.13,70.59 72.34,70.81 72.34,72.71 72.13,72.93 71.89,72.93 71.61,73.21 71.61,74.25 71.33,74.53 71.31,74.53 69.04,76.8 69.04,84.91 70.9,86.78 70.9,90.42 68.91,92.41 68.91,100.13 64.8,104.24 64.8,106.82 65.86,107.89 65.86,107.9 66.11,108.15 66.13,108.15 67.46,109.48 67.46,115.51 63.55,119.42 59.27,119.42 58.62,120.06 51.38,120.06 v1(50.16,118.85)
  BOTTOM w0.152: U51.13 v1(50.16,118.85)
SOC_EMIFA06: length 57.7
  TOP w0.152: U23.M3 v4(66.38,72.56)
  L10_SIG4 w0.107: v1(50.16,117.85) 50.22,117.8 51.61,117.8 51.87,118.06 52.28,118.06 52.65,117.69 52.65,114.81 52.1,114.25 52.1,113.46 52.1,113.45 52.1,113.42 52.45,113.07 52.66,113.07 53.63,112.09 53.63,109.79 53.96,109.47 56.25,109.47 62.71,103 62.71,102.11 64.04,100.79 64.04,92.27 64.31,92 64.31,81.26 65.13,80.44 65.13,74.57 66.01,73.69 66.01,73.12 66.38,72.75 v4(66.38,72.56)
  BOTTOM w0.152: U51.15 v1(50.16,117.85)
SOC_EMIFA07: length 54.6
  TOP w0.152: U23.N4 v4(65.58,71.76)
  L10_SIG4 w0.107: v4(65.58,71.76) 65.14,72.19 65.14,72.71 65.03,72.83 64.43,73.42 64.41,73.42 64.41,80.07 63.56,80.92 63.56,91.01 60.4,94.17 60.4,102.36 60.45,102.41 60.45,103.38 55.34,108.5 53.96,108.5 52.95,109.51 52.95,111.81 52.37,112.38 52.17,112.38 50.64,113.91 50.64,116.37 v1(50.16,116.85)
  BOTTOM w0.152: U51.17 v1(50.16,116.85)
SOC_EMIFA08: length 70
  TOP w0.152: U23.N5 v4(65.58,70.96) ; U6.2 v1(52.12,119.68)
  L10_SIG4 w0.107: v4(65.58,70.96) 65.94,70.59 66.53,70.59 66.53,70.6 66.81,70.32 66.81,70.01 67.02,69.79 68.13,69.79 68.34,70.01 68.34,70.37 68.55,70.58 68.91,70.58 69.14,70.81 69.14,70.93 69.16,71.07 69.16,72.67 69.42,72.93 69.66,72.93 69.94,73.21 69.94,77.08 71.83,78.96 71.83,91.05 70.02,92.86 70.02,99.8 69.6,100.23 69.6,108.96 64.29,114.27 64.29,116.26 61.49,119.05 59.66,119.05 58.65,120.06 52.5,120.06 v1(52.12,119.68)
SOC_EMIFA09: length 69.3
  TOP w0.152: U23.M5 v4(66.38,70.96) ; U6.4 v1(52.12,118.68)
  L10_SIG4 w0.107: v4(66.38,70.96) 66.67,70.96 66.81,70.83 66.81,70.81 67.02,70.59 67.33,70.59 67.61,70.87 67.61,72.71 67.89,72.99 68.13,72.99 68.4,73.27 68.4,77.15 69.14,77.88 69.14,80.09 70.31,81.25 70.31,85.55 71.3,86.54 71.3,90.92 69.57,92.65 69.57,99.37 68.5,100.43 68.5,105.99 64.43,110.07 60.11,110.07 59.29,110.89 57.78,110.89 57.28,111.39 57.09,111.39 56.87,111.62 56.87,114.53 58.37,116.02 58.37,118.39 57.96,118.8 57.83,118.8 57.48,119.15 55.75,119.15 55.42,119.49 52.92,119.49 v1(52.12,118.68)
SOC_EMIFA10: length 55.1
  TOP w0.152: U23.M4 v4(66.38,71.76) ; U6.6 v1(52.12,117.68)
  L10_SIG4 w0.107: v1(52.12,117.68) 51.77,117.33 51.77,113.43 52.36,112.84 52.56,112.84 53.4,112 53.4,109.7 53.86,109.24 56.15,109.24 62.48,102.91 62.48,101.63 63.37,100.74 63.37,92.53 64.08,91.82 64.08,81.14 64.9,80.32 64.9,73.54 65.43,73 65.65,73 66.01,72.65 66.01,72.41 66.38,72.04 v4(66.38,71.76)
SOC_EMIFA11: length 90.9
  TOP w0.152: U23.L1 v4(67.18,74.16) ; U6.8 v1(52.21,116.68)
  L5_SIG2 w0.107: v1(63.42,109.42) 63.02,109.02 59.11,109.02 58.95,108.86 54.56,108.86 53.27,110.15 51.96,110.15 51.66,109.86 51.16,109.86 50.75,109.45 50.75,104.74 51.09,104.4 51.09,101.82 48.47,99.2 48.47,95.29 49.68,94.08 51.07,94.08 51.36,94.36 54.57,94.36 59.22,89.71 59.73,89.71 61.79,87.66 62.18,87.66 62.99,86.84 62.99,78.66 67.18,74.47 v4(67.18,74.16)
  L8_SIG3 w0.107: v1(52.21,116.68) 53.63,118.11 53.63,119.42 54.74,120.52 58.14,120.52 59.18,119.48 63.56,119.48 65.35,117.68 65.35,111.35 v1(63.42,109.42)
  BOTTOM w0.102: v1(63.42,109.42) 63.47,109.47 U53.C4
SOC_EMIFA12: length 84.9
  TOP w0.152: U6.11 55.47,115.67 v2(57.3,115.67) ; U23.U5 v4(62.38,70.96)
  L3_SIG1 w0.102: v2(57.3,115.67) 62.2,115.67 63.87,114.01 v1(63.87,112.7)
  L5_SIG2 w0.107: v1(63.87,112.7) 63.18,113.39 60.3,113.39 59.69,114 55.97,114 55.37,114.6 48.31,114.6 45.81,112.1 45.81,109.64 46.31,109.14 46.31,106.15 45.54,105.38 45.54,101.64 44.35,100.45 44.35,92.8 45.4,91.74 46.65,91.74 49.72,88.67 51.08,88.67 53.68,86.07 55.77,86.07 57.08,84.76 57.91,84.76 59.33,83.33 59.33,78.01 62.09,75.25 62.09,73.99 61.73,73.63 61.73,71.07 61.85,70.96 v4(62.38,70.96)
  BOTTOM w0.152: U53.D5 v1(63.87,112.7)
SOC_EMIFA13: length 92.9
  TOP w0.152: U23.T5 v4(63.18,70.96) ; U6.13 v1(57.25,116.68)
  L5_SIG2 w0.107: v1(57.25,116.68) 58.52,116.68 58.75,116.45 65.94,116.45 67.05,115.34 67.05,110.56 66.93,110.44 65.3,110.44 64.03,111.71 63.04,111.71 61.57,113.18 60.22,113.18 59.61,113.79 55.85,113.79 55.27,114.38 50.36,114.38 48.1,112.11 48.1,106.63 47.36,105.89 46.37,105.89 45.77,105.29 45.77,101.54 44.58,100.36 44.58,92.89 45.5,91.97 46.74,91.97 49.81,88.9 51.17,88.9 53.78,86.29 55.87,86.29 57.16,85 57.99,85 59.56,83.43 59.56,78.11 62.32,75.35 62.32,73.89 61.94,73.51 61.94,71.56 62.11,71.39 62.46,71.39 62.9,70.96 v4(63.18,70.96)
SOC_EMIFA14: length 57.2
  TOP w0.152: U6.15 v1(57.25,117.68) ; U23.L3 v4(67.18,72.56)
  L10_SIG4 w0.107: v1(57.25,117.68) 56.64,117.07 56.64,110.84 57.09,110.39 57.41,110.39 57.67,110.65 59.02,110.65 59.87,109.8 64.37,109.8 68.28,105.9 68.28,100.28 69.34,99.22 69.34,92.47 68.76,91.9 68.76,88.54 68.91,88.39 68.91,78.33 67.61,77.03 67.61,73 67.4,72.8 67.4,72.79 v4(67.18,72.56)
SOC_EMIFA15: length 91
  TOP w0.152: U6.17 v1(57.25,118.68)
  TOP w0.254: U23.T3 v4(63.18,72.56)
  L5_SIG2 w0.107: v4(63.18,72.56) 62.96,72.78 62.96,75.35 61.14,77.18 61.14,82.98 60.48,83.64 58.66,85.45 57.35,85.45 56.06,86.75 54.27,86.75 53.58,87.44 53.58,88.2 52.43,89.36 50,89.36 48.22,91.14 48.22,92.93 47.52,93.62 46.03,93.62 45.08,94.57 45.08,100.21 46.86,101.99 46.86,104.06 47.25,104.44 47.47,104.44 48.56,105.53 48.56,111.25 49.55,112.24 49.63,112.24 50.27,112.88 55.58,112.88 56.06,112.39 57.25,112.39 57.96,111.69 58.17,111.69 60.05,109.8 64.52,109.8 64.9,109.42 66.57,109.42 67.25,110.1 67.25,115.43 64.52,118.16 58.83,118.16 58.3,118.68 v1(57.25,118.68)
SOC_EMIFA16: length 54.7
  TOP w0.152: U23.L2 v4(67.18,73.36) ; U10.2 52.5,112.77 52.3,112.98 52.3,113.44 v1(52.48,113.61)
  L10_SIG4 w0.107: v1(52.48,113.61) 52.79,113.3 54.7,113.3 56.08,111.91 56.08,111.08 57,110.16 57.43,110.16 58.58,109.02 60.2,109.02 60.68,109.5 62.71,109.5 66.55,105.66 66.55,105.66 66.85,105.36 66.85,105.36 67.79,104.42 67.79,100.25 69.11,98.94 69.11,92.57 68.92,92.38 67.51,90.97 67.51,78.08 66.8,77.37 66.8,73.91 67.18,73.54 v4(67.18,73.36)
SOC_EMIFA17: length 52.3
  TOP w0.152: U23.L5 v4(67.18,70.96) ; U10.4 v1(52.12,111.77)
  L10_SIG4 w0.107: v1(52.12,111.77) 51.35,111.77 51,111.43 51,108.79 52.25,107.54 53.01,107.54 53.63,106.92 55,106.92 58.42,103.5 58.42,94.23 63.1,89.54 63.1,80.57 63.96,79.72 63.96,73.1 64.34,72.71 64.34,72.7 64.41,72.64 64.41,71.61 64.65,71.36 66.74,71.36 67.14,70.96 v4(67.18,70.96)
SOC_EMIFA18: length 58.4
  TOP w0.152: U23.M6 v4(66.38,70.16) ; U10.6 v1(52.12,110.77)
  L5_SIG2 w0.107: v1(52.12,110.77) 51.35,110.77 50.55,109.97 50.55,109.96 50.47,109.89 50.47,106.23 48.32,104.08 48.32,102.48 47.65,101.81 47.65,100.82 47.53,100.7 47.01,100.18 46.6,100.18 45.77,99.34 45.77,94.97 46.42,94.31 47.83,94.31 50.32,91.82 51.61,91.82 51.73,91.69 53.85,91.69 56.69,88.85 56.69,88.09 56.69,88.09 56.69,87.96 57.07,87.58 58.01,87.58 59.3,86.29 60.46,86.29 61.82,84.93 61.82,77.48 64.34,74.96 64.34,71.58 64.6,71.33 64.93,71.33 65.21,71.05 65.21,70.81 65.42,70.59 65.67,70.59 66.1,70.16 v4(66.38,70.16)
SOC_EMIFA19: length 53.5
  TOP w0.152: U10.8 v1(52.12,109.77) ; U23.K2 v4(67.98,73.36)
  L5_SIG2 w0.107: v1(52.12,109.77) 52.12,109.02 53.95,107.19 53.95,104.34 48.7,99.1 48.7,95.38 49.76,94.32 50.15,94.32 51.08,95.25 51.4,95.25 52.06,94.59 54.66,94.59 59.31,89.94 59.83,89.94 61.1,88.67 62.21,88.67 63.22,87.66 63.22,78.76 67.58,74.4 67.58,73.77 67.98,73.37 v4(67.98,73.36)
SOC_EMIFA20: length 50.6
  TOP w0.152: U23.K1 v4(67.98,74.16) ; U10.11 v1(55.44,107.86)
  L5_SIG2 w0.107: v4(67.98,74.16) 67.98,74.33 63.45,78.85 63.45,87.76 62.26,88.95 61.14,88.95 59.92,90.17 59.4,90.17 53.87,95.7 53.23,96.34 51.37,96.34 50.16,95.13 49.49,95.13 48.93,95.69 48.93,98.97 54.18,104.21 54.18,106.6 v1(55.44,107.86)
SOC_EMIFA21: length 50
  TOP w0.152: U10.13 v1(57.25,109.77) ; U23.L4 v4(67.18,71.76)
  L10_SIG4 w0.107: v4(67.18,71.76) 67.18,72.04 66.8,72.41 66.8,73.45 66.74,73.51 66.74,73.51 66.53,73.73 66.26,73.73 65.56,74.43 65.56,77.07 66.5,78.01 66.5,89.32 67.28,90.1 67.28,91.06 68.88,92.67 68.88,97.91 64.86,101.93 64.86,106.94 62.7,109.1 60.68,109.1 60.32,108.74 57.56,108.74 57.25,109.04 v1(57.25,109.77)
SOC_EMIFA22: length 62.2
  TOP w0.152: U23.R3 v4(63.98,72.56) ; U10.15 v1(57.25,110.77)
  L5_SIG2 w0.107: v1(57.25,110.77) 57.25,110.77 55.44,112.58 52.35,112.58 51.46,111.68 50.15,111.68 49.62,111.15 49.46,111.15 49.01,110.7 49.01,105.1 48.09,104.17 48.09,102.57 47.42,101.91 47.42,100.91 46.91,100.41 46.51,100.41 45.54,99.44 45.54,94.87 46.33,94.08 47.73,94.08 50.22,91.59 51.51,91.59 51.64,91.47 52.57,91.47 58.08,85.95 60.47,85.95 61.59,84.83 61.59,77.39 63.98,75.01 v4(63.98,72.56)
SOC_EMIFA23: length 55.3
  TOP w0.152: U10.17 v1(57.25,111.77) ; U23.L6 v4(67.18,70.16)
  L10_SIG4 w0.107: v4(67.18,70.16) 67.4,70.39 67.41,70.39 67.62,70.59 68.13,70.59 68.39,70.86 68.39,72.76 68.62,72.99 68.93,72.99 69.21,73.27 69.21,76.66 70.54,77.99 70.54,85.42 71.53,86.41 71.53,90.98 69.79,92.71 69.79,99.52 69.14,100.18 69.14,106.24 66.4,108.98 66.4,109.6 65.38,110.62 63.47,110.62 62.97,111.12 62.09,111.12 61.44,111.77 v1(57.25,111.77)
SOC_EMIFBE0Z: length 51.5
  TOP w0.152: U23.AA2 v4(58.38,73.36)
  L10_SIG4 w0.107: v1(49.47,112.62) 48.46,111.61 48.46,104.98 49.07,104.37 49.07,98.53 51.57,96.04 51.57,93.23 53.26,91.53 53.26,89.72 51.12,87.58 49.57,87.58 47.42,85.43 47.42,84.45 47.57,84.3 48.41,84.3 57.96,74.75 57.96,73.77 v4(58.38,73.36)
  BOTTOM w0.152: U54.2 v1(49.47,112.62)
SOC_EMIFBE1Z: length 57.1
  TOP w0.152: U23.R6 v4(63.98,70.16)
  L5_SIG2 w0.107: v4(63.98,70.16) 64.34,70.53 64.34,71.11 64.13,71.33 63.8,71.33 63.61,71.52 63.61,73.17 63.19,73.59 63.19,75.45 61.37,77.27 61.37,83.08 58.76,85.68 57.48,85.68 56.18,86.98 54.36,86.98 53.81,87.53 53.81,88.46 52.06,90.22 49.46,90.22 48.45,91.23 48.45,93.02 48.26,93.21 48.26,93.22 48.25,93.22 47.62,93.85 46.12,93.85 45.31,94.66 45.31,100.12 47.86,102.67 47.86,104.45 48.78,105.38 48.78,110.94 v1(49.48,111.63)
  BOTTOM w0.152: U54.4 49.39,111.62 49.4,111.63 v1(49.48,111.63)
SOC_EMIFCE0Z: length 83.5
  TOP w0.152: U23.AA1 v4(58.38,74.16)
  L5_SIG2 w0.107: v1(64.67,111.9) 64.67,113.76 63.16,115.27 50,115.27 48.34,116.93 48.34,118.41 47.59,119.16 45.06,119.16 43.69,117.78 43.69,112.85 42.98,112.14 42.98,106.5 41.4,104.93 41.4,93.76 42.2,92.96 42.2,88.05 43.74,86.51 49.98,86.51 51.79,84.7 51.79,83.76 51.87,83.68 52.95,83.68 53.26,83.36 53.26,81.19 58.38,76.08 v4(58.38,74.16)
  BOTTOM w0.152: U53.C6 v1(64.67,111.9)
SOC_EMIFCE1Z: length 60.3
  TOP w0.152: v1(52.22,84.06) 50.8,85.48 R184.1 ; v1(49.47,110.62) 49.73,110.36 49.73,109.94 49.99,109.69 50.06,109.69 50.91,108.84 51.58,108.84 51.68,108.95 52.43,108.95 52.45,108.93 52.54,108.93 53.48,107.99 53.48,107.63 54.83,106.27 56.08,106.27 57.19,105.17 U13.1 ; U23.Y4 v4(59.18,71.76)
  L5_SIG2 w0.107: v4(59.18,71.76) 58.78,72.16 58.78,76.02 53.49,81.31 53.49,83.46 52.89,84.06 v1(52.22,84.06)
  L10_SIG4 w0.107: v1(52.22,84.06) 53.77,85.61 53.77,97.48 49.92,101.33 49.92,102.92 49.82,103.02 49.82,103.51 49.92,103.61 49.92,103.92 49.46,104.38 49.38,104.38 48.95,104.82 48.95,110.1 v1(49.47,110.62)
  BOTTOM w0.152: U54.6 v1(49.47,110.62)
SOC_EMIFCE2Z: length 72.9
  TOP w0.152: v1(49.39,109.6) 49.39,109.14 50,108.54 51.71,108.54 51.81,108.64 52.31,108.64 52.33,108.63 52.41,108.63 53.17,107.86 53.17,107.5 54.7,105.97 55.81,105.97 57.64,104.14 58.92,104.14 59.22,104.44 U13.3 ; U23.W1 v4(59.98,74.16) 59.98,76.71 61.08,77.82 61.08,80.68 61.08,81.34 61.08,82.5 61.08,82.5 61.08,83.36 60.34,84.1 57.02,84.1 55.21,85.91 R182.1
  L10_SIG4 w0.107: v1(49.39,109.6) 49.39,105.46 50.05,104.8 50.2,104.8 55.84,99.17 55.84,78.87 59.98,74.73 v4(59.98,74.16)
  BOTTOM w0.152: U54.8 49.33,109.62 49.35,109.6 v1(49.39,109.6)
SOC_EMIFCE3Z: length 80.4
  TOP w0.152: v1(56.41,106.55) 56.93,107.07 U13.6 ; U23.Y1 v4(59.18,74.16) 59.18,76.37 60.71,77.9 60.71,83.3 60.21,83.79 56.9,83.79 55.27,85.42 53.29,85.42 52.8,85.91 R183.1
  L3_SIG1 w0.107: v1(45.01,107.7) 53.44,107.7 54.59,106.55 v1(56.41,106.55)
  L5_SIG2 w0.107: v1(45.01,107.7) 41.63,104.32 41.63,93.85 42.35,93.13 42.43,93.06 42.43,89.67 45.35,86.74 50.12,86.74 52.57,84.29 52.99,84.29 53.72,83.55 53.72,81.4 59.18,75.95 v4(59.18,74.16)
  BOTTOM w0.152: v1(45.01,107.7) 45.67,107.7 46.11,108.14 U54.11
SOC_EMIFD0: length 77.9
  TOP w0.152: U23.G5 v4(70.38,70.96) ; v1(49.85,95.51) 49.82,95.54 U16.11
  L5_SIG2 w0.107: v1(49.85,95.51) 49.43,95.51 49.16,95.78 49.16,98.87 49.71,99.42 54.83,99.42 62.08,92.18 65.93,92.18 67.59,90.52 67.59,83.9 67.87,83.62 67.87,77.47 70.79,74.55 70.79,73.22 71.09,72.93 71.33,72.93 71.54,72.71 71.54,71.61 71.33,71.39 70.82,71.39 70.61,71.19 70.6,71.19 v4(70.38,70.96)
  BOTTOM w0.102: 62.26,115.21 62.41,115.21 62.51,115.12 63.09,115.12 U53.H4
  BOTTOM w0.152: 62.26,115.21 61.82,115.21 61.44,114.83 61.44,112.37 60.66,111.59 60.66,108.05 59.51,106.9 59.51,104.67 50.67,95.83 50.16,95.83 v1(49.85,95.51)
SOC_EMIFD1: length 65.2
  TOP w0.152: U23.K3 v4(67.98,72.56) ; U16.12 v1(49.54,96.04)
  L5_SIG2 w0.107: v1(49.54,96.04) 49.65,95.93 50.62,95.93 51.26,96.57 53.33,96.57 53.97,95.93 53.97,95.93 59.46,90.44 62.29,90.44 63.68,89.05 63.68,79.07 68.38,74.37 68.38,72.97 68.2,72.8 68.2,72.79 v4(67.98,72.56)
  BOTTOM w0.102: 62.51,115.88 63.05,115.88 U53.J4
  BOTTOM w0.152: 62.51,115.88 61.21,115.88 60.35,115.02 60.35,109.17 59.18,108 59.18,104.77 50.55,96.14 49.64,96.14 v1(49.54,96.04)
SOC_EMIFD2: length 67.5
  TOP w0.152: U16.13 v1(50.2,96.54) ; U23.K4 v4(67.98,71.76)
  L5_SIG2 w0.107: v1(50.2,96.54) 50.69,97.03 53.52,97.03 54.16,96.39 54.42,96.12 59.53,91.01 62.36,91.01 64.14,89.24 64.14,79.31 68.91,74.53 68.93,74.53 69.18,74.28 69.18,73.24 68.93,72.99 68.69,72.99 68.41,72.71 68.41,72.19 v4(67.98,71.76)
  BOTTOM w0.152: v1(50.2,96.54) 50.52,96.54 58.88,104.9 58.88,108.13 60.1,109.35 60.1,115.9 61.44,117.24 62.21,117.24 62.48,117.51 63.06,117.51 U53.K4
SOC_EMIFD3: length 66.4
  TOP w0.152: U16.14 49.54,97.04 49.62,97.04 v1(49.68,97.1) ; U23.J1 v4(68.78,74.16)
  L5_SIG2 w0.107: v4(68.78,74.16) 68.78,74.3 63.91,79.16 63.91,89.14 62.39,90.67 59.56,90.67 54.2,96.03 54.06,96.16 53.42,96.8 51.16,96.8 50.52,96.16 50.05,96.16 49.68,96.52 v1(49.68,97.1)
  BOTTOM w0.152: U53.K5 64.27,117.58 64.08,117.76 62.37,117.76 62.11,117.49 61.33,117.49 59.84,116 59.84,109.45 58.57,108.18 58.57,105.02 50.65,97.1 v1(49.68,97.1)
SOC_EMIFD4: length 72.9
  TOP w0.152: U23.H5 v4(69.58,70.96) ; U16.15 50.52,97.54 v1(50.85,97.89)
  L5_SIG2 w0.107: v4(69.58,70.96) 69.58,71.24 69.98,71.64 69.98,72.95 70.28,73.26 70.28,74.29 66.5,78.08 66.5,87.76 65.4,88.86 65.4,90.4 64.08,91.72 61.89,91.72 55.72,97.89 v1(50.85,97.89)
  BOTTOM w0.152: v1(50.85,97.89) 58.27,105.31 58.27,110.1 58.27,110.1 58.27,110.26 58.88,110.87 58.88,113.35 59.44,113.91 59.44,116.36 60.66,117.58 60.66,118.87 60.9,119.11 63.4,119.11 65.07,117.44 U53.K6
SOC_EMIFD5: length 78.1
  TOP w0.152: U23.J6 v4(68.78,70.16) ; v1(50.19,97.95) 50.1,98.04 U16.16
  L5_SIG2 w0.107: v4(68.78,70.16) 69.18,70.56 69.18,72.66 69.21,72.69 69.21,72.71 69.42,72.93 69.66,72.93 69.94,73.21 69.94,74.31 69.81,74.45 69.81,74.45 69.73,74.53 66.27,77.98 66.27,84.86 64.59,86.54 64.59,90.4 63.5,91.49 60.53,91.49 54.53,97.49 50.57,97.49 50.19,97.87 v1(50.19,97.95)
  BOTTOM w0.102: 65.6,117.62 65.73,117.5 66.01,117.5 66.29,117.22 66.29,116.48 66.11,116.3 U53.J7
  BOTTOM w0.152: 65.6,117.62 65.21,118.02 63.61,119.61 59.74,119.61 58.83,118.7 58.83,116.23 56.21,113.61 56.21,109.22 57.3,108.13 57.3,105.69 50.19,98.58 v1(50.19,97.95)
SOC_EMIFD6: length 77.1
  TOP w0.152: U16.17 50.76,98.54 50.78,98.52 v1(50.8,98.52) ; U23.H6 v4(69.58,70.16)
  L5_SIG2 w0.107: v4(69.58,70.16) 69.58,70.44 69.94,70.81 69.94,71.11 70.22,71.39 70.53,71.39 70.74,71.61 70.74,72.84 70.5,73.09 70.5,74.52 67.64,77.38 67.64,83.49 67.36,83.77 67.36,90.42 65.84,91.95 61.98,91.95 55.41,98.52 v1(50.8,98.52)
  BOTTOM w0.152: v1(50.8,98.52) 57.61,105.33 57.61,108.46 56.79,109.27 56.79,113.77 59.08,116.05 59.08,118.45 59.99,119.36 63.5,119.36 65.76,117.1 U53.K7
SOC_EMIFD7: length 77.1
  TOP w0.152: U16.18 v1(49.87,99.04) ; U23.H1 v4(69.58,74.16)
  L5_SIG2 w0.107: v4(69.58,74.16) 69.58,74.19 64.36,79.4 64.36,90.27 63.4,91.24 59.63,91.24 54.65,96.21 53.61,97.26 50.35,97.26 49.81,97.8 49.81,98.98 v1(49.87,99.04)
  BOTTOM w0.152: v1(49.87,99.04) 49.95,99.04 57,106.09 57,108.08 55.91,109.17 55.91,119.12 57.39,120.61 64.19,120.61 67.07,117.72 67.07,116.71 U53.J8
SOC_EMIFD8: length 50.7
  TOP w0.152: v1(48.69,101.45) 48.38,101.76 U14.11 ; U23.H2 v4(69.58,73.36)
  L3_SIG1 w0.102: v4(69.58,73.36) 70.32,74.1 70.32,74.71 75.72,80.11 75.72,84.32 74.35,85.69 74.35,88.08 70.48,91.95 61.64,91.95 61.45,92.14 58.55,92.14 49.24,101.45 v1(48.69,101.45)
SOC_EMIFD9: length 56.8
  TOP w0.152: v1(50.71,102.22) 50.66,102.26 U14.12 ; U23.G6 v4(70.38,70.16)
  L3_SIG1 w0.102: v4(70.38,70.16) 70.74,70.53 70.74,71.24 70.89,71.39 71.33,71.39 71.6,71.67 71.6,75.03 76.4,79.83 76.4,84.61 75.03,85.98 75.03,91.62 73.1,93.55 69.8,93.55 68.96,92.71 61.83,92.71 52.33,102.22 v1(50.71,102.22)
SOC_EMIFD10: length 45.7
  TOP w0.152: U23.K5 v4(67.98,70.96) ; U14.13 v1(49.54,102.76)
  L5_SIG2 w0.107: v1(49.54,102.76) 49.54,100.94 48.02,99.41 48.02,95.09 49.49,93.62 50.78,93.62 52.02,92.38 54.63,92.38 57.76,89.26 59.16,89.26 61.14,87.27 61.14,86.58 62.53,85.19 62.53,78.08 66.01,74.61 66.01,74.01 66.29,73.73 66.53,73.73 66.74,73.51 66.74,71.67 67.05,71.36 67.57,71.36 67.74,71.19 67.75,71.19 v4(67.98,70.96)
SOC_EMIFD11: length 53.9
  TOP w0.152: U14.14 v1(50.2,103.26) ; U23.H3 v4(69.58,72.56)
  L3_SIG1 w0.102: v1(50.2,103.26) 50.1,103.16 50.1,101.97 59.7,92.36 61.51,92.36 61.72,92.15 73.11,92.15 74.57,90.69 74.57,85.79 75.95,84.42 75.95,80.02 70.55,74.62 70.55,73.53 v4(69.58,72.56)
SOC_EMIFD12: length 47.1
  TOP w0.152: U23.J4 v4(68.78,71.76) ; U14.15 v1(49.54,103.76)
  L5_SIG2 w0.107: v4(68.78,71.76) 68.41,71.39 67.82,71.39 67.54,71.67 67.54,73.51 67.33,73.73 67.09,73.73 66.78,74.04 66.78,74.39 62.76,78.4 62.76,85.37 61.4,86.73 61.4,87.33 59.25,89.48 57.85,89.48 54.73,92.61 52.11,92.61 50.87,93.85 49.58,93.85 48.24,95.19 48.24,99.32 49.92,100.99 49.92,103.01 49.54,103.39 v1(49.54,103.76)
SOC_EMIFD13: length 56.3
  TOP w0.152: U14.16 v1(50.2,104.26) ; U23.H4 v4(69.58,71.76)
  L3_SIG1 w0.102: v4(69.58,71.76) 70.01,72.19 70.53,72.19 70.74,72.41 70.74,72.6 70.75,72.61 70.75,74.5 76.17,79.92 76.17,84.51 74.8,85.88 74.8,90.79 73.21,92.38 61.84,92.38 52.62,101.6 50.79,101.6 50.33,102.06 50.33,102.82 50.58,103.07 50.58,103.88 v1(50.2,104.26)
SOC_EMIFD14: length 52.1
  TOP w0.152: U14.17 v1(49.54,104.76) ; U23.K6 v4(67.98,70.16)
  L5_SIG2 w0.107: v4(67.98,70.16) 67.7,70.16 67.33,69.79 67,69.79 66.74,70.05 66.74,70.31 66.47,70.59 66.22,70.59 65.94,70.87 65.94,71.11 65.66,71.39 65.42,71.39 65.14,71.67 65.14,74.51 62.08,77.57 62.08,85 59.44,87.63 59.02,87.63 58.01,88.65 57.65,88.65 54.37,91.92 51.83,91.92 51.7,92.05 50.41,92.05 47.26,95.2 46.23,95.2 45.99,95.43 45.99,99.25 46.7,99.95 47.86,99.95 49.07,101.16 49.07,101.61 48.93,101.75 48.93,104.15 v1(49.54,104.76)
SOC_EMIFD15: length 52
  TOP w0.152: U14.18 v1(50.2,105.26) ; U23.J5 v4(68.78,70.96)
  L5_SIG2 w0.107: v1(50.2,105.26) 49.92,104.98 49.92,104.61 49.46,104.14 49.38,104.14 49.16,103.92 49.16,101.84 49.3,101.7 49.3,101.07 47.96,99.72 47.4,99.72 46.99,99.32 46.99,95.79 50.51,92.28 51.8,92.28 51.92,92.15 54.54,92.15 57.82,88.87 59.21,88.87 60.91,87.18 60.91,86.48 62.31,85.09 62.31,77.99 65.63,74.66 65.63,73.84 65.95,73.53 65.95,73.22 65.94,73.21 65.94,71.67 66.22,71.39 66.46,71.39 66.74,71.11 66.74,70.87 67.02,70.59 68.13,70.59 68.5,70.96 v4(68.78,70.96)
SOC_EMIFOEZ: length 82.8
  TOP w0.152: U23.Y2 v4(59.18,73.36)
  L5_SIG2 w0.107: v1(44.2,110.63) 44.2,110.28 45.39,109.09 45.39,107.45 42.93,104.98 42.93,96.52 41.96,95.55 41.96,93.85 42.66,93.15 42.66,89.76 45.45,86.97 50.21,86.97 52.66,84.52 53.08,84.52 53.95,83.65 53.95,81.5 59.58,75.87 59.58,73.76 v4(59.18,73.36)
  L8_SIG3 w0.107: v1(44.2,110.63) 46,112.42 47.59,112.42 47.8,112.21 49.68,112.21 53.61,116.14 55.64,116.14 55.98,116.48 55.98,119.38 56.66,120.06 57.89,120.06 58.75,119.2 62.28,119.2 63.07,118.41 v1(63.07,112.7)
  BOTTOM w0.152: v1(44.2,110.63) 44.21,110.62 U54.15 ; U53.D4 v1(63.07,112.7)
SOC_EMIFRNW: length 53.4
  TOP w0.152: U23.Y3 v4(59.18,72.56)
  L5_SIG2 w0.107: v4(59.18,72.56) 59.54,72.93 60.07,72.93 60.34,73.21 60.34,75.42 55.57,80.2 55.57,84.07 54.49,85.15 52.35,85.15 50.3,87.2 45.54,87.2 42.88,89.86 42.88,93.31 43.21,93.63 43.21,100.51 v1(44.42,101.73)
  L10_SIG4 w0.107: v1(44.26,109.63) 44.26,101.9 v1(44.42,101.73)
  BOTTOM w0.152: U54.13 44.3,109.62 44.3,109.63 v1(44.26,109.63) ; v1(44.42,101.73) 45.28,100.88 R388.2
SOC_EMIFRNW_R: length 10.3
  TOP w0.152: U16.1 46.18,100.76 46.33,100.91 v1(46.66,100.91) ; U14.1 46.18,106.83 46.1,106.91 v1(45.39,106.91)
  L3_SIG1 w0.107: v1(46.66,100.91) 45.39,102.18 v1(45.39,106.91)
  BOTTOM w0.152: v1(46.66,100.91) 46.61,100.91 46.18,100.48 R388.1
SOC_EMIFWAIT0: length 87.3
  TOP w0.152: v1(66.67,110.85) 67.42,111.6 67.42,113.52 68.51,114.61 R74.1 ; U23.T6 v4(63.18,70.16)
  L5_SIG2 w0.107: v1(66.67,110.85) 65.18,110.85 64.25,111.78 64.25,113.73 63.73,114.25 62.07,114.25 61.36,114.97 48.35,114.97 45.58,112.2 45.58,109.55 46.08,109.05 46.08,106.25 45.31,105.48 45.31,101.73 44.12,100.55 44.12,92.24 45.06,91.3 46.11,91.3 46.48,90.93 46.48,90.56 46.76,90.28 47.14,90.28 49.53,87.88 50.59,87.88 52.63,85.84 55.68,85.84 58.27,83.24 58.27,80.79 58.88,80.18 58.88,78.14 61.85,75.17 61.85,74.08 61.53,73.76 61.53,70.94 61.91,70.56 62.78,70.56 v4(63.18,70.16)
  BOTTOM w0.254: U53.C8 v1(66.67,110.85)
SOC_EMIFWAIT1: length 77.5
  TOP w0.152: CN7.69 v1(42.8,119.99) ; U23.N3 v4(65.58,72.56)
  L10_SIG4 w0.107: v4(65.58,72.56) 65.58,72.57 65.35,72.79 65.35,72.8 65.23,72.91 64.64,73.5 64.64,80.25 63.79,81.11 63.79,91.74 63.04,92.5 63.04,100.28 61.19,102.13 61.19,103.33 59.66,104.85 56.27,108.24 55.79,108.73 54.05,108.73 53.17,109.6 53.17,111.91 52.47,112.61 52.26,112.61 50.87,114 50.87,116.68 50.08,117.47 50.01,117.47 49.6,117.88 49.2,117.88 47.08,119.99 v1(42.8,119.99)
  BOTTOM w0.127: 66.34,74.68 65.2,73.53 65.2,73.21 65.58,72.84 v4(65.58,72.56)
  BOTTOM w0.152: R418.1 73.28,81.48 72.92,81.13 72.15,81.13 70.66,79.64 70.66,78.05 68.25,75.64 67.31,75.64 66.34,74.68
SOC_EMIFWEZ: length 106.1
  TOP w0.152: U23.R5 v4(63.98,70.96)
  L3_SIG1 w0.102: v1(44.26,111.62) 44.26,111.14 46.18,109.22 49.67,109.22 50.13,109.68 50.89,109.68 51.1,109.89 51.55,109.89 51.81,110.15 52.29,110.15 52.86,110.72 52.86,114.05 53.87,115.07 60.7,115.07 61.87,113.89 61.87,113.21 63.51,111.58 64.21,111.58 65.3,110.49 v1(65.3,110.06)
  L5_SIG2 w0.107: v4(63.98,70.96) 63.7,70.96 63.33,71.33 63.09,71.33 62.74,71.67 62.74,73.71 62.73,73.72 62.73,75.26 60.91,77.08 60.91,82.89 60.39,83.41 58.57,85.23 57.26,85.23 55.96,86.52 53.87,86.52 51.27,89.13 49.91,89.13 46.84,92.2 45.59,92.2 44.81,92.99 44.81,100.26 45.99,101.45 45.99,105.19 46.44,105.64 47.43,105.64 48.33,106.53 48.33,112.02 49.46,113.15 58.4,113.15 61.49,110.06 v1(65.3,110.06)
  BOTTOM w0.102: v1(65.3,110.06) 65.3,110.11 65.87,110.67 U53.C7
  BOTTOM w0.152: v1(44.26,111.62) U54.17
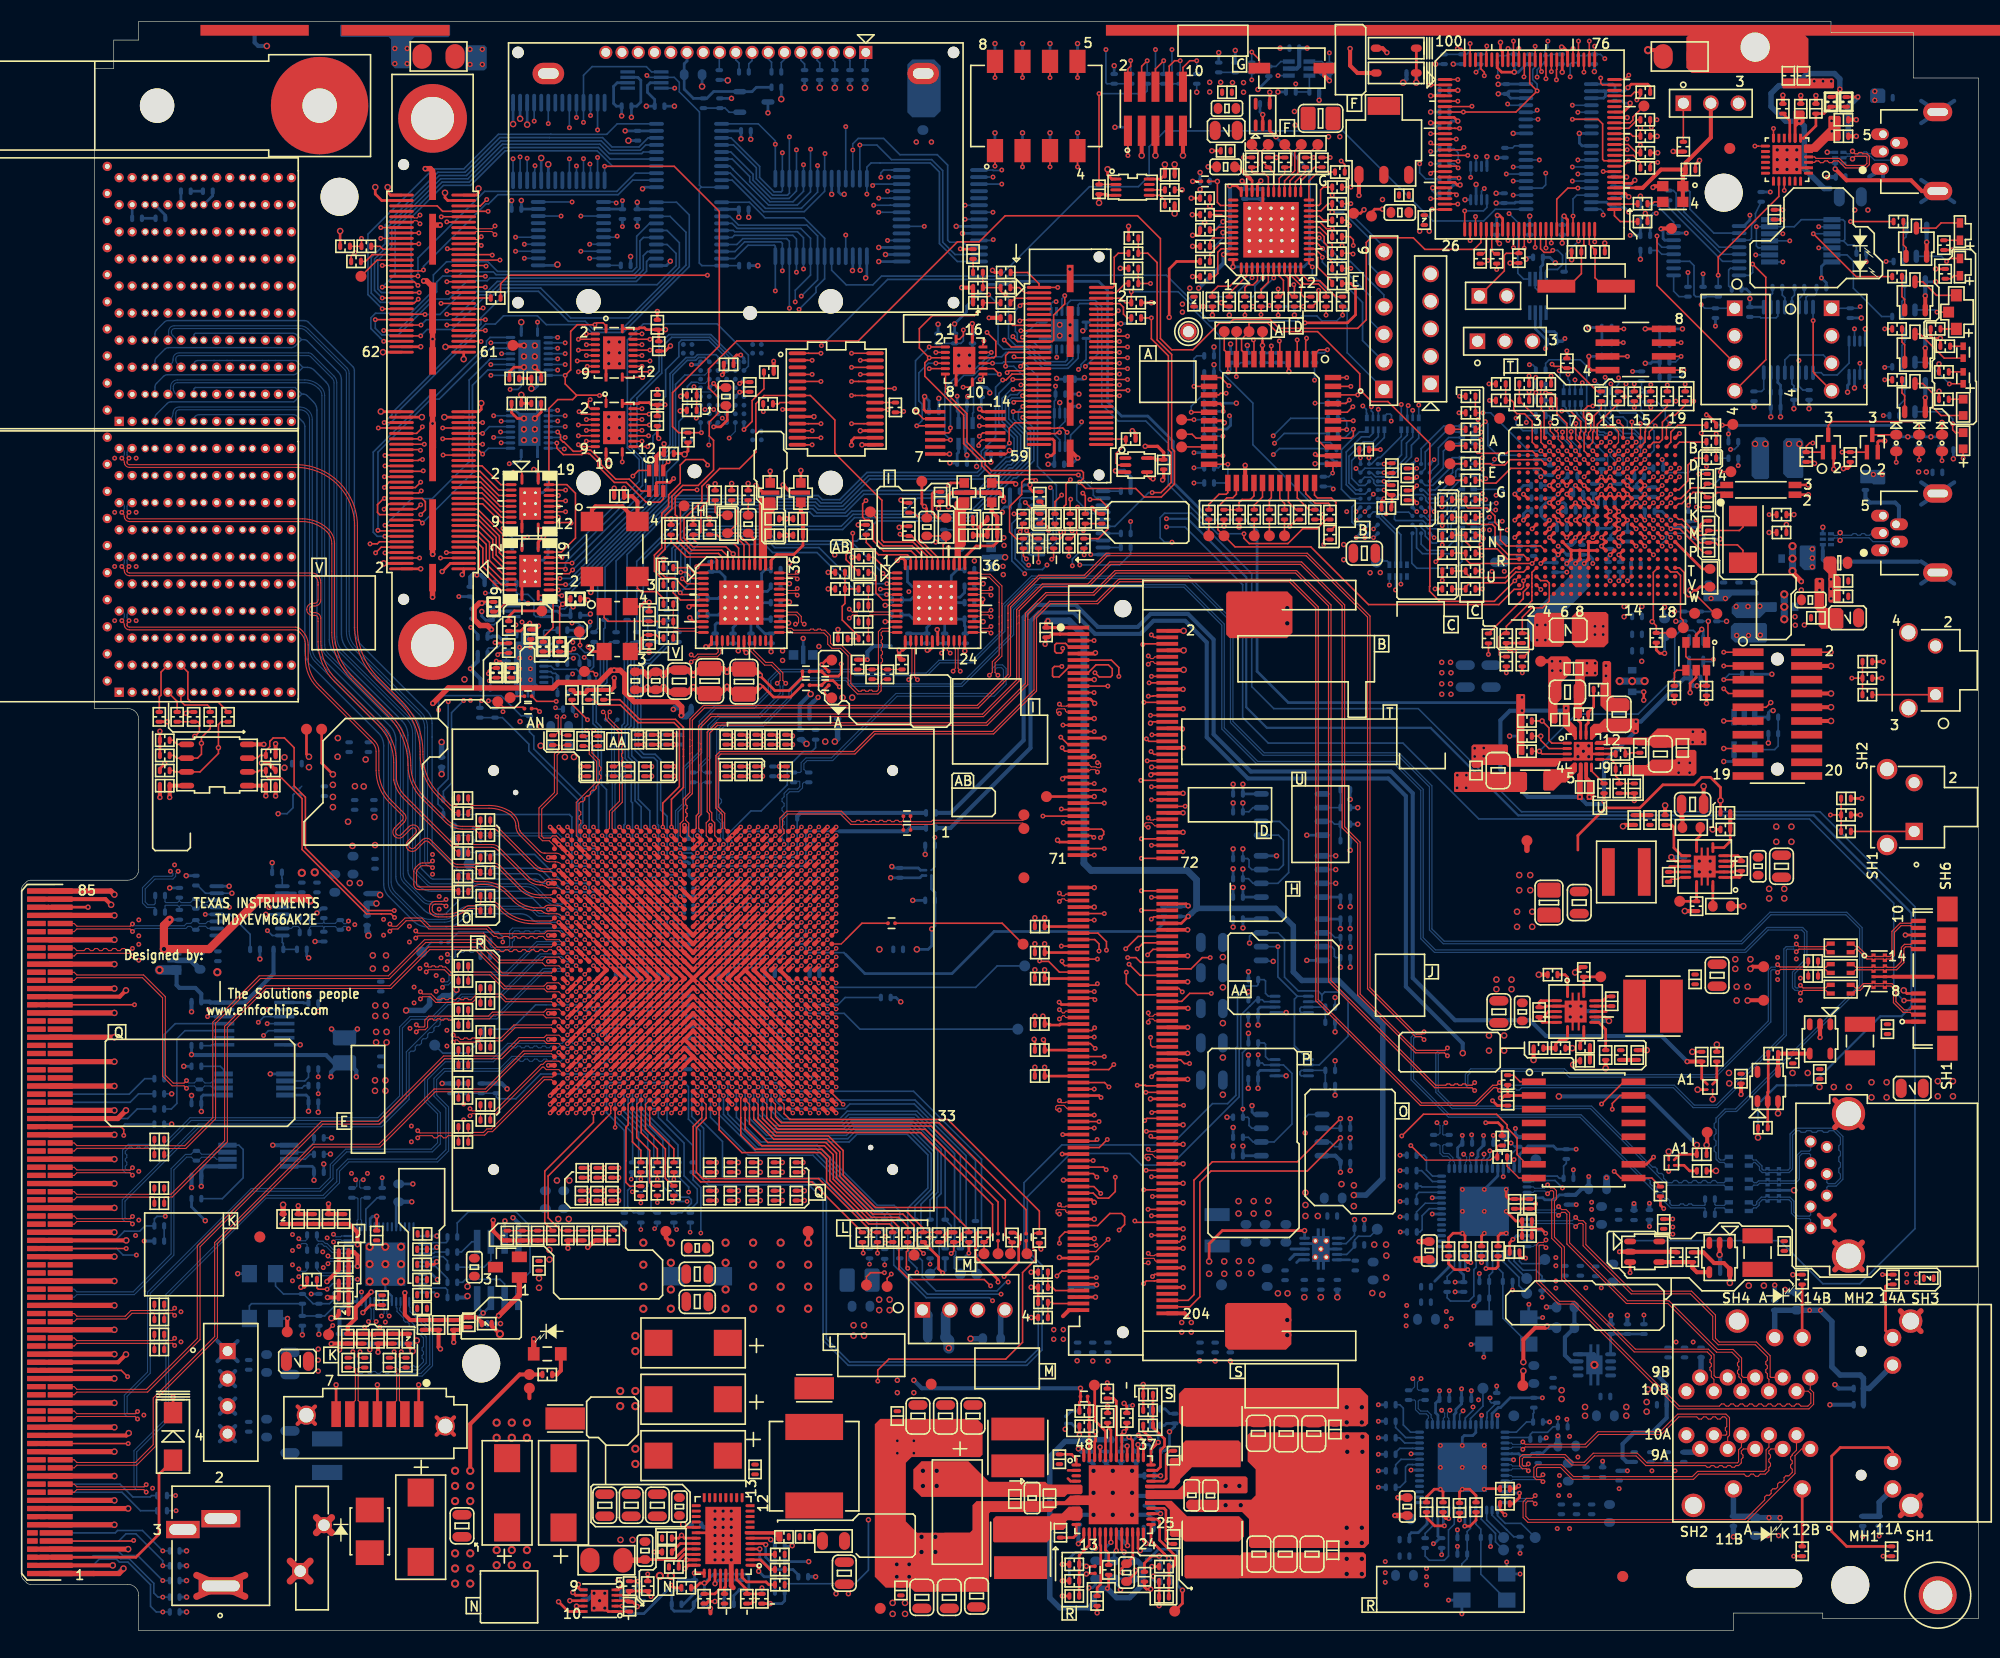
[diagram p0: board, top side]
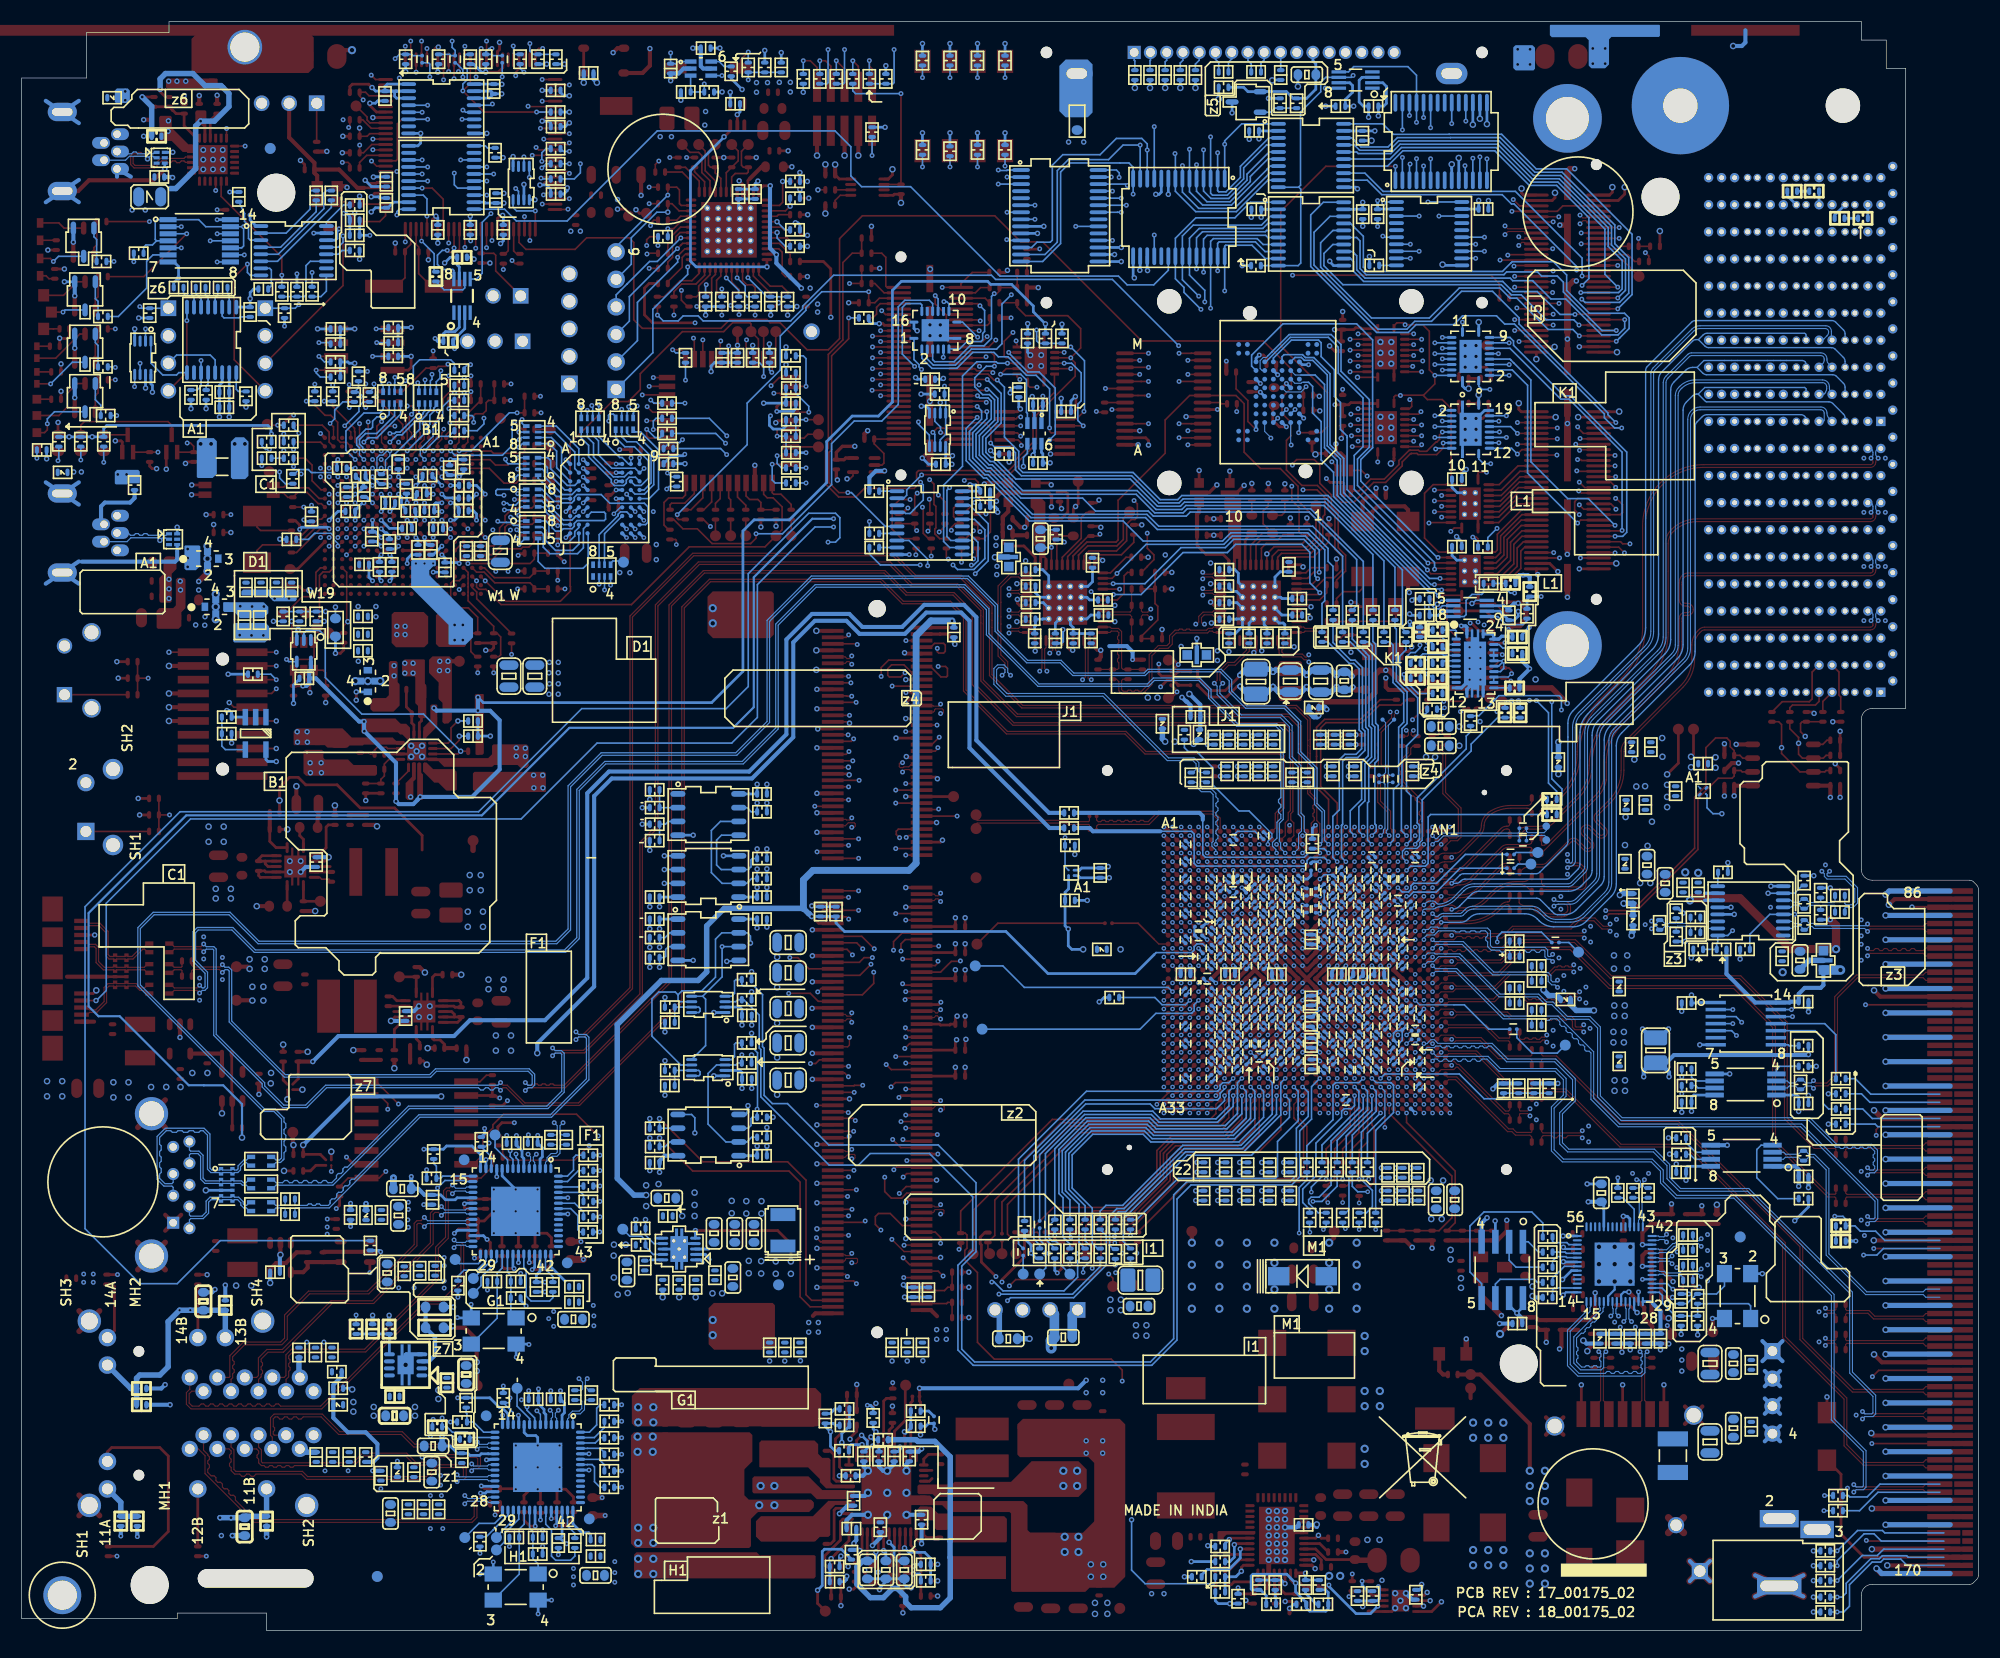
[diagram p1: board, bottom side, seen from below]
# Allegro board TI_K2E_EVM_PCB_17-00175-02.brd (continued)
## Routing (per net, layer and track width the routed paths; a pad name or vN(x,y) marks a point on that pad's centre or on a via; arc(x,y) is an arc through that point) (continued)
SOC_EMU_00: length 65.7
  TOP w0.152: R109.1 94.59,103.59 94.59,102.82 93.98,102.21 R131.1 94.43,102.17 94.79,101.8 v1(94.79,101.55) ; U23.AC5 v4(56.78,70.96)
  L8_SIG3 w0.107: v4(56.78,70.96) 56.41,71.33 55.89,71.33 55.58,71.64 55.58,74.74 57.1,76.26 59.33,76.26 61.37,78.3 61.37,82.1 64.41,85.14 76.48,85.14 77.57,86.23 86.72,86.23 87.83,87.34 87.83,88.71 90.53,91.41 91.2,92.08 91.2,93.32 94.23,96.35 94.23,100.51 94.79,101.07 v1(94.79,101.55)
SOC_EMU_00_R: length 24.6
  TOP w0.152: EMU1.19 92.46,119.47 v1(92.37,119.38) ; R131.2 93.68,103.07 v1(92.63,104.11)
  L3_SIG1 w0.107: v1(92.63,104.11) 92.56,104.19 92.56,110.22 90.81,111.97 90.81,114.34 89.87,115.29 89.87,116.38 91.07,117.59 91.07,119.67 91.22,119.81 91.85,119.81 92.28,119.38 v1(92.37,119.38)
  BOTTOM w0.152: U49.9 93.75,120.77 v1(92.37,119.38)
SOC_EMU_01: length 64.5
  TOP w0.152: U23.AA6 v4(58.38,70.16) ; R127.1 R128.2 98.17,101.7 v1(97.99,101.52)
  L8_SIG3 w0.107: v1(97.99,101.52) 99.16,100.36 99.16,98.67 93.03,92.54 93.03,91.32 91.15,89.45 91.15,88.03 87.53,84.4 78.33,84.4 77.24,83.31 65.17,83.31 63.2,81.34 63.2,77.55 60.36,74.71 60.36,73.22 60.13,72.99 59.89,72.99 59.61,72.71 59.61,70.82 59.37,70.59 58.8,70.59 v4(58.38,70.16)
SOC_EMU_01_R: length 29.5
  TOP w0.152: R128.1 98.17,104.75 v1(97.94,104.98) ; v1(91.49,119.43) 91.52,119.41 91.52,119.37 91.91,118.97 EMU1.21 95.12,118.97 95.25,119.1 95.25,121.42 96.28,122.45 v1(96.28,123.21)
  L3_SIG1 w0.107: v1(91.49,119.43) 93.75,117.17 93.75,111.4 96.42,108.74 96.42,106.06 96.86,105.62 97.3,105.62 v1(97.94,104.98)
  BOTTOM w0.152: v1(96.28,123.21) 96.28,123.18 96.02,122.91 U49.12
SOC_EMU_02: length 58.6
  TOP w0.152: v1(95.07,98.88) 95.25,99.06 R145.1 ; U23.AC4 v4(56.78,71.76)
  L8_SIG3 w0.107: v1(95.07,98.88) 95.07,96.87 91.43,93.22 91.43,91.99 88.06,88.62 88.06,87.25 86.81,86 77.67,86 76.58,84.91 64.5,84.91 61.59,82 61.59,78.21 59.42,76.03 57.33,76.03 56.38,75.08 56.38,72.16 v4(56.78,71.76)
SOC_EMU_02_R: length 24.9
  TOP w0.152: EMU1.13 92.22,120.97 v1(92.13,120.88) ; v1(96.8,106.22) 96.39,105.82 96.39,103.94 96.22,103.76 96.22,101.78 96.32,101.68 96.32,101.23 95.87,100.78 R145.2
  L3_SIG1 w0.107: v1(92.13,120.88) 93.98,119.02 93.98,111.5 95.87,109.61 96.8,108.68 v1(96.8,106.22)
SOC_EMU_03: length 64.9
  TOP w0.152: U23.AE6 v4(55.18,70.16) ; R132.2 92.35,102.06 92.35,101.62 v1(92.15,101.42)
  L8_SIG3 w0.107: v1(92.15,101.42) 93.47,100.1 93.47,96.24 90.74,93.51 90.74,92.27 87.37,88.9 87.37,87.89 86.44,86.96 76.41,86.96 75.9,87.48 75.08,87.48 74.73,87.12 74.73,86.36 73.96,85.6 64.22,85.6 61.49,82.87 60.91,82.29 60.91,78.49 59.14,76.72 56.74,76.72 53.98,73.96 53.98,70.84 54.22,70.59 54.47,70.59 54.9,70.16 v4(55.18,70.16)
SOC_EMU_03_R: length 22.9
  TOP w0.152: R132.1 v1(91.59,103.07) ; EMU1.17 v1(92.23,119.97)
  L3_SIG1 w0.107: v1(92.23,119.97) 92.16,120.04 90.91,120.04 88.85,117.99 88.85,115.66 90.36,114.15 90.36,106.21 91.59,104.98 v1(91.59,103.07)
SOC_EMU_04: length 61.1
  TOP w0.152: R146.2 v1(93.85,98.6) ; U23.AD6 v4(55.98,70.16)
  L8_SIG3 w0.107: v1(93.85,98.6) 93.85,96.29 90.97,93.41 90.97,92.18 90.43,91.64 87.6,88.81 87.6,87.44 86.83,86.67 76,86.67 76,86.66 75.51,86.66 74.22,85.37 64.31,85.37 61.58,82.64 61.14,82.19 61.14,78.4 59.23,76.49 56.83,76.49 54.78,74.43 54.78,70.84 55.02,70.59 55.54,70.59 v4(55.98,70.16)
SOC_EMU_04_R: length 24.7
  TOP w0.152: v1(92.76,101.5) 93.48,100.78 R146.1 ; EMU1.23 91.33,118.47 v1(90.69,119.11)
  L3_SIG1 w0.107: v1(92.76,101.5) 92.76,103.45 92.25,103.96 92.25,110.2 90.59,111.87 90.59,114.25 89.08,115.75 89.08,117.02 89.65,117.59 89.65,117.59 90.69,118.63 v1(90.69,119.11)
SOC_EMU_05: length 20.4
  TOP w0.152: U23.AD3 v4(55.98,72.56)
  BOTTOM w0.152: v4(55.98,72.56) 56.38,72.96 56.38,76.39 56.26,76.51 56.26,79.93 55.7,80.48 55.7,83.39 55.93,83.62 55.93,90.91 56.27,91.24 R401.1
SOC_EMU_05_R: length 61.6
  TOP w0.152: v1(90.82,116.69) 90.82,117.68 91.11,117.97 EMU1.25
  BOTTOM w0.152: v1(90.82,116.69) 91.56,116.69 92.63,115.62 92.63,114.8 91.9,114.07 91.27,114.07 90.81,113.6 90.81,111.7 92.21,110.3 92.21,108.48 91.32,107.59 91.02,107.59 88.3,104.87 77.73,104.87 76.02,103.16 73.39,103.16 73.02,103.54 61.63,103.54 56.77,98.68 R401.2
SOC_EMU_06: length 59.4
  TOP w0.152: v1(98.07,99.29) 98.12,99.29 98.12,99.29 98.07,99.34 98.07,99.85 R143.1 ; U23.AB5 v4(57.58,70.96)
  L8_SIG3 w0.107: v1(98.07,99.29) 98.12,99.29 98.07,99.24 98.07,97.9 92.8,92.63 92.8,92.05 92.8,92.05 92.8,91.42 90.92,89.55 90.92,88.12 87.43,84.63 78.43,84.63 78.43,84.63 78.24,84.63 77.15,83.54 65.07,83.54 62.97,81.43 62.97,77.64 59.85,74.53 59.82,74.53 59.54,74.25 59.54,73.21 59.3,72.96 58.98,72.96 58.74,72.72 58.74,71.61 58.5,71.36 57.98,71.36 v4(57.58,70.96)
SOC_EMU_06_R: length 25.9
  TOP w0.152: R143.2 99.38,100.78 100.25,101.65 100.25,103.68 99.54,104.39 v1(98.6,104.39) ; v1(91.59,117.56) 91.6,117.56 91.7,117.47 EMU1.27
  L3_SIG1 w0.107: v1(91.59,117.56) 92.17,117.56 93.52,116.22 93.52,111.31 96.19,108.64 96.19,105.79 97.58,104.39 v1(98.6,104.39)
SOC_EMU_07: length 60
  TOP w0.152: U23.AC3 v4(56.78,72.56) ; R130.1 95.38,101.93 v1(95.91,101.4)
  L8_SIG3 w0.107: v4(56.78,72.56) 57.18,72.96 57.18,74.79 57.96,75.58 59.61,75.58 62.05,78.02 62.05,81.81 64.69,84.45 76.77,84.45 77.86,85.55 78.81,85.55 87,85.55 88.51,87.06 88.51,88.43 91.88,91.8 91.88,93.03 95.68,96.83 95.68,99.54 95.91,99.77 v1(95.91,101.4)
SOC_EMU_07_R: length 17.3
  TOP w0.152: R130.2 95.38,104.19 v1(95.99,104.8) ; v1(92.19,116.68) 92.19,116.7 92.46,116.97 EMU1.29
  L3_SIG1 w0.107: v1(95.99,104.8) 95.61,105.18 95.61,108.58 93.42,110.77 93.02,111.17 93.02,115.86 v1(92.19,116.68)
SOC_EMU_08: length 60.4
  TOP w0.152: R129.1 96.77,101.65 v1(96.95,101.47) ; U23.AB4 v4(57.58,71.76)
  L8_SIG3 w0.107: v1(96.95,101.47) 96.95,100 97.1,99.85 97.1,99.01 96.6,98.5 96.6,96.77 92.57,92.75 92.57,91.51 90.7,89.64 90.7,88.22 87.34,84.86 78.52,84.86 78.14,84.86 77.05,83.77 64.98,83.77 62.74,81.53 62.74,77.73 59.63,74.63 59.08,74.63 58.75,74.3 58.75,73.23 58.74,73.23 58.74,73.21 58.47,72.93 58.22,72.93 57.98,72.68 57.98,72.16 v4(57.58,71.76)
SOC_EMU_08_R: length 20.8
  TOP w0.152: v1(90.96,116.1) 91.13,116.28 92.44,116.28 92.63,116.47 EMU1.31 ; v1(96.82,104.42) 96.77,104.37 R129.2
  L3_SIG1 w0.107: v1(96.82,104.42) 96.82,104.75 95.96,105.61 95.96,108.55 94.15,110.36 93.7,110.81 93.29,111.21 93.29,116.12 92.35,117.06 91.92,117.06 v1(90.96,116.1)
SOC_EMU_09: length 20.9
  TOP w0.152: U23.AH3 v4(52.78,72.56)
  BOTTOM w0.152: R403.1 52.83,90.5 53.41,89.92 53.41,87.75 51.75,86.09 51.75,82.68 52.78,81.65 52.78,77.47 52.38,77.06 52.38,72.96 v4(52.78,72.56)
SOC_EMU_09_R: length 58
  TOP w0.152: EMU1.33 91.4,115.97 90.86,115.42 v1(90.55,115.42)
  BOTTOM w0.152: R403.2 53.16,92.47 53.16,97.89 60.03,104.76 73.52,104.76 73.9,104.38 75.51,104.38 78.02,106.89 88.2,106.89 88.57,107.26 88.57,108.84 89.89,110.16 89.89,114.76 v1(90.55,115.42)
SOC_EMU_10: length 20.9
  TOP w0.152: U23.AF3 v4(54.38,72.56)
  BOTTOM w0.152: v4(54.38,72.56) 53.98,72.95 53.98,77.61 53.5,78.09 53.5,83.37 53.04,83.84 53.04,86.51 54.02,87.5 54.02,90.95 54.31,91.24 R402.1
SOC_EMU_10_R: length 58
  TOP w0.152: EMU1.35 v1(91.48,115.47)
  BOTTOM w0.152: R402.2 54.86,98.73 60.28,104.15 73.27,104.15 73.65,103.77 75.77,103.77 78.27,106.28 88.84,106.28 90.84,108.28 91.14,108.28 91.6,108.74 91.6,110.05 90.2,111.45 90.2,114.19 v1(91.48,115.47)
SOC_EMU_11: length 59.4
  TOP w0.152: v1(92.74,98.91) 92.46,99.19 R147.1 ; U23.AG4 v4(53.58,71.76)
  L8_SIG3 w0.107: v1(92.74,98.91) 92.16,98.34 92.16,95.25 90.51,93.6 90.51,92.37 87.14,89 87.14,87.98 86.35,87.19 76.5,87.19 75.99,87.71 73.25,87.71 71.37,85.83 64.74,85.83 64.12,85.83 61.39,83.1 60.68,82.38 60.68,78.64 58.99,76.95 56.64,76.95 53.19,73.49 53.19,72.15 v4(53.58,71.76)
SOC_EMU_11_R: length 20.1
  TOP w0.152: EMU1.37 v1(92.23,114.97) ; R147.2 91.8,100.78 91.19,101.39 91.19,103.74 92.3,104.86 92.3,105.97 92.61,106.27 93.47,106.27 v1(93.6,106.15)
  L3_SIG1 w0.107: v1(92.23,114.97) 92.23,114.55 91.41,113.74 91.41,113.74 91.04,113.38 91.04,112.06 93.6,109.51 v1(93.6,106.15)
SOC_EMU_12: length 21
  TOP w0.152: U23.AD2 v4(55.98,73.36)
  BOTTOM w0.152: v4(55.98,73.36) 55.58,73.76 55.58,74.3 55.58,74.31 55.58,74.32 55.7,74.44 55.7,80.06 55.4,80.36 55.4,83.52 55.63,83.75 55.63,91.04 55.88,91.29 R393.1
SOC_EMU_12_R: length 54.8
  TOP w0.152: EMU1.39 91.63,114.47 91.55,114.55 v1(91.52,114.55)
  BOTTOM w0.152: R393.2 55.88,99.31 60.41,103.84 73.15,103.84 73.52,103.47 75.89,103.47 77.64,105.21 88.21,105.21 90.89,107.9 91.19,107.9 91.9,108.61 91.9,110.17 90.5,111.58 90.5,113.73 91.32,114.55 v1(91.52,114.55)
SOC_EMU_13: length 21.9
  TOP w0.152: U23.AC2 v4(56.78,73.36)
  BOTTOM w0.152: R392.1 57.78,91.52 56.53,90.26 56.53,90.23 56.24,89.94 56.24,83.5 56.01,83.27 56.01,80.61 56.62,80 56.62,76.58 57.18,76.02 57.18,73.76 v4(56.78,73.36)
SOC_EMU_13_R: length 52.9
  TOP w0.152: v1(92.38,113.97) 92.38,113.97 EMU1.41
  BOTTOM w0.152: R392.2 57.38,94.58 57.38,98.85 61.76,103.23 72.74,103.23 73.11,102.86 76.15,102.86 76.62,103.33 81.48,103.33 82.68,104.52 88.38,104.52 91.14,107.29 91.45,107.29 92.51,108.36 92.51,110.43 91.11,111.83 91.11,113.48 91.4,113.77 92.18,113.77 v1(92.38,113.97)
SOC_EMU_14: length 57.2
  TOP w0.152: R144.1 v1(96.65,99.16) ; U23.AB3 v4(57.58,72.56)
  L8_SIG3 w0.107: v1(96.65,99.16) 96.14,98.65 96.14,96.64 95.84,96.34 92.34,92.84 92.34,91.61 89.71,88.97 89.71,87.55 87.25,85.09 78.62,85.09 78.24,85.09 78.05,85.09 76.96,84 64.88,84 62.51,81.62 62.51,77.83 59.54,74.86 58.47,74.86 57.98,74.37 57.98,73.24 57.58,72.84 v4(57.58,72.56)
SOC_EMU_14_R: length 19
  TOP w0.152: v1(91.57,113.36) 91.68,113.47 EMU1.43 ; R144.2 96.89,100.78 97.38,101.27 97.38,103.61 v1(97.46,103.68)
  L3_SIG1 w0.107: v1(91.57,113.36) 92.56,113.36 92.79,113.14 92.79,111.07 95.38,108.48 95.38,104.87 96.57,103.68 v1(97.46,103.68)
SOC_EMU_15: length 26
  TOP w0.152: U23.AA5 v4(58.38,70.96)
  BOTTOM w0.152: v4(58.38,70.96) 58.78,71.36 58.78,74.3 58.77,74.31 58.77,74.32 58.67,74.42 58.67,80.24 58.34,80.57 57.28,80.57 56.62,81.23 56.62,83.01 56.85,83.24 56.85,88.88 57.53,89.56 57.93,89.56 59.56,91.19 R391.1
SOC_EMU_15_R: length 49.4
  TOP w0.152: EMU1.45 92.41,112.97 v1(92.41,112.98)
  BOTTOM w0.152: R391.2 59.56,98.22 60.02,98.68 60.02,99.87 61.77,101.62 75.77,101.62 76.87,102.72 87.43,102.72 91.4,106.68 91.7,106.68 93.12,108.1 93.12,110.68 92,111.8 92,112.57 v1(92.41,112.98)
SOC_EMU_16: length 20.7
  TOP w0.152: U23.AB2 v4(57.58,73.36)
  BOTTOM w0.152: v4(57.58,73.36) 57.98,73.76 57.98,75.65 56.92,76.71 56.92,80.13 56.31,80.74 56.31,83.14 56.54,83.37 56.54,89.82 57.97,91.24 R400.1
SOC_EMU_16_R: length 52.1
  TOP w0.152: EMU1.47 91.55,112.47 v1(91.52,112.51)
  BOTTOM w0.152: v1(91.52,112.51) 91.52,111.85 92.82,110.55 92.82,108.23 91.57,106.98 91.27,106.98 87.31,103.02 76.74,103.02 75.65,101.93 61.44,101.93 58.67,99.16 R400.2
SOC_EMU_17: length 24.8
  TOP w0.152: U23.Y5 v4(59.18,70.96)
  BOTTOM w0.152: R399.1 60.04,91.24 58.06,89.26 57.66,89.26 57.15,88.75 57.15,83.12 56.92,82.89 56.92,82.81 56.92,82.8 56.92,81.38 57.43,80.87 58.47,80.87 58.98,80.37 58.98,75.74 59.58,75.14 59.58,71.36 v4(59.18,70.96)
SOC_EMU_17_R: length 50.8
  TOP w0.152: v1(92.41,111.97) EMU1.49
  BOTTOM w0.152: R399.2 60.58,94.79 60.32,95.05 60.32,99.75 61.9,101.32 69,101.32 69.76,100.56 77.09,100.56 78.94,102.41 87.59,102.41 91.55,106.38 91.83,106.38 93.43,107.98 93.43,110.95 v1(92.41,111.97)
SOC_EMU_18: length 21.4
  TOP w0.152: U23.AH2 v4(52.78,73.36)
  BOTTOM w0.152: v4(52.78,73.36) 53.25,73.83 53.25,77.92 53.2,77.97 53.2,83.24 52.73,83.71 52.73,86.64 53.72,87.62 53.72,92.43 53.85,92.56 R394.1
SOC_EMU_18_R: length 51.6
  TOP w0.152: EMU1.51 91.67,111.47 91.14,110.94 91.14,109.63 v1(91.17,109.6)
  BOTTOM w0.152: v1(91.17,109.6) 90.82,109.25 89.41,109.25 88.87,108.72 88.87,107.14 88.32,106.58 78.15,106.58 75.64,104.08 73.77,104.08 73.4,104.45 60.16,104.45 53.85,98.14 R394.2
SOC_EMU_19: length 9.2
  TOP w0.127: 57.58,47.32 57.58,48.56 U23.AB32
  TOP w0.152: R227.1 59.54,41.6 59.41,41.73 59.41,44.45 57.58,46.28 57.58,47.32
SOC_EMU_19_R: length 124.7
  TOP w0.152: v1(96.49,110.59) 96.09,110.99 95.61,110.99 95.59,110.97 EMU1.53 ; v4(60.05,39.49) 60.2,39.64 R227.2
  L5_SIG2 w0.107: v4(60.05,39.49) 59.04,38.48 55.25,38.48 54.36,39.38 54.36,43.07 55.03,43.75 72.41,43.75 72.75,43.41 72.75,43.41 76.25,39.9 81.86,39.9 90.86,48.9 90.86,88.6 90.99,88.73 95.3,93.04 95.3,94.52 99.92,99.14 99.92,105.13 100.58,105.79 100.58,106.69 100.45,106.83 100.45,106.87 96.73,110.59 v1(96.49,110.59)
  BOTTOM w0.152: v1(96.49,110.59) 96.31,110.41 U55.6
SOC_EMU_20: length 5.9
  TOP w0.127: 57.98,47.32 U23.AB33
  TOP w0.152: R224.1 60.2,44.45 57.98,46.67 57.98,47.32
SOC_EMU_20_R: length 129.3
  TOP w0.152: R224.2 v4(60.2,41.65) ; EMU1.55 95.45,110.47 95.55,110.58 v1(95.79,110.58)
  L5_SIG2 w0.107: v4(60.2,41.65) 60.41,41.43 60.41,38.98 59.54,38.1 54.46,38.1 53.19,39.38 53.19,43.1 54.06,43.98 72.5,43.98 74.51,41.96 74.51,41.96 76.34,40.13 81.76,40.13 90.63,49 90.63,90.18 99.69,99.25 99.69,104.55 98.37,105.87 98.37,108.13 95.93,110.58 v1(95.79,110.58)
  BOTTOM w0.152: U55.3 96.31,111.61 95.79,111.08 v1(95.79,110.58)
SOC_EMU_21: length 14
  TOP w0.152: U23.AB31 v4(57.58,49.36)
  BOTTOM w0.152: v4(57.58,49.36) 57.58,48.44 57.87,48.15 58.54,48.15 58.77,47.92 58.77,47.35 61.14,44.98 61.14,41.96 62.36,40.74 62.36,39.5 61.72,38.86 R516.2
SOC_EMU_21_R: length 122.5
  TOP w0.152: EMU1.18 v1(101.32,119.97)
  L5_SIG2 w0.107: v1(101.32,119.97) 102.89,119.97 107.49,115.37 107.49,97.57 97.89,87.97 97.89,49.28 96.04,47.42 93.58,47.42 83.09,36.93 63.75,36.93 63.07,36.25 62.2,36.25 v4(61.7,36.75)
  BOTTOM w0.152: R516.1 61.72,36.78 v4(61.7,36.75)
SOC_EMU_22: length 11.7
  TOP w0.152: U23.AC29 v4(56.78,50.96)
  BOTTOM w0.152: R502.1 61.98,44.73 59.56,47.14 59.56,50.33 59.34,50.55 59.32,50.55 59.32,50.56 57.18,50.56 v4(56.78,50.96)
SOC_EMU_22_R: length 127.7
  TOP w0.152: EMU1.20 v1(102.07,119.47)
  L5_SIG2 w0.107: v1(102.07,119.47) 103.06,119.47 107.26,115.27 107.26,97.66 94.87,85.27 94.87,72.64 97.66,69.85 97.66,49.37 95.94,47.65 93.49,47.65 82.99,37.16 63.17,37.16 v4(62.69,36.68)
  BOTTOM w0.152: R502.2 61.98,41.58 62.69,40.87 v4(62.69,36.68)
SOC_EMU_23: length 5.6
  TOP w0.127: 57.18,47.32 U23.AC33
  TOP w0.152: 57.18,47.32 57.18,45.95 58.67,44.45 R225.2
SOC_EMU_23_R: length 132.2
  TOP w0.152: EMU1.22 v1(101.32,118.97) ; R225.1 v4(58.67,41.65)
  L5_SIG2 w0.107: v4(58.67,41.65) 59.17,41.15 59.17,39.04 58.84,38.71 55.35,38.71 54.58,39.47 54.58,42.98 55.13,43.52 61.83,43.52 63.71,41.64 73.81,41.64 74,41.64 74,41.64 74.19,41.64 76.15,39.67 81.95,39.67 91.08,48.81 91.08,88.5 95.53,92.95 95.53,94.43 102.74,101.63 102.74,107.81 100.26,110.29 100.26,117.9 v1(101.32,118.97)
SOC_EMU_24: length 15.3
  TOP w0.152: U23.AD29 v4(55.98,50.96)
  BOTTOM w0.152: v4(55.98,50.96) 55.58,50.57 54.24,50.57 54.23,50.55 54.21,50.55 53.98,50.32 53.98,50.31 53.98,50.3 53.98,47.8 55.63,46.15 R520.2
SOC_EMU_24_R: length 125.2
  TOP w0.152: EMU1.24 v1(102.07,118.47)
  L5_SIG2 w0.107: v4(55.63,37) 56.04,36.59 59.3,36.59 60.33,37.62 82.8,37.62 93.14,47.95 93.14,48.87 94.93,50.65 94.93,71.04 93.62,72.34 93.62,84.71 98.13,89.22 98.13,93.08 106.81,101.75 106.81,114.64 102.97,118.47 v1(102.07,118.47)
  BOTTOM w0.152: R520.1 v4(55.63,37)
SOC_EMU_25: length 15
  TOP w0.152: U23.AC31 v4(56.78,49.36)
  BOTTOM w0.152: v4(56.78,49.36) 56.78,48.15 59.74,45.19 59.74,41.1 60.85,39.99 61.58,39.99 61.81,39.76 61.81,39.44 61.79,39.41 61.79,39.41 60.93,38.55 R517.1
SOC_EMU_25_R: length 123.6
  TOP w0.152: EMU1.26 v1(101.32,117.97)
  L5_SIG2 w0.107: v1(101.32,117.97) 101.32,118.42 101.76,118.85 102.92,118.85 107.04,114.73 107.04,97.76 100.03,90.75 98.9,90.75 98.6,90.46 98.6,89.32 98.16,88.88 98.12,88.88 93.85,84.61 93.85,72.96 96.85,69.97 96.85,52.25 93.37,48.77 93.37,47.86 82.9,37.39 60.84,37.39 v4(60.45,37)
  BOTTOM w0.152: R517.2 60.2,37.26 v4(60.45,37)
SOC_EMU_26: length 9.1
  TOP w0.127: 56.78,47.32 56.78,47.99 56.78,48.56 U23.AC32
  TOP w0.152: 56.78,47.32 56.78,45.48 57.97,44.29 57.97,41.35 58.28,41.04 R228.1
SOC_EMU_26_R: length 126.2
  TOP w0.152: EMU1.28 v1(102.07,117.47) ; R228.2 v4(58.67,39.49)
  L5_SIG2 w0.107: v1(102.07,117.47) 101.28,117.47 100.48,116.67 100.48,110.39 102.96,107.91 102.96,101.54 95.76,94.33 95.76,91.57 92.1,87.92 91.45,87.26 91.31,87.13 91.31,48.71 82.05,39.45 76.06,39.45 74.1,41.41 73.91,41.41 63.61,41.41 61.77,43.25 61.21,43.25 61.2,43.25 56.59,43.25 55.6,42.27 55.6,40.11 56.68,39.03 58.21,39.03 v4(58.67,39.49)
SOC_EMU_27: length 9.1
  TOP w0.152: U23.AB30 v4(57.58,50.16)
  BOTTOM w0.152: R503.1 60.58,44.81 57.18,48.21 57.18,49.76 v4(57.58,50.16)
SOC_EMU_27_R: length 119.3
  TOP w0.152: EMU1.30 v1(101.32,116.97)
  L5_SIG2 w0.107: v4(61.56,40.46) 62.46,39.56 62.46,39 63.61,37.85 82.71,37.85 92.91,48.05 92.91,84.32 97.86,89.27 97.86,93.13 106.58,101.84 106.58,114.54 104.15,116.97 v1(101.32,116.97)
  BOTTOM w0.152: R503.2 60.58,41.91 61.56,40.92 v4(61.56,40.46)
SOC_EMU_28: length 8.9
  TOP w0.152: U23.AC30 v4(56.78,50.16)
  BOTTOM w0.152: v4(56.78,50.16) 56.38,49.76 56.38,48.04 59.18,45.24 R504.1
SOC_EMU_28_R: length 122.5
  TOP w0.152: EMU1.32 v1(102.07,116.47)
  L5_SIG2 w0.107: v4(61.42,39.6) 61.21,39.81 61.21,39.81 61.13,39.89 61.13,40.76 61.32,40.95 61.87,40.95 62.69,40.13 62.69,39.09 63.7,38.07 82.62,38.07 92.68,48.14 92.68,84.41 97.63,89.36 97.63,94.27 104.39,101.03 104.39,101.96 106.35,103.92 106.35,114.45 104.33,116.47 v1(102.07,116.47)
  BOTTOM w0.152: R504.2 59.18,41 60.58,39.6 v4(61.42,39.6)
SOC_EMU_29: length 9.4
  TOP w0.127: U23.AD32 55.98,48.56 55.98,47.32
  TOP w0.152: 55.98,47.32 55.98,46.66 55.78,46.46 55.78,43.36 55.77,43.35 55.77,41.36 56.13,41 R229.1
SOC_EMU_29_R: length 120.8
  TOP w0.152: EMU1.34 v1(101.32,115.97) ; R229.2 v4(57.15,39.45)
  L5_SIG2 w0.107: v1(101.32,115.97) 100.94,115.59 100.94,110.58 103.42,108.1 103.42,101.35 96.22,94.14 96.22,91.38 91.77,86.94 91.77,48.52 82.24,38.99 64.08,38.99 63.6,39.47 63.6,40.78 61.58,42.79 58.88,42.79 57.13,41.05 56.31,41.05 55.94,40.68 55.94,40.09 56.58,39.45 v4(57.15,39.45)
SOC_EMU_30: length 5.3
  TOP w0.127: 56.38,47.32 U23.AD33
  TOP w0.152: 56.38,47.32 56.38,45.1 57.15,44.32 R226.1
SOC_EMU_30_R: length 118.7
  TOP w0.152: EMU1.36 v1(102.07,115.47) ; R226.2 v4(57.15,41.65)
  L5_SIG2 w0.107: v4(57.15,41.65) 58.52,43.02 61.3,43.02 61.68,43.02 63.52,41.18 74,41.18 75.96,39.22 82.14,39.22 91.54,48.62 91.54,87.03 91.68,87.17 95.99,91.48 95.99,94.24 103.19,101.44 103.19,108 100.71,110.48 100.71,115.9 101.16,116.35 101.48,116.35 101.7,116.13 101.7,115.84 v1(102.07,115.47)
SOC_EMU_31: length 12.9
  TOP w0.152: U23.AD31 v4(55.98,49.36)
  BOTTOM w0.152: R518.1 58.38,38.55 58.09,38.84 58.09,41.78 58.34,42.04 58.34,45.64 55.98,48.01 v4(55.98,49.36)
SOC_EMU_31_R: length 120.8
  TOP w0.152: EMU1.38 v1(101.32,114.97)
  L5_SIG2 w0.107: v4(58.42,37.08) 59.2,37.08 60.87,38.75 60.87,40.83 61.23,41.19 61.95,41.19 62.92,40.23 62.92,39.19 63.8,38.3 82.52,38.3 92.46,48.24 92.46,84.51 92.59,84.64 97.22,89.27 97.22,94.17 104.17,101.12 104.17,102.06 106.12,104.01 106.12,112.14 103.29,114.97 v1(101.32,114.97)
  BOTTOM w0.152: R518.2 58.67,37.34 v4(58.42,37.08)
SOC_EMU_32: length 11.8
  TOP w0.152: U23.AE33 v4(55.18,47.76)
  BOTTOM w0.152: R519.1 56.47,38.55 55.93,39.09 55.93,40.61 56.76,41.44 56.76,41.82 56.95,42.01 56.95,45.99 v4(55.18,47.76)
SOC_EMU_32_R: length 120.9
  TOP w0.152: EMU1.40 v1(102.11,114.47)
  L5_SIG2 w0.107: v1(102.11,114.47) 102.72,114.47 105.89,111.3 105.89,104.11 103.88,102.09 103.88,101.16 96.99,94.27 96.99,89.36 92.5,84.87 92.49,84.87 92.23,84.6 92.23,48.33 82.43,38.53 63.89,38.53 63.14,39.28 63.14,40.32 62.05,41.42 61.01,41.42 60.64,41.05 60.64,38.84 59.67,37.87 58.02,37.87 v4(57.15,37)
  BOTTOM w0.152: R519.2 v4(57.15,37)
SOC_EMU_33: length 8.6
  TOP w0.152: U23.AD30 v4(55.98,50.16)
  BOTTOM w0.152: v4(55.98,50.16) 55.58,49.76 55.58,47.92 57.78,45.71 R505.1
SOC_EMU_33_R: length 118.8
  TOP w0.152: EMU1.42 v1(101.32,113.97)
  L5_SIG2 w0.107: v1(101.32,113.97) 101.32,110.82 103.65,108.49 103.65,101.25 96.74,94.34 96.74,90.47 92,85.72 92,48.43 82.33,38.76 63.99,38.76 63.37,39.38 63.37,40.68 61.49,42.56 59,42.56 56.92,40.49 v4(56.36,40.49)
  BOTTOM w0.152: R505.2 57.78,41 57.28,40.49 v4(56.36,40.49)
SOC_GPIO_00: length 119
  TOP w0.152: U23.V30 v4(60.78,50.16)
  L5_SIG2 w0.107: v4(60.78,50.16) 60.78,50.39 61.19,50.8 61.19,53.49 62.25,54.56 79.37,54.56 85.37,60.56 85.37,80.33 76.94,88.75 76.94,89.4 72.26,94.07 72.26,102.41 69.55,105.13 69.55,106.75 69.6,106.8 69.6,115.82 68.93,116.49 68.93,119.12 v1(71.75,121.95)
  BOTTOM w0.152: v1(71.75,121.95) 73.32,123.51 73.32,123.97 74.11,124.76 U44.21 74.11,128.5 72.22,130.39 68.62,130.39 67.18,131.83 U46.1
SOC_GPIO_01: length 125.1
  TOP w0.152: U23.AA29 v4(58.38,50.96)
  L5_SIG2 w0.107: v1(71.96,123.16) 71.12,123.16 68.32,120.37 68.32,116.13 68.83,115.61 68.83,109.62 66.55,107.33 66.55,104.7 69.77,101.48 69.77,92.48 71.8,90.45 71.84,90.45 72.33,89.95 74.08,89.95 75.78,88.25 76.47,88.25 84.68,80.04 84.68,60.84 80.76,56.93 58.22,56.93 58.01,56.71 58.01,51.33 v4(58.38,50.96)
  BOTTOM w0.152: U46.3 65.35,130.53 66.17,129.72 72.47,129.72 73.46,128.72 U44.22 73.46,124.67 v1(71.96,123.16)
SOC_GPIO_02: length 120.6
  TOP w0.152: U23.Y29 v4(59.18,50.96)
  L5_SIG2 w0.107: v1(71.4,122.63) 70.91,122.63 68.52,120.25 68.52,116.25 69.06,115.71 69.06,109.52 68.35,108.81 68.35,104.35 68.73,103.97 69.14,103.56 70,102.7 70,92.83 71.95,90.87 72.65,90.18 75.35,90.18 76.45,89.08 76.45,88.6 84.91,80.14 84.91,60.75 80.32,56.16 59.86,56.16 59.61,55.91 59.61,51.67 59.18,51.24 v4(59.18,50.96)
  BOTTOM w0.152: v1(71.4,122.63) 71.4,123.7 72.81,125.11 U44.23 72.81,128.51 71.91,129.41 66.04,129.41 65.57,129.88 U46.4
SOC_GPIO_03: length 119.1
  TOP w0.152: U23.V33 60.78,47.76 v4(60.77,47.76)
  L5_SIG2 w0.107: v1(72.16,125.67) 74.71,125.67 76.78,123.6 76.78,121.02 74.65,118.89 74.65,108.72 73.1,107.17 73.1,103.87 77.28,99.69 77.28,92.01 79.93,89.35 79.93,88.02 79.98,87.97 86.97,80.99 86.97,59.9 76.07,49 75.09,49 74.81,48.71 74.81,48.47 74.48,48.14 61.15,48.14 v4(60.77,47.76)
  BOTTOM w0.152: U46.5 65.69,129.23 65.81,129.11 71.61,129.11 72.16,128.55 U44.24 v1(72.16,125.67)
SOC_GPIO_04: length 118
  TOP w0.152: U23.V32 v4(60.78,48.56)
  L5_SIG2 w0.107: v1(71.51,125.37) 71.72,125.17 74.8,125.17 76.56,123.42 76.56,121.11 74.42,118.98 74.42,108.81 72.87,107.26 72.87,103.77 75.74,100.9 75.74,98.95 77.04,97.65 77.04,91.92 79.71,89.26 79.71,87.93 86.74,80.89 86.74,59.99 76.25,49.5 75.23,49.5 74.69,48.96 U23.V32 v4(60.78,48.56)
  BOTTOM w0.152: v1(71.51,125.37) U44.25 71.51,128.44 71.17,128.78 65.78,128.78 65.58,128.58 64.61,128.58 U46.6
SOC_GPIO_05: length 115.1
  TOP w0.152: U23.W30 v4(59.98,50.16)
  L5_SIG2 w0.107: v4(59.98,50.16) 59.98,50.44 60.34,50.81 60.34,55.05 60.62,55.33 79.81,55.33 85.14,60.65 85.14,80.23 76.71,88.66 76.71,89.3 72.03,93.98 72.03,102.26 68.58,105.71 68.58,108.51 69.29,109.22 69.29,115.8 68.73,116.37 68.73,119.91 v1(70.86,122.05)
  BOTTOM w0.152: U46.7 66.01,127.93 66.56,128.47 70.61,128.47 70.86,128.22 U44.26 v1(70.86,122.05)
SOC_GPIO_06: length 120.5
  TOP w0.152: U23.W32 v4(59.98,48.56)
  L5_SIG2 w0.107: v4(59.98,48.56) 60.41,48.13 60.41,47.61 60.62,47.39 75.33,47.39 87.2,59.26 87.2,81.08 80.16,88.11 80.16,89.45 77.51,92.1 77.51,92.42 77.51,101.04 76.68,101.87 76.68,107.29 74.88,109.09 74.88,118.79 77.01,120.92 77.01,123.77 74.74,126.05 70.76,126.05 v1(70.21,125.5)
  BOTTOM w0.152: v1(70.21,125.5) U44.27 70.21,128.04 70.08,128.17 66.73,128.17 65.84,127.28 U46.8
SOC_GPIO_07: length 114.7
  TOP w0.152: U23.V31 v4(60.78,49.36)
  L5_SIG2 w0.107: v4(60.78,49.36) 62.01,50.59 62.01,53.51 62.25,53.76 78.89,53.76 85.59,60.46 85.59,80.42 77.17,88.85 77.17,89.49 72.49,94.17 72.49,102.51 70.76,104.24 69.77,105.23 69.77,106.52 70.72,107.47 70.72,117.01 72.34,118.63 72.34,123.32 72.01,123.65 v1(69.56,123.65)
  BOTTOM w0.152: U46.9 65.81,126.63 67.05,127.86 69.47,127.86 69.56,127.77 U44.28 v1(69.56,123.65)
SOC_GPIO_08: length 135.3
  TOP w0.152: U23.W31 v4(59.98,49.36)
  L5_SIG2 w0.107: v1(69.56,137.19) 70.13,137.19 71.64,135.67 73.54,135.67 74.25,134.96 74.25,131.54 78.46,127.33 78.46,126.28 78.96,125.79 79.09,125.65 79.09,115.27 78.49,114.66 78.49,94.94 78.89,94.53 78.92,94.53 81.43,92.03 81.43,89.91 88.11,83.23 88.11,58.72 75.89,46.5 59.68,46.5 58.74,47.44 58.74,48.65 59.04,48.95 59.56,48.95 v4(59.98,49.36)
  BOTTOM w0.152: U40.1 67.99,139.07 69.56,137.5 v1(69.56,137.19) U44.1
SOC_GPIO_09: length 132.2
  TOP w0.152: U23.W33 v4(59.98,47.76)
  L5_SIG2 w0.107: v4(59.98,47.76) 60.2,47.53 60.2,47.53 60.54,47.19 73.21,47.19 75.61,47.19 87.43,59.01 87.43,81.17 81.19,87.42 80.39,88.21 80.39,89.54 77.74,92.19 77.74,92.48 77.74,92.48 77.74,92.9 77.74,102.88 77.01,103.61 77.01,107.37 75.11,109.27 75.11,118.7 78.41,122 78.41,125.26 70.21,133.45 v1(70.21,136.4)
  BOTTOM w0.152: U40.3 65.48,137.77 68.11,135.14 68.11,134.12 69.44,132.79 70.1,132.79 70.21,132.9 U44.2 v1(70.21,136.4)
SOC_GPIO_10: length 148.7
  TOP w0.152: U23.AB29 v4(57.58,50.96)
  L5_SIG2 w0.107: v4(57.58,50.96) 57.16,50.55 56.64,50.55 56.38,50.28 56.38,48.1 59.12,45.36 76.37,45.36 89.26,58.25 89.26,83.7 82.55,90.41 82.55,92.38 81.51,93.43 81.51,97.52 80.26,98.76 80.26,104.48 81.79,106.01 81.79,129.08 80.72,130.15 79.33,130.15 77.62,131.85 77.62,134.03 73.79,137.86 v1(70.86,137.86)
  BOTTOM w0.152: U40.4 65.7,137.12 67.81,135.01 67.81,133.99 69.32,132.49 70.69,132.49 70.86,132.66 U44.3 v1(70.86,137.86)
SOC_GPIO_11: length 221.8
  TOP w0.152: U23.Y30 v4(59.18,50.16)
  L3_SIG1 w0.102: v1(137.29,130.78) 136.82,131.25 135.88,131.25 135.72,131.41 132.84,131.41 132.71,131.28 130.63,131.28 130.33,131.57 129.63,131.57 127.37,133.83 115.87,133.83 115.85,133.81 115.85,133.81 114.78,132.75 111.94,132.75 111.53,132.33 109.31,132.33 108.68,131.7 107.74,131.7 106.42,133.02 91.27,133.02 90.84,132.59 84.35,132.59 80.94,136 75.76,136 74.43,137.34 72.18,137.34 v1(71.51,136.67)
  L5_SIG2 w0.107: v4(59.18,50.16) 58.81,49.79 58.29,49.79 58.01,49.51 58.01,49.27 57.8,49.07 57.8,47.35 59.33,45.82 76.18,45.82 88.8,58.44 88.8,83.51 82.09,90.22 82.09,92.23 81.08,93.24 81.08,97.38 79.71,98.75 79.71,104.57 80.72,105.59 80.72,113.07 81.27,113.62 81.27,128.95 80.53,129.69 79.14,129.69 77.01,131.82 77.01,134 74.31,136.7 73.33,136.7 72.97,136.35 71.83,136.35 v1(71.51,136.67)
  BOTTOM w0.152: U79.5 138.63,124.74 138.1,125.27 138.1,129.97 v1(137.29,130.78) ; v1(71.51,136.67) U44.4 71.51,132.87 70.83,132.18 69.19,132.18 67.5,133.87 67.5,134.42 65.46,136.47 U40.5
SOC_GPIO_12: length 235.4
  TOP w0.152: U23.Y32 v4(59.18,48.56)
  L3_SIG1 w0.102: v1(165.87,129.57) 166.25,129.19 166.25,127.46 166.02,127.24 160.67,127.24 159.64,128.27 149.95,128.27 148.77,129.45 131.18,129.45 130.5,130.12 124.05,130.12 123.16,131.01 121.89,131.01 121.27,131.63 118.08,131.63 118.06,131.65 117.79,131.93 112.99,131.93 111.51,130.44 108.85,130.44 108.36,129.95 106.15,129.95 105.57,130.53 88.42,130.53 88,130.95 84.7,130.95 80.58,135.07 74.18,135.07 73.66,135.59 72.46,135.59 v1(72.16,135.29)
  L5_SIG2 w0.107: v4(59.18,48.56) 59.54,48.19 59.54,47.41 59.99,46.96 75.7,46.96 87.66,58.91 87.66,81.27 87.52,81.4 81.64,87.28 80.62,88.3 80.62,89.63 77.97,92.29 77.97,92.51 77.97,102.98 77.83,103.11 77.24,103.7 77.24,107.71 75.86,109.09 75.86,119.12 78.64,121.9 78.64,125.35 72.16,131.83 v1(72.16,135.29)
  BOTTOM w0.152: U48.2 v1(165.87,129.57) ; U40.6 65.58,135.82 67.2,134.2 67.2,133.74 69.06,131.88 71.2,131.88 72.16,132.84 U44.5 v1(72.16,135.29)
SOC_GPIO_13: length 245.4
  TOP w0.152: U23.AA30 v4(58.38,50.16)
  L3_SIG1 w0.102: v1(165.87,127.62) 160.84,127.62 159.96,128.5 152.98,128.5 151.63,129.85 150.93,129.85 150.72,129.65 131.29,129.65 130.59,130.35 125.53,130.35 124.23,131.65 123.27,131.65 122.94,131.32 121.95,131.32 121.41,131.86 118.15,131.86 117.87,132.13 112.77,132.13 111.38,130.74 108.83,130.74 108.26,130.18 106.24,130.18 104.08,132.33 91.55,132.33 91.13,131.91 87.96,131.91 87.23,131.18 84.8,131.18 80.68,135.3 74.28,135.3 72.84,136.73 v1(72.81,136.73)
  L5_SIG2 w0.107: v1(72.81,136.73) 73.02,136.93 74.4,136.93 77.23,134.1 77.23,131.92 79.23,129.92 80.63,129.92 81.5,129.05 81.5,113.53 81.03,113.06 81.03,105.57 80.04,104.58 80.04,98.71 81.31,97.44 81.31,93.34 82.3,92.35 82.3,90.34 89.03,83.61 89.03,58.34 76.27,45.59 59.24,45.59 57.21,47.62 57.21,49.51 57.49,49.79 57.73,49.79 58.1,50.16 v4(58.38,50.16)
  BOTTOM w0.152: U48.5 v1(165.87,127.62) ; U40.7 65.36,135.17 65.66,134.87 65.66,134.85 68.94,131.57 71.59,131.57 72.81,132.79 U44.6 v1(72.81,136.73)
SOC_GPIO_14: length 225.7
  TOP w0.152: U23.Y33 v4(59.18,47.76)
  L3_SIG1 w0.102: v1(160.05,126.97) 158.98,128.04 147.61,128.04 146.4,129.25 131.04,129.25 130.39,129.9 123.95,129.9 123.34,130.51 117.74,130.51 117.51,130.74 113.13,130.74 111.95,129.57 110.49,129.57 110.35,129.43 105.84,129.43 105.15,130.12 88.56,130.12 88.32,129.88 86.74,129.88 86.49,130.12 85.21,130.12 80.49,134.84 73.84,134.84 v1(73.46,135.21)
  L5_SIG2 w0.107: v4(59.18,47.76) 59.18,47.35 59.79,46.73 75.8,46.73 87.88,58.82 87.88,83.13 82.73,88.29 82.3,88.29 78.19,92.39 78.19,103.07 77.93,103.34 77.47,103.8 77.47,107.81 76.09,109.19 76.09,119.03 78.86,121.81 78.86,125.45 73.46,130.85 v1(73.46,135.21)
  BOTTOM w0.152: U40.8 65.4,134.52 68.66,131.27 71.96,131.27 73.46,132.77 U44.7 v1(73.46,135.21) ; U48.9 v1(160.05,126.97)
SOC_GPIO_15: length 235.5
  TOP w0.152: U23.Y31 v4(59.18,49.36)
  L3_SIG1 w0.102: v1(162.56,128.92) 159.86,128.92 159.38,129.41 159.32,129.46 152.54,129.46 151.92,130.08 150.83,130.08 150.63,129.88 131.39,129.88 130.69,130.58 129.87,130.58 127.86,132.59 125.32,132.59 124.69,131.95 123.22,131.95 123.09,132.08 118.21,132.08 117.96,132.33 112.24,132.33 111.79,131.88 109.5,131.88 108.87,131.24 107.06,131.24 105.74,132.56 91.46,132.56 91.03,132.13 84.16,132.13 80.77,135.53 74.94,135.53 v1(74.15,136.32)
  L5_SIG2 w0.107: v1(74.15,136.32) 76.78,133.69 76.78,131.73 79.04,129.46 80.44,129.46 81.04,128.86 81.04,115.75 78.94,113.65 78.94,99.22 80.87,97.29 80.87,93.16 81.89,92.14 81.89,90.1 88.57,83.42 88.57,58.53 76.08,46.05 59.43,46.05 58.01,47.47 58.01,48.71 58.29,48.99 58.53,48.99 58.9,49.36 v4(59.18,49.36)
  BOTTOM w0.152: U40.9 65.58,133.87 68.48,130.96 72.23,130.96 74.11,132.84 U44.8 74.11,136.29 v1(74.15,136.32) ; U48.12 v1(162.56,128.92)
SOC_GPIO_16: length 156.3
  TOP w0.152: U23.AA33 v4(58.38,47.76)
  L5_SIG2 w0.107: v1(51.86,139.21) 51.9,139.17 68.47,139.17 71.52,136.12 73.42,136.12 75.41,134.12 75.41,132.08 80.24,127.26 80.24,115.77 78.71,114.25 78.71,95.03 81.66,92.08 81.66,90 88.34,83.32 88.34,58.63 75.99,46.27 59.52,46.27 58.53,47.27 58.38,47.42 v4(58.38,47.76)
  BOTTOM w0.152: v1(51.86,139.21) U39.25 51.86,143.55 52.65,144.35 57.65,144.35 58.14,143.86 U37.5
SOC_HOUT: length 215.7
  TOP w0.152: U23.AF30 v4(54.38,50.16)
  L5_SIG2 w0.107: v4(54.38,50.16) 54.38,50.32 53.94,50.75 53.94,51.11 53.73,51.33 53.49,51.33 53.21,51.61 53.21,51.85 52.9,52.16 49.26,52.16 47.88,50.77 47.88,38.84 49.53,37.19 51.78,37.19 56.56,32.41 60.48,32.41 60.91,32.84 75.43,32.84 77.19,31.09 86.1,31.09 88.16,33.15 90.98,33.15 93.87,30.26 99.32,30.26 103.4,34.34 104.42,34.34 105.13,35.05 105.13,67.03 109.19,71.09 109.19,92.61 110.27,93.69 110.27,115.66 106.5,119.43 106.5,123.53 99.74,130.3 89.2,130.3 84.73,134.77 79.41,134.77 78.92,134.28 78.92,133.97 78.93,133.96 78.93,132.92 78.64,132.63 v1(78.64,131.56)
  BOTTOM w0.152: U43.23 80.19,131.56 v1(78.64,131.56)
SOC_I2C1_DIMM_EN: length 110.1
  TOP w0.152: v1(77.41,115.94) 78.76,115.94 U8.25
  L3_SIG1 w0.102: v1(77.41,115.94) 75.6,115.94 72.24,112.57 72.24,108.81 73.51,107.54 76.61,107.54 83.22,100.94 85.15,100.94 87.77,98.32 88.84,98.32 90.34,96.82 105.42,96.82 119.58,82.67 119.58,47.04 v2(118.47,45.92)
  BOTTOM w0.152: v2(118.47,45.92) 118.47,47.32 118.77,47.62 U71.5
SOC_I2C1_PMBUS_EN: length 100.9
  TOP w0.152: U8.24 77.27,115.29 77.27,115.29 v1(76.6,115.29)
  L3_SIG1 w0.102: v1(76.6,115.29) 75.27,115.29 72.46,112.48 72.46,108.91 73.6,107.77 76.71,107.77 83.27,101.21 86.28,101.21 90.43,97.05 105.52,97.05 120.05,82.52 120.05,53.76 v2(121.23,52.58)
  BOTTOM w0.152: R484.2 v2(121.23,52.58)
SOC_I2C_EN: length 85.3
  TOP w0.152: U1.6 133.82,140.66 133.86,140.69 v1(133.86,140.69)
  L8_SIG3 w0.107: v2(121.28,71.5) 123.47,73.69 123.62,73.69 124.05,74.12 124.05,92.98 119.71,97.33 119.71,106.38 123.49,110.17 127.19,110.17 132.75,115.73 132.75,119.67 133.1,120.01 133.1,128.24 135.38,130.53 135.38,134.34 133.86,135.86 133.86,140.69 v1(133.86,140.69)
  BOTTOM w0.152: U64.5 v2(121.28,71.5)
SOC_LRESETNMIENZ: length 229.9
  TOP w0.152: U23.AE30 v4(55.18,50.16)
  L5_SIG2 w0.107: v1(78.55,133.38) 78.55,134.23 79.31,134.99 85.02,134.99 89.49,130.53 99.83,130.53 107.8,122.55 107.8,121.48 113.44,115.85 113.44,89.31 109.68,85.55 109.68,71.25 105.36,66.94 105.36,34.71 99.81,29.16 94.64,29.16 93.85,28.37 79.38,28.37 75.14,32.61 64.26,32.61 63.02,31.37 62.46,30.81 57.36,30.81 56.72,31.45 56.72,31.93 51.69,36.96 49.43,36.96 47.65,38.74 47.65,52.01 48.6,52.96 53.77,52.96 54,52.73 54,51.63 54.01,51.63 54.01,51.61 54.29,51.33 54.53,51.33 54.81,51.05 54.81,50.81 55.18,50.44 v4(55.18,50.16)
  BOTTOM w0.127: v4(55.18,50.16) 54.78,49.76 54.78,47.5 54.95,47.32
  BOTTOM w0.152: R506.2 56.39,45.89 54.95,47.32 ; U43.26 78.74,133.51 78.61,133.38 v1(78.55,133.38)
SOC_LRESETZ: length 171.7
  TOP w0.127: 54.78,47.32 U23.AF33
  TOP w0.152: v4(54.78,46.43) 54.78,47.32
  L5_SIG2 w0.107: v4(54.78,46.43) 52.96,44.61 52.96,38.51 56.34,35.13 62.27,35.13 63.82,36.68 73.54,36.68 74.83,35.38 81.86,35.38 93.68,47.19 96.13,47.19 98.12,49.18 98.12,86.24 99.14,87.26 99.21,87.26 101.9,89.95 101.9,91.11 108.9,98.11 108.9,114.67 97.3,126.28 88.63,126.28 82.63,132.28 80.49,132.28 v1(79.92,132.86)
  BOTTOM w0.152: v1(79.92,132.86) U43.25
SOC_NMIZ: length 191.8
  TOP w0.152: U23.AG33 v4(53.58,47.76)
  L5_SIG2 w0.107: v1(79.11,132.21) 79.11,132.58 79.76,133.24 83.96,133.24 86.28,130.91 86.96,130.91 88.69,129.18 95.04,129.18 109.36,114.86 109.36,97.92 102.36,90.93 102.36,62.36 102.59,62.13 102.59,51.64 101.68,50.72 101.68,36.8 99.65,34.77 96.85,34.77 95.99,33.92 95.57,33.92 95.43,34.06 87.78,34.06 85.72,32 77.56,32 74.44,35.13 63.11,35.13 62.65,34.67 56.15,34.67 51.28,39.54 51.28,46.86 50.79,47.35 50.79,48.84 50.92,48.97 52.88,48.97 53.21,48.65 53.21,48.41 53.58,48.04 v4(53.58,47.76)
  BOTTOM w0.152: U43.24 80.11,132.21 v1(79.11,132.21)
SOC_PACLKSEL: length 106.8
  TOP w0.152: U23.AG6 v4(53.58,70.16)
  L10_SIG4 w0.107: v4(53.58,70.16) 53.35,69.93 53.34,69.93 53.14,69.73 52.62,69.73 52.34,70.01 52.34,71.91 52.07,72.19 51.82,72.19 51.54,72.47 51.54,75.57 42.04,85.08 42.04,86 42.19,86.16 42.19,93.06 43.84,94.71 43.84,100.69 40.24,104.29 40.24,124.41 41.3,125.48 53.9,125.48 57.71,129.29 77.49,129.29 v1(79.11,130.91)
  BOTTOM w0.152: v1(79.11,130.91) 79.45,130.91 U43.22
SOC_PORZ: length 184
  TOP w0.127: v4(52.78,47.76) 52.78,47.32
  TOP w0.152: R231.1 C202.2 C201.1 C200.1 48.29,37.64 48.29,42.4 52.78,46.89 52.78,47.32 ; U23.AH33 v4(52.78,47.76)
  L5_SIG2 w0.107: v4(52.78,47.76) 52.48,48.06 52.36,48.18 51.84,48.18 51.6,47.93 51.6,39.55 56.24,34.9 62.56,34.9 64.11,36.45 73.44,36.45 75.32,34.58 77.31,34.58 77.44,34.44 81.25,34.44 93.77,46.97 96.23,46.97 98.35,49.09 98.35,85.85 98.68,86.19 99.14,86.19 99.36,86.41 99.36,87.09 102.13,89.86 102.13,91.02 109.13,98.02 109.13,114.77 96.99,126.91 90.42,126.91 v1(87.08,130.26)
  BOTTOM w0.152: U43.8 v1(87.08,130.26)
SOC_POWER_GOOD: length 12.6
  TOP w0.152: v1(130.05,137.31) 130.2,137.16 U1.13 ; R11.2 v1(120.78,135.96)
  L5_SIG2 w0.107: v1(130.05,137.31) 125.02,137.31 122.94,135.23 121.51,135.23 v1(120.78,135.96)
SOC_POWER_START: length 13.4
  TOP w0.152: v1(132.41,137.66) U1.12 ; R19.1 v1(122.68,133.22)
  L5_SIG2 w0.107: v1(132.41,137.66) 130.93,137.66 130.18,136.91 126.36,136.91 v1(122.68,133.22)
SOC_POWER_START_R: length 11.5
  TOP w0.152: U4.23 119.72,131.54 119.89,131.7 119.89,132.97 120.14,133.22 R19.2 v1(120.96,132.49)
  BOTTOM w0.152: v1(120.96,132.49) 125.73,127.72 CN5.6
SOC_RESETFULLZ: length 214
  TOP w0.127: 53.97,47.32 54.38,47.73 54.38,47.99 v4(54.38,48.56)
  TOP w0.152: R230.1 C197.1 C198.1 C199.2 49.78,36.9 48.59,38.09 48.59,41.94 53.97,47.32 ; U23.AF32 v4(54.38,48.56)
  L5_SIG2 w0.107: v1(87.08,131.56) 88.88,129.75 99.63,129.75 105.1,124.29 105.1,120.16 109.82,115.44 109.82,96.42 102.92,89.52 102.92,66.24 103.35,65.81 103.35,62.76 103.15,62.55 103.15,51.03 102.13,50.02 102.13,36.42 99.17,33.46 95.38,33.46 95.24,33.6 87.97,33.6 85.91,31.55 77.38,31.55 74.25,34.67 63.3,34.67 62.74,34.1 61.52,34.1 60.29,32.87 56.95,32.87 51.01,38.81 51,38.81 48.33,41.48 48.33,49.98 48.91,50.56 53.7,50.56 54.01,50.25 54.01,50.01 54.22,49.79 54.47,49.79 54.74,49.51 54.74,48.93 v4(54.38,48.56)
  BOTTOM w0.152: v1(87.08,131.56) U43.6
SOC_RESETSTATZ: length 308.2
  TOP w0.152: U23.AH29 v4(52.78,50.96) ; R75.1 v1(171.96,115.44)
  L3_SIG1 w0.102: v1(171.96,115.44) 168.08,119.32 168.08,122.34 166.23,124.18 149.29,124.18 145.61,127.86 145.61,128.37 145.31,128.68 133.53,128.68 133.51,128.65 128.82,128.65 128.03,129.44 123.76,129.44 123.15,130.05 119.54,130.05 118.24,128.74 113.13,128.74 112.44,128.06 110.85,128.06 110.05,127.25 102.36,127.25 101.63,127.98 87.79,127.98 87.66,128.12 85.34,128.12 79.33,134.12 v1(79.31,134.12)
  L5_SIG2 w0.107: v1(79.31,134.12) 79.72,134.54 84.63,134.54 89.13,130.04 99.67,130.04 105.32,124.39 105.32,120.29 110.05,115.56 110.05,94.27 104.9,89.13 104.9,63.98 103.38,62.46 103.38,49.96 102.36,48.95 102.36,36.33 98.37,32.33 93.17,32.33 92.13,33.38 88.06,33.38 86.01,31.32 77.28,31.32 75.53,33.07 60.81,33.07 60.38,32.64 56.86,32.64 48.11,41.39 48.11,50.64 48.83,51.36 52.38,51.36 v4(52.78,50.96)
  BOTTOM w0.152: v1(79.31,134.12) 79.29,134.12 79.29,134.55 79.55,134.81 80.32,134.81 80.32,134.81 U43.28
SOC_RESETZ: length 226.1
  TOP w0.152: U23.AE29 v4(55.18,50.96)
  L5_SIG2 w0.107: v1(89.65,130.91) 99.77,130.91 108.03,122.65 108.03,121.58 113.67,115.94 113.67,88.93 109.9,85.16 109.9,71.16 105.59,66.84 105.59,34.62 99.9,28.93 94.74,28.93 93.95,28.14 79.28,28.14 75.04,32.38 64.36,32.38 62.55,30.58 57.26,30.58 56.49,31.36 56.49,31.83 51.6,36.72 49.34,36.72 47.42,38.65 47.42,52.63 48.54,53.75 54.58,53.75 54.81,53.52 54.81,53.21 54.81,53.2 54.81,52.72 54.81,52.71 54.81,52.41 54.81,52.4 54.81,51.92 54.81,51.91 54.81,51.61 55.18,51.24 v4(55.18,50.96)
  BOTTOM w0.152: R488.1 C728.2 C727.1 C726.1 43.81,49.25 43.99,49.07 45.62,49.07 47.91,51.36 54.78,51.36 v4(55.18,50.96) ; U43.7 v1(89.65,130.91)
SOC_RS232_RX: length 8.4
  TOP w0.152: 167.06,114.43 165.48,116 165.48,116.08 165.35,116.2 v1(165.35,120.9)
  BOTTOM w0.152: v1(165.35,120.9) 165.34,120.91 U50.8
SOC_RS232_TX: length 6
  BOTTOM w0.152: U50.13 162.74,117.28 163.19,117.73 166.3,117.73 COM1.3
SOC_RSV000: length 30.6
  TOP w0.127: 69.67,47.32 69.58,47.41 69.58,48.56 U23.H32
  TOP w0.152: 69.67,47.32 70.12,46.86 84.68,46.86 92.71,38.84 R236.1
SOC_RSV001: length 29.3
  TOP w0.127: 68.78,47.32 68.78,48.56 U23.J32
  TOP w0.152: 68.78,47.32 68.78,47.29 69.81,46.25 83.41,46.25 90.12,39.55 R237.1
SOC_RSV002: length 6.1
  TOP w0.102: U23.AE2 v4(55.18,73.36)
  BOTTOM w0.102: v4(55.18,73.36) 54.9,73.63 54.9,73.91 54.77,74.05 54.77,78.12 54.93,78.28 R419.1
SOC_RSV003: length 6.1
  TOP w0.102: U23.AF2 v4(54.38,73.36)
  BOTTOM w0.102: v4(54.38,73.36) 54.65,73.63 54.65,73.81 54.51,73.94 54.51,78.18 54.41,78.28 R420.1
SOC_RSV004: length 14.3
  TOP w0.102: R210.1 81.38,74.24 81.23,74.4 76.53,74.4 75.56,75.36 70.72,75.36 70.23,74.88 70.23,74.05 70.36,73.92 70.36,73.6 69.98,73.21 U23.G2
SOC_RSV005: length 14.3
  TOP w0.102: U23.G1 69.98,74.98 70.61,75.62 75.67,75.62 76.64,74.65 76.96,74.65 77.09,74.78 77.32,74.78 77.44,74.65 77.67,74.65 77.8,74.78 78.03,74.78 78.16,74.65 78.38,74.65 78.51,74.78 78.74,74.78 78.87,74.65 79.1,74.65 79.22,74.78 79.45,74.78 79.58,74.65 79.81,74.65 79.93,74.78 80.16,74.78 80.29,74.65 80.52,74.65 80.64,74.78 80.87,74.78 81,74.65 81.23,74.65 81.38,74.8 R206.1
SOC_RSV006: length 9.3
  TOP w0.102: U23.AL3 v4(50.38,72.56)
  BOTTOM w0.102: R430.1 42.37,73.25 42.46,73.34 49.37,73.34 49.88,72.83 50.1,72.83 v4(50.38,72.56)
SOC_RSV007: length 9.3
  TOP w0.102: U23.AL2 v4(50.38,73.36)
  BOTTOM w0.102: v4(50.38,73.36) 50.1,73.09 49.99,73.09 49.48,73.6 42.46,73.6 42.37,73.69 R427.1
SOC_RSV008: length 99.4
  TOP w0.152: U23.AG5 v4(53.58,70.96)
  L10_SIG4 w0.107: v4(53.58,70.96) 53.58,70.81 53.94,70.44 53.94,70.01 53.67,69.73 53.42,69.73 53.21,69.51 53.21,69.27 52.93,68.99 52.62,68.99 52.34,69.27 52.34,69.51 52.07,69.79 51.82,69.79 51.54,70.07 51.54,71.91 51.27,72.19 51.02,72.19 50.81,72.41 50.81,75.98 43.58,83.21 38.96,83.21 34.21,87.95 34.21,97.76 39.8,103.35 39.8,134.28 43.45,137.93 52.58,137.93 v1(53.16,138.51)
  BOTTOM w0.152: v1(53.16,138.51) U39.27
SOC_RSV009: length 1.2
  TOP w0.152: U23.K8 v4(67.98,68.56)
  BOTTOM w0.254: R445.1 v4(67.98,68.56)
SOC_RSV010: length 0.6
  TOP w0.152: U23.J8 v4(68.78,68.56)
SOC_RSV011: length 25.9
  TOP w0.152: v1(49.34,85.76) 47.54,85.76 R173.1 ; U23.W8 v4(59.98,68.56)
  L10_SIG4 w0.107: v1(49.34,85.76) 50.68,85.76 51.73,84.72 51.73,82.17 59.61,74.29 59.61,70.81 59.82,70.59 60.07,70.59 60.34,70.31 60.34,68.93 v4(59.98,68.56)
SOC_RSV012: length 22.5
  TOP w0.152: U23.W7 v4(59.98,69.36) ; R174.1 47.52,85.09 v1(47.8,84.81)
  L10_SIG4 w0.107: v4(59.98,69.36) 59.98,69.61 59.61,69.98 59.61,70.26 59.28,70.59 59.02,70.59 58.81,70.81 58.81,74.57 58.62,74.75 58.29,74.75 48.23,84.81 v1(47.8,84.81)
SOC_RSV013: length 28.5
  TOP w0.152: U23.J30 v4(68.78,50.16)
  BOTTOM w0.152: R521.1 86.64,43.91 82.62,47.93 76.21,47.93 75.49,47.22 70.36,47.22 69.17,48.41 69.17,49.2 69.17,49.2 69.17,49.52 69.17,49.77 v4(68.78,50.16)
SOC_RSV014: length 32.1
  TOP w0.152: U23.J29 v4(68.78,50.96)
  BOTTOM w0.152: v4(68.78,50.96) 69.18,50.55 69.74,50.55 69.97,50.32 69.97,50.31 69.98,50.29 69.98,50 70.21,49.77 70.23,49.77 82.32,49.77 88.6,43.49 88.6,35.69 R534.1
SOC_RSV015: length 12.4
  TOP w0.152: U23.AG8 v4(53.58,68.56)
  BOTTOM w0.152: R433.1 47.35,71.63 50.01,68.97 52.11,68.97 52.12,68.95 52.14,68.95 52.37,68.72 52.37,68.39 52.59,68.17 53.18,68.17 v4(53.58,68.56)
SOC_RSV016: length 10.4
  TOP w0.152: U23.AJ20 v4(51.98,58.16)
  BOTTOM w0.127: v4(51.98,58.16) 51.56,57.74 48.4,57.74
  BOTTOM w0.152: 48.4,57.74 47.43,57.74 45.19,55.5 R473.1
SOC_RSV017: length 17.5
  TOP w0.152: U23.AG12 v4(53.58,65.36)
  L3_SIG1 w0.102: v4(53.58,65.36) 53.18,65.76 45.67,65.76 44.37,64.47 44.37,63.58 v4(44.41,63.54)
  BOTTOM w0.152: R461.1 40.33,64.46 43.97,64.46 44.41,64.02 v4(44.41,63.54)
SOC_RSV018: length 0.6
  TOP w0.152: U23.AJ28 v4(51.98,51.76)
SOC_RSV019: length 0.6
  TOP w0.152: U23.AJ26 v4(51.98,53.36)
SOC_RSV020: length 10.9
  TOP w0.152: U23.AH9 v4(52.78,67.76)
  BOTTOM w0.152: R437.1 47.83,70.36 50.04,68.15 52.14,68.15 52.53,67.76 v4(52.78,67.76)
SOC_RSV021: length 19.8
  TOP w0.152: U23.B19 v4(74.38,58.96)
  BOTTOM w0.152: v4(74.38,58.96) 74.77,59.35 88.06,59.35 90.04,61.34 TP72.1
SOC_RSV022: length 22
  TOP w0.152: U23.E20 v4(71.98,58.16)
  BOTTOM w0.152: v4(71.98,58.16) 72.38,57.75 72.38,57.2 72.61,56.97 72.63,56.97 72.64,56.96 75.91,56.96 77.37,55.5 TP73.1
SOC_RSV023: length 6
  TOP w0.127: U23.A14 75.64,63.36 76.07,63.79
  TOP w0.152: R214.1 77.56,65.28 76.07,63.79
SOC_SCL0: length 146.5
  TOP w0.152: U23.AG30 v4(53.58,50.16)
  L8_SIG3 w0.107: v2(112.72,70.28) 111.31,68.87 111.31,68.49 110.31,67.49 110.31,60.71 111.46,59.57 111.46,58.88 110.31,57.73 110.31,49.22 110.39,49.15 110.39,28.92 107.12,25.65 97.02,25.65 91.18,19.81 54.88,19.81 54.36,20.33 54.36,35.29 54.23,35.42 54.23,44.58 53.98,44.83 53.98,49.76 v4(53.58,50.16)
  BOTTOM w0.152: EEPROM1.6 116.1,74.68 116.94,73.84 116.94,69.95 115.95,68.96 U64.2 113.67,68.96 113.23,69.39 R440.2 v2(112.72,70.28)
SOC_SCL1: length 143.8
  TOP w0.152: U23.AH30 v4(52.78,50.16)
  L8_SIG3 w0.107: v1(114.13,53.14) 112.09,51.1 112.09,47.47 111.31,46.69 111.31,39.47 111.61,39.17 111.61,29.82 105.77,23.98 102.1,23.98 99.1,20.98 95.85,20.98 94.56,19.69 94.56,14.23 91.92,11.59 78.37,11.59 76.82,10.03 69.88,10.03 66.8,13.11 62.75,13.11 57.29,18.57 54.53,18.57 54.1,18.99 54.1,35.22 53.19,36.14 53.19,49.75 v4(52.78,50.16)
  BOTTOM w0.152: v1(114.13,53.14) R480.2 114.51,52.37 114.69,52.19 U69.3 116.47,52.19 117.25,51.41 117.25,46.74 115.6,45.09 U71.2 113.67,45.09 113.23,45.52 R494.2
SOC_SCL2: length 54.8
  TOP w0.152: U21.2 21.79,79.25 21.92,79.38 R200.2 22.54,78.86 22.73,78.66 24,78.66 25.88,76.78 25.88,72.09 31.83,66.14 33.19,66.14 34.09,66.14 v1(34.42,65.81) ; U23.AH31 v4(52.78,49.36)
  L3_SIG1 w0.102: v1(34.42,65.81) 37.13,65.81 40.44,62.51 48.44,62.51 49.19,61.76 51.84,61.76 52.39,61.21 52.39,49.75 v4(52.78,49.36)
SOC_SCL_RTM: length 7.6
  TOP w0.152: J4.D2 15.34,88.46 15.34,85.98 15.6,85.72 18.1,85.72 R186.1
SOC_SDA0: length 147
  TOP w0.152: U23.AG28 v4(53.58,51.76)
  L8_SIG3 w0.107: v4(53.58,51.76) 53.86,51.76 54.29,51.33 54.53,51.33 54.74,51.11 54.74,47.02 54.33,46.61 54.33,45.85 54.46,45.72 54.46,35.51 54.58,35.39 54.58,20.43 54.97,20.04 90.58,20.04 96.42,25.88 107.03,25.88 110.16,29.02 110.16,49.05 110.08,49.13 110.08,57.99 110.29,58.19 110.29,60.05 110.08,60.25 110.08,69.5 v2(112.72,72.14)
  BOTTOM w0.152: v2(112.72,72.14) R435.2 113.16,71.25 113.28,71.12 113.28,70.48 113.54,70.23 U64.3 116.03,70.23 116.46,70.66 116.46,72.95 116,73.41 EEPROM1.5
SOC_SDA1: length 136.8
  TOP w0.152: U23.AJ32 v4(51.98,48.56)
  L8_SIG3 w0.107: v1(112.72,48.11) 113.36,47.47 113.36,40.51 112.93,40.08 112.93,30.81 105.86,23.75 102.19,23.75 99.19,20.75 95.95,20.75 94.82,19.62 94.82,14.16 91.99,11.34 78.45,11.34 76.91,9.8 69.75,9.8 66.69,12.86 62.68,12.86 57.2,18.34 54.43,18.34 52.96,19.81 52.96,43.69 52.35,44.3 52.35,48.19 v4(51.98,48.56)
  BOTTOM w0.152: U69.4 115.07,52.69 114.81,52.96 114.81,54.1 114.68,54.23 R474.2 114.13,53.86 113.94,53.67 113.03,53.67 112.68,53.32 112.68,48.15 v1(112.72,48.11) R491.2 113.16,47.37 113.28,47.24 113.28,46.61 113.54,46.35 U71.3
SOC_SDA2: length 58.9
  TOP w0.152: U21.3 21.75,80.52 22,80.77 R197.2 22.54,81.22 22.9,81.59 22.9,82.07 23.22,82.38 24.25,82.38 25.15,81.48 25.15,77.95 26.19,76.91 26.19,72.21 31.95,66.45 v1(34.39,66.45) ; U23.AG29 v4(53.58,50.96)
  L3_SIG1 w0.102: v1(34.39,66.45) 37.29,66.45 40.89,62.84 49.18,62.84 49.42,62.59 49.44,62.59 49.47,62.56 52.96,62.56 53.14,62.37 53.14,51.39 v4(53.58,50.96)
SOC_SDA_RTM: length 4.2
  TOP w0.152: R187.1 17.4,85.17 17.15,85.42 15.04,85.42 14.7,85.76 J4.D1
SOC_SGMII0_RXN: length 138.6
  TOP w0.102: C161.2 40.32,46.05 40.19,45.92 36.76,45.92 v1(36.56,46.12)
  L10_SIG4 w0.102: v1(36.56,46.12) 36.38,45.95 34.56,45.95 34.21,45.6 34.21,38.18 35.88,36.51 35.88,29.02 33.55,26.7 33.55,19.63 36.36,16.83 53.73,16.83 55.12,18.21 94.95,18.21 96.67,19.93 120.36,19.93 121.74,21.31 126.87,21.31 128.76,19.42 131.24,19.42 131.59,19.77 131.59,20.09 v1(131.83,20.32)
  BOTTOM w0.102: U77.5 131.72,19.57 131.6,19.69 131.6,20.09 v1(131.83,20.32)
SOC_SGMII0_RXN_R: length 10.7
  TOP w0.102: C161.1 41.22,46.03 41.27,45.97 42.62,45.97 42.95,46.29 43.35,46.29 48.14,51.09 49.02,51.09 49.18,51.24 U23.AN29
SOC_SGMII0_RXP: length 138.6
  TOP w0.102: v1(36.56,45.46) 36.76,45.67 37.88,45.67 38.08,45.47 38.31,45.47 38.51,45.67 38.74,45.67 38.94,45.47 39.17,45.47 39.37,45.67 40.17,45.67 40.32,45.52 C163.2
  L10_SIG4 w0.102: v1(131.06,20.32) 131.3,20.09 131.3,19.89 131.12,19.71 128.88,19.71 126.99,21.6 121.62,21.6 120.24,20.22 96.55,20.22 94.83,18.5 55,18.5 53.61,17.12 36.48,17.12 33.85,19.76 33.85,26.57 36.17,28.9 36.17,36.64 34.51,38.3 34.51,39.53 34.67,39.69 34.67,39.92 34.51,40.09 34.51,40.32 34.7,40.51 34.7,40.73 34.51,40.93 34.51,41.15 34.7,41.34 34.7,41.57 34.51,41.76 34.51,41.99 34.7,42.18 34.7,42.41 34.51,42.6 34.51,42.83 34.7,43.02 34.7,43.25 34.51,43.44 34.51,43.67 34.7,43.86 34.7,44.09 34.51,44.28 34.51,44.51 34.7,44.7 34.7,44.93 34.51,45.12 34.51,45.48 34.68,45.66 36.36,45.66 v1(36.56,45.46)
  BOTTOM w0.102: v1(131.06,20.32) 131.08,20.32 131.34,20.05 131.34,19.7 131.22,19.57 U77.4
SOC_SGMII0_RXP_R: length 10.7
  TOP w0.102: U23.AN30 48.9,50.83 48.25,50.83 43.45,46.04 43.05,46.04 42.73,45.71 41.39,45.71 41.22,45.54 C163.1
SOC_SGMII0_TXN: length 138.4
  TOP w0.102: U23.AL30 v4(50.38,50.16)
  L10_SIG4 w0.102: v1(129.16,23.24) 128.92,23.48 128.92,23.74 128.31,24.36 96.47,24.36 92.4,20.29 67.3,20.29 63.48,24.11 47.47,24.11 44.34,20.98 40.74,20.98 38.15,23.58 38.15,27.15 39.24,28.24 39.24,37.13 38.75,37.63 38.75,49.28 39.99,50.53 50.06,50.53 50.38,50.21 v4(50.38,50.16)
  BOTTOM w0.102: v1(129.16,23.24) 128.82,22.91 128.82,22.29 128.94,22.17 C816.1
SOC_SGMII0_TXP: length 138.4
  TOP w0.102: U23.AL29 v4(50.38,50.96)
  L10_SIG4 w0.102: v4(50.38,50.96) 50.24,50.82 39.87,50.82 38.46,49.4 38.46,37.51 38.95,37.01 38.95,28.37 37.85,27.27 37.85,23.45 40.62,20.69 44.46,20.69 47.59,23.82 63.36,23.82 67.18,20 92.53,20 96.59,24.07 128.19,24.07 128.63,23.62 128.63,23.48 v1(128.4,23.24)
  BOTTOM w0.102: C817.1 128.25,22.17 128.57,22.49 128.57,23.07 v1(128.4,23.24)
SOC_SGMII1_RXN: length 154.3
  TOP w0.102: v1(41.38,48.16) 41.58,47.95 42.29,47.95 42.35,48.01 C159.2
  L10_SIG4 w0.102: v1(133.86,43.95) 133.62,43.72 133.62,41.59 134.06,41.15 134.06,36.45 136.23,34.28 136.23,24.87 135.3,23.94 131.27,23.94 129.81,25.4 96.79,25.4 92.19,20.8 67.51,20.8 63.69,24.62 47.26,24.62 44.13,21.49 40.95,21.49 39.17,23.27 39.17,26.17 39.08,26.26 39.08,26.93 40.1,27.95 40.1,37.33 39.34,38.09 39.34,47.65 39.65,47.95 41.18,47.95 v1(41.38,48.16)
  BOTTOM w0.102: U73.5 133.75,43.21 133.63,43.33 133.63,43.73 v1(133.86,43.95)
SOC_SGMII1_RXN_R: length 9.3
  TOP w0.102: U23.AM28 49.59,52.55 48.4,52.55 48.1,52.25 47.95,52.25 43.65,47.94 43.36,47.94 43.25,48.05 C159.1
SOC_SGMII1_RXP: length 154.2
  TOP w0.102: C160.2 42.35,47.64 42.29,47.7 41.58,47.7 v1(41.38,47.5)
  L10_SIG4 w0.102: v1(41.38,47.5) 41.22,47.66 39.77,47.66 39.64,47.53 39.64,47.26 39.78,47.12 39.78,46.89 39.64,46.75 39.64,46.53 39.78,46.39 39.78,46.16 39.64,46.02 39.64,45.79 39.78,45.65 39.78,45.42 39.64,45.28 39.64,45.05 39.78,44.91 39.78,44.68 39.64,44.54 39.64,44.32 39.78,44.18 39.78,43.95 39.64,43.81 39.64,43.58 39.78,43.44 39.78,43.21 39.64,43.07 39.64,42.84 39.78,42.7 39.78,42.47 39.64,42.33 39.64,42.11 39.78,41.97 39.78,41.74 39.64,41.6 39.64,41.37 39.78,41.23 39.78,41 39.64,40.86 39.64,40.63 39.78,40.49 39.78,40.26 39.64,40.12 39.64,39.9 39.78,39.76 39.78,39.53 39.64,39.39 39.64,39.16 39.78,39.02 39.78,38.79 39.64,38.65 39.64,38.21 40.4,37.45 40.4,27.83 39.37,26.8 39.37,26.38 39.46,26.29 39.46,23.4 41.07,21.78 44.01,21.78 47.14,24.91 63.81,24.91 67.63,21.09 92.07,21.09 96.67,25.69 129.94,25.69 131.39,24.24 135.17,24.24 135.93,25 135.93,34.16 135.35,34.74 133.77,36.33 133.77,41.03 133.33,41.47 133.33,43.72 v1(133.1,43.95)
  BOTTOM w0.102: U73.4 133.25,43.21 133.38,43.33 133.38,43.69 133.11,43.95 v1(133.1,43.95)
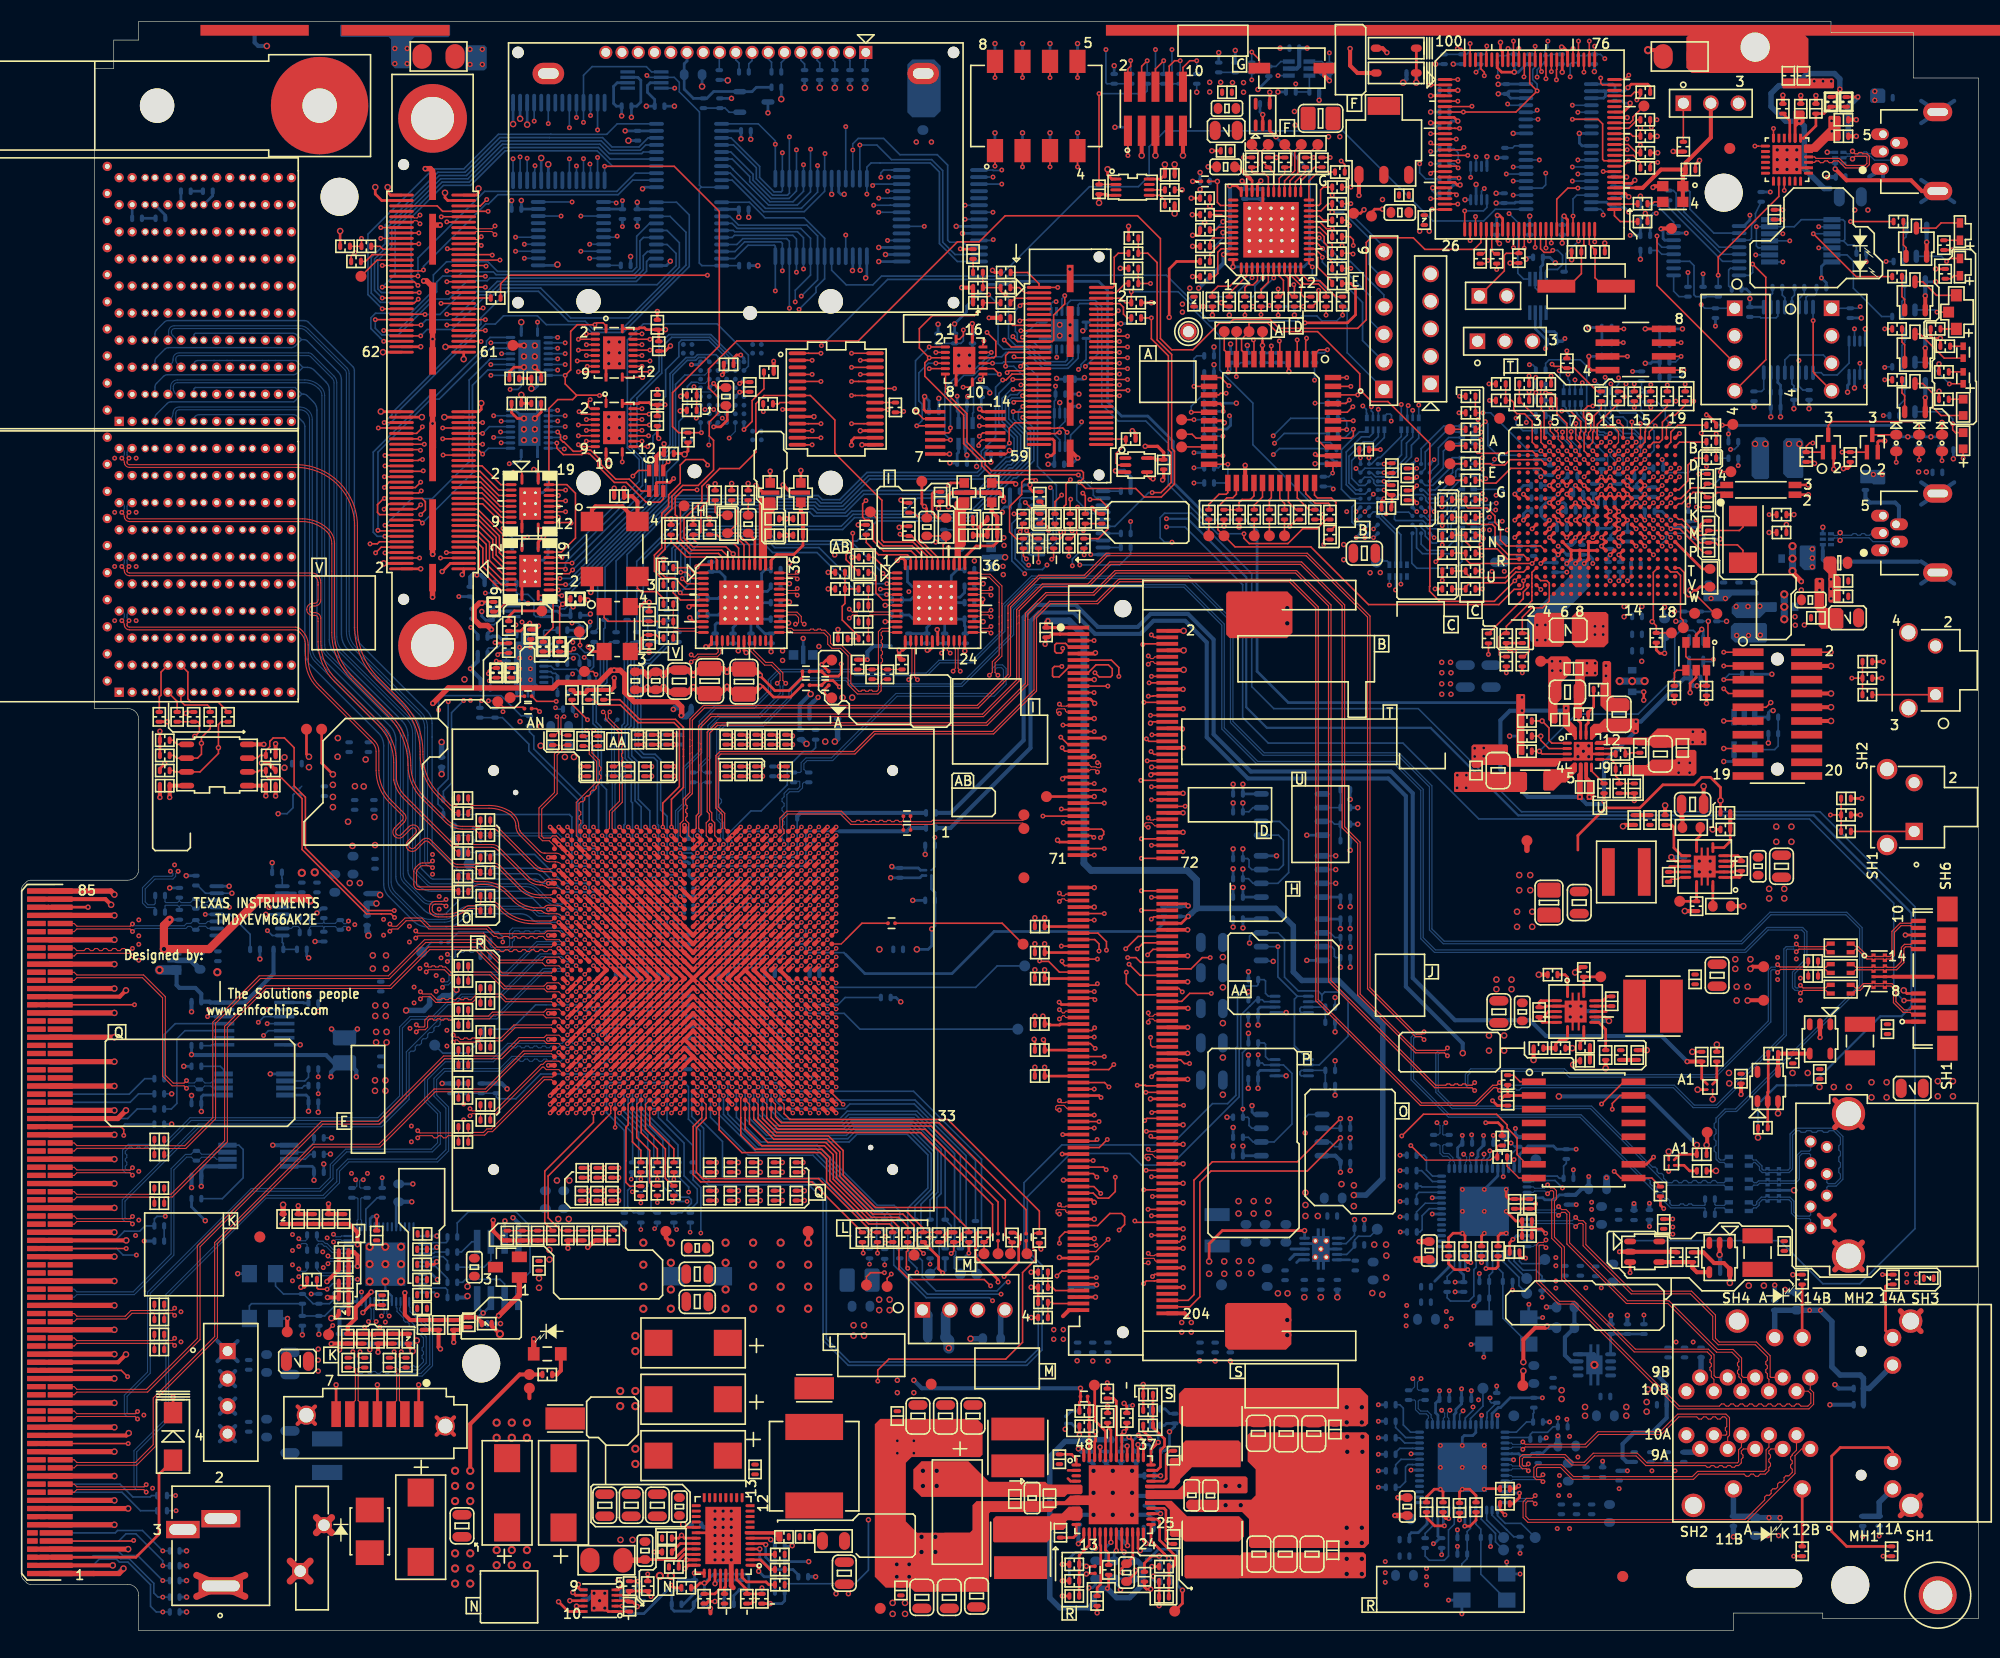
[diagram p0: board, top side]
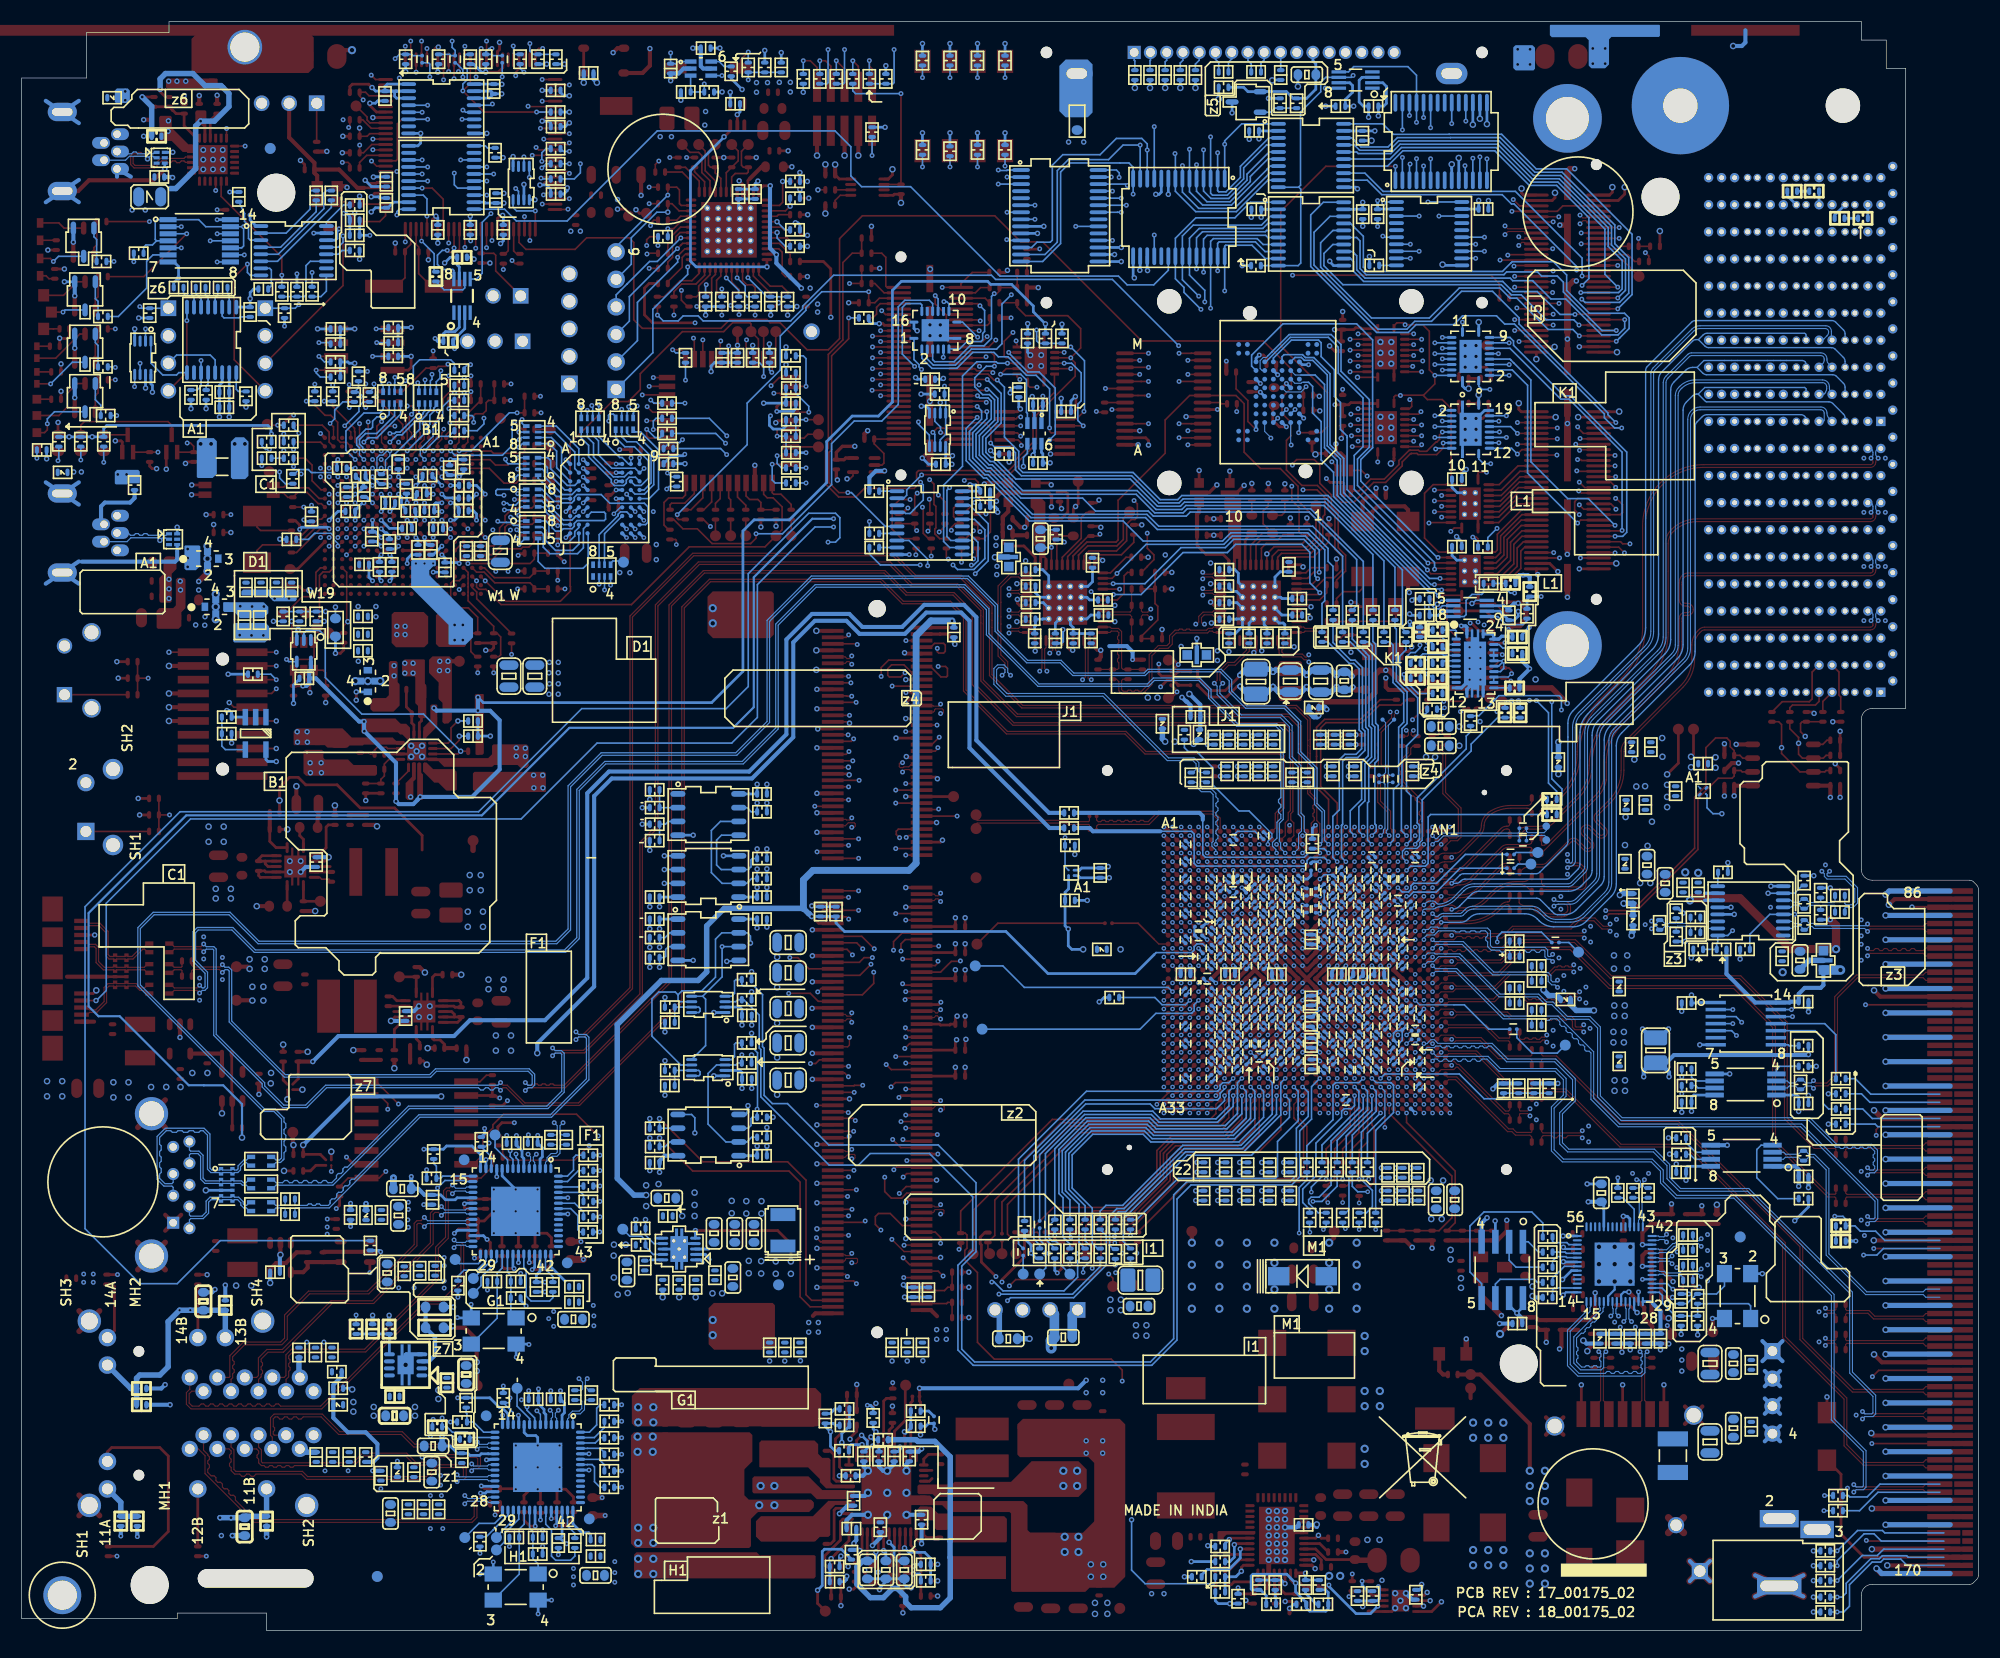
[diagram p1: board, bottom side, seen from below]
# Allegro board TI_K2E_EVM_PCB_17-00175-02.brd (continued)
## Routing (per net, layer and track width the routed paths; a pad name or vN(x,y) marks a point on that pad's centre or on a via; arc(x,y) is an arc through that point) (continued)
SOC_SGMII1_RXP_R: length 9.3
  TOP w0.102: C160.1 43.25,47.55 43.38,47.69 43.75,47.69 48.06,51.99 48.19,51.99 48.42,51.77 49.58,51.77 49.68,51.66 49.68,51.65 U23.AM29
SOC_SGMII1_TXN: length 182.6
  TOP w0.102: U23.AK29 v4(51.18,50.96)
  L10_SIG4 w0.102: v1(131.44,46.86) 131.18,47.12 131.18,47.51 131.41,47.73 135.54,47.73 136.32,46.95 136.32,45.31 135.94,44.93 135.94,36.53 136.78,35.69 136.78,24.5 135.57,23.29 130.44,23.29 129.61,22.46 127.83,22.46 126.75,23.54 97.28,23.54 93.15,19.41 67.06,19.41 63.15,23.31 49.66,23.31 46.53,20.18 40.38,20.18 37.35,23.21 37.35,44.75 37.6,45.01 37.6,45.55 37.72,45.66 37.72,45.89 37.6,46.01 37.6,46.23 37.72,46.35 37.72,46.58 37.6,46.69 37.6,46.92 37.72,47.03 37.72,47.26 37.6,47.38 37.6,47.61 37.72,47.72 37.72,47.95 37.6,48.06 37.6,48.29 37.72,48.41 37.72,48.63 37.6,48.75 37.6,48.98 37.72,49.09 37.72,49.32 37.6,49.43 37.6,49.66 37.72,49.78 37.72,50.01 37.6,50.12 37.6,50.35 37.72,50.46 37.72,50.69 37.6,50.81 37.6,51.03 38.06,51.49 38.74,51.49 38.87,51.36 39.1,51.36 39.23,51.49 39.45,51.49 39.58,51.36 39.81,51.36 39.94,51.49 40.17,51.49 40.29,51.36 40.52,51.36 40.65,51.49 40.88,51.49 41,51.36 41.23,51.36 41.36,51.49 41.59,51.49 41.71,51.36 41.94,51.36 42.07,51.49 42.3,51.49 42.43,51.36 42.65,51.36 42.78,51.49 43.01,51.49 43.14,51.36 43.37,51.36 43.49,51.49 43.72,51.49 43.85,51.36 44.08,51.36 44.2,51.49 44.43,51.49 44.56,51.36 44.79,51.36 44.92,51.49 45.14,51.49 45.27,51.36 45.5,51.36 45.63,51.49 45.86,51.49 45.98,51.36 46.21,51.36 46.34,51.49 46.57,51.49 46.69,51.36 46.92,51.36 47.05,51.49 47.28,51.49 47.4,51.36 47.63,51.36 47.76,51.49 47.99,51.49 48.12,51.36 48.34,51.36 48.47,51.49 48.7,51.49 48.83,51.36 49.06,51.36 49.18,51.49 49.41,51.49 49.54,51.36 49.77,51.36 49.89,51.49 50.13,51.49 50.22,51.39 50.74,51.39 v4(51.18,50.96)
  BOTTOM w0.102: C732.1 131.22,45.74 131.17,45.8 131.17,46.58 v1(131.44,46.86)
SOC_SGMII1_TXP: length 182.6
  TOP w0.102: U23.AK28 v4(51.18,51.76)
  L10_SIG4 w0.102: v1(130.63,46.86) 130.89,47.12 130.89,47.63 131.29,48.03 135.66,48.03 136.61,47.07 136.61,45.19 136.23,44.81 136.23,36.65 137.08,35.81 137.08,24.38 135.69,22.99 130.56,22.99 129.73,22.17 127.71,22.17 126.63,23.25 97.4,23.25 93.27,19.11 66.94,19.11 63.03,23.02 49.78,23.02 46.65,19.89 40.26,19.89 37.05,23.09 37.05,44.87 37.31,45.13 37.31,51.16 37.93,51.78 49.87,51.78 50.22,52.13 50.54,52.13 50.91,51.76 v4(51.18,51.76)
  BOTTOM w0.102: C733.1 130.74,45.74 130.91,45.91 130.91,46.58 v1(130.63,46.86)
SOC_SGMII_MDC: length 23.4
  TOP w0.152: v1(43.81,89.47) 44.22,89.47 44.85,88.84 R643.2
  L3_SIG1 w0.102: v1(43.81,89.47) 43.46,89.47 39.71,85.72 v1(39.37,85.72)
  BOTTOM w0.152: v1(43.81,89.47) 43.81,88.81 44.11,88.51 U80.17 ; v1(43.81,89.47) 44.27,89.01 U80.18 ; v1(43.81,89.47) 43.84,89.51 U80.19 U80.20 U80.21 ; R630.2 38.92,75.79 38.43,76.28 38.43,77.67 39.37,78.61 v1(39.37,85.72)
SOC_SGMII_MDIO: length 22.6
  TOP w0.152: R646.2 49.66,94.45 v2(49.93,94.73) 50.43,95.22 R626.1
  L10_SIG4 w0.107: v1(43.08,85.8) 42.65,86.24 42.65,92.84 44.12,94.31 49.52,94.31 v2(49.93,94.73)
  BOTTOM w0.152: U58.5 49.57,95.09 v2(49.93,94.73) ; R631.2 43.69,85.62 43.51,85.8 v1(43.08,85.8)
SOC_SPI2_CLK: length 185.8
  TOP w0.152: R232.2 81.79,35.07 81.66,34.94 81.66,33.55 v1(81.79,33.43) ; CN7.91 v1(39.24,125.49)
  L3_SIG1 w0.102: v1(81.79,33.43) 81.79,33.36 83.1,32.05 86.31,32.05 90.48,36.22 98.01,36.22 98.69,36.9 100.49,36.9 101.04,36.35 102.48,36.35 103.33,37.2 105.64,37.2 106.72,38.27 108.95,38.27 117.68,47.01 117.68,83.28 105.05,95.91 90.35,95.91 89.63,95.18 89.31,95.18 87.02,97.48 83.26,97.48 77.92,102.82 74.48,102.82 69.52,107.78 69.52,115.76 59.27,126.01 52.08,126.01 51.93,126.17 51.23,126.87 48.18,126.87 47.19,125.88 44.29,125.88 43.9,125.49 v1(39.24,125.49)
SOC_SPI2_CS0: length 184.1
  TOP w0.152: CN7.83 v1(39.3,123.49)
  L3_SIG1 w0.102: v1(39.3,123.49) 39.3,122.43 38.86,121.99 38.86,120.34 39.62,119.58 47.29,119.58 48.85,121.13 60.3,121.13 65.89,115.54 65.89,109.38 64.8,108.29 64.8,105.57 68.56,101.8 71.34,101.8 77.34,95.81 77.34,93.56 81.52,89.38 102.12,89.38 103.05,88.45 106.66,88.45 114.39,80.72 114.39,56.64 114.85,56.19 114.85,48.42 111.88,45.44 110.33,45.44 106.34,41.45 97.21,41.45 96.59,42.08 91.74,42.08 86.88,37.21 79.72,37.21 79.12,36.62 79.12,35.56 79.65,35.03 v1(79.65,33.73)
  BOTTOM w0.152: R541.2 v1(79.65,33.73)
SOC_SPI2_CS1: length 183.1
  TOP w0.152: CN7.85 v1(42.8,123.99)
  L3_SIG1 w0.102: v1(79.73,36.37) 79.86,36.37 83.71,32.51 86.12,32.51 90.29,36.68 96.69,36.68 97.47,37.46 99.57,37.46 100.28,38.18 102.9,38.18 103.42,37.66 105.46,37.66 106.53,38.73 108.76,38.73 117.22,47.19 117.22,83.09 107.4,92.91 100.12,92.91 98.48,94.55 88.23,94.55 87.62,95.16 87.62,95.17 87.57,95.22 87.57,96.37 86.9,97.03 82,97.03 78.27,100.76 75.59,100.76 71.34,105 69.98,105 68.35,106.63 68.35,108.61 68.07,108.9 68.07,116.57 59.21,125.43 45.05,125.43 43.62,123.99 v1(42.8,123.99)
  BOTTOM w0.152: R526.2 79.65,36.42 79.68,36.4 79.68,36.37 v1(79.73,36.37)
SOC_SPI2_CS2: length 187
  TOP w0.152: CN7.87 v1(39.24,124.49) ; R233.2 79.78,35.85 v4(79.7,35.77)
  L3_SIG1 w0.102: v4(79.7,35.77) 79.35,36.12 79.35,36.52 79.57,36.75 79.93,36.75 83.48,33.2 84.54,33.2 84.81,33.48 86.76,33.48 90.62,37.34 97.03,37.34 98.17,38.48 102.92,38.48 103.51,37.89 105.37,37.89 106.44,38.96 108.66,38.96 116.2,46.5 116.2,59.62 116.56,59.98 116.56,82.27 107.58,91.26 105.92,91.26 104.9,92.28 94.35,92.28 93.75,91.68 88.53,91.68 87.27,92.94 87.27,96.17 86.62,96.82 82.09,96.82 82.09,96.83 81.89,96.83 78.18,100.54 75.49,100.54 71.25,104.78 69.88,104.78 67.86,106.79 67.86,115.34 58.46,124.74 58.07,125.13 45.08,125.13 43.56,123.61 40.13,123.61 v1(39.24,124.49)
SOC_SPI2_CS3: length 183.8
  TOP w0.152: CN7.89 v1(42.8,124.99)
  L3_SIG1 w0.102: v1(42.8,124.99) 44.29,124.99 44.95,125.66 47.33,125.66 48.31,126.64 51.13,126.64 51.99,125.78 59.18,125.78 68.99,115.98 68.99,107.99 74.39,102.59 77.83,102.59 83.19,97.23 86.98,97.23 87.76,96.45 87.76,95.31 88.3,94.77 89.54,94.77 90.45,95.68 104.95,95.68 117.45,83.18 117.45,47.1 108.85,38.5 106.62,38.5 105.55,37.43 103.24,37.43 102.39,36.58 101.14,36.58 100.58,37.13 97.47,37.13 96.78,36.45 90.38,36.45 86.22,32.28 83.39,32.28 v4(82.63,33.05)
  BOTTOM w0.152: R524.2 82.45,35.97 81.89,35.41 81.89,34.18 82.63,33.45 v4(82.63,33.05)
SOC_SPI2_DIN: length 127.6
  TOP w0.152: R54.2 44.2,124.31 44.98,125.09 v1(63.3,125.09) ; U23.P30 v4(64.78,50.16)
  L5_SIG2 w0.107: v4(64.78,50.16) 65.19,50.57 76.67,50.57 86.28,60.18 86.28,80.7 79.25,87.74 79.25,89.05 76.71,91.59 76.11,92.19 76.11,92.71 73.18,95.64 73.18,102.82 71.41,104.59 71.41,116.73 73.03,118.34 73.03,123.61 71.92,124.71 63.68,124.71 v1(63.3,125.09)
SOC_SPI2_DOUT: length 184.3
  TOP w0.152: CN7.79 v1(38.7,122.49)
  L3_SIG1 w0.102: v4(78.26,33.8) 78.81,33.8 79.38,34.37 79.38,34.98 78.89,35.46 78.89,36.71 79.62,37.44 86.78,37.44 91.64,42.3 99.32,42.3 99.48,42.14 100.41,42.14 100.48,42.21 102.11,42.21 102.24,42.09 103.96,42.09 105.45,43.58 108.14,43.58 110.23,45.67 111.78,45.67 114.62,48.51 114.62,56.09 114.17,56.55 114.17,80.62 107.41,87.38 106.19,87.38 105.9,87.09 103.19,87.09 101.5,88.78 96.72,88.78 96.54,88.6 94.43,88.6 93.88,89.15 81.42,89.15 77.11,93.47 77.11,95.72 72.27,100.56 69.48,100.56 64.57,105.47 64.57,108.35 65.68,109.46 65.68,115.42 60.2,120.9 48.94,120.9 47.39,119.35 39.52,119.35 38.63,120.24 38.63,122.42 v1(38.7,122.49)
  BOTTOM w0.152: R542.2 v4(78.26,33.8)
SOC_TCK: length 96.5
  TOP w0.152: U23.AJ33 v4(51.98,47.76)
  L5_SIG2 w0.107: v1(97.66,98.35) 97.66,97.6 89.73,89.66 89.73,87.53 90.4,86.86 90.4,57.71 76.9,44.22 57.57,44.22 54.93,46.86 52.87,46.86 v4(51.98,47.76)
  BOTTOM w0.152: R389.1 102.35,99.36 101.35,98.35 v1(97.66,98.35)
  BOTTOM w0.254: U23.AJ33 v4(51.98,47.76)
SOC_TDI: length 94.3
  TOP w0.152: U23.AG31 v4(53.58,49.36)
  L5_SIG2 w0.107: v1(92.58,97.54) 92.58,93.88 88.49,89.79 88.49,87.8 89.71,86.58 89.71,58 76.62,44.9 58.83,44.9 55.6,48.13 54.27,48.13 54.02,48.38 54.02,48.39 54.01,48.41 54.01,48.93 v4(53.58,49.36)
  BOTTOM w0.152: v1(92.58,97.54) 91.39,98.73 91.39,102.16 93.09,103.86 U57.18
SOC_TDO: length 99.4
  TOP w0.152: U23.AF29 v4(54.38,50.96)
  L5_SIG2 w0.107: v4(54.38,50.96) 54.38,50.68 54.78,50.28 54.78,50.04 55.02,49.79 55.27,49.79 55.54,49.51 55.54,48.61 59.02,45.13 76.46,45.13 89.48,58.16 89.48,86.48 88.26,87.71 88.26,97.34 90.54,99.62 94.61,99.62 94.69,99.69 96.8,99.69 97.23,99.26 97.23,98.53 v1(96.98,98.27)
  BOTTOM w0.152: v1(96.98,98.27) 96.98,98.88 98.7,100.61 U57.8
SOC_TEMP1: length 22.1
  TOP w0.254: v2(115.77,137.87) 115.77,137.85 115.2,138.42 Q1.3 ; v2(111.81,125.87) 111.82,125.88 U4.48
  BOTTOM w0.254: v2(115.77,137.87) 115.77,137.85 118.87,134.75 118.87,126.39 118.35,125.87 v2(111.81,125.87)
SOC_TIMI0: length 199.9
  TOP w0.127: 67.58,47.32 U23.K33
  TOP w0.152: R242.1 82.85,36.75 82.68,36.58 82.68,35.35 v1(83.23,34.79) ; R242.1 R241.2 ; R242.1 83.24,37.11 81.61,38.73 78.69,38.73 75.51,41.91 75.51,44.17 74.35,45.34 69.43,45.34 67.58,47.19 67.58,47.32 ; CN7.73 v1(42.8,120.99)
  L3_SIG1 w0.102: v1(42.8,120.99) 43.13,121.32 46.96,121.32 49.86,124.22 57.69,124.22 67.05,114.86 67.05,110.25 65.02,108.23 65.02,105.66 68.65,102.03 71.02,102.03 71.02,102.03 71.44,102.03 73.74,99.72 76.64,96.82 78.44,95.03 78.44,93.81 82.63,89.61 102.21,89.61 103.02,88.8 106.6,88.8 107.02,89.23 107.48,89.23 114.62,82.09 114.62,56.74 115.08,56.28 115.08,48.32 111.97,45.21 110.42,45.21 106.26,41.05 91.03,41.05 84.77,34.79 v1(83.23,34.79)
SOC_TIMI1: length 202.8
  TOP w0.127: U23.K32 67.98,48.56 67.98,47.32
  TOP w0.152: 67.98,47.32 67.98,47.23 69.56,45.64 74.47,45.64 75.82,44.3 75.82,42.03 78.81,39.04 85.37,39.04 87.43,36.98 R239.1 86.86,36.75 86.72,36.6 86.72,36.04 86.52,35.85 R240.2 86.03,35.04 v1(85.79,34.8) ; v1(42.6,122.07) 42.52,121.99 CN7.77
  L3_SIG1 w0.102: v1(85.79,34.8) 91.02,40.02 99.21,40.02 99.28,39.95 103.73,39.95 104.34,40.56 109.3,40.56 115.31,46.58 115.31,56.37 114.85,56.83 114.85,82.18 107.55,89.48 105.92,89.48 105.07,90.33 99.74,90.33 99.32,90.75 96.73,90.75 96.25,90.27 88.6,90.27 87.91,90.96 83.38,90.96 80.99,93.35 80.99,96.74 77.86,99.87 75.21,99.87 70.99,104.09 67.47,104.09 66.09,105.47 66.09,109.01 67.25,110.17 67.25,114.98 57.78,124.45 46.01,124.45 43.63,122.07 v1(42.6,122.07)
SOC_TIMO0: length 180
  TOP w0.152: CN7.71 v1(39.24,120.49)
  L3_SIG1 w0.102: v1(39.24,120.49) 41.23,122.48 43.72,122.48 45.91,124.68 57.88,124.68 67.46,115.1 67.46,110.09 66.32,108.95 66.32,105.57 67.57,104.32 71.07,104.32 75.3,100.09 77.99,100.09 81.18,96.9 81.18,93.43 83.39,91.23 93.94,91.23 94.25,91.54 95.74,91.54 96.29,90.99 99.34,90.99 99.34,90.98 99.42,90.98 99.84,90.56 105.16,90.56 105.82,89.91 107.45,89.91 115.32,82.04 115.32,62.86 115.92,62.25 115.92,60.63 115.54,60.25 115.54,46.48 109.39,40.34 106.89,40.34 106.03,39.48 103.46,39.48 102.99,39.01 97.92,39.01 96.96,38.05 89.64,38.05 85.52,33.93 84.62,33.93 84.49,33.8 v4(83.85,33.8)
  BOTTOM w0.152: R538.1 v4(83.85,33.8)
SOC_TIMO1: length 185.1
  TOP w0.152: CN7.75 v1(39.24,121.49)
  L3_SIG1 w0.102: v1(39.24,121.49) 40.51,122.76 43.67,122.76 45.82,124.9 57.97,124.9 67.66,115.22 67.66,110 66.55,108.89 66.55,105.66 67.66,104.55 71.16,104.55 75.39,100.31 78.09,100.31 81.38,97.02 81.38,93.51 83.44,91.45 93.85,91.45 94.16,91.77 103.58,91.77 104.32,91.03 107.48,91.03 116.33,82.18 116.33,60.28 115.77,59.72 115.77,46.39 109.49,40.11 106.98,40.11 106.13,39.25 103.56,39.25 103.08,38.78 98.01,38.78 97.06,37.82 89.73,37.82 85.62,33.71 84.72,33.71 84.45,33.43 83.57,33.43 82.85,34.15 82.85,35.36 v4(83.77,36.28)
  BOTTOM w0.152: R523.1 83.85,36.47 83.77,36.4 v4(83.77,36.28)
SOC_TMS: length 97.6
  TOP w0.152: U23.AH32 v4(52.78,48.56)
  L5_SIG2 w0.107: v4(52.78,48.56) 52.78,48.28 53.14,47.91 53.14,47.67 53.72,47.09 55.02,47.09 57.67,44.45 76.81,44.45 90.17,57.81 90.17,86.77 88.94,87.99 88.94,89.6 94.64,95.29 v1(94.64,98.35)
  BOTTOM w0.152: U57.16 92.65,102.56 91.69,101.6 91.69,100.64 91.69,100.62 91.69,98.94 92.71,97.93 94.22,97.93 v1(94.64,98.35)
SOC_TRST#: length 91
  TOP w0.152: U23.AG32 v4(53.58,48.56)
  L5_SIG2 w0.107: v4(53.58,48.56) 53.58,48.5 54.27,47.8 54.61,47.8 55.02,47.39 55.05,47.39 57.76,44.67 76.71,44.67 89.94,57.9 89.94,86.67 88.72,87.9 88.72,89.69 92.96,93.94 92.96,97.69 92.94,97.71 v1(92.94,98.33)
  BOTTOM w0.152: v1(92.94,98.33) 92.73,98.33 92.33,98.74 92.33,100.44 93.15,101.26 U57.14
SOC_TVD: length 13.3
  TOP w0.152: v1(95.63,123.97) EMU1.1 93.9,124.3 92.86,125.35 R45.2 ; EMU1.12 100.87,121.47 v1(101.22,121.82)
  L3_SIG1 w0.107: v1(101.22,121.82) 99.07,123.97 v1(95.63,123.97)
SOC_UART0_DETECT: length 9.8
  L5_SIG2 w0.107: v1(169.67,116.97) 170.68,117.97 170.68,121.22 v1(169.7,122.2)
  BOTTOM w0.152: v1(169.7,122.2) 169.54,122.05 R339.2 COM1.1 ; U52.6 169.67,116.96 v1(169.67,116.97)
SOC_UART0_RXD_3V3: length 142.8
  L10_SIG4 w0.107: v1(50.8,131.86) 51.34,131.32 72.56,131.32 81.98,140.74 120.32,140.74 120.47,140.89 131.8,140.89 131.95,140.74 133.27,140.74 133.7,140.31 138.33,140.31 138.73,140.72 140.53,140.72 144.18,137.06 148.34,137.06 149.56,135.84 149.56,135.59 151.52,133.62 151.52,133.19 161.44,123.27 167.54,123.27 168.44,122.37 168.44,116.55 v1(170.18,114.81)
  BOTTOM w0.152: U52.5 170.17,114.82 v1(170.18,114.81) ; v1(50.8,131.86) U45.20
SOC_UART0_RXD_V1P8: length 120.9
  TOP w0.152: U23.T29 v4(63.18,50.96)
  L5_SIG2 w0.107: v1(54.88,131.77) 56.16,130.49 56.16,129.38 61.12,124.42 71.89,124.42 72.8,123.51 72.8,118.44 71.18,116.82 71.18,104.49 72.95,102.72 72.95,95.54 75.88,92.61 75.88,92.1 77.62,90.35 77.62,89.04 86.05,80.61 86.05,60.28 77.92,52.15 63.84,52.15 63.61,51.91 63.61,51.39 v4(63.18,50.96)
  BOTTOM w0.152: v1(54.88,131.77) 54.79,131.86 U45.1
SOC_UART0_TXD_3V3: length 150.8
  TOP w0.127: U2.12 161.69,138.3
  TOP w0.152: 161.69,138.3 v1(161.69,138.64) ; R7.2 150.31,138.84 v1(150.42,138.73)
  L3_SIG1 w0.254: v1(161.69,138.64) 150.51,138.64 v1(150.42,138.73)
  L8_SIG3 w0.107: v1(164.04,117.22) 164.41,117.59 164.41,137.13 162.91,138.64 v1(161.69,138.64)
  L10_SIG4 w0.107: v1(150.42,138.73) 150.42,140.48 149.24,141.66 148.37,141.66 148.14,141.43 135.48,141.43 135.28,141.63 131.73,141.63 131.19,142.17 117.81,142.17 117.12,141.48 82.4,141.48 73.48,132.56 50.37,132.56 49.78,131.98 v1(49.78,130.56)
  BOTTOM w0.152: R358.1 164.4,114.5 164.04,114.85 U50.11 v1(164.04,117.22) ; v1(49.78,130.56) U45.18
SOC_UART0_TXD_V1P8: length 185.6
  L3_SIG1 w0.102: v4(78.26,36.45) 77.29,35.48 77.29,33.43 79.35,31.37 86.6,31.37 89.15,33.92 101.22,33.92 103.08,35.77 107.42,35.77 119.35,47.71 119.35,82.57 105.33,96.6 90.23,96.6 88.71,98.12 83.59,98.12 78.21,103.5 74.77,103.5 71.41,106.86 71.41,119.37 60.22,130.56 v1(51.61,130.56)
  BOTTOM w0.152: R527.1 v4(78.26,36.45) ; v1(51.61,130.56) U45.3
SOC_UART1_CTS_3V3: length 11.2
  TOP w0.152: CN7.99 39.33,127.49 v1(39.29,127.54)
  L8_SIG3 w0.107: v1(39.29,127.54) 39.33,127.49 40.73,127.49 42.71,125.51 45.25,125.51 v1(46.4,126.66)
  BOTTOM w0.152: v1(46.4,126.66) U45.12
SOC_UART1_CTS_V1P8: length 132.1
  TOP w0.152: U23.T31 v4(63.18,49.36)
  L5_SIG2 w0.107: v1(52.43,126.66) 53.92,128.15 53.92,131.36 55.03,132.46 62.71,132.46 70.23,124.94 74.68,124.94 76.33,123.29 76.33,121.21 74.19,119.08 74.19,108.91 72.64,107.36 72.64,103.68 73.41,102.91 73.41,95.73 76.33,92.8 76.33,92.29 76.87,91.76 79.48,89.15 79.48,87.83 86.51,80.8 86.51,60.09 76.18,49.76 63.58,49.76 v4(63.18,49.36)
  BOTTOM w0.152: v1(52.43,126.66) U45.9
SOC_UART1_RTS_3V3: length 8.4
  TOP w0.152: CN7.97 43.39,126.99 v1(43.43,126.95)
  L8_SIG3 w0.107: v1(43.43,126.95) 43.43,126.47 43.92,125.98 44.7,125.98 45.59,126.87 45.59,127.3 v1(45.58,127.31)
  BOTTOM w0.152: v1(45.58,127.31) U45.13
SOC_UART1_RTS_V1P8: length 183.3
  TOP w0.152: R235.1 77.6,35.47 77.67,35.39 v1(77.67,34.82)
  L3_SIG1 w0.102: v1(77.67,34.82) 77.57,34.72 77.57,33.48 79.45,31.6 86.5,31.6 89.6,34.7 94.28,34.7 94.66,35.08 102.06,35.08 102.98,36 105.09,36 106.89,37.8 109.12,37.8 119.13,47.81 119.13,82.48 105.24,96.37 90.14,96.37 88.59,97.92 83.47,97.92 79.14,102.25 78.11,103.28 74.67,103.28 71.17,106.78 71.17,119.25 61.34,129.08 53.01,129.08 51.61,127.68 v1(51.61,127.31)
  BOTTOM w0.152: v1(51.61,127.31) U45.8
SOC_UART1_RX_3V3: length 8.6
  TOP w0.152: CN7.93 42.8,125.99 v1(42.86,125.93)
  L8_SIG3 w0.107: v1(45.58,128.61) 44.55,128.61 42.82,126.88 42.82,125.97 v1(42.86,125.93)
  BOTTOM w0.152: v1(45.58,128.61) U45.15
SOC_UART1_RXD_V1P8: length 119.6
  TOP w0.152: U23.U29 v4(62.38,50.96)
  L5_SIG2 w0.107: v4(62.38,50.96) 62.81,51.39 62.81,52.71 63.08,52.98 78.44,52.98 85.82,60.37 85.82,80.51 77.39,88.94 77.39,89.59 72.72,94.26 72.72,102.63 70.95,104.4 70.95,116.92 72.57,118.53 72.57,123.42 71.79,124.19 60.14,124.19 55.63,128.7 v1(54.97,128.7)
  BOTTOM w0.152: v1(54.97,128.7) 54.87,128.61 U45.6
SOC_UART1_TX_3V3: length 7.5
  TOP w0.152: CN7.95 v1(44.15,126.49)
  L8_SIG3 w0.107: v1(46.4,127.96) 45.61,127.96 v1(44.15,126.49)
  BOTTOM w0.152: v1(46.4,127.96) U45.14
SOC_UART1_TXD_V1P8: length 178.2
  TOP w0.152: R234.1 v1(78.99,34.82)
  L3_SIG1 w0.102: v1(78.99,34.82) 78.43,34.82 77.89,34.28 77.89,33.49 78.11,33.27 78.11,33.26 79.54,31.83 86.41,31.83 90.24,35.66 95.32,35.66 95.63,35.36 97.47,35.36 98.79,36.68 100.39,36.68 100.95,36.12 102.58,36.12 103.43,36.97 105.74,36.97 106.8,38.03 109.03,38.03 117.91,46.91 117.91,83.37 105.14,96.14 90.04,96.14 88.5,97.68 83.38,97.68 78.71,102.35 78.02,103.05 74.58,103.05 70.94,106.68 70.94,116.31 59.3,127.96 v1(52.43,127.96)
  BOTTOM w0.152: v1(52.43,127.96) U45.7
SOC_URX_3V3: length 5.9
  BOTTOM w0.152: U50.9 166.09,116.1 166.31,115.89 167.58,115.89 168.67,116.98 U52.1
SOC_VPPB_EN: length 91.2
  L5_SIG2 w0.107: v4(84.3,73.2) 84.3,80.04 76.31,88.02 75.69,88.02 73.99,89.72 72.24,89.72 69.37,92.59 69.37,101.56 66.32,104.61 66.32,107.77 67.86,109.31 67.86,115.68 60.05,123.49 54.88,123.49 50.17,128.2 50.17,136.98 51.21,138.01 v1(51.21,139.65)
  BOTTOM w0.152: U63.B2 84.3,70.5 R432.2 v4(84.3,73.2) ; v1(51.21,139.65) U39.24
SOC_XFI_MDIO: length 24.3
  TOP w0.152: R645.2 48.13,91.67 49.05,92.58 49.05,94.77 48.9,94.92 47.91,94.92 47.82,94.83 46.77,94.83 v2(46.74,94.79) 44.6,94.79 43.85,94.04 R627.1
  L10_SIG4 w0.107: v1(42.44,85.83) 42.42,85.85 42.42,92.96 44.25,94.79 v2(46.74,94.79)
  BOTTOM w0.152: v2(46.74,94.79) 46.71,94.77 46.39,95.09 U58.4 ; v1(42.44,85.83) 42.29,85.67 R632.2
SOC_XFI_RX_DN0: length 75.7
  TOP w0.102: C119.2 42.37,67.8 arc(42.38,67.78) 42.39,67.76 42.39,67.2 arc(42.38,67.18) 42.38,67.16 arc(42.36,67.13) 42.34,67.1 arc(42.11,66.95) 41.84,66.9 41.29,66.9 arc(41.11,66.86) 40.96,66.76 arc(40.16,66.28) 39.24,66.12 38.46,66.12 arc(38.2,66.17) 37.97,66.32 arc(37.92,66.4) 37.9,66.5 37.9,66.76 arc(37.98,66.95) 38.18,67.04 38.74,67.04 arc(38.97,66.99) v1(39.17,66.86)
  BOTTOM w0.102: J2.D2 14.31,114.1 arc(14.27,114.11) 14.23,114.14 14.17,114.19 arc(14.13,114.25) 14.09,114.31 14.03,114.47 arc(14.01,114.54) 14,114.61 14,114.8 arc(14.11,115.06) 14.38,115.17 26.13,115.17 arc(26.81,115.04) 27.38,114.66 27.48,114.56 arc(27.65,114.3) 27.71,113.99 27.71,90.93 arc(27.81,90.42) 28.1,90 34.55,83.54 arc(34.86,83.08) 34.96,82.54 34.96,69.78 arc(35.05,69.36) 35.28,69.01 36.99,67.3 arc(37.29,67.1) 37.63,67.03 38.75,67.03 arc(38.98,66.99) v1(39.17,66.86)
SOC_XFI_RX_DN0_R: length 7.1
  TOP w0.102: U23.AN11 48.98,65.57 arc(48.89,65.51) 48.79,65.49 47.2,65.49 arc(45.66,65.79) 44.36,66.66 44.17,66.85 44.01,67.02 arc(43.75,67.19) 43.45,67.25 43.4,67.25 arc(43.35,67.26) 43.31,67.28 43.29,67.31 43.25,67.39 C119.1
SOC_XFI_RX_DN1: length 76
  TOP w0.102: C116.2 40.32,69.02 arc(40.3,68.94) 40.25,68.87 40.2,68.81 arc(40.14,68.76) 40.08,68.73 39.93,68.67 arc(39.84,68.64) 39.74,68.63 36.7,68.63 arc(36.52,68.71) 36.45,68.88 36.45,70.07 arc(36.46,70.15) 36.51,70.21 36.81,70.51 arc(36.89,70.57) 36.99,70.59 37.49,70.59 arc(37.49,70.59) 37.49,70.59 arc(37.73,70.54) v1(37.92,70.41)
  BOTTOM w0.102: J2.D4 14.53,119.1 arc(14.38,119.13) 14.25,119.22 13.97,119.5 arc(13.86,119.67) 13.82,119.86 arc(13.91,120.08) 14.13,120.17 25.7,120.17 arc(26,120.11) 26.26,119.94 29.83,116.37 arc(29.93,116.21) 29.97,116.03 29.97,92.19 arc(30.14,91.35) 30.62,90.64 36.68,84.58 arc(37.06,84) 37.2,83.32 37.2,71 arc(37.23,70.86) 37.31,70.74 37.42,70.62 37.43,70.61 arc(37.52,70.56) 37.62,70.54 37.8,70.54 arc(37.89,70.5) v1(37.92,70.41)
SOC_XFI_RX_DN1_R: length 9.9
  TOP w0.102: C116.1 41.46,69.35 arc(41.73,69.18) 42.04,69.11 42.67,69.11 arc(43.87,68.88) 44.88,68.2 45.11,67.97 45.55,67.53 arc(46.47,66.92) 47.55,66.7 48.04,66.7 arc(48.17,66.72) 48.28,66.78 48.35,66.84 arc(48.45,66.91) 48.57,66.94 arc(48.62,66.94) 48.67,66.95 49.48,66.95 arc(49.67,66.91) 49.84,66.8 49.9,66.73 arc(49.96,66.65) U23.AM10
SOC_XFI_RX_DP0: length 75.8
  TOP w0.102: C123.2 42.27,66.5 arc(42.14,66.6) 41.98,66.64 41.31,66.64 arc(41.21,66.63) 41.13,66.57 arc(40.25,66.04) 39.24,65.86 38.46,65.86 arc(38.1,65.93) 37.79,66.14 37.72,66.22 arc(37.66,66.3) 37.64,66.4 37.64,66.76 arc(37.8,67.13) 38.18,67.29 38.74,67.29 arc(38.97,67.34) v1(39.17,67.47)
  BOTTOM w0.102: J2.C2 13.52,114.12 arc(13.69,114.37) 13.74,114.66 arc(13.74,114.68) 13.74,114.69 13.74,114.8 arc(13.93,115.24) 14.38,115.43 26.13,115.43 arc(26.9,115.27) 27.56,114.84 27.66,114.74 arc(27.88,114.4) 27.97,113.99 27.97,90.98 arc(28.06,90.52) 28.31,90.14 34.77,83.69 arc(35.1,83.19) 35.22,82.6 35.22,69.83 arc(35.29,69.46) 35.5,69.15 37.11,67.54 arc(37.39,67.35) 37.72,67.29 38.74,67.29 arc(38.97,67.33) v1(39.17,67.47)
SOC_XFI_RX_DP0_R: length 7
  TOP w0.102: U23.AN12 48.98,65.15 arc(48.89,65.21) 48.79,65.23 47.2,65.23 arc(45.57,65.56) 44.18,66.48 43.99,66.67 43.83,66.84 arc(43.65,66.95) 43.45,66.99 43.42,66.99 arc(43.37,66.98) 43.33,66.96 43.29,66.91 43.25,66.82 C123.1
SOC_XFI_RX_DP1: length 76
  TOP w0.102: v1(37.92,71.02) arc(37.73,70.89) 37.49,70.84 36.99,70.84 arc(36.8,70.8) 36.63,70.69 36.33,70.39 arc(36.23,70.24) 36.2,70.07 36.2,68.88 arc(36.34,68.53) 36.7,68.38 39.89,68.38 arc(39.98,68.37) 40.08,68.35 arc(40.21,68.29) C118.2
  BOTTOM w0.102: v1(37.92,71.02) 37.79,70.89 arc(37.72,70.84) 37.63,70.82 arc(37.58,70.83) 37.55,70.86 arc(37.48,70.96) 37.45,71.08 37.45,83.35 arc(37.3,84.1) 36.88,84.73 30.82,90.79 arc(30.38,91.45) 30.23,92.23 30.23,116.03 arc(30.17,116.31) 30.01,116.55 26.44,120.12 arc(26.1,120.35) 25.7,120.43 14.07,120.43 arc(13.71,120.28) 13.56,119.92 13.56,119.25 arc(13.55,119.17) J2.C4
SOC_XFI_RX_DP1_R: length 9.9
  TOP w0.102: C118.1 41.55,68.53 arc(41.91,68.77) 42.34,68.86 42.67,68.86 arc(43.77,68.64) 44.7,68.02 45.37,67.35 arc(46.37,66.68) 47.55,66.45 47.88,66.45 arc(47.94,66.44) 47.99,66.42 arc(48.09,66.34) 48.2,66.27 arc(48.42,66.18) 48.66,66.15 49.37,66.15 arc(49.56,66.11) 49.73,66 49.97,65.76 U23.AM11
SOC_XFI_TX_DN0: length 79.6
  TOP w0.102: U23.AL12 v4(50.38,65.36)
  BOTTOM w0.102: v4(50.38,65.36) 50.38,65.5 arc(50.37,65.54) 50.34,65.59 arc(50.3,65.61) 50.25,65.62 49.92,65.62 arc(49.79,65.67) 49.68,65.76 49.6,65.83 arc(49.5,65.91) 49.37,65.93 47.78,65.93 arc(47.64,65.96) 47.52,66.04 47.25,66.3 arc(46.94,66.51) 46.58,66.59 41.39,66.59 arc(40.88,66.48) 40.44,66.19 40.06,65.81 arc(39.58,65.49) 39.02,65.38 37.62,65.38 arc(36.93,65.52) 36.34,65.91 34.25,68 arc(33.95,68.45) 33.85,68.97 33.85,82.16 arc(33.75,82.63) 33.49,83.02 27.08,89.43 arc(26.7,90) 26.57,90.66 26.57,111.79 arc(26.31,112.41) 25.68,112.67 14.53,112.67 arc(14.32,112.59) 14.23,112.37 14.23,111.73 arc(14.24,111.68) 14.26,111.64 14.27,111.64 arc(14.31,111.61) 14.36,111.6 J2.D1
SOC_XFI_TX_DN1: length 82.1
  TOP w0.102: U23.AK11 v4(51.18,66.16)
  BOTTOM w0.102: J2.D3 14.37,116.93 arc(14.26,117.09) 14.23,117.27 14.23,117.37 arc(14.32,117.59) 14.53,117.67 26.47,117.67 arc(26.56,117.66) 26.64,117.6 28.65,115.6 arc(28.78,115.4) 28.83,115.16 28.83,91.63 arc(28.97,90.9) 29.38,90.29 35.53,84.14 arc(35.94,83.53) 36.08,82.81 36.08,70.45 arc(36.13,70.19) 36.28,69.96 37.4,68.85 arc(37.61,68.71) 37.85,68.66 46.53,68.66 arc(47.04,68.56) 47.47,68.27 48.26,67.48 arc(48.96,67) 49.78,66.79 49.78,66.78 arc(49.94,66.76) 50.09,66.68 arc(50.19,66.61) 50.31,66.59 51,66.59 arc(51.08,66.58) 51.15,66.56 51.22,66.53 arc(51.27,66.46) 51.29,66.37 51.29,66.24 51.24,66.19 arc(51.21,66.17) v4(51.18,66.16)
SOC_XFI_TX_DP0: length 79.6
  TOP w0.102: U23.AL11 v4(50.38,66.16)
  BOTTOM w0.102: v4(50.38,66.16) 50.21,65.99 arc(50.09,65.91) 49.96,65.89 arc(49.91,65.9) 49.86,65.94 49.78,66.01 arc(49.6,66.14) 49.37,66.18 47.83,66.18 arc(47.74,66.2) 47.67,66.25 47.52,66.4 47.36,66.56 arc(47.05,66.77) 46.68,66.84 41.16,66.84 arc(40.76,66.76) 40.42,66.54 39.9,66.01 arc(39.48,65.73) 38.98,65.63 37.69,65.63 arc(37.03,65.76) 36.47,66.14 34.5,68.11 arc(34.2,68.55) 34.1,69.08 34.1,82.18 arc(33.99,82.73) 33.68,83.19 27.26,89.61 arc(26.94,90.09) 26.82,90.66 26.82,111.79 arc(26.49,112.59) 25.68,112.93 14.53,112.93 arc(14.14,112.77) 13.97,112.37 arc(13.92,112.1) 13.76,111.86 J2.C1
SOC_XFI_TX_DP1: length 82.2
  TOP w0.102: U23.AK10 v4(51.18,66.96)
  BOTTOM w0.102: J2.C3 13.83,116.93 arc(13.94,117.09) 13.97,117.27 13.97,117.37 arc(14.14,117.77) 14.53,117.93 26.47,117.93 arc(26.66,117.89) 26.82,117.78 28.83,115.78 arc(29.02,115.5) 29.08,115.16 29.08,91.7 arc(29.22,91.01) 29.61,90.42 35.73,84.3 arc(36.18,83.62) 36.33,82.81 36.33,70.51 arc(36.38,70.29) 36.5,70.11 37.57,69.04 arc(37.7,68.95) 37.87,68.92 46.53,68.92 arc(47.14,68.8) 47.65,68.45 48.44,67.66 arc(49.06,67.23) 49.79,67.04 arc(49.87,67.05) 49.94,67.08 arc(49.95,67.08) 49.95,67.08 50.1,67.23 arc(50.21,67.31) 50.34,67.33 50.57,67.33 arc(50.79,67.29) 50.97,67.16 v4(51.18,66.96)
SOC_XFIMDC: length 16.9
  TOP w0.152: R644.2 43.33,88.84 43.08,88.59 v1(43.08,88.32)
  L3_SIG1 w0.102: v1(43.08,88.32) 42.77,88.32 40.79,86.33 v1(40.79,85.83)
  BOTTOM w0.127: v1(43.08,88.32) 43.39,88.01 U80.16
  BOTTOM w0.152: U80.15 U80.16 ; R629.2 38.92,77.45 39.67,78.21 39.67,84.71 v1(40.79,85.83)
SPARE0: length 2.5
  TOP w0.152: U9.20 TP20.1
SPARE1: length 2.7
  TOP w0.152: U9.19 108.38,110.06 108.03,110.41 TP18.1
SPI0_CLK: length 86.5
  TOP w0.152: v1(145.82,48.59) 147.88,50.65 NOR1.16
  L3_SIG1 w0.102: v1(145.82,48.59) 145.52,48.29 128.68,48.29 124.5,44.1 119.19,44.1 115.92,40.83 115.92,33.65 112.03,29.76 92.62,29.76 91.36,28.49 89.76,28.49 89.58,28.67 89.58,29.74 90.4,30.56 v1(90.4,31.04)
  BOTTOM w0.152: R540.2 81.05,33.59 82.61,32.03 83.1,31.54 83.6,31.04 v1(90.4,31.04)
SPI0_CS0: length 85.8
  TOP w0.127: 138.02,44.04 138.02,43.92 138.91,43.03 NOR1.7
  TOP w0.152: v1(127.38,45.64) 129.39,47.65 136.13,47.65 137.11,46.67 137.11,46.38 138.02,45.46 138.02,44.04
  L3_SIG1 w0.102: v1(127.38,45.64) 125.34,43.61 119.34,43.61 116.37,40.64 116.37,33.46 112.22,29.3 94.35,29.3 92.9,27.86 87.77,27.86 87.04,28.59 87.04,30.26 88.2,31.42 90.32,31.42 v1(91.06,32.16)
  BOTTOM w0.152: v1(91.06,32.16) 90.84,32.16 90.02,31.34 84.39,31.34 83.13,32.6 83.13,34.12 82.91,34.35 R539.2
SPI0_DIN: length 104.8
  TOP w0.127: 129.24,43.73 129.57,43.41 135.56,43.41 135.84,43.69 R447.2 ; v4(66.38,49.36) 66.38,49.13 66.38,47.32
  TOP w0.152: U23.M31 v4(66.38,49.36) ; v1(89.43,31.8) 88.85,32.38 81.94,32.38 80.98,33.35 80.98,37.21 80.37,37.82 78.31,37.82 74.6,41.53 74.6,43.66 73.85,44.41 67.69,44.41 66.38,45.73 66.38,47.32 ; R443.2 136.27,44.76 136.2,44.69 R447.2 ; v1(128.22,44.75) 129.24,43.73
  L3_SIG1 w0.102: v1(89.43,31.8) 88.27,31.8 86.82,30.35 86.82,28.5 87.68,27.64 93,27.64 94.44,29.08 112.31,29.08 116.6,33.37 116.6,40.55 119.43,43.38 125.93,43.38 127.3,44.75 v1(128.22,44.75)
SPI0_DOUT: length 88.8
  TOP w0.152: v1(146.81,48.11) 146.81,48.64 147.55,49.38 NOR1.15
  L3_SIG1 w0.102: 143.59,48.06 143.59,48.06 146.77,48.06 v1(146.81,48.11)
  L3_SIG1 w0.107: 143.59,48.06 128.78,48.06 124.59,43.87 119.28,43.87 116.15,40.73 116.15,33.56 112.12,29.53 92.72,29.53 91.45,28.27 89.66,28.27 89.36,28.57 89.36,30.18 v1(89.61,30.43)
  BOTTOM w0.152: v1(89.61,30.43) 89.33,30.71 83.5,30.71 80.49,33.72 80.49,36.46 R525.2
SPI1_CLK: length 17
  TOP w0.152: R105.2 v1(156.41,108.92) ; U5.6 v1(153.16,117.6)
  L5_SIG2 w0.107: v1(156.41,108.92) 156.69,108.64 157.89,108.64 158.11,108.86 158.11,109.17 157.32,109.96 156.21,109.96 153.85,112.32 153.85,113.67 153.92,113.75 153.92,116.84 v1(153.16,117.6)
  BOTTOM w0.152: R352.1 152.65,117.09 v1(153.16,117.6)
SPI1_SCS[0]: length 18.2
  TOP w0.127: U15.E19 v1(153.02,107.28)
  TOP w0.152: U5.1 v1(147.88,120.14)
  L5_SIG2 w0.107: v1(147.88,120.14) 151.36,116.66 151.36,113.82 152.64,112.54 152.64,107.67 v1(153.02,107.28)
  BOTTOM w0.152: R342.1 146.88,120.14 v1(147.88,120.14)
SPI1_SIMO: length 16.6
  TOP w0.127: U15.G17 v1(151.42,105.68)
  TOP w0.152: U5.5 v1(153.42,116.33)
  L5_SIG2 w0.107: v1(153.42,116.33) 153.16,116.08 153.16,114.02 153.4,113.79 153.4,106.33 152.76,105.68 v1(151.42,105.68)
  BOTTOM w0.152: v1(153.42,116.33) 153.42,116.08 153.03,115.7 R355.1
SPI1_SOMI: length 18.8
  TOP w0.127: U15.H17 v1(151.42,104.88)
  TOP w0.152: U5.2 v1(147.83,118.87)
  L5_SIG2 w0.107: v1(147.83,118.87) 147.83,118.87 147.83,116.39 148.6,115.62 148.83,115.62 149.8,114.64 149.8,114.2 151.16,112.84 151.16,110.31 151.04,110.19 151.04,105.27 v1(151.42,104.88)
  BOTTOM w0.152: R345.1 v1(147.83,118.87)
SPI1_WPN: length 16.7
  TOP w0.127: U15.F18 v1(152.22,106.48)
  TOP w0.152: U5.3 v1(148.21,117.6)
  L5_SIG2 w0.107: v1(152.22,106.48) 151.8,106.9 151.8,108.63 151.55,108.87 151.55,112.99 150.9,113.64 150.9,115 148.3,117.6 v1(148.21,117.6)
  BOTTOM w0.152: R348.1 v1(148.21,117.6)
SPI_GPIO_INT0: length 6.6
  TOP w0.152: v1(145.97,134.67) 145.98,134.66 U1.58
  L5_SIG2 w0.102: v1(145.97,130.66) v1(145.97,134.67)
  BOTTOM w0.152: U41.20 145.75,131.19 145.97,130.96 v1(145.97,130.66)
SPI_GPIO_INT0_1V8: length 77.3
  BOTTOM w0.152: U44.20 74.76,125.55 76.11,124.2 78.56,124.2 79.37,125.01 90.3,125.01 98.55,133.27 103.07,133.27 104.06,134.26 104.06,136.96 105.52,138.42 121.94,138.42 130.25,130.1 134.94,130.1 136.02,131.19 U41.1
SPI_GPIO_INT1: length 4.6
  TOP w0.152: U1.46 v1(143.19,130.56)
  BOTTOM w0.152: U41.18 143.54,132.49 143.19,132.14 v1(143.19,130.56)
SPI_GPIO_INT1_1V8: length 98.8
  L3_SIG1 w0.102: v1(48.61,139.09) 49.96,140.44 56.76,140.44 60.4,136.8 70.72,136.8 71.49,137.57 74.52,137.57 75.86,136.23 81.03,136.23 84.45,132.82 90.75,132.82 91.31,133.38 107.5,133.38 108.36,132.51 109.17,132.51 109.22,132.56 111.4,132.56 111.84,132.99 114.71,132.99 115.78,134.06 127.61,134.06 127.86,133.81 131.32,133.81 132.21,132.92 132.99,132.92 133.2,132.72 135.25,132.72 135.71,133.17 136.99,133.17 v1(137.67,132.49)
  BOTTOM w0.152: v1(48.61,139.09) U39.20 ; U41.3 v1(137.67,132.49)
SPI_GPIO_INT2: length 6.4
  TOP w0.152: v1(143.64,133.14) 142.71,133.14 141.69,132.12 U1.43
  BOTTOM w0.152: U41.17 v1(143.64,133.14)
SPI_GPIO_INT2_1V8: length 70
  L10_SIG4 w0.107: v1(140.67,134.52) 140.67,135.76 137.84,138.59 134.35,138.59 133.83,138.07 130.5,138.07 130.21,137.78 123.15,137.78 122.68,137.31 100.76,137.31 91.45,128 87.93,128 87.61,128.32 84.6,128.32 v1(83.31,129.61)
  BOTTOM w0.152: U43.20 v1(83.31,129.61) ; U41.4 140.36,133.14 140.67,133.44 v1(140.67,134.52)
SPI_GPIO_INT3: length 75.8
  TOP w0.152: U1.42 141.19,128.08 141.18,128.07 v1(141.18,128.07) ; U8.20 v1(79.97,112.69)
  L3_SIG1 w0.102: v1(79.97,112.69) 79.97,117 84.68,121.72 86.9,121.72 89.76,124.58 99.7,124.58 102.23,122.05 104.48,122.05 106.84,124.41 112.04,124.41 112.88,125.25 124.01,125.25 124.76,126.01 126.59,126.01 126.85,126.26 131.04,126.26 132.06,125.24 138.23,125.24 140.22,127.23 140.22,127.68 140.61,128.07 v1(141.18,128.07)
SPI_GPIO_RESET: length 89.2
  TOP w0.152: v1(76.6,111.39) 77.74,111.39 77.75,111.39 U8.18 ; v1(138.69,127.59) U1.37
  L3_SIG1 w0.102: v1(76.6,111.39) 78.38,113.18 78.38,116.94 89.15,127.7 100.53,127.7 101.36,126.87 109.99,126.87 110.95,127.83 118.19,127.83 119.29,128.93 127.61,128.93 128.73,127.81 130.76,127.81 131.31,127.25 138.36,127.25 v1(138.69,127.59)
  L5_SIG2 w0.107: v1(138.69,127.59) 138.69,130.33 138.68,130.34 138.68,131.27 141.76,134.34 142.98,134.34 143.64,135 v1(143.64,135.74)
  BOTTOM w0.152: U41.13 v1(143.64,135.74)
SPI_GPIO_RESET_1V8: length 115.3
  L3_SIG1 w0.102: v1(76.06,128.8) 64.03,128.8 56.36,136.47 47.72,136.47 47.4,136.15 47.4,135.77 46.81,135.18 45.31,135.18 44.88,135.61 44.88,136.42 47.31,138.85 v1(47.31,139.32)
  L8_SIG3 w0.107: v1(79.92,128.31) 76.56,128.31 v1(76.06,128.8)
  L10_SIG4 w0.107: v1(140.08,135.74) 138.54,137.27 132.96,137.27 132.62,136.93 129.69,136.93 129.54,137.08 100.86,137.08 91.54,127.77 87.71,127.77 87.38,128.09 80.13,128.09 v1(79.92,128.31)
  BOTTOM w0.152: U41.8 v1(140.08,135.74) ; v1(79.92,128.31) U43.18 ; v1(47.31,139.32) U39.18 ; U44.18 v1(76.06,128.8)
SPI_HOLDN: length 2.7
  TOP w0.152: U5.7 v1(153.16,118.87)
  BOTTOM w0.152: v1(153.16,118.87) 152.22,118.87 R346.1
T_TDIS: length 3.6
  TOP w0.152: TP15.1 v1(108.2,111.76)
  BOTTOM w0.152: R370.2 R367.2 v1(108.2,111.76)
TCLKA_TSIP0CLKA_N: length 24.1
  TOP w0.102: AMC1.75 4.84,60.75 5.09,60.5 11.25,60.5 13.26,58.5 13.26,51.26 14,50.52 14.99,50.52 v1(15.21,50.75)
  BOTTOM w0.102: v1(15.21,50.75) 15.43,50.53 15.93,50.53 16.24,50.84 R486.2 16.61,50.84 16.92,50.53 17.45,50.53 17.64,50.72 U70.3
TCLKA_TSIP0CLKA_P: length 24.1
  TOP w0.102: v1(15.21,50.04) 14.99,50.27 13.89,50.27 13,51.15 13,58.39 11.15,60.25 5.09,60.25 4.84,60 AMC1.74
  BOTTOM w0.102: U70.2 17.64,50.07 17.45,50.25 16.88,50.25 16.57,49.94 R486.1 16.24,49.94 15.93,50.25 15.43,50.25 v1(15.21,50.04)
TCLKB_25MHZ_N: length 113.4
  TOP w0.102: AMC1.78 4.84,63 5.09,62.75 5.75,62.75 5.93,62.94 6.16,62.94 6.35,62.75 6.58,62.75 6.77,62.94 7,62.94 7.19,62.75 7.41,62.75 7.6,62.94 7.83,62.94 8.02,62.75 8.25,62.75 8.44,62.94 8.67,62.94 8.85,62.75 9.08,62.75 9.27,62.94 9.5,62.94 9.69,62.75 10.02,62.75 v1(10.23,62.95) ; C56.1 77.25,93.61 77.12,93.74 76.69,93.74 v1(76.39,93.44)
  L8_SIG3 w0.102: v1(76.39,93.44) 76.68,93.73 77.04,93.73 77.11,93.65 77.11,93.1 76.86,92.85 76.12,92.85 74.48,94.49 70.38,94.49 69.76,95.11 69.76,97.17 68.02,98.91 61.8,98.91 61.37,98.47 61.37,95.58 61.02,95.24 60.38,95.24 55.86,90.72 55.86,85.73 54.25,84.12 54.25,83.55 52.26,81.56 49.63,81.56 48.68,82.51 47.72,82.51 47.35,82.89 47.35,86.25 46.86,86.74 40.61,86.74 39.93,86.06 39.93,84 39.31,83.39 37.77,83.39 35.26,80.87 35.26,73.32 32.87,70.93 24.97,70.93 18.31,64.27 13.11,64.27 12.77,63.92 12.67,63.92 12.57,63.92 12.4,63.76 12.4,63.66 12.4,63.56 12.24,63.4 12.14,63.4 12.14,63.4 12.04,63.4 11.88,63.24 11.88,63.14 11.88,63.03 11.7,62.86 10.32,62.86 v1(10.23,62.95)
TCLKB_25MHZ_P: length 113.4
  TOP w0.102: v1(10.23,62.27) 10,62.5 5.09,62.5 4.84,62.25 AMC1.77 ; C53.1 77.25,94.09 77.15,93.99 76.66,93.99 v1(76.39,94.27)
  L8_SIG3 w0.102: v1(10.23,62.27) 10.52,62.56 11.82,62.56 13.23,63.97 18.43,63.97 25.1,70.64 32.99,70.64 35.55,73.2 35.55,80.75 37.9,83.09 39.43,83.09 40.22,83.88 40.22,85.93 40.74,86.45 46.74,86.45 47.05,86.13 47.05,82.77 47.6,82.22 48.56,82.22 49.51,81.27 52.38,81.27 54.54,83.43 54.54,84 56.16,85.61 56.16,90.6 60.5,94.95 61.15,94.95 61.66,95.46 61.66,98.35 61.93,98.62 67.9,98.62 69.47,97.05 69.47,94.99 70.26,94.2 74.36,94.2 76,92.56 76.98,92.56 77.41,92.98 77.41,93.77 77.16,94.02 76.64,94.02 v1(76.39,94.27)
TCLKC_FS_N: length 25.7
  BOTTOM w0.102: U72.3 17.97,44.14 17.78,43.95 16.6,43.95 16.29,44.27 R501.2 15.95,44.27 15.63,43.94 15.12,43.94 13.79,42.61 13.79,34.75 10.29,31.25 5.09,31.25 4.84,31.5 AMC1.135
TCLKC_FS_P: length 25.7
  BOTTOM w0.102: U72.2 18,43.49 17.81,43.68 16.6,43.68 16.29,43.36 R501.1 15.98,43.36 15.65,43.69 15.23,43.69 14.05,42.51 14.05,34.65 10.4,31 5.09,31 4.84,30.75 AMC1.136
TCLKD_N_C: length 4.8
  TOP w0.102: R171.1 C56.2 78.15,93.59 78.31,93.75 80.14,93.75 80.27,93.62 U17.9
TCLKD_P_C: length 4.8
  TOP w0.102: R160.1 C53.2 78.15,94.14 78.28,94.01 80.13,94.01 80.24,94.12 U17.8
TDIS: length 3.2
  TOP w0.152: EMU1.15 91.47,120.47 91.26,120.68 R68.2
TPS65000_PG#: length 25.4
  TOP w0.152: R195.1 v2(140.08,81.15) 140.33,80.9 U20.3
  BOTTOM w0.152: U59.2 154.56,92.05 154.31,92.3 153.11,92.3 152.58,91.77 152.58,87.96 149.2,84.58 143.51,84.58 v2(140.08,81.15)
TRGRSTZ: length 78.1
  TOP w0.152: R117.2 119.99,102.55 120.09,102.65 v1(120.09,103) ; v1(102.42,123.57) R64.1 101.85,122.56 101.44,122.97 EMU1.6 ; v1(139.69,127.66) U1.39
  L3_SIG1 w0.102: v1(102.42,123.57) 104.13,123.57 106.52,125.96 110.94,125.96 111.58,126.6 117.61,126.6 118.18,127.17 120.54,127.17 121.84,128.47 127.44,128.47 128.54,127.36 130.57,127.36 131.86,126.08 135.76,126.08 136.41,126.73 138.28,126.73 138.77,127.21 139.24,127.21 v1(139.69,127.66)
  BOTTOM w0.152: v1(102.42,123.57) 106.75,123.57 108.21,122.11 108.21,121.86 110.58,119.49 110.58,116.34 113.64,113.28 113.64,109.45 v1(120.09,103)
TRIP2:
  vias: v2(34.44,146.02) v2(34.44,144.63) v2(35.59,146.02) v2(35.59,144.63)
TRIP3: length 132.5
  TOP w0.381: v6(150.11,145.87) 150.93,145.87 R1.2
  L5_SIG2 w0.381: v6(150.11,145.87) 148.72,147.27 23.65,147.27 v3(22.63,146.25)
  BOTTOM w0.381: v3(22.63,146.25) 21.83,146.25 21.5,146.58 ESD1.3
TSCOMPOUT_E: length 90.3
  TOP w0.152: U23.AF4 v4(54.38,71.76) ; v1(43.05,130.99) CN7.113 38.86,130.99 38.36,131.49 CN7.116
  L3_SIG1 w0.102: v4(54.38,71.76) 53.98,72.16 53.98,74.49 54.04,74.55 54.04,82.56 53.04,83.56 53.04,85.8 53.68,86.43 53.68,96.18 50.11,99.75 45.21,99.75 45.21,99.75 45.2,99.75 43.14,101.8 36.82,101.8 36.36,102.27 36.36,116.97 37.42,118.03 37.42,120.71 38.02,121.31 38.02,122.73 38.21,122.92 38.21,125.32 39.43,126.54 43.65,126.54 43.99,126.87 44.63,126.87 45.05,127.29 45.05,129.64 43.7,130.99 v1(43.05,130.99)
TSIP0_CLKA: length 27.1
  TOP w0.152: U23.AK31 v4(51.18,49.36)
  L3_SIG1 w0.102: v4(51.18,49.36) 51.18,49.48 50.74,49.92 50.74,50.31 50.5,50.56 50.12,50.56 49.52,51.16 41.66,51.16 39.74,49.24 27.67,49.24 v1(27.37,49.54)
  BOTTOM w0.152: R487.1 v1(27.37,49.54)
TSIP0_CLKB: length 30.8
  TOP w0.152: U23.AK33 v4(51.18,47.76)
  L3_SIG1 w0.107: v4(51.18,47.76) 50.77,48.16 50.77,48.79 50.57,48.99 50.22,48.99 49.99,49.23 49.99,50.27 49.73,50.53 41.41,50.53 39.84,48.96 27.19,48.96 26.57,49.58 26.57,50.29 v1(27.37,51.1)
  BOTTOM w0.152: R483.1 v1(27.37,51.1)
TSIP0_FSA: length 28.8
  TOP w0.152: U23.AJ31 v4(51.98,49.36)
  L3_SIG1 w0.102: v2(28.5,43.97) 40.08,43.97 42.54,46.43 51.64,46.43 52.38,47.17 52.38,48.96 v4(51.98,49.36)
  BOTTOM w0.152: R499.1 27.91,43.97 v2(28.5,43.97)
TSIP0_FSB: length 27.3
  TOP w0.152: U23.AK32 v4(51.18,48.56)
  L3_SIG1 w0.102: v2(28.6,45.47) 29.82,44.25 39.83,44.25 42.25,46.66 50.65,46.66 51.58,47.59 51.58,48.16 v4(51.18,48.56)
  BOTTOM w0.152: R495.1 v2(28.6,45.47)
TSIP0_RX0_TX1: length 12.9
  L3_SIG1 w0.102: v2(13.84,49.53) 13.84,56.06 15.44,57.65 16.91,57.65 v1(17.25,57.31)
  BOTTOM w0.152: v1(17.25,57.31) 17.25,57.31 U68.13 ; R489.2 v2(13.84,49.53)
TSIP0_RX1_TX0: length 13.5
  L3_SIG1 w0.102: v2(13.84,46.74) 13.84,48.23 14.45,48.84 14.45,53.37 17.16,56.07 v1(17.16,56.66)
  BOTTOM w0.152: U68.12 v1(17.16,56.66) ; R492.2 v2(13.84,46.74)
TSIP0_TX0_RX1: length 10
  BOTTOM w0.152: R485.2 13.15,54.98 14.17,56.01 U68.11
TSIP0_TX1_RX0: length 12
  BOTTOM w0.152: U68.10 15.07,55.36 14.33,54.61 14.33,48.64 13.82,48.13 R490.2
TSPUSHEVT0_E: length 74.7
  TOP w0.152: CN7.109 39.32,129.99 39.29,130.02 v1(39.24,130.02) ; U23.AG3 v4(53.58,72.56)
  L3_SIG1 w0.102: v4(53.58,72.56) 53.3,72.56 52.93,72.93 52.91,72.93 52.88,72.96 50.26,72.96 50.01,73.21 50.01,77.21 49.49,77.73 48.46,78.76 48.46,83.67 48.3,83.84 48.3,90.4 47.35,91.35 47.35,93.19 47.04,93.5 46.13,93.5 42.67,96.95 37.03,96.95 34.85,99.13 34.85,125.24 39.24,129.63 v1(39.24,130.02)
TSPUSHEVT1_E: length 71.1
  TOP w0.152: CN7.111 38.73,130.49 v1(38.73,130.49) ; U23.AL1 v4(50.38,74.16)
  L10_SIG4 w0.107: v1(38.73,130.49) 38.26,130.49 37.9,130.12 37.9,122.28 38.43,121.74 38.43,102.31 33.99,97.86 33.99,87.86 38.86,82.98 43.48,82.98 50.38,76.09 v4(50.38,74.16)
TSREFCLKN: length 65.5
  TOP w0.102: v4(52.8,83.08) 52.6,82.88 52.6,82.65 52.71,82.54 C83.1 ; U17.33 88.46,96.12 88.58,96 89.29,96 v1(89.47,96.17)
  L8_SIG3 w0.102: v1(89.47,96.17) 89.31,96.01 87.27,96.01 86.15,97.13 81.56,97.13 80.37,98.32 74.91,98.32 72.87,100.37 70.18,100.37 68.57,101.97 57,101.97 51.47,96.44 51.47,92.88 49.71,91.12 49.71,89.48 48.26,88.03 48.26,83.92 50.07,82.11 52.23,82.11 52.62,82.51 52.62,82.89 v4(52.8,83.08)
TSREFCLKN_R: length 10.4
  TOP w0.102: C83.2 52.8,81.64 52.64,81.48 52.64,81 53.31,80.33 53.31,79.81 53.47,79.66 53.47,79.43 53.31,79.28 53.31,79.05 53.47,78.9 53.47,78.67 53.31,78.52 53.31,78.21 53.02,77.91 53.02,77.81 53.02,77.71 52.86,77.55 52.76,77.55 52.76,77.55 52.66,77.55 52.5,77.39 52.5,77.29 52.5,77.18 52.33,77.02 52.23,77.02 52.23,77.02 52.13,77.02 51.97,76.86 51.97,76.76 51.97,76.66 51.81,76.5 51.71,76.5 51.6,76.5 51.44,76.33 51.44,75.71 51.61,75.54 51.61,75.31 51.44,75.14 51.44,74.91 51.61,74.74 51.61,74.51 51.44,74.34 51.44,73.89 U23.AK1
TSREFCLKP: length 65.5
  TOP w0.102: v1(89.47,95.56) 89.29,95.74 88.58,95.74 88.46,95.62 U17.32 ; v4(52.14,83.08) 52.35,82.88 52.35,82.68 52.21,82.54 C84.1
  L8_SIG3 w0.102: v1(89.47,95.56) 89.31,95.72 87.14,95.72 86.03,96.84 81.44,96.84 80.24,98.03 74.79,98.03 74.65,98.17 74.65,98.17 72.75,100.07 70.06,100.07 68.45,101.68 57.12,101.68 51.77,96.32 51.77,92.75 50.01,91 50.01,89.36 49.72,89.08 49.72,88.81 49.56,88.65 49.3,88.65 49.14,88.49 49.14,88.23 48.98,88.07 48.71,88.07 48.55,87.91 48.55,87.64 48.74,87.45 48.74,87.22 48.55,87.03 48.55,86.8 48.74,86.61 48.74,86.38 48.55,86.19 48.55,85.96 48.74,85.77 48.74,85.54 48.55,85.35 48.55,85.12 48.74,84.93 48.74,84.7 48.55,84.51 48.55,84.04 48.83,83.77 48.96,83.77 49.1,83.77 49.26,83.6 49.26,83.47 49.26,83.33 49.42,83.17 49.56,83.17 49.7,83.17 49.86,83.01 49.86,82.87 49.86,82.74 50.19,82.4 50.42,82.4 50.57,82.55 50.8,82.55 50.94,82.4 51.17,82.4 51.32,82.55 51.55,82.55 51.7,82.4 52.1,82.4 52.33,82.63 52.33,82.89 v4(52.14,83.08)
TSREFCLKP_R: length 10.3
  TOP w0.102: C84.2 52.18,81.64 52.39,81.43 52.39,80.89 53.06,80.22 53.06,78.31 51.19,76.44 51.19,73.35 U23.AK2
TSRX_CLK0N: length 76.1
  TOP w0.102: v1(42.42,127.84) 42.13,128.13 41.94,128.13 41.8,127.99 CN7.101 ; U23.AJ2 v4(51.98,73.36)
  L3_SIG1 w0.102: v4(51.98,73.36) 51.72,73.61 51.19,73.61 50.81,74 50.81,77.42 48.83,79.4 48.83,83.8 48.6,84.02 48.6,92.72 48.6,92.72 48.6,92.81 47.4,94.02 46.37,94.02 40.36,100.03 36.88,100.03 35.16,101.75 35.16,125.03 39.83,129.71 42.82,129.71 43.21,129.32 43.21,128.36 42.95,128.1 42.67,128.1 v1(42.42,127.84)
TSRX_CLK0P: length 75.9
  TOP w0.102: v1(42.42,128.65) 42.16,128.38 41.91,128.38 41.8,128.49 CN7.103 ; U23.AJ1 v4(51.98,74.16)
  L3_SIG1 w0.102: v1(42.42,128.65) 42.67,128.39 42.82,128.39 42.91,128.48 42.91,129.2 42.7,129.41 39.95,129.41 35.45,124.91 35.45,101.87 37,100.32 40.48,100.32 46.49,94.31 47.52,94.31 48.9,92.93 48.9,92.84 48.9,84.14 49.33,83.71 49.33,83.48 49.12,83.28 49.12,83.05 49.33,82.84 49.33,82.61 49.12,82.4 49.12,82.17 49.33,81.96 49.33,81.74 49.12,81.53 49.12,81.3 49.33,81.09 49.33,80.86 49.12,80.65 49.12,80.42 49.33,80.21 49.33,79.99 49.12,79.78 49.12,79.52 49.33,79.31 49.46,79.31 49.6,79.31 49.76,79.15 49.76,79.02 49.76,78.89 49.92,78.72 50.05,78.72 50.18,78.72 50.34,78.56 50.34,78.43 50.34,78.3 50.51,78.14 50.64,78.14 50.77,78.14 50.93,77.98 50.93,77.84 50.93,77.71 51.1,77.54 51.1,77.11 51.31,76.91 51.31,76.68 51.1,76.48 51.1,76.25 51.31,76.04 51.31,75.82 51.1,75.61 51.1,75.38 51.31,75.18 51.31,74.95 51.1,74.75 51.1,74.12 51.32,73.91 51.72,73.91 v4(51.98,74.16)
TSRX_CLK1N: length 77.2
  TOP w0.102: CN7.105 41.8,128.99 41.94,129.13 43.4,129.13 v1(43.69,128.84) ; U23.AH1 v4(52.78,74.16)
  L3_SIG1 w0.102: v1(43.69,128.84) 43.94,129.1 44.32,129.1 44.45,128.97 44.45,128.1 44.22,127.87 43.39,127.87 42.65,127.14 38.86,127.14 37.61,125.88 37.61,123.17 35.75,121.31 35.75,101.99 36.86,100.89 41.27,100.89 46.21,95.95 47.07,95.95 49.99,93.03 49.99,85.81 50.52,85.27 50.52,82.96 50.64,82.83 53.28,80.19 53.28,73.86 53.18,73.76 52.93,73.76 52.78,73.92 v4(52.78,74.16)
TSRX_CLK1P: length 77.3
  TOP w0.102: U23.AG2 v4(53.58,73.36) ; v1(43.69,129.65) 43.43,129.38 41.91,129.38 41.8,129.49 CN7.107
  L3_SIG1 w0.102: v4(53.58,73.36) 53.58,74.32 53.57,74.32 53.57,80.32 50.96,82.93 50.81,83.08 50.81,85.39 50.28,85.93 50.28,93.15 47.19,96.24 46.33,96.24 41.4,101.18 36.98,101.18 36.05,102.11 36.05,121.19 37.9,123.04 37.9,125.76 38.99,126.84 42.78,126.84 43.51,127.58 44.34,127.58 44.74,127.98 44.74,129.09 44.44,129.39 43.94,129.39 v1(43.69,129.65)
TSSYNCEVT_E: length 85.3
  TOP w0.152: CN7.115 42.34,131.49 v1(42.93,132.08) ; U23.AE5 v4(55.18,70.96)
  L3_SIG1 w0.102: v4(55.18,70.96) 54.78,71.36 54.78,73.7 54.27,74.21 54.27,82.66 53.27,83.65 53.27,85.62 53.9,86.25 53.9,96.28 50.21,99.97 45.29,99.97 43.24,102.03 41.54,102.03 36.61,106.95 36.61,108.33 36.81,108.53 37.61,108.53 38.43,109.35 38.43,119.41 38.3,119.54 38.3,122.63 38.44,122.76 38.44,125.23 39.52,126.31 43.79,126.31 43.99,126.11 44.45,126.11 45.15,126.8 45.63,126.8 45.96,127.14 45.96,129.04 v1(42.93,132.08)
TXN_1: length 12.6
  TOP w0.102: v1(34.38,25.73) 34.58,25.53 34.58,25.23 34.51,25.16 C240.2
  BOTTOM w0.102: v1(34.38,25.73) 34.58,25.53 34.58,24.27 34.8,24.05 36.71,24.05 37.34,24.68 37.34,27.1 34.89,29.54 34.89,29.75 34.97,29.82 U75.18
TXP_1: length 12.6
  TOP w0.102: C239.2 34.92,25.16 34.83,25.25 34.83,25.53 v1(35.04,25.73)
  BOTTOM w0.102: v1(35.04,25.73) 34.83,25.53 34.83,25.3 34.95,25.18 34.95,24.95 34.83,24.84 34.83,24.38 34.9,24.31 35.13,24.31 35.26,24.43 35.49,24.43 35.61,24.31 35.84,24.31 35.97,24.43 36.2,24.43 36.33,24.31 36.61,24.31 37.08,24.78 37.08,25.01 36.96,25.14 36.96,25.37 37.08,25.49 37.08,25.72 36.96,25.85 36.96,26.08 37.08,26.2 37.08,26.99 36.64,27.43 36.45,27.43 36.29,27.59 36.29,27.79 36.13,27.95 35.93,27.95 35.77,28.11 35.77,28.3 35.61,28.47 35.41,28.47 35.25,28.63 35.25,28.82 34.64,29.43 34.64,29.75 34.57,29.82 U75.19
UEMU0: length 6.2
  TOP w0.152: R115.1 120.88,101.6 121.31,102.03 121.31,104.12 120.89,104.53 119.6,104.53 119.33,104.8 U9.33
UEMU1: length 4.1
  TOP w0.152: R116.1 120.75,103.91 120.61,104.05 119.39,104.05 118.52,104.93 U9.32
UEXP0: length 2.6
  TOP w0.152: U9.29 116.13,104.47 116.56,104.04 R119.1
UEXP1: length 2.5
  TOP w0.152: R120.1 115.16,104.37 115.34,104.55 U9.28
UEXP2: length 2.8
  TOP w0.152: U9.27 114.53,104.62 113.77,103.86 R121.1
UEXP3: length 3.6
  TOP w0.152: U9.23 111.33,105.03 111.18,104.88 110.52,104.88 109.58,103.94 R124.1
URTCK: length 4.6
  TOP w0.152: U9.22 v1(111.33,107.65)
  BOTTOM w0.152: v1(111.33,107.65) 111.33,106.2 111.05,105.92 R383.1
URTM_PS#: length 98.6
  TOP w0.152: v1(76.6,117.89) U8.28 ; v2(15.98,82.52) 16.41,82.96 16.41,83.72 16.25,83.88 R188.1 R189.2
  L8_SIG3 w0.107: v2(15.98,82.52) 17.29,83.84 26.08,83.84 27.75,85.51 27.75,111.01 36.65,119.91 40.77,119.91 41.35,120.5 43.1,120.5 43.4,120.21 52.48,120.21 52.6,120.09 53.37,120.09 54.06,120.78 63.96,120.78 65.66,119.07 75.41,119.07 76.15,118.34 v1(76.6,117.89)
URTM_PS#_R: length 2.2
  TOP w0.152: J4.C1 14.35,85.75 R189.1
USB0_0V85: length 1.9
  TOP w0.254: U23.V9 v4(60.78,67.76) ; U23.U8 v4(62.38,68.56)
  BOTTOM w0.254: C504.1 v4(62.38,68.56) ; C505.1 v4(60.78,67.76)
  vias: v3(31.75,80.39)
USB0_ID: length 2.2
  TOP w0.254: U23.W4 v4(59.98,71.76)
  BOTTOM w0.152: 60.38,72.17 R431.2
  BOTTOM w0.165: v4(59.98,71.76) 60.38,72.17
USB0_RXN: length 163.7
  TOP w0.114: U23.T1 62.49,74.05 62.49,75.11 62.7,75.32 62.7,81.35 62.7,83.38 63.67,84.35 88.78,84.35 92.07,87.64 92.07,93 92.07,93.66 92.07,94.13 94.3,96.37 98.5,96.37 100.53,98.4 118.04,98.4 121.88,94.56 121.88,74.09 123.31,72.65 123.31,58.65 128.65,53.31 131.33,53.31 v1(131.6,53.04)
  BOTTOM w0.114: v1(131.6,53.04) 131.35,53.29 130.87,53.29 130.75,53.17 130.75,49.77 132.12,48.4 144.9,48.4 150.53,42.77 150.66,42.77 150.78,42.77 150.95,42.6 150.95,42.47 150.95,42.35 151.12,42.17 151.25,42.17 151.37,42.17 151.54,42 151.54,41.88 151.54,41.75 151.97,41.33 152.32,41.33 152.52,41.53 152.76,41.53 152.97,41.33 153.21,41.33 153.41,41.53 153.65,41.53 153.86,41.33 154.1,41.33 154.3,41.53 154.54,41.53 154.75,41.33 154.99,41.33 155.19,41.53 155.43,41.53 155.63,41.33 155.88,41.33 156.08,41.53 156.32,41.53 156.52,41.33 157.12,41.33 157.41,41.61 L7.2
USB0_RXP: length 163.7
  TOP w0.114: U23.U1 62.26,74.05 62.26,75.2 62.47,75.41 62.47,81.26 62.47,83.48 63.58,84.58 88.68,84.58 91.84,87.74 91.84,92.9 91.84,93.57 91.84,94.23 94.21,96.6 98.41,96.6 100.44,98.63 118.14,98.63 122.11,94.66 122.11,74.18 123.54,72.75 123.54,58.74 128.74,53.54 131.38,53.54 v1(131.6,53.76)
  BOTTOM w0.114: v1(131.6,53.76) 131.35,53.52 130.77,53.52 130.52,53.27 130.52,49.68 132.03,48.17 144.81,48.17 151.88,41.1 157.12,41.1 157.41,40.81 L7.1
USB0_TXN: length 166
  TOP w0.114: U23.U2 61.57,73.37 61.57,74.51 61.29,74.79 61.29,75.03 61.42,75.16 61.42,75.4 61.29,75.53 61.29,75.77 61.42,75.89 61.42,76.13 61.29,76.26 61.29,76.63 61.9,77.24 61.9,81.02 61.9,81.68 61.9,82.16 61.9,84.03 63.02,85.15 88.29,85.15 91.27,88.14 91.27,92.67 91.27,93.33 91.27,93.99 91.27,94.47 93.97,97.17 98.17,97.17 100.2,99.2 118.56,99.2 124.23,93.54 124.23,59.23 128.64,54.81 129.16,54.81 v1(129.44,54.53)
  BOTTOM w0.114: v1(129.44,54.53) 129.19,54.78 128.59,54.78 128.47,54.66 128.47,50.92 131.79,47.6 143.93,47.6 149.88,41.65 150.15,41.65 150.32,41.48 150.32,41.35 150.32,41.35 150.32,41.22 150.49,41.04 150.75,41.04 150.92,40.87 150.92,40.74 150.92,40.61 151.09,40.44 151.36,40.44 151.53,40.27 151.53,40.14 151.53,40.01 151.7,39.84 151.96,39.84 152.13,39.66 152.13,39.53 152.13,39.53 152.13,39.4 152.3,39.23 152.98,39.23 153.12,39.37 153.36,39.37 153.5,39.23 153.74,39.23 153.88,39.37 154.12,39.37 154.26,39.23 155.32,39.23 155.38,39.29 C186.2
USB0_TXP: length 166
  TOP w0.114: v1(129.44,55.25) 129.23,55.04 128.74,55.04 124.45,59.33 124.45,93.63 118.66,99.43 100.1,99.43 98.07,97.4 93.88,97.4 91.04,94.56 91.04,93.9 91.04,93.24 91.04,92.57 91.04,88.23 88.19,85.38 62.93,85.38 61.67,84.13 61.67,82.25 61.67,82.25 61.67,81.59 61.67,81.59 61.67,80.93 61.67,77.34 61.06,76.73 61.06,74.75 60.78,74.47 60.78,73.35 U23.V2
  BOTTOM w0.114: v1(129.44,55.25) 129.19,55.01 128.5,55.01 128.24,54.75 128.24,50.82 131.7,47.37 143.84,47.37 152.21,39 155.32,39 155.38,38.94 C189.2
USB0_VDD3V3: length 3.7
  TOP w0.254: U23.W10 v4(59.98,66.96)
  L5_SIG2 w0.127: 58.09,66.67 58.13,66.67 58.22,66.58 58.53,66.58 58.62,66.67 58.67,66.67 ; 59.44,66.62 59.37,66.62 59.33,66.58 59.02,66.58 58.98,66.62 58.93,66.62 ; 57.81,66.65 57.8,66.65 57.73,66.58 57.42,66.58 57.35,66.65
  BOTTOM w0.152: C499.1 C524.1
  BOTTOM w0.254: v4(59.98,66.96) C524.1
  vias: v3(32.56,75.08)
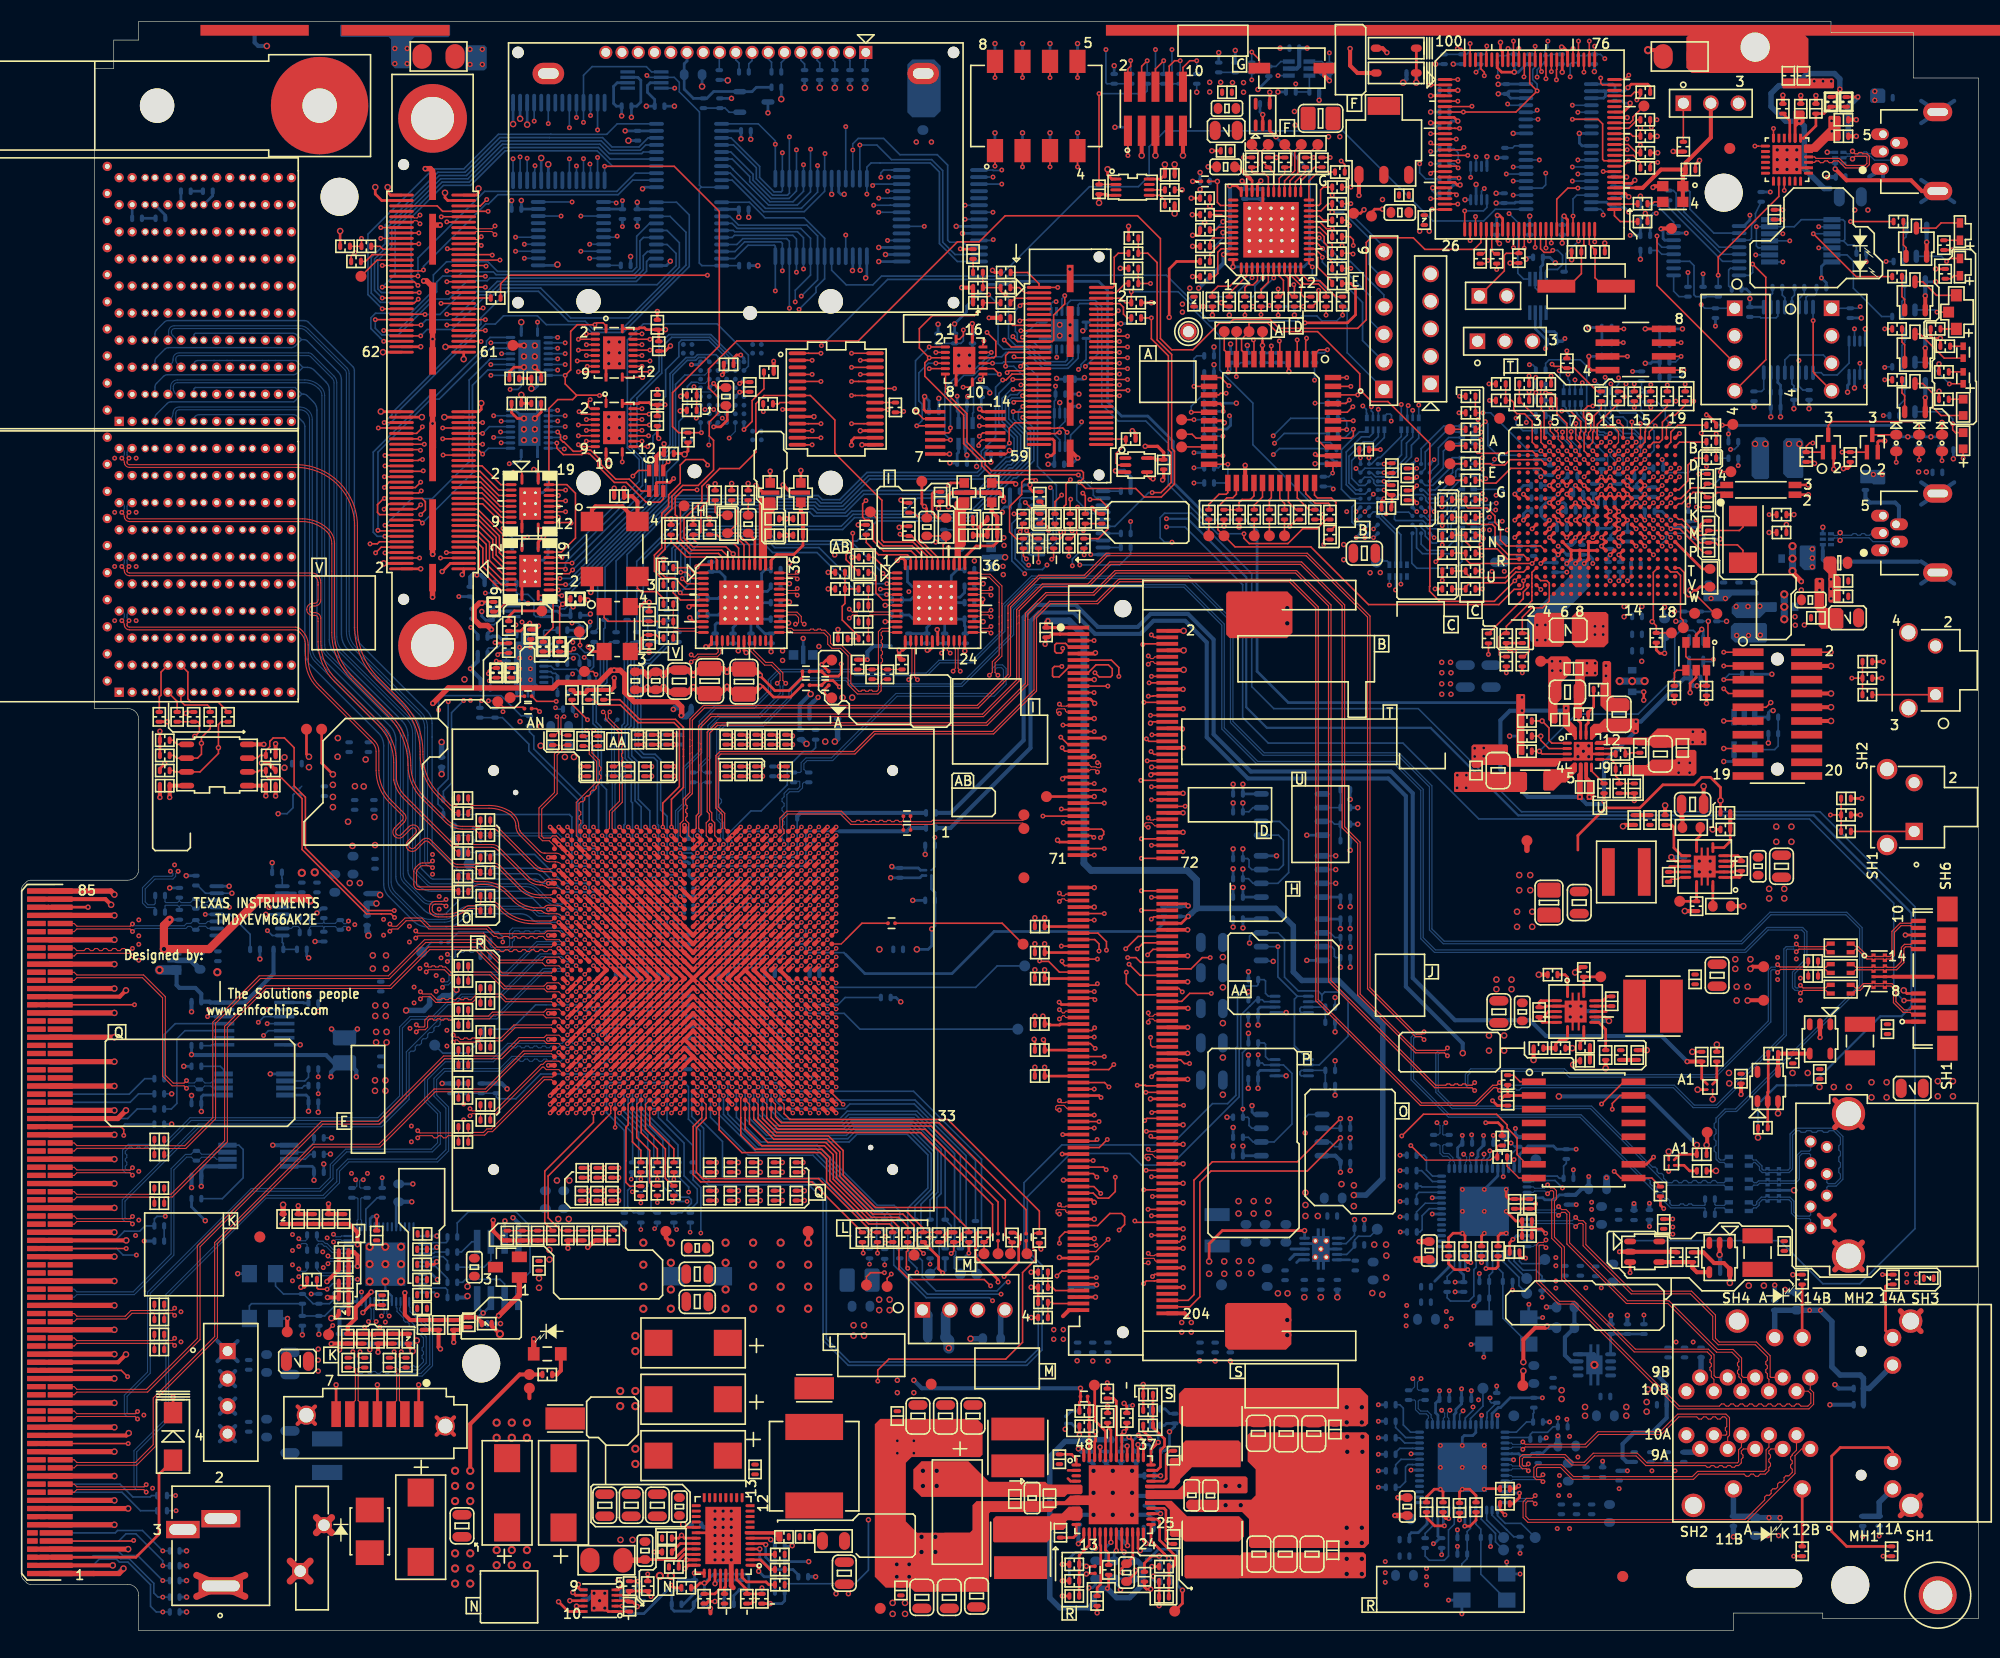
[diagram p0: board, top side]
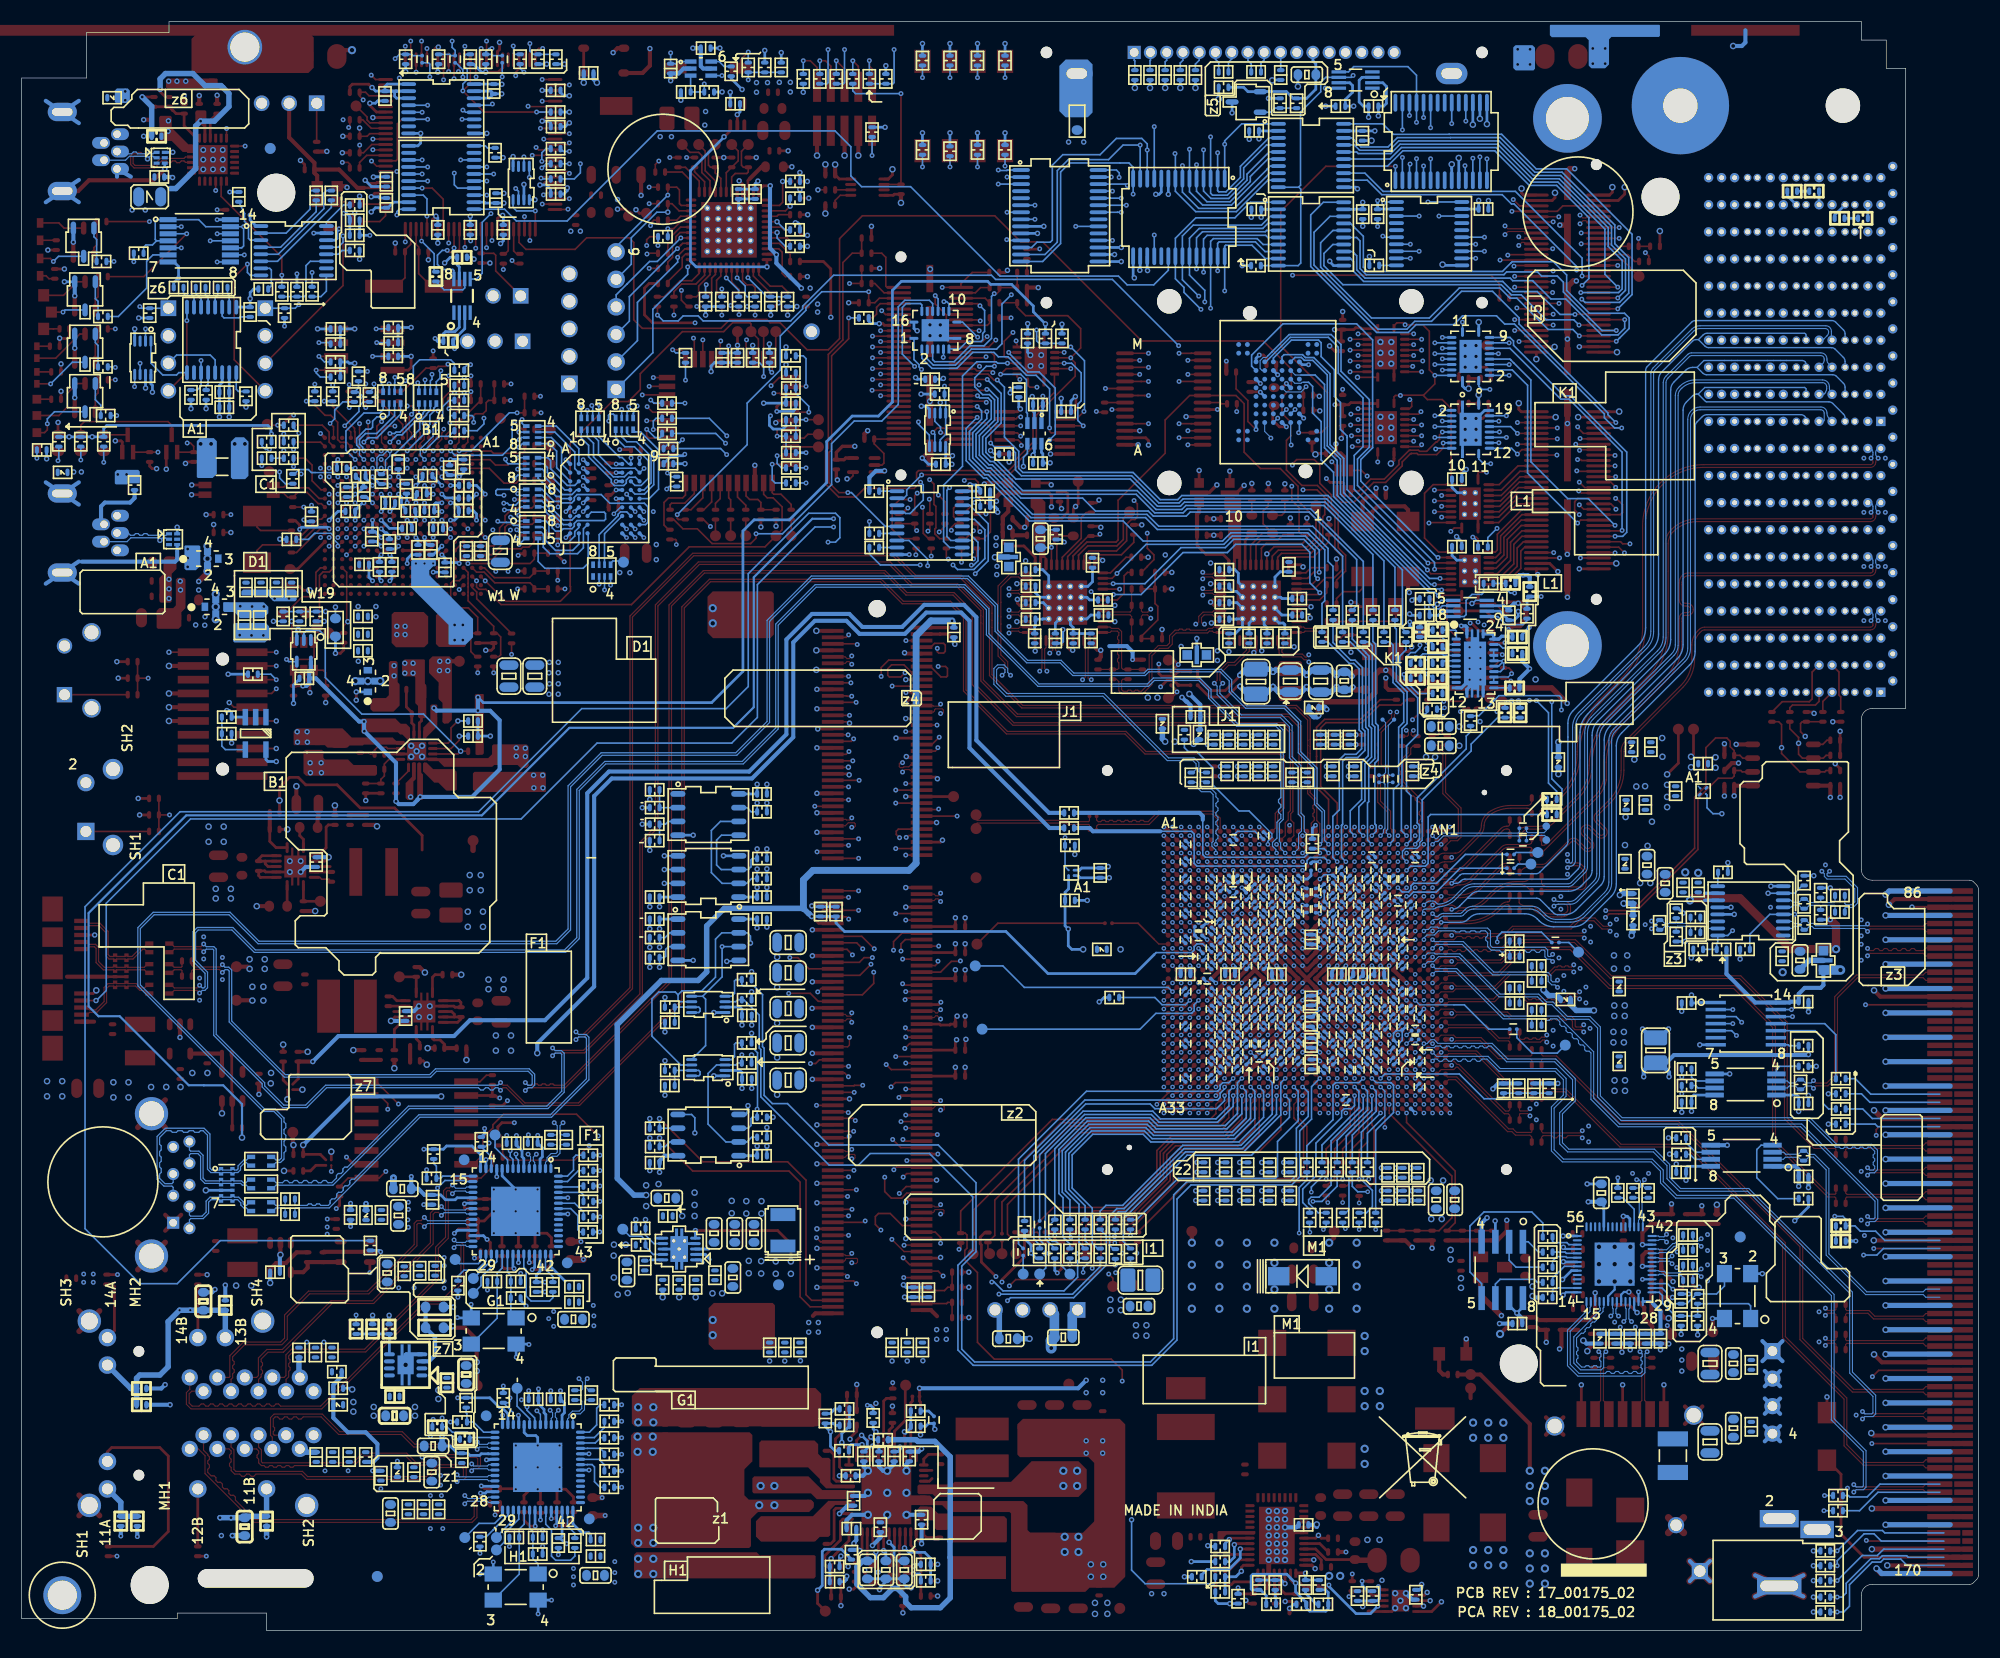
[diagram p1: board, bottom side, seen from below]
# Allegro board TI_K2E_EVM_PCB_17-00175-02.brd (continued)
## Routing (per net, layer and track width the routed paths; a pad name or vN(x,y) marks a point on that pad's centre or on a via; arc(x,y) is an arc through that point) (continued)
USB0_VDDA33: length 0.6
  TOP w0.127: U15.N18 v1(152.22,100.08)
USB0DN: length 185.5
  TOP w0.114: U23.W3 v4(59.98,72.56)
  BOTTOM w0.114: v4(59.98,72.56) 60.35,72.93 60.35,75.65 61.04,76.33 61.04,79.6 62.54,81.11 62.54,83.92 63.96,85.34 67.53,85.34 68.92,86.73 68.92,87.75 69.88,88.72 76.66,88.72 77,88.37 83.48,88.37 84.66,89.55 87.74,89.55 90.53,92.33 90.53,94.64 93.21,97.33 107.71,97.33 111.8,93.24 111.8,83.9 114.69,81.01 127.12,81.01 130.16,77.96 130.16,64.75 131.3,63.61 158.69,63.61 161.36,66.29 168.46,66.29 169.88,64.87 169.88,59.49 158.28,47.9 157.31,47.9 156.62,47.2 156.62,43.61 156.8,43.42 157.12,43.42 157.41,43.71 L8.2
USB0DP: length 185.4
  TOP w0.114: U23.V3 v4(60.78,72.56)
  BOTTOM w0.114: L8.1 157.41,42.91 157.12,43.19 156.71,43.19 156.39,43.51 156.39,44.09 156.22,44.26 156.22,44.63 156.39,44.79 156.39,45.16 156.22,45.33 156.22,45.7 156.39,45.86 156.39,46.23 156.22,46.4 156.22,46.77 156.39,46.93 156.39,47.3 157.22,48.13 158.19,48.13 169.65,59.59 169.65,64.78 168.36,66.06 161.46,66.06 158.79,63.39 131.21,63.39 129.94,64.66 129.94,77.87 127.02,80.78 114.59,80.78 111.57,83.8 111.57,93.14 107.62,97.1 93.31,97.1 90.75,94.55 90.75,92.23 87.84,89.32 84.75,89.32 83.58,88.14 76.9,88.14 76.56,88.49 69.98,88.49 69.15,87.66 69.15,86.64 67.62,85.12 64.06,85.12 62.77,83.83 62.77,81.01 61.26,79.51 61.26,76.24 60.58,75.55 60.58,72.76 v4(60.78,72.56)
USB0DRVVBUS: length 223
  TOP w0.254: U23.AB1 v4(57.58,74.16)
  L8_SIG3 w0.107: v4(57.58,74.16) 57.58,74.67 57.99,75.09 59.44,75.09 62.28,77.92 62.28,81.72 64.79,84.23 76.86,84.23 77.95,85.32 78.71,85.32 78.71,85.32 87.1,85.32 88.74,86.96 88.74,88.33 92.11,91.7 92.11,92.94 95.91,96.73 95.91,98.96 96.27,99.31 96.27,99.32 96.42,99.47 96.42,101.68 96.4,101.7 96.65,101.96 104.47,101.96 104.75,102.23 105.82,102.23 106.05,102.01 106.05,100.58 v1(106.17,100.46)
  BOTTOM w0.152: R533.1 162.27,35.98 166.24,32 169.67,32 174.75,37.08 174.75,66.8 165.99,75.56 138.43,75.56 128.91,85.09 115.57,85.09 113.54,87.12 113.54,97.54 107.95,103.12 105.49,103.12 105.08,102.72 105.08,100.86 105.49,100.46 v1(106.17,100.46)
USB0VBUS: length 5.4
  TOP w0.254: C174.1 153.95,42.42 153.44,42.93 U29.A2
  TOP w0.381: J7.1 167.35,38.36 ; J7.1 165.88,38.36 ; J7.1 167.35,36.89
USB1_0V85: length 3.7
  TOP w0.254: U23.R8 v4(63.98,68.56) ; U23.T9 v4(63.18,67.76)
  L8_SIG3 w0.381: 63.65,68.88 63.98,68.56 v4(63.98,68.56) ; 62.89,67.87 63,67.76 v4(63.18,67.76)
  BOTTOM w0.254: C513.1 v4(63.18,67.76) ; C498.1 v4(63.98,68.56)
  BOTTOM w0.508: FB22.1 72.05,82.23 v3(72.44,81.84)
USB1_ID: length 197.2
  TOP w0.152: R172.2 44.1,90.23 v1(43.94,90.07) ; J6.4 v2(173.74,58.14) ; U23.W6 v4(59.98,70.16)
  L5_SIG2 w0.107: v1(43.94,90.07) 45.73,88.28 47.11,88.28 47.96,87.43 50.4,87.43 52.45,85.38 54.58,85.38 55.8,84.16 55.8,80.3 58.69,77.4 60.67,75.42 60.67,73.11 60.54,72.97 60.41,72.85 60.41,70.59 v4(59.98,70.16)
  L8_SIG3 w0.107: v1(105.66,101.85) 105.66,100.61 101.9,96.85 97.66,96.85 93.26,92.44 93.26,91.23 91.38,89.36 91.38,87.93 87.62,84.18 78.46,84.18 78.13,83.84 77.37,83.08 65.28,83.08 63.42,81.23 63.42,77.45 60.65,74.68 60.65,73.23 60.41,72.98 60.41,70.62 59.98,70.19 v4(59.98,70.16)
  BOTTOM w0.152: v2(173.74,58.14) 173.71,58.14 172.8,59.05 172.8,67.12 165.01,74.9 134.49,74.9 127.49,81.91 115.06,81.91 112.7,84.27 112.7,96.53 107.37,101.85 v1(105.66,101.85)
USB1_RXN: length 175
  TOP w0.114: U23.N1 64.89,74.05 64.89,75.42 64.3,76.01 64.3,80.66 64.54,80.9 76.91,80.9 78.77,82.75 89.71,82.75 93.67,86.71 93.67,93.47 94.97,94.77 99.32,94.77 101.35,96.8 117.03,96.8 119.44,94.38 119.44,58.13 129.11,48.46 134.24,48.46 135.87,50.1 136.15,50.1 v1(136.4,49.85) ; L3.2 166.81,62.6 166.52,62.89 164.05,62.89 v1(163.8,62.64)
  BOTTOM w0.114: v1(136.4,49.85) 136.64,50.09 136.88,50.09 137.09,49.89 137.33,49.89 137.54,50.09 137.78,50.09 137.99,49.89 138.23,49.89 138.44,50.09 152.45,50.09 154.29,48.26 156.49,48.26 158.4,50.17 158.4,50.46 162.87,54.93 162.87,62.8 162.96,62.89 163.56,62.89 v1(163.8,62.64)
USB1_RXN_R: length 9.6
  TOP w0.114: L3.3 168.98,62.6 169.27,62.89 169.41,62.89 170.32,61.98 170.79,61.98 U24.2 171.06,61.98 171.84,61.98 U24.13 172.11,61.98 172.53,61.98 172.85,62.3 172.85,64.43 173.47,65.05 174.35,65.05 174.56,64.84 J6.9
USB1_RXP: length 175
  TOP w0.114: L3.1 166.81,63.4 166.52,63.11 164.05,63.11 v1(163.8,63.36) ; v1(136.4,50.57) 136.15,50.32 135.78,50.32 134.15,48.69 129.2,48.69 119.67,58.22 119.67,94.48 117.12,97.03 101.25,97.03 99.22,95 94.87,95 93.44,93.57 93.44,86.81 89.61,82.98 78.67,82.98 76.82,81.13 64.45,81.13 64.07,80.75 64.07,75.91 64.66,75.32 64.66,74.05 U23.P1
  BOTTOM w0.114: v1(136.4,50.57) 136.64,50.32 152.55,50.32 154.38,48.49 156.4,48.49 158.17,50.26 158.17,50.55 162.65,55.03 162.65,62.9 162.86,63.11 163.56,63.11 v1(163.8,63.36)
USB1_RXP_R: length 9.6
  TOP w0.114: J6.10 174.59,65.49 174.38,65.28 173.38,65.28 172.63,64.53 172.63,62.39 172.44,62.21 172.11,62.21 U24.14 171.84,62.21 171.06,62.21 U24.1 170.79,62.21 170.42,62.21 169.51,63.11 169.27,63.11 168.98,63.4 L3.4
USB1_TXN: length 172.5
  TOP w0.114: U23.R2 63.18,73.35 63.18,74.54 63.47,74.82 63.47,75.38 63.27,75.58 63.27,82.92 64.14,83.78 89.02,83.78 92.64,87.41 92.64,93.24 92.64,93.9 94.54,95.8 98.88,95.8 100.91,97.83 117.68,97.83 120.85,94.65 120.85,59.99 130.52,50.32 131.44,50.32 131.56,50.45 131.81,50.45 131.93,50.32 132.17,50.32 132.29,50.45 132.53,50.45 132.66,50.32 132.9,50.32 133.02,50.45 133.26,50.45 133.39,50.32 133.87,50.32 v1(134.11,50.57) ; C129.2 164.9,60.88 164.77,61.01 162.35,61.01 v1(162.07,60.74)
  BOTTOM w0.114: v1(162.07,60.74) 161.82,60.99 161.58,60.99 161.44,60.86 161.44,56.16 156.36,51.07 142.85,51.07 142.31,51.61 133.85,51.61 133.48,51.24 133.48,50.43 133.59,50.32 133.86,50.32 v1(134.11,50.57)
USB1_TXN_R: length 8.3
  TOP w0.114: J6.6 174.56,62.89 174.35,63.1 173.88,63.1 173.73,62.95 173.73,61.65 173.06,60.98 172.11,60.98 U24.11 171.84,60.98 171.06,60.98 U24.4 170.79,60.98 169.27,60.98 168.98,60.7 L4.3
USB1_TXP: length 172.5
  TOP w0.114: U23.P2 63.97,73.37 63.97,74.54 63.7,74.81 63.7,75.47 63.5,75.67 63.5,82.82 64.23,83.55 89.11,83.55 92.87,87.31 92.87,93.33 92.87,93.8 94.64,95.57 98.97,95.57 101,97.6 117.58,97.6 120.62,94.56 120.62,59.9 130.42,50.1 133.85,50.1 v1(134.11,49.84) ; C126.2 164.9,61.4 164.74,61.24 162.29,61.24 v1(162.07,61.45)
  BOTTOM w0.114: v1(162.07,61.45) 161.84,61.22 161.48,61.22 161.21,60.95 161.21,56.25 156.26,51.3 142.94,51.3 142.4,51.84 133.76,51.84 133.25,51.34 133.25,50.33 133.5,50.09 133.86,50.09 v1(134.11,49.84)
USB1_TXP_R: length 8.3
  TOP w0.114: J6.7 174.56,63.54 174.35,63.33 173.78,63.33 173.5,63.05 173.5,61.74 172.97,61.21 172.2,61.21 172.06,61.34 U24.12 171.84,61.21 171.06,61.21 U24.3 170.79,61.21 169.29,61.21 169,61.5 L4.4
USB1_VDD3V3: length 2.7
  TOP w0.254: U23.R10 v4(63.98,66.96)
  BOTTOM w0.254: C512.1 v4(63.98,66.96) C523.1
  BOTTOM w0.508: FB27.1 31.88,64.52 32,64.39 v3(32,64.14)
USB1DN: length 158.6
  TOP w0.114: U23.P4 v4(64.78,71.76) ; L5.2 166.81,58.79 166.52,59.08 164.42,59.08 v1(164.18,58.83)
  BOTTOM w0.114: v4(64.78,71.76) 64.84,71.82 64.84,72.09 65.15,72.4 65.15,72.72 64.74,73.14 64.74,74.6 64.38,74.95 64.38,75.32 64.59,75.52 64.59,75.77 64.38,75.98 64.38,76.22 64.59,76.43 64.59,76.67 64.38,76.88 64.38,83 64.84,83.46 68.46,83.46 71.05,86.05 71.05,86.78 71.96,87.69 76.05,87.69 76.59,87.14 86.79,87.14 91.55,91.9 91.55,94.21 93.64,96.3 107.27,96.3 110.77,92.8 110.77,83.21 114,79.98 126.69,79.98 129.14,77.54 129.14,63.85 130.4,62.59 159.12,62.59 161.19,64.65 164.3,64.65 164.55,64.4 164.55,61.86 163.45,60.76 163.45,59.32 163.69,59.08 163.93,59.08 v1(164.18,58.83)
USB1DN_R: length 8.6
  TOP w0.114: J6.2 174.53,56.84 174.32,57.05 173.66,57.05 172.76,57.95 172.76,59.25 172.54,59.48 172.11,59.48 U24.8 171.84,59.48 171.06,59.48 U24.7 170.79,59.48 170.09,59.48 169.69,59.08 169.27,59.08 168.98,58.79 L5.3
USB1DP: length 158.5
  TOP w0.114: L5.1 166.8,59.59 166.51,59.3 164.42,59.3 v1(164.18,59.55) ; U23.R4 v4(63.98,71.76)
  BOTTOM w0.114: v1(164.18,59.55) 163.93,59.3 163.79,59.3 163.67,59.42 163.67,60.66 164.78,61.77 164.78,64.5 164.39,64.88 161.1,64.88 159.03,62.81 130.5,62.81 129.36,63.95 129.36,77.63 126.78,80.21 114.09,80.21 111,83.31 111,92.89 107.37,96.53 93.54,96.53 91.33,94.31 91.33,92 86.7,87.37 76.69,87.37 76.14,87.92 71.86,87.92 70.82,86.87 70.82,86.14 68.36,83.69 64.75,83.69 64.15,83.1 64.15,74.86 64.51,74.51 64.51,72.82 64.4,72.72 64.4,72.19 v4(63.98,71.76)
USB1DP_R: length 8.6
  TOP w0.114: J6.3 174.52,57.49 174.31,57.28 173.76,57.28 172.99,58.04 172.99,59.35 172.63,59.71 172.11,59.71 U24.9 171.84,59.71 171.06,59.71 U24.6 170.79,59.71 169.99,59.71 169.93,59.64 169.59,59.3 169.27,59.3 168.98,59.59 L5.4
USB1DRVVBUS: length 190
  TOP w0.152: U23.AC1 v4(56.78,74.16)
  TOP w0.254: R223.1 v3(160.26,45.49)
  L8_SIG3 w0.107: v4(56.78,74.16) 56.78,75.1 57.48,75.81 59.52,75.81 61.82,78.11 61.82,81.91 64.6,84.68 76.67,84.68 77.76,85.78 86.91,85.78 88.28,87.15 88.28,88.52 91.66,91.89 91.66,93.13 95.45,96.92 95.45,99.8 95.25,100 95.25,101.57 96.42,102.74 105.54,102.74 v1(105.66,102.62)
  BOTTOM w0.203: v1(105.66,102.62) 107.62,102.62 113.03,97.21 113.03,85.22 114.93,83.31 130.05,83.31 138.13,75.23 165.4,75.23 174.42,66.22 174.42,57.61 173.51,56.69 171.55,56.69 165.18,50.32 163.78,50.32 163.78,50.32 162,50.32 160.26,48.58 v3(160.26,45.49)
USB1VBUS: length 3.4
  TOP w0.254: C150.1 156.46,50.8 U28.A2
  TOP w0.381: J6.1 173.92,56.19
USB_CLKN: length 19.7
  TOP w0.102: U18.21 67.67,90.71 67.55,90.59 67.55,90.49 68.68,89.36 69.29,89.36 70.26,88.39 70.26,87.69 v1(70.52,87.43)
  BOTTOM w0.102: v1(70.52,87.43) 70.26,87.16 70.26,86.38 68.13,84.25 64.41,84.25 63.59,83.43 63.59,80.54 62.78,79.73 62.78,79.35 62.94,79.19 C462.1
USB_CLKN_R: length 8
  TOP w0.102: U23.T4 v4(63.18,71.76)
  BOTTOM w0.102: C462.2 62.91,78.29 62.78,78.16 62.78,75.34 62.47,75.03 62.47,73.79 62.74,73.51 62.74,72.19 63.17,71.76 v4(63.18,71.76)
USB_CLKP: length 19.7
  TOP w0.102: v1(69.74,87.43) 70,87.69 70,88.29 69.19,89.1 68.57,89.1 67.29,90.38 67.29,90.59 67.17,90.71 U18.20
  BOTTOM w0.102: C463.1 62.34,79.19 62.52,79.38 62.52,79.84 63.33,80.65 63.33,83.53 64.31,84.51 68.03,84.51 70,86.48 70,87.16 v1(69.74,87.43)
USB_CLKP_R: length 8
  TOP w0.102: U23.U4 v4(62.38,71.76)
  BOTTOM w0.102: C463.2 62.43,78.29 62.52,78.2 62.52,75.44 62.22,75.14 62.22,73.75 62.01,73.54 62.01,72.13 v4(62.38,71.76)
USB_RXN_R: length 9.3
  BOTTOM w0.114: J7.5 165.12,44.36 165,44.24 164.24,44.24 163.86,43.85 163.86,41.75 163.6,41.49 162.33,41.49 U30.3 162.06,41.49 161.28,41.49 U30.12 161.01,41.49 160.3,41.49 160.14,41.33 159.89,41.33 159.61,41.61 L7.3
USB_RXP_R: length 9.3
  BOTTOM w0.114: L7.4 159.58,40.81 159.87,41.1 160.23,41.1 160.4,41.26 161.01,41.26 U30.11 161.28,41.26 162.06,41.26 U30.4 162.33,41.26 163.69,41.26 164.08,41.66 164.08,43.76 164.34,44.01 165,44.01 165.12,43.9 J7.6
USB_SHIELD: length 30.7
  TOP w0.254: 172.72,60.34 U24.10 U24.5
  TOP w0.381: 176.41,60.34 172.72,60.34
  TOP w0.508: 167.35,33.29 J7.H1 ; J7.H1 169.88,33.29 ; J7.H1 169.88,35.82 ; J7.H1 167.35,35.82 ; 167.35,46.43 J7.H2 ; J7.H2 169.88,46.43 ; J7.H2 167.35,48.96
  L3_SIG1 w0.635: J7.H1 165.09,34.56 163.6,36.04 v3(163.6,40.63)
  BOTTOM w0.254: U30.10 U30.5 v3(163.6,40.63)
  vias: v3(176.86,50.7) v3(176.86,49.3) v3(178.26,50.7) v3(178.26,49.3)
USB_VBUS: length 21.6
  TOP w0.254: v2(167.82,142.27) 167.82,142.04 167.33,141.55 R613.1
  BOTTOM w0.508: v2(167.82,142.27) 167.82,143.22 167.32,143.71 164.8,143.71 163.68,142.6 162.2,142.6 162.02,142.42 161.47,141.87 161.47,140.67 162.81,139.32 v2(164.08,139.32) 164.54,138.86 164.54,134.92 166.37,133.1 166.9,133.1
USB_VBUS_EN: length 114.6
  TOP w0.152: U28.B2 v3(156.08,49.02) ; R57.2 119.13,122.21 119.71,122.79 119.71,123.63 119.71,123.64 v1(119.71,123.7) ; U29.B2 152.02,42.93 v1(152.02,42.37)
  L3_SIG1 w0.254: v1(119.71,123.7) 121.46,121.94 121.46,108.25 121.68,108.04 121.68,100.72 121.44,100.48 121.44,98.59 124.76,95.28 137.86,95.28 139.52,96.93 139.81,96.93 140.52,96.93 143.15,94.3 143.15,85.58 153.9,74.84 153.9,67.54 155.4,66.04 155.4,52.15 156.08,51.46 v3(156.08,49.02)
  L10_SIG4 w0.107: v3(156.08,49.02) 154.74,49.02 151.23,45.52 151.23,43.15 v1(152.02,42.37)
USB_VBUS_R: length 9.4
  L3_SIG1 w0.381: v2(166.65,136.45) 166.76,136.45 169.19,134.02 v2(169.19,131.11)
  BOTTOM w0.254: D13.6 166.66,136.44 v2(166.65,136.45)
  BOTTOM w0.381: 171.8,134.19 J1.1 170.52,134.19
  vias: v2(170.41,131.11)
USB_VIO: length 1.3
  TOP w0.127: 165.35,136.65 165.22,136.51 U2.5
  TOP w0.381: R6.1 v2(162.56,141.71)
  vias: v2(167.06,139.34) v2(167.08,138.38)
USBDN_R: length 19.8
  BOTTOM w0.114: L8.3 159.56,43.71 159.84,43.42 160.09,43.42 160.63,42.88 160.63,42.61 160.74,42.49 160.93,42.49 161.07,42.63 U30.14 161.28,42.49 162.06,42.49 U30.1 162.33,42.49 163.04,42.49 163.22,42.67 163.22,45.81 163.76,46.35 167.34,46.35 168.1,45.6 168.1,41.64 167.47,41.01 166.73,41.01 166.62,40.9 J7.2
USBDP_R: length 19.8
  BOTTOM w0.114: L8.4 159.58,42.91 159.87,43.19 159.99,43.19 160.4,42.79 160.4,42.51 160.65,42.26 160.93,42.26 161.07,42.13 U30.13 161.28,42.26 162.06,42.26 U30.2 162.33,42.26 163.14,42.26 163.45,42.57 163.45,45.72 163.86,46.13 164.1,46.13 164.25,45.98 164.62,45.98 164.77,46.13 165.13,46.13 165.28,45.98 165.65,45.98 165.8,46.13 166.17,46.13 166.32,45.98 166.69,45.98 166.84,46.13 167.25,46.13 167.87,45.5 167.87,44.88 167.72,44.72 167.72,44.35 167.87,44.2 167.87,43.83 167.72,43.68 167.72,43.31 167.87,43.16 167.87,42.79 167.72,42.64 167.72,42.27 167.87,42.12 167.87,41.74 167.37,41.24 166.73,41.24 166.62,41.36 J7.3
USRSTN: length 3.5
  TOP w0.152: R117.1 118.83,103.45 117.73,104.55 U9.31
UTCA_SGMII4_RX_DN: length 100.5
  TOP w0.102: C143.2 42.35,54.66 42.25,54.56 41.94,54.56 41.81,54.69 41.58,54.69 41.45,54.56 41.23,54.56 41.1,54.69 40.87,54.69 40.74,54.56 40.51,54.56 40.31,54.76 40.03,54.76 v1(39.83,54.96)
  L3_SIG1 w0.102: J2.B2 9.8,114.1 9.73,114.03 9.73,113.49 9.88,113.33 25.94,113.33 26.86,112.41 26.86,85.74 24.78,83.65 22.05,83.65 20.54,82.14 20.54,71.26 23.72,68.07 23.72,59.21 30.07,52.86 37.05,52.86 38.97,54.78 39.65,54.78 v1(39.83,54.96)
UTCA_SGMII4_RX_DN_R: length 7.1
  TOP w0.102: U23.AN23 48.9,55.89 45.43,55.89 44.22,54.67 43.31,54.67 43.25,54.73 C143.1
UTCA_SGMII4_RX_DP: length 100.5
  TOP w0.102: v1(39.83,54.3) 40.03,54.51 40.21,54.51 40.41,54.31 42.27,54.31 42.35,54.22 C145.2
  L3_SIG1 w0.102: v1(39.83,54.3) 39.65,54.49 39.09,54.49 37.17,52.57 29.95,52.57 23.43,59.09 23.43,67.95 20.24,71.14 20.24,82.26 21.93,83.95 24.66,83.95 26.57,85.86 26.57,112.29 25.82,113.04 9.76,113.04 9.44,113.37 9.44,114.03 9.37,114.1 J2.A2
UTCA_SGMII4_RX_DP_R: length 7.1
  TOP w0.102: U23.AN24 48.9,55.63 45.54,55.63 44.33,54.42 43.36,54.42 43.25,54.31 C145.1
UTCA_SGMII4_TX_DN: length 108.9
  TOP w0.102: U23.AL24 v4(50.38,54.96)
  L3_SIG1 w0.102: v4(50.38,54.96) 50.38,55.09 50.25,55.21 50.01,55.21 49.88,55.08 43.66,55.08 40.41,51.83 29.19,51.83 20.87,60.15 20.87,68.41 19.42,69.86 19.42,82.66 21.63,84.87 24.4,84.87 25.65,86.13 25.65,111.85 25.19,112.32 9.93,112.32 9.61,112 9.61,111.71 9.72,111.6 J2.B1
UTCA_SGMII4_TX_DP: length 108.9
  TOP w0.102: U23.AL23 v4(50.38,55.76)
  L3_SIG1 w0.102: J2.A1 9.32,111.92 9.32,112.12 9.81,112.61 25.31,112.61 25.95,111.98 25.95,86.01 24.52,84.58 21.75,84.58 19.71,82.54 19.71,69.98 21.16,68.53 21.16,60.27 29.31,52.12 40.29,52.12 43.54,55.37 49.76,55.37 49.89,55.51 50.12,55.51 v4(50.38,55.76)
UTCA_SGMII5_RX_DN: length 100.6
  TOP w0.102: C136.2 40.32,56.79 40.24,56.71 37.58,56.71 37.21,56.34 37.21,55.78 37.13,55.7 36.7,55.7 36.63,55.7 v1(36.42,55.9)
  L3_SIG1 w0.102: v1(36.42,55.9) 36.61,55.72 37.1,55.72 37.39,55.43 37.39,54.76 36.77,54.14 34.69,54.14 34.26,54.57 34.26,55.47 33.93,55.8 31.49,55.8 25.64,61.65 25.64,68.23 24.83,69.04 24.83,81.65 28.17,84.99 28.17,117.25 25.36,120.05 10.06,120.05 9.75,119.74 9.75,119.55 J2.B4
UTCA_SGMII5_RX_DN_R: length 9.7
  TOP w0.102: C136.1 41.22,56.81 41.33,56.71 43.08,56.71 43.45,57.07 48.19,57.07 48.46,57.35 49.59,57.35 U23.AM22
UTCA_SGMII5_RX_DP: length 100.6
  TOP w0.102: C141.2 40.32,56.38 40.25,56.45 39.74,56.45 39.62,56.34 39.4,56.34 39.28,56.45 39.05,56.45 38.94,56.34 38.71,56.34 38.6,56.45 38.37,56.45 38.25,56.34 38.02,56.34 37.91,56.45 37.68,56.45 37.47,56.24 37.47,55.68 37.23,55.45 36.63,55.45 v1(36.42,55.24)
  L3_SIG1 w0.102: v1(36.42,55.24) 36.61,55.43 36.98,55.43 37.1,55.31 37.1,54.88 36.65,54.43 36.13,54.43 36.03,54.53 35.8,54.53 35.7,54.43 35.47,54.43 35.37,54.53 35.14,54.53 35.04,54.43 34.81,54.43 34.56,54.69 34.56,55.59 34.06,56.1 31.61,56.1 25.93,61.77 25.93,68.35 25.12,69.16 25.12,81.53 28.46,84.87 28.46,117.37 25.48,120.35 9.94,120.35 9.45,119.86 9.45,119.55 J2.A4
UTCA_SGMII5_RX_DP_R: length 9.7
  TOP w0.102: U23.AM23 49.59,56.55 48.41,56.55 48.14,56.82 43.55,56.82 43.18,56.45 41.3,56.45 41.22,56.37 C141.1
UTCA_SGMII5_TX_DN: length 112.9
  TOP w0.102: U23.AK23 v4(51.18,55.76)
  L3_SIG1 w0.102: J2.B3 9.77,116.6 9.65,116.72 9.65,117.08 9.86,117.28 26.55,117.28 27.36,116.48 27.36,85.41 24.85,82.9 22.29,82.9 21.2,81.81 21.2,71.18 24.68,67.7 24.68,61.27 29.25,56.7 29.25,55.23 31.1,53.38 36.99,53.38 38.76,55.15 38.76,55.64 39.37,56.25 49.87,56.25 49.96,56.16 50.5,56.16 50.59,56.26 50.96,56.26 51.18,56.04 v4(51.18,55.76)
UTCA_SGMII5_TX_DP: length 112.9
  TOP w0.102: U23.AK22 v4(51.18,56.56)
  L3_SIG1 w0.102: J2.A3 9,116.61 9.36,116.97 9.36,117.2 9.74,117.57 26.68,117.57 27.65,116.6 27.65,85.28 24.97,82.61 22.41,82.61 21.49,81.69 21.49,71.3 24.97,67.82 24.97,61.39 29.54,56.82 29.54,55.35 31.22,53.67 36.87,53.67 38.47,55.27 38.47,55.76 39.25,56.54 49.84,56.54 50.22,56.93 50.81,56.93 v4(51.18,56.56)
UTCA_SGMII6_RX_DN: length 99
  TOP w0.102: C133.2 42.35,58.8 42.29,58.74 42.01,58.74 41.49,58.22 41.26,58.22 41.13,58.34 40.9,58.34 40.78,58.22 40.55,58.22 40.42,58.34 40.19,58.34 40.06,58.22 39.84,58.22 39.71,58.34 39.48,58.34 39.35,58.22 39.12,58.22 39,58.34 38.77,58.34 38.64,58.22 38.33,58.22 37.8,58.75 37.01,58.75 v1(36.8,58.95)
  L3_SIG1 w0.102: v1(36.8,58.95) 36.65,58.8 35.57,58.8 35.03,59.33 32.13,59.33 28.85,62.61 28.85,73.89 27.37,75.37 27.37,81.62 30.1,84.35 30.1,120.86 27.54,123.42 9.94,123.42 9.7,123.65 9.7,123.96 9.84,124.1 J2.B6
UTCA_SGMII6_RX_DN_R: length 6.7
  TOP w0.102: C133.1 43.25,58.85 43.36,58.74 44.3,58.74 44.75,58.29 48.9,58.29 U23.AN20
UTCA_SGMII6_RX_DP: length 99
  TOP w0.102: C135.2 42.35,58.43 42.29,58.48 42.11,58.48 41.59,57.96 38.22,57.96 37.69,58.49 37.01,58.49 v1(36.8,58.29)
  L3_SIG1 w0.102: J2.A6 9.27,124.1 9.41,123.96 9.41,123.53 9.82,123.12 27.42,123.12 29.81,120.74 29.81,84.47 27.08,81.74 27.08,75.25 28.56,73.77 28.56,62.49 32.01,59.04 34.91,59.04 35.45,58.51 36.59,58.51 v1(36.8,58.29)
UTCA_SGMII6_RX_DP_R: length 6.7
  TOP w0.102: U23.AN21 48.9,58.03 44.65,58.03 44.2,58.48 43.33,58.48 43.25,58.4 C135.1
UTCA_SGMII6_TX_DN: length 108.6
  TOP w0.102: U23.AL21 v4(50.38,57.36)
  L3_SIG1 w0.102: v4(50.38,57.36) 50.24,57.5 49.79,57.5 49.67,57.38 49.44,57.38 49.32,57.5 49.09,57.5 48.97,57.38 48.74,57.38 48.62,57.5 48.39,57.5 48.27,57.38 48.04,57.38 47.92,57.5 47.69,57.5 47.57,57.38 47.34,57.38 47.22,57.5 46.99,57.5 46.87,57.38 46.64,57.38 46.52,57.5 46.29,57.5 46.17,57.38 45.94,57.38 45.82,57.5 45.59,57.5 45.47,57.38 45.25,57.38 45.12,57.5 44.9,57.5 44.39,57 39.17,57 38.91,56.74 36.42,56.74 35.97,56.29 34.75,56.29 34.18,56.85 34.18,57.97 33.9,58.25 31.67,58.25 27.76,62.16 27.76,72.81 25.64,74.94 25.64,81.38 28.94,84.68 28.94,119.85 26.52,122.28 9.86,122.28 9.78,122.2 9.78,121.77 9.95,121.6 J2.B5
UTCA_SGMII6_TX_DP: length 108.5
  TOP w0.102: U23.AL20 v4(50.38,58.16)
  L3_SIG1 w0.102: v4(50.38,58.16) 50.01,57.79 44.77,57.79 44.27,57.29 39.05,57.29 38.79,57.04 36.3,57.04 35.85,56.58 34.87,56.58 34.47,56.98 34.47,58.09 34.02,58.55 31.79,58.55 28.05,62.28 28.05,72.94 25.93,75.06 25.93,81.25 29.24,84.56 29.24,119.97 26.64,122.57 9.74,122.57 9.49,122.32 9.49,121.75 9.34,121.6 J2.A5
UTCA_SGMII7_RX_DN: length 100
  TOP w0.102: v1(37.34,61.44) 37.55,61.24 37.77,61.24 37.88,61.34 38.11,61.34 38.21,61.24 38.44,61.24 38.54,61.34 38.77,61.34 38.87,61.24 39.12,61.24 39.62,60.73 40.16,60.73 40.32,60.89 C127.2
  L3_SIG1 w0.102: v1(37.34,61.44) 37.52,61.27 37.75,61.27 37.9,61.42 37.9,62.61 37.74,62.77 37.55,62.77 37.42,62.64 37.19,62.64 37.06,62.77 36.83,62.77 36.7,62.64 36.47,62.64 36.34,62.77 36.11,62.77 35.98,62.64 35.75,62.64 35.62,62.77 35.4,62.77 35.26,62.64 35.04,62.64 34.91,62.77 34.68,62.77 34.55,62.64 34.32,62.64 34.19,62.77 33.96,62.77 33.63,63.09 33.37,63.09 32.56,63.9 32.56,64.44 31.79,65.21 31.79,65.46 31.67,65.58 31.67,65.81 31.79,65.92 31.79,66.15 31.67,66.27 31.67,66.49 31.79,66.61 31.79,66.84 31.67,66.95 31.67,67.18 31.79,67.29 31.79,67.52 31.67,67.64 31.67,67.87 31.79,67.98 31.79,68.21 31.67,68.32 31.67,68.55 31.79,68.67 31.79,69.4 31.18,70.01 31.18,74.58 29.72,76.04 29.72,80.86 31.46,82.6 31.46,123.45 24.77,130.14 9.93,130.14 9.7,129.91 9.7,129.21 9.81,129.1 J2.B8
UTCA_SGMII7_RX_DN_R: length 10.1
  TOP w0.102: U23.AM19 49.56,59.77 48.5,59.77 48.2,59.47 44.61,59.47 43.31,60.77 41.33,60.77 41.22,60.88 C127.1
UTCA_SGMII7_RX_DP: length 100.1
  TOP w0.102: C132.2 40.32,60.38 40.22,60.48 39.52,60.48 39.01,60.98 37.55,60.98 v1(37.34,60.78)
  L3_SIG1 w0.102: v1(37.34,60.78) 37.54,60.97 37.87,60.97 38.19,61.29 38.19,62.73 37.87,63.06 34.08,63.06 34.08,63.06 33.75,63.39 33.49,63.39 32.85,64.02 32.85,64.56 32.08,65.34 32.08,69.52 31.47,70.13 31.47,74.7 30.01,76.16 30.01,80.74 30.02,80.75 30.02,80.75 31.75,82.48 31.75,82.72 31.75,123.57 24.89,130.43 9.8,130.43 9.41,130.03 9.41,129.38 9.13,129.1 J2.A8
UTCA_SGMII7_RX_DP_R: length 10.1
  TOP w0.102: C132.1 41.22,60.38 41.35,60.52 43.21,60.52 44.5,59.22 48.22,59.22 48.49,58.95 49.59,58.95 U23.AM20
UTCA_SGMII7_TX_DN: length 112.2
  TOP w0.102: U23.AK20 v4(51.18,58.16)
  L3_SIG1 w0.102: v4(51.18,58.16) 51.18,58.32 50.9,58.59 49.06,58.59 48.94,58.47 48.71,58.47 48.59,58.59 48.36,58.59 48.24,58.47 48.01,58.47 47.89,58.59 47.66,58.59 47.54,58.47 47.31,58.47 47.19,58.59 46.96,58.59 46.84,58.47 46.61,58.47 46.49,58.59 44.84,58.59 44.04,57.78 37.85,57.78 37.44,58.19 37.44,59.39 36.93,59.9 32.23,59.9 29.27,62.85 29.27,74.04 27.77,75.54 27.77,81.24 28.35,81.81 29.68,81.81 30.65,82.78 30.65,122.19 25.55,127.28 9.86,127.28 9.74,127.16 9.74,126.69 9.82,126.6 J2.B7
UTCA_SGMII7_TX_DP: length 112.2
  TOP w0.102: U23.AK19 v4(51.18,58.96)
  L3_SIG1 w0.102: J2.A7 9.15,126.6 9.45,126.89 9.45,127.28 9.74,127.57 25.67,127.57 30.94,122.31 30.94,82.66 29.8,81.52 28.47,81.52 28.07,81.12 28.07,75.66 29.57,74.17 29.57,62.97 32.35,60.19 37.05,60.19 37.73,59.51 37.73,58.31 37.97,58.08 43.92,58.08 44.72,58.88 49.78,58.88 50.22,59.33 50.81,59.33 v4(51.18,58.96)
UTCK: length 1.9
  TOP w0.152: v4(121,106.83) 121,106.85 121.03,106.88 U9.34
  BOTTOM w0.152: R382.1 120.64,106.5 121,106.85 v4(121,106.83)
UTDI: length 3
  TOP w0.152: U9.38 v1(122.3,110.85)
  BOTTOM w0.152: v1(122.3,110.85) 122.3,111.63 122.05,111.89 R366.1
UTDIS: length 4.2
  TOP w0.152: U9.18 110.77,110.85 110.87,110.74 v1(110.87,110.24)
  BOTTOM w0.152: C358.2 R370.1 v1(110.87,110.24)
UTDO: length 3
  TOP w0.152: U9.21 v1(110.87,108.43)
  BOTTOM w0.152: R380.1 110.46,107.31 110.87,107.72 v1(110.87,108.43)
UTMS: length 4.6
  TOP w0.152: v1(122.91,110.87) 122.91,110.26 122.7,110.06 U9.37
  BOTTOM w0.152: v1(122.91,110.87) 122.91,110.88 122.86,110.83 122.86,110.83 122.14,110.11 121.67,110.11 121.48,110.29 R369.1
UTMSK: length 3.1
  TOP w0.152: U9.30 116.92,104.17 117.63,103.45 R118.1
UTRSTN: length 4.2
  TOP w0.152: U9.36 120.27,109.25 119.54,109.98 119.54,109.97 v1(119.61,109.91)
  BOTTOM w0.152: R376.1 120.8,109.65 119.87,109.65 119.54,109.98 119.54,109.97 v1(119.61,109.91)
VAA1: length 9.7
  BOTTOM w0.254: 30.04,30.16 30.23,30.36 U75.28
  BOTTOM w0.381: 30.04,30.16 29.34,29.46 C802.2 C801.1 C800.1 C799.1 FB33.2
VAA2_0: length 11.8
  TOP w0.381: FB11.2 C234.1 C235.1 32.67,27.37 32.63,27.33 32.11,27.33 32.07,27.37 C236.1 C237.2 30.1,28.07 30.84,28.8 30.84,29.82 v2(32.26,31.24)
  BOTTOM w0.203: U75.23 32.97,30.99 32.72,31.24 32.7,31.24 v2(32.26,31.24)
VAA2_1: length 10.5
  TOP w0.381: FB10.2 42.48,28.39 41.97,28.9 C229.1 40.84,28.9 40.59,28.64 C230.1 C231.1 C232.2 35.85,28.64 35.37,29.13 v2(35.37,31.16)
  BOTTOM w0.203: U75.17 v2(35.37,31.16)
VCONT_10: length 21.9
  TOP w0.508: v2(44.02,29.06) 44.04,29.06 45.94,30.95 Q9.1
  L3_SIG1 w0.381: v2(44.02,29.06) 43.66,29.06 42.87,28.26 41.59,28.26 40.03,29.82 40.03,31.83 38.85,33.01 31.6,33.01 v1(31,32.41)
  BOTTOM w0.203: U75.32 v1(31,32.41)
VER0: length 9.6
  TOP w0.127: v1(140.22,108.88) U15.C4
  TOP w0.152: v1(134.87,112.39) R96.2 R87.1
  BOTTOM w0.152: v1(140.22,108.88) 139.1,108.88 135.59,112.39 v1(134.87,112.39)
VER1: length 7.7
  TOP w0.152: R78.1 R92.2 137.52,113.54 137.73,113.33 137.73,112.6 138.02,112.3 138.72,112.3 139.42,111.6 139.42,109.68 U15.B3
VER2: length 6.8
  TOP w0.152: U15.B4 140.23,109.67 140.23,110.7 140.22,110.72 140.22,111.54 138.23,113.53 R91.2 R77.1
VER3: length 5.2
  TOP w0.152: R76.1 140.27,114.49 140.2,114.43 140.2,114.05 140.27,113.98 R90.2 140.27,112.67 140.52,112.42 140.52,110.18 U15.A4
VPP1V8: length 107.3
  TOP w0.254: R49.2 v2(108.08,124.97) ; U23.M9 v4(66.38,67.76) ; U23.K9 v4(67.98,67.76)
  L10_SIG4 w0.152: 68.59,68.16 71.34,68.16 71.57,68.39 71.57,74.52
  L10_SIG4 w0.165: v4(67.98,67.76) 68.38,68.16 68.59,68.16
  L10_SIG4 w0.381: 71.57,74.52 71.57,75.05 77.45,80.93 77.45,91.28 72.1,96.63 72.1,101.65 71.21,102.54 71.21,105.93 70.54,106.6 70.54,108.81 67.72,111.63 67.72,113.38 78.94,124.6 87.03,124.6 87.04,124.59 99.14,124.59 100.93,126.38 106.67,126.38 v2(108.08,124.97)
  BOTTOM w0.254: C511.1 v4(66.38,67.76) ; U63.A1 83.11,69.68 82.91,69.48 C478.1 v2(80.21,69.48)
VPP1V8_MON: length 4.4
  TOP w0.152: R49.1 110.11,124.97 110.41,125.27 110.41,127.22 110.72,127.54 U4.46
XDS200_EMU0: length 52.9
  TOP w0.152: R115.2 120.25,100.7 120.18,100.62 v4(120.18,100.23)
  L3_SIG1 w0.107: v4(120.18,100.23) 120.18,100.62 121.38,101.82 121.38,103.29 120.58,104.09 120.58,107.56 120.9,107.88 120.9,121.45 119.13,123.22 115.7,123.22 115.09,123.83 109.6,123.83 108.94,123.16 107.16,123.16 104.77,120.78 102.44,120.78 102.08,121.13 100.05,121.13 98.53,122.66 v1(95.48,122.66)
  BOTTOM w0.152: U49.10 95.02,122.45 95.22,122.66 v1(95.48,122.66)
XDS200_EMU1: length 43.1
  TOP w0.152: R116.2 120.42,102.55 119.56,101.69 118.24,101.69 116.87,100.32 113.31,100.32 112.82,100.82 v1(112.82,101.23)
  BOTTOM w0.152: U49.13 96.52,122.47 96.82,122.78 99.09,122.78 99.69,122.18 99.69,113.16 101.21,111.63 103.76,111.63 105.84,109.55 105.84,105.77 110.38,101.23 v1(112.82,101.23)
XDS200_TCK: length 66.5
  L3_SIG1 w0.107: v1(89.26,123.29) 90.32,124.35 99.61,124.35 102.14,121.82 104.87,121.82 106.44,123.39 108.85,123.39 109.51,124.05 115.18,124.05 115.79,123.44 119.23,123.44 121.13,121.54 121.13,107.92 121.37,107.69 121.37,105.67 v1(121.06,105.36)
  BOTTOM w0.152: v1(89.26,123.29) 90.12,122.43 90.12,118.77 90.61,118.28 92.94,118.28 94.41,116.8 96.45,116.8 97.02,117.37 U49.3 ; v1(121.06,105.36) 120.82,105.59 R382.2
XDS200_TDI: length 47.3
  TOP w0.152: U7.3 v1(84.38,117.97)
  L3_SIG1 w0.107: v1(115.52,110.27) 115.03,109.78 105.46,109.78 103.43,111.81 100.62,111.81 94.89,117.53 94.89,120.7 92.94,122.66 90.1,122.66 88.42,120.98 88.42,120.58 87.12,119.28 85.69,119.28 v1(84.38,117.97)
  BOTTOM w0.152: R366.2 117.13,111.89 v1(115.52,110.27)
XDS200_TDO: length 34
  TOP w0.152: U7.13 89.73,117.47 89.92,117.65 89.92,119 v1(89.1,119.81)
  L3_SIG1 w0.107: v1(89.1,119.81) 90.78,121.49 92.91,121.49 94.44,119.96 94.44,113.81 100.43,107.82 102.7,107.82 102.72,107.81 107.71,107.81 v1(108.2,107.31)
  BOTTOM w0.152: R380.2 v1(108.2,107.31)
XDS200_TMS: length 60.3
  TOP w0.152: U7.6 v1(83.77,116.47) ; R118.2 117.68,102.55 117.03,101.9 v1(117.03,101.9)
  L3_SIG1 w0.107: v1(83.77,116.47) 84.45,116.47 87.03,119.05 87.5,119.05 89.13,120.68 89.48,120.68 90.52,121.72 93.17,121.72 94.67,120.22 94.67,113.91 100.52,108.05 114.1,108.05 v1(115.63,109.59) 116.18,109.04 116.18,102.74 117.03,101.9 v1(117.03,101.9)
  BOTTOM w0.152: R369.2 116.54,110.49 v1(115.63,109.59)
XDS200_TRST#: length 46.9
  TOP w0.152: v1(88.47,115.47) 88.47,115.47 88.72,115.72 U7.10
  L3_SIG1 w0.107: v1(115.53,108.54) 113.93,106.93 107.82,106.93 107.18,107.58 100.35,107.58 94.21,113.72 94.21,119.86 92.81,121.26 91.8,121.26 88.47,117.93 v1(88.47,115.47)
  BOTTOM w0.152: R376.2 116.09,109.09 v1(115.53,108.54)
XDS_1V2: length 34.8
  TOP w0.254: v1(143.42,105.68) U15.G8 ; U15.L14 v1(149.02,101.68) ; v2(148.84,76.61) C100.1 R202.1 ; U15.E15 v1(149.82,107.28) ; U15.K6 v1(141.82,103.28) U15.J6 ; U15.M9 v1(144.22,100.88) U15.N8 ; U15.H7 v1(142.62,104.88) U15.G7 ; U15.M8 v1(143.42,100.88) U15.N7 ; v1(148.22,104.88) U15.H14 ; v1(148.22,104.88) U15.G13 ; v1(148.22,104.88) U15.H13 v1(147.42,104.88) U15.H12 v1(146.62,104.88) U15.H11 v1(145.82,104.88) U15.H10 ; U15.M12 v1(147.42,101.68) U15.L12 v1(147.42,102.48) U15.K12 v1(147.42,103.28) U15.J12 ; U15.H6 v1(141.82,104.08) ; v1(141.82,107.28) U15.E5
  BOTTOM w0.254: v1(149.82,107.28) 150.47,107.28 C369.1 ; v1(141.82,104.08) 142.37,104.08 142.53,103.93 C382.1 142.46,103.28 v1(141.82,103.28) ; v1(147.42,102.48) 146.66,101.73 C386.1 ; C393.1 143.15,100.2 143.42,100.47 v1(143.42,100.88) ; v1(144.22,100.88) 144.02,100.69 C392.1 ; C367.1 139.8,106.9 v1(140.22,106.48) 140.38,106.64 C366.1 141.18,106.64 v1(141.82,107.28) ; C385.1 v1(153.85,103.86) ; v1(147.42,101.68) 147.05,101.32 146.91,101.32 146.66,101.07 C390.1 ; v1(147.42,104.88) 147.03,104.5 C380.1 147.03,103.67 v1(147.42,103.28) ; C381.1 145.18,103.52 145.54,103.88 145.54,104.61 v1(145.82,104.88) ; v1(142.62,104.88) 142.66,104.93 C378.1 143.21,105.48 v1(143.42,105.68)
  vias: v2(131.07,87.38) v2(131.08,86.42) v2(131.88,87.38) v2(131.93,86.42) v2(132.51,78.94) v2(132.49,77.77) v2(133.35,78.94) v2(133.32,77.77) v2(163.68,93.57) v2(163.7,92.79) v2(164.54,92.81)
XDS_1V8: length 21.6
  TOP w0.254: U15.K5 v1(141.82,102.48) U15.L6 ; U15.G11 v1(146.62,105.68) U15.G12 ; v2(149.72,86.63) v2(149.72,85.87) ; U15.G6 v1(141.82,104.88) ; U15.G10 v1(145.82,105.68) ; v1(110.9,112.52) 110.9,112.98 110.64,113.23 U9.15 ; U15.P13 v1(147.42,99.28) U15.R13 ; U15.J13 v1(148.22,104.08) ; U15.F14 v1(148.22,106.48) ; R122.2 v2(112.37,101.85)
  BOTTOM w0.254: v1(148.22,104.08) 148.76,104.63 C377.1 ; C379.1 140.81,104.52 140.83,104.54 141.47,104.54 v1(141.82,104.88) ; FB19.1 v2(149.72,86.63) ; C354.1 109.15,112.77 109.4,112.52 v1(110.9,112.52) ; v1(147.42,99.28) 147.57,99.13 C399.1 ; v1(148.22,106.48) 147.56,105.82 C370.1 146.76,105.82 v1(146.62,105.68) ; C364.1 145.66,105.84 v1(145.82,105.68) ; U61.3 R415.1 161.22,84.71 161.42,84.91 v2(161.66,84.91) ; C387.1 141.71,102.38 v1(141.82,102.48)
  vias: v2(145.21,92.68) v2(145.21,91.92) v2(145.97,92.68) v2(145.97,91.92) v2(154.23,81.99) v2(154.25,82.96) v2(155.14,81.99) v2(155.17,82.96)
XDS_BOOTMODE[0]: length 10.7
  TOP w0.152: U15.U3 140.2,96.9 140.77,96.9 141,96.67 141,95.02 140.36,94.39 139.37,94.39 138.51,93.52 R168.1 138.92,92.04 139.14,91.82 139.14,90.35 138.67,89.88 R175.2
XDS_BOOTMODE[1]: length 6.9
  TOP w0.152: U15.T1 137.88,98.08 136.98,97.18 133.73,97.18 133.28,97.62 R152.1 R153.2
XDS_BOOTMODE[2]: length 7.9
  TOP w0.152: R159.2 R158.1 133.28,96.3 133.67,96.7 136.93,96.7 137.92,97.69 138.62,97.69 U15.T2
XDS_BOOTMODE[3]: length 10.4
  TOP w0.152: R176.2 136.55,89.88 136.39,90.05 136.39,91.71 136.72,92.04 R169.1 137.03,92.68 139.4,95.05 139.4,95.52 139.4,95.53 139.4,95.84 139.4,95.85 139.4,96.32 139.4,96.33 139.4,96.64 139.4,96.64 139.4,97.12 139.4,97.13 139.4,97.44 139.4,97.45 139.4,97.66 U15.T3
XDS_BOOTMODE[4]: length 7.5
  TOP w0.152: U15.R1 137.13,98.88 136.18,99.84 134.51,99.84 134.34,100 133.78,100 133.3,100.48 133.3,101.07 R141.2 R142.2
XDS_BOOTMODE[5]: length 9.6
  TOP w0.152: U15.R2 138.6,99.3 137.19,99.3 135.99,100.5 135.99,101.84 135.73,102.1 133.48,102.1 133.28,102.3 R125.2 R126.2
XDS_BOOTMODE[6]: length 8.7
  TOP w0.127: v1(139.42,98.48) U15.R3
  TOP w0.152: v1(139.42,98.48) 133.67,98.48 133.28,98.88 R148.2 R149.2
XDS_BOOTMODE[7]: length 11.9
  TOP w0.152: R111.2 R110.2 133.28,103.83 133.5,103.61 135.26,103.61 135.98,102.88 135.98,102.28 136.49,101.77 136.49,100.64 137.03,100.1 140.2,100.1 U15.P4
XDS_RTCK: length 23.8
  L8_SIG3 w0.107: v1(95.54,117.52) 95.54,117.52 95.52,117.52 95.52,116.75 95.02,116.25 95.02,113.09 97.94,110.16 97.94,110.13 98.04,110.03 100.05,110.03 102.15,107.93 102.15,106.29 102.81,105.64 107.92,105.64 v1(108.2,105.92)
  BOTTOM w0.152: v1(95.54,117.52) 95.54,117.52 95.52,117.52 U49.6 ; R383.2 v1(108.2,105.92)
XDS_SYS_RESETN: length 2.8
  TOP w0.152: v2(155.68,93.15) 155.64,93.12 155.64,91.34 U19.1
  BOTTOM w0.152: R396.1 v2(155.68,93.15)
XDS_USB_DM: length 23.5
  TOP w0.114: U15.M18 v1(152.22,100.88)
  L10_SIG4 w0.102: v1(152.22,100.88) 152.51,100.59 152.51,100.4 152.9,100.01 160.9,100.01 161.76,100.87 167.6,100.87 v2(167.84,100.62)
  BOTTOM w0.114: D14.2 167.2,100.72 167.32,100.84 167.62,100.84 v2(167.84,100.62) 168.08,100.86 170.51,100.86 170.87,100.5 J3.2
XDS_USB_DP: length 23.5
  TOP w0.114: U15.M19 v1(153.02,100.88)
  L10_SIG4 w0.102: v2(167.84,101.33) 167.6,101.08 167.31,101.08 167.07,101.32 166.84,101.32 166.61,101.08 166.38,101.08 166.14,101.32 165.91,101.32 165.67,101.08 165.45,101.08 165.21,101.32 164.98,101.32 164.74,101.08 164.51,101.08 164.27,101.32 164.05,101.32 163.81,101.08 163.58,101.08 163.34,101.32 163.11,101.32 162.88,101.08 162.65,101.08 162.41,101.32 162.18,101.32 161.94,101.08 161.67,101.08 160.81,100.23 160.5,100.23 160.4,100.33 160.17,100.33 160.07,100.23 159.84,100.23 159.74,100.33 159.51,100.33 159.41,100.23 152.99,100.23 152.72,100.49 152.72,100.59 v1(153.02,100.88)
  BOTTOM w0.114: J3.3 170.77,101.3 170.56,101.09 170.25,101.09 170.09,101.24 169.85,101.24 169.69,101.09 169.45,101.09 169.3,101.24 169.06,101.24 168.9,101.09 168.08,101.09 v2(167.84,101.33) 167.58,101.07 167.31,101.07 167.15,101.22 D14.1
XDS_USB_GND: length 21.3
  BOTTOM w0.305: 166.25,99.64 D14.4
  BOTTOM w0.381: 175.33,96.62 J3.6 ; J3.6 178.37,96.62 ; J3.6 175.33,98.68 ; 166.25,99.64 166.25,98.85 166.45,98.65 175.06,98.65 ; 175.33,103.92 J3.7 ; J3.7 178.37,105.98 ; J3.7 175.33,105.98
XDS_USB_VBUS: length 134.7
  TOP w0.254: v3(154.04,96.01) 154.59,96.01 154.91,96.33 R156.2 ; R191.2 v2(138.49,84.91) ; v2(154.64,87.19) C67.1 U19.6 ; R203.2 v2(146.05,76.53)
  L3_SIG1 w0.254: 165.91,96.01 v2(165.94,96.04)
  BOTTOM w0.254: v2(138.48,86.13) 137.99,85.64 116.91,85.64 114.03,88.53 114.03,101.48 113,102.51 109.74,102.51 106.3,105.95 106.3,109.74 106.01,110.03 103.95,112.09 101.52,112.09 100.23,113.39 100.23,123.7 99.4,124.53 91.44,124.53 91.16,124.25 89.22,124.25 87.22,122.25 87.22,121.72 v2(86.11,120.6) R343.2
  BOTTOM w0.381: v2(142.54,85.14) 142.31,84.91 v2(138.49,84.91) ; U59.5 153.91,88.7 154.06,88.55 C435.1 ; C435.1 154.06,87.44 154.31,87.19 v2(154.64,87.19) ; C435.1 153.44,87.88 149.45,83.9 v2(149,83.9) 149,83.03 v2(148.97,83.01) 146.05,80.09 v2(146.05,76.53) 145.79,76.27 144.45,76.27 144.06,76.67 144.06,76.7 v2(143.81,76.94) 139.02,76.94 136.49,79.47 136.49,84.02 137.36,84.89 138.47,84.89 v2(138.49,84.91) ; v2(138.49,84.91) 138.49,86.12 v2(138.48,86.13)
  vias: v2(165.96,96.85)
XDS_VBUS: length 0.6
  BOTTOM w0.254: D14.6 v2(166.25,101.83)
XDS_VCC3V3: length 112.8
  TOP w0.127: v4(123.57,108.24) 123.46,108.35 123.46,108.38
  TOP w0.254: v2(154,86.56) 154,87.4 154.56,87.96 U19.5 ; v4(128.77,107.27) 128.76,107.26 C861.1 ; v1(140.22,98.48) U15.R4 ; v1(141.02,102.48) U15.L4 ; v1(146.62,99.28) U15.P12 ; R110.1 v1(135.12,104.39) ; C863.1 125.51,104.24 v4(125.74,104.47) ; R92.1 v1(135.48,113.54) ; R148.1 134.26,99.44 134.32,99.38 134.63,99.38 v1(134.78,99.24) ; C864.1 128.33,105.23 v4(128.77,105.67) ; U15.F6 v1(142.62,105.68) U15.F7 ; v1(134.73,102.93) 134.54,102.74 R125.1 ; U15.P6 v1(141.82,99.28) U15.P5 ; U15.G9 144.62,105.29 v1(144.22,105.68) U15.F8 ; U15.J14 v1(149.02,104.08) ; R141.1 134.64,101.09 134.9,100.83 134.9,100.82 v1(134.91,100.81) ; U15.F5 v1(141.02,105.68) U15.G5 ; R72.1 v1(142.62,118.11) ; R96.1 v1(132.66,112.39) ; U15.G15 v1(149.82,105.68) U15.F15 ; U15.J5 v1(141.02,104.08) U15.H5 ; C865.1 123.46,108.38 ; R114.2 v2(163.58,103) ; U9.35 119.53,108.43 v1(119.4,108.56) ; C862.1 125.8,107.74 v4(125.74,107.67) ; R158.2 v1(134.82,96.14) ; U15.F12 v1(146.62,106.48) U15.F11 v1(145.82,106.48) U15.F10 ; v2(137.77,90.47) 137.26,90.47 137.03,90.7 R169.2 R168.2 ; U15.L13 v1(148.22,102.48) U15.K13 ; R185.2 143.69,83.97 143.9,83.77 U20.15 ; v1(155.5,112.19) 155.5,112.32 156.41,111.41 R97.1 ; U15.K15 v1(149.82,102.48) ; R123.2 v2(110.97,101.93) ; U15.N13 v1(147.42,100.88) U15.M13 ; R101.1 v1(156.41,110.45) ; C860.1 126.1,105.71 v4(125.74,106.07) ; R90.1 v1(141.17,112.78) ; U15.G14 v1(148.22,105.68) U15.F13 ; v1(149.02,107.28) U15.E14 ; v2(151.64,90.2) 151.18,90.2 150.88,90.5 R166.2 ; R152.2 v1(134.8,97.79) ; v1(139.13,114.35) R91.1 ; U5.8 v2(149.86,120.14) ; TP10.1 v2(114.53,118.62) U9.7
  BOTTOM w0.254: v1(156.41,110.45) R101.1 ; U78.E7 v4(125.74,104.47) ; R350.2 v2(113.13,118.62) ; R345.2 R342.2 v2(144.65,120.27) ; U78.D3 v4(128.77,105.67) ; v2(114.53,118.62) C350.1 C349.1 ; v1(111.48,112.12) 111.58,112.01 111.58,111.24 111.24,110.9 110.34,110.9 110.05,111.18 R367.1 ; v2(110.05,116.84) R354.2 ; v1(149.02,104.08) 149.13,104.08 149.82,103.4 C384.1 v1(149.82,102.48) ; R362.2 v1(154.33,113.47) ; C372.1 140.23,105.68 v1(141.02,105.68) ; U78.B3 v4(128.77,107.27) ; R371.2 v2(176.22,110.18) R372.2 v2(174.09,110.18) R373.2 173.02,110.95 172.75,111.23 157.88,111.23 157.59,110.94 157.59,110.45 157.54,110.4 ; v2(149.86,116.97) 150.37,116.97 150.5,117.09 R352.2 R355.2 ; v1(147.42,100.88) 147.95,101.42 C388.1 148.22,101.48 v1(148.22,102.48) ; R397.1 v2(152.68,93.15) ; v1(145.82,106.48) 145.82,107.16 C363.1 ; v1(141.82,99.28) 141.53,99 C402.1 140.3,98.57 v1(140.22,98.48) ; C400.1 146.43,99.1 v1(146.62,99.28) ; v1(149.82,105.68) 149.97,105.53 C373.1 ; v1(144.22,105.68) 143.59,106.31 C365.1 ; R346.2 C347.1 v2(149.86,120.14) ; R363.1 v1(152.68,113.47) ; R598.2 v1(148.69,116.22) ; C362.1 120.62,108.43 119.53,108.43 v1(119.4,108.56) ; v1(141.02,102.48) 140.64,102.48 140.25,102.87 C383.1 140.25,103.65 140.69,104.08 v1(141.02,104.08) ; 157.54,110.4 R374.2 ; 157.54,110.4 v1(157.54,110.45) ; U78.C7 v4(125.74,106.07) ; U78.J9 v4(123.17,100.87) ; v1(148.22,105.68) 148.86,106.33 C359.1 148.86,107.13 v1(149.02,107.28) ; R398.2 v2(151.64,90.2) ; U78.A9 v4(123.57,108.24) ; R409.2 v2(161.54,88.27) ; U78.A7 v4(125.74,107.67)
  vias: v1(135.71,97.76) v1(136.84,97.76) v2(122.02,100.23) v2(122.02,98.84) v2(144.48,89.28) v2(144.48,88.37) v2(145.24,89.28) v2(145.24,88.37) v2(165.28,99.82) v2(165.28,98.98) v2(165.28,98.17)
XFICLKN: length 42.8
  TOP w0.102: U23.AJ12 v4(51.98,65.36) ; v1(61.8,89.4) 62,89.6 62.23,89.6 62.5,89.87 64.2,89.87 64.54,90.21 64.54,90.5 64.67,90.63 U18.15
  L8_SIG3 w0.102: v1(61.8,89.4) 61.98,89.58 62.13,89.58 62.52,89.19 62.52,86.91 61.42,85.81 59.82,85.81 59.19,85.19 59.19,84.25 57.96,83.03 57.96,81 52.82,75.86 48.08,75.86 47.03,74.8 47.03,68.69 49.66,66.07 49.95,66.07 50.22,65.79 51.54,65.79 v4(51.98,65.36)
XFICLKP: length 42.7
  TOP w0.102: U23.AJ11 v4(51.98,66.16) ; U18.14 64.17,90.62 64.29,90.5 64.29,90.31 64.09,90.12 62.4,90.12 62.13,89.85 62,89.85 v1(61.8,90.06)
  L8_SIG3 w0.102: v4(51.98,66.16) 51.61,66.53 50.22,66.53 50.05,66.36 49.78,66.36 49.62,66.52 49.62,66.72 49.45,66.88 49.26,66.88 49.1,67.04 49.1,67.24 48.93,67.4 48.74,67.4 48.58,67.56 48.58,67.76 48.41,67.92 48.22,67.92 48.06,68.08 48.06,68.28 47.9,68.44 47.7,68.44 47.32,68.82 47.32,74.68 48.2,75.56 52.94,75.56 58.25,80.88 58.25,82.91 59.48,84.13 59.48,85.07 59.94,85.52 61.54,85.52 62.81,86.79 62.81,89.31 62.26,89.87 61.98,89.87 v1(61.8,90.06)
N854872: length 20.4
  TOP w0.127: U23.AH5 v4(52.78,70.96)
  BOTTOM w0.127: v4(52.78,70.96) 53.15,71.34 53.15,71.92 52.88,72.18 51.82,72.18 51.55,72.45 51.55,72.72 51.33,72.93 51.33,74.68
  BOTTOM w0.152: R632.1 R631.1 44.37,84.26 46.81,81.81 46.81,81.18 51.33,76.66 51.33,74.68
N854876: length 19.6
  TOP w0.127: U23.AH6 v4(52.78,70.16)
  BOTTOM w0.152: v4(52.78,70.16) 52.39,70.55 51.03,70.55 50.79,70.8 50.79,75.08 50.56,75.31 R630.1 R629.1
N859795: length 32.3
  TOP w0.152: R645.1 R646.1 50.72,90.35 v1(50.97,90.61) ; U23.AE7 v4(55.18,69.36)
  L10_SIG4 w0.107: v4(55.18,69.36) 54.81,69.73 54.81,71.11 55.09,71.39 55.33,71.39 55.54,71.61 55.54,76.85 48.32,84.07 47.48,84.07 47.19,84.36 47.19,85.52 49.48,87.81 51.03,87.81 51.23,88.01 51.23,88.77 50.55,89.46 50.55,90.18 v1(50.97,90.61)
N859809: length 25.8
  TOP w0.152: U23.AF6 v4(54.38,70.16) ; v5(43.14,87.65) 43.43,87.94 R644.1 R643.1
  L10_SIG4 w0.107: v4(54.38,70.16) 54.38,70.44 54.01,70.81 54.01,71.11 54.22,71.33 54.47,71.33 54.74,71.61 54.74,71.91 54.47,72.19 54.22,72.19 53.94,72.47 53.94,74.14 43.8,84.29 43.8,87 v5(43.14,87.65)
N12934666: length 4
  TOP w0.152: CN3.1 v1(102.11,136.14)
  BOTTOM w0.152: v1(102.11,136.14) R311.2
N13012268: length 2.6
  TOP w0.152: v1(135.23,146.25) 135.19,146.22 U1.96
  BOTTOM w0.152: R290.2 135.1,145.48 135.19,145.58 135.19,146.22 v1(135.23,146.25)
N13662493: length 3.8
  TOP w0.152: CN3.2 102.11,144.15 102.36,144.4 v1(102.36,144.91)
  BOTTOM w0.152: R304.2 v1(102.36,144.91)
N13662497: length 3.8
  TOP w0.152: v1(103.89,144.89) 103.38,144.39 CN3.4
  BOTTOM w0.152: v1(103.89,144.89) R303.2
N13662501: length 3.9
  TOP w0.152: CN3.6 104.65,144.13 v1(105.41,144.89)
  BOTTOM w0.152: v1(105.41,144.89) R302.2
N13662505: length 4.4
  TOP w0.152: CN3.8 105.92,144.4 106.41,144.89 v1(106.93,144.89)
  BOTTOM w0.152: v1(106.93,144.89) R301.2
N13662509: length 4.5
  TOP w0.152: CN3.10 107.19,144.27 107.81,144.89 v1(108.46,144.89)
  BOTTOM w0.152: v1(108.46,144.89) R300.2
N14462583: length 1.1
  TOP w0.152: U23.AJ27 v4(51.98,52.56)
  BOTTOM w0.127: R479.1 v4(51.98,52.56)
N14463052: length 1.1
  TOP w0.152: U23.AG14 v4(53.58,63.76)
  BOTTOM w0.127: R460.1 v4(53.58,63.76)
N14463586: length 1.1
  TOP w0.152: U23.AJ5 v4(51.98,70.96)
  BOTTOM w0.254: R434.2 v4(51.98,70.96)
N14466276: length 1.1
  TOP w0.152: U23.AH7 v4(52.78,69.36)
  BOTTOM w0.127: R441.2 v4(52.78,69.36)
N14466300: length 1.1
  TOP w0.152: U23.AG10 v4(53.58,66.96)
  BOTTOM w0.127: R446.2 v4(53.58,66.96)
N14466840: length 1.1
  TOP w0.254: U23.Y6 v4(59.18,70.16)
  BOTTOM w0.254: R438.2 v4(59.18,70.16)
N14469420: length 1.1
  TOP w0.152: U23.G12 v4(70.38,65.36)
  BOTTOM w0.254: R454.1 v4(70.38,65.36)
N14469428: length 1.2
  TOP w0.152: U23.G18 v4(70.38,59.76)
  BOTTOM w0.254: R467.1 v4(70.38,59.76)
N14469440: length 1.2
  TOP w0.152: U23.E15 v4(71.98,62.96)
  BOTTOM w0.254: R465.1 v4(71.98,62.96)
N14711749: length 3.2
  TOP w0.254: U4.34 113.57,133.83 113.4,134
  TOP w0.381: 113.4,134 112.29,135.1 C9.1
N14714084: length 3
  TOP w0.152: R60.1 114.4,123.8 115.07,124.46 U4.6
N14714150: length 3.5
  TOP w0.152: R61.1 112.9,123.95 113.16,124.21 113.67,124.21 114.07,124.61 U4.4
N14714160: length 3.8
  TOP w0.152: U4.5 v1(114.57,124.85)
  BOTTOM w0.152: v1(114.57,124.85) 113.82,124.1 113.82,123.29 113.63,123.11 R337.1
N14715464: length 3.9
  TOP w0.152: R36.2 120.96,127.93 120.57,128.32 120.57,128.75 119.79,129.54 U4.19
N14715500: length 3.9
  TOP w0.152: R30.2 v1(120.96,129.39) 120.43,129.39 119.78,130.04 U4.20
  BOTTOM w0.152: R30.2 v1(120.96,129.39)
N14716011: length 6.4
  TOP w0.152: U4.31 115.07,134.16 114.74,134.49 113.67,134.49 113.54,134.62 R15.2 113.98,135.06 114.16,135.24 114.16,136.54 TP4.1
N14719575: length 3
  TOP w0.152: U4.43 v2(110.88,129.04)
  BOTTOM w0.152: R325.2 110.11,127.76 110.88,128.53 v2(110.88,129.04)
N14725158: length 3.2
  TOP w0.152: U4.7 v1(115.57,124.85)
  BOTTOM w0.152: v1(115.57,124.85) 114.43,123.71 R336.1
N14733790: length 2.3
  TOP w0.152: R26.1 120.14,130.18 119.78,130.54 U4.21
N14872798: length 2.4
  TOP w0.152: R133.2 64.3,102.93 64.01,103.23 C34.2
N14873463: length 4.1
  TOP w0.254: R134.2 85.31,102.67 84.59,102.67 84.04,103.22 84.04,104.92 84.22,105.1 C36.2
N14877032: length 7.2
  TOP w0.102: R602.1 R178.2 78.92,88.7 79.08,88.86 79.08,92.2 79.37,92.5 80.02,92.5 80.15,92.62 U17.11
N15165762: length 2.7
  TOP w0.152: U4.26 117.57,133.72 118.49,134.65 R12.1
N15571799: length 3.6
  TOP w0.152: CN1.1 R9.1
N15783945: length 4.6
  TOP w0.152: R56.1 120.4,123.58 119.7,124.28 118.36,124.28 117.57,125.08 U4.11
N16053779: length 2.3
  TOP w0.152: v1(132.67,134.06) 132.66,134.06 132.57,134.16 U1.19
  BOTTOM w0.152: R319.2 132.49,133.99 132.57,134.06 132.66,134.06 v1(132.67,134.06)
N16114816: length 3.9
  TOP w0.152: U4.14 119.33,127.04 119.63,126.73 119.63,125.83 120.96,124.5 R50.1
N16281952: length 2.7
  TOP w0.152: RST_BMC1.2 114.24,144.99 v1(113.54,145.69)
  BOTTOM w0.152: v1(113.54,145.69) R297.1
N16316172: length 2.3
  TOP w0.152: v1(132.59,135) 132.43,135.16 U1.17
  BOTTOM w0.152: R318.2 132.19,135.38 132.42,135.15 132.44,135.15 v1(132.59,135)
N16319325: length 3.2
  TOP w0.152: U1.61 148.75,136.16 149.41,135.5 R16.1
N16321972: length 2
  BOTTOM w0.152: U41.10 137.8,137.04 137.61,136.85 R317.1
N16474415: length 1.3
  TOP w0.152: R89.1 D5.1
N16474431: length 6.4
  TOP w0.152: D5.2 177.16,112.15 176.4,112.9 176.4,114.17 175.48,115.09 Q6.3
N16572263: length 3
  TOP w0.152: U1.16 132.49,135.66 132.54,135.61 v1(132.59,135.61)
  BOTTOM w0.152: R312.2 132.21,136.78 132.59,136.4 v1(132.59,135.61)
N16795853: length 3.5
  TOP w0.152: U4.25 118.07,133.79 119.33,135.06 R11.1
N16795860: length 4.5
  TOP w0.152: U4.24 118.82,133.8 119.63,134.62 R17.1
N16800870: length 3.1
  TOP w0.152: Q6.1 173.8,113.97 173.55,114.22 R75.2
N16809812: length 2.5
  TOP w0.152: CN7.81 R54.1
N16865403: length 3.2
  BOTTOM w0.152: Q14.1 173.8,113.6 173.3,113.1 R365.2
N16865412: length 1.6
  TOP w0.152: D6.1 v1(179.2,108.2)
  BOTTOM w0.152: R377.1 v1(179.2,108.2)
N16865430: length 5.8
  TOP w0.152: v1(178.23,111.38) 178.23,110.82 178.49,110.56 D6.2
  BOTTOM w0.152: Q14.3 177.58,112.49 178.23,111.83 v1(178.23,111.38)
N16865801: length 3.2
  BOTTOM w0.152: R328.2 173.68,128.39 173.93,128.64 Q11.1
N16865808: length 1.5
  TOP w0.152: D3.2 R32.1
N16865818: length 4.2
  TOP w0.152: D3.1 177.16,129.92 176.69,129.45 Q3.3
N16865822: length 1.5
  TOP w0.152: D4.2 178.35,125.04 178.08,124.77 R47.1
N16865834: length 4.3
  TOP w0.152: v1(177.67,126.36) 177.95,126.64 D4.1
  BOTTOM w0.152: Q11.3 177.2,126.84 v1(177.67,126.36)
N16865898: length 3.3
  TOP w0.152: Q3.1 173.93,127.64 173.68,127.89 R27.2
N16869469: length 1.4
  TOP w0.152: R108.2 C42.1
N16870184: length 1.4
  BOTTOM w0.152: C45.1 R112.2
N16947500: length 1.3
  TOP w0.152: R46.2 C18.1
N16951277: length 1.1
  TOP w0.152: U23.AJ22 v4(51.98,56.56)
  BOTTOM w0.127: R472.1 v4(51.98,56.56)
N16953830: length 1.1
  TOP w0.152: U23.AJ10 v4(51.98,66.96)
  BOTTOM w0.127: R449.1 v4(51.98,66.96)
N16953906: length 3.3
  BOTTOM w0.102: U75.33 29.52,32.81 29.44,32.88 29.07,32.88 28.93,32.74 27.41,32.74 27.25,32.58 C782.1
N16953908: length 3.7
  BOTTOM w0.102: U75.39 29.52,35.21 29.44,35.13 28.77,35.13 28.19,35.71 28.03,35.71 27.82,35.93 27.38,35.93 27.25,36.06 C769.1
N16953910: length 3.7
  BOTTOM w0.102: U75.38 29.52,34.81 29.44,34.88 28.67,34.88 28.09,35.46 27.93,35.46 27.71,35.67 27.38,35.67 27.25,35.54 C770.1
N16953912: length 3.5
  BOTTOM w0.102: U75.34 29.52,33.21 29.44,33.13 28.97,33.13 28.83,32.99 27.56,32.99 27.25,33.31 C771.1
N16954088: length 6.3
  TOP w0.152: v1(28.71,28.14) 28.32,27.76 TP58.1
  L3_SIG1 w0.107: v1(31.37,31.24) 31.37,30.45 29.06,28.14 v1(28.71,28.14)
  BOTTOM w0.203: U75.27 v1(31.37,31.24)
N16997326: length 3.7
  BOTTOM w0.102: C816.2 129.01,21.27 128.91,21.17 128.91,20.48 129.14,20.24 129.75,20.24 130.1,19.9 130.1,19.63 130.22,19.51 U77.2
N16997342: length 3.7
  BOTTOM w0.102: C817.2 128.55,21.27 128.65,21.17 128.65,20.37 129.03,19.99 129.65,19.99 129.84,19.8 129.84,19.6 129.72,19.48 U77.1
N17001107: length 3.9
  BOTTOM w0.152: R576.1 137.72,8.64 137.07,9.28 137.07,9.28 137.03,9.33 135.72,10.64 U77.30
N17001211: length 4.8
  BOTTOM w0.152: TP88.1 138.39,9.88 136.93,9.88 136.22,10.59 U77.29
N17001218: length 3.2
  BOTTOM w0.152: TP89.1 136.78,8.64 135.22,10.2 U77.31
N17001225: length 4.5
  BOTTOM w0.152: U77.32 134.72,10.26 136.04,8.95 136.04,8.17 TP90.1
N17007218: length 4.7
  TOP w0.152: J4.C2 12.86,88.46 12.86,86.34 12.7,86.17 R190.1
N17199371: length 20
  TOP w0.254: R264.2 168.45,7.75 167.07,9.13 167.07,16.09 167.85,16.88 172.29,16.88 172.68,16.48 J9.12A
N17199383: length 5.8
  TOP w0.254: J9.14A 172.04,27.68 172.04,31.76 172.22,31.94 R248.2
N17200454: length 2.5
  BOTTOM w0.152: R568.1 126.82,16.42 127.2,16.81 128.38,16.81 128.39,16.8 U77.53
N17200461: length 4.2
  BOTTOM w0.152: U77.56 128.2,18.3 127.53,18.97 127.53,20.51 127.21,20.83 R559.1
N17200465: length 3.2
  BOTTOM w0.152: U77.55 127.74,17.8 126.82,18.73 R562.1
N17200469: length 2.4
  BOTTOM w0.152: U77.54 127.66,17.3 127.18,17.78 R564.1
N17200473: length 3
  BOTTOM w0.152: R571.1 126.82,15.29 127.32,15.79 129.01,15.79 U77.51
N17200477: length 3.9
  BOTTOM w0.152: R572.1 127.21,13.21 127.73,13.73 127.73,15.08 127.96,15.31 128.38,15.31 128.39,15.3 U77.50
N17204930: length 1.6
  BOTTOM w0.508: C831.1 154.63,16.45 J9.9A
N17205278: length 3.8
  BOTTOM w0.152: TP87.1 134.87,20.7 133.72,19.55 U77.9
N17206950: length 9.5
  BOTTOM w0.152: Y8.3 134.68,5.19 C844.2 134.68,9.35 134.22,9.8 U77.33
N17206970: length 6.2
  BOTTOM w0.152: Y8.1 132.93,6.13 133.42,6.62 R579.1 C845.2 133.42,9.13 133.72,9.43 U77.34
N17261802: length 2.8
  TOP w0.152: R33.1 109.67,128.26 109.94,128.54 U4.44
N17416492: length 3.1
  BOTTOM w0.152: R552.1 39.3,31.43 39.12,31.61 U75.13
N17426925: length 3.9
  TOP w0.152: v1(28.19,31.5) 27.38,31.5 27.25,31.63 R250.1
  BOTTOM w0.152: U75.31 28.71,32.01 v1(28.19,31.5)
N17447628: length 9.5
  BOTTOM w0.152: Y6.3 23.43,31.79 24.16,31.06 R554.1 26,31.06 26.9,30.16 C791.2 28.4,30.16 28.76,30.51 28.76,31.17 29.19,31.61 U75.30
N17447634: length 12.8
  BOTTOM w0.152: U75.29 29.45,31.21 29.16,30.91 29.16,30.22 27.97,29.03 C795.2 R555.1 R554.2 21.22,30.16 21.02,29.96 Y6.1
N17448646: length 3.6
  BOTTOM w0.152: R510.2 32.83,39.94 31.77,38.88 U75.45
N17467804: length 2.9
  BOTTOM w0.152: U77.41 130.22,9.63 129.54,8.95 C848.1
N17467824: length 7.7
  BOTTOM w0.152: C848.2 129.54,6.86 129.92,6.48 131.32,6.48 131.7,6.86 131.7,9.27 132.23,9.8 132.23,10.53 132.21,10.55 132.21,11.09 U77.37
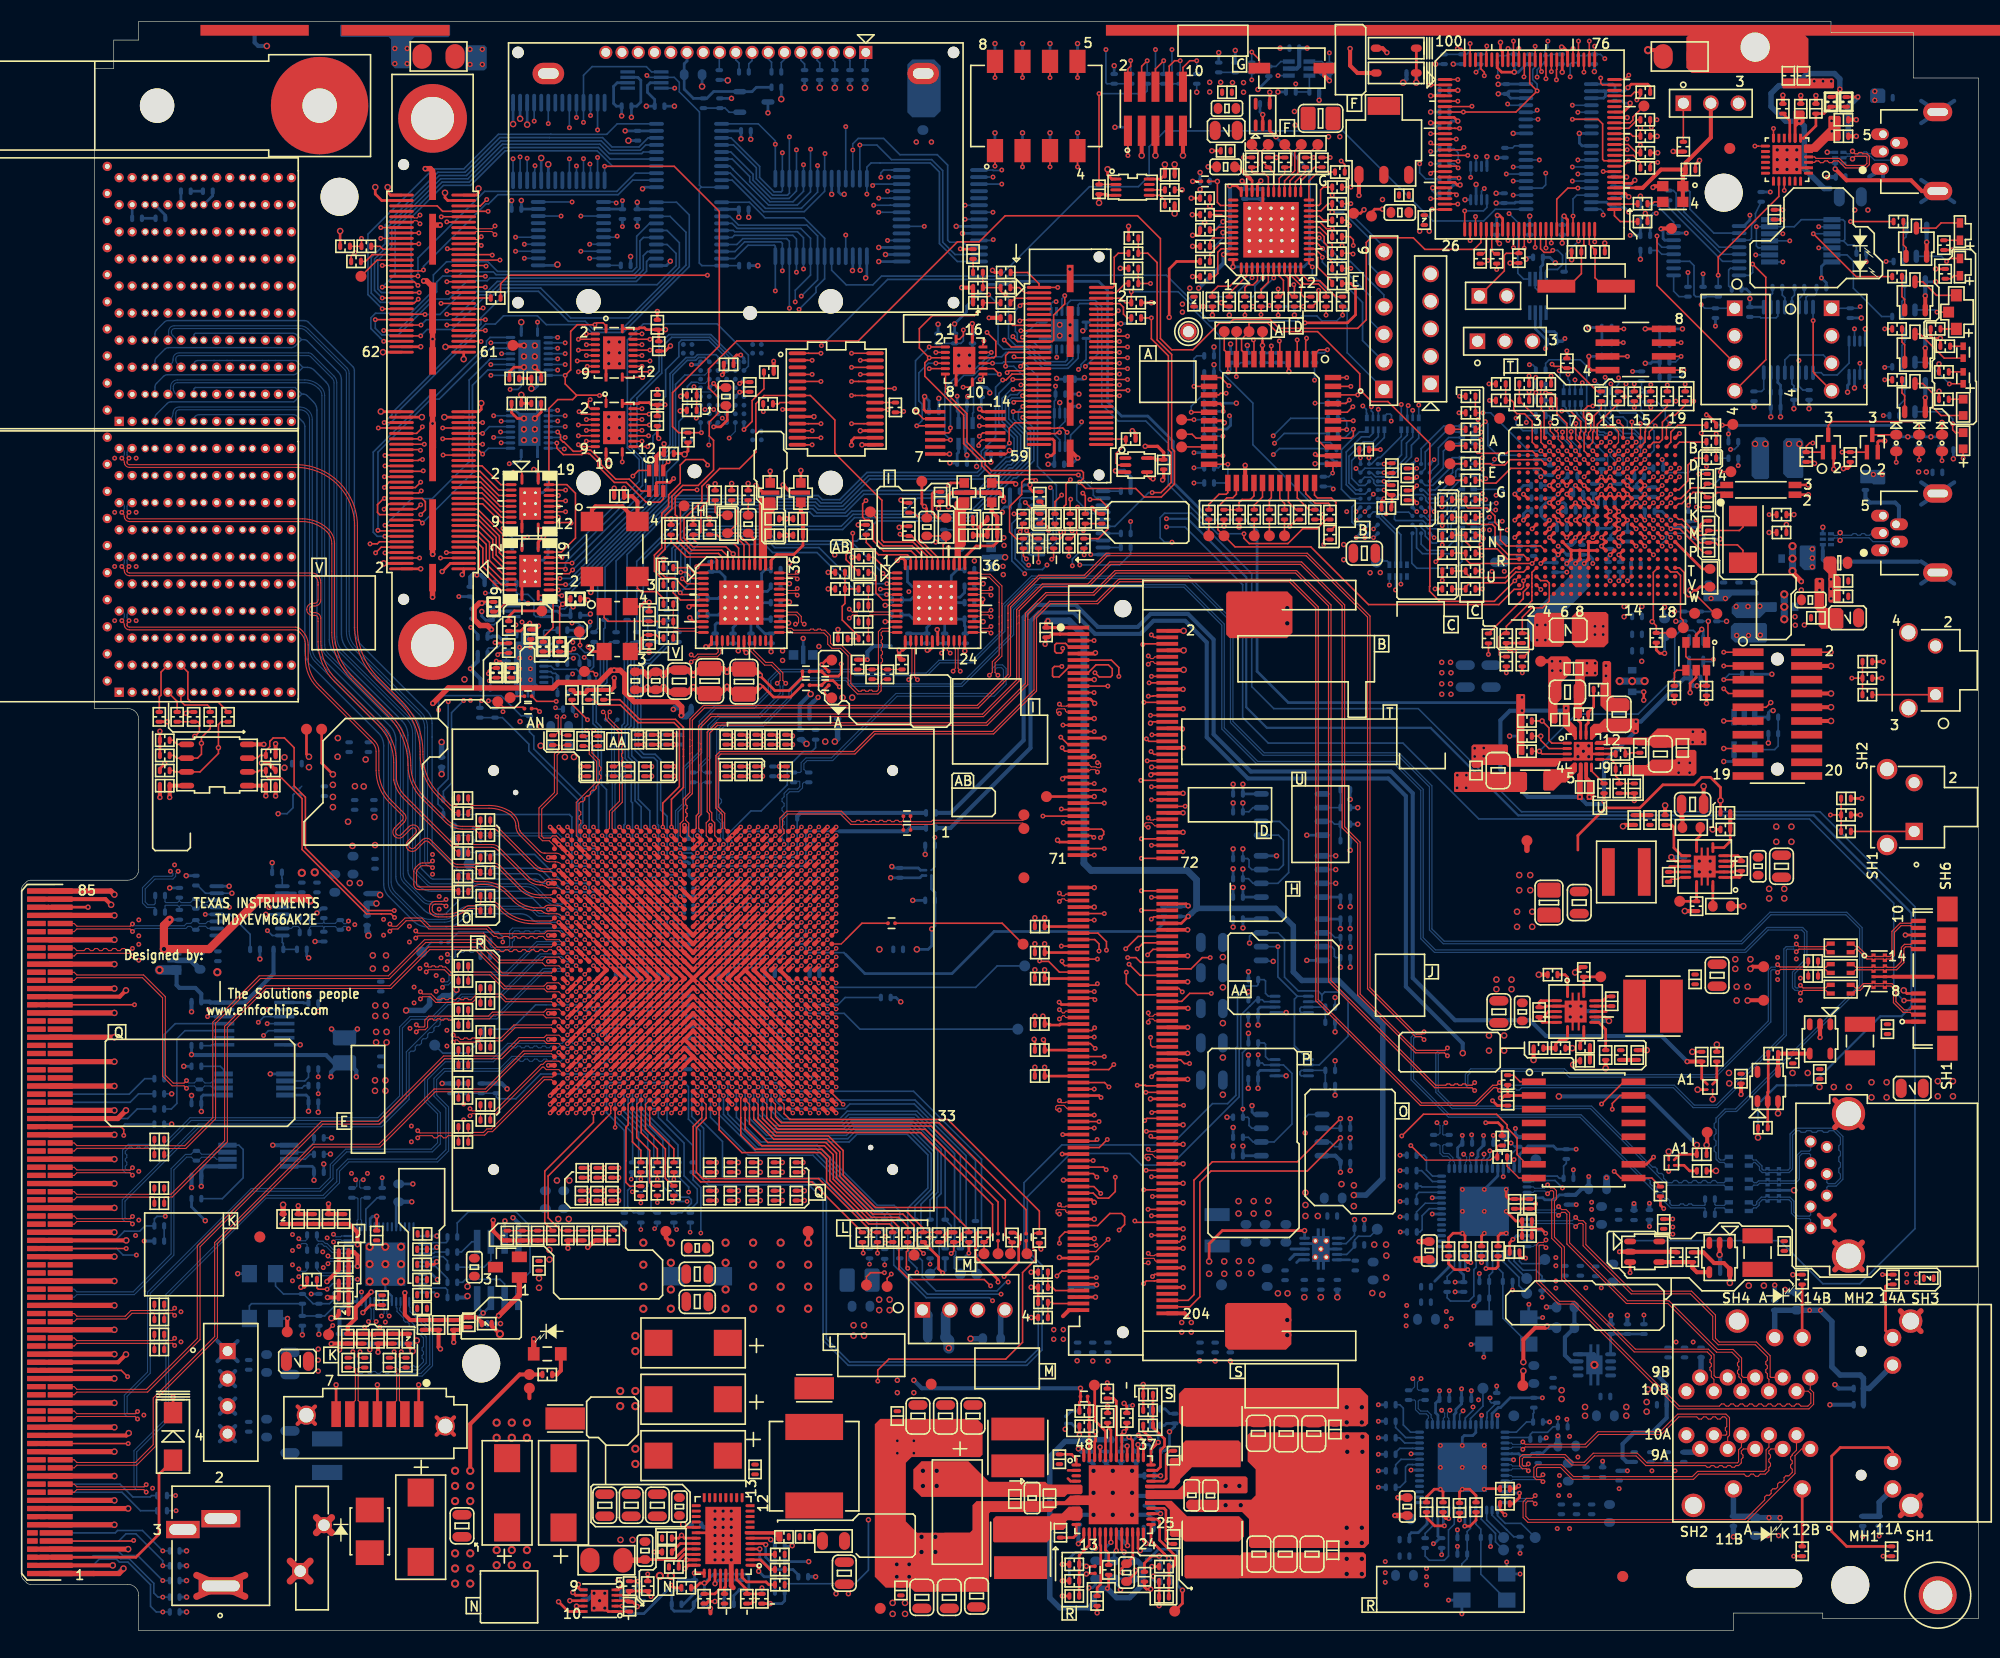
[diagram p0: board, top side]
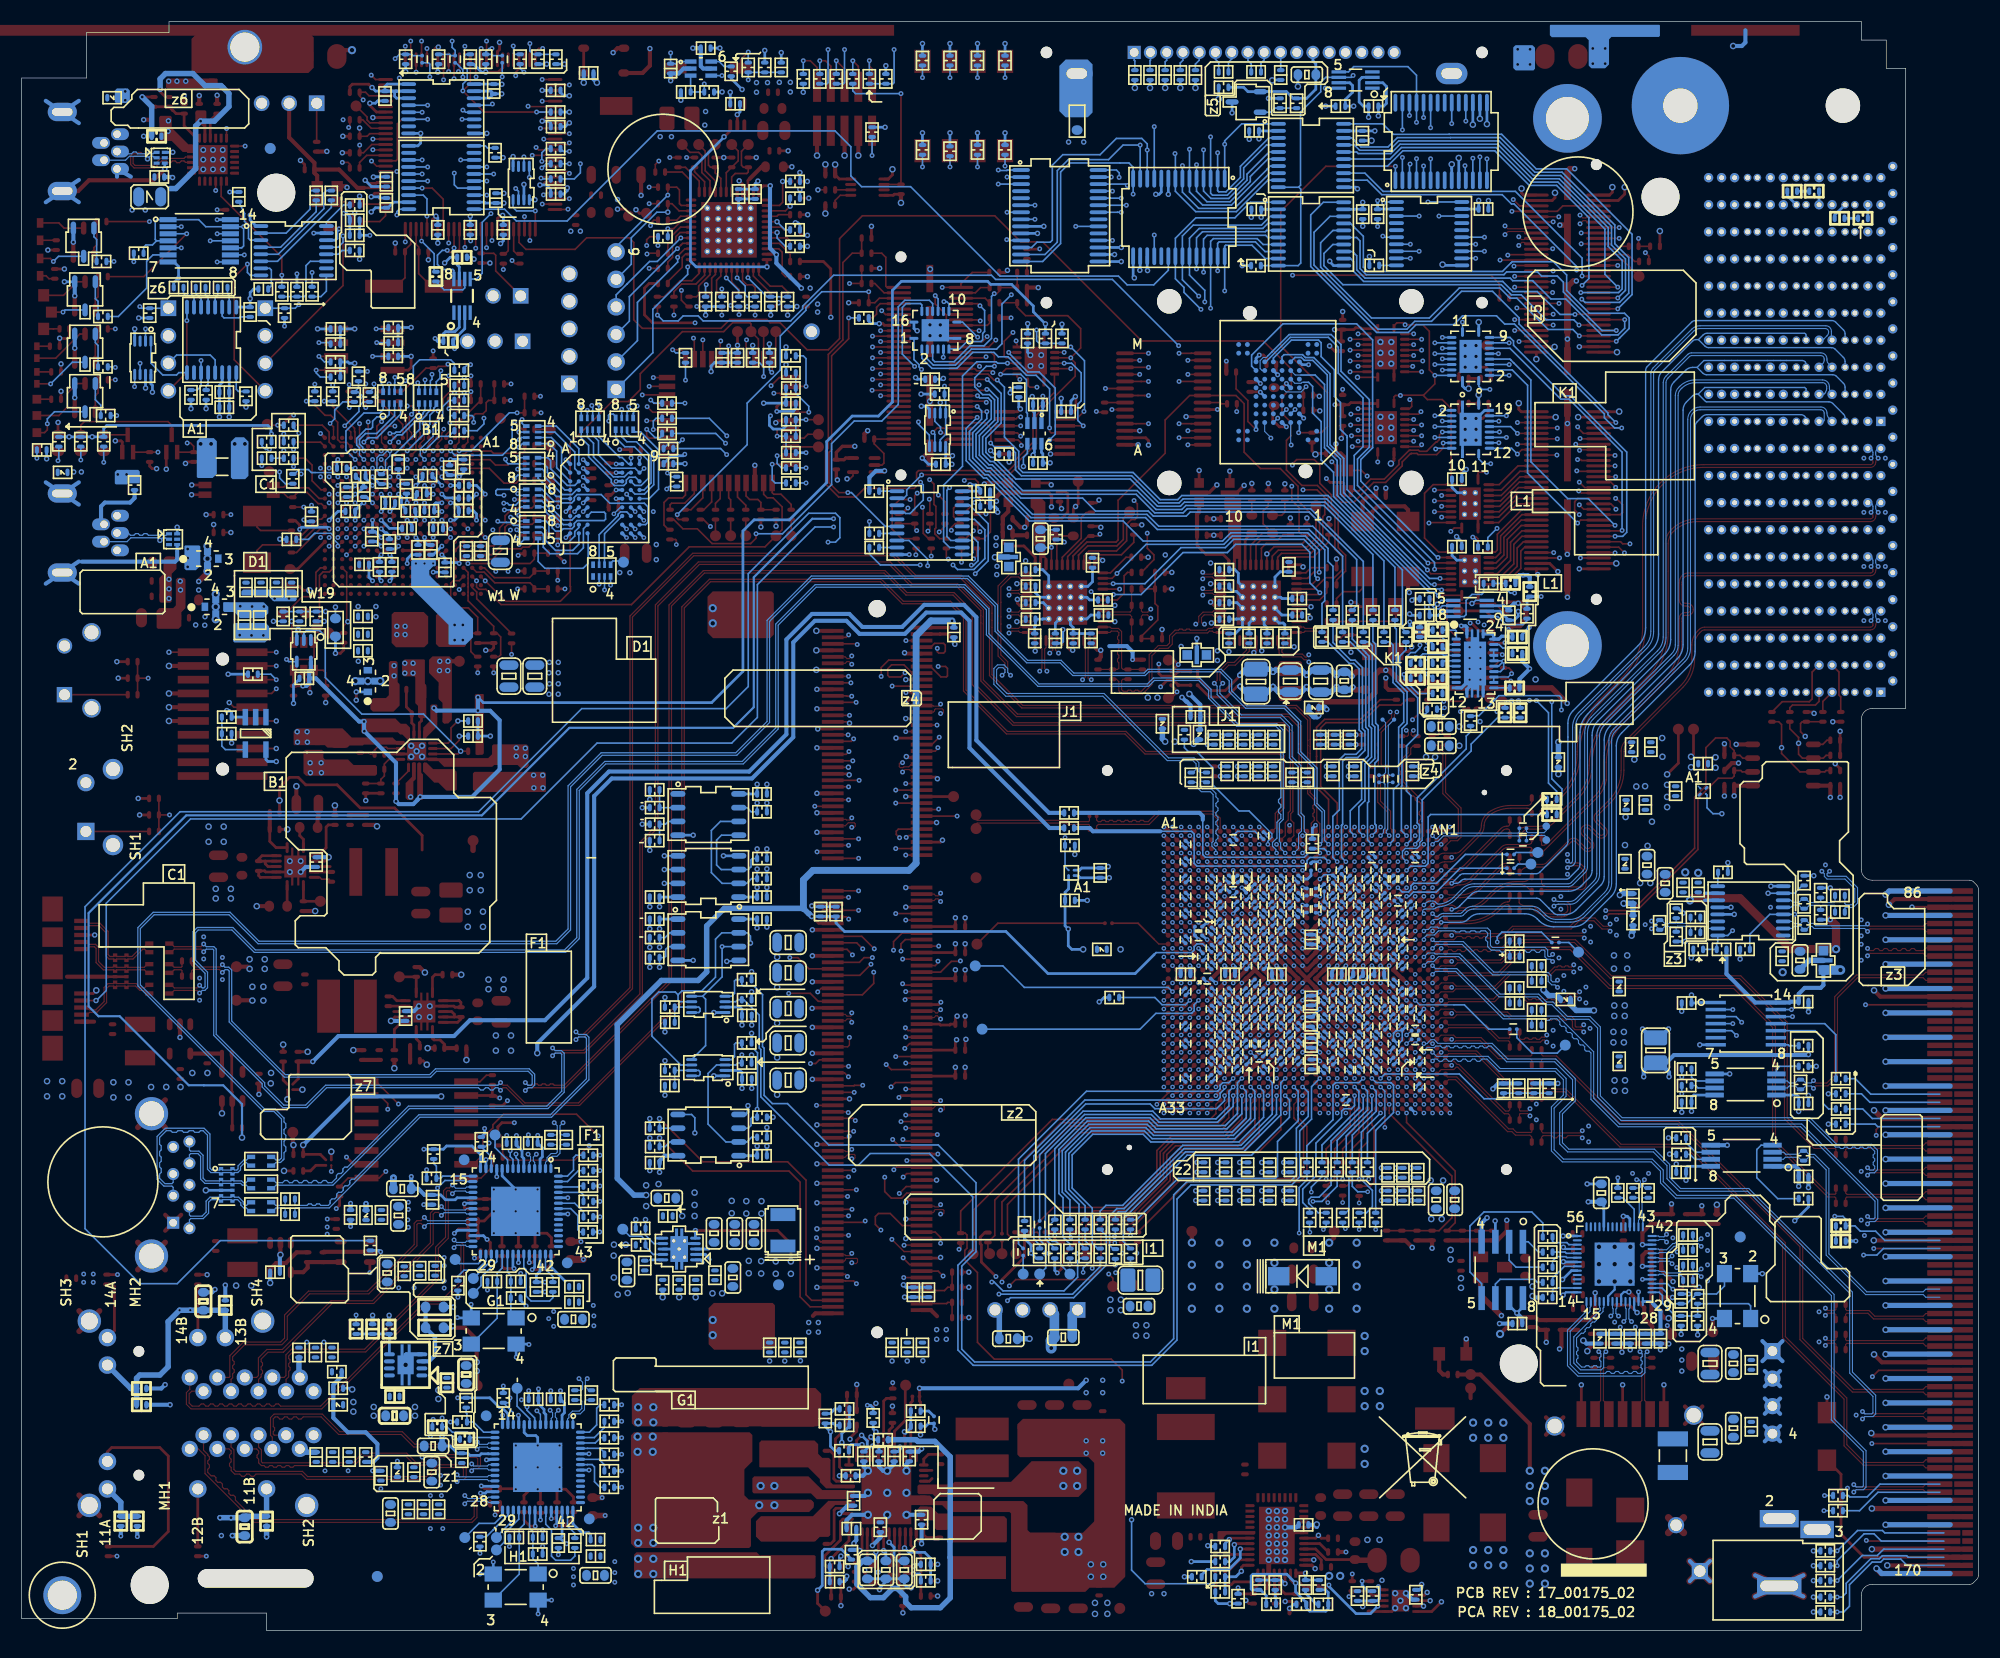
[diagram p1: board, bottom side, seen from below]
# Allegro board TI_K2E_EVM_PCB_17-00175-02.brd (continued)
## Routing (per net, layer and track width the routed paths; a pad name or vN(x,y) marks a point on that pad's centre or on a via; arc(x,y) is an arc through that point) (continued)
N17469110: length 3.1
  BOTTOM w0.152: R548.1 39.3,32.51 38.21,33.61 U75.8
N17469117: length 3.1
  BOTTOM w0.152: R543.1 39.3,34.11 38.9,34.5 38.06,34.5 37.97,34.41 U75.6
N17469130: length 2.8
  BOTTOM w0.152: U75.3 37.79,35.61 37.98,35.8 39.18,35.8 39.3,35.92 R531.1
N17469143: length 2.3
  BOTTOM w0.152: R535.1 38.14,34.92 38.02,34.81 U75.5
N17470441: length 2.7
  TOP w0.152: R428.2 137.7,51.25 138.3,50.65 NOR1.1
N17470469: length 3.8
  TOP w0.127: R447.1 137.1,42.86 138.2,41.76 NOR1.8
N17470666: length 24.4
  TOP w0.152: U23.N29 v4(65.58,50.96)
  BOTTOM w0.152: v4(65.58,50.96) 65.17,50.56 65.17,47.66 68.05,44.78 73.43,44.78 78.97,39.24 80.52,39.24 81.05,38.7 R525.1
N17470672: length 33.1
  TOP w0.152: U23.M30 v4(66.38,50.16)
  BOTTOM w0.152: R540.1 81.29,35.25 81.79,35.74 81.79,38.98 83.64,40.83 83.64,43.89 81.74,45.8 77.09,45.8 76.38,45.09 68.24,45.09 65.97,47.36 65.97,49.76 v4(66.38,50.16)
N17494072: length 31.3
  TOP w0.152: U23.L31 v4(67.18,49.36)
  BOTTOM w0.152: R539.1 83.01,35.81 83.01,39.34 84.25,40.58 84.25,44.14 81.99,46.41 76.84,46.41 76.13,45.69 68.76,45.69 67.18,47.28 v4(67.18,49.36)
N17494427: length 24.2
  TOP w0.127: U23.T33 62.78,47.32
  TOP w0.152: R235.2 72.94,41.4 62.66,41.4 61.98,42.09 61.98,46.52 62.78,47.32
N17494476: length 26.2
  TOP w0.127: U23.T32 63.18,48.56 63.18,47.32
  TOP w0.152: R234.2 78.52,36.75 73.56,41.71 62.87,41.71 62.28,42.29 62.28,46.39 63.18,47.29 63.18,47.32
N17495593: length 30.6
  TOP w0.152: U23.K31 v4(67.98,49.36)
  BOTTOM w0.152: R538.2 83.85,35.66 84.48,36.3 84.48,39.95 84.86,40.33 84.86,44.4 82.24,47.02 76.58,47.02 75.87,46.3 69.36,46.3 67.98,47.69 v4(67.98,49.36)
N17495612: length 29.1
  TOP w0.152: U23.K30 v4(67.98,50.16)
  BOTTOM w0.152: v4(67.98,50.16) 67.57,49.76 67.57,47.31 68.88,46 76,46 76.71,46.71 82.12,46.71 84.56,44.27 84.56,40.45 83.85,39.74 R523.2
N17501624: length 1.7
  TOP w0.152: U21.5 14.35,81.79 13.97,82.17 R193.1
N17511358: length 2
  BOTTOM w0.152: C342.1 164.53,123.41 164.04,122.92 U50.6
N17511366: length 1.9
  BOTTOM w0.152: U50.2 161.44,123.25 161.6,123.41 C343.1
N17511368: length 2.5
  BOTTOM w0.152: R361.2 160.6,114.37 160.79,114.56 U50.16
N17511372: length 1.9
  BOTTOM w0.152: U50.4 162.74,123.02 162.5,123.27 C343.2
N17511396: length 3.5
  BOTTOM w0.152: C346.1 160.44,121.25 160.53,121.16 161.93,121.16 162.09,121.33 U50.3
N17511408: length 2.6
  BOTTOM w0.152: U50.7 164.69,123.06 164.87,123.23 165.49,123.23 165.67,123.41 C341.2
N17511414: length 1.7
  BOTTOM w0.152: U50.12 163.39,115.06 163.58,114.88 R359.2
N17511418: length 1.9
  BOTTOM w0.152: C342.2 163.63,123.27 163.39,123.02 U50.5
N17580617: length 25
  TOP w0.152: U23.T30 v4(63.18,50.16)
  BOTTOM w0.152: v4(63.18,50.16) 62.78,49.77 62.78,47.94 62.78,47.94 62.78,47.61 62.78,47.04 64.68,45.14 64.68,41.93 64.89,41.73 73.86,41.73 77.67,37.91 R527.2
N17583891: length 4.3
  TOP w0.152: Q4.3 175.48,124.49 176.73,123.24 DBG_D1.3
N17583895: length 5.4
  TOP w0.152: DBG_D2.1 177.45,117.44 175.23,119.67 Q5.3
N17583899: length 1.5
  TOP w0.152: R69.1 177.67,120.14 177.67,120.14 DBG_D1.1
N17583903: length 5.3
  TOP w0.152: v1(177.93,115.06) 177.94,115.07 DBG_D3.1
  BOTTOM w0.152: Q13.3 175.93,117.06 v1(177.93,115.06)
N17583929: length 1.3
  TOP w0.152: R73.1 DBG_D3.2
N17583981: length 3.2
  TOP w0.152: R70.2 173.55,118.92 173.8,118.67 Q5.1
N17584002: length 3.1
  BOTTOM w0.152: R353.2 173.55,118.61 173.8,118.87 Q13.1
N17584047: length 1.2
  TOP w0.152: R71.1 DBG_D2.2
N17584060: length 3.2
  TOP w0.152: Q4.1 173.8,122.86 173.55,123.11 R48.2
N17584073: length 3.2
  TOP w0.152: DBG_D1.2 v1(176.78,121.69)
  BOTTOM w0.152: Q12.3 176.59,121.89 v1(176.78,121.69)
N17584084: length 3.3
  BOTTOM w0.152: Q12.1 173.8,122.94 173.55,122.69 R340.2
N17624377: length 1.1
  TOP w0.102: U23.AJ24 v4(51.98,54.96)
  BOTTOM w0.102: C673.2 v4(51.98,54.96)
N17624382: length 1.1
  TOP w0.102: U23.AJ25 v4(51.98,54.16)
  BOTTOM w0.102: C681.2 v4(51.98,54.16)
N17624472: length 6.1
  TOP w0.102: U23.AG1 54.25,74.03 54.25,75.62 55.18,76.55 55.18,78.66 55,78.85 C95.2
N17624476: length 6.1
  TOP w0.102: C94.2 55.61,78.85 55.44,78.68 55.44,76.45 54.5,75.51 54.5,74.03 U23.AF1
N17626857: length 7.2
  TOP w0.102: R601.1 R177.2 79.45,88.7 79.33,88.82 79.33,89.31 79.45,89.43 79.45,89.66 79.33,89.78 79.33,90.01 79.45,90.13 79.45,90.36 79.33,90.48 79.33,90.7 79.45,90.82 79.45,91.05 79.33,91.17 79.33,91.4 79.45,91.52 79.45,91.75 79.33,91.87 79.33,92.1 79.48,92.24 80.02,92.24 80.15,92.12 U17.12
N17628895: length 9.1
  TOP w0.152: R161.2 75.99,94.79 75.74,94.54 75.74,93.27 77.25,91.76 R171.2 77.22,91.54 C59.1 ; R161.2 R160.2 ; R161.2 R155.1
N17655103: length 1.4
  TOP w0.254: U23.V5 v4(60.78,70.96)
  BOTTOM w0.254: R436.2 61.47,70.94 61.28,70.94 v4(60.78,70.96)
N17664197: length 8.6
  BOTTOM w0.114: L9.3 159.56,39.52 159.84,39.23 160.02,39.23 160.15,39.36 160.15,39.57 160.57,39.99 160.93,39.99 161.07,40.13 U30.9 161.28,39.99 162.06,39.99 U30.6 162.33,39.99 163.21,39.99 163.58,39.62 163.58,38.61 163.94,38.24 165,38.24 165.12,38.36 J7.8
N17664207: length 8.6
  BOTTOM w0.114: J7.9 165.12,37.9 165,38.01 163.85,38.01 163.35,38.51 163.35,39.53 163.11,39.76 162.33,39.76 U30.7 162.06,39.76 161.28,39.76 U30.8 161.07,39.63 160.93,39.76 160.67,39.76 160.38,39.47 160.38,39.27 160.11,39 159.87,39 159.58,38.72 L9.4
N17665181: length 1.8
  TOP w0.114: C129.1 165.8,60.89 165.89,60.98 166.52,60.98 166.81,60.7 L4.2
N17667106: length 4.6
  TOP w0.381: U26.4 R222.1 R220.2 U27.4
N17684391: length 9.5
  TOP w0.102: C226.1 12.25,29.63 12.14,29.53 10.08,29.53 9.56,29 5.09,29 4.84,29.25 AMC1.33
N17684393: length 9.5
  TOP w0.102: C228.1 12.25,29.16 12.14,29.27 10.19,29.27 9.66,28.75 5.09,28.75 4.84,28.5 AMC1.32
N17684395: length 9.3
  TOP w0.102: C233.1 12.25,26.84 12.16,26.75 5.09,26.75 4.84,27 AMC1.30
N17684397: length 9.3
  TOP w0.102: AMC1.29 4.84,26.25 5.09,26.5 12.14,26.5 12.25,26.39 C238.1
N17685557: length 9
  BOTTOM w0.152: AMC1.112 10.01,48.75 10.79,49.53 R489.1
N17687628: length 36.2
  TOP w0.152: U23.AM31 v4(49.58,49.36)
  L3_SIG1 w0.102: v4(49.58,49.36) 49.52,49.36 49.12,49.76 47.9,49.76 47.62,49.48 40.68,49.48 39.93,48.73 26.07,48.73 23.65,51.16 23.65,56.32 v1(22.66,57.31)
  BOTTOM w0.152: U68.2 v1(22.66,57.31)
N17687639: length 41.1
  TOP w0.152: U23.AL33 v4(50.38,47.76)
  L3_SIG1 w0.102: v4(50.38,47.76) 49.63,47.02 42.09,47.02 41.49,46.42 39.86,46.42 39.19,47.1 23.47,47.1 21.29,49.29 21.29,55.58 v1(21.84,56.13)
  BOTTOM w0.152: v1(21.84,56.13) 22.37,56.66 U68.3
N17687855: length 9.3
  BOTTOM w0.152: AMC1.111 9.93,49.5 11.36,50.93 R485.1
N17705388: length 3.2
  TOP w0.254: U25.9 145.55,56.12 146.2,55.47 C149.1
N17705416: length 3.5
  TOP w0.254: R218.1 141.59,54.11 141.99,54.51 142.54,54.51 142.68,54.65 U25.7
  TOP w0.381: R219.1 R218.1
N17705473: length 1.6
  TOP w0.254: R217.2 143.85,54.28 144.18,54.61 U25.8
N17705475: length 1.3
  TOP w0.381: R217.1 C152.1
N17705504: length 1.5
  TOP w0.381: C148.1 R221.1
N17705537: length 2.4
  TOP w0.254: U25.1 142.68,60.29 142.44,60.53 R216.2
N17705615: length 3
  TOP w0.254: TP49.1 R215.1 U25.14
N17705627: length 2.7
  TOP w0.254: U25.11 146.26,57.12 ; U25.12 C134.2
N17705639: length 1.7
  TOP w0.254: U25.13 145.97,58.12 146.37,58.52 C134.1
N17709052: length 4.2
  TOP w0.254: U22.9 153.23,71.51 152.5,72.24 152.5,74.15 152.3,74.35 C105.1
N17709080: length 4.5
  TOP w0.254: R209.1 157.7,72.84 157.12,72.26 U22.7
  TOP w0.381: R209.1 R204.2
N17709137: length 2
  TOP w0.254: U22.8 154.6,73.02 154.93,73.36 R208.1
N17709139: length 2.2
  TOP w0.381: R208.2 153.29,74.97 153.21,75.04 C103.1
N17709168: length 1.4
  TOP w0.381: C106.1 R207.1
N17709201: length 1.9
  TOP w0.254: U22.1 R212.2
N17709279: length 3
  TOP w0.254: U22.14 R213.1 TP46.1
N17709291: length 3.1
  TOP w0.254: U22.11 152.12,70.51 ; U22.12 C117.2
N17709303: length 1.7
  TOP w0.152: C117.1 152.25,69.34 152.91,69.34 153.07,69.5 153.09,69.51 U22.13
N17728755: length 0.8
  BOTTOM w0.254: U74.1 117.92,34.2 117.68,33.96
N17728967: length 5
  BOTTOM w0.152: U74.9 122.3,34.7 123.02,35.42 R532.1 123.02,36.02 123.38,36.39 124.47,36.39 TP78.1
N17793041: length 2.5
  TOP w0.381: R254.2 49.4,23.62 49.76,23.98 D10.1
N17836608: length 1.3
  BOTTOM w0.152: R439.1 24.02,69.43 24.05,69.4 U65.9
N17928857: length 1.5
  TOP w0.152: R98.2 TP17.1
N17928862: length 10.3
  TOP w0.127: v1(141.02,108.88) U15.C5
  TOP w0.152: R98.1 134.39,110.87 v1(135.1,111.58)
  BOTTOM w0.152: v1(141.02,108.88) 140.61,108.48 136.23,108.48 135.33,109.37 135.33,111.35 v1(135.1,111.58)
N17928972: length 1.5
  TOP w0.152: TP23.1 R107.2
N17928982: length 1.5
  TOP w0.152: R102.2 TP19.1
N17929018: length 1.5
  TOP w0.152: TP21.1 R106.2
N17929020: length 7.3
  TOP w0.152: R107.1 134.73,106.17 134.73,106.14 134.96,105.91 136.08,105.91 137.44,107.27 140.24,107.27 U15.E4
N17929025: length 6.5
  TOP w0.127: 134.18,109.28 R102.1
  TOP w0.152: U15.C3 139.44,108.87 137.27,108.87 137.06,108.66 134.36,108.66 134.18,108.84 134.18,109.28
N17929027: length 6.8
  TOP w0.152: R106.1 135.59,107.7 135.72,107.57 136.87,107.57 137.36,108.07 140.24,108.07 U15.D4
N17929181: length 1.6
  TOP w0.152: TP16.1 157.86,111.25 v1(156.97,111.25)
  BOTTOM w0.152: R368.2 v1(156.97,111.25)
N17929183: length 3
  TOP w0.152: v1(156.79,106.93) 156.82,106.96 TP22.1
  BOTTOM w0.152: v1(156.79,106.93) 156.79,106.38 156.27,105.85 R381.2
N17929185: length 5.2
  TOP w0.127: U15.F17 v1(151.42,106.48)
  BOTTOM w0.127: v1(151.42,106.48) 151.81,106.88 153.47,106.88
  BOTTOM w0.152: 153.47,106.88 153.86,106.88 154.14,107.16 155,107.16 155.41,106.75 R381.1
N17929187: length 9.4
  TOP w0.127: U15.F16 v1(150.62,106.48)
  L10_SIG4 w0.107: v1(150.62,106.48) 151,106.1 153.17,106.1 153.4,106.33 153.4,108.9 v1(155.02,110.52)
  BOTTOM w0.152: R368.1 155.51,111.01 v1(155.02,110.52)
N17929697: length 6.9
  TOP w0.127: U15.P16 v1(150.62,99.28)
  L5_SIG2 w0.107: v1(150.62,99.28) 150.62,95.48 v2(151.64,94.46)
  BOTTOM w0.152: R398.1 v2(151.64,94.46)
N17929849: length 5.4
  TOP w0.127: U15.N17 v1(151.42,100.08)
  BOTTOM w0.127: 153.47,101.27 153.46,101.27 152.06,101.27 151.81,101.02 151.81,100.72 151.42,100.34 v1(151.42,100.08)
  BOTTOM w0.152: 153.47,101.27 153.57,101.27 154.13,100.71 C389.1
N17929864: length 0.6
  TOP w0.254: U15.N14 v1(149.02,100.08)
  vias: v2(147.9,94.51) v2(147.9,93.57)
N17936032: length 6.5
  TOP w0.152: U15.T18 152.2,97.7 152.79,97.7 153.11,97.38 153.11,93.47 153.37,93.22 TP34.1
N17936096: length 6
  TOP w0.152: R170.2 138.6,95.23 138.6,95.85 139.02,96.27 U15.V2
N17937670: length 12.1
  TOP w0.127: U15.K16 v1(150.62,102.48)
  TOP w0.152: R114.1 v1(161.29,103)
  L10_SIG4 w0.107: v1(161.29,103) 151.13,103 v1(150.62,102.48)
N17937746: length 15.4
  TOP w0.127: U15.K14 v1(149.02,102.48)
  L5_SIG2 w0.107: v1(149.02,102.48) 148.64,102.1 148.64,96.73 151.31,94.06 v2(152.55,94.06)
  BOTTOM w0.152: v2(152.55,94.06) 152.56,94.05 R397.2 R396.2 R395.2
N17937762: length 12.3
  TOP w0.127: U15.J16 v1(150.62,104.08)
  L5_SIG2 w0.107: v1(150.62,104.08) 151.04,104.5 151.57,104.5 151.8,104.73 151.8,105 152.1,105.3 152.7,105.3 153.89,106.49 153.89,107.94 155.35,109.4 157.35,109.4 v1(157.73,109.02)
  BOTTOM w0.152: R374.1 158.44,109.36 158.09,109.02 v1(157.73,109.02)
N17938891: length 2.5
  TOP w0.152: D9.1 v1(173.02,107.82)
  BOTTOM w0.152: v1(173.02,107.82) R373.1
N17938893: length 2
  TOP w0.152: D8.1 v1(175.14,108.04)
  BOTTOM w0.152: R372.1 v1(175.14,108.04)
N17939061: length 2.2
  TOP w0.152: Q7.3 D9.2
N17939063: length 10.4
  TOP w0.152: D8.2 175.14,111.25 174.81,111.58 167.09,111.58 166.76,111.25 166.76,111.23 166.75,111.23 Q8.3
N17939289: length 2.2
  TOP w0.152: D7.1 v1(177.25,107.98)
  BOTTOM w0.152: v1(177.25,107.98) 177.17,108.05 R371.1
N17941980: length 21.4
  TOP w0.254: U15.M17 v1(151.42,100.88) ; U15.M15 v1(149.82,100.88)
  L3_SIG1 w0.381: v3(159.99,109.52) 159.99,102.57 156.69,99.26 151.41,99.26 150.81,99.86 150.81,100.28 ; 150.81,100.28 v1(151.42,100.88) ; 150.81,100.28 150.39,100.28 149.82,100.86 v1(149.82,100.88)
  vias: v3(160.94,109.52)
N17943569: length 6.7
  TOP w0.152: TP32.1 156.26,93.85 154.69,95.43 153.79,95.43 153.44,95.78 153.44,97.66 153.02,98.08 U15.T19
N17947121: length 4.9
  TOP w0.152: U9.26 113.74,104.72 113.41,104.39 112.65,104.39 112.37,104.11 R122.1 R123.1
N17948726: length 5.9
  BOTTOM w0.381: R384.2 170.18,104.52 170.59,104.11 172.92,104.11 173.27,103.76 173.27,102.37 J3.4
N17968117: length 5.2
  TOP w0.152: U15.B15 149.83,109.7 149.83,110.62 149.87,110.66 149.87,110.96 151.89,112.98 R82.2
N17968119: length 4.7
  TOP w0.152: U15.B9 145.01,109.68 145.01,110.6 145.12,110.72 145.12,112.11 145.8,112.78 R79.2
N17968507: length 10.9
  TOP w0.127: v1(144.22,106.48) U15.E9
  TOP w0.152: R84.1 v1(148.84,112.88)
  L5_SIG2 w0.107: v1(144.22,106.48) 144.81,106.48 145.4,107.07 145.4,111.29 146.99,112.88 v1(148.84,112.88)
N17968518: length 4.2
  TOP w0.152: U15.A10 145.42,110.71 145.43,110.72 145.43,111.32 147.37,113.26 R85.1
N17968576: length 6.2
  TOP w0.152: R81.2 153.54,113.11 152.6,112.17 152.07,112.17 151.44,111.53 151.44,109.93 151.17,109.67 150.86,109.67 150.86,109.66 150.6,109.66 U15.B16
N17969207: length 5
  TOP w0.152: R97.2 152.86,111.25 152.22,110.62 152.22,109.69 U15.B18
N17969213: length 3.1
  TOP w0.152: R101.2 155.46,109.68 153.02,109.68 U15.B19
N17976218: length 7.8
  TOP w0.152: U15.T17 150.6,97.67 150.6,93.22 v2(150.5,93.12) 150.88,92.74 150.88,92.08 TP35.1
N17976303: length 8.2
  TOP w0.127: U15.J17 v1(151.42,104.08)
  L5_SIG2 w0.107: v1(155.51,109.02) 154.23,107.74 154.23,106.36 152.37,104.5 152.03,104.5 151.61,104.08 v1(151.42,104.08)
  BOTTOM w0.152: R375.1 v1(155.51,109.02)
N17976785: length 1.1
  BOTTOM w0.152: R379.1 C360.1
N18031730: length 4.9
  TOP w0.152: U15.G19 152.96,105.28 153.8,106.12 153.8,107.57 154.43,108.2 R105.1
N18106049: length 2.6
  TOP w0.152: U17.40 v1(85.55,99.98)
  BOTTOM w0.152: C45.2 85.58,99.95 v1(85.55,99.98)
N18116016: length 9.2
  BOTTOM w0.152: U47.6 156.99,126.38 152.02,131.35 C329.1
N18116024: length 7.7
  BOTTOM w0.152: U47.2 156.2,128.98 153.98,131.19 153.98,132.8 153.87,132.91 C328.1
N18116026: length 3.2
  BOTTOM w0.152: R322.2 150.9,131.57 152.48,130 U47.16
N18116030: length 7.5
  BOTTOM w0.152: C328.2 153.42,130.96 156.7,127.68 U47.4
N18116054: length 4.9
  BOTTOM w0.152: U47.3 159.5,128.33 159.66,128.5 159.66,129.7 160.03,130.06 160.03,130.76 160.02,130.78 C324.1
N18116066: length 2.9
  BOTTOM w0.152: U47.7 157.71,125.73 157.56,125.58 157.56,124.11 C344.2
N18116072: length 2.3
  BOTTOM w0.152: U47.12 151.38,127.03 151.03,127.38 R326.2
N18116076: length 9.8
  BOTTOM w0.152: C329.2 152.46,132.91 152.7,132.66 152.7,131.24 156.92,127.03 U47.5
N18202591: length 5.3
  TOP w0.152: U4.12 118.07,125.27 118.75,124.59 119.82,124.59 121.3,123.11 R55.1
N18238342: length 8.8
  BOTTOM w0.152: AMC1.115 9.29,46.5 9.53,46.74 R492.1
N18238353: length 9.1
  BOTTOM w0.152: AMC1.114 9.79,47.25 10.67,48.13 R490.1
N18260681: length 1.6
  BOTTOM w0.152: U45.10 R329.1
N18287363: length 13.1
  TOP w0.114: v2(168.99,135.83) 169.23,136.07 170.23,136.07 170.31,135.99 170.31,135.41 170.14,135.23 168.42,135.23 167.77,135.88 165.62,135.88 165.49,136.01 U2.4
  BOTTOM w0.114: J1.2 171.01,135.71 170.65,136.07 169.23,136.07 v2(168.99,135.83) 168.74,136.07 168.48,136.07 168.34,135.94 D13.2
N18287374: length 13.1
  TOP w0.114: v2(168.99,136.54) 169.23,136.3 169.47,136.3 169.59,136.42 169.83,136.42 169.95,136.3 170.33,136.3 170.54,136.09 170.54,135.31 170.23,135 168.33,135 167.68,135.65 167.25,135.65 167.08,135.48 166.84,135.48 166.68,135.65 166.43,135.65 166.27,135.48 166.03,135.48 165.86,135.65 165.62,135.65 165.49,135.51 U2.3
  BOTTOM w0.114: J1.3 171.59,136.3 170.46,136.3 170.29,136.47 170.05,136.47 169.88,136.3 169.23,136.3 v2(168.99,136.54) 168.74,136.3 168.48,136.3 168.34,136.44 D13.1
N18287430: length 2.5
  TOP w0.254: R6.2 163.19,139.38 U2.9
N18287465: length 6.1
  TOP w0.254: R614.2 R613.2 166.67,140.31 166.64,140.31 166.34,140.01 C3.1 165.61,138.89 164.46,137.74 U2.7
N18287912: length 4.3
  BOTTOM w0.152: U77.15 137.96,18.3 138.9,19.24 R563.1 139.5,20.02 139.57,20.08 R558.1
N18358937: length 3.4
  BOTTOM w0.102: C732.2 131.27,44.84 131.17,44.74 131.17,44.15 131.3,44.02 131.73,44.02 132.11,43.64 132.11,43.35 132.25,43.21 U73.2
N18358939: length 3.4
  BOTTOM w0.102: C733.2 130.8,44.84 130.91,44.73 130.91,44.04 131.19,43.76 131.62,43.76 131.85,43.54 131.85,43.31 131.75,43.21 U73.1
N18359019: length 3.6
  BOTTOM w0.152: TP77.1 136.91,44.57 135.75,43.41 U73.9
N18359046: length 4.2
  BOTTOM w0.152: U73.30 137.75,34.08 138.58,33.25 139.78,33.25 140.34,32.69 R551.1
N18359063: length 3.3
  BOTTOM w0.152: TP79.1 140.21,33.86 138.46,33.86 138.25,34.06 U73.29
N18359070: length 9.5
  BOTTOM w0.152: Y7.3 136.71,28.82 C783.2 136.71,32.99 136.25,33.45 U73.33
N18359080: length 6.2
  BOTTOM w0.152: Y7.1 135.45,29.33 R553.1 C784.2 135.45,32.77 135.76,33.08 135.76,34.4 135.75,34.42 U73.34
N18359169: length 2.9
  BOTTOM w0.152: C788.1 131.57,32.66 132.25,33.34 U73.41
N18359175: length 7.3
  BOTTOM w0.152: C788.2 131.57,30.71 131.88,30.4 133.58,30.4 134.04,30.86 134.04,33.3 134.25,33.51 U73.37
N18359199: length 5.3
  BOTTOM w0.152: U73.15 141.73,41.93 141.94,41.73 R508.1 142.32,42.86 142.57,43.1 R498.1
N18359263: length 2.9
  BOTTOM w0.152: U73.31 137.25,34.15 138.46,32.94 TP83.1
N18359265: length 4.5
  BOTTOM w0.152: TP85.1 138.2,31.83 138.2,32.59 136.75,34.04 U73.32
N18359267: length 3
  BOTTOM w0.152: R514.1 128.75,40.2 128.98,40.43 U73.53
N18359269: length 3.8
  BOTTOM w0.152: R500.1 129.44,43.87 129.67,43.64 129.67,42.49 130.23,41.93 U73.56
N18359271: length 2.7
  BOTTOM w0.152: U73.55 130.22,41.43 129.21,42.44 R507.1
N18359273: length 2.3
  BOTTOM w0.152: R509.1 129.14,41.02 129.23,40.93 U73.54
N18359285: length 3.1
  BOTTOM w0.152: U73.51 129.55,39.43 128.75,38.63 R515.1
N18359287: length 3.9
  BOTTOM w0.152: R530.1 129.06,36.78 129.26,36.98 129.26,38.28 129.92,38.93 U73.50
N18360107: length 5.3
  TOP w0.254: R265.2 J9.12B
N18360109: length 4.9
  TOP w0.254: J9.14B 164.34,27.04 R249.2
N18360137: length 1.9
  BOTTOM w0.508: C809.1 155.01,23.43 J9.9B
N18631752: length 1.7
  BOTTOM w0.152: C305.1 77.85,144.88 77.91,144.94 LCD1.1
N18631754: length 1.7
  BOTTOM w0.152: LCD1.2 76.41,144.94 76.45,144.9 C306.1
N18631756: length 1.7
  BOTTOM w0.152: LCD1.3 74.91,144.94 75.06,144.79 C307.1
N18631758: length 1.7
  BOTTOM w0.152: C308.1 73.66,144.69 73.41,144.94 LCD1.4
N18631760: length 1.8
  BOTTOM w0.152: C309.1 72.26,144.59 71.91,144.94 LCD1.5
N18631984: length 1.9
  BOTTOM w0.152: LCD1.6 70.41,145.03 70.11,144.73 C301.2
N18631986: length 1.9
  BOTTOM w0.152: C301.1 69.21,144.75 68.91,145.05 LCD1.7
N18631992: length 1.9
  BOTTOM w0.152: C302.2 67.11,144.61 67.41,144.91 LCD1.8
N18632005: length 1.9
  BOTTOM w0.152: LCD1.9 65.91,144.98 66.21,144.68 C302.1
N18632025: length 1.6
  BOTTOM w0.152: C310.1 64.39,145.64 LCD1.10
N18632070: length 3.5
  BOTTOM w0.152: Q10.1 65.3,140.14 64.92,140.52 R308.1 R309.1
N18640521: length 4.8
  TOP w0.152: R43.1 120.96,126.31 120.52,126.75 120.52,127.81 120.22,128.12 120.22,128.65 119.84,129.04 U4.18
N18643296: length 5.7
  BOTTOM w0.102: R419.2 54.94,78.94 54.71,79.17 54.71,83.79 TP65.1
N18643297: length 2.6
  BOTTOM w0.102: R427.2 41.71,73.76 41.58,73.63 40.08,73.63 39.88,73.84 TP66.1
N18643298: length 5.7
  BOTTOM w0.102: TP64.1 54.46,83.54 54.46,79.06 54.34,78.94 R420.2
N18643299: length 2.6
  BOTTOM w0.102: R430.2 41.71,73.3 41.63,73.38 40.03,73.38 39.88,73.23 TP67.1
N18643300: length 11.4
  TOP w0.102: R206.2 82.04,74.75 82.14,74.65 83.94,74.65 84.07,74.78 92.41,74.78 92.51,74.88 TP42.1
N18643301: length 11.4
  TOP w0.102: R210.2 82.04,74.32 82.12,74.4 84.05,74.4 84.18,74.52 92.41,74.52 92.51,74.42 TP43.1
N18643419: length 1.4
  TOP w0.152: TP36.1 45.21,86.23 R173.2
N18643442: length 2.7
  TOP w0.152: R174.2 46.28,85.21 44.45,85.21 TP37.1
N18643465: length 4.8
  BOTTOM w0.152: TP81.1 86.08,33.45 86.08,34.51 86.21,34.64 86.21,34.96 86.08,35.08 86.08,35.49 86.64,36.05 R521.2
N18643488: length 1.7
  BOTTOM w0.152: R534.2 TP80.1
N18643523: length 2.3
  BOTTOM w0.152: R433.2 42.67,71.81 TP68.1
N18643546: length 6.2
  BOTTOM w0.152: TP74.1 38.86,53.29 41.17,53.29 42.6,54.71 R473.2
N18643624: length 2.2
  BOTTOM w0.152: R461.2 37.8,63.5 TP71.1
N18643711: length 1.2
  TOP w0.152: TP55.1 R237.2
N18643735: length 1.2
  TOP w0.152: TP53.1 92.71,34.85 R236.2
N18643759: length 1.7
  BOTTOM w0.152: R437.2 42.47,70.74 TP69.1
N18643843: length 12.6
  TOP w0.152: R214.2 90.5,65.28 TP47.1
N18646931: length 1.5
  TOP w0.152: R121.2 TP29.1
N18646952: length 1.5
  TOP w0.152: TP31.1 R124.2
N18646958: length 1.5
  TOP w0.152: R119.2 TP27.1
N18646969: length 1.5
  TOP w0.152: R120.2 TP28.1
N18661122: length 4.2
  TOP w0.254: R156.1 155.12,97.98 U15.N19
N18690585: length 4.9
  BOTTOM w0.152: U67.8 118.1,57.03 117.98,57.15 117.98,57.4 118.11,57.54 U67.7 R471.1 C661.1
N18909283: length 4.9
  TOP w0.152: R95.2 R88.1 62.3,114.56 v1(62.05,114.81)
  BOTTOM w0.102: v1(62.05,114.81) 62.05,114.78 62.29,114.55 62.29,114.54 62.51,114.32 63.89,114.32 U53.G5
N19595154: length 30.3
  TOP w0.127: 68.38,47.32 U23.J33
  TOP w0.152: TP56.1 R238.1 88.88,35.85 89.61,36.58 89.61,39.32 82.98,45.95 69.68,45.95 68.38,47.26 68.38,47.32
N19595193: length 30.9
  TOP w0.127: 69.18,47.32 U23.H33
  TOP w0.152: TP54.1 91.41,34.92 R243.1 90.78,36.46 90.78,39.73 83.95,46.56 69.94,46.56 69.18,47.32
N19595213: length 35.6
  TOP w0.152: U23.K29 v4(67.98,50.96)
  BOTTOM w0.152: v4(67.98,50.96) 68.38,50.55 68.38,50.33 68.38,50.32 68.38,50 68.38,49.99 68.38,49.53 68.38,49.52 68.38,49.2 68.38,49.19 68.38,47.71 69.49,46.61 75.75,46.61 76.46,47.32 82.37,47.32 85.24,44.45 R522.1 85.8,37.36 85.8,36.25 85.47,35.91 85.11,35.91 84.68,35.48 84.68,33.73 TP82.1
N19617731: length 5
  TOP w0.152: C100.2 R202.2 147.45,78.56 147.12,78.88 R199.2 147.12,79.98 146.7,80.4 U20.9
N19618957: length 4.3
  TOP w0.152: U20.11 146.82,81.4 146.93,81.52 147.78,81.52 148.02,81.27 R196.1 148.41,80.9 148.52,81.01 R194.1
N19619378: length 4.5
  TOP w0.254: R180.2 145.09,85.24 144.6,84.75 R185.1 144.6,83.77 144.39,83.57 U20.14
N19620431: length 2
  TOP w0.152: R203.1 146.05,78.18 144.9,79.33 U20.8
N19620706: length 5.7
  TOP w0.152: U20.1 141.24,81.9 140.97,82.17 140.97,83.31 v2(140.34,83.95) R191.1
  BOTTOM w0.152: R191.1 v2(140.34,83.95)
N19620742: length 4.8
  TOP w0.152: R192.1 v2(140.21,82.55) 140.21,82.17 140.97,81.4 U20.2
  BOTTOM w0.152: v2(140.21,82.55) R192.1
N19627767: length 4.4
  TOP w0.152: Y5.3 56.96,90.36 57.2,90.6 57.2,91.62 57.47,91.89 C58.2 58.56,91.89 58.85,91.61 R167.1
N19627773: length 6.6
  TOP w0.152: Y5.1 53.76,93.48 54.09,93.15 C54.2 57.93,93.13 R164.1
N19628918: length 4.4
  TOP w0.152: R163.1 59.24,95.25 58.6,95.89 57.15,95.89 56.84,96.2 Y4.3
N19630686: length 3.2
  BOTTOM w0.102: U75.44 31.37,37.86 31.29,37.93 31.29,39.85 31.38,39.94 R511.2
N19630689: length 3.2
  BOTTOM w0.102: U75.43 30.97,37.86 31.04,37.93 31.04,39.84 30.94,39.94 R512.2
N19642467: length 2.9
  BOTTOM w0.152: U58.6 49.46,94.59 49.75,94.3 50.11,94.3 50.65,94.84 R390.1
N19665402: length 5
  TOP w0.152: U19.3 153.61,89.89 153.87,89.63 v1(156.15,89.63)
  BOTTOM w0.152: U59.4 155.95,89.43 v1(156.15,89.63)
N19666056: length 2.4
  TOP w0.152: U19.4 152.77,88.63 152.54,88.41 C68.1
N19669080: length 2.4
  TOP w0.152: v2(91.17,108.92) 90.84,108.59 U11.8
  BOTTOM w0.152: R378.1 90.84,108.58 v2(91.17,108.92)
N19695800: length 5.3
  TOP w0.381: U32.4 154.62,33.06 154.2,33.48 R245.1 R246.2 U31.4
N19714193: length 5.1
  TOP w0.102: C242.1 30.67,24.26 30.8,24.13 30.8,21.23 30.29,20.72 J10.6
N19714195: length 5.1
  TOP w0.102: C241.1 31.16,24.26 31.05,24.16 31.05,21.23 31.56,20.72 J10.5
N19714197: length 5.1
  TOP w0.102: C240.1 34.48,24.26 34.61,24.13 34.61,21.22 34.1,20.71 J10.3
N19714199: length 5.1
  TOP w0.102: J10.2 35.37,20.71 34.86,21.22 34.86,24.18 34.95,24.26 C239.1
N19809600: length 3.9
  TOP w0.152: R57.1 118.32,123.11 118.11,123.32 118.11,124.1 117.07,125.15 U4.10
N19815748: length 6.3
  TOP w0.381: R246.1 152.71,34.95 U31.2 v1(147.47,34.95)
  BOTTOM w0.254: v1(147.47,34.95) 147.59,35.08 R533.2
N19819673: length 6.9
  TOP w0.254: 161.16,46.4 U27.2 161.16,49.67 161.21,49.72 R220.1
N19956937: length 5.8
  TOP w0.152: U9.16 v1(107.95,112.45)
  BOTTOM w0.152: v1(107.95,112.45) 107.95,113 109.15,114.2 R356.2 R354.1
N20100474: length 1.4
  TOP w0.152: U3.6 R20.1
N20107888: length 2
  BOTTOM w0.152: R299.2 115.77,144.37 116.22,144.82 U36.6
N20108296: length 5
  BOTTOM w0.152: U61.4 161.8,81.31 162.12,81.63 R417.1 R415.2
N20214474: length 2.1
  TOP w0.152: U3.5 105.04,132.47 105.52,132 R24.1
N20256439: length 1.9
  BOTTOM w0.114: L9.2 157.44,39.52 157.15,39.23 156.36,39.23 156.28,39.31 C186.1
N20256446: length 1.9
  BOTTOM w0.114: L9.1 157.41,38.72 157.12,39 156.36,39 156.28,38.92 C189.1
N20256822: length 1.8
  TOP w0.114: C126.1 165.8,61.28 165.88,61.21 166.52,61.21 166.81,61.5 L4.1
N20259025: length 3.7
  TOP w0.254: TP33.1 45.47,94.11 44.96,93.6 R165.1
N20259028: length 28
  TOP w0.152: U23.AE4 v4(55.18,71.76)
  TOP w0.254: v1(46.9,92.99) 46.78,92.99 46.06,92.26 R165.2
  L10_SIG4 w0.107: v1(46.9,92.99) 47.52,92.36 47.52,86.39 46.94,85.8 46.94,81.47 54.74,73.66 54.74,72.47 55.02,72.19 55.04,72.19 55.18,72.05 v4(55.18,71.76)
N20260067: length 39.6
  TOP w0.152: U23.AL32 v4(50.38,48.56)
  L3_SIG1 w0.102: v1(22.66,56.01) 21.69,55.04 21.69,49.63 24,47.33 39.28,47.33 39.96,46.65 41.37,46.65 42.14,47.42 47.35,47.42 48.08,48.16 49.97,48.16 v4(50.38,48.56)
  BOTTOM w0.152: U68.4 v1(22.66,56.01)
N20260083: length 36.2
  TOP w0.152: U23.AM32 v4(49.58,48.56)
  L3_SIG1 w0.102: v1(22.33,54.91) 22.33,49.81 23.71,48.43 39.96,48.43 40.78,49.25 47.88,49.25 48.16,48.97 49.16,48.97 v4(49.58,48.56)
  BOTTOM w0.152: v1(22.33,54.91) 22.77,55.36 U68.5
N20260360: length 2.1
  BOTTOM w0.152: R475.1 17.47,53.98 17.56,54.06 U68.8
N20314517: length 2.2
  BOTTOM w0.152: U70.7 25.87,50.07 26.09,50.29 R487.2
N20314549: length 3
  BOTTOM w0.152: R483.2 26.47,51.06 26.13,50.72 U70.6
N20314831: length 2.5
  BOTTOM w0.152: U72.7 26.17,43.49 26.62,43.94 R499.2
N20314842: length 3.1
  BOTTOM w0.152: R495.2 26.98,45.03 26.09,44.14 U72.6
N20315949: length 2.6
  BOTTOM w0.152: R482.2 18.33,52.07 18.64,51.77 U70.4
N20316135: length 8.9
  BOTTOM w0.152: U72.4 20.05,44.79 20.45,44.39 20.45,41.78 18.52,39.85 R513.2
N20339426: length 25.1
  TOP w0.152: U23.P31 v4(64.78,49.36)
  BOTTOM w0.152: R541.1 79.9,35.25 80.19,35.54 80.19,36.58 80.29,36.68 80.29,38.17 79.52,38.93 78.84,38.93 73.3,44.48 67.93,44.48 64.78,47.63 v4(64.78,49.36)
N20339428: length 23.6
  TOP w0.152: U23.R29 v4(63.98,50.96)
  BOTTOM w0.152: v4(63.98,50.96) 64.38,50.55 64.38,47.59 67.8,44.17 73.17,44.17 78.72,38.63 79.37,38.63 79.65,38.35 R526.1
N20339430: length 23.4
  TOP w0.127: U23.P33 64.38,47.32
  TOP w0.152: R233.1 80.39,37.24 80.11,37.52 78.18,37.52 74.3,41.4 74.3,43.54 73.73,44.1 66.49,44.1 64.38,46.22 64.38,47.32
N20339432: length 29.5
  TOP w0.152: U23.L30 v4(67.18,50.16)
  BOTTOM w0.152: R524.1 82.45,39.21 83.95,40.71 83.95,44.02 81.86,46.1 76.96,46.1 76.25,45.39 68.63,45.39 66.78,47.24 66.78,49.19 66.78,49.2 66.78,49.52 66.78,49.53 66.78,49.77 v4(67.18,50.16)
N20339434: length 25
  TOP w0.152: U23.R31 v4(63.98,49.36)
  BOTTOM w0.152: v4(63.98,49.36) 63.58,48.97 63.58,47.37 67.08,43.87 73.03,43.87 78.92,37.98 78.92,35.91 R542.1
N20339438: length 22.5
  TOP w0.127: 66.78,47.32 U23.L33
  TOP w0.152: 66.78,47.32 66.78,46.28 68.33,44.73 74.09,44.73 74.9,43.92 74.9,41.65 78.43,38.13 80.95,38.13 81.79,37.29 R232.1
N20460479: length 4.9
  BOTTOM w0.152: U69.8 118.1,51.19 117.98,51.31 117.98,51.56 118.11,51.69 U69.7 R484.1 C724.1
N20517788: length 3.3
  BOTTOM w0.152: EEPROM1.3 120.92,74.68 121.17,74.42 R425.1 R429.2
N20517790: length 3.3
  BOTTOM w0.152: R421.2 R422.1 EEPROM1.2
N20589689: length 29.5
  TOP w0.152: TP59.1 79.88,32.51 v1(80.26,32.89) ; U23.L29 v4(67.18,50.96)
  L8_SIG3 w0.107: v1(80.26,32.89) 80.26,36.55 79.86,36.96 78.25,36.96 73.81,41.4 72.14,41.4 71.45,42.09 71.45,43.3 69.88,44.87 69.88,48.85 69.95,48.92 69.95,51.31 69.87,51.39 67.6,51.39 v4(67.18,50.96)
N20589690: length 28.7
  TOP w0.152: TP60.1 77.98,32.64 78.36,33.02 v1(79.63,33.02) ; U23.M29 v4(66.38,50.96)
  L8_SIG3 w0.107: v4(66.38,50.96) 66.76,50.57 69.01,50.57 69.15,50.43 69.15,45.28 70.71,43.71 70.71,43.33 71.12,42.93 71.12,40.61 71.73,40 71.73,39.47 78.18,33.02 v1(79.63,33.02)
N20589691: length 25.5
  TOP w0.127: 67.18,47.32 67.18,47.99 67.18,48.56 U23.L32
  TOP w0.152: TP57.1 82.37,37.39 81.33,38.43 78.56,38.43 75.21,41.78 75.21,44.04 74.22,45.03 68.88,45.03 67.18,46.74 67.18,47.32
N22090512: length 3.7
  TOP w0.254: R275.2 68.96,4.22 68.7,4.48 66.91,4.48 66.5,4.89 U34.40
N22090530: length 3.5
  TOP w0.254: U34.35 v2(64,4.32)
  BOTTOM w0.254: v2(64,4.32) 64.32,4.64 C858.2 C857.2
N22090531: length 1.4
  BOTTOM w0.254: C858.1 64.9,3.09 64.83,3.02 R592.1
N22090532: length 18.1
  TOP w0.254: U34.34 63.5,4.69 63.17,4.37 v2(63.02,4.37) 62.61,4.37 62.18,3.94 R603.2
  BOTTOM w0.254: R587.1 60.25,3.74 60,3.49 R594.2 60,2.01 60.23,1.78 61.72,1.78 62.03,2.09 R593.1 62.03,2.58 63.02,3.56 v2(63.02,4.37) 63.83,5.19 66.95,5.19 67.12,5.02 67.12,3.83 67.03,3.74 C857.1 66.26,3.74 65.73,3.21 R592.2
N22090538: length 2.8
  TOP w0.305: U34.33 v2(62.1,5.29)
  BOTTOM w0.254: v2(62.1,5.29) C859.2 R587.2
N22090539: length 1.9
  BOTTOM w0.254: R594.1 61.09,2.41 62.1,3.43 C859.1
N22090556: length 3.1
  TOP w0.254: R280.2 63.98,3.37 64.5,3.88 U34.36
N22090558: length 1.6
  TOP w0.254: U33.4 96.82,13.77 96.57,14.02 ; U33.2 96.59,14.77
N22090580: length 5.7
  TOP w0.254: U33.47 98.54,18.84 R261.2 R257.2 98.53,21.01 98.39,21.16 C246.1
N22090592: length 2.5
  TOP w0.254: U33.12 97.34,8.82 97.09,8.57 C278.1
N22090599: length 5.1
  TOP w0.254: U33.28 105.44,11.27 105.61,11.1 105.61,8.31 105.94,7.98 C280.1
N22090604: length 4.6
  TOP w0.254: U33.33 105.42,13.77 105.64,14 105.64,16.23 105.99,16.58 C254.1
N22090609: length 6.3
  TOP w0.254: U33.14 98.54,7.86 97.61,6.92 R269.2 R273.2 C290.1
N22090615: length 8.9
  TOP w0.254: U33.26 104.8,10.27 105.03,10.04 105.03,8.33 106.47,6.89 106.47,6.06 106.3,5.89 R270.2 R274.2 C292.1
N22090621: length 8.3
  TOP w0.254: U33.35 104.79,14.77 105.11,15.09 105.11,16.61 105.49,16.99 105.49,17.68 104.42,18.75 R260.2 R256.2 C245.1
N22090627: length 1.8
  TOP w0.254: U33.45 v2(99.54,16.92)
  BOTTOM w0.254: v2(99.54,16.92) 99.54,16.69 99.73,16.5 C830.1
N22090640: length 4.9
  TOP w0.254: v2(99.12,18.34) 99.12,17.48 99.04,17.4 U33.46
  BOTTOM w0.254: R561.1 C823.1 98.53,18.68 99.01,18.2 99.05,18.23 99.05,18.34 v2(99.12,18.34)
N22090648: length 1.4
  BOTTOM w0.254: R561.2 96.88,20.24 C821.2
N22090649: length 6.1
  TOP w0.254: U33.16 99.54,7.87 99.6,7.81 99.6,4.27 99.26,3.93 C295.1
N22090650: length 2.6
  TOP w0.254: U33.24 103.54,8.27 v2(103.78,8.03)
  BOTTOM w0.381: v2(103.78,8.03) 103.78,8.1 103.56,8.32 C843.1
N22090651: length 4.1
  TOP w0.254: U33.37 103.54,17.54 v2(103.07,18.01)
  BOTTOM w0.254: v2(103.07,18.01) 102.55,17.49 102.55,16.82 C829.1
N22090653: length 2.1
  TOP w0.254: U33.40 v2(102.04,17.02)
  BOTTOM w0.254: v2(102.04,17.02) 101.59,17.02 101.47,16.9 R569.1
N22090664: length 2.3
  TOP w0.254: C256.1 96.91,16.25 97.34,15.82 U33.1
N22090666: length 2.6
  TOP w0.254: U33.23 103.04,7.58 v2(103.25,7.37)
  BOTTOM w0.381: R575.2 103.32,7.44 v2(103.25,7.37)
N22090676: length 6.4
  TOP w0.254: U33.15 99.04,7.69 v2(99.12,7.61)
  BOTTOM w0.254: R586.1 C851.2 96.7,6.65 97.25,7.2 98.71,7.2 v2(99.12,7.61)
N22090680: length 2
  TOP w0.254: C282.2 98.33,5.26 v2(98.28,5.21)
  BOTTOM w0.254: R586.2 97.61,5.08 97.73,5.21 v2(98.28,5.21)
N22090686: length 3.4
  TOP w0.254: C284.2 103.63,6.2 104.29,6.86 v2(104.99,6.86)
  BOTTOM w0.254: v2(104.99,6.86) 105.11,6.73 R582.2
N22090687: length 6
  TOP w0.254: v2(105.89,6.63) 105.47,7.05 105.47,7.06 104.24,8.28 U33.25
  BOTTOM w0.152: R582.1 106.01,6.5 v2(105.89,6.63)
  BOTTOM w0.254: R582.1 C856.2
N22090695: length 1.5
  BOTTOM w0.254: R560.2 105.54,20.45 105.98,20.01 C820.2
N22090696: length 5.7
  TOP w0.254: U33.36 104.24,16.69 v2(104.9,17.36)
  BOTTOM w0.254: v2(104.9,17.36) 104.9,18.16 104.2,18.87 C822.1 R560.1
N22090791: length 2.8
  TOP w0.254: U33.39 102.54,17.53 102.21,17.85 v2(102.21,17.86)
  BOTTOM w0.254: v2(102.21,17.86) 101.96,17.6 R567.2
N22090797: length 1.9
  TOP w0.254: U35.6 51.59,3.74 51.38,3.95 v2(51.38,4.24)
  BOTTOM w0.305: v2(51.38,4.24) 51.38,3.93 51.57,3.74 R590.2
N22090840: length 3.2
  TOP w0.254: R272.2 100.33,7.12 100.04,7.42 U33.17
N22090844: length 6.1
  TOP w0.254: U34.4 v2(68.12,7.51)
  BOTTOM w0.254: v2(68.12,7.51) 68.12,6.68 69.19,5.61 71.19,5.61 71.69,5.12 R583.2
N22090845: length 3.7
  TOP w0.254: v2(68.67,7.91) 68.57,8.01 U34.5
  BOTTOM w0.254: R580.2 69.08,6.35 68.67,6.76 v2(68.67,7.91)
N22090846: length 4.4
  TOP w0.254: v2(68.02,5.46) 68.02,5.82 67.82,6.01 U34.1
  BOTTOM w0.254: v2(68.02,5.46) 68.53,4.95 R584.2 R589.2
N22090848: length 2.8
  TOP w0.254: U34.6 69.01,8.51 v2(69.14,8.38)
  BOTTOM w0.254: R577.2 69.53,8.02 69.19,8.36 69.19,8.36 69.16,8.38 v2(69.14,8.38)
N22090854: length 3.3
  TOP w0.254: R259.2 100.23,18.8 100.54,18.49 U33.43
N22090856: length 4.3
  TOP w0.254: U33.41 101.54,18.12 v2(101.75,18.34) 102.01,18.59 R258.2
  BOTTOM w0.254: R258.2 102.01,18.59 v2(101.75,18.34)
N22090858: length 6.1
  TOP w0.254: R255.2 100.78,21.42 101.04,21.16 U33.42
N22090866: length 2.5
  TOP w0.254: U34.30 61.17,7.01 60.65,6.5 R268.2
N22090868: length 2
  TOP w0.254: R279.1 64.87,3.63 64.88,3.63 64.88,3.94 64.97,4.04 64.97,4.75 65,4.77 U34.37
N22090880: length 7.1
  TOP w0.254: TP63.1 99.04,22.6 99.04,19.38 100.04,18.39 U33.44
N22090898: length 2.3
  TOP w0.254: U34.3 R266.2
N22090899: length 2.7
  TOP w0.254: R271.2 69.08,5.62 68.19,6.51 U34.2
N22090903: length 3.7
  TOP w0.254: U34.39 66,4.69 66.93,3.76 R278.1 R277.1
N22090947: length 7.2
  TOP w0.254: U34.29 61.17,7.51 60.2,6.54 C281.1
  TOP w0.508: C281.1 57.47,6.48 R267.1
N22090970: length 2.8
  TOP w0.254: U33.38 v2(103.04,17.14)
  BOTTOM w0.254: v2(103.04,17.14) 104.04,17.14 104.25,16.93 R566.2
N22169052: length 1.2
  TOP w0.152: U23.L26 v4(67.18,53.36)
  BOTTOM w0.127: R477.1 v4(67.18,53.36)
N22169056: length 1.2
  TOP w0.152: U23.K26 v4(67.98,53.36)
  BOTTOM w0.127: R478.1 v4(67.98,53.36)
N24344484: length 1.6
  BOTTOM w0.152: R389.2 U57.9
N24344504: length 1.6
  BOTTOM w0.152: U57.7 R387.2
N24344573: length 1.6
  BOTTOM w0.152: U57.1 R385.2
N24344575: length 2.4
  BOTTOM w0.152: R386.2 92.12,104.36 92.3,104.55 93.75,104.55 U57.19
N25551345: length 6.9
  TOP w0.127: 142.62,110.85 142.62,109.96 143.02,109.56 U15.B7
  TOP w0.152: 142.62,110.85 142.62,111.41 141.69,112.35 141.69,113.73 141.19,114.24 v1(140.66,114.24)
  BOTTOM w0.152: R283.2 v1(140.66,114.24)
N25551369: length 7.8
  TOP w0.127: U15.D8 v1(143.42,108.08)
  BOTTOM w0.127: v1(143.42,108.08) 143.81,108.48 143.81,109.05 142.62,110.24 142.62,110.85
  BOTTOM w0.152: 142.62,110.85 142.62,111.21 141.74,112.09 141.74,112.95 141.16,113.54 R476.2
N25551410: length 4.8
  TOP w0.127: U15.A16 150.22,110.62 150.44,110.85
  TOP w0.152: 150.44,110.85 v4(150.79,111.19)
  BOTTOM w0.152: v4(150.79,111.19) 149.47,112.51 149.47,113.01 149.08,113.4 R596.2
N25551640: length 5
  TOP w0.127: 151.82,110.85 U15.A18
  TOP w0.152: 151.82,110.85 151.82,111.1 v4(152.13,111.42)
  BOTTOM w0.152: R597.2 150.96,113.4 151.71,112.65 151.71,111.84 v4(152.13,111.42)
N25565163: length 11.7
  TOP w0.127: U15.A9 144.62,110.55 144.82,110.76 144.82,110.85
  TOP w0.152: 144.82,110.85 144.82,112.05 v1(144.62,112.25)
  BOTTOM w0.152: v1(144.62,112.25) 144.45,112.42 144.45,116.71 143.87,117.29 141,117.29 140.66,116.95 R481.2
N25619366: length 4.1
  TOP w0.127: U15.C8 v1(143.42,108.88)
  BOTTOM w0.152: R599.2 141.18,110.22 142.08,110.22 v1(143.42,108.88)
N25619369: length 2.6
  TOP w0.127: 141.09,110.85 141.09,110.7 141.42,110.38 U15.A5
  TOP w0.152: v4(141.09,111.48) 141.09,110.85
  BOTTOM w0.152: v4(141.09,111.48) 141.09,112.03 140.98,112.14 R600.2
N26224346: length 9.2
  TOP w0.254: TP94.1 107.14,2.49 v2(107.14,3.71)
  BOTTOM w0.254: R575.1 104.01,6.56 104.94,7.49 106.5,7.49 106.71,7.29 106.71,4.14 v2(107.14,3.71)
N26374725: length 1.3
  BOTTOM w0.254: R623.2 C874.2
N26377331: length 1.4
  BOTTOM w0.152: R621.2 C872.2
N26444584: length 3.9
  BOTTOM w0.152: U79.6 139.7,123.93 139.88,123.75 141.6,123.75 R628.2
N26449108: length 6.3
  BOTTOM w0.381: R648.1 R647.2 142.44,27.06 142.44,25.4 143.01,24.84 Q15.3
N26465222: length 5.3
  BOTTOM w0.152: U58.8 47.46,93.59 47.28,93.76 47.28,95.08 46.74,95.63 45.85,95.63 45.66,95.82 R407.1
N26465374: length 4.4
  BOTTOM w0.152: U58.1 44.35,93.59 43.6,92.84 42.04,92.84 41.66,93.22 R412.1
N26504675: length 1.9
  TOP w0.152: R94.2 U8.21
N26504706: length 2.3
  TOP w0.152: U8.8 69.98,113.34 69.86,113.23 R93.1
N26537188: length 1.1
  BOTTOM w0.254: R653.2 C896.2
N26540501: length 2.3
  BOTTOM w0.152: U80.22 44.22,91.01 43.9,90.68 43.1,90.68 43,90.58 R642.2
N26541964: length 1.5
  BOTTOM w0.152: U80.14 43.26,87.01 R655.2
N26588297: length 1.4
  BOTTOM w0.152: U80.6 49.24,89.51 R637.1
N26588299: length 4.1
  BOTTOM w0.152: R636.1 51.49,89.92 51.27,90.14 49.49,90.14 49.35,90.01 U80.5
N26588301: length 1.4
  BOTTOM w0.152: U80.4 49.16,90.51 R635.1
N26588303: length 3.7
  BOTTOM w0.152: R634.1 49.53,91.7 48.83,91.01 U80.3
N26588305: length 2.5
  BOTTOM w0.152: U80.9 48.9,88.01 49.02,87.88 49.02,87.38 49.46,86.94 R640.1
N26588307: length 4.1
  BOTTOM w0.152: U80.7 48.87,89.01 49.15,88.72 51.21,88.72 51.49,88.44 R638.1
N26588309: length 1.7
  BOTTOM w0.152: R639.1 49.46,88.16 49.28,88.34 49,88.34 48.84,88.51 U80.8
N26588382: length 5.2
  TOP w0.152: TP96.1 51.54,92.1 v1(51.54,90.95)
  BOTTOM w0.152: v1(51.54,90.95) 51.54,90.7 51.98,90.26 52.39,90.26 52.79,89.87 52.79,88.95 52.39,88.56 R638.2
N26588389: length 4.8
  TOP w0.152: v1(53.01,88.24) 52.73,88.52 TP97.1
  BOTTOM w0.152: R640.2 51.72,86.49 53.01,87.78 v1(53.01,88.24)
N26588687: length 2.1
  BOTTOM w0.152: R654.1 48.26,92.33 48.18,92.25 U80.2
N56425294: length 9.3
  TOP w0.102: AMC1.53 4.84,44.25 5.09,44.5 12.14,44.5 12.25,44.39 C165.1
N56425297: length 9.3
  TOP w0.102: AMC1.54 4.84,45 5.09,44.75 12.14,44.75 12.25,44.86 C162.1
N56425300: length 9.3
  TOP w0.102: C187.1 12.25,39.89 12.14,40 5.09,40 4.84,39.75 AMC1.47
N56425303: length 9.3
  TOP w0.102: AMC1.48 4.84,40.5 5.09,40.25 12.12,40.25 12.25,40.39 C176.1
N66223400: length 8.9
  TOP w0.102: U23.G3 v4(70.38,72.56)
  BOTTOM w0.102: v4(70.38,72.56) 70.38,72.94 70.18,73.14 70.18,73.36 70.38,73.56 70.38,73.79 70.18,73.98 70.18,74.21 70.38,74.41 70.38,74.64 70.18,74.83 70.18,75.06 70.38,75.26 70.38,75.49 70.18,75.68 70.18,75.91 70.38,76.11 70.38,76.33 70.18,76.53 70.18,76.76 70.38,76.95 70.38,77.26 70.78,77.67 71.62,77.67 71.82,77.88 71.82,78.33 71.77,78.38 71.34,78.38 C457.2
N66223405: length 8.9
  TOP w0.102: U23.G4 v4(70.38,71.76)
  BOTTOM w0.102: C456.2 72.21,78.29 72.07,78.16 72.07,77.77 71.72,77.42 70.89,77.42 70.63,77.16 70.63,72.83 70.74,72.71 70.74,72.4 70.38,72.03 v4(70.38,71.76)
N68025719: length 2.6
  TOP w0.152: U1.31 135.69,127.36 135.98,127.07 R39.2
N68025736: length 2.7
  TOP w0.152: U1.30 135.19,127.34 134.92,127.07 R40.2
N68027970: length 2.6
  TOP w0.152: v1(89.84,143.34) SW1.8
  BOTTOM w0.152: R296.1 v1(89.84,143.34)
N68027994: length 2.6
  TOP w0.152: v1(92.38,143.34) SW1.7
  BOTTOM w0.152: R295.1 v1(92.38,143.34)
N68028184: length 2.6
  TOP w0.152: v1(94.92,143.34) SW1.6
  BOTTOM w0.152: R294.1 v1(94.92,143.34)
N68028192: length 2.6
  TOP w0.152: v1(97.46,143.34) SW1.5
  BOTTOM w0.152: R293.1 v1(97.46,143.34)
N68029449: length 5.8
  TOP w0.152: RST_PWR1.1 R181.1
N68029469: length 5.8
  TOP w0.152: RST_ATTN1.1 R211.1
N68035165: length 34.1
  TOP w0.152: v1(139.16,128.26) 139.19,128.3 U1.38 ; U1.88 139.19,142.8 v1(139.88,142.11) 137.92,140.16 v1(133.07,140.16) U1.7
  L8_SIG3 w0.107: v1(139.16,128.26) 138.68,128.74 138.68,140.92 v1(139.88,142.11)
  BOTTOM w0.152: v1(139.88,142.11) 139.88,142.74 139.47,143.15 139.47,144.08 139.75,144.36 139.75,145.31 139.57,145.48 C298.1 ; C318.1 v1(133.07,140.16) ; C338.1 139.19,128.3 v1(139.16,128.26)
N68049827: length 8.4
  TOP w0.152: U17.45 83.05,99.26 83.05,99.26 82.2,100.11 79.51,100.11 78.92,100.7 78.92,102.67 TP25.1
N68049869: length 4.6
  TOP w0.152: R154.2 78.53,97.66 78.84,97.35 78.84,95.76 79.48,95.12 U17.6
N68057675: length 3
  TOP w0.152: U18.1 62.07,97.62 61.6,98.09 R151.2
N68057679: length 9
  TOP w0.152: U18.45 65.17,99.16 64.61,99.72 61.82,99.72 60.81,100.74 60.81,103.48 TP26.1
N68057721: length 3.8
  TOP w0.152: R157.2 60.14,95.78 60.8,95.12 U18.6
N68057761: length 3.2
  TOP w0.254: C42.2 67.67,100.67 U18.40
N68057795: length 6
  TOP w0.152: R138.2 59.94,100.51 61.37,99.09 63.93,99.09 64.17,98.85 U18.47
N68067792: length 3.2
  TOP w0.152: R150.2 78.66,99.06 80.1,97.62 U17.1
N68067794: length 6
  TOP w0.152: R135.2 77.95,100.43 79.1,99.29 81.76,99.29 82.05,99 U17.47
N68073129: length 2.9
  TOP w0.152: R28.2 147.55,130.05 147.01,130.58 U1.51

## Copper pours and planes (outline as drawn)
AGND on TOP: 58.5,1.19 58.5,3.57 58.3,3.76 58.3,5.22 58.67,5.59 59.18,5.59 59.54,5.94 59.54,6.1 59.66,6.22 59.92,6.22 60.07,6.07 60.07,5.71 60.71,5.08 60.71,4.45 60.53,4.27 60.53,3.58 62.15,1.96 64.16,1.96 64.49,2.29 64.49,2.64 64.64,2.79 65.28,2.79 65.41,2.92 65.41,5.71 65.66,5.46 65.66,4.45 66.17,3.94 66.17,2.24 66.52,1.88 69.39,1.88 70.18,2.67 70.18,7.24 70.31,7.37 72.01,7.37 72.14,7.24 72.14,1.14 72.01,1.02 58.67,1.02
AGND on TOP: 56.92,7.98 57.12,7.77 57.99,7.77 58.27,8.05 59.11,8.05 59.31,8.26 59.31,8.81 59.23,8.89 55.12,8.89 54.97,8.74 54.97,8.15 55.14,7.98
AGND on L2_GND1: 61.16,9.09 62.15,8.1 62.15,6.99 63.32,5.82 66.57,5.82 66.75,5.99 66.75,7.04 66.85,7.14 69.14,7.14 69.49,7.49 72.06,7.49 72.14,7.42 72.14,1.6 71.58,1.04 58.24,1.04 57.56,1.73 57.56,4.9 54.81,7.65 54.81,8.81 55.09,9.09
AGND1 on L2_GND1: 106.5,19.23 106.05,19.68 95.89,19.68 95.38,19.18 95.38,8 96.9,6.48 96.9,3.43 97.92,2.41 103.76,2.41 104.65,3.3 105.16,3.3 106.5,4.65
AVCC3V3_1 on BOTTOM: 146.18,14.35 143.51,14.35 143.26,14.61 141.76,14.61 141.66,14.5 141.66,13.21 141.78,13.08 146.18,13.08 146.3,13.21 146.3,14.22
AVCC3V3_1 on L8_SIG3: 134.04,15.72 134.04,11.96 131.8,9.73 131.8,8.86 132.11,8.56 143.1,8.56 143.46,8.92 143.46,13.18 140.31,16.33 134.65,16.33
AVCC3V3_2 on BOTTOM: 149.17,38.05 149.1,38.13 144.75,38.13 144.65,38.02 144.65,37.06 144.78,36.93 149.07,36.93 149.17,37.03
AVCC3V3_2 on L5_SIG2: 133.99,34.11 133.99,32.69 134.42,32.26 138.96,32.26 141.55,34.85 144.96,34.85 146.41,36.3 146.41,40.84 145.97,41.27 136.09,41.27 135.71,40.89 135.71,35.84
AVDD1V8_1 on BOTTOM: 147.07,11.18 146.05,11.18 145.8,11.43 141.71,11.43 141.6,11.53 141.6,12.55 141.76,12.7 146.94,12.7 147.32,12.32 147.32,11.43
AVDD1V8_1 on L3_SIG1: 127.43,20.78 127.43,13.72 126.39,12.67 126.39,9.83 127.53,8.69 143.31,8.69 143.59,8.97 143.59,16.59 141.45,18.72 139.32,18.72 135.08,22.96 129.62,22.96
AVDD1V8_2 on BOTTOM: 141.38,33.45 147.37,33.45 147.45,33.53 147.45,34.14 146.96,34.62 141.43,34.62 141.27,34.47 141.27,33.55
AVDD1V8_2 on L3_SIG1: 129.16,44.88 129.16,35.15 128.52,34.52 128.52,33.35 129.11,32.77 132.23,32.77 133.05,31.95 143.94,31.95 146.15,34.16 146.15,46.05 145.26,46.94 134.44,46.94 133.81,46.3 130.58,46.3
AVDDA1 on BOTTOM: 32.82,70.87 31.93,70.87 31.5,71.3 31.5,72.72 31.62,72.85 32.82,72.85 33.15,72.52 33.15,71.2
AVDDA1 on L3_SIG1: 54.84,68.28 54.84,69.52 54.64,69.72 54.25,69.72 54.05,69.93 54.05,70.33 53.77,70.61 53.39,70.61 53.24,70.76 53.24,71.17 52.98,71.42 52.63,71.42 52.4,71.65 52.4,72.03 52.2,72.24 48.49,72.24 47.02,73.71 32.66,73.71 32.11,73.15 32.11,70.36 34.29,68.17 47.98,68.17 48.08,68.07 54.64,68.07
AVDDA3 on L5_SIG2: 56.34,69.19 56.34,69.72 56.21,69.85 54.2,69.85 54,70.05 54,70.46 53.8,70.66 52.63,70.66 52.48,70.82 52.48,71.3 52.32,71.45 51.82,71.45 51.66,71.6 51.66,73.25 49.12,75.79 44.78,75.79 44.77,75.81 42.43,75.81 40.34,77.9 40.34,80.24 40.18,80.39 37.95,80.39 37.69,80.14 37.69,77.39 42.37,72.72 46.28,72.72 50.11,68.88 55.37,68.88 55.63,69.14 56.29,69.14
DVDD1V0 on TOP: 44.45,33.02 43.03,33.02 42.14,33.91 41.4,33.91 40.13,32.64 40.13,29.57 39.93,29.36 37.31,29.36 37.21,29.46 37.21,32.84 37.41,33.05 38.63,33.05 38.81,33.22 38.81,34.34 38.56,34.59 37.31,34.59 37.21,34.7 37.21,37.19 36.98,37.41 35.53,37.41 34.72,36.6 32.38,36.6 32.21,36.78 32.21,38.51 32.84,39.14 40.18,39.14 44.58,34.75 44.58,33.15
DVDD1V0_1 on BOTTOM: 127.89,9.02 127.89,4.19 128.14,3.94 129.92,3.94 130.05,4.06 130.05,5.84 129.92,5.97 128.91,5.97 128.65,6.22 128.65,8.89 128.52,9.02
DVDD1V0_1 on L8_SIG3: 127.64,21.95 127.64,4.06 128.32,3.38 130.94,3.38 131.47,3.91 131.47,8.56 130.86,9.17 130.86,10.34 131.8,11.28 131.8,16.74 133.5,18.44 133.5,20.8 133.35,20.95 133.35,22.83 133.05,23.14 128.83,23.14
DVDD1V0_2 on BOTTOM: 129.87,32.38 129.87,28.12 130.23,27.76 131.85,27.76 132.21,28.12 132.21,29.24 131.7,29.74 130.84,29.74 130.53,30.05 130.53,32.33 130.38,32.49 129.97,32.49
DVDD1V0_2 on L8_SIG3: 130.84,45.47 130.84,27.38 131.09,27.13 134.19,27.13 134.59,27.53 134.59,31.24 133.05,32.79 133.05,33.93 134.32,35.2 134.32,41.17 136.17,43.03 136.17,46.76 135.46,47.47 132.84,47.47
GND on TOP (solid shape): 117.2,29.74 117.2,26.42 116.69,25.91 111.4,25.91 111.07,26.24 111.07,30.02 111.28,30.23 116.71,30.23
GND on TOP (solid shape): 117.3,95.43 117.3,92.1 116.79,91.59 111.51,91.59 111.18,91.92 111.18,95.71 111.38,95.91 116.81,95.91
GND on TOP (solid shape): 167.28,143.13 167.28,142.44 167.18,142.34 162.59,142.34 162.51,142.42 162.51,143.18 162.59,143.26 167.16,143.26
GND on TOP (solid shape): 143,89.59 143,88.39 142.11,87.5 142.11,85.98 141.76,85.62 141.76,83.85 141.63,83.72 141.22,83.72 140.89,84.05 140.89,89.69 141.12,89.92 142.67,89.92
GND on TOP (solid shape): 167.51,98.91 167.51,97.54 167.89,97.16 167.89,95 167.77,94.87 166.88,94.87 166.75,95 166.75,97.54 166.31,97.98 166.31,98.89 166.55,99.14 167.28,99.14
GND on TOP (solid shape): 144.58,80.06 144.58,78.79 145.16,78.21 145.16,76.83 144.98,76.66 144.48,76.66 144.45,76.68 144.45,78.35 144.22,78.57 144.22,80.09 144.27,80.14 144.5,80.14
GND on TOP (solid shape): 154.58,81.13 154.58,79.12 154.36,78.89 147.96,78.89 147.8,79.04 147.8,79.73 147.96,79.88 149.96,79.88 150.47,80.39 152.6,80.39 152.76,80.54 152.76,81.15 152.88,81.28 154.43,81.28
GND on TOP (solid shape): 146.71,89.33 146.71,86.33 146.99,86.06 148.16,86.06 148.41,85.8 148.41,85.04 148.18,84.81 146.28,84.81 145.72,85.37 145.72,87.35 145.9,87.53 145.9,89.35 146.04,89.48 146.56,89.48
GND on TOP (solid shape): 124.36,18.01 124.36,8.01 123.95,7.61 113.46,7.61 113.28,7.78 113.28,10.29 112.65,10.92 107.92,10.92 107.49,11.35 107.49,11.81 107.75,12.06 113.49,12.06 113.89,12.47 113.89,14.86 113.16,15.6 113.16,18.03 113.41,18.29 124.08,18.29
GND on TOP (solid shape): 145.03,81.99 145.03,80.37 144.98,80.31 143.13,80.31 143.05,80.24 142.13,80.24 141.61,79.72 137.16,79.72 136.99,79.88 134.82,79.88 134.57,79.63 133.99,79.63 133.81,79.8 133.81,81.62 133.99,81.79 137.06,81.79 137.19,81.66 137.19,80.88 137.55,80.52 142.21,80.52 142.27,80.57 143.21,80.57 143.26,80.62 143.26,81.97 143.31,82.02 145.01,82.02
GND on TOP (solid shape): 88.7,19.02 88.7,16.23 88.46,15.99 87.54,15.99 87.53,16 82.14,16 81.61,15.47 81.61,10.06 82.65,9.02 87.5,9.02 87.76,9.27 87.76,11.56 88.14,11.94 96.27,11.94 96.77,12.45 97.66,12.45 97.79,12.32 97.79,11.68 97.66,11.56 95.63,11.56 95,10.92 89.41,10.92 89.28,10.79 89.28,3.68 89.15,3.56 82.42,3.56 82.04,3.94 79.76,3.94 78.74,4.95 78.74,19.02 79.24,19.53 88.19,19.53
GND on BOTTOM (solid shape): 42.93,146.13 42.93,144.22 42.7,143.99 41.07,143.99 40.92,144.15 40.92,146.1 41.15,146.33 42.72,146.33
GND on BOTTOM (solid shape): 172.01,142.14 172.01,141.1 171.91,141 170.74,141 170.61,141.12 170.61,142.14 170.81,142.34 171.81,142.34
GND on BOTTOM (solid shape): 160.32,95.91 160.32,95.61 160.25,95.53 157.89,95.53 157.35,95 155.35,95 155.22,95.12 155.22,95.94 155.37,96.09 160.15,96.09
GND on BOTTOM (solid shape): 161.09,92.84 161.09,91.31 160.96,91.19 158.14,91.19 157.76,91.57 157.76,92.68 158.06,92.99 160.93,92.99
GND on BOTTOM (solid shape): 172.01,106.92 172.01,105.88 171.91,105.78 170.9,105.78 170.79,105.89 169.75,105.89 169.7,105.94 169.7,106.98 169.84,107.13 171.81,107.13
GND on BOTTOM (solid shape): 164.44,109.78 164.44,106.48 164.34,106.38 162.97,106.38 162.59,106.76 162.59,109.78 162.86,110.06 164.16,110.06
GND on TOP: 163.63,94.39 164.97,93.04 165.35,93.04 165.46,93.14 165.46,93.85 164.9,94.41 164.9,97 164.82,97.08 163.91,97.08 163.63,96.8
GND on TOP: 74.78,4.4 74.78,3.23 74.96,3.05 76.76,3.05 76.83,3.12 76.83,4.5 76.61,4.72 75.11,4.72
GND on TOP: 126.64,130.3 125.6,130.3 125.35,130.56 125.35,132.59 125.6,132.84 127.25,132.84 127.33,132.77 127.33,132.05 126.82,131.55 126.82,130.48
GND on TOP: 119.51,140.46 119.51,138.68 119.25,138.43 117.47,138.43 117.22,138.68 117.22,140.46 117.47,140.72 119.25,140.72
GND on TOP: 44.04,12.45 51.54,12.45 52.15,11.84 62.76,11.84 63.09,11.51 63.09,10.77 63.17,10.69 66.17,10.69 66.4,10.92 66.4,11.66 66.65,11.91 66.65,12.78 68.05,14.17 68.05,14.48 67.89,14.63 67.31,14.63 67.11,14.43 63.53,14.43 62.5,15.46 62.5,28.82 61.98,29.34 61.98,35.89 61.67,36.2 56.34,36.2 54.84,34.7 54.84,25.55 50.98,21.69 44.93,21.69 42.95,19.71 42.95,13.54
GND on TOP: 39.6,144.02 42.6,144.02 42.82,144.25 42.82,146.35 42.65,146.53 39.47,146.53 39.12,146.18 39.12,144.5
GND on TOP: 111.51,143.26 111.51,140.08 111.76,139.83 112.78,139.83 113.03,140.08 113.03,143.26 112.9,143.38 111.63,143.38
GND on TOP: 36.07,31.62 35.94,31.75 34.92,31.75 33.91,30.73 33.02,30.73 32.89,30.86 32.89,31.42 32.49,31.83 31.93,31.83 31.62,32.13 31.62,35.92 31.9,36.2 35.05,36.2 35.81,36.96 36.68,36.96 36.83,36.8 36.83,29.44 36.75,29.36 36.12,29.36 36.07,29.41
GND on TOP: 132.66,41.02 132.66,36.37 137.31,36.37 137.31,41.02
GND on TOP: 25.91,26.04 25.91,23.88 26.16,23.62 27.43,23.62 27.69,23.88 27.69,26.04 27.43,26.29 26.16,26.29
GND on TOP: 119.1,36.35 119.1,34.09 120.75,34.09 120.75,36.35
